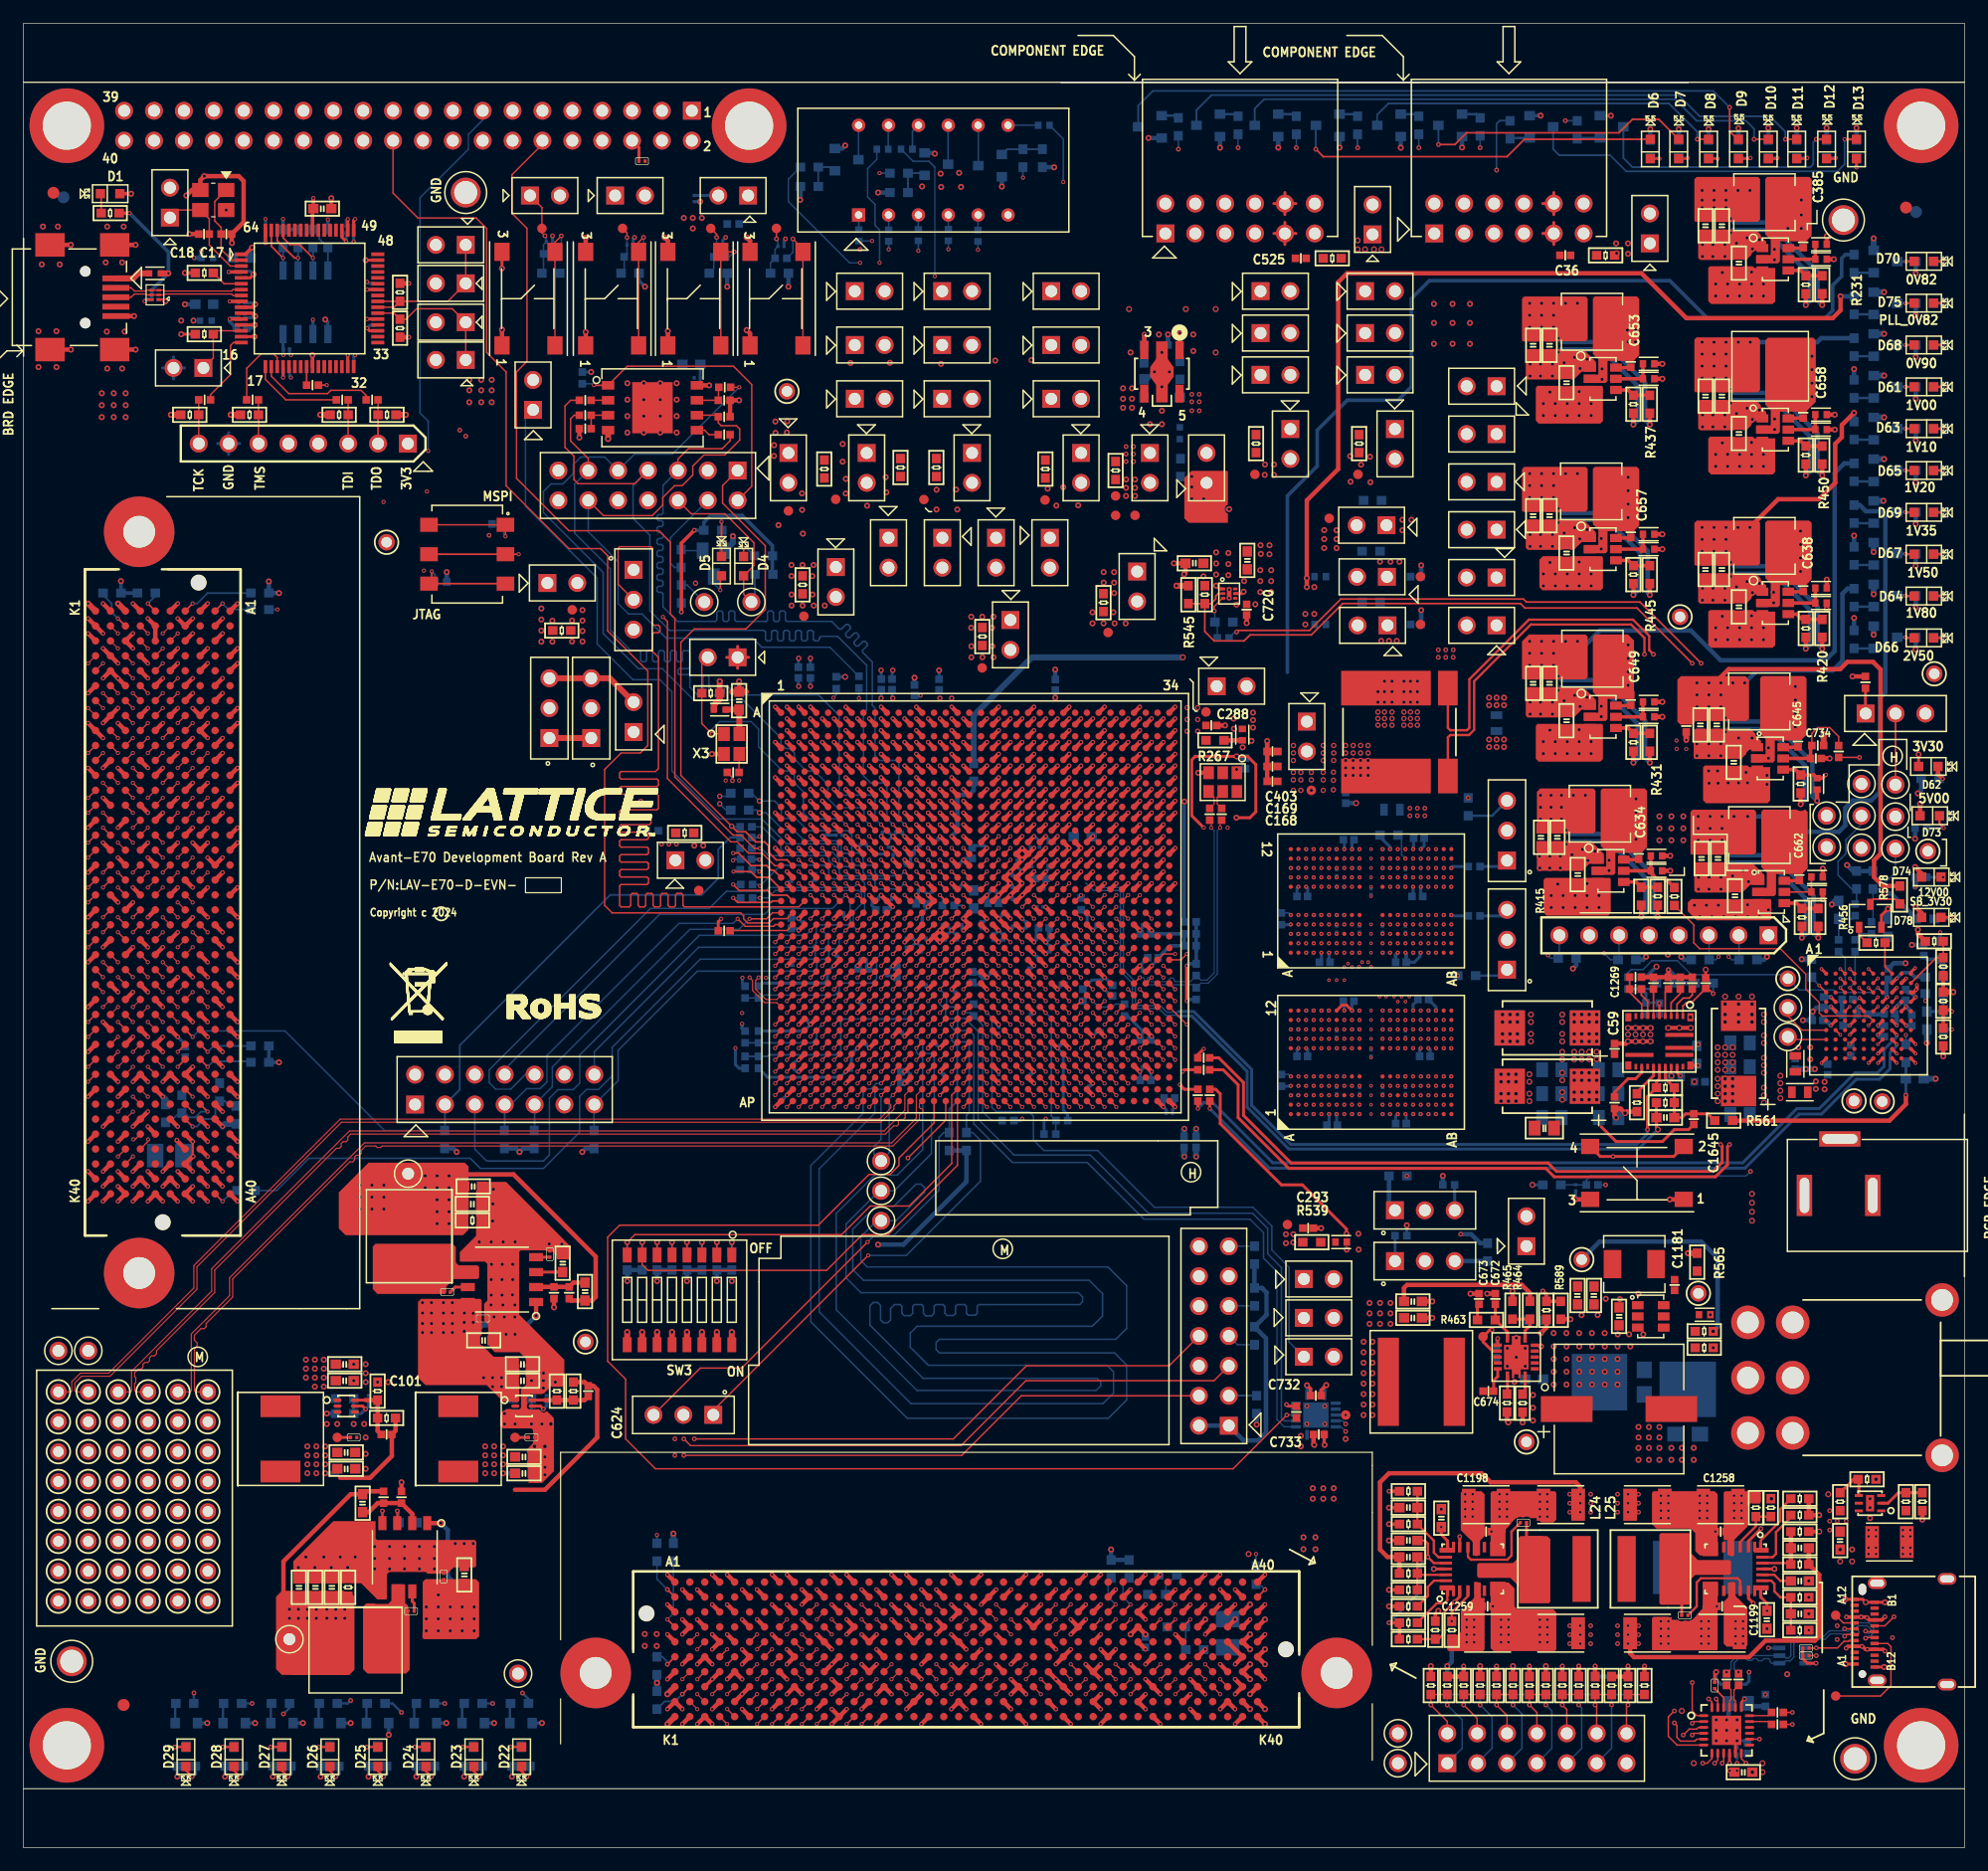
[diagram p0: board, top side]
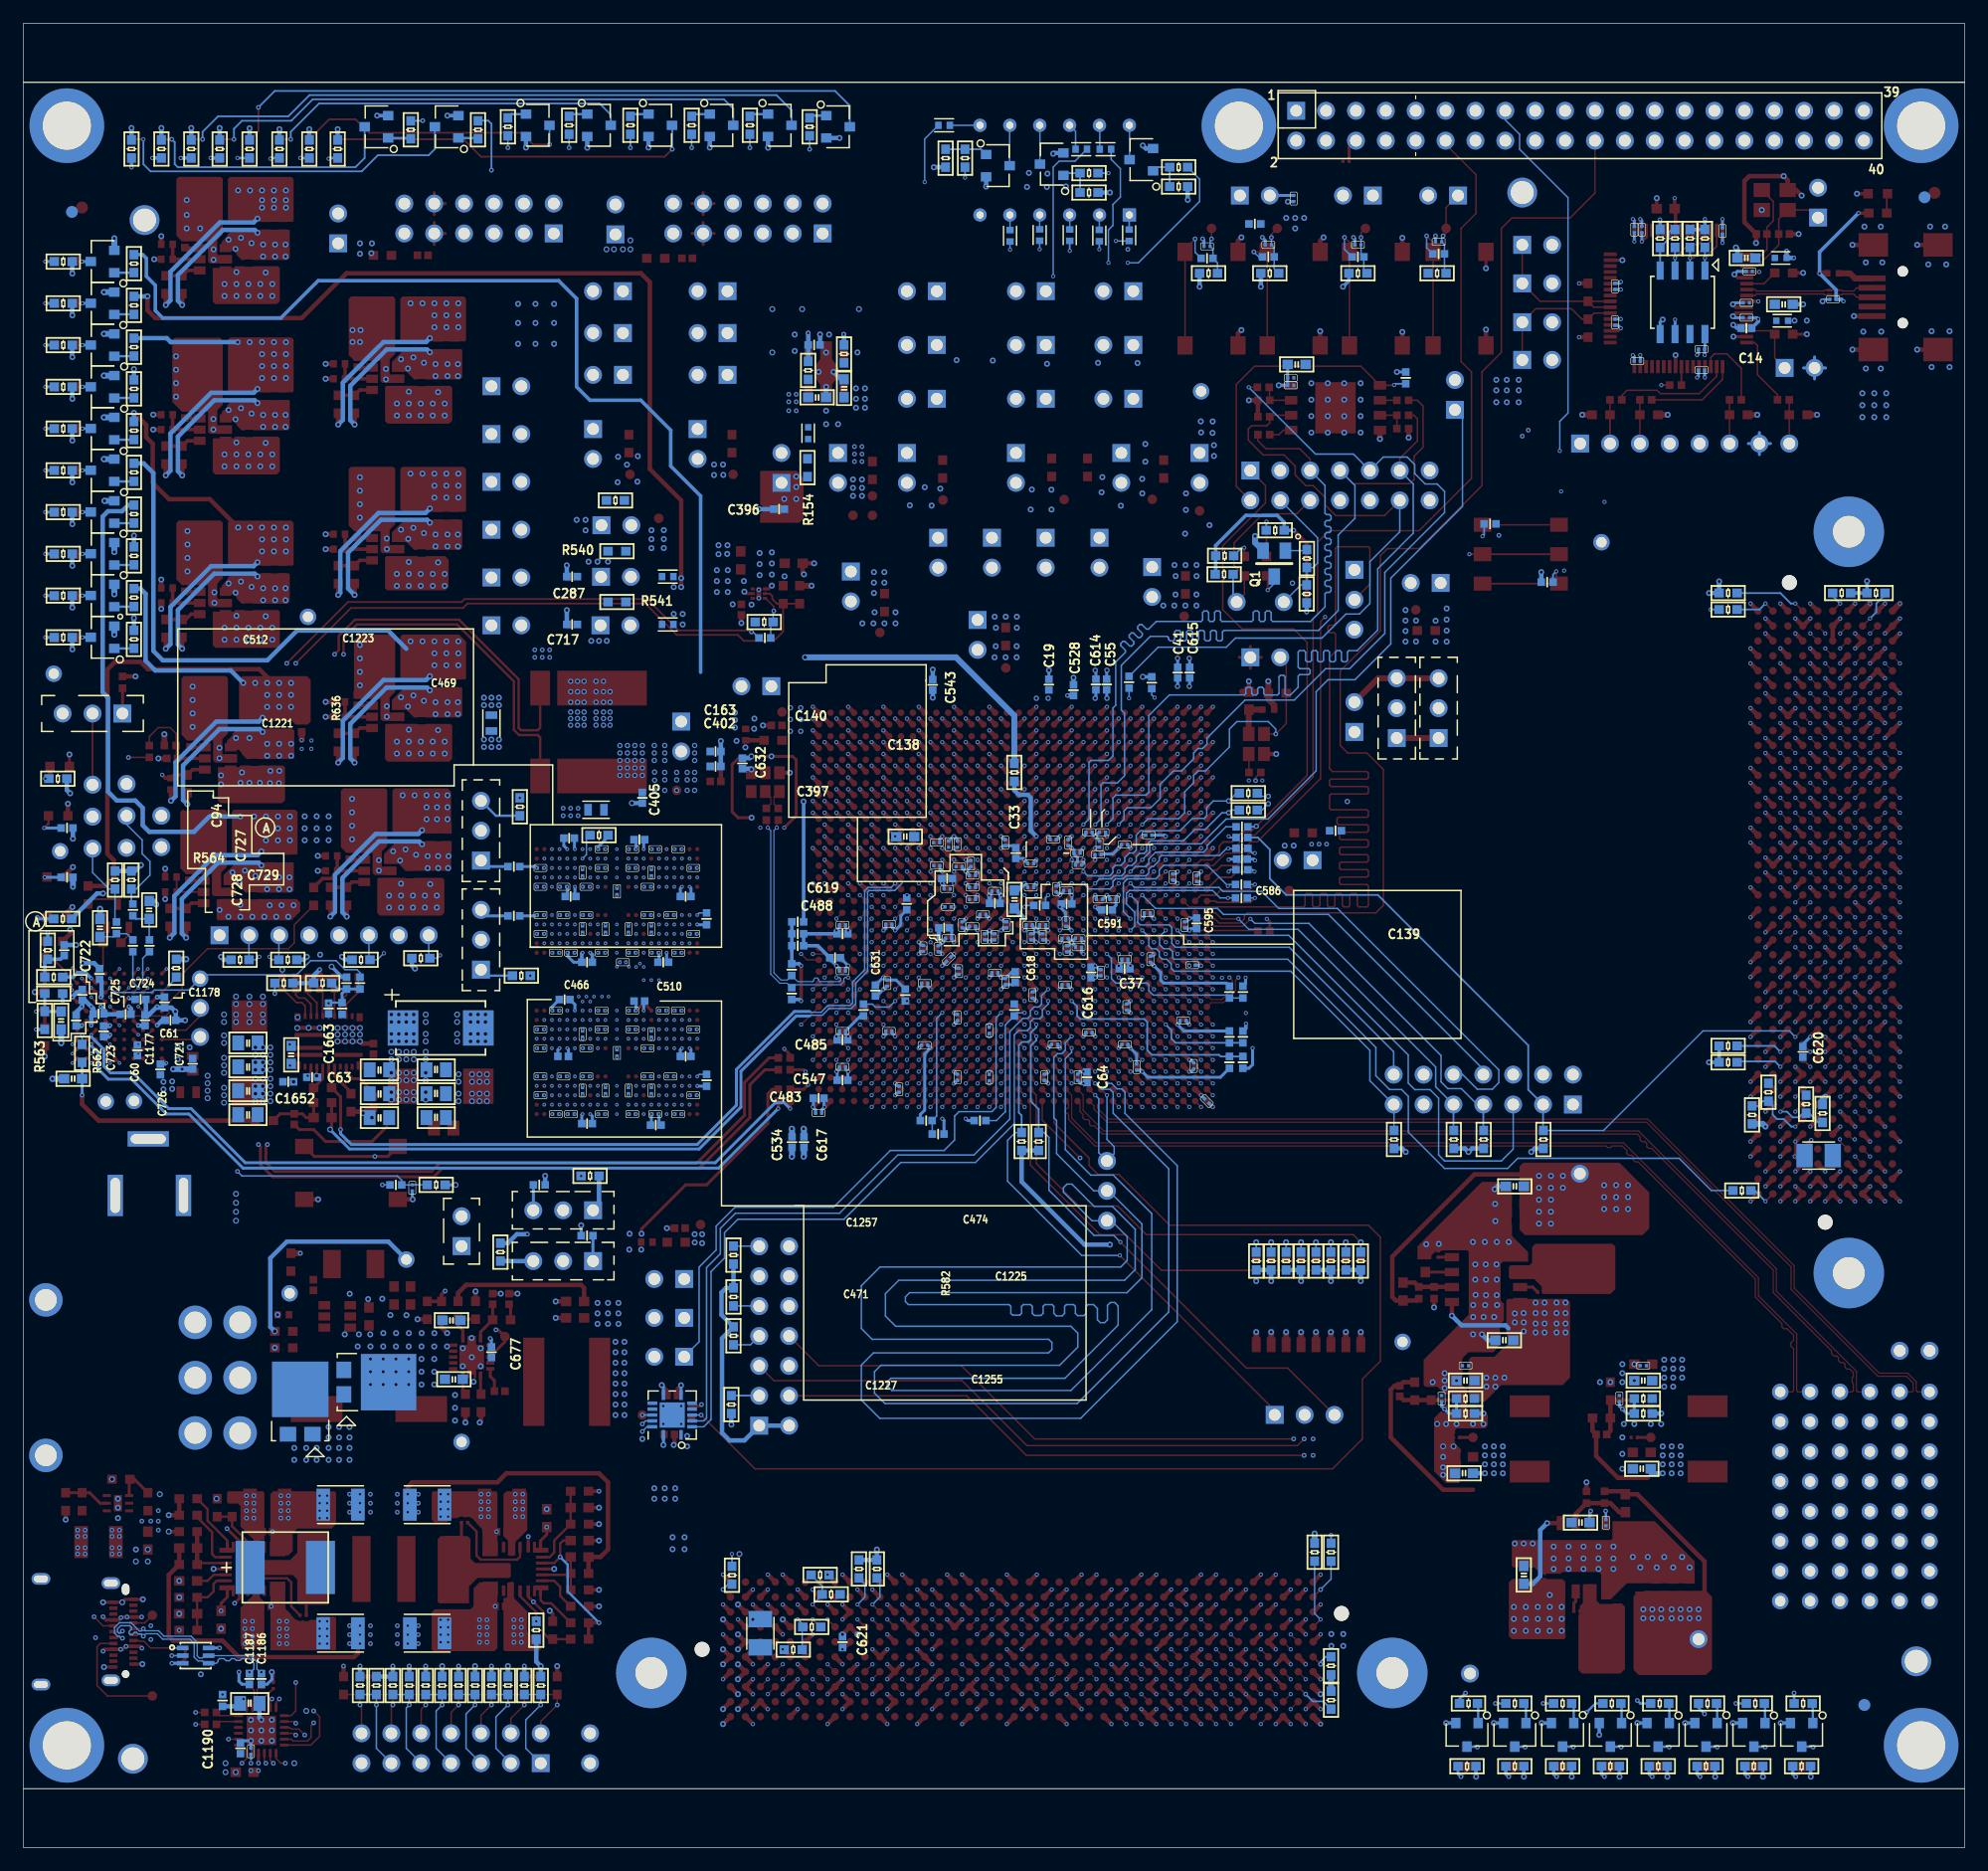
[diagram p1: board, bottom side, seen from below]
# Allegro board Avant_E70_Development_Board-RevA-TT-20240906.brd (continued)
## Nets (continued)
FMC2_TMS: J53.13 J54.D33(TMS) R316.1 U3.W14(WRIO13_5A)
FMC2_TRST_L: J53.6 J54.D34(TRST_L)
FMC2_VREFA: J54.H1(VREF_A_M2C) JP40.2 JP42.2
GPIO_AP14: U3.AP14(HPIO6_9B/DP1_DQ52) U46.4(A3)
ICS: C1214.1 C1215.1 U110.17(ICS_1) U110.18(ICS_2) U111.17(ICS_1) U111.18(ICS_2)
IMON1N_082V: R658.2(V2) U45.H10(IMON1N)
IMON1P_082V: R658.1(V1) U45.J10(IMON1P)
INITN: D4.K(CATHODE) INIT.1(TP) J3.6 R22.2 U3.T5(INITN)
K_DIG1: D60.12(K_DIG1) Q4.C
K_DIG2: D60.9(K_DIG2) Q2.C
K_DIG3: D60.8(K_DIG3) Q3.C
LED_0: R687.2 U3.L8(WRIO1_4B/MDQ5)
LED_1: R688.2 U3.P8(WRIO1_5B/MCLKN)
LED_2: R689.2 U3.M8(WRIO1_6A/MDQ6)
LED_3: R690.2 U3.M9(WRIO1_6B/MDQ7)
LED_4: R691.2 U3.P10(WRIO1_7A)
LED_5: R692.2 U3.N10(WRIO1_7B)
LED_6: R683.2 U3.AL10(HPIO6_25A/PCLKRT6_3/DP1_DM8)
LED_7: R684.2 U3.AL11(HPIO6_25B/PCLKRC6_3)
LED_8: R520.2 U3.AN15(HPIO6_5B/DP1_DQSN6)
LED_9: R522.2 U3.AH17(HPIO6_6A/DP1_DQ41)
LED_10: R525.2 U3.AG17(HPIO6_6B/DP1_DQ40)
LED_11: R527.2 U3.AM14(HPIO6_7A/DP1_DQ49)
LED_12: R530.2 U3.AL14(HPIO6_7B/DP1_DQ48)
LED_13: R531.2 U3.AK17(HPIO6_8A/DP1_DQ45)
LED_14: R534.2 U3.AJ17(HPIO6_8B/DP1_DQ44)
LED_15: R535.2 U3.AN14(HPIO6_9A/DP1_DQ53)
LPDDR4_A0_A: U3.AC26(HPIO10_2B/DP2_MA0) U5.H2(CA0_A) U5.R2(CA0_B) U119.H2(CA0_A) U119.R2(CA0_B)
LPDDR4_A1_A: U3.AB27(HPIO10_4A/DP2_MA1) U5.J2(CA1_A) U5.P2(CA1_B) U119.J2(CA1_A) U119.P2(CA1_B)
LPDDR4_A2_A: U3.AB28(HPIO10_4B/DP2_MA2) U5.H9(CA2_A) U5.R9(CA2_B) U119.H9(CA2_A) U119.R9(CA2_B)
LPDDR4_A3_A: U3.AC29(HPIO10_6A/DP2_MA3) U5.H10(CA3_A) U5.R10(CA3_B) U119.H10(CA3_A) U119.R10(CA3_B)
LPDDR4_A4_A: U3.AB29(HPIO10_6B/DP2_MA4) U5.H11(CA4_A) U5.R11(CA4_B) U119.H11(CA4_A) U119.R11(CA4_B)
LPDDR4_A5_A: U3.AD27(HPIO10_8A/DP2_MA5) U5.J11(CA5_A) U5.P11(CA5_B) U119.J11(CA5_A) U119.P11(CA5_B)
LPDDR4_CKE_A: U3.AB26(HPIO10_2A/DP2_CKE0) U5.J4(CKE0_A) U5.P4(CKE0_B) U119.J4(CKE0_A) U119.P4(CKE0_B)
LPDDR4_CLK_A_N: C1665.1 R582.1 R636.1 U3.AC25(HPIO10_0B/DP2_MCLKC0) U5.J9(CK_C_A) U5.P9(CK_C_B) U119.J9(CK_C_A) U119.P9(CK_C_B)
LPDDR4_CLK_A_P: C1665.2 R582.2 R636.2 U3.AB25(HPIO10_0A/DP2_MCLKT0) U5.J8(CK_T_A) U5.P8(CK_T_B) U119.J8(CK_T_A) U119.P8(CK_T_B)
LPDDR4_CS_A: U3.AA31(HPIO10_7A/DP2_CS_N0) U5.H4(CS0_A) U5.R4(CS0_B) U119.H4(CS0_A) U119.R4(CS0_B)
LPDDR4_DQ0_A: U3.AD22(HPIO10_20B/DP2_DQ00) U5.B2(DQ0_A)
LPDDR4_DQ0_B: U3.U29(HPIO11_3A/DP2_DQ16) U5.AA2(DQ0_B)
LPDDR4_DQ0_C: U3.V28(HPIO11_2A/DP2_DQ32) U119.B2(DQ0_A)
LPDDR4_DQ0_D: U3.AK32(HPIO9_7B/DP2_DQ48) U119.AA2(DQ0_B)
LPDDR4_DQ1_A: U3.AD21(HPIO10_20A/DP2_DQ01) U5.C2(DQ1_A)
LPDDR4_DQ1_B: U3.V29(HPIO11_3B/DP2_DQ17) U5.Y2(DQ1_B)
LPDDR4_DQ1_C: U3.U28(HPIO11_2B/DP2_DQ33) U119.C2(DQ1_A)
LPDDR4_DQ1_D: U3.AK31(HPIO9_7A/DP2_DQ49) U119.Y2(DQ1_B)
LPDDR4_DQ2_A: U3.AE25(HPIO10_14B/DP2_DQ02) U5.E2(DQ2_A)
LPDDR4_DQ2_B: U3.U30(HPIO11_9A/DP2_DQ18) U5.V2(DQ2_B)
LPDDR4_DQ2_C: U3.W26(HPIO11_8A/DP2_DQ34) U119.E2(DQ2_A)
LPDDR4_DQ2_D: U3.AJ32(HPIO9_1B/DP2_DQ50) U119.V2(DQ2_B)
LPDDR4_DQ3_A: U3.AE24(HPIO10_14A/DP2_DQ03) U5.F2(DQ3_A)
LPDDR4_DQ3_B: U3.U31(HPIO11_9B/DP2_DQ19) U5.U2(DQ3_B)
LPDDR4_DQ3_C: U3.V26(HPIO11_8B/DP2_DQ35) U119.F2(DQ3_A)
LPDDR4_DQ3_D: U3.AJ31(HPIO9_1A/DP2_DQ51) U119.U2(DQ3_B)
LPDDR4_DQ4_A: U3.AA21(HPIO10_22B/DP2_DQ04) U5.F4(DQ4_A)
LPDDR4_DQ4_B: U3.Y28(HPIO11_1A/DP2_DQ20) U5.U4(DQ4_B)
LPDDR4_DQ4_C: U3.AA27(HPIO11_0A/DP2_DQ36) U119.F4(DQ4_A)
LPDDR4_DQ4_D: U3.AK34(HPIO9_9B/DP2_DQ52) U119.U4(DQ4_B)
LPDDR4_DQ5_A: U3.Y21(HPIO10_22A/DP2_DQ05) U5.E4(DQ5_A)
LPDDR4_DQ5_B: U3.AA28(HPIO11_1B/DP2_DQ21) U5.V4(DQ5_B)
LPDDR4_DQ5_C: U3.Y27(HPIO11_0B/DP2_DQ37) U119.E4(DQ5_A)
LPDDR4_DQ5_D: U3.AK33(HPIO9_9A/DP2_DQ53) U119.V4(DQ5_B)
LPDDR4_DQ6_A: U3.AB24(HPIO10_16B/DP2_DQ06) U5.C4(DQ6_A)
LPDDR4_DQ6_B: U3.V30(HPIO11_7A/DP2_DQ22) U5.Y4(DQ6_B)
LPDDR4_DQ6_C: U3.AA26(HPIO11_6A/DP2_DQ38) U119.C4(DQ6_A)
LPDDR4_DQ6_D: U3.AJ33(HPIO9_3B/DP2_DQ54) U119.Y4(DQ6_B)
LPDDR4_DQ7_A: U3.AC24(HPIO10_16A/DP2_DQ07) U5.B4(DQ7_A)
LPDDR4_DQ7_B: U3.W30(HPIO11_7B/DP2_DQ23) U5.AA4(DQ7_B)
LPDDR4_DQ7_C: U3.Y26(HPIO11_6B/DP2_DQ39) U119.B4(DQ7_A)
LPDDR4_DQ7_D: U3.AJ34(HPIO9_3A/DP2_DQ55) U119.AA4(DQ7_B)
LPDDR4_DQ8_A: U3.AD34(HPIO10_21B/DP2_DQ08) U5.B11(DQ8_A)
LPDDR4_DQ8_B: U3.AA24(HPIO11_16A/DP2_DQ24) U5.AA11(DQ8_B)
LPDDR4_DQ8_C: U3.AF32(HPIO9_6B/DP2_DQ40) U119.B11(DQ8_A)
LPDDR4_DQ8_D: U3.AJ29(HPIO9_20B/DP2_DQ56) U119.AA11(DQ8_B)
LPDDR4_DQ9_A: U3.AD33(HPIO10_21A/DP2_DQ09) U5.C11(DQ9_A)
LPDDR4_DQ9_B: U3.Y24(HPIO11_16B/DP2_DQ25) U5.Y11(DQ9_B)
LPDDR4_DQ9_C: U3.AG32(HPIO9_6A/DP2_DQ41) U119.C11(DQ9_A)
LPDDR4_DQ9_D: U3.AJ28(HPIO9_20A/DP2_DQ57) U119.Y11(DQ9_B)
LPDDR4_DQ10_A: U3.AE32(HPIO10_15B/DP2_DQ10) U5.E11(DQ10_A)
LPDDR4_DQ10_B: U3.U23(HPIO11_22A/DP2_DQ26) U5.V11(DQ10_B)
LPDDR4_DQ10_C: U3.AF29(HPIO9_0B/DP2_DQ42) U119.E11(DQ10_A)
LPDDR4_DQ10_D: U3.AG28(HPIO9_14B/DP2_DQ58) U119.V11(DQ10_B)
LPDDR4_DQ11_A: U3.AE31(HPIO10_15A/DP2_DQ11) U5.F11(DQ11_A)
LPDDR4_DQ11_B: U3.U22(HPIO11_22B/DP2_DQ27) U5.U11(DQ11_B)
LPDDR4_DQ11_C: U3.AF28(HPIO9_0A/DP2_DQ43) U119.F11(DQ11_A)
LPDDR4_DQ11_D: U3.AG27(HPIO9_14A/DP2_DQ59) U119.U11(DQ11_B)
LPDDR4_DQ12_A: U3.AE33(HPIO10_23B/DP2_DQ12) U5.F9(DQ12_A)
LPDDR4_DQ12_B: U3.U25(HPIO11_14A/DP2_DQ28) U5.U9(DQ12_B)
LPDDR4_DQ12_C: U3.AG34(HPIO9_8B/DP2_DQ44) U119.F9(DQ12_A)
LPDDR4_DQ12_D: U3.AG26(HPIO9_22B/DP2_DQ60) U119.U9(DQ12_B)
LPDDR4_DQ13_A: U3.AE34(HPIO10_23A/DP2_DQ13) U5.E9(DQ13_A)
LPDDR4_DQ13_B: U3.T25(HPIO11_14B/DP2_DQ29) U5.V9(DQ13_B)
LPDDR4_DQ13_C: U3.AH34(HPIO9_8A/DP2_DQ45) U119.E9(DQ13_A)
LPDDR4_DQ13_D: U3.AH26(HPIO9_22A/DP2_DQ61) U119.V9(DQ13_B)
LPDDR4_DQ14_A: U3.AB34(HPIO10_17B/DP2_DQ14) U5.C9(DQ14_A)
LPDDR4_DQ14_B: U3.U24(HPIO11_20A/DP2_DQ30) U5.Y9(DQ14_B)
LPDDR4_DQ14_C: U3.AG30(HPIO9_2B/DP2_DQ46) U119.C9(DQ14_A)
LPDDR4_DQ14_D: U3.AG29(HPIO9_16B/DP2_DQ62) U119.Y9(DQ14_B)
LPDDR4_DQ15_A: U3.AB33(HPIO10_17A/DP2_DQ15) U5.B9(DQ15_A)
LPDDR4_DQ15_B: U3.T24(HPIO11_20B/DP2_DQ31) U5.AA9(DQ15_B)
LPDDR4_DQ15_C: U3.AF30(HPIO9_2A/DP2_DQ47) U119.B9(DQ15_A)
LPDDR4_DQ15_D: U3.AH29(HPIO9_16A/DP2_DQ63) U119.AA9(DQ15_B)
LPDDR4_LDM_A: U3.AC21(HPIO10_24A/PCLKRT10_2/DP2_DM0) U5.C3(DMI0_A)
LPDDR4_LDM_B: U3.V32(HPIO11_11A/PCLKT11_1/PCLKRT11_1) U5.Y3(DMI0_B)
LPDDR4_LDM_C: U3.V25(HPIO11_10A/PCLKT11_0/PCLKRT11_0) U119.C3(DMI0_A)
LPDDR4_LDM_D: U3.AM30(HPIO9_11A/PCLKT9_1/PCLKRT9_1/DP) U119.Y3(DMI0_B)
LPDDR4_LDQS_A_N: U3.AD23(HPIO10_18B/DP2_DQSN0) U5.E3(DQS0_C_A)
LPDDR4_LDQS_A_P: U3.AC23(HPIO10_18A/DP2_DQS0) U5.D3(DQS0_T_A)
LPDDR4_LDQS_B_N: U3.W29(HPIO11_5B/DP2_DQSN2) U5.V3(DQS0_C_B)
LPDDR4_LDQS_B_P: U3.Y29(HPIO11_5A/DP2_DQS2) U5.W3(DQS0_T_B)
LPDDR4_LDQS_C_N: U3.V27(HPIO11_4B/DP2_DQSN4) U119.E3(DQS0_C_A)
LPDDR4_LDQS_C_P: U3.U27(HPIO11_4A/DP2_DQS4) U119.D3(DQS0_T_A)
LPDDR4_LDQS_D_N: U3.AK30(HPIO9_5B/DP2_DQSN6) U119.V3(DQS0_C_B)
LPDDR4_LDQS_D_P: U3.AK29(HPIO9_5A/DP2_DQS6) U119.W3(DQS0_T_B)
LPDDR4_RESET: R596.1 U3.AF34(HPIO10_25B/PCLKRC10_3/DP2_RST_N) U5.T11(RESET_N) U119.T11(RESET_N)
LPDDR4_UDM_A: U3.AF33(HPIO10_25A/PCLKRT10_3/DP2_DM1) U5.C10(DMI1_A)
LPDDR4_UDM_B: U3.V22(HPIO11_24A/PCLKRT11_2/DP2_DM3) U5.Y10(DMI1_B)
LPDDR4_UDM_C: U3.AG33(HPIO9_10A/PCLKT9_0/PCLKRT9_0/DP) U119.C10(DMI1_A)
LPDDR4_UDM_D: U3.AJ27(HPIO9_24A/PCLKRT9_2/DP2_DM7) U119.Y10(DMI1_B)
LPDDR4_UDQS_A_N: U3.AC33(HPIO10_19B/DP2_DQSN1) U5.E10(DQS1_C_A)
LPDDR4_UDQS_A_P: U3.AC34(HPIO10_19A/DP2_DQS1) U5.D10(DQS1_T_A)
LPDDR4_UDQS_B_N: U3.W24(HPIO11_18B/DP2_DQSN3) U5.V10(DQS1_C_B)
LPDDR4_UDQS_B_P: U3.W23(HPIO11_18A/DP2_DQS3) U5.W10(DQS1_T_B)
LPDDR4_UDQS_C_N: U3.AG31(HPIO9_4B/DP2_DQSN5) U119.E10(DQS1_C_A)
LPDDR4_UDQS_C_P: U3.AF31(HPIO9_4A/DP2_DQS5) U119.D10(DQS1_T_A)
LPDDR4_UDQS_D_N: U3.AJ30(HPIO9_18B/DP2_DQSN7) U119.V10(DQS1_C_B)
LPDDR4_UDQS_D_P: U3.AH30(HPIO9_18A/DP2_DQS7) U119.W10(DQS1_T_B)
MPM3695_SCL: R707.2 U120.3(SCL)
MPM3695_SDA: R706.2 U120.4(SDA)
MPM3695_SW1: C1646.1 U120.27(SW#27) U120.28(SW#28)
MPM3695_TAKE: R694.1 R695.2 U120.9(TAKE)
ODT_CA_A: JP83.2 U5.G2(ODT_CA_A)
ODT_CA_B: JP84.2 U5.T2(ODT_CA_B)
ODT_CA_C: JP85.2 U119.G2(ODT_CA_A)
ODT_CA_D: JP86.2 U119.T2(ODT_CA_B)
PLL0V82_EN: PLL0V82_EN.1(TP) R715.2 U45.D6(GPIO3)
PLL0V82_MON: R584.2 U45.H8(VMON2)
PLL0V82_MON_GS: R583.2 U45.G8(VMON2GS)
PLL0V82_TRIM: R564.2 U45.C8(TRIM2)
PMOD2_1: J6.1 U3.P18(WRIO12_7B/PLLTFB12_IN)
PMOD2_2: J6.2 U3.N19(WRIO12_1A)
PMOD2_3: J6.3 U3.N20(WRIO12_5B)
PMOD2_4: J6.4 U3.P20(WRIO12_5A)
PMOD2_5: J6.7 U3.R17(WRIO12_6B)
PMOD2_6: J6.8 U3.M19(WRIO12_3A)
PMOD2_7: J6.9 U3.M20(WRIO12_3B/PCLKT12_0/PCLKRT12_0)
PMOD2_8: J6.10 U3.P19(WRIO12_7A/PLLT12_IN)
PMOD3_1: J7.1 U3.P14(WRIO12_4B)
PMOD3_2: J7.2 U3.N15(WRIO12_0A)
PMOD3_3: J7.3 U3.N16(WRIO12_2B)
PMOD3_4: J7.4 U3.R16(WRIO12_6A)
PMOD3_5: J7.7 U3.P13(WRIO12_4A)
PMOD3_6: J7.8 U3.N14(WRIO12_0B)
PMOD3_7: J7.9 U3.P15(WRIO12_2A)
PMOD3_8: J7.10 U3.N17(WRIO12_1B/PCLK12_1/PCLKRT12_1)
POWER_DOWN: C34.1 R42.2 R80.1 U45.H7(GPIO10)
PROGRAMN: C22.1 J3.1 JP17.1 PROGRAMN.1(TP) R10.2 R27.2 R29.1 R408.1 U3.P2(PROGRAMN)
PTM_DONE: P_DONE.1 U45.C6(PT17D || DONE)
PTM_INITN: P_INITN.1 U45.C5(PT17C || INITN)
PTM_JTAGENB: J8.2 P_JTAGENB.1 U45.B6(PT15C || JTAGENB)
PTM_PROGRAMN: P_PROGN.1 U45.A6(PT15D || PROGRAMN)
PTM_SCL_18: U3.AE15(HPIO6_24A/PCLKRT6_2/DP1_DM7) U46.2(A1)
PTM_SCL_33: PTM_SCL.1 R127.2 R550.1 U46.13(B1)
PTM_SDA_18: U3.AD15(HPIO6_24B/PCLKRC6_2) U46.3(A2)
PTM_SDA_33: PTM_SDA.1 R126.2 R549.1 U46.12(B2)
PTM_TCK: J39.8 R77.1 U45.A4(DIO23 || PT11C / TCK)
PTM_TDI: J39.3 R78.2 U45.B3(DIO25 || PT10D / TDI)
PTM_TDO: J39.2 R76.2 U45.A3(DIO22 || PT10C / TDO)
PTM_TMS: J39.6 R79.2 U45.B4(DIO24 || PT11D / TMS)
PUSHBUTTON1: C21.1 PB1.1(TP) R21.2 R23.1 U3.AC17(HPIO6_4A/DP1_DQS5)
PUSHBUTTON2: C26.1 PB2.1(TP) R47.2 R50.1 U3.AC16(HPIO6_4B/DP1_DQSN5)
PUSHBUTTON3: C27.1 PB3.1(TP) R48.2 R51.1 U3.AP15(HPIO6_5A/DP1_DQS6)
RASP_5V: C599.1 JP13.2 JP26.2 JP26.4
RASP_ID_SC: JP26.28 R103.1 U3.R12(WRIO14_7A)
RASP_ID_SD: JP26.27 R104.1 U3.T11(WRIO14_7B)
RASP_IO02: JP26.3 U3.V15(WRIO13_6B)
RASP_IO03: JP26.5 U3.T13(WRIO13_7A)
RASP_IO04: JP26.7 U3.P6(WRIO2_2A/SDQ2)
RASP_IO05: JP26.29 R108.2 U3.V8(WRIO14_6A)
RASP_IO06: JP26.31 R105.2 U3.W8(WRIO14_6B)
RASP_IO07: JP26.26 JP65.1
RASP_IO08: JP26.24 U3.P5(WRIO2_2B/SDQ3)
RASP_IO09: JP26.21 U3.R5(WRIO2_3B/SDS)
RASP_IO10: JP26.19 U3.R6(WRIO2_3A/SCSN)
RASP_IO11: JP26.23 R106.2 U3.U12(WRIO14_5A/PCLKRT14_0)
RASP_IO12: JP26.32 U3.U5(WRIO2_1B/SSDO)
RASP_IO13: JP26.33 U3.R9(WRIO14_8B)
RASP_IO14: JP26.8 U3.V14(WRIO13_5B)
RASP_IO15: JP26.10 U3.R13(WRIO13_7B)
RASP_IO16: JP26.36 U3.N6(WRIO2_0A/SDQ0)
RASP_IO17: JP26.11 U3.V16(WRIO13_6A)
RASP_IO18: JP26.12 R107.2 U3.T12(WRIO14_5B)
RASP_IO19: JP26.35 U3.R11(WRIO14_9A)
RASP_IO20: JP26.38 U3.T6(WRIO0_7B/PLLTFB0_IN)
RASP_IO21: JP26.40 U3.U6(WRIO0_7A/PLLT0_IN)
RASP_IO22: JP26.15 U3.W6(WRIO0_5B)
RASP_IO23: JP26.16 U3.P4(WRIO2_4B/SDQ5)
RASP_IO24: JP26.18 U3.N5(WRIO2_0B/SDQ1)
RASP_IO25: JP26.22 U3.V2(WRIO0_6A)
RASP_IO26: JP26.37 U3.T9(WRIO14_8A)
RASP_IO27: JP26.13 U3.P3(WRIO2_4A/SDQ4)
RXD_UART: JP2.2 U3.R3(WRIO2_6A/SDQ6)
SB_3V30: C1183.1 C1184.1 J11.1 J39.1 L23.2 R42.1 R76.1 R78.1 R79.1 R81.1 R126.1 R127.1 R566.1 R567.2 R585.2 SB_3V30.1(TP)
SCL: JP4.2 R103.2
SDA: JP5.2 R104.2
SEG_A: R332.2 U3.V10(WRIO14_0A)
SEG_B: R333.2 U3.T10(WRIO14_0B)
SEG_C: R334.2 U3.V12(WRIO14_1A)
SEG_D: R335.2 U3.V13(WRIO14_1B)
SEG_DP: R331.2 U3.W11(WRIO14_3B)
SEG_E: R336.2 U3.W10(WRIO14_2A)
SEG_F: R337.2 U3.V11(WRIO14_2B)
SEG_G: R338.2 U3.W12(WRIO14_3A)
SHORT_STUB_TRACE: ST.1 U3.AN10(HPIO6_21B/DP1_DQ64) U3.AN11(HPIO6_21A/DP1_DQ65)
SPI_MCLK: J3.12 R20.1 R40.2 U4.6(SCLK)
SYNC_IN: R615.2 R616.2 U110.3(SYNCIN) U111.16(SYNCO)
SYNC_OUT: U110.16(SYNCO) U111.3(SYNCIN)
TCK: J1.8 R5.1 R6.2 R106.1 U3.T1(TCK)
TDI: J1.3 R3.2 R7.2 R105.1 U3.U1(TDI)
TDO: J1.2 R4.2 R8.2 R108.1 U3.U2(TDO)
TMS: J1.6 R2.2 R9.2 R107.1 U3.R1(TMS)
TXD_UART: JP1.2 U3.T3(WRIO2_6B/SDQ7)
USB3_CC1: C1188.1 J25.A5(CC1) R601.2 U109.1
USB3_CC2: C1189.1 J25.B5(CC2) R602.2 U109.2
USB3_LDO_5V: C1190.1 C1191.1 C1261.1 C1268.1 R603.1 R604.1 R605.1 R606.1 R607.1 R608.1 R623.1 R640.2 R649.2 R650.2 R659.1 R660.1 R661.1 R662.1 R675.1 R676.1 U108.10(VIN) U118.6(VOUT)
USB3_PA1: J83.1 R603.2 R663.1 U108.1(PA1)
USB3_PA2: J83.3 R604.2 R664.1 U108.2(PA2)
USB3_PA3: J83.5 R659.2 R665.1 U108.3(PA3)
USB3_PA4: J83.7 R660.2 R666.1 U108.4(PA4)
USB3_PA5: J83.9 R661.2 R667.1 U108.5(PA5)
USB3_PA6: J83.11 R662.2 R668.1 U108.6(PA6)
USB3_PB0: J83.2 R607.2 R671.2 U108.7(PB0)
USB3_PB1: J83.4 R606.2 R672.2 U108.8(PB1)
USB3_PB2: J83.6 R623.2 R651.1 U108.12(PB2)
USB3_PB3: J83.8 R670.2 R675.2 U108.14(PB3)
USB3_PB6: J83.10 R605.2 R673.2 U108.23(PB6)
USB3_PB7: J83.12 R608.2 R674.2 U108.24(PB7)
USB3_PC2: J83.14 R669.2 R676.2 U108.9(PC2)
USB3_RST: C1192.2 U108.22(NRST)
USB_12V: C1204.1 C1205.1 C1206.1 C1207.1 C1208.1 C1209.1 C1210.1 C1211.1 C1666.1 C1667.1 J84.3 J84.6 L24.2 L25.2 R619.2 R622.2
USB_DM: C1186.1 J25.A7(D-A) J25.B7(D-B) R599.1 U109.5
USB_DP: C1187.1 J25.A6(D+A) J25.B6(D+B) R600.1 U109.4
USB_VBUS: C1193.1 C1194.1 C1195.1 C1196.1 C1198.1 C1199.1 C1258.1 C1259.1 C1260.1 C1668.1 J25.A4(VBUS1) J25.A9(VBUS2) J25.B4(VBUS4) J25.B9(VBUS3) R609.1 R610.1 R638.1 R648.1 U110.5(VIN_1) U110.14(VIN_2) U111.5(VIN_1) U111.14(VIN_2) U118.1(VIN)
VFMC1_3V30: C49.1 C50.1 C51.1 C52.1 F1_3V3.1(TP) FB4.2 J48.C39(3P3V#C39) J48.D36(3P3V#D36) J48.D38(3P3V#D38) J48.D40(3P3V#D40) L1.2 R95.2 R96.1 VFMC1_3V30.1
VFMC1_3V30AUX: C620.2 F1_3V3AUX.1(TP) FB4.1 J48.D32(3P3VAUX) R249.2 R250.2
VFMC1_ADJ: C100.1 C101.1 C103.1 C104.1 C1217.1 F1_ADJ.1(TP) J48.E39(VADJ#E39) J48.F40(VADJ#F40) J48.G39(VADJ#G39) J48.H40(VADJ#H40) JP70.1 JP72.1 JP74.1 L13.2 R399.2 VFMC1_ADJ.1(TP)
VFMC2_3V30: C556.1 C557.1 C559.1 C565.1 F2_3V3.1(TP) FB24.2 J54.C39(3P3V#C39) J54.D36(3P3V#D36) J54.D38(3P3V#D38) J54.D40(3P3V#D40) L10.2 R305.1 R307.2 VFMC2_3V30.1
VFMC2_3V30AUX: C621.2 F2_3V3AUX.1(TP) FB24.1 J54.D32(3P3VAUX) R323.2 R324.2
VFMC2_ADJ: C622.1 C624.1 C628.1 C629.1 C630.1 F2_ADJ.1(TP) J54.E39(VADJ#E39) J54.F40(VADJ#F40) J54.G39(VADJ#G39) J54.H40(VADJ#H40) JP76.1 JP78.1 L14.2 R402.2 VFMC2_ADJ.1(TP)
VLDO_MPM_3V3: C63.1 R52.2 R693.1 R694.2 R705.1 R706.1 R707.1 R708.2 U120.23(VCC)
N00911: C6.1 C7.1 FB1.1 U1.9(VPLL)
N00925: C9.1 C10.1 FB3.1 U1.4(VPHY)
N01606: JP3.1 R11.1 U1.14(RESET#)
N01656: R15.2 U1.6(REF)
N02092: R12.2 U1.63(EECS) U2.1(CS)
N02098: R13.2 U1.62(EECLK) U2.2(CLK)
N02124: R19.1 U1.61(EEDATA) U2.3(DI)
N02138: R14.2 R19.2 U2.4(DO)
N02805: C17.2 U1.2(OSCI) X1.1
N02831: C18.2 JP6.1 U1.3(OSCO) X1.3
N03813: R9.1 U1.19(ADBUS3)
N03929: R7.1 U1.17(ADBUS1)
N03953: R8.1 U1.18(ADBUS2)
N16504386: FB2.2 J2.1(VCC)
N16632009: JP2.1 JP5.1 R16.1 U1.39(BDBUS1) U1.40(BDBUS2)
N16632070: JP1.1 JP4.1 R17.1 U1.38(BDBUS0)
N16986163: R39.2 R45.1 U4.3(WP#/SIO2)
N16986174: R41.2 R44.2 U4.7(RESET#/SIO3)
N16986210: R43.2 U4.2(SO/SIO1)
N17591276: R10.1 U1.24(ADBUS7)
N17596855: R6.1 U1.16(ADBUS0)
N18595602: D1.A(ANODE) R1.1
N19901221: C36.1 J6.6 J6.12 J23.2 R82.2
N20181793: C52.2 R96.2 R100.1 U6.2(FB)
N20181835: C48.1 U6.7(BOOT)
N20181965: C54.1 U6.4(SS)
N20181967: C53.1 U6.3(VREG)
N20182036: C48.2 L1.1 U6.6(SW)
N20325017: J48.B1(RES1) R215.1
N20325029: J48.B40(RES0) R216.1
N20421551: JP88.2 U3.AA11(HPIO3_12A/VREF3/DP0_VREF3)
N20899580: R294.1 U3.U26(EXT_RES11/DP2_EXT_RES11)
N20899618: R290.1 U3.AE27(EXT_RES10/DP2_EXT_RES10)
N20900730: R291.2 U5.A5(ZQ0)
N20922301: C525.1 J7.6 J7.12 J57.2 R298.2
N20943247: JP40.1 U3.AF18(HPIO7_12A/VREF7/DP1_VREF7)
N20953373: C564.2 L10.1 U32.6(SW)
N20953565: C559.2 R305.2 R306.1 U32.2(FB)
N20953569: C564.1 U32.7(BOOT)
N20953725: C563.1 U32.4(SS)
N20953727: C562.1 U32.3(VREG)
N20954035: J54.B1(RES1) R308.1
N20954045: J54.B40(RES0) R309.1
N20954331: J54.K1(VREF_B_M2C) TP_FMC2_VREFB.1(TP)
N20986575: D4.A(ANODE) R24.1
N20986579: D5.K(CATHODE) Q1.C(COLLECTOR)
N20986602: D5.A(ANODE) R25.1
N20986712: Q1.B(BASE) R28.1
N20987029: R29.2 SW2.2(B1) SW2.4(B2)
N21000300: R46.2 U4.5(SI/SIO0)
N21001542: R20.2 U3.P9(WRIO1_5A/MCLK)
N21002825: JP65.2 U3.U3(WRIO2_5A/PCLKRT2_0/SCLKP)
N21005513: D60.3(DP) R331.1
N21005532: D60.11(A) R332.1
N21005551: D60.7(B) R333.1
N21005570: D60.4(C) R334.1
N21005589: D60.2(D) R335.1
N21005608: D60.1(E) R336.1
N21005627: D60.10(F) R337.1
N21005646: D60.5(G) R338.1
N21008142: Q2.B R339.2 R340.1
N21008495: Q3.B R341.2 R342.1
N21008871: Q4.B R343.2 R344.1
N21037031: R55.2 U3.T7(WRIO0_3B/PCLKT0_0/PCLKRT0_0)
N21071175: R345.2 U3.U15(WRIO13_3B/PCLKRT13_0)
N21072310: R23.2 SW1.2(B1) SW1.4(B2)
N21077063: D9.K(CATHODE) Q32.C
N21077065: D11.K(CATHODE) Q34.C
N21077067: D10.K(CATHODE) Q33.C
N21077110: D6.K(CATHODE) Q29.C
N21077112: D7.K(CATHODE) Q30.C
N21077121: D8.K(CATHODE) Q31.C
N21077214: D10.A(ANODE) R60.1
N21077216: D7.A(ANODE) R57.1
N21077218: D6.A(ANODE) R56.1
N21077222: D11.A(ANODE) R61.1
N21077224: D8.A(ANODE) R58.1
N21077226: D9.A(ANODE) R59.1
N21110155: R50.2 SW4.2(B1) SW4.4(B2)
N21111210: R51.2 SW5.2(B1) SW5.4(B2)
N21123855: C600.1 JP12.2 JP26.1 JP26.17
N21167890: R408.2 U3.R8(WRIO1_1B/MSDO)
N21221554: R652.1 R712.1 U3.AA10(EXT_RES3/DP0_EXT_RES3)
N21236832: C624.2 R402.1 R406.2 U115.6(FB)
N21269868: R538.2 Y1.5(OUT#)
N21271826: D61.A R169.1
N21271847: Q7.B R229.1
N21271871: D61.K Q7.C
N21271879: C385.1 U17.6(BST)
N21271891: C385.2 L8.1 U17.2(SW)
N21271907: R231.2 R232.1 U17.4(FB)
N21272003: R233.2 R234.1 U17.5(EN)
N21279835: D63.A R417.1
N21279856: Q8.B R416.1
N21279868: D63.K Q8.C
N21279888: C638.1 U35.6(BST)
N21279900: C638.2 L15.1 U35.2(SW)
N21279916: R420.2 R421.1 U35.4(FB)
N21279996: R418.2 R419.1 U35.5(EN)
N21283467: C734.1 R572.2 R716.1 U36.5(EN)
N21283516: R288.1 R424.1 R425.2 U36.4(FB)
N21283565: D64.A R427.1
N21283586: Q9.B R426.1
N21283590: D64.K Q9.C
N21283614: C645.1 U36.6(BST)
N21283618: C645.2 L5.1 U36.2(SW)
N21285415: R428.2 R429.1 U37.5(EN)
N21285466: R430.1 R431.2 U37.4(FB)
N21285515: D65.A R433.1
N21285536: Q10.B R432.1
N21285540: D65.K Q10.C
N21285564: C649.1 U37.6(BST)
N21285568: C649.2 L16.1 U37.2(SW)
N21287544: R434.2 R435.1 U38.5(EN)
N21287595: R436.1 R437.2 U38.4(FB)
N21287644: D66.A R439.1
N21287665: Q11.B R438.1
N21287669: D66.K Q11.C
N21287693: C653.1 U38.6(BST)
N21287697: C653.2 L17.1 U38.2(SW)
N21298381: D68.A R447.1
N21298402: Q13.B R446.1
N21298414: D68.K Q13.C
N21298430: C658.1 U40.6(BST)
N21298442: C658.2 L19.1 U40.2(SW)
N21298458: R450.2 R451.1 U40.4(FB)
N21298538: R448.2 R449.1 U40.5(EN)
N21300072: D62.A R411.1
N21300092: C634.1 U34.6(BST)
N21300096: C634.2 L4.1 U34.2(SW)
N21300112: R414.2 R415.1 U34.4(FB)
N21300200: R412.2 R413.1 R682.2 U34.5(EN)
N21310610: D69.A R453.1
N21310631: Q14.B R452.1
N21310643: D69.K Q14.C
N21310659: C662.1 U41.6(BST)
N21310671: C662.2 L20.1 U41.2(SW)
N21310687: R456.2 R457.1 U41.4(FB)
N21310767: R454.2 R455.1 U41.5(EN)
N21316067: R440.1 R441.2 U39.5(EN)
N21316093: R442.1 R445.2 U39.4(FB)
N21316143: D67.A R444.1
N21316167: Q12.B R443.1
N21316171: D67.K Q12.C
N21316188: C657.1 U39.6(BST)
N21316200: C657.2 L18.1 U39.2(SW)
N21319599: R655.1 R709.1 U3.AF17(EXT_RES7/DP1_EXT_RES7)
N21332411: C674.2 L21.1 U43.11(LX1) U43.12(LX2)
N21332860: C113.1 C713.1 C714.1 C1182.1 D77.K R519.1 R565.1 R588.1 U43.4(PVIN1) U43.5(PVIN2) U43.6(VIN) U107.3(VIN)
N21333157: C672.1 R463.1 U43.8(COMP)
N21333175: C673.1 R463.2
N21333379: C674.1 U43.13(BOOT)
N21333574: R464.2 R465.1 U43.7(FB)
N21334320: R466.2 U43.1(RT/SYNC)
N21334323: C677.2 U43.9(SS/TR)
N21335874: R467.2 U43.14(PGOOD)
N21377300: R490.2 R491.1 R492.1 R493.2 R548.2
N21392431: D74.A R519.2
N21425635: D22.A R521.1
N21425658: D22.K(C) Q16.C
N21425660: Q16.B R520.1
N21425855: D23.A R523.1
N21425865: D23.K(C) Q17.C
N21425867: Q17.B R522.1
N21436938: D24.A R524.1
N21436944: D24.K(C) Q18.C
N21437139: Q18.B R525.1
N21437250: D25.A R526.1
N21437256: D25.K(C) Q19.C
N21437449: Q19.B R527.1
N21437528: D26.A R528.1
N21437532: D26.K(C) Q20.C
N21437655: D27.A R529.1
N21437659: D27.K(C) Q21.C
N21437864: Q20.B R530.1
N21437895: Q21.B R531.1
N21438194: D28.A R532.1
N21438198: D28.K(C) Q22.C
N21438325: D29.A R533.1
N21438329: D29.K(C) Q23.C
N21438561: Q22.B R534.1
N21438597: Q23.B R535.1
N21460625: R656.1 R710.1 U3.AF23(EXT_RES8/DP1_EXT_RES8)
N21460772: JP42.1 U3.AF24(HPIO8_12A/VREF8/DP1_VREF8)
N21461634: PS_EN.1(TP) R588.2 R589.1 U43.10(EN)
N21466678: R537.2 Y1.4(OUT)
N21480652: R544.2 R545.1 R563.1 U44.2(ADJ/NC)
N21481605: R556.2 R715.1 U44.3(EN)
N21482339: D75.A R546.1
N21482349: D75.K Q24.C
N21482360: Q24.B R547.1
N21645200: D73.A R510.2
N21892437: R180.1 SW7.3(NC_1) SW7.6(NC_2)
N21892555: R179.2 SW7.1(NO_1) SW7.4(NO_2)
N21945289: C60.1 C61.1 C721.1 C722.1 C723.1 C724.1 C725.1 C1177.1 C1178.1 L3.1 U45.D2(VCCIO3#D2) U45.D5(VCCIO0#D5) U45.D7(VCC#D7) U45.E5(VCCIO0#E5) U45.F2(VCCIO3#F2) U45.F4(VCCIO2#F4) U45.G7(VCC#G7) U45.H4(VCCIO2#H4)
N21945322: J11.2 L3.2 L6.2
N21945422: C726.1 C727.1 C728.1 C729.1 L6.1 U45.E8(VCCA#E8) U45.E9(VCCA#E9) U45.F8(VCCA#F8)
N21948317: C30.2 R549.2 R551.1
N21948373: C29.2 R550.2 R552.1
N21948381: R551.2 U45.C3(SDA)
N21948411: R552.2 U45.C4(SCL)
N21948657: R80.2 SW8.2(B1) SW8.4(B2)
N21970187: R245.1 U46.15(EPAD)
N21993618: R81.2 U45.C1(RESETB)
N22007255: C94.1 R287.1 R288.2
N22018757: C1180.1 R563.2 R564.1
N22019660: C1181.1 U107.6(BST)
N22019707: C1181.2 L23.1 U107.2(SW)
N22019773: R565.2 R568.1 U107.5(EN) U107_EN.1(TP)
N22019783: R566.2 R569.1 U107.4(FB)
N22019789: D78.A R567.1
N22103220: Q26.D R578.2
N22103236: Q26.G R579.2
N22103439: R579.1 U45.A8(HVOUT1)
N22357147: J8.1 R585.1
N22419042: R398.1 TP_R7.1(TP) U3.R7(VSSR#R7)
N22461237: R654.1 R711.1 U3.AE13(EXT_RES5/DP0_EXT_RES5)
N22461561: JP38.1 U3.AF13(HPIO5_12A/VREF5/DP0_VREF5)
N22463394: JP89.2 U3.AG6(HPIO4_12A/VREF4/DP0_VREF4)
N22463398: R653.1 R713.1 U3.AG5(EXT_RES4/DP0_EXT_RES4)
N22505657: J25.A8(SBU1) TP26.1(TP)
N22505665: J25.B8(SBU2) TP25.1(TP)
N22506509: R599.2 U108.21(DM)
N22506512: R600.2 U108.20(DP)
N22506572: C1185.1 R648.2 U108.19(VBUS)
N22506942: R601.1 U108.18(CC1)
N22506945: R602.1 U108.17(CC2)
N22513651: R610.2 R613.2 U111.4(EN)
N22518145: R612.2 U110.23(FREQ)
N22518148: R611.2 U111.23(FREQ)
N22519451: C1266.1 R615.1 R618.1 U110.20(VCC)
N22519923: C1267.1 U111.20(VCC)
N22520337: R618.2 U110.1(PG_1) U110.2(PG_2)
N22520353: R617.2 U111.1(PG_1) U111.2(PG_2)
N22520434: C1203.1 U110.15(BST)
N22520437: C1203.2 L24.1 U110.9(SW_1) U110.10(SW_2)
N22520459: C1202.2 L25.1 U111.9(SW_1) U111.10(SW_2)
N22520465: C1202.1 U111.15(BST)
N22523186: C1667.2 R621.1 R622.1 U111.22(FB)
N22523201: C1666.2 R619.1 R620.1 U110.22(FB)
N22525321: J50.1(+5V) J84.1 J84.4
N22530625: C1219.2 R624.1 R625.1 U114.5(EN)
N22531796: C101.2 R399.1 R401.2 U114.6(FB)
N22531852: L13.1 U114.2(SW)
N22581142: C1220.2 R628.1 R629.1 U115.5(EN)
N22599585: L14.1 U115.2(SW)
N22604437: R185.2 U116.3(CE)
N22604439: R189.1 R192.2 U116.1(VFB)
N22625096: R633.2 U119.A5(ZQ0)
N22668834: R638.2 R639.2 U118.2(EN)
N22670042: R640.1 R641.1 U118.4(FB)
N22671497: C1265.1 R642.1 R649.1 U111.19(VBIAS)
N22672695: C1264.1 R643.1 R650.1 U110.19(VBIAS)
N22703478: JP83.3 R292.1
N22703481: JP83.1 R598.2
N22703488: JP84.3 R597.2
N22703491: JP84.1 R293.1
N22703555: JP85.3 R646.1
N22703558: JP85.1 R645.2
N22703565: JP86.3 R644.2
N22703568: JP86.1 R647.1
N22778691: J54.K40(VIO_B_M2C-2) TP_M2C_B_2_2.1(TP)
N22778693: J54.J39(VIO_B_M2C-1) TP_M2C_B_2_1.1(TP)
N22778746: J48.K40(VIO_B_M2C-2) TP_M2C_B_1_2.1(TP)
N22778748: J48.J39(VIO_B_M2C-1) TP_M2C_B_1_1.1(TP)
N23028314: AP14.1(TP) U46.11(B3)
N23029118: C69.1 FB6.2 X3.4(VDD)
N23029151: R110.1 X3.3(OUT)
N23030072: D12.K(CATHODE) Q27.C
N23030074: D13.K(CATHODE) Q28.C
N23030106: D12.A(ANODE) R62.1
N23030124: D13.A(ANODE) R63.1
N23030387: Q27.B R683.1
N23030530: Q28.B R684.1
N23050396: R685.1 U3.AF26(EXT_RES9/DP2_EXT_RES9)
N23063052: R686.1 U3.W2(VSSR57)
N23067021: Q29.B R687.1
N23067044: Q30.B R688.1
N23067876: Q31.B R689.1
N23067899: Q32.B R690.1
N23068194: Q33.B R691.1
N23068217: Q34.B R692.1
N23070235: C1269.1 R52.1 U120.2(VDRV)
N23070376: C1646.2 U120.25(BST)
N23070416: R695.1 U120.8(PASS)
N23070431: R696.1 U120.19(IREF)
N23070448: R54.2 U120.17(ADDR)
N23076171: C1179.1 R561.2 R562.1
N23077522: D70.A R475.1
N23077532: D70.K Q15.C
N23077534: Q15.B R474.1
N23166257: R609.2 R614.2 U110.4(EN)

Pads without a net: D60 6; J1 4 5; J2 4; J3 3; J25 A2 A3 A10 A11 B2 B3 B10 B11; J39 4 5; J48 A2 A3 A6 A7 A10 A11 A14 A15 A18 A19 A22 A23 A26 A27 A30 A31 A34 A35 A38 A39 B4 B5 B8 B9 B12 B13 B16 B17 B20 B21 B24 B25 B28 B29 B32 B33 B36 B37 C2 C3 C6 C7 D4 D5 E30 E31 E33 E34 E36 E37 F34 F35 F37 F38 J33 J34 J36 J37 K34 K35 K37 K38; J54 A2 A3 A6 A7 A10 A11 A14 A15 A18 A19 A22 A23 A26 A27 A30 A31 A34 A35 A38 A39 B4 B5 B8 B9 B12 B13 B16 B17 B20 B21 B24 B25 B28 B29 B32 B33 B36 B37 C2 C3 C6 C7 D4 D5 E12 E13 E15 E16 E18 E19 E21 E22 E24 E25 E27 E28 E30 E31 E33 E34 E36 E37 F13 F14 F16 F17 F19 F20 F22 F23 F25 F26 F28 F29 F31 F32 F34 F35 F37 F38 J15 J16 J18 J19 J21 J22 J24 J25 J27 J28 J30 J31 J33 J34 J36 J37 K16 K17 K19 K20 K22 K23 K25 K26 K28 K29 K31 K32 K34 K35 K37 K38; U1 21 22 23 26 27 28 29 30 32 33 34 36 41 43 44 45 46 48 52 53 54 55 57 58 59 60; U2 7; U3 A5 A6 A8 A9 A11 A12 A14 A15 A17 A18 A20 A21 A23 A24 A26 A27 A29 A30 A32 A33 AA29 AA30 AA32 AA33 AA34 AB21 AB30 AB31 AB32 AC27 AC30 AD26 AD29 AD30 AE26 AE28 AE29 AE30 AF27 AH33 AJ26 AL30 AL33 AL34 AM31 AM32 AM33 AM34 AN30 AN31 AN32 AN33 AN34 AP30 AP31 AP32 B1 B3 C1 C3 C5 C6 C8 C9 C11 C12 C14 C15 C17 C18 C20 C21 C23 C24 C26 C27 C29 C30 C32 C33 E1 E3 E5 E6 E8 E9 E11 E12 E14 E15 E17 E18 E20 E21 E23 E24 E26 E27 E29 E30 E32 E33 F1 F3 G5 G6 G8 G9 G11 G12 G14 G15 G17 G18 G20 G21 G23 G24 G26 G27 G29 G30 G32 G33 H1 H3 J1 J3 J6 J12 J18 J24 J30 L1 L3 L26 L28 L30 L32 L34 M1 M3 M6 M28 M30 M32 M34 P28 P30 P32 P34 R28 R30 R32 R34 T26 U32 U33 U34 V31 V33 V34 W22 W25 W33 W34 Y30 Y31 Y32 Y33 Y34; U5 A1 A2 A8 A11 A12 AA1 AA12 AB1 AB2 AB11 AB12 B1 B12 G11 H3 J5 K5 K8 N5 N8 P5 R3; U45 A2 A5 A7 A9 B1 B2 B5 B7 C2 C9 D1 D3 D4 D9 E1 E4 E10 F1 F3 F5 F10 G3 G5 G6 G9 G10 H2 H3 H5 H6 H9 J1 J2 J3 J4 J5 J6 J9 K2 K3 K4 K5 K9; U46 5 6 9 10; U108 13 15 16; U110 6 13; U111 6 13; U118 5; U119 A1 A2 A8 A11 A12 AA1 AA12 AB1 AB2 AB11 AB12 B1 B12 G11 H3 J5 K5 K8 N5 N8 P5 R3; U120 10 16 18 24; Y1 2

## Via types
v1: diameter 0.406, hole 0.203, TOP to BOTTOM, 377 vias
v2: diameter 0.356, hole 0.203, TOP to BOTTOM, 1778 vias
v3: diameter 0.305, hole 0.152, TOP to BOTTOM, 447 vias
v4: diameter 0.508, hole 0.254, TOP to BOTTOM, 1244 vias
v5: diameter 0.508, hole 0.305, TOP to BOTTOM, 191 vias
v6: diameter 0.457, hole 0.254, TOP to BOTTOM, 106 vias

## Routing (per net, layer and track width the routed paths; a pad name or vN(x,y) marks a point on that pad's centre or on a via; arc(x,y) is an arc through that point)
0V82_EN: length 23.9
  TOP w0.152: U45.C7 v3(157.65,73.06)
  BOTTOM w0.127: R704.2 136.4,74.34 136.65,74.6 137.67,74.6 138.43,75.36 140.59,75.36 141.78,74.16 149.66,74.16 UNK0V82_EN.1 150.96,72.86 153.87,72.86 154.07,72.66 157.2,72.66 157.59,73.06 v3(157.65,73.06)
0V82_MON: length 69.5
  TOP w0.254: U45.K8 v3(159.24,66.66) ; R575.2 101.61,67.1 103.71,65.01 103.71,62.21 107.76,58.16 129.6,58.16 130.31,57.45 143.64,57.45 144.4,58.21 144.4,59.61 v1(144.27,59.74)
  L03-SIG1 w0.254: v1(144.27,59.74) 144.91,60.37 149.96,60.37 155.8,66.21 158.8,66.21 v3(159.24,66.66)
0V82_MON_GS: length 70.9
  TOP w0.254: R576.2 101.98,66.09 103.25,64.82 103.25,62.02 107.57,57.7 129.41,57.7 130.12,56.99 143.83,56.99 144.86,58.02 144.86,59.56 v1(145.03,59.74) ; U45.J8 v3(159.24,67.46)
  L03-SIG1 w0.254: v3(159.24,67.46) 159.69,67.01 159.69,66.39 159,65.71 155.96,65.71 150.11,59.86 145.16,59.86 v1(145.03,59.74)
0V82_TRIM: length 4.9
  TOP w0.152: U45.D8 v3(159.24,72.26)
  L03-SIG1 w0.114: v3(159.24,72.26) 159.63,71.87 159.63,69.43 v2(160.02,69.04)
  BOTTOM w0.152: R562.2 v2(160.02,69.04)
1V8_LDO:
  vias: v1(99.31,123.49) v1(99.31,122.86) v1(99.31,122.09) v1(99.95,123.49) v1(99.95,122.86) v1(99.95,122.09) v1(120.27,101.77) v1(120.27,101.14) v1(120.9,101.77) v1(120.9,101.14) v1(121.54,101.77) v1(121.54,101.14)
1V80_EN: length 29.7
  TOP w0.127: R716.2 156.08,92.64 v1(156.08,92.63)
  TOP w0.152: U45.E6 v3(157.64,71.46)
  L05-SIG2 w0.091: v1(156.08,92.63) 158.88,92.63 161.63,89.88 161.63,84.92 UNK1V80_EN.1 161.54,84.32 161.54,81.55 159.52,79.52 159.52,75.08 158.85,74.42 158.85,72.01 158.67,71.83 158.01,71.83 v3(157.64,71.46)
1V80_MON: length 2.2
  TOP w0.305: v3(160.96,73.29) 160.96,72.96 v3(160.89,72.88) 160.66,72.66 U45.C10 ; U45.J7 v3(157.65,67.46)
  TOP w0.508: R577.2 v2(141.35,94.11)
  vias: v2(140.53,94.07) v2(140.54,93.36) v2(141.35,93.36)
1V80_TRIM: length 3.3
  TOP w0.305: U45.B8 v3(159.24,73.86)
  BOTTOM w0.305: R287.2 160.78,73.96 160.4,74.34 159.73,74.34 v3(159.24,73.86)
12V00_MON: length 7.9
  TOP w0.305: R289.1 R554.2 163.8,71.17 v2(163.93,71.04) ; U45.B9 v3(160.04,73.86)
  L12-SIG4 w0.305: v3(160.04,73.86) 161.11,73.86 v2(163.93,71.04)
GND: length 2019.5
  TOP w0.203: v4(12.06,131.39) 11.92,131.54 D3.1 ; v5(140.09,65.58) 140.06,65.6 U120.22
  TOP w0.254: v4(19.56,133.68) 19.27,133.39 U1.5 ; U45.A1 v3(152.85,74.66) ; v1(107.37,37.64) 107.5,37.5 R245.2 ; v1(138.05,61.01) 138.05,63.8 R697.2 138.81,65.07 139.06,65.32 U120.20 ; R583.1 98.69,64.43 v2(98.3,64.82) ; U43.15 126.15,42.42 v4(126.14,42.42) ; U43.15 v4(126.9,41.66) ; U43.15 127.64,42.42 v4(127.66,42.42) ; U43.15 126.14,40.92 v4(126.14,40.9) ; U43.15 127.66,40.92 v4(127.66,40.9) ; SW2.3 v4(40.68,134.2) ; v2(59.31,78.91) 59.06,78.67 R686.2 ; 129.15,137.16 J6.5 ; J6.5 130.09,138.09 ; J6.5 130.09,136.23 ; U1.47 v4(29.08,134.89) ; U45.G4 v3(155.25,69.06) ; U1.51 27.06,136.84 v2(27.43,136.47) ; v4(144.78,9.95) 145.53,9.2 U108.11 ; U45.F7 v3(157.65,69.86) ; JP15.1 60.71,102.07 ; JP15.1 60.71,100.21 ; JP15.1 61.64,101.14 ; JP15.1 59.77,101.14 ; v4(103.72,106.72) 103.56,106.55 U44.5 ; v4(158.5,79.76) 157.94,79.21 Q26.S ; v3(112.93,71.12) 112.46,71.59 112.1,71.59 U119.G12 ; U45.K7 v3(157.65,66.66) ; U45.A10 160.44,74.37 v3(160.81,74.74) ; v1(152.39,15.65) 151.65,15.65 151.25,16.06 C1189.2 C1188.2 ; 130.09,138.77 J6.11 ; J6.11 130.09,140.63 ; J6.11 129.15,139.7 ; J7.5 108.16,137.16 ; J7.5 107.23,136.23 ; J7.5 106.29,137.16 ; J7.5 107.23,138.09 ; C1192.1 143.76,14.78 v4(143.89,14.91) ; 106.29,139.7 J7.11 ; J7.11 108.16,139.7 ; J7.11 107.23,138.77 ; J7.11 107.23,140.63 ; U45.K10 v3(160.84,66.66) ; U110.21 v4(119.89,23.67) ; U45.F9 v3(160.04,69.86) ; C1269.2 v5(143,74.6) ; U45.K6 v3(156.85,66.66) ; U45.K1 v3(152.85,66.66) ; J25.A1 v4(154.9,15.58) ; v4(154.86,21.09) J25.A12 156.36,21.09 v5(156.61,20.84) J25.B1 v4(158.24,20.84) ; v2(29.21,129.11) 29.43,128.89 U1.35 ; v4(103.11,87.51) 104.26,87.51 104.76,88.01 104.76,92.03 104.06,92.72 v5(103.12,92.72) v4(101.42,92.72) 99.61,92.72 99.31,92.42 99.31,87.68 v2(100.33,86.66) ; J25.B12 v4(158.16,15.33) ; U1.15 v4(19.64,128.39) ; U45.E7 v3(158.44,71.46) ; JP26.6 52.32,144.46 C599.2 ; U45.D10 v3(160.84,72.26) ; U111.21 v4(148.84,23.67) ; v2(98.53,65.93) 98.68,66.09 R576.1 ; U45.E2 v3(153.65,71.46) ; U1.13 v4(19.66,129.39) ; D62.K v4(161.1,92.88)
  TOP w0.305: v4(109.1,39.28) 109.4,38.98 C732.2 ; R612.1 v4(116.08,20.49) ; D1.K v4(9.14,140.54) ; R15.1 v4(13.72,133.81) ; v4(19.43,135.97) 18.85,135.39 U1.1 ; U1.25 v4(24.56,126.82) ; v4(19.68,131.14) 19.43,130.89 U1.10 ; R616.1 120.01,19.86 v4(120.27,20.11) ; C5.2 v4(26.16,140.16) ; C1266.2 v4(116.08,26.08) ; v2(58.55,14.3) J54.H3 ; U1.11 19.42,130.39 v4(19.68,130.12) ; R621.2 v5(152.65,26.84) ; R643.2 v4(116.08,27.48) ; R681.1 R554.1 ; C1264.2 v4(116.08,28.88) ; R620.2 v4(116.08,21.89)
  TOP w0.381: v2(11.84,65.07) 12.47,65.71 v2(13.11,65.07) ; J54.G29 v2(90.3,15.57) ; J54.G29 v2(91.57,15.57) ; J54.G29 v2(91.57,14.3) ; J54.D28 v2(89.03,18.11) ; J54.D28 v2(90.3,19.38) ; J54.D28 v2(89.03,19.38) ; v2(5.49,95.55) J48.K9 v2(6.76,94.28) ; U3.G2 v2(64.9,90.93) ; U3.H14 v2(76.9,89.93) ; J48.A8 v2(18.19,96.82) ; J48.E23 v2(13.11,77.77) ; v2(95.38,13.03) J54.J32 v2(95.38,11.76) ; J54.K27 v2(89.03,10.49) ; v2(6.76,99.36) J48.J5 v2(8.03,99.36) J48.H6 ; U3.B5 v2(67.9,95.93) ; U3.H32 v2(95.9,89.93) ; U3.G25 v2(88.9,90.93) ; J48.B30 v2(16.92,67.61) ; U3.N4 v2(66.9,84.93) ; v2(101.73,11.76) J54.J38 v2(103,11.76) ; v2(66.17,20.65) 66.8,21.28 v2(66.17,21.92) ; U3.J14 v2(76.9,88.93) ; J54.A36 v2(100.46,23.19) ; 17.55,65.71 v2(18.19,65.07) ; U3.J28 v2(91.9,88.93) ; U3.T29 v2(92.9,81.93) ; U3.H7 v2(69.9,89.93) ; R430.2 v4(136.86,92.19) ; U3.M29 v2(92.9,85.93) ; U3.F33 v2(96.9,91.93) ; J48.F6 v2(11.84,99.36) ; J54.C28 v2(90.3,20.65) ; J48.G1 v2(9.3,105.71) ; U3.T17 v2(79.9,81.93) ; v2(72.9,80.93) U3.U10 v2(73.9,79.93) ; U3.J11 v2(73.9,88.93) ; U3.F18 v2(81.9,91.93) ; v2(15.65,94.28) J48.C9 v2(15.65,95.55) ; U3.L13 v2(75.9,86.93) ; U3.AB2 v2(64.9,74.93) ; U3.D8 v2(70.9,93.93) ; U3.AH19 v2(82.9,68.93) ; U3.H12 v2(74.9,89.93) ; v2(72.52,18.11) J54.E14 v2(71.25,18.11) ; U3.J20 v2(83.9,88.93) ; v2(6.76,103.17) J48.K2 v2(5.49,104.44) ; U3.F29 v2(92.9,91.93) ; U3.F5 v2(67.9,91.93) ; U3.D25 v2(88.9,93.93) ; J54.K9 v2(64.9,10.49) ; J54.J40 v4(105.54,11.76) ; U3.D22 v2(85.9,93.93) ; J54.E32 v2(95.38,16.84) ; U3.R33 v2(96.9,82.93) ; J48.D37 13.03,60.07 v2(13.03,60.12) ; D74.K 161.35,82.76 v4(160.8,83.32) ; U3.H22 v2(85.9,89.93) ; U3.K9 v2(71.9,87.93) ; U3.L31 v2(94.9,86.93) ; U3.AG22 v2(85.9,69.93) ; R670.1 v4(129.41,15.41) ; U3.B27 v2(90.9,95.93) ; U3.D9 v2(71.9,93.93) ; U3.D29 v2(92.9,93.93) ; U3.H23 v2(86.9,89.93) ; J48.B39 v2(16.92,56.18) ; v2(56.01,18.11) 56.64,18.74 v2(56.01,19.38) ; U3.K6 v2(68.9,87.93) ; U3.P31 v2(94.9,83.93) ; U3.K4 v2(66.9,87.93) ; U3.H25 v2(88.9,89.93) ; U3.J19 v2(82.9,88.93) ; J48.D13 v2(14.38,90.47) ; J48.H12 v2(8.03,91.74) ; J54.D3 v2(57.28,19.38) ; v2(76.9,80.93) U3.U14 v2(76.9,79.93) ; J54.B14 v2(71.25,21.92) ; U3.C4 v2(66.9,94.93) ; U3.K15 v2(77.9,87.93) ; J54.H24 v2(83.95,14.3) ; J54.H24 v2(85.22,13.03) ; J54.H24 v2(83.95,13.03) ; v2(95.38,19.38) J54.C32 v2(95.38,20.65) ; U3.AH11 v2(73.9,68.93) ; v2(78.87,19.38) 79.5,20.01 v2(78.87,20.65) ; J54.G26 v2(87.76,14.3) J54.H27 v2(89.03,13.03) ; J48.C16 v2(15.65,86.66) ; U3.W28 v2(91.9,77.93) ; U3.T32 v2(95.9,81.93) ; J54.F15 v2(72.52,16.84) ; U3.K11 v2(73.9,87.93) ; U3.B26 v2(89.9,95.93) ; v2(78.87,15.57) 79.5,14.93 v2(80.14,15.57) ; D73.K v4(161.23,88.69) ; v4(61.47,128.95) 61.76,128.66 SW5.1 ; U3.K7 v2(69.9,87.93) ; U3.L25 v2(88.9,86.93) ; J48.B7 v2(16.92,98.09) ; v2(81.41,18.11) J54.D22 v2(81.41,19.38) ; J54.C24 v2(85.22,20.65) ; 64.26,17.47 v2(63.63,18.11) ; R455.2 v4(152.96,83.18) ; J54.C1 v2(54.74,20.65) ; J54.F24 v2(83.95,15.57) ; U3.G34 v2(97.9,90.93) ; U3.D10 v2(72.9,93.93) ; U3.B25 v2(88.9,95.93) ; U3.D1 v2(63.9,93.93) ; J54.C17 v2(75.06,20.65) ; U3.AB11 v2(73.9,74.93) ; U3.V24 v2(86.9,79.93) ; U3.K30 v2(93.9,87.93) ; J48.F27 v2(11.84,71.42) ; U3.B6 v2(68.9,95.93) ; v2(10.57,62.53) J48.G35 v2(9.3,61.26) ; J2.5 v4(9.4,130.14) ; U3.V6 v2(68.9,78.93) ; C59.2 136.21,68.32 v5(136.4,68.5) ; J48.C12 v2(15.65,91.74) ; U3.G7 v2(69.9,90.93) ; U3.L33 v2(96.9,86.93) ; U3.AJ14 v2(76.9,67.93) ; J48.J26 v2(8.03,72.69) ; U3.N31 v2(94.9,84.93) ; J48.A28 v2(18.19,70.15) ; v2(73.79,13.03) J54.H15 v2(72.52,13.03) ; J48.C28 v2(15.65,70.15) ; J48.A20 v2(18.19,81.58) ; v2(15.65,84.12) J48.B18 v2(16.92,84.12) ; R449.2 v4(153.97,121.76) ; C288.2 v4(102.14,95.35) ; U3.J31 v2(94.9,88.93) ; J48.A40 v2(18.19,54.91) ; C293.2 v4(110.31,52.63) ; U3.F30 v2(93.9,91.93) ; U3.M25 88.4,85.43 v2(88.9,84.93) U3.N25 ; J54.A29 v2(91.57,23.19) ; U3.W19 v2(82.9,77.93) ; U3.AM7 v2(69.9,64.93) ; U3.D6 v2(68.9,93.93) ; U3.A7 v2(69.9,96.93) ; v2(89.03,16.84) J54.F27 v2(87.76,15.57) ; U3.B34 v2(97.9,95.93) ; U3.D14 v2(76.9,93.93) ; U3.B8 v2(70.9,95.93) ; U3.D15 v2(77.9,93.93) ; J48.C13 v2(15.65,90.47) ; U3.K13 v2(75.9,87.93) ; U3.J9 v2(71.9,88.93) ; U3.K31 v2(94.9,87.93) ; U3.M15 v2(77.9,85.93) ; J54.K24 v2(85.22,10.49) ; U3.N1 v2(63.9,84.93) ; U3.E22 v2(85.9,92.93) ; R232.2 v4(151.51,131.08) ; v2(58.55,15.57) J54.F3 v2(57.28,15.57) ; J48.A4 v2(18.19,101.9) ; J48.J40 v2(6.76,54.91) ; U3.K24 v2(87.9,87.93) ; 97.28,21.28 v2(97.92,21.92) ; 7.39,84.76 v2(6.76,85.39) ; R674.1 R669.1 v1(136.4,15.41) ; U3.M33 v2(96.9,85.93) ; U3.AL32 v2(95.9,65.93) ; U3.F13 v2(75.9,91.93) ; C676.2 v4(119.76,46.4) ; SW4.3 54.77,136.54 v4(54.48,136.83) ; C69.2 v4(60.83,99.11) ; J48.A36 v2(18.19,59.99) ; U3.H30 v2(93.9,89.93) ; J48.D28 v2(14.38,70.15) ; U3.H8 v2(70.9,89.93) ; J48.H30 v2(9.3,68.88) ; U3.M18 v2(81.9,85.93) ; J48.B15 v2(16.92,87.93) ; v4(13.84,140.38) 14.31,140.85 X1.2 15.03,141.69 v4(15.37,142.03) 18.29,142.03 18.71,141.61 18.71,138.12 C17.1 17.69,136.38 v4(17.72,136.35) ; U3.D16 v2(78.9,93.93) ; J48.J11 v2(6.76,91.74) ; U3.F24 v2(87.9,91.93) ; U3.F14 v2(76.9,91.93) ; 59.18,12.39 v2(58.55,11.76) ; R457.2 v4(151.18,77.31) ; J48.C38 v2(15.65,57.45) ; J48.D39 v2(13.11,57.45) ; J48.H24 v2(9.3,76.5) ; U3.F32 v2(95.9,91.93) ; 74.42,18.74 v2(73.79,19.38) ; U3.L19 v2(82.9,86.93) ; J54.D39 v2(104.27,19.38) ; J48.K18 v2(5.49,82.85) ; 69.34,11.12 v2(69.98,11.76) ; 69.34,11.12 v2(68.71,11.76) ; 69.34,11.12 v2(68.71,10.49) ; J48.K33 v2(5.49,63.8) ; U3.AP1 v2(63.9,62.93) ; v2(69.98,19.38) J54.D13 v2(69.98,18.11) ; U3.E16 v2(78.9,92.93) ; U3.B22 v2(85.9,95.93) ; J48.F9 v2(11.84,95.55) ; J48.B11 v2(16.92,93.01) ; U3.AD13 v2(75.9,72.93) ; U3.B10 v2(72.9,95.93) ; U3.AD25 v2(88.9,72.93) ; U3.AG3 v2(65.9,69.93) ; U3.N27 v2(90.9,84.93) ; U3.T2 v2(64.9,81.93) ; U3.D7 v2(69.9,93.93) ; v2(59.82,14.3) J54.G5 v2(61.09,14.3) ; J54.K33 v2(96.65,10.49) ; X3.2 v4(58.51,92.92) ; U3.J34 v2(97.9,88.93) ; U3.G3 v2(65.9,90.93) ; J48.D16 v2(14.38,86.66) ; J48.A13 v2(18.19,90.47) ; J48.E35 v2(13.11,61.26) ; U3.B19 v2(82.9,95.93) ; U3.F8 v2(70.9,91.93) ; J48.E14 v2(13.11,89.2) ; U3.C10 v2(72.9,94.93) ; U3.D20 v2(83.9,93.93) ; U3.P33 v2(96.9,83.93) ; U3.AM15 v2(77.9,64.93) ; U3.A2 v2(64.9,96.93) ; J48.G20 v2(9.3,81.58) ; J54.G1 v2(54.74,14.3) ; U3.B9 v2(71.9,95.93) ; U3.J29 v2(92.9,88.93) ; 56.64,21.28 v2(56.01,21.92) ; v2(8.03,96.82) J48.J8 v2(6.76,95.55) ; J48.H39 v2(8.03,57.45) ; 16.28,102.54 v2(16.92,103.17) ; 64.26,22.55 v2(63.63,23.19) ; 92.2,11.12 v2(91.57,10.49) ; J54.C25 v2(86.49,20.65) ; J48.B22 v2(16.92,77.77) ; U3.H15 v2(77.9,89.93) ; U3.P29 v2(92.9,83.93) ; J54.E35 v2(97.92,18.11) ; U3.B24 v2(87.9,95.93) ; 59.18,14.93 v2(58.55,14.3) ; U3.R27 v2(90.9,82.93) ; 56.64,16.2 v2(56.01,15.57) ; R436.2 v4(136.86,120.92) ; U3.F34 v2(97.9,91.93) ; J48.G11 v2(10.57,91.74) ; U3.K23 v2(86.9,87.93) ; U3.AD28 v2(91.9,72.93) ; J48.C5 v2(15.65,100.63) ; J48.D7 v2(14.38,98.09) ; J48.G23 v2(10.57,76.5) ; J48.D10 v2(14.38,94.28) ; J48.H18 v2(8.03,84.12) ; J54.F33 v2(95.38,15.57) ; J2.9 v4(9.52,127.29) ; U3.J15 v2(77.9,88.93) ; J54.B18 v2(76.33,21.92) ; U3.R23 v2(86.9,82.93) ; Y1.3 v4(99.86,91.33) ; J48.G5 v2(10.57,99.36) ; U3.F9 v2(71.9,91.93) ; v4(105.72,94.03) C403.1 C169.1 C168.1 ; v4(109.73,34.21) 109.66,34.28 C733.2 ; v2(10.57,104.44) J48.F2 11.2,102.54 ; U3.V20 v2(83.9,78.93) ; U3.H21 v2(84.9,89.93) ; U3.L21 v2(84.9,86.93) ; R617.1 R611.1 v4(152.65,28.24) ; J54.J14 v2(71.25,11.76) ; U3.J26 v2(89.9,88.93) ; U3.E13 v2(75.9,92.93) ; 6.12,102.54 v2(5.49,103.17) ; U3.L6 v2(68.9,86.93) ; J48.D22 v2(14.38,79.04) ; v2(71.25,15.57) J54.G14 v2(72.52,15.57) ; U3.J23 v2(86.9,88.93) ; v2(68.71,16.84) J54.E11 v2(67.44,18.11) ; 15.01,65.71 v2(15.65,65.07) ; J48.A21 v2(18.19,79.04) ; U3.A34 v2(97.9,96.93) ; J48.K39 v2(5.49,57.45) ; U3.T34 v2(97.9,81.93) ; v2(76.33,13.03) J54.J17 v2(75.06,11.76) ; J48.B14 v2(16.92,89.2) ; U3.M23 v2(86.9,85.93) ; R465.2 v4(126.58,47.26) ; U3.W21 v2(84.9,77.93) ; U3.H16 v2(78.9,89.93) ; U3.K29 v2(92.9,87.93) ; J48.F36 v2(10.57,61.26) ; U3.A28 v2(91.9,96.93) ; v2(96.65,13.03) J54.H33 v2(95.38,14.3) ; J48.G40 v2(9.3,54.91) ; U3.Y25 v2(88.9,76.93) ; v2(61.09,15.57) 61.72,16.2 v2(61.09,16.84) ; J48.C25 v2(15.65,73.96) ; 59.18,20.01 v2(58.55,20.65) ; U3.J27 v2(90.9,88.93) ; J2.6 v4(9.52,136.19) ; U3.L18 v2(81.9,86.93) ; U3.K12 v2(74.9,87.93) ; U3.AJ8 v2(70.9,67.93) ; v2(15.65,96.82) J48.C8 v2(14.38,96.82) ; U3.H29 v2(92.9,89.93) ; v2(86.9,84.93) U3.N23 v2(85.9,83.93) U3.P22 85.4,83.43 v2(84.9,82.93) U3.R21 v2(84.9,81.93) U3.T21 v2(83.9,80.93) U3.U20 ; U3.N2 v2(64.9,84.93) ; U3.J32 v2(95.9,88.93) ; 56.64,11.12 v2(56.01,10.49) ; U3.R29 v2(92.9,82.93) ; U3.B33 v2(96.9,95.93) ; SW4.1 v4(54.77,128.86) ; J54.A37 v2(101.73,23.19) ; J48.A29 v2(18.19,68.88) ; v2(54.74,11.76) J54.J1 v2(56.01,11.76) ; U3.F25 v2(88.9,91.93) ; J48.C24 v2(15.65,75.23) ; J54.B31 v2(94.11,21.92) ; U3.H9 v2(71.9,89.93) ; J48.H27 v2(9.3,72.69) ; R651.2 v4(126.62,15.41) ; U3.L27 v2(90.9,86.93) ; J54.K36 v2(99.19,11.76) ; U3.D34 v2(97.9,93.93) ; J54.B19 v2(77.6,21.92) ; U3.H2 v2(64.9,89.93) ; J54.C13 v2(69.98,20.65) ; 2.25,136.19 J2.7 v4(4.02,136.19) ; U3.R25 v2(88.9,82.93) ; J48.D25 v2(14.38,73.96) ; SW2.1 v4(40.68,128.99) ; C734.2 v4(153.54,92.55) ; U3.D11 v2(73.9,93.93) ; U3.F16 v2(78.9,91.93) ; J48.H9 v2(8.03,95.55) ; U3.F10 v2(72.9,91.93) ; v2(15.65,85.39) 15.01,84.76 v2(14.38,85.39) ; J48.K24 v2(5.49,75.23) ; J48.E8 v2(13.11,96.82) ; J48.B35 v2(16.92,61.26) ; J48.E40 v2(13.11,54.91) ; v2(91.57,16.84) 92.2,16.2 v2(92.84,16.84) ; J48.E26 v2(13.11,73.96) ; U3.J21 v2(84.9,88.93) ; U3.N26 v2(89.9,84.93) 89.4,85.43 U3.M26 ; U3.D5 v2(67.9,93.93) ; v2(99.19,14.3) J54.H36 v2(100.46,13.03) ; v5(135.38,62.02) 135.25,62.15 R54.1 135.76,62.79 v5(136.14,62.4) 136.27,62.53 R696.2 ; J54.A5 v2(59.82,23.19) ; U3.B28 v2(91.9,95.93) ; U3.P24 v2(87.9,83.93) ; J48.E5 v2(13.11,100.63) ; J54.A25 v2(86.49,23.19) ; J54.F36 v2(100.46,16.84) ; U3.A13 v2(75.9,96.93) ; U3.W32 v2(95.9,77.93) ; U3.D17 v2(79.9,93.93) ; J48.C40 v2(15.65,54.91) ; U3.F11 v2(73.9,91.93) ; U3.AC22 v2(85.9,73.93) ; J48.H36 v2(8.03,59.99) ; U3.D21 v2(84.9,93.93) ; U3.G4 v2(66.9,90.93) ; U3.P25 v2(88.9,83.93) ; J48.J20 v2(8.03,80.31) ; U3.H26 v2(89.9,89.93) ; J54.A33 v2(96.65,23.19) ; U3.M11 v2(73.9,85.93) ; U3.K33 v2(96.9,87.93) ; 92.2,13.66 v2(92.84,13.03) ; U3.D2 v2(64.9,93.93) ; U3.B20 v2(83.9,95.93) ; J54.A24 v2(85.22,23.19) ; 69.34,20.01 v2(68.71,20.65) ; U3.H17 v2(79.9,89.93) ; v2(80.14,11.76) 79.5,12.39 v2(78.87,11.76) ; J48.B31 v2(16.92,66.34) ; v2(11.84,67.61) J48.F30 v2(11.84,68.88) ; U3.B14 v2(76.9,95.93) ; U3.T27 v2(90.9,81.93) ; J54.D7 v2(62.36,19.38) ; U3.D27 v2(90.9,93.93) ; J48.B6 v2(16.92,99.36) ; U3.AM22 v2(85.9,64.93) ; U3.H24 v2(87.9,89.93) ; U3.F2 v2(64.9,91.93) ; U3.E34 v2(97.9,92.93) ; U3.J5 v2(67.9,88.93) ; J48.J35 v2(6.76,61.26) ; U3.G16 v2(78.9,90.93) ; U3.Y23 v2(86.9,76.93) ; U3.H11 v2(73.9,89.93) ; R306.2 v4(32.13,31.03) ; U3.K27 v2(90.9,87.93) ; U3.M21 v2(84.9,85.93) ; v2(81.41,20.65) J54.B22 v2(82.68,21.92) ; J48.A33 v2(18.19,63.8) ; U3.J22 v2(85.9,88.93) ; J48.F24 v2(11.84,76.5) ; J54.K39 v2(103,10.49) ; U3.AH28 v2(91.9,68.93) ; R589.2 v4(131.51,44.89) ; U3.J33 v2(96.9,88.93) ; U3.F26 v2(89.9,91.93) ; U3.C25 v2(88.9,94.93) ; 66.8,18.74 v2(66.17,19.38) ; U3.H5 v2(67.9,89.93) ; J48.F33 v2(11.84,63.8) ; U3.A1 v2(63.9,96.93) ; J48.A24 v2(18.19,75.23) ; J48.K27 v2(5.49,71.42) ; J48.E4 v2(13.11,101.9) ; v2(10.57,65.07) 9.93,65.71 v2(9.3,65.07) ; J48.H15 v2(8.03,86.66) ; U3.K3 v2(65.9,87.93) ; U3.D19 v2(82.9,93.93) ; U3.T31 v2(94.9,81.93) ; J48.H33 v2(8.03,63.8) ; U3.G13 v2(75.9,90.93) ; J54.C29 v2(91.57,20.65) ; J48.A16 v2(18.19,86.66) ; J54.B35 v2(99.19,21.92) ; J54.F18 v2(76.33,15.57) ; U3.B30 v2(93.9,95.93) ; J48.A37 v2(18.19,58.72) ; U3.AM12 v2(74.9,64.93) ; J54.B26 v2(87.76,21.92) ; U3.L14 v2(76.9,86.93) ; U3.W16 v2(78.9,77.93) ; U3.N34 v2(97.9,84.93) ; U3.AN27 v2(90.9,63.93) ; J54.E1 v2(54.74,18.11) ; U3.H27 v2(90.9,89.93) ; U3.B31 v2(94.9,95.93) ; U3.G31 v2(94.9,90.93) ; U3.K2 v2(64.9,87.93) ; J48.J29 v2(6.76,70.15) ; R639.1 v4(161.42,27.86) ; R419.2 v4(153.29,107.74) ; 61.72,11.12 v2(61.09,11.76) ; J48.K6 v2(5.49,98.09) ; U3.B21 v2(84.9,95.93) ; J48.A9 v2(18.19,95.55) ; J54.J26 v2(87.76,11.76) ; v2(58.55,10.49) J54.K3 v2(57.28,10.49) ; U3.AJ25 v2(88.9,67.93) ; v2(91.57,13.03) J54.J29 v2(91.57,11.76) ; U3.J8 v2(70.9,88.93) ; SW8.3 v4(131.92,55.07) ; J48.K12 v2(5.49,91.74) ; J54.B7 v2(62.36,21.92) ; J48.B23 v2(16.92,76.5) ; U3.E7 v2(69.9,92.93) ; U3.L5 v2(67.9,86.93) ; J48.C20 v2(15.65,81.58) ; U3.B17 v2(79.9,95.93) ; J48.K15 v2(5.49,86.66) ; U3.B12 v2(74.9,95.93) ; U3.H6 v2(68.9,89.93) ; U3.K34 v2(97.9,87.93) ; U3.A4 v2(66.9,96.93) ; U3.V18 v2(81.9,78.93) ; J48.B26 v2(16.92,72.69) ; J54.K18 v2(76.33,10.49) ; U3.K25 v2(88.9,87.93) ; U3.K22 v2(85.9,87.93) ; J48.C4 v2(15.65,101.9) ; U3.M5 v2(67.9,85.93) ; U3.AL3 v2(65.9,65.93) ; J48.F15 v2(11.84,87.93) ; U3.K8 v2(70.9,87.93) ; C675.2 v4(119.76,45) ; v2(68.71,13.03) 69.34,13.66 v2(68.71,14.3) ; J54.A28 v2(90.3,23.19) ; J48.E38 v2(11.84,57.45) ; U3.C19 v2(82.9,94.93) ; U3.M24 v2(87.9,85.93) ; 69.34,22.55 v2(68.71,23.19) ; U3.K21 v2(84.9,87.93) ; U3.J7 v2(69.9,88.93) ; 69.34,16.2 v2(68.71,15.57) J54.G11 ; C720.2 v4(103.98,104.05) ; U3.H4 v2(66.9,89.93) ; v2(103,14.3) J54.H39 v2(103,13.03) ; J48.K21 v2(5.49,79.04) ; U3.B16 v2(78.9,95.93) ; R100.2 v4(45.09,45.89) ; J54.D37 v2(100.46,18.11) ; R435.2 v4(139.32,126.08) ; U3.B29 v2(92.9,95.93) ; 61.72,21.28 v2(61.09,21.92) ; U3.G10 v2(72.9,90.93) ; 64.26,20.01 v2(63.63,20.65) ; v2(80.14,16.84) v2(78.87,18.11) ; U3.H31 v2(94.9,89.93) ; U3.B4 v2(66.9,95.93) ; J48.J23 v2(6.76,76.5) ; U3.F12 v2(74.9,91.93) ; U3.J25 v2(88.9,88.93) ; U3.R31 v2(94.9,82.93) ; v2(13.11,104.44) J48.D2 v2(14.38,104.44) ; U3.E2 v2(64.9,92.93) ; 74.42,22.55 v2(73.79,23.19) ; U3.L23 v2(86.9,86.93) ; U3.A10 v2(72.9,96.93) ; v2(103,15.57) J54.F39 J54.E38 ; U3.B18 v2(81.9,95.93) ; J54.B15 v2(72.52,21.92) ; U3.D33 v2(96.9,93.93) ; J54.B38 v2(101.73,21.92) ; U3.AE16 v2(78.9,71.93) ; J48.F12 v2(11.84,91.74) ; U3.AP34 v2(97.9,62.93) ; U3.T33 v2(96.9,81.93) ; U3.T28 v2(91.9,81.93) ; J48.G4 v2(10.57,100.63) ; J48.E29 v2(13.11,68.88) ; J54.E40 v2(105.54,18.11) ; R421.2 v4(151.51,101.87) ; U3.B13 v2(75.9,95.93) ; U3.D4 v2(66.9,93.93) ; J54.E23 v2(82.68,18.11) ; U3.K18 v2(81.9,87.93) ; U3.A22 v2(85.9,96.93) ; U3.AB8 v2(70.9,74.93) ; J48.A5 v2(18.19,100.63) ; U3.E10 v2(72.9,92.93) ; v4(160.85,79.92) 161.35,79.41 D78.K ; U3.N28 v2(91.9,84.93) ; v2(64.9,16.84) J54.F9 v2(64.9,15.57) ; U3.U18 v2(81.9,80.93) ; U3.M4 v2(66.9,85.93) ; U3.R26 v2(89.9,82.93) ; U3.F19 v2(82.9,91.93) ; J54.H21 v2(80.14,13.03) ; U3.D18 v2(81.9,93.93) ; U3.T23 v2(86.9,81.93) ; U3.L4 v2(66.9,86.93) ; 12.47,84.76 v2(13.11,85.39) ; C672.2 v4(124.43,47.06) ; U3.K20 v2(83.9,87.93) ; J48.E11 v2(13.11,93.01) ; U3.K14 v2(76.9,87.93) ; J48.C21 v2(15.65,79.04) ; U3.H20 v2(83.9,89.93) ; U3.J2 v2(64.9,88.93) ; U3.F28 v2(91.9,91.93) ; U3.K32 v2(95.9,87.93) ; J54.A32 v2(95.38,23.19) ; J54.C5 v2(59.82,20.65) ; 17.55,84.76 v2(18.19,85.39) ; U3.K16 v2(78.9,87.93) ; U3.M27 v2(90.9,85.93) ; J48.B2 v2(16.92,104.44) ; J54.B23 v2(83.95,21.92) ; U3.E25 v2(88.9,92.93) ; v2(77.6,19.38) J54.D19 v2(77.6,18.11) ; J54.J35 v2(99.19,13.03) ; U3.F15 v2(77.9,91.93) ; J48.J38 v2(6.76,57.45) ; J54.A1 v2(54.74,23.19) ; U3.C2 v2(64.9,94.93) ; U3.F17 v2(79.9,91.93) ; R415.2 v4(137.52,79.11) ; J48.K30 v2(5.49,67.61) ; J54.A13 v2(69.98,23.19) ; J48.B19 v2(16.92,82.85) ; U3.C31 v2(94.9,94.93) ; U3.L2 v2(64.9,86.93) ; J54.A9 v2(64.9,23.19) ; U3.D26 v2(89.9,93.93) ; U3.Y13 v2(75.9,76.93) ; U3.L15 v2(77.9,86.93) ; U3.K5 v2(67.9,87.93) ; 64.26,12.39 v2(63.63,11.76) ; U3.B15 v2(77.9,95.93) ; U3.AH32 v2(95.9,68.93) ; U3.K17 v2(79.9,87.93) ; U3.L20 v2(83.9,86.93) ; U3.AM19 v2(82.9,64.93) ; J48.F18 v2(10.57,84.12) ; v4(97.79,109.13) C719.2 98.77,108.31 v4(98.66,108.19) ; U3.L22 v2(85.9,86.93) ; J54.G40 v2(105.54,14.3) ; J48.C29 v2(15.65,68.88) ; J48.H21 v2(9.3,80.31) ; U3.D32 v2(95.9,93.93) ; v2(9.3,103.17) 8.66,102.54 v2(9.3,101.9) ; 13.74,102.54 v2(14.38,103.17) ; U3.M22 v2(85.9,85.93) ; U3.P27 v2(90.9,83.93) ; U3.D23 v2(86.9,93.93) ; J54.K21 v2(81.41,10.49) ; J54.C21 v2(80.14,20.65) ; J48.G14 v2(10.57,87.93) ; SW8.1 v4(139.95,55.07) ; v2(8.03,100.63) J48.J4 v2(6.76,101.9) ; R234.2 v4(153.29,136.93) ; U3.C28 v2(91.9,94.93) ; J54.G32 v2(94.11,15.57) ; v4(14.1,137.11) C18.1 ; R424.2 v4(151.07,88.66) ; v2(95.9,74.93) 95.9,74.93 U3.AC32 ; R671.1 v4(119.63,15.41) ; U3.A16 v2(78.9,96.93) ; J54.E26 v2(87.76,16.84) ; J54.B11 v2(67.44,21.92) ; U3.A19 v2(82.9,96.93) ; U3.C13 v2(75.9,94.93) ; U3.E4 v2(66.9,92.93) ; U3.J13 v2(75.9,88.93) ; v4(61.47,136.83) 61.76,136.54 SW5.3 ; J48.A12 v2(18.19,91.74) ; U3.B32 v2(95.9,95.93) ; U3.C16 v2(78.9,94.93) ; U3.D31 v2(94.9,93.93) ; J48.E1 v2(13.11,105.71) ; U3.K10 v2(72.9,87.93) ; J54.C38 v2(103,20.65) ; SW1.3 v4(47.79,136.79) ; U3.F20 v2(83.9,91.93) ; U3.F31 v2(94.9,91.93) ; U3.F21 v2(84.9,91.93) ; J54.G38 v2(101.73,15.57) ; R672.1 v4(123.82,15.41) ; J54.A17 v2(75.06,23.19) ; R440.2 v4(139.32,111.6) ; J48.G26 v2(10.57,72.69) ; J48.A25 v2(18.19,73.96) ; U3.A3 v2(65.9,96.93) ; J54.C36 v2(100.46,20.65) ; U3.F4 v2(66.9,91.93) ; R673.1 v1(132.21,15.41) ; U3.N33 v2(96.9,84.93) ; U3.AA6 v2(68.9,75.93) ; J54.C9 v2(64.9,20.65) ; 74.42,20.01 v2(73.79,20.65) ; J54.C33 v2(96.65,20.65) ; U3.H18 v2(81.9,89.93) ; U3.K19 v2(82.9,87.93) ; J54.J11 v2(67.44,11.76) ; 61.72,13.66 v2(61.09,13.03) J54.J5 ; J48.B34 v2(16.92,62.53) ; v2(58.55,16.84) 59.18,17.47 v2(58.55,18.11) ; U3.E31 v2(94.9,92.93) ; U3.F27 v2(90.9,91.93) ; U3.C7 v2(69.9,94.93) ; J48.A1 v2(18.19,105.71) ; U3.H19 v2(82.9,89.93) ; J48.D6 v2(14.38,99.36) ; U3.N3 v2(65.9,84.93) ; C673.2 v4(123.01,47.06) ; J54.G17 v2(76.33,14.3) ; U3.N32 v2(95.9,84.93) ; J54.B3 v2(57.28,21.92) ; 61.72,18.74 v2(61.09,19.38) ; J48.G8 v2(10.57,96.82) ; J48.G38 v2(9.3,57.45) ; J48.G29 v2(10.57,68.88) ; J54.A21 v2(81.41,23.19) ; J48.C33 v2(15.65,63.8) ; U3.B7 v2(69.9,95.93) ; U3.A31 v2(94.9,96.93) ; U3.D30 v2(93.9,93.93) ; U3.M17 v2(79.9,85.93) ; U3.E28 v2(91.9,92.93) ; R442.2 v4(136.86,106.44) ; U3.N30 v2(93.9,84.93) ; U3.T4 v2(66.9,81.93) ; J54.G35 v2(99.19,15.57) ; J54.G23 v2(82.68,15.57) ; v2(85.22,19.38) J54.D25 v2(86.49,19.38) ; J54.B27 v2(89.03,21.92) ; U3.F22 v2(85.9,91.93) ; J48.J1 v2(6.76,105.71) ; U3.F23 v2(86.9,91.93) ; 59.18,22.55 v2(58.55,23.19) ; R429.2 v4(139.32,97.35) ; U3.K1 v2(63.9,87.93) ; U3.G22 v2(85.9,90.93) ; U3.B2 v2(64.9,95.93) ; U3.D12 v2(74.9,93.93) ; J48.C1 v2(15.65,105.71) ; U3.L16 v2(78.9,86.93) ; R451.2 v4(151.51,116.6) ; U3.P17 v2(79.9,83.93) ; U3.C22 v2(85.9,94.93) ; 7.39,65.71 v2(8.03,65.07) ; U3.G1 v2(63.9,90.93) ; v4(4.02,127.29) J2.8 2.25,127.29 ; v2(76.33,18.11) J54.E17 v2(75.06,18.11) ; U3.W3 v2(65.9,77.93) ; U3.G19 v2(82.9,90.93) ; U3.L17 v2(79.9,86.93) ; J48.D19 v2(14.38,81.58) ; 92.2,21.28 v2(92.84,21.92) ; U3.L24 v2(87.9,86.93) ; J54.H18 v2(77.6,13.03) ; U3.E19 v2(82.9,92.93) ; U3.J16 v2(78.9,88.93) ; U3.M2 v2(64.9,85.93) ; U3.T30 v2(93.9,81.93) ; U3.K26 v2(89.9,87.93) ; J48.B38 v2(16.92,57.45) ; U3.J17 v2(79.9,88.93) ; 64.26,14.93 v2(64.9,14.3) ; U3.H13 v2(75.9,89.93) ; J54.A40 v2(105.54,23.19) ; U3.F6 v2(68.9,91.93) ; J54.F21 v2(81.41,16.84) ; J54.C40 v2(105.54,20.65) ; R413.2 v4(139.99,84.27) ; J48.F39 v2(10.57,57.45) ; J54.E5 v2(59.82,18.11) ; U3.F7 v2(69.9,91.93) ; U3.P23 v2(86.9,83.93) ; U3.H28 v2(91.9,89.93) ; U3.L29 v2(92.9,86.93) ; U3.N29 v2(92.9,84.93) ; J48.K36 v2(5.49,59.99) ; U3.D24 v2(87.9,93.93) ; U3.P26 v2(89.9,83.93) ; J48.E20 v2(13.11,81.58) ; U3.J10 v2(72.9,88.93) ; v2(64.9,13.03) J54.H9 v2(66.17,13.03) ; U3.B11 v2(73.9,95.93) ; 79.5,22.55 v2(78.87,23.19) ; U3.A25 v2(88.9,96.93) ; U3.AF8 v2(70.9,70.93) ; U3.K28 v2(91.9,87.93) ; U3.D28 v2(91.9,93.93) ; U3.M31 v2(94.9,85.93) ; J54.K15 v2(72.52,10.49) ; U3.H10 v2(72.9,89.93) ; U3.C34 v2(97.9,94.93) ; U3.AC18 v2(81.9,73.93) ; U3.N9 v2(71.9,84.93) ; J48.B10 v2(16.92,94.28) ; J54.E29 v2(91.57,18.11) ; J54.B39 v2(103,21.92) ; U3.D3 v2(65.9,93.93) ; J48.B27 v2(16.92,71.42) ; U3.N13 v2(75.9,84.93) ; R466.1 v4(127.44,36.11) ; U3.H33 v2(96.9,89.93) ; J48.J14 v2(6.76,89.2) ; J48.F21 v2(10.57,79.04) ; J48.C36 v2(15.65,59.99) ; 9.93,84.76 v2(10.57,85.39) ; SW1.1 v4(47.79,128.79) ; U3.AB23 v2(86.9,74.93) ; U3.J4 v2(66.9,88.93) ; U3.B23 v2(86.9,95.93) ; U3.H34 v2(97.9,89.93) ; U3.G28 v2(91.9,90.93) ; J54.J23 v2(83.95,11.76) ; U3.D13 v2(75.9,93.93)
  TOP w0.508: SW3.14 v4(57.67,43.8) ; 61.41,98.22 C69.2 60.25,98.22 ; SW3.11 v4(53.86,43.8) ; SW3.12 v4(55.13,43.8) ; R5.2 v4(12.53,121.75) ; SW3.15 v4(58.94,43.8) ; U4.4 v4(49.69,119.7) ; SW3.9 v4(51.32,43.8) ; R554.1 v4(164.05,72.69) ; SW3.16 v4(60.21,43.8) ; R545.2 v4(98.01,107.22) ; SW3.13 v4(56.4,43.8) ; SW3.10 v4(52.59,43.8)
  L02-GND w0.229: 132.16,77.52 133.1,77.52 ; 133.1,77.52 134.03,77.52 ; 133.1,77.52 133.1,78.45 ; 133.1,77.52 133.1,76.58 ; 45.47,113.54 J3.14 ; J3.14 44.53,114.47 ; J3.14 45.47,115.41 ; J3.14 46.4,114.47 ; 11.81,125.73 JP3.2 ; JP3.2 13.68,125.73 ; JP3.2 12.75,126.67 ; JP3.2 12.75,124.8 ; JP26.34 17.11,145.05 ; JP26.34 16.17,144.11 ; JP26.34 15.24,145.05 ; JP26.34 16.17,145.98 ; 45.72,147.59 JP26.9 ; JP26.9 46.65,146.65 ; JP26.9 47.59,147.59 ; JP26.9 46.65,148.52 ; JP26.30 22.19,145.05 ; JP26.30 21.25,144.11 ; JP26.30 20.32,145.05 ; JP26.30 21.25,145.98 ; J10.12 46.92,65.68 ; J10.12 45.98,64.74 ; J10.12 45.98,66.61 ; J10.12 45.05,65.68 ; JP26.25 26.33,148.52 ; JP26.25 26.33,146.65 ; JP26.25 27.27,147.59 ; JP26.25 25.4,147.59 ; J53.12 99.92,49.48 ; J53.12 98.99,48.54 ; J53.12 99.92,47.61 ; J53.12 100.85,48.54 ; J6.5 130.09,138.09 ; J6.5 131.02,137.16 ; J6.5 130.09,136.23 ; J6.5 129.15,137.16 ; 60.71,100.21 JP15.1 ; JP15.1 59.77,101.14 ; JP15.1 60.71,102.07 ; JP15.1 61.64,101.14 ; J7.5 107.23,138.09 ; J7.5 106.29,137.16 ; J7.5 108.16,137.16 ; J7.5 107.23,136.23 ; J7.11 107.23,140.63 ; J7.11 106.29,139.7 ; J7.11 107.23,138.77 ; J7.11 108.16,139.7 ; 40.64,145.05 JP26.14 ; JP26.14 42.51,145.05 ; JP26.14 41.57,145.98 ; JP26.14 41.57,144.11 ; JP64.2 57.03,36.76 ; JP64.2 56.09,37.69 ; JP64.2 56.09,35.83 ; JP64.2 55.16,36.76 ; J53.11 102.46,49.48 ; J53.11 103.39,48.54 ; J53.11 102.46,47.61 ; J53.11 101.53,48.54 ; JP26.39 9.49,147.59 ; JP26.39 8.55,146.65 ; JP26.39 7.62,147.59 ; JP26.39 8.55,148.52 ; 45.05,63.14 J10.11 ; J10.11 46.92,63.14 ; J10.11 45.98,62.2 ; J10.11 45.98,64.07 ; 129.15,139.7 J6.11 ; J6.11 131.02,139.7 ; J6.11 130.09,140.63 ; J6.11 130.09,138.77 ; J1.7 18.37,119.31 ; J1.7 17.43,118.37 ; J1.7 16.5,119.31 ; J1.7 17.43,120.24 ; 45.47,116.08 J3.13 ; J3.13 44.53,117.01 ; J3.13 46.4,117.01 ; J3.13 45.47,117.95 ; JP17.2 45.59,141.32 ; JP17.2 44.66,140.38 ; JP17.2 46.53,140.38 ; JP17.2 45.59,139.45 ; JP26.20 34.89,145.05 ; JP26.20 33.95,145.98 ; JP26.20 33.95,144.11 ; JP26.20 33.02,145.05 ; 51.73,144.11 JP26.6 ; JP26.6 52.67,145.05 ; JP26.6 51.73,145.98 ; JP26.6 50.8,145.05
  L02-GND w0.356: 162.55,22.82 J25.G4 ; J25.G4 163.52,22.15 ; J25.G4 163.52,23.5 ; J8.3 161.68,97.3 ; J8.3 162.61,96.36 ; J8.3 160.74,96.36 ; J8.3 161.68,95.43 ; J25.G2 157.57,23.14 ; J25.G2 157.57,21.79 ; J25.G2 158.54,22.47 ; J25.G1 158.54,14.2 ; J25.G1 157.57,14.88 ; J25.G1 157.57,13.53 ; J25.G1 156.6,14.2 ; J83.13 136.27,8.09 ; J83.13 136.27,6.23 ; J83.13 137.2,7.16 ; J83.13 135.34,7.16 ; J25.G3 163.52,14.52 ; J25.G3 162.55,13.85 ; J25.G3 163.52,13.17
  L02-GND w0.483: 157.2,53.49 J50.2 ; J50.2 157.2,57.34 ; J50.2 158.03,55.41 ; J50.2 156.37,55.41 ; 152.47,60.21 J50.3 ; J50.3 154.4,59.39 ; J50.3 156.33,60.21 ; J50.3 154.4,61.04
  L04-GND w0.229: 11.81,125.73 JP3.2 ; JP3.2 12.75,126.67 ; JP3.2 13.68,125.73 ; JP3.2 12.75,124.8 ; 101.53,48.54 J53.11 ; J53.11 103.39,48.54 ; J53.11 102.46,49.48 ; J53.11 102.46,47.61 ; JP26.9 46.65,148.52 ; JP26.9 45.72,147.59 ; JP26.9 47.59,147.59 ; JP26.9 46.65,146.65 ; 98.99,48.54 J53.12 ; J53.12 100.85,48.54 ; J53.12 99.92,47.61 ; J53.12 99.92,49.48 ; JP15.1 61.64,101.14 ; JP15.1 60.71,102.07 ; JP15.1 59.77,101.14 ; JP15.1 60.71,100.21 ; J3.14 46.4,114.47 ; J3.14 44.53,114.47 ; J3.14 45.47,115.41 ; J3.14 45.47,113.54 ; JP26.25 26.33,148.52 ; JP26.25 27.27,147.59 ; JP26.25 26.33,146.65 ; JP26.25 25.4,147.59 ; 106.29,139.7 J7.11 ; J7.11 107.23,138.77 ; J7.11 107.23,140.63 ; J7.11 108.16,139.7 ; 133.1,76.58 133.1,77.52 ; 133.1,77.52 134.03,77.52 ; 133.1,77.52 132.16,77.52 ; 133.1,77.52 133.1,78.45 ; 129.15,137.16 J6.5 ; J6.5 130.09,138.09 ; J6.5 131.02,137.16 ; J6.5 130.09,136.23 ; JP26.20 33.95,145.98 ; JP26.20 34.89,145.05 ; JP26.20 33.02,145.05 ; JP26.20 33.95,144.11 ; 15.24,145.05 JP26.34 ; JP26.34 16.17,145.98 ; JP26.34 16.17,144.11 ; JP26.34 17.11,145.05 ; JP26.6 51.73,145.98 ; JP26.6 51.73,144.11 ; JP26.6 50.8,145.05 ; JP26.6 52.67,145.05 ; J7.5 107.23,138.09 ; J7.5 108.16,137.16 ; J7.5 106.29,137.16 ; J7.5 107.23,136.23 ; 55.16,36.76 JP64.2 ; JP64.2 56.09,37.69 ; JP64.2 57.03,36.76 ; JP64.2 56.09,35.83 ; 44.66,140.38 JP17.2 ; JP17.2 45.59,141.32 ; JP17.2 45.59,139.45 ; JP17.2 46.53,140.38 ; J1.7 18.37,119.31 ; J1.7 17.43,120.24 ; J1.7 17.43,118.37 ; J1.7 16.5,119.31 ; 40.64,145.05 JP26.14 ; JP26.14 41.57,144.11 ; JP26.14 42.51,145.05 ; JP26.14 41.57,145.98 ; 130.09,138.77 J6.11 ; J6.11 130.09,140.63 ; J6.11 131.02,139.7 ; J6.11 129.15,139.7 ; JP26.30 21.25,145.98 ; JP26.30 21.25,144.11 ; JP26.30 20.32,145.05 ; JP26.30 22.19,145.05 ; J3.13 45.47,117.95 ; J3.13 44.53,117.01 ; J3.13 45.47,116.08 ; J3.13 46.4,117.01 ; J10.11 46.92,63.14 ; J10.11 45.98,62.2 ; J10.11 45.05,63.14 ; J10.11 45.98,64.07 ; 7.62,147.59 JP26.39 ; JP26.39 8.55,146.65 ; JP26.39 9.49,147.59 ; JP26.39 8.55,148.52 ; J10.12 46.92,65.68 ; J10.12 45.98,66.61 ; J10.12 45.98,64.74 ; J10.12 45.05,65.68
  L04-GND w0.356: 135.34,7.16 J83.13 ; J83.13 136.27,6.23 ; J83.13 137.2,7.16 ; J83.13 136.27,8.09 ; 162.55,22.82 J25.G4 ; J25.G4 163.52,23.5 ; J25.G4 163.52,22.15 ; 161.68,95.43 J8.3 ; J8.3 160.74,96.36 ; J8.3 161.68,97.3 ; J8.3 162.61,96.36 ; J25.G3 163.52,14.52 ; J25.G3 163.52,13.17 ; J25.G3 162.55,13.85 ; J25.G2 157.57,23.14 ; J25.G2 157.57,21.79 ; J25.G2 158.54,22.47 ; 156.6,14.2 J25.G1 ; J25.G1 158.54,14.2 ; J25.G1 157.57,13.53 ; J25.G1 157.57,14.88
  L04-GND w0.483: J50.2 158.03,55.41 ; J50.2 157.2,53.49 ; J50.2 157.2,57.34 ; J50.2 156.37,55.41 ; 152.47,60.21 J50.3 ; J50.3 156.33,60.21 ; J50.3 154.4,59.39 ; J50.3 154.4,61.04
  L05-SIG2 w0.218: J1.7 18.37,119.31 ; J1.7 17.43,120.24 ; J1.7 17.43,118.37 ; J1.7 16.5,119.31 ; 12.75,124.8 JP3.2 ; JP3.2 13.68,125.73 ; JP3.2 11.81,125.73 ; JP3.2 12.75,126.67
  L06-GND w0.229: 98.99,48.54 J53.12 ; J53.12 99.92,47.61 ; J53.12 99.92,49.48 ; J53.12 100.85,48.54 ; 129.15,137.16 J6.5 ; J6.5 131.02,137.16 ; J6.5 130.09,136.23 ; J6.5 130.09,138.09 ; 45.47,113.54 J3.14 ; J3.14 45.47,115.41 ; J3.14 44.53,114.47 ; J3.14 46.4,114.47 ; JP26.30 22.19,145.05 ; JP26.30 21.25,144.11 ; JP26.30 20.32,145.05 ; JP26.30 21.25,145.98 ; JP26.20 34.89,145.05 ; JP26.20 33.02,145.05 ; JP26.20 33.95,145.98 ; JP26.20 33.95,144.11 ; JP64.2 56.09,37.69 ; JP64.2 56.09,35.83 ; JP64.2 57.03,36.76 ; JP64.2 55.16,36.76 ; 40.64,145.05 JP26.14 ; JP26.14 41.57,145.98 ; JP26.14 41.57,144.11 ; JP26.14 42.51,145.05 ; 45.98,64.74 J10.12 ; J10.12 45.98,66.61 ; J10.12 46.92,65.68 ; J10.12 45.05,65.68 ; 102.46,47.61 J53.11 ; J53.11 102.46,49.48 ; J53.11 103.39,48.54 ; J53.11 101.53,48.54 ; 7.62,147.59 JP26.39 ; JP26.39 8.55,148.52 ; JP26.39 9.49,147.59 ; JP26.39 8.55,146.65 ; J3.13 46.4,117.01 ; J3.13 45.47,117.95 ; J3.13 44.53,117.01 ; J3.13 45.47,116.08 ; 60.71,100.21 JP15.1 ; JP15.1 61.64,101.14 ; JP15.1 59.77,101.14 ; JP15.1 60.71,102.07 ; 51.73,144.11 JP26.6 ; JP26.6 52.67,145.05 ; JP26.6 51.73,145.98 ; JP26.6 50.8,145.05 ; 107.23,138.77 J7.11 ; J7.11 106.29,139.7 ; J7.11 107.23,140.63 ; J7.11 108.16,139.7 ; JP17.2 46.53,140.38 ; JP17.2 45.59,139.45 ; JP17.2 45.59,141.32 ; JP17.2 44.66,140.38 ; 132.16,77.52 133.1,77.52 ; 133.1,77.52 133.1,76.58 ; 133.1,77.52 134.03,77.52 ; 133.1,77.52 133.1,78.45 ; J7.5 108.16,137.16 ; J7.5 107.23,136.23 ; J7.5 107.23,138.09 ; J7.5 106.29,137.16 ; 17.43,118.37 J1.7 ; J1.7 16.5,119.31 ; J1.7 18.37,119.31 ; J1.7 17.43,120.24 ; 130.09,138.77 J6.11 ; J6.11 131.02,139.7 ; J6.11 130.09,140.63 ; J6.11 129.15,139.7 ; 45.98,62.2 J10.11 ; J10.11 45.05,63.14 ; J10.11 46.92,63.14 ; J10.11 45.98,64.07 ; JP26.25 27.27,147.59 ; JP26.25 26.33,146.65 ; JP26.25 25.4,147.59 ; JP26.25 26.33,148.52 ; JP26.9 47.59,147.59 ; JP26.9 46.65,148.52 ; JP26.9 46.65,146.65 ; JP26.9 45.72,147.59 ; 15.24,145.05 JP26.34 ; JP26.34 16.17,144.11 ; JP26.34 17.11,145.05 ; JP26.34 16.17,145.98 ; JP3.2 12.75,126.67 ; JP3.2 12.75,124.8 ; JP3.2 11.81,125.73 ; JP3.2 13.68,125.73
  L06-GND w0.356: J25.G4 163.52,23.5 ; J25.G4 162.55,22.82 ; J25.G4 163.52,22.15 ; 136.27,6.23 J83.13 ; J83.13 135.34,7.16 ; J83.13 137.2,7.16 ; J83.13 136.27,8.09 ; 160.74,96.36 J8.3 ; J8.3 161.68,95.43 ; J8.3 162.61,96.36 ; J8.3 161.68,97.3 ; J25.G2 157.57,23.14 ; J25.G2 158.54,22.47 ; J25.G2 157.57,21.79 ; 162.55,13.85 J25.G3 ; J25.G3 163.52,14.52 ; J25.G3 163.52,13.17 ; J25.G1 157.57,14.88 ; J25.G1 158.54,14.2 ; J25.G1 156.6,14.2 ; J25.G1 157.57,13.53
  L06-GND w0.483: J50.2 157.2,57.34 ; J50.2 157.2,53.49 ; J50.2 158.03,55.41 ; J50.2 156.37,55.41 ; 154.4,59.39 J50.3 ; J50.3 154.4,61.04 ; J50.3 156.33,60.21 ; J50.3 152.47,60.21
  L07_POW1 w0.229: JP26.34 17.11,145.05 ; JP26.34 16.17,144.11 ; JP26.34 16.17,145.98 ; JP26.34 15.24,145.05 ; 8.55,146.65 JP26.39 ; JP26.39 7.62,147.59 ; JP26.39 8.55,148.52 ; JP26.39 9.49,147.59 ; JP3.2 12.75,126.67 ; JP3.2 13.68,125.73 ; JP3.2 12.75,124.8 ; JP3.2 11.81,125.73 ; JP26.25 26.33,148.52 ; JP26.25 27.27,147.59 ; JP26.25 25.4,147.59 ; JP26.25 26.33,146.65 ; JP26.30 21.25,145.98 ; JP26.30 21.25,144.11 ; JP26.30 22.19,145.05 ; JP26.30 20.32,145.05 ; JP15.1 60.71,102.07 ; JP15.1 60.71,100.21 ; JP15.1 59.77,101.14
  L08-POW2 w0.356: J83.13 136.27,8.09 ; J83.13 136.27,6.23 ; J83.13 137.2,7.16 ; J83.13 135.34,7.16 ; 162.55,13.85 J25.G3 ; J25.G3 163.52,13.17 ; J25.G3 163.52,14.52 ; J25.G1 158.54,14.2 ; J25.G1 156.6,14.2 ; J25.G1 157.57,14.88 ; J25.G1 157.57,13.53
  L09-GND w0.229: 12.75,124.8 JP3.2 ; JP3.2 11.81,125.73 ; JP3.2 13.68,125.73 ; JP3.2 12.75,126.67 ; J1.7 18.37,119.31 ; J1.7 17.43,120.24 ; J1.7 17.43,118.37 ; J1.7 16.5,119.31 ; 130.09,136.23 J6.5 ; J6.5 131.02,137.16 ; J6.5 129.15,137.16 ; J6.5 130.09,138.09 ; JP26.9 47.59,147.59 ; JP26.9 46.65,148.52 ; JP26.9 45.72,147.59 ; JP26.9 46.65,146.65 ; 106.29,137.16 J7.5 ; J7.5 107.23,136.23 ; J7.5 107.23,138.09 ; J7.5 108.16,137.16 ; 8.55,146.65 JP26.39 ; JP26.39 8.55,148.52 ; JP26.39 9.49,147.59 ; JP26.39 7.62,147.59 ; 98.99,48.54 J53.12 ; J53.12 100.85,48.54 ; J53.12 99.92,47.61 ; J53.12 99.92,49.48 ; 25.4,147.59 JP26.25 ; JP26.25 26.33,148.52 ; JP26.25 26.33,146.65 ; JP26.25 27.27,147.59 ; JP15.1 60.71,102.07 ; JP15.1 59.77,101.14 ; JP15.1 61.64,101.14 ; JP15.1 60.71,100.21 ; 45.59,139.45 JP17.2 ; JP17.2 46.53,140.38 ; JP17.2 45.59,141.32 ; JP17.2 44.66,140.38 ; 21.25,144.11 JP26.30 ; JP26.30 20.32,145.05 ; JP26.30 21.25,145.98 ; JP26.30 22.19,145.05 ; J10.11 46.92,63.14 ; J10.11 45.98,62.2 ; J10.11 45.98,64.07 ; J10.11 45.05,63.14 ; JP26.6 51.73,145.98 ; JP26.6 50.8,145.05 ; JP26.6 51.73,144.11 ; JP26.6 52.67,145.05 ; J3.13 46.4,117.01 ; J3.13 45.47,116.08 ; J3.13 45.47,117.95 ; J3.13 44.53,117.01 ; 133.1,77.52 134.03,77.52 ; 133.1,77.52 133.1,76.58 ; 133.1,77.52 133.1,78.45 ; 133.1,77.52 132.16,77.52 ; JP26.34 16.17,145.98 ; JP26.34 15.24,145.05 ; JP26.34 17.11,145.05 ; JP26.34 16.17,144.11 ; 33.02,145.05 JP26.20 ; JP26.20 34.89,145.05 ; JP26.20 33.95,144.11 ; JP26.20 33.95,145.98 ; J6.11 131.02,139.7 ; J6.11 130.09,140.63 ; J6.11 130.09,138.77 ; J6.11 129.15,139.7 ; 107.23,138.77 J7.11 ; J7.11 106.29,139.7 ; J7.11 107.23,140.63 ; J7.11 108.16,139.7 ; J10.12 45.98,66.61 ; J10.12 46.92,65.68 ; J10.12 45.05,65.68 ; J10.12 45.98,64.74 ; 44.53,114.47 J3.14 ; J3.14 45.47,115.41 ; J3.14 45.47,113.54 ; J3.14 46.4,114.47 ; JP26.14 41.57,145.98 ; JP26.14 41.57,144.11 ; JP26.14 42.51,145.05 ; JP26.14 40.64,145.05 ; 102.46,47.61 J53.11 ; J53.11 102.46,49.48 ; J53.11 101.53,48.54 ; J53.11 103.39,48.54 ; JP64.2 57.03,36.76 ; JP64.2 56.09,37.69 ; JP64.2 56.09,35.83 ; JP64.2 55.16,36.76
  L09-GND w0.356: J25.G2 158.54,22.47 ; J25.G2 157.57,23.14 ; J25.G2 157.57,21.79 ; J8.3 161.68,97.3 ; J8.3 160.74,96.36 ; J8.3 162.61,96.36 ; J8.3 161.68,95.43 ; J25.G4 163.52,23.5 ; J25.G4 162.55,22.82 ; J25.G4 163.52,22.15 ; 162.55,13.85 J25.G3 ; J25.G3 163.52,13.17 ; J25.G3 163.52,14.52 ; 156.6,14.2 J25.G1 ; J25.G1 158.54,14.2 ; J25.G1 157.57,13.53 ; J25.G1 157.57,14.88 ; J83.13 137.2,7.16 ; J83.13 135.34,7.16 ; J83.13 136.27,8.09 ; J83.13 136.27,6.23
  L09-GND w0.483: J50.2 158.03,55.41 ; J50.2 157.2,57.34 ; J50.2 157.2,53.49 ; J50.2 156.37,55.41 ; 152.47,60.21 J50.3 ; J50.3 156.33,60.21 ; J50.3 154.4,59.39 ; J50.3 154.4,61.04
  L10-SIG3 w0.218: 41.57,144.11 JP26.14 ; JP26.14 40.64,145.05 ; JP26.14 41.57,145.98 ; JP26.14 42.51,145.05 ; JP26.34 16.17,145.98 ; JP26.34 15.24,145.05 ; JP26.34 16.17,144.11 ; JP26.34 17.11,145.05 ; JP26.6 51.73,145.98 ; JP26.6 52.67,145.05 ; JP26.6 51.73,144.11 ; JP26.6 50.8,145.05 ; 26.33,146.65 JP26.25 ; JP26.25 25.4,147.59 ; JP26.25 27.27,147.59 ; JP26.25 26.33,148.52 ; JP26.20 33.95,145.98 ; JP26.20 34.89,145.05 ; JP26.20 33.02,145.05 ; JP26.20 33.95,144.11 ; 8.55,146.65 JP26.39 ; JP26.39 8.55,148.52 ; JP26.39 7.62,147.59 ; JP26.39 9.49,147.59 ; JP3.2 12.75,126.67 ; JP3.2 11.81,125.73 ; JP3.2 13.68,125.73 ; JP3.2 12.75,124.8 ; 44.66,140.38 JP17.2 ; JP17.2 46.53,140.38 ; JP17.2 45.59,141.32 ; JP17.2 45.59,139.45 ; 21.25,144.11 JP26.30 ; JP26.30 22.19,145.05 ; JP26.30 21.25,145.98 ; JP26.30 20.32,145.05 ; JP26.9 46.65,148.52 ; JP26.9 47.59,147.59 ; JP26.9 45.72,147.59 ; JP26.9 46.65,146.65
  L11-GND w0.229: 16.5,119.31 J1.7 ; J1.7 17.43,120.24 ; J1.7 17.43,118.37 ; J1.7 18.37,119.31 ; J7.11 107.23,140.63 ; J7.11 108.16,139.7 ; J7.11 107.23,138.77 ; J7.11 106.29,139.7 ; JP26.34 16.17,145.98 ; JP26.34 15.24,145.05 ; JP26.34 16.17,144.11 ; JP26.34 17.11,145.05 ; 130.09,138.77 J6.11 ; J6.11 130.09,140.63 ; J6.11 129.15,139.7 ; J6.11 131.02,139.7 ; JP26.25 27.27,147.59 ; JP26.25 26.33,146.65 ; JP26.25 26.33,148.52 ; JP26.25 25.4,147.59 ; 50.8,145.05 JP26.6 ; JP26.6 51.73,144.11 ; JP26.6 51.73,145.98 ; JP26.6 52.67,145.05 ; 133.1,77.52 134.03,77.52 ; 133.1,77.52 133.1,78.45 ; 133.1,77.52 132.16,77.52 ; 133.1,77.52 133.1,76.58 ; J6.5 130.09,138.09 ; J6.5 130.09,136.23 ; J6.5 129.15,137.16 ; J6.5 131.02,137.16 ; 98.99,48.54 J53.12 ; J53.12 100.85,48.54 ; J53.12 99.92,49.48 ; J53.12 99.92,47.61 ; JP26.14 42.51,145.05 ; JP26.14 41.57,144.11 ; JP26.14 40.64,145.05 ; JP26.14 41.57,145.98 ; 44.53,114.47 J3.14 ; J3.14 46.4,114.47 ; J3.14 45.47,113.54 ; J3.14 45.47,115.41 ; 21.25,144.11 JP26.30 ; JP26.30 22.19,145.05 ; JP26.30 20.32,145.05 ; JP26.30 21.25,145.98 ; JP26.39 8.55,148.52 ; JP26.39 9.49,147.59 ; JP26.39 8.55,146.65 ; JP26.39 7.62,147.59 ; JP15.1 61.64,101.14 ; JP15.1 60.71,102.07 ; JP15.1 60.71,100.21 ; JP15.1 59.77,101.14 ; JP17.2 46.53,140.38 ; JP17.2 45.59,141.32 ; JP17.2 44.66,140.38 ; JP17.2 45.59,139.45 ; J7.5 107.23,138.09 ; J7.5 106.29,137.16 ; J7.5 108.16,137.16 ; J7.5 107.23,136.23 ; J3.13 46.4,117.01 ; J3.13 44.53,117.01 ; J3.13 45.47,117.95 ; J3.13 45.47,116.08 ; 102.46,47.61 J53.11 ; J53.11 101.53,48.54 ; J53.11 102.46,49.48 ; J53.11 103.39,48.54 ; 45.05,63.14 J10.11 ; J10.11 45.98,62.2 ; J10.11 46.92,63.14 ; J10.11 45.98,64.07 ; JP3.2 12.75,126.67 ; JP3.2 13.68,125.73 ; JP3.2 12.75,124.8 ; JP3.2 11.81,125.73 ; JP26.20 33.95,145.98 ; JP26.20 33.02,145.05 ; JP26.20 34.89,145.05 ; JP26.20 33.95,144.11 ; 55.16,36.76 JP64.2 ; JP64.2 57.03,36.76 ; JP64.2 56.09,35.83 ; JP64.2 56.09,37.69 ; 45.72,147.59 JP26.9 ; JP26.9 46.65,148.52 ; JP26.9 46.65,146.65 ; JP26.9 47.59,147.59 ; 45.05,65.68 J10.12 ; J10.12 45.98,64.74 ; J10.12 45.98,66.61 ; J10.12 46.92,65.68
  L11-GND w0.356: J25.G1 158.54,14.2 ; J25.G1 156.6,14.2 ; J25.G1 157.57,14.88 ; J25.G1 157.57,13.53 ; J25.G2 157.57,23.14 ; J25.G2 158.54,22.47 ; J25.G2 157.57,21.79 ; 135.34,7.16 J83.13 ; J83.13 136.27,6.23 ; J83.13 136.27,8.09 ; J83.13 137.2,7.16 ; 162.55,22.82 J25.G4 ; J25.G4 163.52,23.5 ; J25.G4 163.52,22.15 ; J25.G3 163.52,14.52 ; J25.G3 163.52,13.17 ; J25.G3 162.55,13.85 ; J8.3 161.68,97.3 ; J8.3 160.74,96.36 ; J8.3 162.61,96.36 ; J8.3 161.68,95.43
  L11-GND w0.483: 154.4,59.39 J50.3 ; J50.3 152.47,60.21 ; J50.3 154.4,61.04 ; J50.3 156.33,60.21 ; 157.2,53.49 J50.2 ; J50.2 157.2,57.34 ; J50.2 156.37,55.41 ; J50.2 158.03,55.41
  L12-SIG4 w0.218: 8.55,146.65 JP26.39 ; JP26.39 9.49,147.59 ; JP26.39 7.62,147.59 ; JP26.39 8.55,148.52 ; 21.25,144.11 JP26.30 ; JP26.30 22.19,145.05 ; JP26.30 20.32,145.05 ; JP26.30 21.25,145.98 ; JP26.25 27.27,147.59 ; JP26.25 26.33,148.52 ; JP26.25 25.4,147.59 ; JP26.25 26.33,146.65 ; JP26.34 16.17,145.98 ; JP26.34 17.11,145.05 ; JP26.34 15.24,145.05 ; JP26.34 16.17,144.11 ; JP26.6 52.67,145.05 ; JP26.6 50.8,145.05 ; JP26.6 51.73,144.11 ; JP26.6 51.73,145.98 ; JP26.20 34.89,145.05 ; JP26.20 33.95,145.98 ; JP26.20 33.95,144.11 ; JP26.20 33.02,145.05 ; JP26.14 42.51,145.05 ; JP26.14 41.57,145.98 ; JP26.14 40.64,145.05 ; JP26.14 41.57,144.11 ; 46.65,146.65 JP26.9 ; JP26.9 46.65,148.52 ; JP26.9 45.72,147.59 ; JP26.9 47.59,147.59
  L12-SIG4 w0.345: J8.3 162.61,96.36 ; J8.3 161.68,95.43 ; J8.3 161.68,97.3 ; J8.3 160.74,96.36
  L12-SIG4 w0.472: 152.47,60.21 J50.3 ; J50.3 156.33,60.21 ; J50.3 154.4,59.39 ; J50.3 154.4,61.04 ; J50.2 157.2,57.34 ; J50.2 157.2,53.49 ; J50.2 158.03,55.41 ; J50.2 156.37,55.41
  L13-GND w0.229: 45.98,62.2 J10.11 ; J10.11 45.05,63.14 ; J10.11 45.98,64.07 ; J10.11 46.92,63.14 ; 33.02,145.05 JP26.20 ; JP26.20 33.95,144.11 ; JP26.20 34.89,145.05 ; JP26.20 33.95,145.98 ; 60.71,100.21 JP15.1 ; JP15.1 59.77,101.14 ; JP15.1 60.71,102.07 ; JP15.1 61.64,101.14 ; 129.15,139.7 J6.11 ; J6.11 130.09,138.77 ; J6.11 130.09,140.63 ; J6.11 131.02,139.7 ; 98.99,48.54 J53.12 ; J53.12 100.85,48.54 ; J53.12 99.92,47.61 ; J53.12 99.92,49.48 ; 46.65,146.65 JP26.9 ; JP26.9 47.59,147.59 ; JP26.9 45.72,147.59 ; JP26.9 46.65,148.52 ; 45.47,116.08 J3.13 ; J3.13 46.4,117.01 ; J3.13 44.53,117.01 ; J3.13 45.47,117.95 ; JP17.2 46.53,140.38 ; JP17.2 45.59,141.32 ; JP17.2 44.66,140.38 ; JP17.2 45.59,139.45 ; J1.7 18.37,119.31 ; J1.7 17.43,118.37 ; J1.7 17.43,120.24 ; J1.7 16.5,119.31 ; JP26.30 21.25,145.98 ; JP26.30 21.25,144.11 ; JP26.30 22.19,145.05 ; JP26.30 20.32,145.05 ; 40.64,145.05 JP26.14 ; JP26.14 41.57,144.11 ; JP26.14 42.51,145.05 ; JP26.14 41.57,145.98 ; 129.15,137.16 J6.5 ; J6.5 131.02,137.16 ; J6.5 130.09,138.09 ; J6.5 130.09,136.23 ; 45.05,65.68 J10.12 ; J10.12 45.98,64.74 ; J10.12 46.92,65.68 ; J10.12 45.98,66.61 ; JP26.34 17.11,145.05 ; JP26.34 16.17,145.98 ; JP26.34 16.17,144.11 ; JP26.34 15.24,145.05 ; 133.1,77.52 133.1,78.45 ; 133.1,77.52 134.03,77.52 ; 133.1,77.52 132.16,77.52 ; 133.1,77.52 133.1,76.58 ; JP3.2 12.75,126.67 ; JP3.2 13.68,125.73 ; JP3.2 11.81,125.73 ; JP3.2 12.75,124.8 ; 107.23,138.77 J7.11 ; J7.11 108.16,139.7 ; J7.11 106.29,139.7 ; J7.11 107.23,140.63 ; JP26.25 26.33,148.52 ; JP26.25 27.27,147.59 ; JP26.25 26.33,146.65 ; JP26.25 25.4,147.59 ; J3.14 45.47,115.41 ; J3.14 46.4,114.47 ; J3.14 45.47,113.54 ; J3.14 44.53,114.47 ; 107.23,136.23 J7.5 ; J7.5 108.16,137.16 ; J7.5 106.29,137.16 ; J7.5 107.23,138.09 ; J53.11 102.46,49.48 ; J53.11 103.39,48.54 ; J53.11 101.53,48.54 ; J53.11 102.46,47.61 ; 7.62,147.59 JP26.39 ; JP26.39 9.49,147.59 ; JP26.39 8.55,148.52 ; JP26.39 8.55,146.65 ; JP26.6 52.67,145.05 ; JP26.6 51.73,144.11 ; JP26.6 51.73,145.98 ; JP26.6 50.8,145.05 ; 56.09,35.83 JP64.2 ; JP64.2 57.03,36.76 ; JP64.2 55.16,36.76 ; JP64.2 56.09,37.69
  L13-GND w0.356: 157.57,21.79 J25.G2 ; J25.G2 158.54,22.47 ; J25.G2 157.57,23.14 ; 136.27,6.23 J83.13 ; J83.13 137.2,7.16 ; J83.13 136.27,8.09 ; J83.13 135.34,7.16 ; 161.68,95.43 J8.3 ; J8.3 161.68,97.3 ; J8.3 160.74,96.36 ; J8.3 162.61,96.36 ; 162.55,13.85 J25.G3 ; J25.G3 163.52,13.17 ; J25.G3 163.52,14.52 ; J25.G1 158.54,14.2 ; J25.G1 157.57,13.53 ; J25.G1 156.6,14.2 ; J25.G1 157.57,14.88 ; 162.55,22.82 J25.G4 ; J25.G4 163.52,23.5 ; J25.G4 163.52,22.15
  L13-GND w0.483: 157.2,53.49 J50.2 ; J50.2 157.2,57.34 ; J50.2 156.37,55.41 ; J50.2 158.03,55.41 ; 154.4,59.39 J50.3 ; J50.3 152.47,60.21 ; J50.3 156.33,60.21 ; J50.3 154.4,61.04
  BOTTOM w0.127: 98.17,71.04 98.14,71.04 98.08,70.98 97.2,70.98 96.63,71.55 94.74,71.55 94.52,71.77 94.52,73.55 93.5,74.57 93.5,81.3 93.22,81.58 91.25,81.58 v2(90.9,81.93)
  BOTTOM w0.203: v4(12.06,131.39) 11.9,131.56 C8.2
  BOTTOM w0.254: C173.2 76.4,79.43 v2(76.9,79.93) ; C579.2 77.08,68.11 v2(76.9,67.93) ; C14.2 19.38,129.11 v4(19.66,129.39) ; R645.1 v4(117.59,52.87) ; C598.2 74.16,86.19 v2(73.9,85.93) ; v2(79.9,81.93) 79.64,81.67 C530.2 ; C542.2 97.67,62.7 v2(97.9,62.93) 97.86,62.97 C483.2 ; v2(65.9,69.93) 66.16,70.19 C42.2 ; J1.7 17.43,120.24 ; J1.7 17.43,118.37 ; J1.7 18.37,119.31 ; J1.7 16.5,119.31 ; C22.2 v1(44.97,136.95) ; C26.2 59.44,136.58 v1(59.69,136.83) ; v2(81.9,85.93) 81.62,85.65 C32.2 ; C485.2 95.83,68.86 v2(95.9,68.93) 95.64,69.19 C546.2 ; v2(75.9,76.93) 75.57,76.6 C166.2 ; v2(75.9,76.93) 76.19,77.22 C147.2 ; v2(75.9,76.93) 76.19,76.64 C289.2 ; v2(75.9,76.93) 75.57,77.26 C401.2 ; v2(88.9,67.93) 88.66,68.17 C541.2 ; v2(73.9,85.93) 73.53,85.56 C20.2 ; v2(73.9,85.93) 73.55,86.28 C587.2 ; v2(22.73,126.82) 22.61,126.94 C16.2 ; v2(85.9,69.93) 85.6,70.23 C536.2 ; C526.2 79.64,83.67 v2(79.9,83.93) 80.02,84.05 C33.2 ; C398.2 86.62,77.21 v2(86.9,76.93) 87.19,76.64 C290.2 ; C66.2 75.13,64.93 v2(74.9,64.93) 74.83,65 C64.2 ; C580.2 78.16,65.19 v2(77.9,64.93) ; v2(28.19,126.82) 28.08,126.7 C1.2 ; C65.2 79.14,72.17 v2(78.9,71.93) ; C138.1 81.98,80.85 v2(81.9,80.93) 82.16,81.19 C148.2 ; v6(72.9,100.04) 72.92,100.02 C55.2 ; C466.2 118.24,75.23 118.72,75.71 C497.2 ; v6(65.9,101.06) 65.87,101.03 C615.2 ; C586.2 60.42,83.99 v2(60.31,83.88) ; C476.2 85.62,74.21 v2(85.9,73.93) ; C41.2 66.89,101.04 v6(66.9,101.06) ; U109.6 v1(148.34,16.95) ; v2(86.9,61.93) 86.75,61.78 R656.2 ; C291.2 75.57,83.58 75.4,83.75 75.4,84.11 75.7,84.41 C592.2 75.7,84.73 v2(75.9,84.93) 76.1,85.13 C529.2 ; v2(78.9,77.93) 78.62,77.65 C404.2 ; v2(78.9,77.93) 79.24,78.27 C152.2 ; v2(78.9,77.93) 78.62,78.21 C176.2 ; v2(78.9,77.93) 79.18,77.65 C292.2 ; v2(84.9,82.93) 84.48,83.35 C171.2 ; v2(84.9,82.93) 85.21,83.24 C150.2 ; v2(84.9,82.93) 84.59,82.62 C178.2 ; v2(63.9,62.93) 64.22,63.25 C43.2 ; C509.2 95.64,78.19 v2(95.9,77.93) 95.83,77.86 C619.2 ; C510.2 110.33,75.39 v3(110.33,76.04) ; v3(109.03,81.64) 109.16,81.5 C469.2 ; v2(73.9,79.93) 73.64,79.68 C591.2 ; C527.2 77.16,81.19 v2(76.9,80.93) 76.59,81.24 C143.2 ; C589.2 71.67,85.16 v2(71.9,84.93) 72.41,84.42 73.35,84.42 C400.2 ; C167.2 86.55,75.28 v2(86.9,74.93) ; C532.2 65.74,65.93 v2(65.9,65.93) ; C172.2 83.7,79.13 v2(83.9,78.93) ; v3(109.03,67.92) 109.16,67.79 C1225.2 ; v2(82.9,68.93) 82.91,68.94 C544.2 ; C7.2 19.56,131.27 v4(19.68,131.14) ; U46.7 v4(109.1,39.28) ; v4(19.56,133.68) 19.3,133.93 C10.2 ; v3(118.78,84.84) 119.07,85.13 C512.2 ; v2(88.9,72.93) 88.65,73.17 C473.2 ; C480.2 95.64,74.67 v2(95.9,74.93) 96.46,75.49 C488.2 ; C1227.2 117.54,62.26 v3(117.48,62.32) ; C538.2 82.91,64.94 v2(82.9,64.93) ; U109.3 v1(152.39,15.65) ; C1255.2 111.63,61.46 v3(111.63,62.32) ; v2(86.9,79.93) C507.2 ; v3(112.93,71.12) 112.93,71.76 C474.2 ; C1187.2 146.43,13.87 146.69,14.13 v1(146.69,14.91) ; C165.2 84.59,78.24 v2(84.9,77.93) 85.11,78.14 C175.2 ; v2(83.9,80.93) 84.07,80.76 C145.2 ; C1221.2 118.78,80.98 v3(118.78,81.64) ; 12.75,124.8 JP3.2 ; JP3.2 11.81,125.73 ; JP3.2 12.75,126.67 ; JP3.2 13.68,125.73 ; C468.2 88.64,76.67 v2(88.9,76.93) ; v2(68.9,78.93) 69.21,79.24 C596.2 ; R655.2 84.74,61.77 v2(84.9,61.93) ; v2(70.9,70.93) 71.13,71.16 C44.2 ; C15.2 19.56,130 v4(19.68,130.12) ; C2.2 29.33,132.93 v2(29.21,133.05) ; v2(60.52,67.93) 60.52,66.53 60.83,66.22 R654.2 ; v2(75.9,72.93) 76.19,73.22 C56.2 ; v2(66.9,81.93) 67.18,82.21 C584.2 ; R597.1 121.45,79.17 v3(121.38,79.24) ; v3(112.93,84.84) 112.93,85.47 C1223.2 ; U2.5 25.87,129.62 v4(25.65,129.84) ; v2(77.9,85.93) 77.73,85.76 C31.2 ; v2(84.9,81.93) 84.59,81.62 C151.2 ; v2(81.9,78.93) 81.64,78.67 C399.2 ; C19.2 v4(77.83,100.04) ; v6(73.9,100.04) 73.83,99.98 C614.2 ; v2(13.11,68.88) 13.74,68.25 C620.1 ; C618.2 80.97,74.41 C537.2 81.81,73.84 v2(81.9,73.93) 82.16,74.19 C535.2 ; C1190.2 146.37,9.06 v4(145.67,9.06) C1191.2 ; C726.2 152.94,66.57 v3(152.85,66.66) ; v2(91.9,68.93) 91.7,69.13 C548.2 ; C164.2 82.62,77.65 v2(82.9,77.93) 83.18,77.65 C177.2 ; v2(29.21,129.11) 29.46,129.35 C11.2 ; C478.2 91.64,73.19 v2(91.9,72.93) 92.46,72.37 C631.2 ; v3(121.38,83.24) 121.5,83.36 R598.1 ; C531.2 69.08,75.75 v2(68.9,75.93) ; C38.2 73.57,74.6 v2(73.9,74.93) ; C58.2 74.16,69.19 v2(73.9,68.93) ; C142.2 87.1,83.13 v2(86.9,82.93) ; C595.2 65.75,78.08 v2(65.9,77.93) 66.11,78.14 C597.2 ; C1186.2 144.29,13.87 143.89,14.27 v4(143.89,14.91) ; R652.2 61.11,73.42 v2(61.11,73.91) ; v2(67.9,85.93) 68,86.03 C590.2 ; C471.2 118.68,67.82 v3(118.78,67.92) ; C12.2 v2(28.07,136.47) ; C27.2 64.65,136.58 v1(64.77,136.7) ; v2(64.9,74.93) 64.95,74.98 C40.2 ; C174.2 85.96,85.93 v2(85.9,85.93) 85.6,85.63 C144.2 ; v3(116.18,84.84) 116.18,85.01 115.32,85.87 R596.2 ; C57.2 70.38,67.41 v2(70.9,67.93) 71.11,68.14 C533.2 ; C545.2 95.64,66.19 v2(95.9,65.93) 95.83,65.86 C547.2 ; 98.17,71.04 99.47,71.04 104.39,66.12 104.39,63.07 107.73,59.74 137.13,59.74 138.05,60.66 v1(138.05,61.01) ; v2(86.9,85.93) 87.11,85.72 C146.2 ; C13.2 v2(20.57,138.38) ; v2(90.9,63.93) 90.66,64.17 C540.2 ; C600.2 v4(57.52,139.87) ; C588.2 65.05,82.08 v2(64.9,81.93) ; C539.2 85.64,65.19 v2(85.9,64.93) ; C34.2 131.95,55.11 v4(131.92,55.07) ; C594.2 72.65,80.68 v2(72.9,80.93) 73.26,80.56 C593.2 ; v1(51.94,136.83) 51.82,136.71 C21.2 ; C3.2 22.61,125.04 v2(22.73,124.92) ; C1257.2 120.08,71.43 v3(120.08,71.12) ; C39.2 71.11,75.14 v2(70.9,74.93) ; C465.2 91.7,78.13 v2(91.9,77.93) ; C140.1 86.94,81.97 v2(86.9,81.93) 86.75,81.78 C149.2 ; C4.2 v2(27.43,136.47)
  BOTTOM w0.305: Q28.E v4(128.97,147.17) ; C616.2 74.01,74.82 v2(73.9,74.93) ; Q17.E v4(40.01,10.57) ; C466.2 117.54,75.97 v3(117.48,76.04) ; Q23.E v4(15.62,10.57) ; R653.2 61.09,69.64 v2(61.09,70) ; Q27.E v4(134.94,147.17) ; C619.2 R493.1 R548.1 97.48,76.63 C488.2 ; Q16.E v4(44.07,10.57) ; Q21.E v4(23.75,10.57) ; Q22.E v4(19.68,10.57) ; Q18.E v4(35.94,10.57) ; R398.2 v5(69.85,99.48) ; Q19.E v4(31.05,9.57) ; Q20.E v4(27.81,10.57)
  BOTTOM w0.381: v4(19.43,135.97) 19.3,135.84 C9.2 ; v2(86.9,76.93) 87.19,77.22 C397.2 ; R342.2 87.6,142.79 v4(87.62,142.78) ; v4(36.83,59.1) 36.53,59.4 R92.2 ; C722.2 159,75.14 v4(159.99,75.14) ; C207.2 95.5,124.76 v4(96.14,125.4) ; R663.2 v4(121.03,15.41) 121.41,15.79 R614.1 ; Q2.E 77.41,144 v4(77.47,143.94) ; v4(136.86,120.92) 137.22,121.28 137.22,124.21 134.13,127.3 130.69,127.3 v4(130.45,127.06) ; v3(158.44,71.46) 158.17,71.19 C729.2 158.17,70.79 158.16,70.8 C725.2 ; v4(145.11,137.22) 145.35,137.46 148.05,137.46 151.88,133.64 151.88,131.44 v4(151.51,131.08) ; Q33.E v4(106.66,144.46) ; Q30.E v4(122.28,144.46) ; C728.2 160.08,69.83 v3(160.04,69.86) ; v4(69.85,144.63) 69.6,144.38 Q4.E ; Q32.E v4(95.63,145.27) ; v4(39.94,55.94) 39.7,56.18 C50.2 ; R651.2 v4(126.62,15.41) ; R77.2 131.99,74.96 v4(131.72,74.68) ; R625.2 v4(25.78,36.88) ; C45.2 40.51,43.1 v4(41.02,43.61) ; v4(145.11,122.74) 145.35,122.98 148.79,122.98 151.88,119.89 151.88,116.97 v4(151.51,116.6) ; C6.2 v4(13.72,131.14) ; v4(151.18,77.31) 151.54,77.67 151.54,80.6 148.45,83.69 145.01,83.69 v4(144.77,83.45) ; v4(137.52,79.11) 137.89,79.47 137.89,82.4 134.8,85.49 131.36,85.49 v4(131.12,85.25) ; R192.1 v4(97.29,128.58) ; C717.2 v4(118.81,105.15) ; C405.1 v5(113.28,88.75) ; C396.2 v4(102.49,113.73) ; v4(136.86,92.19) 137.22,92.56 137.22,95.48 134.13,98.57 130.69,98.57 v4(130.45,98.33) ; Q29.E v4(111.87,144.46) ; v4(144.67,94.8) 144.91,95.04 148.35,95.04 151.44,91.95 151.44,89.02 v4(151.07,88.66) ; v4(136.86,106.44) 137.41,107 137.41,110.03 134.62,112.82 130.69,112.82 v4(130.45,112.58) ; C724.2 154.6,70.81 C1177.2 154.36,70.75 v3(153.65,71.46) 153.56,71.37 C1178.2 152.42,71.37 v4(152.1,71.04) 152.06,71.01 C61.2 v4(151.26,70.3) ; Q34.E v4(101.71,144.45) ; R670.1 v4(129.41,15.41) ; v4(144.78,10.84) 144.95,11.01 C1185.2 ; v2(79.9,81.93) 80.5,81.33 C612.2 ; R672.1 v4(123.82,15.41) ; R669.1 v1(136.4,15.41) ; R644.1 v4(120.66,57.07) ; v4(66.03,140.01) 66.04,140.03 R344.2 ; v3(160.84,72.26) 160.84,72.28 160.45,72.67 160.24,72.67 C727.2 ; C543.2 v4(87.71,100.1) ; C632.2 103.27,92.57 v5(103.12,92.72) ; C723.2 157.7,69.81 v3(157.65,69.86) ; R180.2 v4(35.98,108.38) ; Q3.E v4(83.17,141.14) ; v4(105.72,94.03) C403.1 C169.1 ; C208.2 v4(96.77,124.13) ; R340.2 v4(72.64,140.64) ; R673.1 v1(132.21,15.41) ; C287.2 v4(118.81,108.96) ; v4(151.51,101.87) 151.88,102.23 151.88,105.16 148.79,108.25 145.35,108.25 v4(145.11,108.01) ; R317.2 v4(104.83,35.94) ; R629.2 v4(40.89,36.88) ; C94.2 v4(160.53,76.7) ; Q31.E v4(117.08,144.45) ; C528.2 v4(75.74,99.41)
  BOTTOM w0.508: C534.2 99.67,58.72 v6(99.69,58.7) ; C1179.2 v4(162.55,65.32) ; v4(60.3,111.43) 60.3,110.88 Q1.E ; Q9.E v4(157.28,106.5) ; v2(11.84,63.8) 12.06,63.57 R251.1 ; C721.2 v4(151.52,66.14) v4(152.28,66.14) ; R252.1 17.15,61.49 v2(16.92,61.26) ; Q13.E v4(158.17,128.63) ; Q24.E v4(158.17,132.18) ; Q14.E v4(158.11,114.44) ; C29.1 v4(158.5,79.76) ; v4(153.72,80.13) 154.03,80.44 C30.1 ; Q8.E v4(158.17,121.53) ; Q7.E v4(158.17,125.08) ; Q15.E v4(157.28,136.74) ; C1180.2 v4(161.8,68.36) ; v6(98.69,58.7) 98.66,58.73 C617.2 ; Q12.E v4(157.28,110.09) ; Q10.E v4(158.17,117.98) ; Q11.E v4(157.28,103.06)
  vias: v1(55.37,34.72) v1(55.37,33.32) v1(102.49,106.88) v1(102.49,106.17) v1(124.78,26.84) v1(124.91,20.49) v1(125.48,30.02) v1(125.48,29.38) v1(125.48,28.75) v1(125.48,28.11) v1(125.6,19.35) v1(125.6,18.72) v1(125.6,18.08) v1(125.6,17.45) v1(126.11,30.02) v1(126.11,29.38) v1(126.11,28.75) v1(126.11,28.11) v1(126.24,19.35) v1(126.24,18.72) v1(126.24,18.08) v1(126.24,17.45) v1(128.91,30.02) v1(128.91,29.38) v1(128.91,28.75) v1(128.91,28.11) v1(128.91,19.35) v1(128.91,18.72) v1(128.91,18.08) v1(128.91,17.45) v1(129.54,30.02) v1(129.54,29.38) v1(129.54,28.75) v1(129.54,28.11) v1(129.54,19.35) v1(129.54,18.72) v1(129.54,18.08) v1(129.54,17.45) v1(139.19,29.89) v1(139.19,29.26) v1(139.19,28.62) v1(139.19,27.99) v1(139.19,19.22) v1(139.19,18.59) v1(139.19,17.95) v1(139.19,17.32) v1(139.83,29.89) v1(139.83,29.26) v1(139.83,28.62) v1(139.83,27.99) v1(139.83,19.22) v1(139.83,18.59) v1(139.83,17.95) v1(139.83,17.32) v1(142.49,29.89) v1(142.49,29.26) v1(142.49,28.62) v1(142.49,27.99) v1(142.62,19.22) v1(142.62,18.59) v1(142.62,17.95) v1(142.62,17.32) v1(143.13,29.89) v1(143.13,29.26) v1(143.13,28.62) v1(143.13,27.99) v1(143.26,19.22) v1(143.26,18.59) v1(143.26,17.95) v1(143.26,17.32) v1(143.82,26.84) v1(143.95,20.49) v1(154.18,18.84) v1(154.18,17.67) v1(156.84,26.97) v1(156.84,26.44) v1(156.84,25.47) v1(156.84,24.94) v1(157.48,26.97) v1(157.48,26.44) v1(157.48,25.47) v1(157.48,24.94) v1(158.88,17.83) v2(30.61,114.35) v2(34.04,108.5) v2(34.29,115.24) v2(59.69,90.67) v2(60.83,90.67) v2(61.09,70.91) v2(63.12,73.91) v2(102.36,86.66) v3(107.73,83.24) v3(107.73,77.64) v3(107.73,69.52) v3(107.73,63.92) v3(109.03,84.84) v3(109.03,79.24) v3(109.03,76.04) v3(109.03,71.12) v3(109.03,65.52) v3(109.03,62.32) v3(109.68,84.04) v3(109.68,82.44) v3(109.68,78.44) v3(109.68,76.84) v3(109.68,70.32) v3(109.68,68.72) v3(109.68,64.72) v3(109.68,63.12) v3(110.33,84.84) v3(110.33,81.64) v3(110.33,79.24) v3(110.33,71.12) v3(110.33,67.92) v3(110.33,65.52) v3(110.33,62.32) v3(111.63,84.84) v3(111.63,83.24) v3(111.63,81.64) v3(111.63,79.24) v3(111.63,77.64) v3(111.63,76.04) v3(111.63,73.71) v3(111.63,69.52) v3(111.63,67.92) v3(111.63,65.52) v3(111.63,63.92) v3(112.6,75.12) v3(112.93,83.24) v3(112.93,77.64) v3(112.93,76.04) v3(112.93,69.52) v3(112.93,63.92) v3(112.93,62.32) v3(113.58,84.04) v3(113.58,82.44) v3(113.58,78.44) v3(113.58,76.84) v3(113.54,74.85) v3(113.58,70.32) v3(113.58,68.72) v3(113.58,64.72) v3(113.58,63.12) v3(114.55,74.85) v3(115.28,72.31) v3(115.53,84.04) v3(115.53,82.44) v3(115.53,78.44) v3(115.53,76.84) v3(115.53,70.32) v3(115.53,68.72) v3(115.53,64.72) v3(115.53,63.12) v3(116.18,83.24) v3(116.18,77.64) v3(116.18,76.04) v3(116.18,71.12) v3(116.18,69.52) v3(116.18,63.92) v3(116.18,62.32) v3(116.83,71.88) v3(117.48,84.84) v3(117.48,83.24) v3(117.48,81.64) v3(117.48,79.24) v3(117.48,77.64) v3(117.48,71.88) v3(117.48,71.12) v3(117.48,69.52) v3(117.48,67.92) v3(117.48,65.52) v3(117.48,63.92) v3(118.78,79.24) v3(118.78,76.04) v3(118.78,71.12) v3(118.78,65.52) v3(118.78,62.32) v3(119.43,84.04) v3(119.43,82.44) v3(119.43,78.44) v3(119.43,76.84) v3(119.43,70.32) v3(119.43,68.72) v3(119.43,64.72) v3(119.43,63.12) v3(120.08,84.84) v3(120.08,81.64) v3(120.08,79.24) v3(120.08,76.04) v3(120.08,67.92) v3(120.08,65.52) v3(120.08,62.32) v3(121.38,81.64) v3(121.38,77.64) v3(121.38,69.52) v3(121.38,67.92) v3(121.38,65.52) v3(121.38,63.92) v3(155.25,67.46) v4(1.27,128.85) v4(1.27,125.81) v4(1.55,134.53) v4(1.65,137.74) v4(2.79,128.85) v4(2.79,125.81) v4(2.92,137.74) v4(3.08,134.53) v4(6.98,134.7) v4(7.11,137.74) v4(7.08,128.82) v4(7.11,125.68) v4(8.38,134.7) v4(8.38,125.68) v4(8.51,137.74) v4(8.6,128.82) v4(17.23,139.15) v4(23.37,23.8) v4(24,24.68) v4(24.77,23.8) v4(25.53,24.68) v4(25.78,35.99) v4(26.16,23.8) v4(26.67,35.99) v4(26.92,24.68) v4(27.56,23.8) v4(28.07,41.07) v4(28.07,39.67) v4(28.07,35.99) v4(28.19,24.68) v4(28.96,35.99) v4(29.08,41.07) v4(29.08,40.31) v4(29.08,39.54) v4(29.08,34.84) v4(29.08,33.45) v4(29.08,32.18) v4(29.84,25.57) v4(29.84,24.56) v4(29.84,23.67) v4(30.1,39.54) v4(30.99,39.54) v4(31.11,25.57) v4(31.11,24.56) v4(31.11,23.67) v4(32.39,25.57) v4(32.39,24.56) v4(32.39,23.67) v4(33.66,25.57) v4(33.66,24.56) v4(33.66,23.67) v4(34.92,25.57) v4(34.92,24.56) v4(34.92,23.67) v4(36.7,25.83) v4(37.46,25.83) v4(38.23,25.83) v4(38.74,51.46) v4(39.76,51.46) v4(39.78,49.55) v4(39.76,48.26) v4(39.76,46.94) v4(39.73,46.1) v4(39.9,54.69) v4(39.88,53.23) v4(39.99,45.08) v4(40.7,49.55) v4(40.67,48.26) v4(40.67,46.94) v4(40.77,51.46) v4(40.75,46.1) v4(40.88,45.08) v4(40.89,35.99) v4(41.59,49.55) v4(41.59,48.26) v4(41.56,46.96) v4(41.79,51.46) v4(41.77,46.1) v4(41.77,45.08) v4(41.78,43.61) v4(41.78,35.99) v4(43.18,39.67) v4(43.18,35.99) v4(44.07,35.99) v4(44.2,40.31) v4(44.2,39.67) v4(44.2,39.04) v4(44.32,33.19) v4(44.32,32.3) v4(44.32,31.67) v4(44.69,51.29) v4(45.21,39.54) v4(45.76,51.27) v4(51.33,124.43) v4(51.33,123.03) v4(51.33,121.64) v4(51.33,120.24) v4(52.73,124.43) v4(52.73,123.03) v4(52.73,121.64) v4(52.73,120.24) v4(54.13,124.43) v4(54.13,123.03) v4(54.13,121.64) v4(54.13,120.24) v4(55.52,124.43) v4(55.52,123.03) v4(55.52,121.64) v4(55.52,120.24) v4(94.11,127.05) v4(95.76,120.95) v4(96.52,128.57) v4(96.77,127.05) v4(96.77,122.09) v4(96.77,120.95) v4(97.41,125.4) v4(99.44,128.57) v4(99.44,127.17) v4(105.16,110.66) v4(105.18,109.93) v4(105.92,110.66) v4(105.92,109.9) v4(108.81,26.36) v4(108.81,25.35) v4(109.82,26.36) v4(109.82,25.35) v4(112.4,34.72) v4(120.52,28.75) v4(126.74,39.57) v4(126.9,43.3) v4(128.07,126.06) v4(128.07,125.04) v4(128.07,111.58) v4(128.07,110.56) v4(128.07,97.33) v4(128.07,96.32) v4(128.32,38.45) v4(128.32,37.36) v4(128.32,36.28) v4(128.87,84.25) v4(128.91,83.23) v4(128.96,126.06) v4(128.96,125.04) v4(128.96,111.58) v4(128.96,110.56) v4(128.96,97.33) v4(128.96,96.32) v4(129.76,84.25) v4(129.75,83.23) v4(129.98,126.06) v4(129.98,125.04) v4(129.98,111.58) v4(129.98,110.56) v4(129.98,97.33) v4(129.98,96.32) v4(130.64,84.25) v4(130.64,83.23) v4(130.96,126.17) v4(130.96,111.7) v4(130.96,97.45) v4(131.63,84.36) v4(131.86,126.63) v4(131.86,112.15) v4(131.86,97.9) v4(132.32,125.68) v4(132.3,111.21) v4(132.32,96.96) v4(132.53,84.82) v4(132.45,45.24) v4(132.91,126.47) v4(132.91,111.99) v4(132.91,97.74) v4(132.99,83.87) v4(133.58,84.66) v4(133.81,45.25) v4(134.5,46.63) v4(135.7,46.6) v4(137.27,47.05) v4(137.29,35.73) v4(137.29,34.84) v4(137.29,33.96) v4(137.29,32.94) v4(138.18,35.73) v4(138.18,34.84) v4(138.18,33.96) v4(138.18,32.94) v4(139.06,35.73) v4(139.06,34.84) v4(139.06,33.96) v4(139.06,32.94) v4(139.78,75.87) v4(140.08,33.96) v4(140.08,32.94) v4(140.97,33.96) v4(140.97,32.94) v4(141.99,33.96) v4(141.99,32.94) v4(142.26,93.79) v4(142.26,92.77) v4(142.39,82.45) v4(142.39,81.43) v4(142.73,136.22) v4(142.73,135.2) v4(142.73,121.74) v4(142.73,120.72) v4(142.73,107.01) v4(142.73,105.99) v4(143.27,93.79) v4(143.27,92.77) v4(143.28,82.45) v4(143.28,81.43) v4(143.4,45.27) v4(143.62,136.22) v4(143.62,135.2) v4(143.62,121.74) v4(143.62,120.72) v4(143.62,107.01) v4(143.62,105.99) v4(143.64,42.46) v4(143.89,10.84) v4(143.89,9.95) v4(143.89,9.06) v4(144.29,93.79) v4(144.29,92.77) v4(144.3,82.45) v4(144.3,81.43) v4(144.63,136.22) v4(144.63,135.2) v4(144.63,121.74) v4(144.63,120.72) v4(144.63,107.01) v4(144.63,105.99) v4(144.78,9.06) v4(145.28,82.56) v4(145.62,136.33) v4(145.62,121.86) v4(145.62,107.12) v4(145.67,10.84) v4(145.67,9.95) v4(145.8,94.28) v4(146.18,83.02) v4(146.52,136.79) v4(146.52,122.31) v4(146.52,107.58) v4(146.64,82.07) v4(146.98,135.84) v4(146.98,121.37) v4(146.98,106.63) v4(146.94,94.28) v4(147.23,82.86) v4(147.57,136.63) v4(147.57,122.15) v4(147.57,107.42) v4(148.21,18.59) v4(149.93,14.72) v4(151.76,22.65) v4(151.76,21.26) v4(151.76,19.86) v4(155.45,25.32) v4(156.97,29.64) v4(156.97,28.88) v4(156.97,27.99) v5(43.43,34.08) v5(44.32,34.08) v5(44.83,35.99) v5(93.98,130.73) v5(98.81,130.73) v5(101.35,130.73) v5(101.35,127.05) v5(104.14,24.94) v5(125.6,65.71) v5(125.6,65.07) v5(125.6,64.05) v5(125.6,63.42) v5(125.73,70.79) v5(125.73,70.15) v5(125.73,69.13) v5(125.73,68.5) v5(126.24,65.71) v5(126.24,65.07) v5(126.24,64.05) v5(126.24,63.42) v5(126.37,70.79) v5(126.37,70.15) v5(126.37,69.13) v5(126.37,68.5) v5(126.87,65.71) v5(126.87,65.07) v5(126.87,64.05) v5(126.87,63.42) v5(127,70.79) v5(127,70.15) v5(127,69.13) v5(127,68.5) v5(128.02,65.71) v5(128.02,65.07) v5(128.02,64.05) v5(128.02,63.42) v5(128.14,70.79) v5(128.14,70.15) v5(128.14,69.13) v5(128.14,68.5) v5(136.4,69.64) v5(136.4,69.08) v5(137.03,69.64) v5(137.03,69.08) v5(137.03,68.5) v5(137.67,69.64) v5(137.67,69.08) v5(137.67,68.5) v5(138.3,69.64) v5(138.3,69.08) v5(138.3,68.5) v5(139.83,69.64) v5(140.77,69.65) v5(140.97,11.6) v5(141.7,70.55) v5(141.73,69.64) v5(141.99,7.16) v5(142.04,65.07) v5(144.65,72.31) v5(144.65,71.67) v5(144.65,70.79) v5(144.65,70.15) v5(145.8,72.31) v5(145.8,71.67) v5(145.8,70.79) v5(145.8,70.15) v5(146.94,72.31) v5(146.94,71.67) v5(146.94,70.79) v5(146.94,70.15) v5(146.96,6.4) v5(147.83,7.16) v5(147.83,6.4) v5(147.95,70.79) v5(147.95,70.15) v5(147.95,69.01) v5(147.95,68.37) v5(147.95,67.1) v5(147.95,66.47) v5(147.95,65.83) v5(147.95,64.56) v5(147.95,63.93) v5(147.95,63.29) v5(148.59,29.64) v5(153.42,30.02) v5(154.43,25.32) v5(154.43,24.3) v5(155.45,24.3) v5(157.48,31.29) v6(52.47,88.89) v6(57.13,107.44)
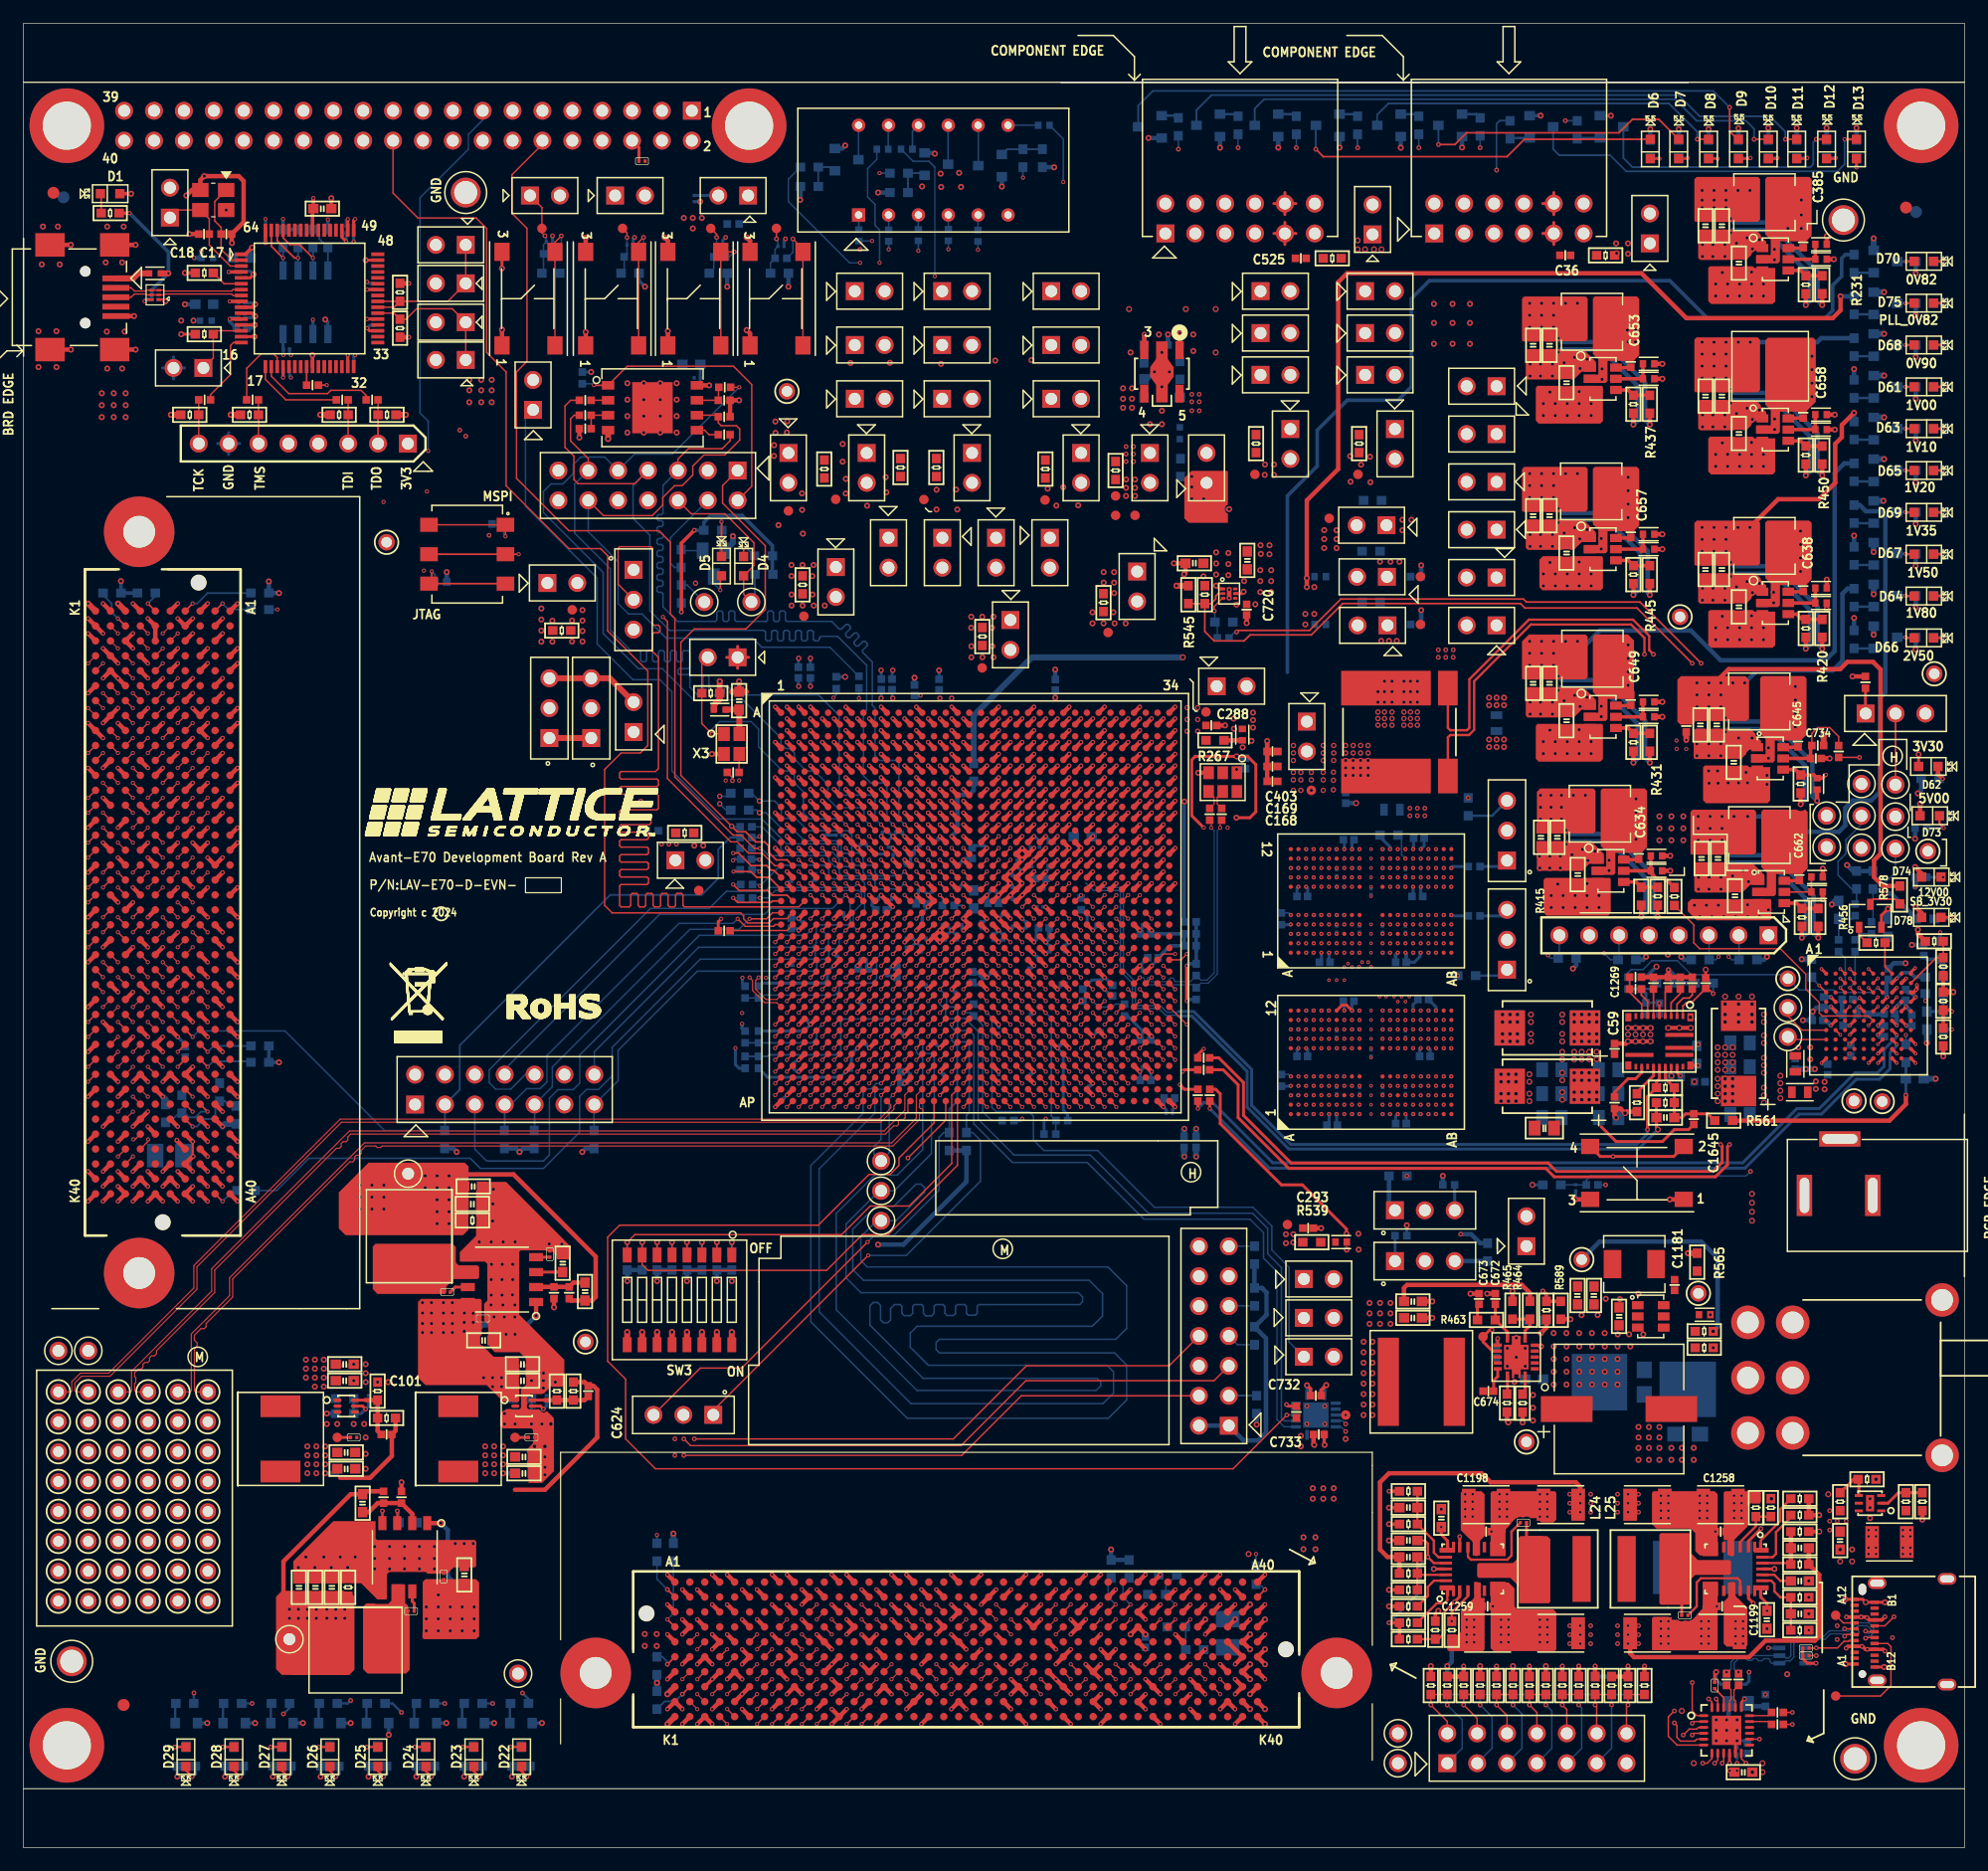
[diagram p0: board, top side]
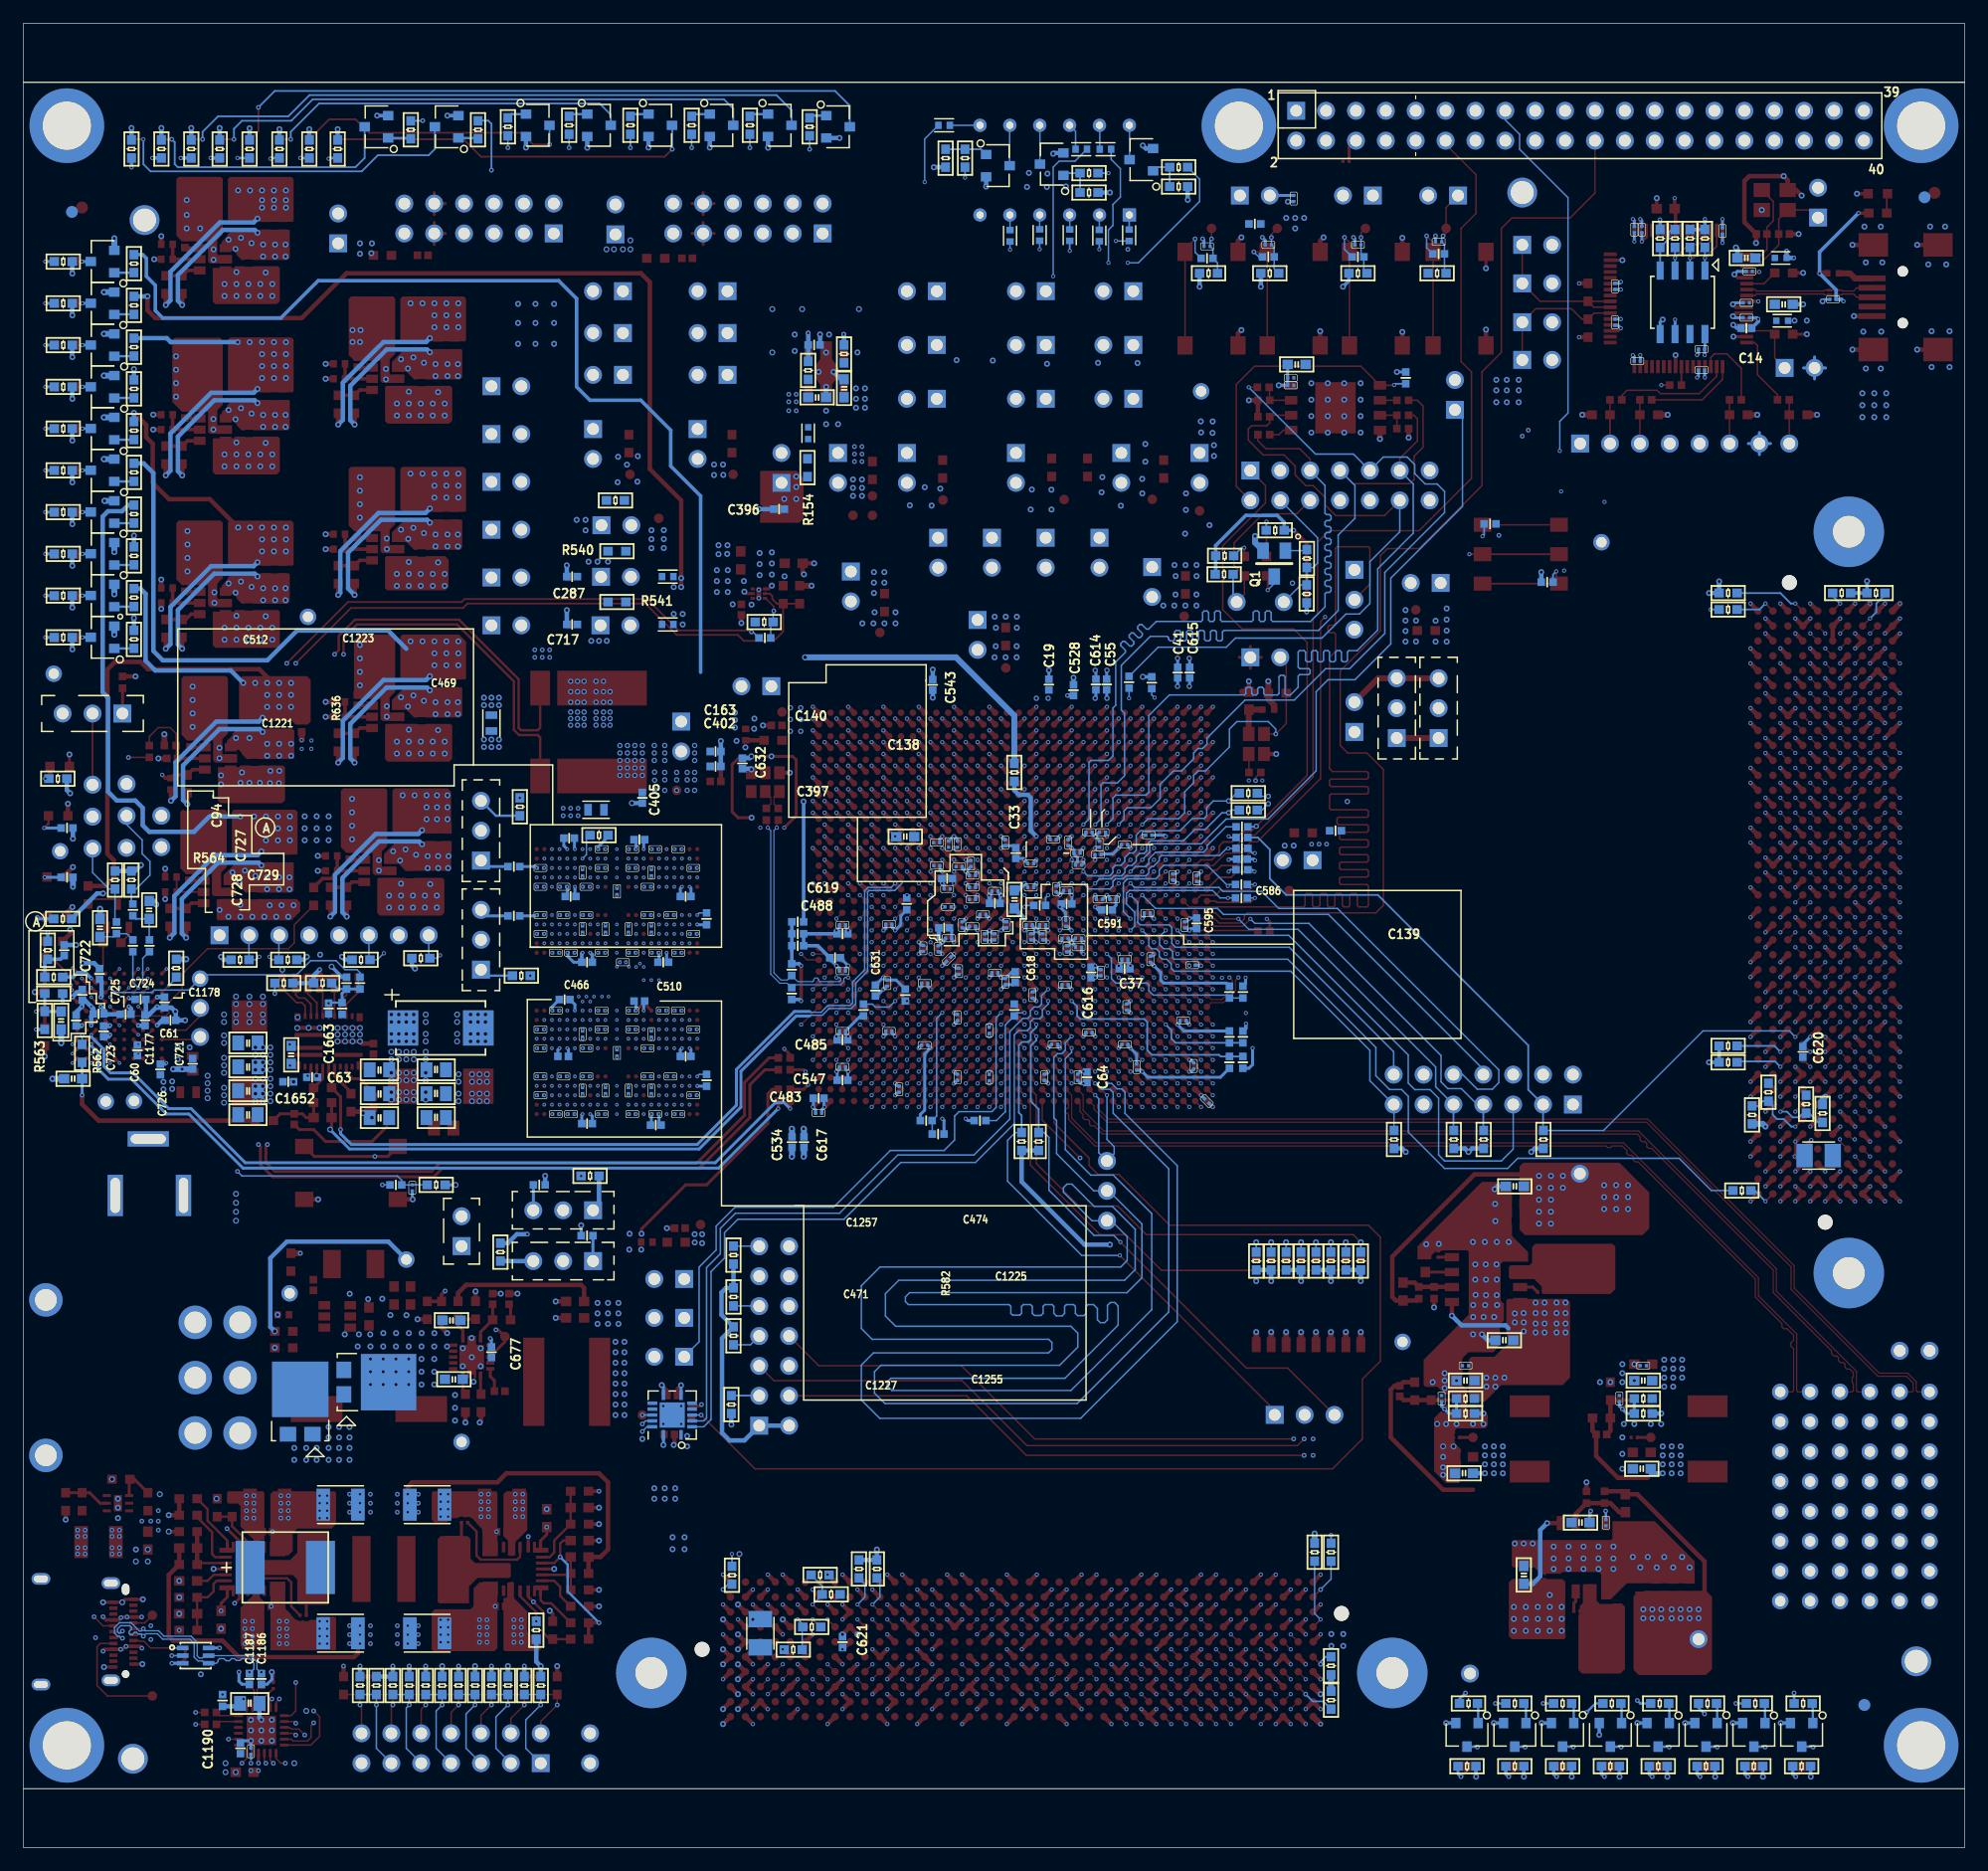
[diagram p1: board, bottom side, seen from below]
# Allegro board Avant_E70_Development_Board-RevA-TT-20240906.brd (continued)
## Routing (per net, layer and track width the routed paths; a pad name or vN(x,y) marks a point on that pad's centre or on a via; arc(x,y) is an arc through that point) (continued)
VBUS_5V00: length 12.1
  TOP w0.203: v2(10.29,131.39) 10.43,131.54 D3.6
  TOP w0.305: R1.2 v2(9.02,138.89)
  TOP w0.508: FB2.1 v2(12.32,133.77)
  BOTTOM w0.305: v2(10.29,131.39) 10.45,131.56 C8.1 10.91,132.37 v2(12.32,133.77) 12.32,135.59 v2(9.02,138.89)
VCC_0V82: length 91.6
  TOP w0.254: 134.11,61.26 135.38,59.99 139.32,59.99 140.33,61.01 141.55,61.01 C1645.1
  BOTTOM w0.305: R474.2 154.87,135.36 154.56,135.05 154.56,133.52 153.8,132.76 153.8,130.6 153.16,129.97 143.13,129.97 139.95,133.14 119.51,133.14 117.98,131.62 117.98,124.13 116.84,122.98 112.52,122.98 109.98,120.44 109.98,117.39 107.44,114.85 107.44,99.87
  vias: v4(109.6,30.53) v4(109.6,29.64) v4(110.49,30.53) v4(110.49,29.64) v4(111.38,30.53) v4(111.38,29.64) v5(130.81,70.79) v5(130.81,70.15) v5(130.81,69.13) v5(130.81,68.5) v5(130.81,67.61) v5(130.81,66.98) v5(130.81,65.83) v5(130.81,65.2) v5(130.81,64.18) v5(130.81,63.55) v5(131.83,70.79) v5(131.83,70.15) v5(131.83,69.13) v5(131.83,68.5) v5(131.83,67.61) v5(131.83,66.98) v5(131.83,65.83) v5(131.83,65.2) v5(131.83,64.18) v5(131.83,63.55) v5(132.46,70.79) v5(132.46,70.15) v5(132.46,69.13) v5(132.46,68.5) v5(132.46,67.61) v5(132.46,66.98) v5(132.46,65.83) v5(132.46,65.2) v5(132.46,64.18) v5(132.46,63.55) v5(133.1,70.79) v5(133.1,70.15) v5(133.1,69.13) v5(133.1,68.5) v5(133.1,67.61) v5(133.1,66.98) v5(133.1,65.83) v5(133.1,65.2) v5(133.1,64.18) v5(133.1,63.55) v5(133.73,70.79) v5(133.73,70.15) v5(133.73,69.13) v5(133.73,68.5) v5(133.73,67.61) v5(133.73,66.98) v5(133.73,65.83) v5(133.73,65.2) v5(133.73,64.18) v5(133.73,63.55) v6(115.14,98.22) v6(115.14,97.33) v6(115.14,96.49) v6(115.14,95.93) v6(115.14,95.37) v6(115.7,99.11) v6(115.7,98.22) v6(115.7,97.33) v6(115.7,96.49) v6(115.7,95.93) v6(115.7,95.37) v6(116.33,99.11) v6(116.33,98.22) v6(116.33,97.33) v6(116.33,96.49) v6(116.33,95.93) v6(116.33,95.37) v6(117.35,99.11) v6(117.35,98.22) v6(117.35,97.33) v6(117.35,96.49) v6(117.35,95.93) v6(117.35,95.37) v6(117.91,99.11) v6(117.91,98.22) v6(117.91,97.33) v6(117.91,96.49) v6(117.91,95.93) v6(117.91,95.37) v6(118.49,99.11) v6(118.49,98.22) v6(118.49,97.33) v6(118.49,96.49) v6(118.49,95.93) v6(118.49,95.37)
VCC_0V82_ALTN: length 2.4
  TOP w0.152: R693.2 139.57,72.69 U120.5
VCC_0V82_PG: length 2.3
  TOP w0.152: U120.7 138.56,72.94 R705.2
VCC_0V82_SENSE+: length 8.4
  TOP w0.254: U120.21 139.57,65.33 R697.1 R698.1 C62.1 140.97,62.02 141.29,62.35 C1645.2 143.19,62.35 R561.1
VCC_0V90: length 22.6
  TOP w0.381: R450.1 v4(152.91,116.6)
  BOTTOM w0.381: v4(146.79,127.92) 152.48,127.92 152.82,128.26 R446.2 ; v4(152.91,116.6) 152.51,117 152.51,120.16 149.05,123.62 145.44,123.62 v4(145.11,123.95)
  vias: v4(6.65,123.58) v4(6.65,122.56) v4(6.65,121.55) v4(7.67,123.58) v4(7.67,122.56) v4(7.67,121.55) v4(8.68,123.58) v4(8.68,122.56) v4(8.68,121.55) v4(142.69,127.92) v4(142.69,126.91) v4(142.69,125.89) v4(142.69,124.88) v4(143.71,127.92) v4(143.71,126.91) v4(143.71,125.89) v4(143.71,124.88) v4(144.73,127.92) v4(144.73,126.91) v4(144.73,125.89) v4(144.73,124.88) v4(145.77,127.92)
VCC_1V00: length 14.1
  TOP w0.381: R231.1 v4(152.91,131.08)
  BOTTOM w0.381: R229.2 v4(155.61,125.64) ; v4(145.11,138.42) 145.44,138.1 148.32,138.1 152.51,133.9 152.51,131.47 v4(152.91,131.08)
  vias: v4(142.69,140.82) v4(142.69,139.99) v4(142.69,139.35) v4(143.71,140.82) v4(143.71,139.99) v4(143.71,139.35) v4(144.73,140.82) v4(144.73,139.99) v4(144.73,139.35) v4(145.74,140.82) v4(146.76,140.82)
VCC_1V10: length 74.8
  TOP w0.381: R420.1 v4(152.91,101.87) ; v4(155.61,121.92) 154.57,120.88 154.57,119.85 154.02,119.29 154.02,115.96 152.63,114.58 149.16,114.58 v4(146.76,112.18)
  L03-SIG1 w0.381: v4(124.59,97.71) 120.9,97.71 118.75,99.87 106.81,99.87 104.14,97.2 101.98,97.2 100.84,96.06 100.84,94.15 99.82,93.14 99.07,93.14 98.69,92.76 v4(98.69,88.88)
  BOTTOM w0.305: R492.2 v4(98.69,88.88)
  BOTTOM w0.381: v4(145.11,109.21) 145.44,108.89 149.05,108.89 152.51,105.42 152.51,102.26 v4(152.91,101.87) ; R416.2 v4(155.61,121.92)
  vias: v4(124.59,97.07) v4(125.22,97.71) v4(125.22,97.07) v4(125.86,97.71) v4(125.86,97.07) v4(142.69,112.18) v4(142.69,111.16) v4(142.69,110.14) v4(143.71,112.18) v4(143.71,111.16) v4(143.71,110.14) v4(144.73,112.18) v4(144.73,111.16) v4(144.73,110.14) v4(145.74,112.18)
VCC_1V20: length 54.3
  TOP w0.381: R431.1 v4(138.25,92.19)
  BOTTOM w0.381: v4(130.45,99.54) 130.78,99.21 134.39,99.21 137.86,95.75 137.86,92.59 v4(138.25,92.19) ; 132.46,101.88 134,103.42 141.74,103.42 144.27,100.88 153.16,100.88 153.96,101.68 153.96,116.8 154.78,117.62 R432.2
  vias: v4(70.3,126.15) v4(73.66,126.17) v4(77.99,126.08) v4(82.6,126.36) v4(85.68,126.39) v4(103.76,107.62) v4(105.13,108.55) v4(105.13,107.62) v4(105.13,106.69) v4(106.06,108.55) v4(106.06,107.62) v4(106.06,106.69) v4(128.04,102.5) v4(128.04,101.48) v4(128.04,100.47) v4(129.05,102.5) v4(129.05,101.48) v4(129.05,100.47) v4(130.07,102.5) v4(130.07,101.48) v4(130.07,100.47) v4(131.09,102.5) v4(132.1,102.5)
VCC_1V35: length 54.3
  TOP w0.381: R456.1 v4(152.57,77.31)
  BOTTOM w0.381: v4(144.77,84.65) 145.1,84.33 148.71,84.33 152.18,80.86 152.18,77.7 v4(152.57,77.31) ; v4(146.57,87.62) 149.19,87.62 150.5,86.31 154.31,86.31 154.86,86.86 154.86,88.34 155.5,88.97 157.07,88.97 157.82,89.72 157.82,97.73 158.27,98.18 158.27,113.1 157.82,113.55 156.62,113.55 156.11,114.07 R452.2
  vias: v4(142.36,87.62) v4(142.36,86.6) v4(142.36,85.58) v4(143.38,87.62) v4(143.38,86.6) v4(143.38,85.58) v4(144.39,87.62) v4(144.39,86.6) v4(144.39,85.58) v4(145.41,87.62)
VCC_1V50: length 82.3
  TOP w0.381: R445.1 v4(138.25,106.44)
  L03-SIG1 w0.508: v5(98.55,101.14) 119,101.14 119.89,100.25 124.59,100.25 126.49,102.15 126.49,114.78 JP35.1
  BOTTOM w0.381: v4(138.25,106.44) 138.07,106.62 138.07,110.16 134.82,113.41 130.83,113.41 v4(130.45,113.79) ; R443.2 v4(155.61,111.48)
  BOTTOM w0.508: v5(98.55,101.14) 85.72,101.14 80.77,96.19 R714.2
  vias: v4(128.04,116.75) v4(128.04,115.73) v4(128.04,114.72) v4(129.05,116.75) v4(129.05,115.73) v4(129.05,114.72) v4(130.07,116.75) v4(130.07,115.73) v4(130.07,114.72) v4(131.09,116.75) v4(132.1,116.75)
VCC_1V80: length 64.6
  TOP w0.381: v4(144.29,98.96) 144.29,99.46 144.96,100.13 154.43,100.13 155.05,100.75 157.23,100.75 157.87,100.11 157.87,84.44 157.31,83.89 157.31,82.47 158.07,81.71 R578.1 ; R425.1 v4(152.47,88.95)
  BOTTOM w0.381: R426.2 155.06,106.97 154.62,106.53 154.62,100.84 153.8,100.02 147.38,100.02 v4(146.32,98.96) ; v4(144.67,96) 145,95.68 148.61,95.68 152.07,92.21 152.07,89.33 152.46,88.95 v4(152.47,88.95)
  vias: v4(139.06,87.63) v4(139.06,86.61) v4(139.06,85.59) v4(140.08,87.63) v4(140.08,86.61) v4(140.08,85.59) v4(141.1,87.63) v4(141.1,86.61) v4(141.1,85.59) v4(142.26,98.96) v4(142.26,97.95) v4(142.26,96.93) v4(143.27,98.96) v4(143.27,97.95) v4(143.27,96.93) v4(144.29,97.95) v4(144.29,96.93) v4(145.31,98.96)
VCC_1V80_FT: length 7.7
  TOP w0.254: U1.37 v2(29.21,129.89) ; U1.49 28.06,138.25 v2(28.19,138.38)
  TOP w0.305: U1.64 v2(20.56,136.36) ; U1.12 v2(17.53,129.89)
  BOTTOM w0.254: C15.1 17.63,130 v2(17.53,129.89) ; C11.1 29.22,129.88 v2(29.21,129.89) ; v2(20.56,136.36) 20.57,136.37 C13.1 ; v2(28.19,138.38) 28.07,138.25 C12.1
  BOTTOM w0.305: C14.1 17.53,129.67 v2(17.53,129.89)
VCC_2V50: length 58.3
  TOP w0.381: R437.1 v4(138.25,120.92)
  L10-SIG3 w0.381: v4(130.45,128.26) 131.24,127.48 134.19,127.48 134.62,127.05 139.83,127.05 141.48,125.4 141.48,118.41 144.53,115.36 152.4,115.36 154.31,113.46 154.31,107.87 155.61,106.56 v4(155.61,104.48)
  BOTTOM w0.381: R438.2 v4(155.61,104.48) ; v4(138.25,120.92) 137.86,121.31 137.86,124.47 134.39,127.94 130.78,127.94 v4(130.45,128.26)
  vias: v4(76.38,141.15) v4(77.96,142.24) v4(78.01,141.11) v4(79.53,142.31) v4(79.7,141.12) v4(93.47,124) v4(93.47,123.11) v4(93.47,122.35) v4(94.23,124) v4(94.23,123.11) v4(94.23,122.35) v4(128.04,131.23) v4(128.04,130.21) v4(128.04,129.19) v4(129.05,131.23) v4(129.05,130.21) v4(129.05,129.19) v4(130.07,131.23) v4(130.07,130.21) v4(130.07,129.19) v4(131.09,131.23) v4(132.1,131.23)
VCC_3V30: length 98.7
  TOP w0.254: U1.31 v2(27.56,126.82) ; C733.1 110.56,34.26 v4(110.61,34.21) ; U1.50 v2(27.56,138.37) ; U1.20 v2(22.06,124.92) ; U1.42 v2(29.21,132.39) ; R11.2 v4(13.4,128.6)
  TOP w0.305: v2(24.64,140.16) C5.1 24.56,139.19 U1.56 ; R414.1 v4(138.92,79.11)
  TOP w0.381: v4(161.04,78) 161.04,77.64 R680.2 ; R17.2 v2(32.77,128.35) ; R16.2 v2(32.77,132.92)
  TOP w0.508: R2.1 v4(17.61,121.75) ; R3.1 v4(25.23,121.75) ; R4.1 v4(32.5,121.75)
  BOTTOM w0.254: v2(29.21,132.39) 29.22,132.4 C2.1 ; U46.14 v4(110.61,34.21) ; C4.1 27.43,138.24 v2(27.56,138.37) ; U2.8 22.06,127.36 C16.1 v2(22.09,126.83) ; v2(27.56,126.82) 27.55,126.81 C1.1 ; C3.1 22.09,124.98 22.06,124.95 v2(22.06,124.92) ; U2.6 v2(24.6,129.84)
  BOTTOM w0.305: R702.1 137.91,73.95 v5(138.81,74.85) ; v4(25.26,6.02) 25.27,6.03 R528.2 ; v4(41.52,6.02) 41.53,6.03 R521.2 ; R529.2 21.21,6.03 v4(21.2,6.02) ; R526.2 29.34,6.03 v4(29.32,6.02) ; R532.2 17.14,6.03 v4(17.13,6.02) ; R14.1 v2(25.87,138.34) ; v4(33.39,6.02) 33.4,6.03 R524.2 ; v4(21.72,66.72) R91.2 R90.2 ; v4(37.45,6.02) 37.46,6.03 R523.2 ; R13.1 R12.1 v2(22.06,138.38) ; v4(8.28,107.62) R217.2 R84.2 ; R533.2 13.08,6.03 v4(13.07,6.02)
  BOTTOM w0.381: R417.2 160.86,119.57 v4(160.85,119.56) ; R475.2 160.86,133.76 v4(160.85,133.75) ; R546.2 160.86,130.22 v4(160.85,130.2) ; v4(47.5,59.1) 47.8,59.4 R87.2 ; R439.2 160.86,101.83 v4(160.85,101.82) ; R453.2 160.86,112.48 v4(160.85,112.46) ; C632.1 103.18,91.67 v4(103.12,91.61) ; R444.2 160.86,108.93 v4(160.85,108.92) ; R62.2 v4(153.28,146.12) ; R86.2 42.47,59.4 v4(42.16,59.1) 41.86,59.4 R85.2 ; v2(15.12,135.68) FB3.2 v2(14.5,135.08) ; v4(160.85,116.01) 160.86,116.02 R433.2 ; v4(92.46,25.32) R321.2 R322.2 ; v4(131.12,86.45) 131.45,86.13 135.06,86.13 138.52,82.66 138.52,79.5 v4(138.92,79.11) ; R427.2 160.86,105.38 v4(160.85,105.37) ; R316.2 R315.2 105.28,47.54 105.66,47.16 105.66,45.26 R314.2 105.62,43.27 105.62,35.24 104.98,34.59 103.71,34.59 J53.1 J53.2 ; v4(161.04,89.58) 161.32,89.87 R411.2 ; v4(160.85,123.11) 160.86,123.12 R169.2 ; v4(21.72,106.6) R83.2 v4(20.85,107.59) ; R447.2 160.86,126.67 v4(160.85,126.65) ; R63.2 v4(155.82,146.12)
  BOTTOM w0.508: R327.2 v4(55.24,26.67) ; R328.2 v4(53.85,13.99) R310.2
  vias: v4(13.4,129.75) v4(14.45,129.75) v4(44.02,105.29) v4(44.02,104.35) v4(44.02,103.41) v4(44.02,102.47) v4(44.96,104.25) v4(44.96,102.47) v4(52.81,18.14) v4(52.81,17.13) v4(53.83,18.14) v4(53.83,17.13) v4(63.8,119.17) v4(63.8,118.25) v4(63.91,121.18) v4(63.92,120.21) v4(64.92,121.19) v4(64.89,120.25) v4(65.28,108.98) v4(65.28,108.04) v4(66.22,108.98) v4(67.06,108.04) v4(67.16,108.98) v4(69.64,119.27) v4(69.64,117.77) v4(103.11,105.62) v4(104.72,105.64) v4(128.96,89.41) v4(128.96,88.4) v4(128.96,87.38) v4(129.85,89.41) v4(129.85,88.4) v4(129.85,87.38) v4(130.74,89.41) v4(130.74,88.4) v4(130.74,87.38) v4(131.75,89.41) v4(132.77,89.41)
VCC_3V30_EN: length 30.6
  TOP w0.127: v3(156.85,69.86) U45.F6 156.84,70.66 152.91,70.66 152.65,70.91 152.65,71.8 151.51,72.94 151.51,74.21 149.35,76.37 142.49,76.37 141.99,76.88 141.99,78.41 R682.1
  L05-SIG2 w0.091: v3(156.85,69.86) 156.85,67.51 157.23,67.12 157.23,64.16 VCC_3V30_EN.1
VCC_3V30_MON: length 5
  TOP w0.152: U45.B10 162.6,75.61 R681.2 R680.1
VCC_5V00: length 20.9
  TOP w0.381: v4(152.96,80.59) R454.1 ; v4(126.22,36.11) 126.11,36.22 R467.1 ; R428.1 v4(139.32,96.08) ; R418.1 v4(153.29,105.25) ; R448.1 v4(153.97,120.49) ; R434.1 v4(139.32,124.81) ; R233.1 v4(153.9,134.97) ; R464.1 128.06,47.12 127.37,47.81 117.61,47.81 117.35,47.54 C676.1 ; R441.1 v4(139.32,110.33) ; R412.1 v4(139.99,83)
  TOP w0.508: R572.1 v4(153.03,94.6)
  BOTTOM w0.381: R510.1 v4(160.8,85.72)
  vias: v4(113.92,42.97) v4(113.92,42.08) v4(113.92,41.19) v4(113.92,40.31) v4(113.92,39.42) v4(113.92,38.53) v4(113.92,37.64) v4(113.92,36.75) v4(114.43,46.27) v4(114.43,45.39) v4(114.43,44.5) v4(114.68,42.97) v4(114.68,42.08) v4(114.68,41.19) v4(114.68,40.31) v4(114.68,39.42) v4(114.68,38.53) v4(114.68,37.64) v4(114.68,36.75) v4(115.32,46.27) v4(115.32,45.39) v4(115.32,44.5) v4(116.21,46.27) v4(116.21,45.39) v4(116.21,44.5) v4(129.2,122.7) v4(129.2,121.69) v4(129.2,108.23) v4(129.2,107.21) v4(129.2,93.98) v4(129.2,92.96) v4(129.76,123.68) v4(129.76,109.2) v4(129.76,94.95) v4(129.87,80.89) v4(129.87,79.88) v4(130.21,122.7) v4(130.21,121.69) v4(130.21,108.23) v4(130.21,107.21) v4(130.21,93.98) v4(130.21,92.96) v4(130.43,81.87) v4(130.88,80.89) v4(130.88,79.88) v4(131.23,122.7) v4(131.23,121.69) v4(131.23,108.23) v4(131.23,107.21) v4(131.23,93.98) v4(131.23,92.96) v4(131.9,80.89) v4(131.9,79.88) v4(132.25,123.72) v4(132.25,122.7) v4(132.25,121.69) v4(132.25,109.24) v4(132.25,108.23) v4(132.25,107.21) v4(132.25,94.99) v4(132.25,93.98) v4(132.25,92.96) v4(132.91,81.91) v4(132.91,80.89) v4(132.91,79.88) v4(133.26,122.7) v4(133.26,121.69) v4(133.26,108.23) v4(133.26,107.21) v4(133.26,93.98) v4(133.26,92.96) v4(133.93,80.89) v4(133.93,79.88) v4(142.05,80.07) v4(142.5,79.09) v4(143.06,80.07) v4(143.26,91.49) v4(143.29,90.44) v4(143.52,79.09) v4(143.85,132.86) v4(143.85,131.85) v4(143.85,118.39) v4(143.85,117.37) v4(143.85,103.65) v4(143.85,102.64) v4(144.02,91.49) v4(144.05,90.44) v4(144.08,80.07) v4(144.41,133.84) v4(144.41,119.36) v4(144.41,104.63) v4(144.53,79.09) v4(144.87,132.86) v4(144.87,131.85) v4(144.87,118.39) v4(144.87,117.37) v4(144.87,103.65) v4(144.87,102.64) v4(144.91,90.47) v4(145.55,79.09) v4(145.8,90.47) v4(145.88,132.86) v4(145.88,131.85) v4(145.88,118.39) v4(145.88,117.37) v4(145.88,103.65) v4(145.88,102.64) v4(146.43,91.36) v4(146.56,90.47) v4(146.57,80.11) v4(146.57,79.09) v4(146.9,133.88) v4(146.9,132.86) v4(146.9,131.85) v4(146.9,119.4) v4(146.9,118.39) v4(146.9,117.37) v4(146.9,104.67) v4(146.9,103.65) v4(146.9,102.64) v4(147.58,79.09) v4(147.92,132.86) v4(147.92,131.85) v4(147.92,118.39) v4(147.92,117.37) v4(147.92,103.65) v4(147.92,102.64) v4(148.21,91.11) v4(148.21,90.34) v4(148.34,79.68) v5(144.02,67.99) v5(144.02,67.36) v5(144.02,66.72) v5(144.02,66.09) v5(144.02,65.32) v5(144.02,64.69) v5(144.02,64.05) v5(144.02,63.42) v5(144.65,67.99) v5(144.65,67.36) v5(144.65,66.72) v5(144.65,66.09) v5(144.65,65.32) v5(144.65,64.69) v5(144.65,64.05) v5(144.65,63.42) v5(145.29,67.99) v5(145.29,67.36) v5(145.29,66.72) v5(145.29,66.09) v5(145.29,65.32) v5(145.29,64.69) v5(145.29,64.05) v5(145.29,63.42)
VCC_12V00: length 25.7
  TOP w0.381: J48.C35 v2(15.65,61.26) ; J54.C37 v2(101.73,20.65) ; R289.2 v4(163.19,67.23) ; J48.C37 v2(15.65,58.72) ; U32.1 v4(35.48,27.56) ; J54.C35 v2(99.19,20.65) ; U6.1 v4(43.57,45.19)
  L08-POW2 w0.508: v4(163.19,67.23) 163.19,59.99
  BOTTOM w0.381: v4(43.57,45.19) 42.75,44.37 39.02,44.37 38.77,44.12 ; C558.1 36.7,22.4 36.07,23.03 36.07,26.97 v4(35.48,27.56)
  vias: v4(24,41.45) v4(24,40.69) v4(24,39.92) v4(24.77,41.45) v4(24.77,40.69) v4(24.77,39.92) v4(24.77,39.16) v4(25.53,41.45) v4(25.53,40.69) v4(25.53,39.92) v4(25.53,39.16) v4(33.92,46.3) v4(33.92,45.41) v4(33.92,44.52) v4(33.92,43.76) v4(34.24,20.44) v4(34.24,19.43) v4(34.24,18.41) v4(34.68,46.3) v4(34.68,45.41) v4(34.68,44.52) v4(34.68,43.76) v4(35.26,21.46) v4(35.26,20.44) v4(35.26,19.43) v4(35.26,18.41) v4(35.69,46.3) v4(35.69,45.41) v4(35.69,44.52) v4(35.69,43.76) v4(36.27,20.44) v4(36.27,19.43) v4(36.27,18.41) v4(36.46,46.3) v4(36.46,45.41) v4(36.46,44.52) v4(36.46,43.76) v4(37.29,20.44) v4(37.29,19.43) v4(37.29,18.41) v4(37.47,45.41) v4(37.46,44.62) v4(37.46,43.86) v4(38.23,45.39) v4(38.23,44.62) v4(38.31,20.44) v4(38.31,19.43) v4(38.31,18.41) v4(39.12,39.92) v4(39.88,39.92) v4(39.88,39.16) v4(40.64,39.92) v4(40.64,39.16)
VCC_AUX: length 10.1
  TOP w0.381: U3.Y12 v2(74.9,76.93) ; U3.Y22 v2(85.9,76.93) ; U3.P11 v2(73.9,83.93) ; U3.W18 v2(81.9,77.93)
  L03-SIG1 w0.254: v2(81.9,77.93) 82.31,77.52 85.31,77.52 v2(85.9,76.93)
  BOTTOM w0.254: v2(85.9,76.93) 86.1,77.13 C398.1 86.1,77.96 C397.1 ; v2(74.9,76.93) 75.05,77.08 C401.1 ; v2(81.9,77.93) 81.69,78.14 C399.1 ; C400.1 73.92,83.95 v2(73.9,83.93)
  vias: v4(99.31,116.51) v4(99.31,115.62) v4(99.31,114.6) v4(100.33,114.6)
VCC_CORE: length 105.9
  TOP w0.254: R575.1 99.83,67.36 v2(100.33,67.86) ; R698.2 C62.2 138.81,61.13 v5(138.94,61.01)
  TOP w0.381: U3.N22 v2(84.9,83.93) ; U3.N22 v2(84.9,84.93) U3.N21 v2(84.9,83.93) ; U3.N22 v2(85.9,84.93) ; v2(84.9,83.93) U3.P21 v2(83.9,82.93) U3.R20 v2(83.9,81.93) U3.T20 83.4,81.43 v2(82.9,80.93) U3.U19 ; U3.N24 v2(87.9,84.93) ; U3.W15 v2(77.9,77.93) ; v2(77.9,77.93) U3.Y14 ; v2(77.9,77.93) U3.Y15 v2(77.9,76.93) U3.Y14 ; U3.V21 v2(84.9,78.93) ; U3.Y14 v2(76.9,76.93) ; U3.R24 v2(87.9,82.93) ; v2(79.9,77.93) U3.W17 80.4,78.43 v2(79.9,78.93) U3.V17 ; U3.U21 v2(84.9,80.93) 85.4,81.43 U3.T22 v2(85.9,81.93) U3.R22 v2(85.9,82.93) ; U3.V19 v2(82.9,78.93) 83.4,78.43 U3.W20 v2(83.9,77.93) ; U3.Y19 v2(82.9,76.93) ; U3.U13 v2(75.9,80.93) ; U3.W13 v2(75.9,77.93) ; U3.AA12 v2(74.9,75.93) ; U3.AA22 v2(85.9,75.93)
  BOTTOM w0.127: 90.3,81.96 90.93,81.33 93.11,81.33 93.24,81.2 93.24,74.47 94.26,73.45 94.26,71.67 94.64,71.29 96.52,71.29 97.09,70.72 98.08,70.72 98.14,70.66 98.17,70.66
  BOTTOM w0.254: v2(74.9,75.93) 75.05,76.08 C166.1 ; C151.1 84.07,81.76 v2(83.9,81.93) ; v2(75.9,77.93) 76.24,78.27 C173.1 ; C178.1 84.07,82.76 v2(83.9,82.93) ; C147.1 76.72,77.11 v2(76.9,76.93) ; v2(84.9,78.93) 85.16,78.67 C175.1 ; C148.1 82.69,81.14 v2(82.9,80.93) ; v2(79.9,77.93) 79.76,78.06 C152.1 ; C139.2 75.88,80.91 v2(75.9,80.93) 76.06,81.1 C143.1 ; C167.1 86.16,75.67 v2(85.9,75.93) ; C165.1 84.07,78.1 v2(83.9,77.93) ; v2(82.9,78.93) 83.18,79.21 C172.1 ; C176.1 78.1,78.13 v2(77.9,77.93) ; C177.1 83.1,77.13 v2(82.9,76.93) 82.7,77.13 C164.1 ; v2(77.9,76.93) 78.1,77.13 C404.1 ; v5(138.94,61.01) 137.29,59.36 107.57,59.36 104.01,62.91 104.01,65.96 99.31,70.66 98.17,70.66 ; v2(84.9,83.93) 84.84,83.88 C171.1
  BOTTOM w0.381: C138.2 82.88,80.91 v2(82.9,80.93) ; C612.1 v2(79.9,78.93)
  vias: v6(107.95,93.65) v6(107.95,93.01) v6(107.95,92.38) v6(107.95,91.36) v6(107.95,90.72) v6(107.95,89.84) v6(108.59,91.36) v6(108.59,90.72) v6(108.59,89.84) v6(109.47,91.36) v6(109.47,90.72) v6(109.47,89.84) v6(110.49,93.65) v6(110.49,93.01) v6(110.49,92.38) v6(110.49,91.36) v6(110.49,90.72) v6(110.49,89.84) v6(111.38,93.65) v6(111.38,93.01) v6(111.38,92.38) v6(111.36,91.38) v6(111.35,90.69) v6(111.35,89.88) v6(112.4,93.65) v6(112.4,93.01) v6(112.4,92.38) v6(112.4,91.74) v6(112.4,91.11) v6(113.03,93.65) v6(113.03,93.01) v6(113.03,92.38) v6(113.03,91.74) v6(113.03,91.11) v6(113.66,93.65) v6(113.66,93.01) v6(113.66,92.38) v6(113.66,91.74) v6(113.66,91.11) v6(114.3,93.65) v6(114.3,93.01) v6(114.3,92.38) v6(114.3,91.74) v6(114.3,91.11)
VCC_DDR: length 24.9
  L10-SIG3 w0.381: v3(116.83,62.32) 116.83,57.83 v1(117.59,57.06) 117.86,56.8 117.86,53.64 119.38,52.12 v1(122.17,52.12)
  BOTTOM w0.254: v3(108.38,81.64) 108.26,81.52 C469.1 ; R633.1 107.7,64.7 v3(107.73,64.72) ; v3(119.43,67.92) 119.58,67.77 C471.1 ; v3(116.83,62.32) 116.64,62.14 C1227.1 ; v3(112.28,84.84) 112.28,85.56 C1223.1 ; C1225.1 108.26,67.8 v3(108.38,67.92) ; C474.1 112.28,71.85 v3(112.28,71.12) ; R291.1 107.7,78.41 v3(107.73,78.44) ; v3(118.13,81.64) 118.13,80.91 C1221.1
  BOTTOM w0.305: v3(116.83,76.04) 116.64,75.85 C466.1
  BOTTOM w0.381: v1(122.17,52.12) 123.06,52.12 123.82,51.35 R646.2
  vias: v1(93.73,119.05) v1(93.73,118.41) v1(93.73,117.78) v1(94.36,119.05) v1(94.36,118.41) v1(94.36,117.78) v1(121.92,74.09) v1(122.82,89.19) v3(107.73,82.44) v3(107.73,68.72) v3(108.38,83.24) v3(108.38,79.24) v3(108.38,77.64) v3(108.38,69.52) v3(108.38,65.52) v3(108.38,63.92) v3(109.68,84.84) v3(109.68,81.64) v3(109.68,79.24) v3(109.68,76.04) v3(109.68,71.12) v3(109.68,67.92) v3(109.68,65.52) v3(109.68,62.32) v3(110.98,83.24) v3(110.98,81.64) v3(110.98,79.24) v3(110.98,77.64) v3(110.98,69.52) v3(110.98,67.92) v3(110.98,65.52) v3(110.98,63.92) v3(112.28,81.64) v3(112.28,79.24) v3(112.28,76.04) v3(112.28,67.92) v3(112.28,65.52) v3(112.28,62.32) v3(113.58,84.84) v3(113.58,83.24) v3(113.58,77.64) v3(113.58,76.04) v3(113.58,71.12) v3(113.58,69.52) v3(113.58,63.92) v3(113.58,62.32) v3(115.53,84.84) v3(115.53,83.24) v3(115.53,77.64) v3(115.53,76.04) v3(115.53,71.12) v3(115.53,69.52) v3(115.53,63.92) v3(115.53,62.32) v3(116.83,84.84) v3(116.83,81.64) v3(116.83,79.24) v3(116.83,71.12) v3(116.83,67.92) v3(116.83,65.52) v3(118.13,83.24) v3(118.13,79.24) v3(118.13,77.64) v3(118.13,69.52) v3(118.13,67.92) v3(118.13,65.52) v3(118.13,63.92) v3(119.43,84.84) v3(119.43,81.64) v3(119.43,79.24) v3(119.43,76.04) v3(119.43,71.12) v3(119.43,65.52) v3(119.43,62.32) v3(120.73,83.24) v3(120.73,81.64) v3(120.73,79.24) v3(120.73,77.64) v3(120.73,69.52) v3(120.73,67.92) v3(120.73,65.52) v3(120.73,63.92) v3(121.38,82.44) v3(121.38,78.44) v3(121.38,68.72) v3(121.38,64.72) v4(124.59,94.15) v4(124.59,93.52) v4(125.22,94.15) v4(125.22,93.52) v4(125.86,94.15) v4(125.86,93.52)
VCC_DDR_VDD1: length 3.9
  BOTTOM w0.254: C512.1 118.17,84.88 v3(118.13,84.84) ; v3(110.98,76.04) 110.98,75.32 C510.1 ; v3(118.13,71.12) 118.13,71.64 C1257.1 ; C1255.1 110.98,61.57 v3(110.98,62.32)
  vias: v1(117.86,88.31) v1(117.86,87.68) v1(118.49,88.31) v1(118.49,87.68) v1(119.13,88.31) v1(119.13,87.68) v3(110.98,84.84) v3(110.98,71.12) v3(111.63,82.44) v3(111.63,78.44) v3(111.63,68.72) v3(111.63,64.72) v3(117.48,82.44) v3(117.48,78.44) v3(117.48,68.72) v3(117.48,64.72) v3(118.13,76.04) v3(118.13,62.32)
VCCA_PLL4: length 1.2
  TOP w0.381: U3.AA13 v2(75.9,75.93)
  BOTTOM w0.254: v2(75.9,75.93) 76.08,76.11 C289.1
  vias: v4(115.32,109.27) v4(116.21,109.27) v4(116.97,109.27)
VCCA_PLL7: length 1.3
  TOP w0.381: U3.Y16 v2(78.9,76.93)
  BOTTOM w0.254: C292.1 79.1,77.13 v2(78.9,76.93)
  vias: v4(115.42,102.54) v4(116.08,102.54) v4(116.74,102.54)
VCCA_PLL10: length 1.1
  TOP w0.381: U3.AA23 v2(86.9,75.93)
  BOTTOM w0.254: v2(86.9,75.93) 87.08,76.11 C290.1
  vias: v4(107.31,52.12) v4(107.31,51.35) v4(107.95,52.12) v4(107.94,51.42)
VCCA_PLLW: length 1.2
  TOP w0.381: U3.P12 v2(74.9,83.93)
  BOTTOM w0.254: v2(74.9,83.93) 74.9,83.64 C291.1
  vias: v6(98.93,96.85) v6(98.93,95.85) v6(98.93,94.85) v6(99.82,96.85) v6(99.82,95.85) v6(99.82,94.85)
VCCA_PLLW_IN: length 1.6
  TOP w0.381: R267.2 103.61,94.08 FB22.1
  vias: v4(103.63,93.49) v4(104.39,94.04)
VCCBAT_1V50: length 6.6
  TOP w0.381: U3.M16 v2(78.9,85.93)
  BOTTOM w0.381: R714.1 80.77,89.84 80.39,89.45 79.63,89.45 79.38,89.2 79.38,86.41 v2(78.9,85.93)
VCCIO0: length 4.3
  TOP w0.381: U3.V3 v2(65.9,78.93) ; U3.V7 v2(69.9,78.93) ; U3.M12 v2(74.9,85.93)
  BOTTOM w0.254: v2(74.9,85.93) 74.68,86.14 C598.1 ; C595.1 65.85,78.98 v2(65.9,78.93) 66.16,78.67 C597.1 ; C596.1 69.73,79.1 v2(69.9,78.93)
  vias: v4(46.63,104.26) v4(46.63,102.48) v4(47.52,105.15) v4(47.52,104.26) v4(47.52,103.37) v4(47.52,102.48)
VCCIO1: length 4
  TOP w0.381: U3.N8 v2(70.9,84.93) 70.4,85.43 U3.M7 v2(69.9,85.93) ; U3.N11 v2(73.9,84.93)
  BOTTOM w0.254: v2(69.9,85.93) 69.8,86.03 C590.1 ; v2(73.9,84.93) 73.83,85 C20.1 ; C589.1 71.14,85.17 v2(70.9,84.93)
  vias: v4(90.87,104.97) v4(90.87,104.03) v4(91.81,104.03) v4(92.65,104.97) v4(92.75,104.03) v4(93.69,104.03) v6(77.9,97.66) v6(78.9,97.66)
VCCIO1_IN: length 35.5
  TOP w0.381: R39.1 v4(47.25,119.81) ; U4.8 v4(58.29,124.25) ; R40.1 R41.1 v4(60.83,122.98)
  TOP w0.508: v4(59.18,99.11) R109.2 59.18,97.58 58.68,97.08 FB6.1
  L03-SIG1 w0.381: v4(59.18,99.11) 57.78,99.11 55.18,101.71 55.18,109.84 J3.10
  BOTTOM w0.254: v4(58.29,124.25) C23.2 C24.1 57.54,126.02 C25.1 ; R38.1 v4(48.25,125.39)
  BOTTOM w0.381: R59.2 v4(145.79,146.1) ; R60.2 v4(148.33,146.12) ; R56.2 v4(138.29,146.02) ; R61.2 v4(150.74,146.12) ; R58.2 v4(143.25,146.02) ; R57.2 v4(140.71,146.02)
  vias: v4(56.13,138.48) v4(56.9,138.48) v4(56.9,137.59) v4(57.66,138.48) v4(91.82,108.38) v4(91.82,107.49) v4(92.71,108.38) v4(92.71,107.49) v4(92.71,106.6)
VCCIO2: length 4.2
  TOP w0.381: U3.M10 v2(72.9,85.93) ; U3.R4 v2(66.9,82.93) ; U3.R2 v2(64.9,82.93)
  BOTTOM w0.254: v2(72.9,85.93) 73.02,86.05 C587.1 ; v2(66.9,82.93) 67.1,82.73 C584.1 ; v2(64.9,82.93) 65.22,82.61 C588.1 ; v2(62.55,83.93) 62.5,83.99 C586.1
  vias: v4(57.02,85.14) v4(57.78,85.14)
VCCIO2_IN: length 37.1
  TOP w0.305: v1(55.92,104.99) 55.92,110.83 v1(57.03,111.94)
  L10-SIG3 w0.305: v1(57.03,111.94) 56.77,112.19 40.26,112.19 v1(39.58,111.5)
  BOTTOM w0.305: v1(57.03,111.94) R25.2 57.83,112.62 58.42,113.2 61.09,113.2 63.65,110.64 R24.2 63.65,108.24 R22.1
  BOTTOM w0.381: R26.1 v1(55.92,104.99)
  vias: v1(54.23,85.26) v1(54.86,85.26) v1(55.5,85.26)
VCCIO3: length 12.3
  TOP w0.381: U3.AB6 v2(68.9,74.93) ; U3.AC11 v2(73.9,73.93) ; U3.AB9 v2(71.9,74.93) ; U3.AB3 v2(65.9,74.93)
  BOTTOM w0.254: v2(71.9,74.93) 71.64,75.19 C39.1 ; C38.1 73.75,74.08 v2(73.9,73.93) ; R712.2 62.75,73.45 68.07,73.45 68.33,73.71 68.33,74.36 v2(68.9,74.93) 69.19,75.22 C531.1
  BOTTOM w0.305: C616.1 73.91,73.92 v2(73.9,73.93)
  vias: v4(69.9,116.3) v4(69.9,115.07) v4(71.71,114.02) v4(73.29,116.45) v4(73.36,115.16)
VCCIO4: length 10.7
  TOP w0.381: U3.AE8 v2(70.9,71.93) ; U3.AN2 v2(64.9,63.93) ; U3.AG4 v2(66.9,69.93) ; U3.AK3 v2(65.9,66.93)
  BOTTOM w0.254: C532.1 65.77,66.93 v2(65.9,66.93) ; C44.1 71.15,71.68 v2(70.9,71.93) ; C43.1 64.59,63.63 v2(64.9,63.93) ; v6(65.9,98.68) 65.87,98.71 C615.1 ; v6(66.9,98.68) 66.89,98.69 C41.1 ; R713.2 66.35,69.38 v2(66.9,69.93) 66.68,70.15 C42.1
  vias: v4(77.62,115.38) v4(77.61,113.7) v4(79.28,115.4) v4(79.38,113.7)
VCCIO5: length 14.1
  TOP w0.381: U3.AH12 v2(74.9,68.93) ; U3.AL7 v2(69.9,65.93) ; U3.AJ9 v2(71.9,67.93) ; U3.AD14 v2(76.9,72.93)
  BOTTOM w0.254: C55.1 72.92,97.68 v6(72.9,97.66) ; C533.1 71.64,68.19 v2(71.9,67.93) ; v2(76.9,72.93) 76.72,73.11 C56.1 ; v2(74.9,68.93) 74.68,69.14 C58.1 ; R711.2 63.25,65.45 69.42,65.45 v2(69.9,65.93) 70.02,66.06 C57.1 ; C614.1 73.83,97.73 v6(73.9,97.66)
  vias: v4(87.06,115.47) v4(87.8,114.03) v4(88.39,115.6) v4(89.66,114.06)
VCCIO6: length 5
  TOP w0.381: U3.AJ15 v2(77.9,67.93) ; U3.AL12 v2(74.9,65.93) ; U3.AL15 v2(77.9,65.93) ; U3.AD16 v2(78.9,72.93)
  BOTTOM w0.254: v2(78.9,72.93) 79.13,72.7 C65.1 ; C66.1 75.17,65.93 v2(74.9,65.93) 74.87,65.9 C64.1 ; v2(77.9,67.93) 77.61,68.22 C579.1 ; v2(77.9,65.93) 78.11,65.71 C580.1
  vias: v4(110.57,111.95) v4(110.57,111.19) v4(110.57,110.43) v4(111.62,111.94) v4(111.62,111.18) v4(111.62,110.42)
VCCIO6_IN: length 42
  TOP w0.305: C732.1 110.31,38.85 v4(110.74,39.29)
  L05-SIG2 w0.381: v4(72.64,51.23) 72.28,50.86 65.93,50.86 63.2,48.13 v4(60.21,48.13)
  BOTTOM w0.254: v4(110.74,39.29) 110.61,39.15 U46.8
  BOTTOM w0.305: v4(52.83,132.63) 52.32,133.14 R21.1
  BOTTOM w0.381: R36.1 R37.1 v4(51.32,48.13) ; R48.1 v4(65.02,132.63) ; R32.1 R33.1 v4(56.4,48.13) ; R34.1 R35.1 v4(53.86,48.13) ; R47.1 v4(59.82,132.63) ; v4(58.94,48.13) R31.1 R30.1 ; R542.2 R543.2 80.15,56.58 74.8,51.23 v4(72.64,51.23)
  vias: v4(108.59,34.97) v4(108.59,34.08) v4(117.22,112.82) v4(117.22,111.93) v4(117.98,112.82) v4(119.9,131.17) v4(119.9,129.56) v4(119.9,127.78) v4(121.48,131.17) v4(121.48,129.56) v4(121.48,127.78) v4(122.96,131.17) v4(122.96,129.56) v4(122.96,127.78)
VCCIO7: length 5.3
  TOP w0.381: U3.AL19 v2(82.9,65.93) ; U3.AL22 v2(85.9,65.93) ; U3.AD18 v2(81.9,72.93) ; U3.AG19 v2(82.9,69.93)
  BOTTOM w0.254: C539.1 85.68,65.71 v2(85.9,65.93) ; C618.1 80.89,73.32 C537.1 81.53,73.29 v2(81.9,72.93)
  BOTTOM w0.381: C543.1 v4(87.71,97.71)
  vias: v4(105.51,116.64) v4(105.54,117.52) v4(106.3,117.52) v4(106.3,116.63)
VCCIO8: length 12.4
  TOP w0.381: U3.AM27 v2(90.9,64.93) ; U3.AF22 v2(85.9,70.93) ; U3.AC19 v2(82.9,73.93) ; U3.AJ24 v2(87.9,67.93)
  BOTTOM w0.254: R710.2 88.77,62.28 88.39,62.66 88.39,67.44 v2(87.9,67.93) 88.14,68.17 C541.1 ; v2(85.9,70.93) 85.76,70.79 C536.1 ; C535.1 82.69,74.14 v2(82.9,73.93) ; C540.1 90.67,64.7 v2(90.9,64.93)
  BOTTOM w0.508: v6(98.69,61.08) 98.66,61.05 C617.1 ; v6(99.69,61.08) 99.67,61.07 C534.1
  vias: v4(112.78,118.24) v4(112.82,116.06) v4(113.7,117.51) v4(114.46,118.18) v4(114.5,116.02)
VCCIO10: length 24.6
  TOP w0.305: U3.W27 v2(90.9,77.93)
  TOP w0.381: U3.AC28 v2(91.9,73.93) ; U3.AC31 94.9,74.93 v2(94.9,74.93) ; U3.V23 v2(85.9,79.93) ; U3.AD24 v2(87.9,72.93) ; U3.AP33 v2(96.9,62.93) ; U3.AH31 v2(94.9,68.93) ; U3.AH27 v2(90.9,68.93) ; U3.AB22 v2(85.9,74.93) ; U3.AA25 v2(88.9,75.93) ; U3.W31 v2(94.9,77.93) ; U3.AL31 v2(94.9,65.93)
  BOTTOM w0.254: C507.1 v2(85.9,79.93) ; C476.1 85.7,74.73 v2(85.9,74.93) ; C631.1 91.92,73.93 v2(91.9,73.93) 91.68,73.72 C478.1 90.82,73.72 R685.2 ; C547.1 94.93,65.9 v2(94.9,65.93) 95.11,66.15 C545.1 ; v2(94.9,77.93) 95.11,78.15 C509.1 ; C473.1 88.13,73.16 v2(87.9,72.93) ; C465.1 91.18,78.21 v2(90.9,77.93) 90.42,78.4 90.42,79.17 89.92,79.68 R294.2 ; C488.1 95.56,75.59 v2(94.9,74.93) 95.11,74.71 C480.1 ; C468.1 88.68,76.15 v2(88.9,75.93) ; C542.1 97.15,62.68 v2(96.9,62.93) 96.96,62.99 C483.1 ; C485.1 94.93,68.9 v2(94.9,68.93) 95.11,69.15 C546.1 93.84,70.67 R290.2 ; v2(90.9,68.93) 91.18,69.21 C548.1
  vias: v4(93.73,116.25) v4(93.73,115.54) v4(93.73,114.85) v4(94.49,116.25) v4(94.49,115.54) v4(94.49,114.85)
VCCIO12: length 4.4
  TOP w0.381: U3.P16 v2(78.9,83.93) ; U3.M14 v2(76.9,85.93) ; U3.N18 v2(81.9,84.93)
  BOTTOM w0.254: v2(76.9,85.93) 77.18,85.64 C31.1 ; C33.1 80.82,85.13 C32.1 81.7,85.13 v2(81.9,84.93) ; v2(78.9,83.93) 79.11,83.72 C526.1
  vias: v4(80.57,102.08) v4(80.57,101.15) v4(81.51,101.15) v4(82.35,102.08) v4(82.45,101.15)
VCCIO12_IN:
  vias: v4(80.56,104.59) v4(80.56,103.65) v4(81.5,104.59) v4(82.34,103.65) v4(82.44,104.59) v4(135.38,136.32) v4(135.43,135.48) v4(136.4,136.32) v4(136.4,135.43) v5(113.41,136.57) v5(113.41,135.81) v5(114.05,135.81) v5(114.81,135.81) v5(115.44,135.81)
VCCIO13: length 3.9
  TOP w0.381: U3.T16 v2(78.9,81.93) ; U3.T14 v2(76.9,81.93) ; U3.M13 v2(75.9,85.93)
  BOTTOM w0.254: v2(76.9,81.93) 77.11,81.72 C527.1 ; C529.1 76.18,85.65 v2(75.9,85.93) ; v2(78.9,81.93) 79.11,81.72 C530.1
  BOTTOM w0.381: C528.1 v2(76.26,97.89)
  vias: v4(64.18,112.37) v4(66.18,115.07) v4(66.19,113.67) v4(66.26,111.65)
VCCIO14: length 4.6
  TOP w0.381: U3.U11 v2(73.9,80.93) ; U3.N12 v2(74.9,84.93) ; U3.U9 v2(71.9,80.93)
  BOTTOM w0.254: v2(74.9,84.93) 75.18,84.65 C592.1 ; C593.1 73.8,80.83 v2(73.9,80.93) ; v2(71.9,80.93) 72.13,80.7 C594.1 72.13,80.07 72.45,79.74 C591.1
  vias: v4(65.29,106.48) v4(65.29,105.54) v4(66.23,105.54) v4(67.07,106.48) v4(67.17,105.54) v4(68.11,105.54)
VCCPLL_0V82: length 93.4
  TOP w0.254: v4(112.46,52.15) 112.46,52.56 108.71,56.31 106.93,56.31 101.73,61.51 101.73,64.05 101.35,64.43 R584.1 ; U44.1 101.66,106.95 v4(101.38,107.23)
  TOP w0.381: v4(109.09,107.11) v4(109.09,107.87) 109.09,114.47 111.76,117.14 111.76,133.02 112.52,133.78 137.54,133.78 141.35,129.97 153.8,129.97 154.46,130.63 v4(154.46,131.82)
  BOTTOM w0.381: R547.2 154.47,131.81 v4(154.46,131.82)
  vias: v4(100.3,108.02) v4(101.38,110.05) v4(101.38,109.11) v4(101.38,108.17) v4(102.43,110) v4(102.43,109.06) v4(102.43,108.12) v4(102.87,95.93) v4(102.89,95.07) v4(104.52,96.44) v4(104.52,95.8) v4(104.52,95.17) v4(108.97,104.82) v4(108.97,103.93) v4(109.73,107.11) v4(109.73,104.82) v4(112.49,50.81) v4(113.48,52.15) v4(113.5,50.81)
6_INCH_LONG_TRACE: length 150.3
  TOP w0.152: U3.AH13 v2(75.9,68.93) ; U3.AJ13 v2(75.9,67.93)
  BOTTOM w0.127: v2(75.9,68.93) 76.44,68.39 76.44,67.75 76.73,67.46 77.1,67.46 77.41,67.14 77.41,62.01 77.18,61.78 77.18,58.97 74.02,55.8 UNK6T.1 72.74,55.8 69.92,52.99 69.92,48.42 71.19,47.15 89.67,47.15 90.03,46.79 90.03,46.39 89.78,46.14 81.22,46.14 81.07,45.98 81.07,45.39 80.92,45.24 80.31,45.24 80.16,45.39 80.16,45.98 80,46.14 79.39,46.14 79.24,45.98 79.24,45.39 79.06,45.21 78.51,45.21 78.33,45.39 78.33,45.98 78.17,46.14 77.56,46.14 77.41,45.98 77.41,45.39 77.19,45.17 76.72,45.17 76.5,45.39 76.5,45.98 76.35,46.14 75.74,46.14 75.58,45.98 75.58,45.39 75.39,45.2 74.86,45.2 74.67,45.39 74.67,45.98 74.52,46.14 74.04,46.14 73.71,45.8 73.71,44.84 73.47,44.6 73.1,44.6 72.85,44.84 72.85,46.07 72.61,46.31 72.24,46.31 71.95,46.03 71.95,44.39 76.47,39.87 91.26,39.87 91.57,39.56 91.57,39.23 91.17,38.83 75.96,38.83 69.09,45.7 69.09,53.87 72.36,57.14 74.27,57.14 76.44,59.31 76.44,67.03 75.9,67.57 v2(75.9,67.93)
10_INCH_LONG_TRACE: length 253.4
  TOP w0.152: U3.AM11 v2(73.9,64.93) ; U3.AM10 v2(72.9,64.93)
  BOTTOM w0.127: v2(72.9,64.93) 72.5,64.93 72.03,64.46 71.63,64.46 71.37,64.2 71.37,62.38 66.92,57.94 66.92,44.67 75.13,36.47 92.21,36.47 93.78,38.04 93.78,40.99 92.74,42.03 77.87,42.03 77.58,42.32 77.58,42.91 77.85,43.18 92.85,43.18 93.78,44.11 93.78,47.74 92.19,49.33 71.73,49.33 71.18,49.87 71.18,51.91 72.53,53.26 UNK10T.1 74.17,53.26 76.6,55.69 76.6,56.07 76.3,56.37 75.87,56.37 73.98,54.48 72.43,54.48 70.5,52.54 70.5,49.1 71.4,48.2 90.59,48.2 91.73,47.06 91.73,45.16 90.86,44.29 75.96,44.29 75.38,43.71 75.38,42.52 76.92,40.98 92.11,40.98 92.66,40.43 92.66,38.62 91.77,37.73 75.43,37.73 67.65,45.51 67.65,57.68 72.37,62.4 72.37,64.16 72.64,64.43 73.39,64.43 73.89,64.93 v2(73.9,64.93)
12_MHZ: length 64.5
  L10-SIG3 w0.091: JP65.3 49.14,106.22 41.66,106.22 31.62,116.25 23.37,116.25 21.21,118.41 21.21,122.6 15.49,128.32 15.49,132.63 10.79,137.33 10.79,139.4 JP6.2
125_DIS: length 26.8
  TOP w0.127: JP15.2 57.66,100.63 R109.1 57.66,95.51 v1(58.55,94.62) X3.1 ; U3.L7 v2(69.9,86.93)
  BOTTOM w0.127: v2(69.9,86.93) 69.41,87.42 66.8,87.42 66.29,87.93 66.29,89.71 65.53,90.47 65.53,91.11 65.15,91.49 64.52,91.49 62.48,93.52 62.48,95.04 61.85,95.68 59.18,95.68 58.55,95.04 v1(58.55,94.62)
125_MHZ: length 15.1
  TOP w0.127: v1(60.26,90.66) 60.26,90.92 R110.2 ; U3.N7 v2(69.9,84.93)
  L10-SIG3 w0.091: v2(69.9,84.93) 69.47,84.5 68.45,84.5 68.33,84.63 68.33,85.14 68.07,85.39 66.8,85.39 65.53,86.66 65.53,88.06 65.15,88.44 64.26,88.44 62.48,90.22 60.71,90.22 v1(60.26,90.66)
ASC_CLK: length 4.4
  TOP w0.127: U45.G1 151.19,69.46 149.99,70.66 ASC_CLK.1
ASC_RDAT: length 16.3
  TOP w0.152: U45.E3 v3(155.24,71.46)
  L05-SIG2 w0.091: RDAT.1 156.16,84.87 156.16,81.25 157.25,80.16 157.25,74.55 156.91,74.21 156.91,73.56 157.21,73.25 157.21,72.9 156.95,72.64 155.8,72.64 155.24,72.08 v3(155.24,71.46)
ASC_WDAT: length 3.4
  TOP w0.127: WDAT.1 150.21,68.66 U45.H1
ASC_WRCLK: length 22.7
  TOP w0.152: U45.G2 v3(154.44,69.06)
  L05-SIG2 w0.091: v3(154.45,69.06) 154.45,69.86 155.59,71 156.17,71 156.72,71.55 156.72,71.89 157.5,72.67 157.84,72.67 158.11,72.94 158.11,73.25 157.88,73.48 157.51,73.48 157.28,73.71 157.28,74.02 157.64,74.38 157.64,82.61 157.35,82.9 157.35,85.82 WRCLK.1
B6_SCL: length 47.1
  TOP w0.127: v2(71.75,51.45) 61.04,40.74 57.53,40.74 JP64.3
  TOP w0.152: U3.AH16 v2(78.9,68.93)
  BOTTOM w0.127: R542.1 78.23,60.75 77.83,60.35 77.83,55.85 73.99,52.02 72.32,52.02 v2(71.75,51.45)
  BOTTOM w0.152: R542.1 78.7,62.75 79.37,63.41 79.37,68.12 78.9,68.59 v2(78.9,68.93)
B6_SDA: length 47
  TOP w0.127: v2(71.81,50.31) 58.63,37.14 JP64.1
  TOP w0.152: U3.AG16 v2(78.9,69.93)
  BOTTOM w0.127: v2(71.81,50.31) 75.04,50.31 81.35,56.62 81.35,60.09 80.69,60.75 R543.1
  BOTTOM w0.152: v2(78.9,69.93) 78.9,69.7 79.38,69.22 79.38,68.64 79.57,68.45 80.11,68.45 80.39,68.17 80.39,62.45 80.15,62.21 R543.1
CFGMODE: length 49.4
  TOP w0.127: v2(54.36,104.57) 54.74,104.19 54.74,90.84 60.12,85.46 60.67,85.46 61.63,84.49 62.81,84.49 63.87,83.43 U3.P1
  TOP w0.152: SW7.5 SW7.2 v2(42.09,109.9)
  L10-SIG3 w0.109: v2(54.36,104.57) 54.36,105.76 52.83,107.29 49.87,107.29 47.25,109.9 v2(42.09,109.9)
CSSPIN: length 72.3
  TOP w0.152: U3.P7 v2(69.9,83.93)
  L03-SIG1 w0.091: J3.8 51.84,115.72 44.73,115.72 43.31,117.14 JP51.1
  BOTTOM w0.127: v2(69.9,83.93) 69.9,83.94 69.27,84.58 69.27,85.09 69.06,85.29 64.87,85.29 62.76,87.4 59.21,87.4 55.12,91.49 55.12,98.22 54.1,99.23 51.82,99.23 48.77,102.28 48.77,107.87 42.67,113.97 42.67,121.53 JP51.1
DIP_SW1: length 42.2
  TOP w0.127: SW3.1 v4(60.21,51.43)
  TOP w0.152: U3.AA16 v2(78.9,75.93)
  L05-SIG2 w0.091: v2(78.9,75.93) 79.25,75.58 79.25,68.73 79.11,68.59 77.69,68.59 77.24,68.14 77.24,67.64 76.96,67.36 76.71,67.36 76.53,67.18 76.53,65.78 76.2,65.45 75.69,65.45 75.44,65.2 75.44,63.42 76.07,62.78 76.07,58.34 75.06,57.32 67.53,57.32 61.64,51.43 v4(60.21,51.43)
  BOTTOM w0.152: R30.2 v4(60.21,51.43)
DIP_SW2: length 43.7
  TOP w0.127: SW3.2 v4(58.94,51.43)
  TOP w0.152: U3.AA17 v2(79.9,75.93)
  L05-SIG2 w0.091: v2(79.9,75.93) 79.5,75.53 79.5,68.63 79.25,68.37 77.8,68.37 77.47,68.04 77.47,67.48 77.32,67.33 77.32,65.68 77.09,65.45 76.71,65.45 76.45,65.2 76.45,58.09 75.31,56.94 67.69,56.94 61.59,50.85 59.52,50.85 v4(58.94,51.43)
  BOTTOM w0.152: R31.2 v4(58.94,51.43)
DIP_SW3: length 36.6
  TOP w0.127: SW3.3 v4(57.67,51.43)
  TOP w0.152: U3.AL16 v2(78.9,65.93)
  L10-SIG3 w0.091: v4(57.67,51.43) 59.27,49.83 72.01,49.83 78.23,56.05 78.23,65.26 v2(78.9,65.93)
  BOTTOM w0.152: R32.2 v4(57.67,51.43)
DIP_SW4: length 37.4
  TOP w0.127: SW3.4 v4(56.4,51.43)
  TOP w0.152: U3.AM16 v2(78.9,64.93)
  L10-SIG3 w0.091: v4(56.4,51.43) 58.34,49.49 72.18,49.49 78.56,55.88 78.56,64.59 v2(78.9,64.93)
  BOTTOM w0.152: R33.2 v4(56.4,51.43)
DIP_SW5: length 49.5
  TOP w0.127: SW3.5 v4(55.13,51.43)
  TOP w0.152: U3.AB16 v2(78.9,74.93)
  L10-SIG3 w0.091: v4(55.13,51.43) 57.37,49.2 72.39,49.2 78.87,55.67 78.87,64.18 79.25,64.56 79.25,74.58 v2(78.9,74.93)
  BOTTOM w0.152: R34.2 v4(55.13,51.43)
DIP_SW6: length 51.5
  TOP w0.127: SW3.6 v4(53.86,51.43)
  TOP w0.152: U3.AB17 v2(79.9,74.93)
  L10-SIG3 w0.091: v2(79.9,74.93) 79.5,74.53 79.5,64.44 79.25,64.18 79.25,55.55 72.52,48.81 56.48,48.81 v4(53.86,51.43)
  BOTTOM w0.152: R35.2 v4(53.86,51.43)
DIP_SW7: length 38.9
  TOP w0.127: U3.AP16 79.4,57.99 73.48,52.07 71.3,52.07 68.27,49.04 53.08,49.04 52.59,49.54 SW3.7 v4(52.59,51.43)
  BOTTOM w0.152: R36.2 v4(52.59,51.43)
DIP_SW8: length 38.8
  TOP w0.127: SW3.8 v4(51.32,51.43) 51.96,52.08 69.55,52.08 71.98,54.51 75.29,54.51 78.91,58.13 78.91,63.94 U3.AN16
  BOTTOM w0.152: R37.2 v4(51.32,51.43)
DM: length 10.9
  TOP w0.117: U1.7 17.81,132.39 17.69,132.27 11.98,132.27 11.91,132.34 D3.3 D3.4 10.45,132.34 10.37,132.27 9.43,132.27 9.15,132.54 J2.2
DONE: length 41.6
  TOP w0.152: U3.U4 v2(66.9,80.93)
  L05-SIG2 w0.091: v2(66.9,80.93) 66.4,81.43 66.4,83.28 66.2,83.49 65.41,83.49 64.26,84.63 64.26,85.39 63.37,86.28 63.37,89.71 62.99,90.09 62.99,100.71 DONE.1
  BOTTOM w0.127: J3.4 54.99,111.3 54.99,109.14 55.36,108.77 R28.2 55.9,107.31 R26.2 56.41,107.29 DONE.1
DP: length 10.9
  TOP w0.117: J2.3 9.15,131.74 9.43,132.01 10.37,132.01 10.45,131.94 D3.5 D3.2 11.91,131.94 11.98,132.01 17.69,132.01 17.81,131.89 U1.8
DQ0_MOSI: length 70
  TOP w0.127: R46.1 60.06,119.55 59.39,118.87 56.52,118.87 55.63,117.98 J3.5
  TOP w0.152: U3.L12 v2(74.9,86.93)
  BOTTOM w0.127: J3.5 54.36,115.75 54.36,113.39 54.24,113.27 53.98,113.27 53.85,113.14 53.85,112.89 53.98,112.76 54.24,112.76 54.36,112.63 54.36,112.38 54.24,112.25 53.98,112.25 53.85,112.12 53.85,111.87 53.98,111.74 54.24,111.74 54.36,111.62 54.36,111.36 54.24,111.23 53.98,111.23 53.85,111.11 53.85,110.85 53.98,110.73 54.24,110.73 54.36,110.6 54.36,110.35 54.24,110.22 53.98,110.22 53.85,110.09 53.85,109.84 53.98,109.71 54.24,109.71 54.36,109.58 54.36,109.33 54.24,109.2 53.98,109.2 53.85,109.08 53.85,108.82 53.98,108.69 54.24,108.69 54.36,108.57 54.36,108.31 54.24,108.19 53.98,108.19 53.85,108.06 53.85,107.81 53.98,107.68 54.24,107.68 54.36,107.55 54.36,107.3 54.24,107.17 53.98,107.17 53.85,107.04 53.85,106.79 53.98,106.66 54.24,106.66 54.36,106.54 54.36,105.42 55.6,104.19 58.81,104.19 58.94,104.31 58.94,104.95 59.07,105.08 59.32,105.08 59.45,104.95 59.45,104.31 59.58,104.19 59.83,104.19 59.96,104.31 59.96,104.95 60.08,105.08 60.34,105.08 60.46,104.95 60.46,104.31 60.59,104.19 63.11,104.19 63.24,104.31 63.24,104.95 63.37,105.08 63.62,105.08 63.75,104.95 63.75,104.31 63.88,104.19 64.13,104.19 64.26,104.31 64.26,104.95 64.38,105.08 64.64,105.08 64.77,104.95 64.77,104.31 64.89,104.19 68.71,104.19 69.36,103.54 69.54,103.54 69.93,103.93 70.11,103.93 70.29,103.75 70.29,103.57 69.9,103.18 69.9,103 70.07,102.82 70.25,102.82 70.65,103.21 70.83,103.21 71.01,103.03 71.01,102.85 70.61,102.46 70.61,102.28 70.79,102.1 70.97,102.1 71.37,102.49 71.54,102.49 71.72,102.31 71.72,102.13 71.33,101.74 71.33,101.56 72.15,100.74 72.15,97.07 72.39,96.83 72.39,92.76 72.77,92.38 74.27,92.38 74.42,92.22 74.42,87.41 v2(74.9,86.93)
DQ1_MISO: length 71.1
  TOP w0.127: R43.1 46.51,122.98 46.02,122.5 46.02,119 46.79,118.23 46.79,116.25 47.14,115.9 51.97,115.9 J3.7
  TOP w0.152: U3.L11 v2(73.9,86.93)
  BOTTOM w0.127: J3.7 51.82,115.74 51.82,112.95 53.24,111.52 53.24,105.1 54.92,103.42 62.95,103.42 63.08,103.3 63.08,102.66 63.21,102.54 63.46,102.54 63.59,102.66 63.59,103.3 63.71,103.42 63.97,103.42 64.09,103.3 64.09,102.66 64.22,102.54 64.48,102.54 64.6,102.66 64.6,103.3 64.73,103.42 64.98,103.42 65.11,103.3 65.11,102.66 65.24,102.54 65.49,102.54 65.62,102.66 65.62,103.3 65.75,103.42 66,103.42 66.13,103.3 66.13,102.66 66.25,102.54 66.51,102.54 66.63,102.66 66.63,103.3 66.76,103.42 67.02,103.42 67.14,103.3 67.14,102.66 67.27,102.54 67.52,102.54 67.65,102.66 67.65,102.79 67.78,102.92 69.22,102.92 71.68,100.46 71.68,96.67 71.4,96.39 71.4,91.08 72.01,90.47 73.25,90.47 73.41,90.32 73.41,87.42 v2(73.9,86.93)
DQ2: length 71.6
  TOP w0.127: R45.2 46.81,121.71 46.51,121.41 46.51,119.53 48.01,118.03 J3.11
  TOP w0.152: U3.L10 v2(72.9,86.93)
  BOTTOM w0.127: v2(72.9,86.93) 72.39,87.44 72.39,89.18 72.14,89.43 69.57,89.43 69.34,89.66 69.34,96.19 67.59,97.94 61.22,97.94 61.1,98.07 61.1,98.47 60.97,98.6 60.71,98.6 60.59,98.47 60.59,98.07 60.46,97.94 60.21,97.94 60.08,98.07 60.08,98.47 59.95,98.6 59.7,98.6 59.57,98.47 59.57,98.07 59.44,97.94 58.4,97.94 58.27,98.07 58.27,99.49 58.15,99.61 57.89,99.61 57.77,99.49 57.77,98.07 57.64,97.94 57.3,97.94 56.64,98.6 56.64,99.54 56.52,99.67 55.75,99.67 55.63,99.8 55.63,100.05 55.75,100.18 56.52,100.18 56.64,100.3 56.64,101.58 56.52,101.71 56.14,101.71 56.01,101.58 56.01,100.88 55.89,100.76 55.63,100.76 55.51,100.88 55.51,101.58 55.38,101.71 55.12,101.71 55,101.58 55,100.88 54.87,100.76 54.62,100.76 54.49,100.88 54.49,101.58 54.36,101.71 54.11,101.71 53.98,101.58 53.98,100.88 53.85,100.76 53.6,100.76 53.47,100.88 53.47,101.58 53.35,101.71 53.09,101.71 52.97,101.58 52.97,100.88 52.84,100.76 52.58,100.76 52.46,100.88 52.46,101.58 52.33,101.71 51.63,101.71 49.88,103.45 49.88,108.66 46.86,111.68 46.86,115.87 J3.11
DQ3: length 68.4
  TOP w0.127: R44.1 v2(60.85,124.09)
  TOP w0.152: U3.L9 v2(71.9,86.93)
  BOTTOM w0.127: v2(71.9,86.93) 71.45,87.38 71.45,88.08 71.17,88.36 69.16,88.36 68.38,89.15 68.38,90.34 67.23,91.49 66.55,91.49 65.53,92.5 65.53,93.01 65.15,93.39 64.77,93.39 64.39,93.77 64.39,94.28 61.16,97.51 56.97,97.51 54.31,100.17 52.27,100.17 49.28,103.17 49.28,108.36 44.2,113.44 44.2,115.24 44.83,115.87 45.85,115.87 46.74,116.76 46.74,117.52 47.37,118.16 49.4,118.16 J3.9 51.94,118.41 55.17,118.41 v2(60.85,124.09)
EN_CORE_0V82: length 6.2
  TOP w0.203: U120.6 v1(139.06,71.74)
  BOTTOM w0.203: R703.2 139.01,71.79 v1(139.06,71.74) ; R708.1 138.31,72.95 R702.2
  BOTTOM w0.254: R704.1 R702.2 137.92,72.57 R703.2
EPS1_AN13_P: length 78.8
  TOP w0.099: U3.AN13 75.9,63.93 75.9,61.97 73.8,59.87 28.97,59.87 17.52,48.42 17.52,46.89 14.26,43.64 14.26,38.82 14.16,38.72 TP_AN13.1
EPS1_AP13_N: length 78.8
  TOP w0.099: TP_AP13.1 14.63,38.72 14.53,38.82 14.53,42.39 14.76,42.62 14.76,42.88 14.53,43.12 14.53,43.53 15.09,44.09 15.37,44.09 15.52,44.24 15.52,44.52 17.78,46.78 17.78,48.31 27.74,58.26 27.99,58.26 28.14,58.42 28.14,58.67 28.3,58.82 28.55,58.82 28.7,58.98 28.7,59.23 29.08,59.61 29.95,59.61 30.08,59.48 30.35,59.48 30.47,59.61 73.91,59.61 76.16,61.86 76.16,62.29 76.26,62.39 76.35,62.39 76.45,62.49 76.45,62.69 76.35,62.79 76.26,62.79 76.16,62.89 76.16,63.19 U3.AP13
EPS2_AJ16: length 105.3
  TOP w0.124: U3.AJ16 v2(78.9,67.93)
  L12-SIG4 w0.081: v2(78.9,67.93) 78.28,67.31 78.28,66.81 78.02,66.55 74.72,66.55 74.34,66.17 74.34,62.12 70.69,58.47 70.69,51.56 60.07,40.94 33.78,40.94 30.61,37.77 30.61,32.3 28.07,29.76 17.53,29.76 17.14,30.15 17.14,31.54 16.17,32.51 4.74,32.51 4.13,31.9 4.13,31.18 4.05,31.1 TP_AJ16.1
EPS2_AK16: length 105
  TOP w0.124: U3.AK16 v2(78.9,66.93)
  L12-SIG4 w0.081: TP_AK16.1 4.42,31.1 4.34,31.18 4.34,31.82 4.83,32.3 16.09,32.3 16.94,31.46 16.94,30.06 17.44,29.56 28.15,29.56 30.82,32.22 30.82,37.68 33.87,40.73 60.16,40.73 70.9,51.47 70.9,58.38 74.55,62.03 74.55,66.09 74.8,66.34 78.1,66.34 78.49,66.72 78.49,67.15 78.57,67.23 78.82,67.23 78.9,67.15 v2(78.9,66.93)
EPS3_AL13_P: length 86.3
  TOP w0.124: U3.AL13 v2(75.9,65.93)
  L10-SIG3 w0.081: TP_AL13.1 8.04,35.09 8.13,35.01 8.76,35.01 9.19,35.44 9.19,40.01 27.73,58.55 70.53,58.55 75.31,63.33 75.31,65.34 v2(75.9,65.93)
EPS3_AM13_N: length 86.6
  TOP w0.124: U3.AM13 v2(75.9,64.93)
  L10-SIG3 w0.081: v2(75.9,64.93) 75.9,65.32 75.82,65.4 75.67,65.4 75.52,65.26 75.52,63.25 70.61,58.34 27.81,58.34 9.4,39.92 9.4,35.35 8.85,34.8 8.13,34.8 8.04,34.72 TP_AM13.1
EPS4_AG15_P: length 89.3
  TOP w0.124: U3.AG15 v2(77.9,69.93)
  L12-SIG4 w0.081: TP_AG15.1 15.66,35.09 15.75,35.01 16.42,35.01 16.81,35.4 16.81,39.5 20,42.69 30.73,42.69 31.47,41.96 59.28,41.96 69.49,52.16 69.49,58.61 73.29,62.42 73.29,67.12 73.71,67.53 77.14,67.53 77.29,67.69 77.29,69.31 77.52,69.53 77.9,69.53 77.98,69.62 77.98,69.85 v2(77.9,69.93)
EPS4_AH15_N: length 89.2
  TOP w0.124: U3.AH15 v2(77.9,68.93)
  L12-SIG4 w0.081: v2(77.9,68.93) 77.9,69.24 77.82,69.33 77.61,69.33 77.5,69.22 77.5,67.6 77.23,67.33 73.8,67.33 73.5,67.03 73.5,62.33 69.7,58.53 69.7,52.08 59.37,41.75 31.38,41.75 30.65,42.49 20.09,42.49 17.02,39.42 17.02,35.31 16.51,34.8 15.75,34.8 15.66,34.72 TP_AH15.1
EPS5_AK12_N: length 90
  TOP w0.124: U3.AK12 v2(74.9,66.93)
  L10-SIG3 w0.081: TP_AK12.1 5.5,35.09 5.59,35.01 6.1,35.01 6.65,35.57 6.65,40.01 26.86,60.22 70.84,60.22 73.63,63.01 73.63,63.18 73.77,63.32 73.95,63.32 74.34,63.72 74.34,66.26 74.62,66.54 75.21,66.54 75.49,66.81 75.49,67 75.41,67.08 75.05,67.08 v2(74.9,66.93)
EPS5_AK13_P: length 89.6
  TOP w0.124: U3.AK13 v2(75.9,66.93)
  L10-SIG3 w0.081: TP_AK13.1 5.5,34.72 5.59,34.8 6.18,34.8 6.86,35.48 6.86,39.92 26.95,60.01 70.93,60.01 74.55,63.63 74.55,66.17 74.71,66.33 75.3,66.33 75.9,66.93 v2(75.9,66.93)
EPS6_AF15_P: length 92.9
  TOP w0.124: U3.AF15 v2(77.9,70.93)
  L12-SIG4 w0.081: TP_AF15.1 13.12,35.09 13.21,35.01 13.84,35.01 14.22,35.39 14.22,39.42 18.75,43.94 31.71,43.94 32.55,43.1 44.32,43.1 46.48,45.26 60.18,45.26 68.32,53.4 68.32,58.76 72.29,62.73 72.29,69.21 72.6,69.52 76.21,69.52 76.37,69.68 76.37,70.24 76.71,70.58 78.25,70.58 78.38,70.71 78.38,70.87 78.3,70.96 77.92,70.96 v2(77.9,70.93)
EPS6_AF16_N: length 92.9
  TOP w0.124: U3.AF16 v2(78.9,70.93)
  L12-SIG4 w0.081: v2(78.9,70.93) 78.34,70.37 76.8,70.37 76.58,70.15 76.58,69.59 76.3,69.31 72.69,69.31 72.5,69.12 72.5,62.64 68.53,58.67 68.53,53.31 60.27,45.05 46.57,45.05 44.41,42.89 32.47,42.89 31.62,43.73 18.84,43.73 14.43,39.33 14.43,35.31 13.93,34.8 13.21,34.8 13.12,34.72 TP_AF16.1
EPS7_AN12_N: length 80.8
  TOP w0.099: TP_AN12.1 9.08,38.72 9.18,38.82 9.18,40.46 15.99,47.27 15.99,49.18 27.7,60.89 73.16,60.89 74.92,62.65 74.92,63.95 U3.AN12
EPS7_AP12_P: length 80.9
  TOP w0.099: TP_AP12.1 9.55,38.72 9.45,38.82 9.45,39.42 9.55,39.52 9.55,39.92 9.45,40.02 9.45,40.35 9.75,40.65 10,40.65 10.15,40.81 10.15,41.06 10.31,41.21 10.56,41.21 10.71,41.37 10.71,41.62 10.87,41.78 11.12,41.78 11.3,41.96 11.3,42.21 16.26,47.16 16.26,49.07 26.6,59.42 26.86,59.42 27.01,59.57 27.01,59.82 27.16,59.98 27.42,59.98 27.57,60.13 27.57,60.38 27.81,60.63 73.27,60.63 73.97,61.32 74.25,61.32 74.38,61.45 74.38,61.73 74.5,61.86 74.79,61.86 74.94,62.01 74.94,62.29 75.18,62.54 75.18,63.22 U3.AP12
EPS8_AG14_N: length 98.7
  TOP w0.124: U3.AG14 v2(76.9,69.93)
  L10-SIG3 w0.081: TP_AG14.1 9.13,31.1 9.21,31.18 9.21,31.78 9.95,32.51 11.22,32.51 11.73,33.03 11.73,39.76 15.15,43.18 43.13,43.18 46.53,46.57 46.53,51.15 52.58,57.2 74.29,57.2 76.3,59.2 76.3,69.33 76.5,69.53 76.82,69.53 76.9,69.62 v2(76.9,69.93)
EPS8_AH14_P: length 99
  TOP w0.124: U3.AH14 v2(76.9,68.93)
  L10-SIG3 w0.081: v2(76.9,68.93) 76.9,69.24 76.82,69.33 76.59,69.33 76.5,69.24 76.5,59.11 74.38,56.99 52.66,56.99 46.74,51.06 46.74,46.49 43.22,42.97 17.39,42.97 17.26,42.85 17.06,42.85 16.94,42.97 16.74,42.97 16.61,42.85 16.41,42.85 16.29,42.97 16.09,42.97 15.96,42.85 15.76,42.85 15.64,42.97 15.24,42.97 14.58,42.31 14.58,42.19 14.41,42.02 14.29,42.02 13.33,41.06 13.33,40.93 13.16,40.76 13.03,40.76 12.87,40.6 12.87,40.47 12.7,40.3 12.57,40.3 11.94,39.67 11.94,32.94 11.3,32.3 10.03,32.3 9.9,32.17 9.9,32.02 9.74,31.86 9.59,31.86 9.42,31.69 9.42,31.18 9.5,31.1 TP_AH14.1
EPS9_AP10_P: length 83
  TOP w0.099: TP_AP10.1 4,38.72 4.1,38.82 4.1,39.58 4.83,40.31 7.24,40.31 14.48,47.54 14.48,49.45 26.92,61.9 72.77,61.9 73.73,62.85 73.73,63.1 U3.AP10
EPS9_AP11_N: length 83.1
  TOP w0.099: TP_AP11.1 4.47,38.72 4.37,38.82 4.37,39.47 4.94,40.04 7.35,40.04 14.74,47.44 14.74,49.34 27.03,61.63 72.88,61.63 73.99,62.74 73.99,63.02 U3.AP11
EPS10_AK14_P: length 94.9
  TOP w0.124: U3.AK14 v2(76.9,66.93)
  L10-SIG3 w0.081: TP_AK14.1 14.43,31.1 14.35,31.02 14.35,30.41 14.78,29.97 15.1,29.97 15.23,30.1 15.43,30.1 15.55,29.97 16.3,29.97 16.58,30.25 16.58,30.42 16.73,30.56 16.89,30.56 17.06,30.74 17.06,31.37 16.92,31.52 16.92,31.7 17.06,31.85 17.06,32.17 16.94,32.29 16.94,32.5 17.06,32.62 17.06,32.82 16.94,32.94 16.94,33.15 17.06,33.27 17.06,33.47 16.94,33.59 16.94,33.8 17.06,33.92 17.06,39.63 19.64,42.21 43.77,42.21 47.67,46.11 47.67,50.38 51.9,54.61 73.7,54.61 77.29,58.21 77.29,66.85 77.21,66.93 v2(76.9,66.93)
EPS10_AK15_N: length 94.7
  TOP w0.124: U3.AK15 v2(77.9,66.93)
  L10-SIG3 w0.081: v2(77.9,66.93) 77.58,66.93 77.5,66.85 77.5,58.12 73.79,54.4 51.98,54.4 47.88,50.3 47.88,46.02 43.86,42 19.73,42 17.27,39.54 17.27,30.65 16.38,29.76 14.69,29.76 14.14,30.32 14.14,31.02 14.06,31.1 TP_AK15.1
F_DDR_100MHZ_N: length 21.5
  TOP w0.099: v2(101.73,86.66) 101.73,87.17 101.85,87.3 R538.1
  TOP w0.124: v2(94.9,73.93) 94.9,73.93 U3.AD31
  BOTTOM w0.099: v2(94.9,73.93) 95.17,73.93 95.27,73.83 95.27,73.58 95.53,73.32 99.44,73.32 R491.2 100.08,73.45 100.71,73.45 101.48,74.21 101.48,86.41 v2(101.73,86.66)
F_DDR_100MHZ_P: length 21.1
  TOP w0.099: v2(100.97,86.66) 100.97,87.18 R537.1
  TOP w0.124: U3.AD32 95.9,73.93 v2(95.9,73.93)
  BOTTOM w0.099: v2(95.9,73.93) 95.63,73.93 95.53,73.83 95.53,73.69 95.64,73.58 97.32,73.58 97.41,73.68 97.41,73.79 97.51,73.88 97.71,73.88 97.81,73.79 97.81,73.68 97.91,73.58 99.18,73.58 R490.1 100.08,73.71 100.6,73.71 101.21,74.32 101.21,86.41 v2(100.97,86.66)
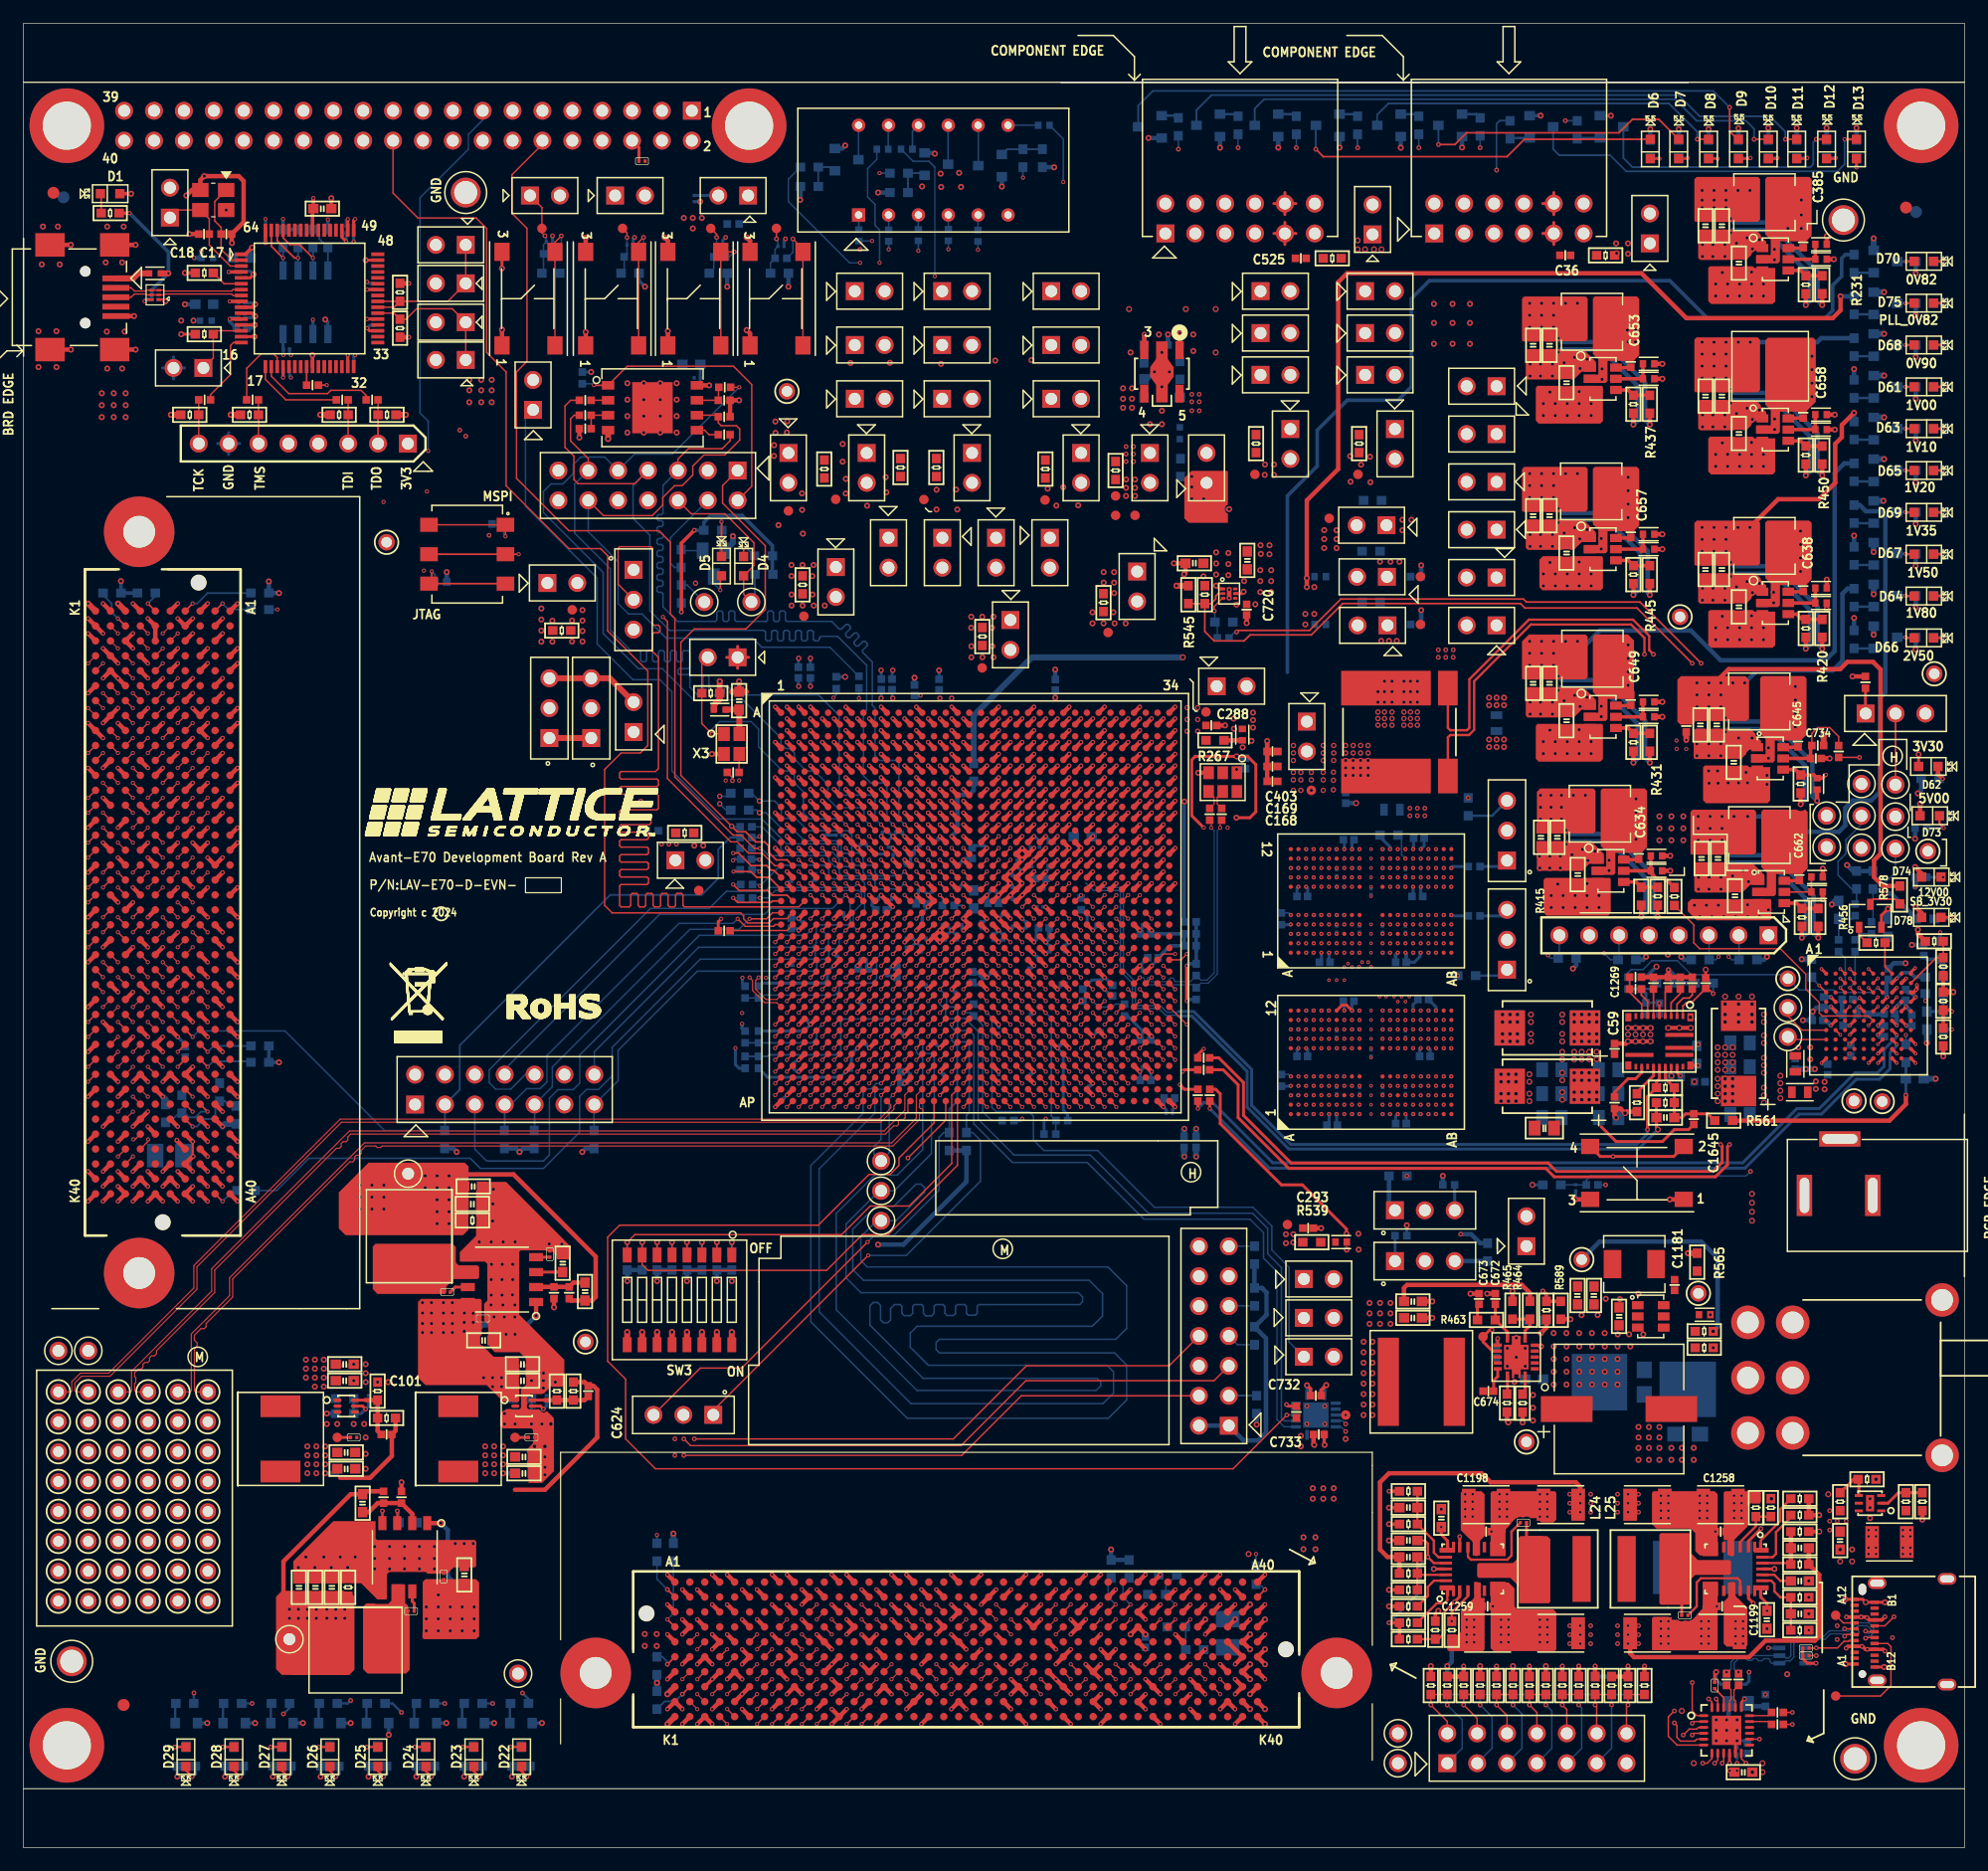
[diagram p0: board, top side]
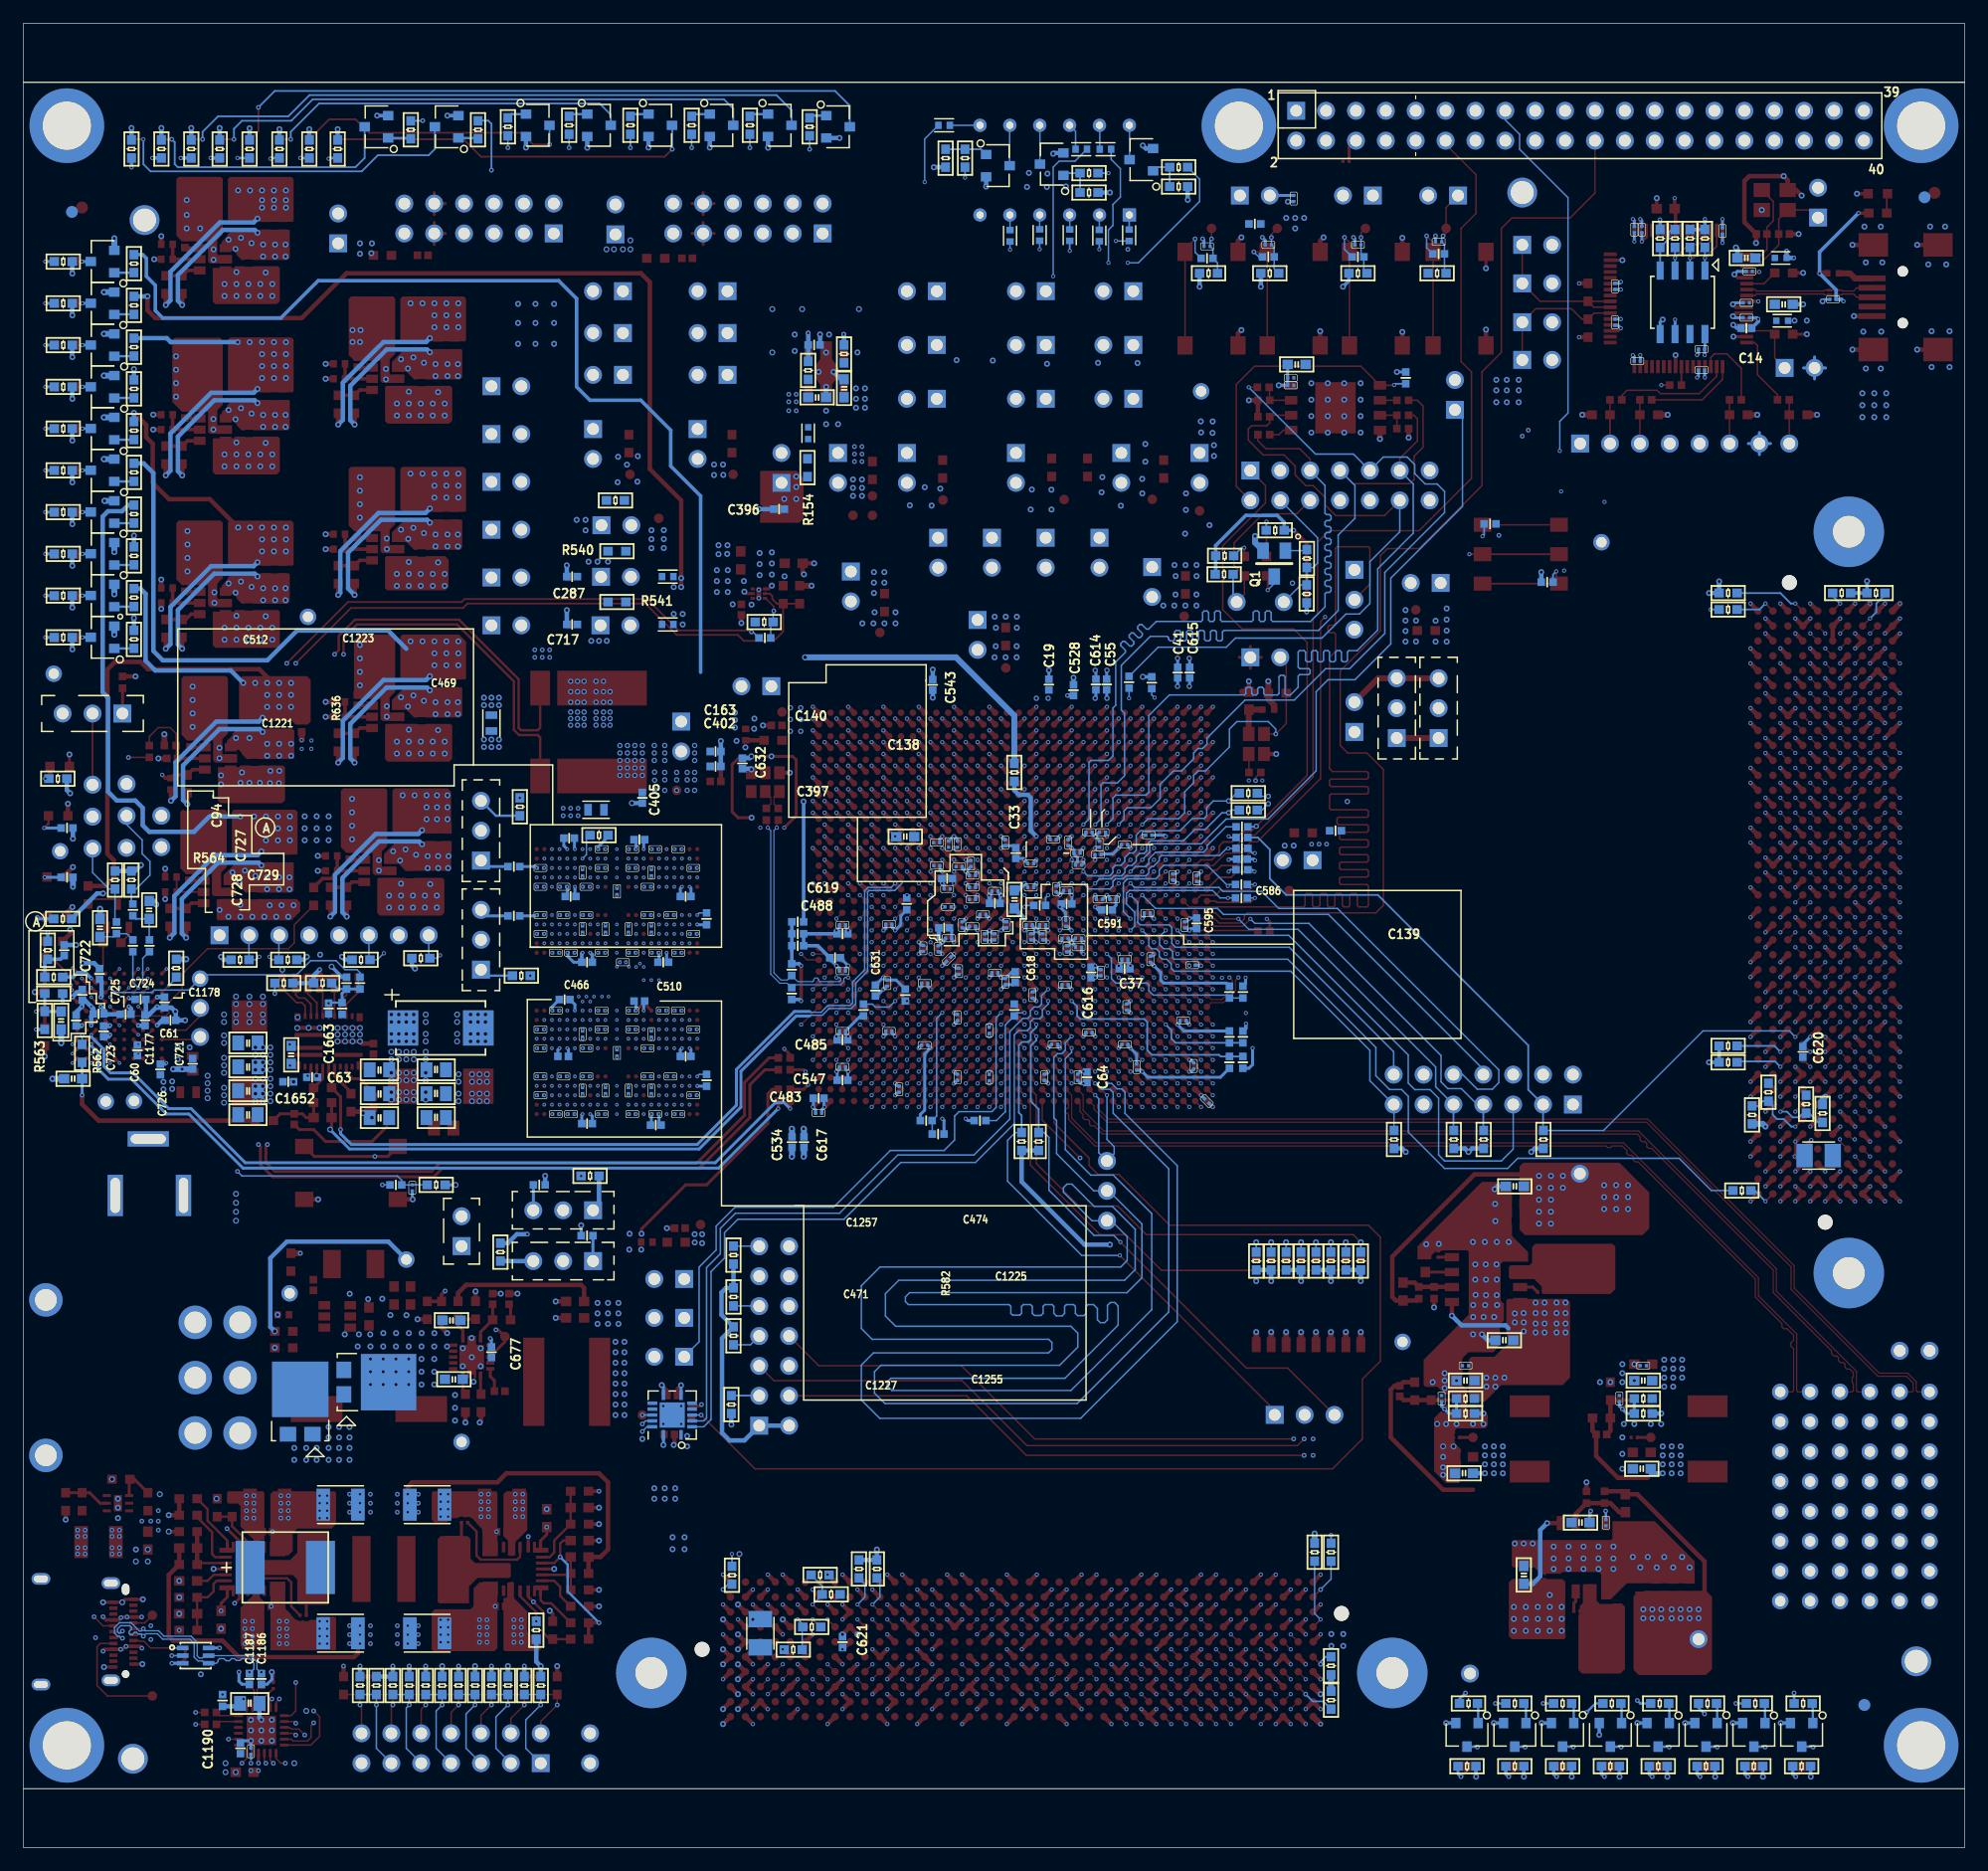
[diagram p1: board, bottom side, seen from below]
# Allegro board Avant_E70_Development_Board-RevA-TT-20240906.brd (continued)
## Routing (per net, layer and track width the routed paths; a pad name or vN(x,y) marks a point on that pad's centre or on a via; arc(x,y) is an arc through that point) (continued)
F_K_DIG1: length 74.8
  TOP w0.152: U3.W9 v2(71.9,77.93)
  L05-SIG2 w0.091: v2(71.12,134.67) 71.75,134.03 73.15,134.03 75.63,131.56 75.63,100.81 75.22,100.41 75.22,97.1 75.52,96.81 75.52,82.55 75.31,82.34 73.53,82.34 73.41,82.22 73.41,81.71 73.15,81.45 72.75,81.45 72.52,81.22 72.52,78.55 v2(71.9,77.93)
  BOTTOM w0.127: R343.1 65.02,141.78 65.02,139.87 70.23,134.67 v2(71.12,134.67)
F_K_DIG2: length 71.2
  TOP w0.152: U3.V9 v2(71.9,78.93)
  L05-SIG2 w0.109: v2(72.77,142.29) 72.39,142.29 67.69,137.59 67.69,121.73 69.15,120.27 69.15,113.37 72.23,110.29 72.23,102.61 73.44,101.4 73.44,98.88 74.28,98.04 74.28,84.74 73.91,84.37 73.79,84.37 73.41,83.99 73.41,83.87 72.9,83.36 72.62,83.36 72.37,83.1 72.37,81.53 72.28,81.44 72.28,79.31 v2(71.9,78.93)
  BOTTOM w0.152: R339.1 v2(72.77,142.29)
F_K_DIG3: length 79.7
  TOP w0.152: U3.R10 v2(72.9,82.93)
  L05-SIG2 w0.109: v2(84.96,141.91) 84.84,141.78 72.52,141.78 68.02,137.28 68.02,122.5 69.81,120.7 71.26,120.7 74.74,117.22 74.74,101.5 74.52,101.28 74.52,83.71 74.17,83.36 73.33,83.36 v2(72.9,82.93)
  BOTTOM w0.152: R341.1 v2(84.96,141.91)
FLASH_CS: length 31.5
  TOP w0.127: U4.1 51.32,125.88 60.35,125.88 61.9,124.32 61.9,115.67 60.71,114.47
  TOP w0.152: U4.1 48.51,124.25 v2(48.49,124.28)
  L03-SIG1 w0.091: v2(48.49,124.28) 48.46,124.25 43.77,124.25 JP51.2
  BOTTOM w0.152: v2(48.49,124.28) 48.38,124.39 R38.2
FMC1_CLK0_M2C_N: length 95.4
  TOP w0.124: U3.Y6 v2(68.9,76.93) ; J48.H5 v2(9.3,99.36)
  L05-SIG2 w0.081: v2(68.9,76.93) 69.14,76.93 69.24,77.03 69.24,77.24 69.11,77.36 58.68,77.36 56.45,79.59 51.73,79.59 51.18,80.15 51.18,80.44 51.41,80.67 51.41,80.78 51.18,81.01 51.06,81.01 50.83,80.78 50.54,80.78 50.19,81.13 50.19,81.42 50.42,81.65 50.42,81.77 50.19,82 50.08,82 49.85,81.77 49.56,81.77 49.21,82.12 49.21,82.41 49.44,82.64 49.44,82.75 49.21,82.98 49.09,82.98 48.86,82.75 48.57,82.75 48.22,83.1 48.22,83.39 48.45,83.62 48.45,83.74 48.22,83.97 48.11,83.97 47.88,83.74 47.59,83.74 47.24,84.09 47.24,84.38 47.47,84.61 47.47,84.72 47.24,84.95 47.12,84.95 46.89,84.72 46.6,84.72 46.25,85.07 46.25,85.36 46.48,85.59 46.48,85.71 46.25,85.94 46.14,85.94 45.91,85.71 45.62,85.71 45.27,86.06 45.27,86.35 45.5,86.58 45.5,86.69 45.27,86.92 45.15,86.92 44.92,86.69 44.63,86.69 44.28,87.04 44.28,87.33 44.51,87.56 44.51,87.68 44.28,87.91 44.17,87.91 43.94,87.68 43.65,87.68 43.3,88.03 43.3,88.32 43.53,88.55 43.53,88.66 43.3,88.89 43.18,88.89 42.95,88.66 42.66,88.66 42.31,89.01 42.31,89.3 42.54,89.53 42.54,89.65 42.31,89.88 42.2,89.88 41.97,89.65 41.68,89.65 41.33,90 41.33,90.29 41.56,90.52 41.56,90.63 41.33,90.86 41.21,90.86 40.98,90.63 40.69,90.63 32.59,98.74 32.45,98.74 32.29,98.9 32.29,99.04 32.13,99.2 31.99,99.2 31.83,99.36 31.83,99.5 31.43,99.89 31.08,99.89 30.96,99.77 30.76,99.77 30.63,99.89 30.43,99.89 30.31,99.77 30.11,99.77 29.98,99.89 28.79,99.89 28.71,99.81 28.71,98.85 28.51,98.64 28.01,98.64 27.81,98.85 27.81,99.81 27.73,99.89 27.4,99.89 27.32,99.81 27.32,98.87 27.12,98.67 26.62,98.67 26.42,98.87 26.42,99.81 26.34,99.89 26.01,99.89 25.93,99.81 25.93,98.93 25.73,98.73 25.23,98.73 25.02,98.93 25.02,99.81 24.94,99.89 24.62,99.89 24.54,99.81 24.54,98.93 24.33,98.73 23.84,98.73 23.63,98.93 23.63,99.81 23.55,99.89 23.23,99.89 23.15,99.81 23.15,99.1 22.94,98.9 22.44,98.9 22.24,99.1 22.24,99.81 22.16,99.89 21.83,99.89 21.75,99.81 21.75,99.1 21.55,98.9 21.05,98.9 20.85,99.1 20.85,99.81 20.77,99.89 20.44,99.89 20.36,99.81 20.36,99.1 20.16,98.9 19.66,98.9 19.46,99.1 19.46,99.81 19.38,99.89 9.38,99.89 9.3,99.81 v2(9.3,99.36)
FMC1_CLK0_M2C_P: length 95.4
  TOP w0.124: J48.H4 v2(9.3,100.63) ; U3.Y7 v2(69.9,76.93)
  L05-SIG2 w0.081: v2(69.9,76.93) 69.55,76.93 69.44,77.04 69.44,77.32 69.19,77.57 58.77,77.57 56.54,79.8 51.82,79.8 51.38,80.23 51.38,80.35 51.61,80.58 51.61,80.87 51.26,81.22 50.97,81.22 50.74,80.99 50.63,80.99 50.4,81.22 50.4,81.33 50.63,81.57 50.63,81.85 50.28,82.21 49.99,82.21 49.76,81.97 49.64,81.97 49.41,82.2 49.41,82.32 49.64,82.55 49.64,82.84 49.29,83.19 49,83.19 48.77,82.96 48.66,82.96 48.43,83.19 48.43,83.3 48.66,83.54 48.66,83.82 48.31,84.18 48.02,84.18 47.79,83.94 47.67,83.94 47.44,84.17 47.44,84.29 47.67,84.52 47.67,84.81 47.32,85.16 47.03,85.16 46.8,84.93 46.69,84.93 46.46,85.16 46.46,85.27 46.69,85.51 46.69,85.79 46.34,86.15 46.05,86.15 45.82,85.91 45.7,85.91 45.47,86.14 45.47,86.26 45.7,86.49 45.7,86.78 45.35,87.13 45.06,87.13 44.83,86.9 44.72,86.9 44.49,87.13 44.49,87.24 44.72,87.48 44.72,87.76 44.37,88.12 44.08,88.12 43.85,87.88 43.73,87.88 43.5,88.11 43.5,88.23 43.73,88.46 43.73,88.75 43.38,89.1 43.09,89.1 42.86,88.87 42.75,88.87 42.52,89.1 42.52,89.21 42.75,89.45 42.75,89.73 42.4,90.09 42.11,90.09 41.88,89.85 41.76,89.85 41.53,90.08 41.53,90.2 41.76,90.43 41.76,90.72 41.41,91.07 41.12,91.07 40.89,90.84 40.78,90.84 31.52,100.1 28.71,100.1 28.5,99.9 28.5,98.93 28.42,98.85 28.1,98.85 28.02,98.93 28.02,99.9 27.81,100.1 27.32,100.1 27.11,99.9 27.11,98.96 27.03,98.88 26.71,98.88 26.63,98.96 26.63,99.9 26.42,100.1 25.92,100.1 25.72,99.9 25.72,99.02 25.64,98.93 25.31,98.93 25.23,99.02 25.23,99.9 25.03,100.1 24.53,100.1 24.33,99.9 24.33,99.02 24.25,98.93 23.92,98.93 23.84,99.02 23.84,99.9 23.64,100.1 23.14,100.1 22.94,99.9 22.94,99.19 22.86,99.11 22.53,99.11 22.45,99.19 22.45,99.9 22.25,100.1 21.75,100.1 21.55,99.9 21.55,99.19 21.46,99.11 21.14,99.11 21.06,99.19 21.06,99.9 20.85,100.1 20.36,100.1 20.15,99.9 20.15,99.19 20.07,99.11 19.75,99.11 19.67,99.19 19.67,99.9 19.46,100.1 9.38,100.1 9.3,100.18 v2(9.3,100.63)
FMC1_CLK1_M2C_N: length 89.5
  TOP w0.124: 9.93,102.54 v2(10.57,101.9)
  TOP w0.152: U3.AE6 v2(68.9,71.93)
  L12-SIG4 w0.081: v2(68.9,71.93) 68.9,71.56 68.98,71.48 69.15,71.48 69.32,71.64 69.32,74.19 69.24,74.27 69.24,74.57 69.32,74.65 69.32,75.09 69.05,75.35 68.68,75.35 68.55,75.23 68.3,75.23 68.18,75.35 63.34,75.35 62.65,76.04 50.33,76.04 48.22,78.15 43.27,78.15 32.46,88.96 32.46,89.25 33.11,89.9 33.11,90.01 32.88,90.24 32.76,90.24 32.11,89.59 31.83,89.59 31.47,89.94 31.47,90.23 32.12,90.88 32.12,91 31.89,91.23 31.78,91.23 31.13,90.58 30.84,90.58 30.49,90.93 30.49,91.22 31.14,91.87 31.14,91.98 30.91,92.21 30.79,92.21 30.14,91.56 29.86,91.56 26.28,95.14 26.28,95.42 26.84,95.98 26.84,96.1 26.61,96.33 26.5,96.33 25.94,95.77 25.65,95.77 25.3,96.12 25.3,96.41 25.98,97.1 25.98,97.21 25.75,97.44 25.64,97.44 24.95,96.75 24.66,96.75 24.31,97.11 24.31,97.39 25,98.08 25,98.2 24.77,98.43 24.65,98.43 23.97,97.74 23.68,97.74 20.28,101.14 11.43,101.14 11.05,101.52 11.05,102.3 10.92,102.43 10.65,102.43 10.57,102.35 v2(10.57,101.9)
FMC1_CLK1_M2C_P: length 89.8
  TOP w0.124: J48.G2 v2(10.57,103.17)
  TOP w0.152: U3.AF6 v2(68.9,70.93)
  L12-SIG4 w0.081: v2(68.9,70.93) 69.52,71.56 69.52,75.18 69.14,75.56 63.42,75.56 62.74,76.25 50.42,76.25 48.31,78.36 43.35,78.36 32.67,89.05 32.67,89.16 33.32,89.81 33.32,90.1 32.96,90.45 32.68,90.45 32.03,89.8 31.91,89.8 31.68,90.03 31.68,90.15 32.33,90.8 32.33,91.08 31.98,91.44 31.69,91.44 31.04,90.79 30.93,90.79 30.7,91.02 30.7,91.13 31.35,91.78 31.35,92.07 30.99,92.42 30.71,92.42 30.06,91.77 29.94,91.77 26.49,95.22 26.49,95.34 27.05,95.9 27.05,96.19 26.7,96.54 26.41,96.54 25.85,95.98 25.74,95.98 25.51,96.21 25.51,96.32 26.19,97.01 26.19,97.3 25.84,97.65 25.55,97.65 24.87,96.96 24.75,96.96 24.52,97.19 24.52,97.31 25.21,98 25.21,98.28 24.86,98.64 24.57,98.64 23.88,97.95 23.77,97.95 20.37,101.35 11.52,101.35 11.26,101.61 11.26,102.39 11.01,102.64 10.65,102.64 10.57,102.72 v2(10.57,103.17)
FMC1_CLK2_M2C_N: length 87.3
  TOP w0.099: J48.K5 v2(6.76,100.63)
  TOP w0.124: U3.AJ6 v2(68.9,67.93)
  L12-SIG4 w0.081: v2(68.9,67.93) 68.58,67.93 68.5,68.01 68.5,68.3 68.63,68.42 68.63,68.63 68.5,68.75 68.5,69.16 68.63,69.29 68.63,69.52 68.5,69.64 68.5,70.23 68.63,70.35 68.63,70.56 68.5,70.69 68.5,74.23 68.19,74.55 63.42,74.55 62.48,75.48 49.7,75.48 48.3,76.88 47.59,76.88 47.34,77.14 46.81,77.14 46.55,76.88 46.2,76.88 45.95,77.14 45.42,77.14 45.16,76.88 44.81,76.88 44.55,77.14 44.03,77.14 43.77,76.88 42.93,76.88 21.08,98.73 19.87,98.73 19.79,98.81 19.79,99.56 19.58,99.77 19.09,99.77 18.88,99.56 18.88,98.81 18.8,98.73 18.48,98.73 18.4,98.81 18.4,99.56 18.19,99.77 17.69,99.77 17.49,99.56 17.49,98.81 17.41,98.73 6.52,98.73 6.23,99.02 6.23,100.55 6.31,100.63 v2(6.76,100.63)
FMC1_CLK2_M2C_P: length 87
  TOP w0.099: J48.K4 v2(5.49,100.63)
  TOP w0.124: U3.AJ5 v2(67.9,67.93)
  L12-SIG4 w0.081: v2(5.49,100.63) 5.94,100.63 6.02,100.55 6.02,98.93 6.43,98.52 17.5,98.52 17.7,98.72 17.7,99.48 17.78,99.56 18.11,99.56 18.19,99.48 18.19,98.72 18.39,98.52 18.89,98.52 19.09,98.72 19.09,99.48 19.17,99.56 19.5,99.56 19.58,99.48 19.58,98.72 19.78,98.52 21,98.52 42.84,76.67 43.86,76.67 44.11,76.93 44.47,76.93 44.72,76.67 45.25,76.67 45.5,76.93 45.86,76.93 46.11,76.67 46.64,76.67 46.9,76.93 47.25,76.93 47.5,76.67 48.21,76.67 49.61,75.28 62.4,75.28 63.33,74.34 68.1,74.34 68.29,74.15 68.29,68.01 68.21,67.93 v2(67.9,67.93)
FMC1_CLK3_M2C_N: length 84.6
  TOP w0.099: v2(62.48,73.93) 62.24,73.69 62.24,72.93 63.11,72.06 64.03,72.06 U3.AE1 ; 7.39,102.54 v2(8.03,101.9)
  L12-SIG4 w0.081: v2(8.03,101.9) 8.03,102.35 7.95,102.43 7.4,102.43 7.3,102.33 7.04,102.33 6.95,102.43 6.24,102.43 6.01,102.21 6.01,102.05 5.86,101.9 5.7,101.9 5.55,101.75 5.55,101.59 5.4,101.44 5.24,101.44 4.95,101.15 4.95,99.73 5.08,99.61 5.08,99.41 4.95,99.28 4.95,99.08 5.08,98.96 5.08,98.76 4.95,98.63 4.95,98.09 5.46,97.58 5.8,97.58 5.93,97.71 6.13,97.71 6.25,97.58 6.45,97.58 6.58,97.71 6.78,97.71 6.9,97.58 7.1,97.58 7.23,97.71 7.43,97.71 7.55,97.58 20.45,97.58 25.39,92.64 25.39,92.35 24.69,91.65 24.69,91.53 24.92,91.3 25.04,91.3 25.74,92 26.03,92 26.38,91.65 26.38,91.36 25.73,90.72 25.73,90.6 25.96,90.37 26.07,90.37 26.72,91.02 27.01,91.02 42.16,75.87 47.75,75.87 48.9,74.72 62,74.72 62.21,74.52 62.21,74.21 v2(62.48,73.93)
FMC1_CLK3_M2C_P: length 84.9
  TOP w0.099: v2(61.72,73.93) 61.98,73.68 61.98,72.83 63,71.8 64.03,71.8 U3.AF1 ; J48.J2 v2(8.03,103.17)
  L12-SIG4 w0.081: v2(8.03,103.17) 8.03,102.72 7.95,102.64 6.15,102.64 4.74,101.24 4.74,98 5.37,97.37 20.36,97.37 25.18,92.55 25.18,92.44 24.48,91.74 24.48,91.45 24.84,91.1 25.12,91.1 25.82,91.8 25.94,91.8 26.17,91.57 26.17,91.45 25.52,90.8 25.52,90.51 25.87,90.16 26.16,90.16 26.81,90.81 26.92,90.81 42.08,75.66 47.67,75.66 48.81,74.51 60.22,74.51 60.37,74.37 60.54,74.37 60.69,74.51 60.87,74.51 61.02,74.37 61.19,74.37 61.34,74.51 61.92,74.51 62,74.43 62,74.21 v2(61.72,73.93)
FMC1_GA0: length 5.2
  TOP w0.152: J48.C34 v2(15.65,62.53)
  BOTTOM w0.152: R251.2 12.42,61.62 13.21,62.4 R249.1 13.72,62.4 14.07,62.05 14.61,62.05 15.09,62.53 v2(15.65,62.53)
FMC1_GA1: length 6.1
  TOP w0.152: J48.D35 v2(14.38,61.26)
  BOTTOM w0.152: v2(14.38,61.26) 14.73,61.26 15.37,61.9 15.93,61.9 16.31,62.28 16.31,63.06 R250.1 17.12,63.42 17.53,63.01 R252.2
FMC1_HA00_CLK_N: length 93
  TOP w0.124: J48.F5 v2(11.84,100.63) ; U3.AJ11 v2(73.9,67.93)
  L05-SIG2 w0.081: v2(73.9,67.93) 74.21,67.93 74.29,68.01 74.29,73.17 74.14,73.33 74.14,73.5 74.29,73.66 74.29,74.05 74,74.34 72.64,74.34 72.31,74.68 72.31,75.02 72,75.33 71.62,75.33 71.29,75.65 71.29,76.03 71.03,76.29 70.65,76.29 70.28,76.67 70.28,78.07 70.01,78.33 58.96,78.33 56.68,80.61 53.05,80.61 41.25,92.41 41.14,92.41 40.88,92.15 40.59,92.15 40.24,92.5 40.24,92.79 40.5,93.05 40.5,93.16 40.27,93.39 40.15,93.39 39.89,93.13 39.6,93.13 39.25,93.48 39.25,93.77 39.51,94.03 39.51,94.15 39.28,94.38 39.17,94.38 38.91,94.12 38.62,94.12 38.27,94.47 38.27,94.76 38.53,95.02 38.53,95.13 38.3,95.36 38.18,95.36 37.92,95.1 37.63,95.1 37.28,95.45 37.28,95.74 37.54,96 37.54,96.12 37.31,96.35 37.2,96.35 36.94,96.09 36.65,96.09 36.3,96.44 36.3,96.73 36.56,96.99 36.56,97.1 36.33,97.33 36.21,97.33 35.95,97.07 35.66,97.07 35.31,97.42 35.31,97.71 35.57,97.97 35.57,98.09 35.34,98.32 35.23,98.32 34.97,98.06 34.68,98.06 34.33,98.41 34.33,98.7 34.59,98.96 34.59,99.07 34.36,99.3 34.24,99.3 33.98,99.04 33.69,99.04 33.34,99.39 33.34,99.68 33.6,99.94 33.6,100.06 32.5,101.16 27.95,101.16 27.67,100.88 27.17,100.88 26.89,101.16 26.56,101.16 26.28,100.88 25.78,100.88 25.5,101.16 25.17,101.16 24.89,100.88 24.39,100.88 24.11,101.16 23.78,101.16 23.5,100.88 22.99,100.88 22.72,101.16 22.38,101.16 22.11,100.88 21.6,100.88 21.32,101.16 20.99,101.16 20.71,100.88 20.21,100.88 19.93,101.16 14.02,101.16 13.92,101.06 13.69,101.06 13.59,101.16 13.37,101.16 13.27,101.06 13.04,101.06 12.94,101.16 12.7,101.16 12.6,101.06 12.37,101.06 12.27,101.16 11.92,101.16 11.84,101.08 v2(11.84,100.63)
FMC1_HA00_CLK_P: length 93
  TOP w0.124: U3.AJ12 v2(74.9,67.93) ; J48.F4 v2(11.84,101.9)
  L05-SIG2 w0.081: v2(74.9,67.93) 74.58,67.93 74.5,68.01 74.5,74.13 74.09,74.55 72.73,74.55 72.52,74.76 72.52,75.1 72.09,75.54 71.7,75.54 71.5,75.74 71.5,76.12 71.12,76.5 70.74,76.5 70.49,76.75 70.49,78.15 70.1,78.54 59.05,78.54 56.77,80.82 53.14,80.82 41.34,92.62 41.05,92.62 40.79,92.36 40.68,92.36 40.45,92.59 40.45,92.7 40.71,92.96 40.71,93.25 40.35,93.6 40.07,93.6 39.81,93.34 39.69,93.34 39.46,93.57 39.46,93.69 39.72,93.95 39.72,94.23 39.37,94.59 39.08,94.59 38.82,94.33 38.71,94.33 38.48,94.56 38.48,94.67 38.74,94.93 38.74,95.22 38.38,95.57 38.1,95.57 37.84,95.31 37.72,95.31 37.49,95.54 37.49,95.66 37.75,95.92 37.75,96.2 37.4,96.56 37.11,96.56 36.85,96.3 36.74,96.3 36.51,96.53 36.51,96.64 36.77,96.9 36.77,97.19 36.41,97.54 36.13,97.54 35.87,97.28 35.75,97.28 35.52,97.51 35.52,97.63 35.78,97.89 35.78,98.17 35.43,98.53 35.14,98.53 34.88,98.27 34.77,98.27 34.54,98.5 34.54,98.61 34.8,98.87 34.8,99.16 34.44,99.51 34.16,99.51 33.9,99.25 33.78,99.25 33.55,99.48 33.55,99.6 33.81,99.86 33.81,100.14 32.59,101.37 27.86,101.37 27.59,101.09 27.26,101.09 26.98,101.37 26.47,101.37 26.2,101.09 25.86,101.09 25.59,101.37 25.08,101.37 24.8,101.09 24.47,101.09 24.19,101.37 23.69,101.37 23.41,101.09 23.08,101.09 22.8,101.37 22.3,101.37 22.02,101.09 21.69,101.09 21.41,101.37 20.91,101.37 20.63,101.09 20.3,101.09 20.02,101.37 11.92,101.37 11.84,101.45 v2(11.84,101.9)
FMC1_HA01_CLK_N: length 95.4
  TOP w0.099: 12.47,102.54 v2(13.11,103.17)
  TOP w0.124: U3.AE12 v2(74.9,71.93)
  L12-SIG4 w0.081: v2(74.9,71.93) 74.9,71.62 74.82,71.53 70.63,71.53 70.5,71.66 70.5,76.21 70.13,76.58 63.59,76.58 63.16,77.01 51.09,77.01 48.73,79.38 45.68,79.38 40.93,84.13 40.64,84.13 40,83.49 39.89,83.49 39.66,83.72 39.66,83.84 40.29,84.47 40.29,84.76 39.94,85.11 39.65,85.11 39.02,84.48 38.9,84.48 38.67,84.71 38.67,84.82 39.31,85.46 39.31,85.75 38.96,86.1 38.67,86.1 38.03,85.46 37.92,85.46 37.69,85.69 37.69,85.81 38.32,86.44 38.32,86.73 37.97,87.08 37.68,87.08 37.05,86.45 36.93,86.45 36.7,86.68 36.7,86.79 37.34,87.43 37.34,87.72 36.99,88.07 36.7,88.07 36.06,87.43 35.95,87.43 35.72,87.66 35.72,87.78 36.35,88.41 36.35,88.7 36,89.05 35.71,89.05 35.08,88.42 34.96,88.42 34.73,88.65 34.73,88.76 35.37,89.4 35.37,89.69 30.68,94.37 30.39,94.37 30.07,94.05 29.95,94.05 29.72,94.28 29.72,94.39 30.05,94.72 30.05,95.01 29.7,95.36 29.41,95.36 29.04,94.99 28.92,94.99 28.69,95.22 28.69,95.33 29.06,95.7 29.06,95.99 22.39,102.66 12.66,102.66 12.58,102.74 12.58,103.09 12.66,103.17 v2(13.11,103.17)
FMC1_HA01_CLK_P: length 95.8
  TOP w0.099: J48.E2 v2(11.84,103.17)
  TOP w0.124: U3.AF12 v2(74.9,70.93)
  L12-SIG4 w0.081: v2(74.9,70.93) 74.9,71.24 74.82,71.33 70.54,71.33 70.29,71.57 70.29,76.12 70.04,76.37 63.5,76.37 63.07,76.8 51.01,76.8 48.64,79.17 45.59,79.17 40.84,83.92 40.73,83.92 40.09,83.28 39.8,83.28 39.45,83.64 39.45,83.92 40.09,84.56 40.09,84.67 39.86,84.91 39.74,84.91 39.1,84.27 38.82,84.27 38.46,84.62 38.46,84.91 39.1,85.54 39.1,85.66 38.87,85.89 38.76,85.89 38.12,85.25 37.83,85.25 37.48,85.61 37.48,85.89 38.12,86.53 38.12,86.64 37.89,86.88 37.77,86.88 37.13,86.24 36.85,86.24 36.49,86.59 36.49,86.88 37.13,87.51 37.13,87.63 36.9,87.86 36.79,87.86 36.15,87.22 35.86,87.22 35.51,87.58 35.51,87.86 36.15,88.5 36.15,88.61 35.92,88.85 35.8,88.85 35.16,88.21 34.88,88.21 34.52,88.56 34.52,88.85 35.16,89.48 35.16,89.6 30.6,94.17 30.48,94.17 30.15,93.84 29.87,93.84 29.51,94.19 29.51,94.48 29.84,94.81 29.84,94.92 29.61,95.15 29.5,95.15 29.13,94.78 28.84,94.78 28.49,95.13 28.49,95.42 28.86,95.79 28.86,95.91 22.31,102.45 12.57,102.45 12.37,102.66 12.37,103.09 12.29,103.17 v2(11.84,103.17)
FMC1_HA02_N: length 97.7
  TOP w0.099: J48.K8 v2(5.49,96.82)
  TOP w0.152: U3.AF14 v2(76.9,70.93)
  L03-SIG1 w0.081: v2(5.49,96.82) 5.94,96.82 6.02,96.74 6.02,95.21 6.39,94.83 21.38,94.83 27.19,89.02 28.09,89.02 28.29,89.22 28.29,89.7 28.37,89.78 28.7,89.78 28.78,89.7 28.78,89.22 28.98,89.02 29.48,89.02 29.68,89.22 29.68,89.7 29.76,89.78 30.09,89.78 30.17,89.7 30.17,89.22 30.37,89.02 30.87,89.02 31.07,89.22 31.07,89.7 31.15,89.78 31.48,89.78 31.56,89.7 31.56,89.22 31.76,89.02 32.26,89.02 32.47,89.22 32.47,89.7 32.55,89.78 32.87,89.78 32.95,89.7 32.95,89.22 33.16,89.02 33.65,89.02 33.86,89.22 33.86,89.7 33.94,89.78 34.26,89.78 34.35,89.7 34.35,89.22 34.55,89.02 35.05,89.02 35.25,89.22 35.25,89.7 35.33,89.78 35.66,89.78 35.74,89.7 35.74,89.22 35.94,89.02 36.44,89.02 36.64,89.22 36.64,89.7 36.72,89.78 37.05,89.78 37.13,89.7 37.13,89.22 37.33,89.02 37.83,89.02 38.03,89.22 38.03,89.7 38.11,89.78 38.44,89.78 38.52,89.7 38.52,89.22 38.72,89.02 39.22,89.02 39.43,89.22 39.43,89.7 39.51,89.78 39.83,89.78 39.91,89.7 39.91,89.22 40.12,89.02 40.61,89.02 40.82,89.22 40.82,89.62 40.9,89.7 41.22,89.7 41.3,89.62 41.3,89.22 41.51,89.02 43.96,89.02 58.65,74.33 75.11,74.33 75.29,74.14 75.29,73.5 75.5,73.3 76.06,73.3 76.3,73.06 76.3,71.53 v2(76.9,70.93)
FMC1_HA02_P: length 97.8
  TOP w0.099: J48.K7 v2(6.76,96.82)
  TOP w0.152: U3.AE14 v2(76.9,71.93)
  L03-SIG1 w0.081: v2(76.9,71.93) 76.9,71.5 76.82,71.42 76.7,71.42 76.5,71.62 76.5,73.15 76.15,73.5 75.58,73.5 75.5,73.59 75.5,74.23 75.19,74.53 58.74,74.53 44.04,89.23 41.59,89.23 41.51,89.31 41.51,89.71 41.31,89.91 40.81,89.91 40.61,89.71 40.61,89.31 40.53,89.23 40.2,89.23 40.12,89.31 40.12,89.79 39.92,89.99 39.42,89.99 39.22,89.79 39.22,89.31 39.14,89.23 38.81,89.23 38.73,89.31 38.73,89.79 38.53,89.99 38.03,89.99 37.82,89.79 37.82,89.31 37.74,89.23 37.42,89.23 37.34,89.31 37.34,89.79 37.13,89.99 36.64,89.99 36.43,89.79 36.43,89.31 36.35,89.23 36.03,89.23 35.95,89.31 35.95,89.79 35.74,89.99 35.24,89.99 35.04,89.79 35.04,89.31 34.96,89.23 34.63,89.23 34.55,89.31 34.55,89.79 34.35,89.99 33.85,89.99 33.65,89.79 33.65,89.31 33.57,89.23 33.24,89.23 33.16,89.31 33.16,89.79 32.96,89.99 32.46,89.99 32.26,89.79 32.26,89.31 32.18,89.23 31.85,89.23 31.77,89.31 31.77,89.79 31.57,89.99 31.07,89.99 30.87,89.79 30.87,89.31 30.78,89.23 30.46,89.23 30.38,89.31 30.38,89.79 30.17,89.99 29.68,89.99 29.47,89.79 29.47,89.31 29.39,89.23 29.07,89.23 28.99,89.31 28.99,89.79 28.78,89.99 28.28,89.99 28.08,89.79 28.08,89.31 28,89.23 27.28,89.23 21.46,95.04 7.42,95.04 7.29,95.17 7.09,95.17 6.97,95.04 6.48,95.04 6.23,95.29 6.23,95.96 6.32,96.06 6.32,96.29 6.23,96.39 6.23,96.74 6.31,96.82 v2(6.76,96.82)
FMC1_HA03_N: length 101.4
  TOP w0.124: U3.AC14 v2(76.9,73.93) ; J48.J7 v2(6.76,98.09)
  L03-SIG1 w0.081: v2(6.76,98.09) 7.16,98.09 7.29,97.97 7.29,96.48 7.66,96.1 21.66,96.1 26.99,90.77 28.15,90.77 28.35,90.97 28.35,91.73 28.44,91.81 28.76,91.81 28.84,91.73 28.84,90.97 29.05,90.77 29.54,90.77 29.75,90.97 29.75,91.73 29.83,91.81 30.15,91.81 30.23,91.73 30.23,90.97 30.44,90.77 30.94,90.77 31.14,90.97 31.14,91.73 31.22,91.81 31.54,91.81 31.63,91.73 31.63,90.97 31.83,90.77 32.33,90.77 32.53,90.97 32.53,91.73 32.61,91.81 32.94,91.81 33.02,91.73 33.02,90.97 33.22,90.77 33.72,90.77 33.92,90.97 33.92,91.73 34,91.81 34.33,91.81 34.41,91.73 34.41,90.97 34.61,90.77 35.11,90.77 35.31,90.97 35.31,91.73 35.4,91.81 35.72,91.81 35.8,91.73 35.8,90.97 36.01,90.77 36.5,90.77 36.71,90.97 36.71,91.73 36.79,91.81 37.11,91.81 37.19,91.73 37.19,90.97 37.4,90.77 37.89,90.77 38.1,90.97 38.1,91.73 38.18,91.81 38.5,91.81 38.59,91.73 38.59,90.97 38.79,90.77 39.29,90.77 39.49,90.97 39.49,91.73 39.57,91.81 39.9,91.81 39.98,91.73 39.98,90.97 40.18,90.77 40.68,90.77 40.88,90.97 40.88,91.73 40.96,91.81 41.29,91.81 41.37,91.73 41.37,90.97 41.57,90.77 43.35,90.77 58.79,75.33 76.06,75.33 76.25,75.14 76.25,74.64 76.54,74.34 77.21,74.34 77.29,74.26 77.29,74.01 77.21,73.93 v2(76.9,73.93)
FMC1_HA03_P: length 101.4
  TOP w0.124: U3.AC15 v2(77.9,73.93) ; J48.J6 v2(8.03,98.09)
  L03-SIG1 w0.081: v2(77.9,73.93) 77.58,73.93 77.5,74.01 77.5,74.35 77.3,74.55 76.62,74.55 76.45,74.72 76.45,75.23 76.15,75.53 58.88,75.53 43.43,90.98 41.66,90.98 41.58,91.06 41.58,91.82 41.37,92.02 40.88,92.02 40.67,91.82 40.67,91.06 40.59,90.98 40.27,90.98 40.19,91.06 40.19,91.82 39.98,92.02 39.48,92.02 39.28,91.82 39.28,91.06 39.2,90.98 38.88,90.98 38.79,91.06 38.79,91.82 38.59,92.02 38.09,92.02 37.89,91.82 37.89,91.06 37.81,90.98 37.48,90.98 37.4,91.06 37.4,91.82 37.2,92.02 36.7,92.02 36.5,91.82 36.5,91.06 36.42,90.98 36.09,90.98 36.01,91.06 36.01,91.82 35.81,92.02 35.31,92.02 35.11,91.82 35.11,91.06 35.02,90.98 34.7,90.98 34.62,91.06 34.62,91.82 34.41,92.02 33.92,92.02 33.71,91.82 33.71,91.06 33.63,90.98 33.31,90.98 33.23,91.06 33.23,91.82 33.02,92.02 32.53,92.02 32.32,91.82 32.32,91.06 32.24,90.98 31.92,90.98 31.83,91.06 31.83,91.82 31.63,92.02 31.13,92.02 30.93,91.82 30.93,91.06 30.85,90.98 30.52,90.98 30.44,91.06 30.44,91.82 30.24,92.02 29.74,92.02 29.54,91.82 29.54,91.06 29.46,90.98 29.13,90.98 29.05,91.06 29.05,91.82 28.85,92.02 28.35,92.02 28.15,91.82 28.15,91.06 28.06,90.98 27.08,90.98 21.74,96.31 7.75,96.31 7.5,96.56 7.5,98.01 7.58,98.09 v2(8.03,98.09)
FMC1_HA04_N: length 100.4
  TOP w0.124: J48.F8 v2(11.84,96.82) ; U3.AA14 v2(76.9,75.93)
  L03-SIG1 w0.081: v2(76.9,75.93) 77.26,75.93 77.34,76.01 77.34,76.19 77.21,76.33 58.94,76.33 42.35,92.91 39.77,92.91 39.57,93.11 39.57,94.3 39.49,94.38 39.16,94.38 39.08,94.3 39.08,93.11 38.88,92.91 38.38,92.91 38.18,93.11 38.18,94.3 38.1,94.38 37.77,94.38 37.69,94.3 37.69,93.11 37.49,92.91 36.99,92.91 36.79,93.11 36.79,94.3 36.71,94.38 36.38,94.38 36.3,94.3 36.3,93.11 36.1,92.91 35.6,92.91 35.39,93.11 35.39,94.3 35.31,94.38 34.99,94.38 34.91,94.3 34.91,93.11 34.7,92.91 34.21,92.91 34,93.11 34,94.3 33.92,94.38 33.6,94.38 33.52,94.3 33.52,93.11 33.31,92.91 32.81,92.91 32.61,93.11 32.61,94.3 32.53,94.38 32.2,94.38 32.12,94.3 32.12,93.11 31.92,92.91 31.42,92.91 31.22,93.11 31.22,94.3 31.14,94.38 30.81,94.38 30.73,94.3 30.73,93.11 30.53,92.91 30.03,92.91 29.83,93.11 29.83,94.3 29.75,94.38 29.42,94.38 29.34,94.3 29.34,93.11 29.14,92.91 28.64,92.91 28.44,93.11 28.44,94.3 28.35,94.38 28.03,94.38 27.95,94.3 27.95,93.11 27.74,92.91 26.54,92.91 22.1,97.35 11.92,97.35 11.84,97.27 v2(11.84,96.82)
FMC1_HA04_P: length 100.5
  TOP w0.124: J48.F7 v2(11.84,98.09) ; U3.AA15 v2(77.9,75.93)
  L03-SIG1 w0.081: v2(77.9,75.93) 77.29,76.53 59.02,76.53 42.44,93.12 39.86,93.12 39.78,93.2 39.78,94.38 39.58,94.59 39.08,94.59 38.87,94.38 38.87,93.2 38.79,93.12 38.47,93.12 38.39,93.2 38.39,94.38 38.18,94.59 37.69,94.59 37.48,94.38 37.48,93.2 37.4,93.12 37.08,93.12 37,93.2 37,94.38 36.79,94.59 36.29,94.59 36.09,94.38 36.09,93.2 36.01,93.12 35.68,93.12 35.6,93.2 35.6,94.38 35.4,94.59 34.9,94.59 34.7,94.38 34.7,93.2 34.62,93.12 34.29,93.12 34.21,93.2 34.21,94.38 34.01,94.59 33.51,94.59 33.31,94.38 33.31,93.2 33.23,93.12 32.9,93.12 32.82,93.2 32.82,94.38 32.62,94.59 32.12,94.59 31.92,94.38 31.92,93.2 31.83,93.12 31.51,93.12 31.43,93.2 31.43,94.38 31.22,94.59 30.73,94.59 30.52,94.38 30.52,93.2 30.44,93.12 30.12,93.12 30.04,93.2 30.04,94.38 29.83,94.59 29.33,94.59 29.13,94.38 29.13,93.2 29.05,93.12 28.72,93.12 28.64,93.2 28.64,94.38 28.44,94.59 27.94,94.59 27.74,94.38 27.74,93.2 27.66,93.12 26.63,93.12 22.19,97.56 11.92,97.56 11.84,97.64 v2(11.84,98.09)
FMC1_HA05_N: length 102.2
  TOP w0.124: U3.AB15 v2(77.9,74.93) ; J48.E7 v2(13.11,98.09)
  L03-SIG1 w0.081: v2(13.11,98.09) 12.36,98.83 12.36,99.68 12.77,100.08 22.06,100.08 26.43,95.71 27.53,95.71 27.61,95.79 27.61,96.77 27.81,96.97 28.31,96.97 28.51,96.77 28.51,95.79 28.6,95.71 28.92,95.71 29,95.79 29,96.77 29.2,96.97 29.7,96.97 29.91,96.77 29.91,95.79 29.99,95.71 30.31,95.71 30.39,95.79 30.39,96.77 30.6,96.97 31.09,96.97 31.3,96.77 31.3,95.79 31.38,95.71 31.7,95.71 31.79,95.79 31.79,96.77 31.99,96.97 32.49,96.97 32.69,96.77 32.69,95.79 32.77,95.71 33.1,95.71 33.18,95.79 33.18,96.77 33.38,96.97 33.88,96.97 34.08,96.77 34.08,95.79 34.16,95.71 34.49,95.71 34.57,95.79 34.57,96.77 34.77,96.97 35.27,96.97 35.47,96.77 35.47,95.79 35.55,95.71 35.88,95.71 35.96,95.79 35.96,96.77 36.16,96.97 36.66,96.97 36.87,96.77 36.87,95.79 36.95,95.71 37.27,95.71 37.35,95.79 37.35,96.77 37.56,96.97 38.05,96.97 38.26,96.77 38.26,95.79 38.34,95.71 38.66,95.71 38.74,95.79 38.74,96.77 38.95,96.97 39.45,96.97 39.65,96.77 39.65,95.79 39.73,95.71 41.09,95.71 59.27,77.53 78.21,77.53 78.49,77.26 78.49,75.61 78.16,75.28 77.7,75.28 77.62,75.2 77.62,75.01 77.7,74.93 v2(77.9,74.93)
FMC1_HA05_P: length 101.9
  TOP w0.124: U3.AB14 v2(76.9,74.93) ; J48.E6 v2(13.11,99.36)
  L03-SIG1 w0.081: v2(13.11,99.36) 13.11,98.86 13,98.75 12.74,98.75 12.57,98.92 12.57,99.59 12.85,99.87 13.49,99.87 13.61,99.74 13.84,99.74 13.97,99.87 21.97,99.87 26.34,95.5 27.61,95.5 27.82,95.7 27.82,96.68 27.9,96.77 28.22,96.77 28.31,96.68 28.31,95.7 28.51,95.5 29.01,95.5 29.21,95.7 29.21,96.68 29.29,96.77 29.62,96.77 29.7,96.68 29.7,95.7 29.9,95.5 30.4,95.5 30.6,95.7 30.6,96.68 30.68,96.77 31.01,96.77 31.09,96.68 31.09,95.7 31.29,95.5 31.79,95.5 31.99,95.7 31.99,96.68 32.07,96.77 32.4,96.77 32.48,96.68 32.48,95.7 32.68,95.5 33.18,95.5 33.39,95.7 33.39,96.68 33.47,96.77 33.79,96.77 33.87,96.68 33.87,95.7 34.08,95.5 34.57,95.5 34.78,95.7 34.78,96.68 34.86,96.77 35.18,96.77 35.27,96.68 35.27,95.7 35.47,95.5 35.97,95.5 36.17,95.7 36.17,96.68 36.25,96.77 36.58,96.77 36.66,96.68 36.66,95.7 36.86,95.5 37.36,95.5 37.56,95.7 37.56,96.68 37.64,96.77 37.97,96.77 38.05,96.68 38.05,95.7 38.25,95.5 38.75,95.5 38.95,95.7 38.95,96.68 39.03,96.77 39.36,96.77 39.44,96.68 39.44,95.7 39.64,95.5 41.01,95.5 59.18,77.33 78.13,77.33 78.28,77.18 78.28,75.7 78.07,75.49 77.62,75.49 77.41,75.29 77.41,75.01 77.33,74.93 v2(76.9,74.93)
FMC1_HA06_N: length 90.6
  TOP w0.124: J48.K11 v2(6.76,93.01) ; U3.AJ7 v2(69.9,67.93)
  L03-SIG1 w0.081: v2(6.76,93.01) 6.31,93.01 6.23,92.93 6.23,92.5 6.35,92.38 6.71,92.38 6.86,92.53 7.03,92.53 7.18,92.38 7.36,92.38 7.51,92.53 7.68,92.53 7.83,92.38 8.38,92.38 8.76,91.99 8.76,91.53 8.86,91.43 8.86,91.21 8.76,91.11 8.76,90.09 8.89,89.96 9.73,89.96 9.98,89.71 9.98,87.55 10.11,87.42 12.17,87.42 12.43,87.16 12.43,86.25 12.52,86.15 18.41,86.15 18.8,85.77 18.8,84.54 24.85,78.49 27.74,78.49 27.97,78.71 28.53,78.71 28.75,78.49 29.14,78.49 29.36,78.71 29.92,78.71 30.14,78.49 30.53,78.49 30.75,78.71 31.31,78.71 31.53,78.49 32.4,78.49 32.61,78.28 32.61,77.68 32.69,77.6 33.01,77.6 33.1,77.68 33.1,78.63 33.3,78.84 33.8,78.84 34,78.63 34,77.68 34.08,77.6 34.41,77.6 34.49,77.68 34.49,78.63 34.69,78.84 35.19,78.84 35.39,78.63 35.39,77.68 35.47,77.6 35.8,77.6 35.88,77.68 35.88,78.63 36.08,78.84 36.58,78.84 36.78,78.63 36.78,77.68 36.87,77.6 37.19,77.6 37.27,77.68 37.27,78.61 37.47,78.81 37.97,78.81 38.18,78.61 38.18,77.68 38.26,77.6 47.29,77.6 57.35,67.53 57.71,67.53 57.84,67.66 58.01,67.66 58.14,67.53 58.39,67.53 58.5,67.64 58.7,67.64 58.8,67.53 69.82,67.53 69.9,67.62 v2(69.9,67.93)
FMC1_HA06_P: length 90.2
  TOP w0.124: J48.K10 v2(5.49,93.01) ; U3.AK7 v2(69.9,66.93)
  L03-SIG1 w0.081: v2(5.49,93.01) 5.94,93.01 6.02,92.93 6.02,92.42 6.27,92.17 8.3,92.17 8.55,91.91 8.55,90 8.8,89.75 9.64,89.75 9.77,89.62 9.77,87.46 10.02,87.21 12.08,87.21 12.22,87.08 12.22,86.16 12.44,85.94 18.33,85.94 18.59,85.69 18.59,84.46 24.77,78.28 27.83,78.28 28.05,78.5 28.44,78.5 28.66,78.28 29.22,78.28 29.45,78.5 29.83,78.5 30.06,78.28 30.61,78.28 30.84,78.5 31.22,78.5 31.45,78.28 32.32,78.28 32.4,78.2 32.4,77.59 32.6,77.39 33.1,77.39 33.3,77.59 33.3,78.55 33.39,78.63 33.71,78.63 33.79,78.55 33.79,77.59 33.99,77.39 34.49,77.39 34.7,77.59 34.7,78.55 34.78,78.63 35.1,78.63 35.18,78.55 35.18,77.59 35.39,77.39 35.88,77.39 36.09,77.59 36.09,78.55 36.17,78.63 36.49,78.63 36.58,78.55 36.58,77.59 36.78,77.39 37.28,77.39 37.48,77.59 37.48,78.52 37.56,78.6 37.89,78.6 37.97,78.52 37.97,77.59 38.17,77.39 47.2,77.39 57.27,67.33 69.5,67.33 v2(69.9,66.93)
FMC1_HA07_N: length 92.7
  TOP w0.124: J48.J10 v2(8.03,93.01) ; U3.AJ10 v2(72.9,67.93)
  L03-SIG1 w0.081: v2(72.9,67.93) 72.9,68.19 72.82,68.27 72.51,68.27 72.31,68.47 72.31,71.08 72.06,71.33 58.09,71.33 46.14,83.28 45.07,83.28 44.99,83.2 44.99,82.62 44.78,82.42 44.28,82.42 44.08,82.62 44.08,83.2 44,83.28 35.63,83.28 35.43,83.48 35.43,84.11 35.34,84.19 35.02,84.19 34.94,84.11 34.94,83.48 34.73,83.28 34.24,83.28 34.03,83.48 34.03,84.09 33.95,84.17 33.63,84.17 33.55,84.09 33.55,83.48 33.34,83.28 32.84,83.28 32.64,83.48 32.64,84.09 32.56,84.17 32.24,84.17 32.15,84.09 32.15,83.48 31.95,83.28 31.45,83.28 31.25,83.48 31.25,84.09 31.17,84.17 30.84,84.17 30.76,84.09 30.76,83.48 30.56,83.28 30.06,83.28 29.86,83.48 29.86,84.11 29.78,84.19 29.45,84.19 29.37,84.11 29.37,83.19 29.13,82.95 28.69,82.95 27.81,83.83 27.81,84.21 27.57,84.45 27.18,84.45 26.82,84.82 26.82,85.2 26.58,85.44 26.2,85.44 25.84,85.8 25.84,86.18 25.6,86.42 25.21,86.42 24.85,86.79 24.85,87.17 24.61,87.41 24.23,87.41 23.87,87.77 23.87,88.15 23.63,88.39 23.24,88.39 22.88,88.76 22.88,89.14 22.64,89.38 22.26,89.38 21.9,89.74 21.9,90.12 21.66,90.36 21.27,90.36 20.61,91.02 19.71,91.02 19.5,91.23 19.5,91.53 19.42,91.61 19.1,91.61 19.02,91.53 19.02,91.23 18.81,91.02 17.52,91.02 17.31,91.23 17.31,91.48 17.23,91.56 16.91,91.56 16.82,91.48 16.82,91.23 16.62,91.02 15.46,91.02 15.28,91.2 14.9,91.2 14.73,91.02 10.33,91.02 9.82,91.53 9.82,93.31 9.59,93.54 8.11,93.54 8.03,93.46 v2(8.03,93.01)
FMC1_HA07_P: length 92.8
  TOP w0.124: J48.J9 v2(8.03,94.28) ; U3.AH10 v2(72.9,68.93)
  L03-SIG1 w0.081: v2(72.9,68.93) 72.9,68.56 72.82,68.48 72.6,68.48 72.52,68.56 72.52,71.17 72.15,71.53 58.18,71.53 46.23,83.49 44.98,83.49 44.78,83.28 44.78,82.71 44.7,82.63 44.37,82.63 44.29,82.71 44.29,83.28 44.09,83.49 35.71,83.49 35.63,83.57 35.63,84.2 35.43,84.4 34.93,84.4 34.73,84.2 34.73,83.57 34.65,83.49 34.32,83.49 34.24,83.57 34.24,84.17 34.04,84.37 33.54,84.37 33.34,84.17 33.34,83.57 33.26,83.49 32.93,83.49 32.85,83.57 32.85,84.17 32.65,84.37 32.15,84.37 31.95,84.17 31.95,83.57 31.86,83.49 31.54,83.49 31.46,83.57 31.46,84.17 31.25,84.37 30.76,84.37 30.55,84.17 30.55,83.57 30.47,83.49 30.15,83.49 30.07,83.57 30.07,84.2 29.86,84.4 29.36,84.4 29.16,84.2 29.16,83.28 29.04,83.16 28.78,83.16 28.02,83.92 28.02,84.3 27.65,84.66 27.27,84.66 27.03,84.9 27.03,85.28 26.67,85.65 26.29,85.65 26.05,85.89 26.05,86.27 25.68,86.63 25.3,86.63 25.06,86.87 25.06,87.25 24.7,87.62 24.32,87.62 24.08,87.86 24.08,88.24 23.71,88.6 23.33,88.6 23.09,88.84 23.09,89.22 22.73,89.59 22.35,89.59 22.11,89.83 22.11,90.21 21.74,90.57 21.36,90.57 20.7,91.23 19.79,91.23 19.71,91.31 19.71,91.61 19.51,91.82 19.01,91.82 18.81,91.61 18.81,91.31 18.73,91.23 17.6,91.23 17.52,91.31 17.52,91.56 17.32,91.77 16.82,91.77 16.62,91.56 16.62,91.31 16.54,91.23 15.54,91.23 15.37,91.41 14.82,91.41 14.64,91.23 10.41,91.23 10.03,91.61 10.03,93.39 9.67,93.75 8.11,93.75 8.03,93.83 v2(8.03,94.28)
FMC1_HA08_N: length 94.9
  TOP w0.124: J48.F11 v2(11.84,93.01) ; U3.AG11 v2(73.9,69.93)
  L03-SIG1 w0.081: v2(73.9,69.93) 73.58,69.93 73.5,70.01 73.5,72.21 73.18,72.53 58.32,72.53 45.9,84.96 44.43,84.96 44.22,84.76 44.22,84.54 44.14,84.46 43.82,84.46 43.74,84.54 43.74,85.02 43.53,85.22 43.03,85.22 42.83,85.02 42.83,84.54 42.75,84.46 42.42,84.46 42.34,84.54 42.34,85.02 42.14,85.22 41.64,85.22 41.44,85.02 41.44,84.54 41.36,84.46 41.03,84.46 40.95,84.54 40.95,85.02 40.75,85.22 40.25,85.22 40.05,85.02 40.05,84.54 39.97,84.46 39.64,84.46 39.56,84.54 39.56,85.95 39.36,86.15 38.86,86.15 38.66,85.95 38.66,84.54 38.57,84.46 38.25,84.46 38.17,84.54 38.17,85.95 37.92,86.2 37.51,86.2 37.26,85.95 37.26,84.54 37.18,84.46 36.86,84.46 36.78,84.54 36.78,85.02 36.57,85.22 35.51,85.22 35.42,85.3 35.42,86 35.22,86.2 34.72,86.2 34.52,86 34.52,85.3 34.44,85.22 34.11,85.22 34.03,85.3 34.03,86 33.83,86.2 33.33,86.2 33.13,86 33.13,85.3 33.05,85.22 32.67,85.22 32.59,85.3 32.59,86.05 32.39,86.25 31.89,86.25 31.69,86.05 31.69,85.3 31.61,85.22 31.28,85.22 31.2,85.3 31.2,86.08 31,86.28 30.5,86.28 30.3,86.08 30.3,85.3 30.22,85.22 29.89,85.22 29.81,85.3 29.81,86.08 29.61,86.28 29.11,86.28 28.91,86.08 28.91,85.3 28.82,85.22 28.34,85.22 21.06,92.5 11.43,92.5 11.31,92.63 11.31,92.93 11.39,93.01 v2(11.84,93.01)
FMC1_HA08_P: length 95.1
  TOP w0.124: U3.AG10 v2(72.9,69.93) ; J48.F10 v2(10.57,93.01)
  L03-SIG1 w0.081: v2(72.9,69.93) 73.21,69.93 73.29,70.01 73.29,71.29 73.18,71.41 73.18,71.6 73.29,71.72 73.29,72.13 73.1,72.33 72.69,72.33 72.54,72.18 72.35,72.18 72.21,72.33 58.24,72.33 45.81,84.75 44.51,84.75 44.43,84.67 44.43,84.45 44.23,84.25 43.73,84.25 43.53,84.45 43.53,84.93 43.45,85.01 43.12,85.01 43.04,84.93 43.04,84.45 42.84,84.25 42.34,84.25 42.14,84.45 42.14,84.93 42.05,85.01 41.73,85.01 41.65,84.93 41.65,84.45 41.44,84.25 40.95,84.25 40.74,84.45 40.74,84.93 40.66,85.01 40.34,85.01 40.26,84.93 40.26,84.45 40.05,84.25 39.55,84.25 39.35,84.45 39.35,85.86 39.27,85.94 38.94,85.94 38.86,85.86 38.86,84.45 38.66,84.25 38.16,84.25 37.96,84.45 37.96,85.87 37.83,86 37.6,86 37.47,85.87 37.47,84.45 37.27,84.25 36.77,84.25 36.57,84.45 36.57,84.93 36.49,85.01 35.42,85.01 35.22,85.21 35.22,85.91 35.13,86 34.81,86 34.73,85.91 34.73,85.21 34.52,85.01 34.03,85.01 33.82,85.21 33.82,85.91 33.74,86 33.42,86 33.34,85.91 33.34,85.21 33.13,85.01 32.59,85.01 32.39,85.21 32.39,85.97 32.3,86.05 31.98,86.05 31.9,85.97 31.9,85.21 31.69,85.01 31.2,85.01 30.99,85.21 30.99,85.99 30.91,86.07 30.59,86.07 30.51,85.99 30.51,85.21 30.3,85.01 29.8,85.01 29.6,85.21 29.6,85.99 29.52,86.07 29.19,86.07 29.11,85.99 29.11,85.21 28.91,85.01 28.25,85.01 20.97,92.29 11.34,92.29 11.1,92.54 11.1,92.93 11.02,93.01 v2(10.57,93.01)
FMC1_HA09_N: length 95.7
  TOP w0.124: J48.E10 v2(13.11,94.28) ; U3.AG13 v2(75.9,69.93)
  L03-SIG1 w0.081: v2(75.9,69.93) 75.58,69.93 75.5,70.01 75.5,71.14 75.14,71.5 74.64,71.5 74.5,71.63 74.5,73.24 74.21,73.53 58.59,73.53 44.9,87.22 42.34,87.22 42.26,87.31 42.26,88.11 42.06,88.31 41.56,88.31 41.36,88.11 41.36,87.31 41.28,87.22 40.95,87.22 40.87,87.31 40.87,88.11 40.67,88.31 40.17,88.31 39.97,88.11 39.97,87.31 39.89,87.22 39.56,87.22 39.48,87.31 39.48,88.11 39.28,88.31 38.78,88.31 38.57,88.11 38.57,87.31 38.49,87.22 38.17,87.22 38.09,87.31 38.09,88.11 37.88,88.31 37.39,88.31 37.18,88.11 37.18,87.31 37.1,87.22 36.78,87.22 36.69,87.31 36.69,88.11 36.49,88.31 35.99,88.31 35.79,88.11 35.79,87.31 35.71,87.22 35.38,87.22 35.3,87.31 35.3,88.11 35.1,88.31 34.6,88.31 34.4,88.11 34.4,87.31 34.32,87.22 33.99,87.22 33.91,87.31 33.91,88.11 33.71,88.31 33.21,88.31 33.01,88.11 33.01,87.31 32.93,87.22 32.6,87.22 32.52,87.31 32.52,88.11 32.32,88.31 31.82,88.31 31.61,88.11 31.61,87.31 31.53,87.22 31.21,87.22 31.13,87.31 31.13,88.11 30.92,88.31 30.43,88.31 30.22,88.11 30.22,87.31 30.14,87.22 29.82,87.22 29.74,87.31 29.74,88.11 29.53,88.31 29.03,88.31 28.83,88.11 28.83,87.31 28.75,87.22 27.63,87.22 21.08,93.77 12.7,93.77 12.58,93.9 12.58,94.2 12.66,94.28 v2(13.11,94.28)
FMC1_HA09_P: length 95.9
  TOP w0.124: J48.E9 v2(11.84,94.28) ; U3.AG12 v2(74.9,69.93)
  L03-SIG1 w0.081: v2(11.84,94.28) 12.29,94.28 12.37,94.2 12.37,93.81 12.62,93.56 21,93.56 27.54,87.02 28.84,87.02 29.04,87.22 29.04,88.02 29.12,88.1 29.45,88.1 29.53,88.02 29.53,87.22 29.73,87.02 30.23,87.02 30.43,87.22 30.43,88.02 30.51,88.1 30.84,88.1 30.92,88.02 30.92,87.22 31.12,87.02 31.62,87.02 31.82,87.22 31.82,88.02 31.9,88.1 32.23,88.1 32.31,88.02 32.31,87.22 32.51,87.02 33.01,87.02 33.22,87.22 33.22,88.02 33.3,88.1 33.62,88.1 33.7,88.02 33.7,87.22 33.91,87.02 34.4,87.02 34.61,87.22 34.61,88.02 34.69,88.1 35.01,88.1 35.09,88.02 35.09,87.22 35.3,87.02 35.8,87.02 36,87.22 36,88.02 36.08,88.1 36.41,88.1 36.49,88.02 36.49,87.22 36.69,87.02 37.19,87.02 37.39,87.22 37.39,88.02 37.47,88.1 37.8,88.1 37.88,88.02 37.88,87.22 38.08,87.02 38.58,87.02 38.78,87.22 38.78,88.02 38.86,88.1 39.19,88.1 39.27,88.02 39.27,87.22 39.47,87.02 39.97,87.02 40.17,87.22 40.17,88.02 40.26,88.1 40.58,88.1 40.66,88.02 40.66,87.22 40.87,87.02 41.36,87.02 41.57,87.22 41.57,88.02 41.65,88.1 41.97,88.1 42.05,88.02 42.05,87.22 42.26,87.02 44.82,87.02 58.51,73.33 74.13,73.33 74.29,73.16 74.29,72.67 74.22,72.59 74.22,72.31 74.29,72.23 74.29,71.55 74.55,71.29 75.06,71.29 75.29,71.06 75.29,70.69 75.18,70.58 75.18,70.38 75.29,70.27 75.29,70.01 75.21,69.93 v2(74.9,69.93)
FMC1_HA10_N: length 89.3
  TOP w0.124: U3.AL9 v2(71.9,65.93) ; J48.K14 v2(5.49,87.93)
  L03-SIG1 w0.081: v2(71.9,65.93) 71.29,65.32 70.52,65.32 70.44,65.24 70.44,62.65 70.19,62.4 56.47,62.4 47.71,71.17 25.4,71.17 23.7,72.86 17.44,72.86 17.01,73.29 16.9,73.29 16.71,73.11 16.43,73.11 16.07,73.46 16.07,73.75 16.26,73.93 16.26,74.05 15.92,74.39 14.87,74.39 13.63,75.63 13.63,76.81 13.49,76.95 12.56,76.95 12.31,77.2 12.31,77.99 11.98,78.32 11.32,78.32 11.07,78.57 11.07,79.38 10.98,79.47 10.02,79.47 9.77,79.72 9.77,84.64 9.67,84.75 7.84,84.75 7.37,85.22 7.37,88.18 7.09,88.46 5.57,88.46 5.49,88.38 v2(5.49,87.93)
FMC1_HA10_P: length 89
  TOP w0.124: J48.K13 v2(5.49,89.2) ; U3.AL8 v2(70.9,65.93)
  L03-SIG1 w0.081: v2(5.49,89.2) 6.02,88.67 7.18,88.67 7.57,88.27 7.57,85.31 7.92,84.96 9.75,84.96 9.98,84.73 9.98,79.8 10.11,79.68 11.06,79.68 11.28,79.46 11.28,78.66 11.4,78.53 12.06,78.53 12.52,78.08 12.52,77.29 12.65,77.16 13.58,77.16 13.84,76.9 13.84,75.71 14.96,74.6 16,74.6 16.47,74.13 16.47,73.84 16.28,73.66 16.28,73.54 16.51,73.31 16.63,73.31 16.81,73.5 17.1,73.5 17.53,73.07 23.79,73.07 25.49,71.38 47.8,71.38 56.56,62.61 70.1,62.61 70.23,62.74 70.23,65.32 70.44,65.53 71.21,65.53 71.37,65.7 71.37,65.85 71.29,65.93 v2(70.9,65.93)
FMC1_HA11_N: length 88.3
  TOP w0.099: J48.J13 v2(6.76,90.47)
  TOP w0.124: U3.AL6 v2(68.9,65.93)
  L03-SIG1 w0.081: v2(68.9,65.93) 68.58,65.93 68.5,65.85 68.5,65.58 68.25,65.32 56.98,65.32 46.65,75.66 45.65,75.66 45.57,75.58 45.57,74.8 45.36,74.6 44.87,74.6 44.66,74.8 44.66,75.58 44.58,75.66 44.26,75.66 44.18,75.58 44.18,74.8 43.97,74.6 43.48,74.6 43.27,74.8 43.27,75.58 43.19,75.66 42.87,75.66 42.78,75.58 42.78,74.82 42.58,74.62 42.08,74.62 41.88,74.82 41.88,75.58 41.8,75.66 41.47,75.66 41.39,75.58 41.39,75 41.19,74.79 40.69,74.79 40.49,75 40.49,75.58 40.41,75.66 39.83,75.66 39.74,75.58 39.74,75 39.54,74.8 39.04,74.8 38.84,75 38.84,75.58 38.76,75.66 38.43,75.66 38.35,75.58 38.35,75 38.15,74.8 37.65,74.8 37.45,75 37.45,75.58 37.37,75.66 22.27,75.66 19.87,78.05 19.76,78.05 19.53,77.83 19.25,77.83 18.89,78.18 18.89,78.47 19.12,78.69 19.12,78.81 16.3,81.62 16.3,82.89 15.79,83.4 11.6,83.4 11.09,83.91 11.09,85.56 10.71,85.94 8.97,85.94 8.43,86.49 8.43,88.27 7.29,89.41 7.29,90.39 7.21,90.47 v2(6.76,90.47)
FMC1_HA11_P: length 88.2
  TOP w0.099: J48.J12 v2(8.03,90.47)
  TOP w0.124: U3.AL5 v2(67.9,65.93)
  L03-SIG1 w0.081: v2(67.9,65.93) 68.21,65.93 68.29,65.85 68.29,65.67 68.16,65.53 67.66,65.53 67.49,65.71 67.28,65.71 67.11,65.53 66.67,65.53 66.5,65.71 66.29,65.71 66.12,65.53 65.68,65.53 65.53,65.68 65.28,65.68 65.13,65.53 64.71,65.53 64.59,65.66 64.29,65.66 64.17,65.53 63.72,65.53 63.6,65.66 63.29,65.66 63.17,65.53 57.07,65.53 46.74,75.87 45.56,75.87 45.36,75.66 45.36,74.89 45.28,74.8 44.95,74.8 44.87,74.89 44.87,75.66 44.67,75.87 44.17,75.87 43.97,75.66 43.97,74.89 43.89,74.8 43.56,74.8 43.48,74.89 43.48,75.66 43.28,75.87 42.78,75.87 42.58,75.66 42.58,74.91 42.49,74.82 42.17,74.82 42.09,74.91 42.09,75.66 41.89,75.87 41.39,75.87 41.18,75.66 41.18,75.08 41.1,75 40.78,75 40.7,75.08 40.7,75.66 40.49,75.87 39.74,75.87 39.54,75.66 39.54,75.09 39.46,75.01 39.13,75.01 39.05,75.09 39.05,75.66 38.85,75.87 38.35,75.87 38.14,75.66 38.14,75.09 38.06,75.01 37.74,75.01 37.66,75.09 37.66,75.66 37.45,75.87 22.35,75.87 19.96,78.26 19.67,78.26 19.45,78.04 19.33,78.04 19.1,78.27 19.1,78.38 19.33,78.6 19.33,78.89 16.51,81.71 16.51,82.98 15.88,83.61 11.68,83.61 11.3,83.99 11.3,85.64 10.79,86.15 9.06,86.15 8.64,86.57 8.64,88.35 7.5,89.49 7.5,90.39 7.58,90.47 v2(8.03,90.47)
FMC1_HA12_N: length 91.1
  TOP w0.099: J48.F14 v2(11.84,89.2)
  TOP w0.124: U3.AH8 v2(70.9,68.93)
  L03-SIG1 w0.081: v2(70.9,68.93) 70.59,68.93 70.5,69.02 70.5,69.31 70.27,69.54 57.76,69.54 46.74,80.56 46.2,80.56 46,80.36 46,79.58 45.92,79.5 45.59,79.5 45.51,79.58 45.51,80.36 45.31,80.56 44.81,80.56 44.61,80.36 44.61,79.58 44.53,79.5 44.2,79.5 44.12,79.58 44.12,80.36 43.92,80.56 43.42,80.56 43.22,80.36 43.22,79.58 43.14,79.5 42.81,79.5 42.73,79.58 42.73,80.36 42.53,80.56 27.43,80.56 26.61,81.38 26.61,81.5 27.05,81.93 27.05,82.22 26.7,82.57 26.41,82.57 25.78,81.95 25.67,81.95 25.44,82.18 25.44,82.29 26.06,82.92 26.06,83.2 25.71,83.56 25.42,83.56 24.7,82.83 24.58,82.83 24.35,83.06 24.35,83.18 25.08,83.9 25.08,84.19 24.73,84.54 24.44,84.54 23.79,83.89 23.67,83.89 23.44,84.12 23.44,84.24 24.09,84.89 24.09,85.17 23.74,85.53 23.45,85.53 22.83,84.9 22.71,84.9 22.48,85.13 22.48,85.25 23.11,85.87 23.11,86.16 22.76,86.51 22.47,86.51 21.73,85.77 21.61,85.77 21.38,86 21.38,86.12 22.12,86.86 22.12,87.14 21.77,87.5 21.48,87.5 20.76,86.77 20.64,86.77 20.41,87 20.41,87.12 21.14,87.84 21.14,88.13 20.79,88.48 20.5,88.48 20.06,88.05 19.95,88.05 19.18,88.82 18.41,88.82 18.24,88.65 17.99,88.65 17.82,88.82 17.34,88.82 17.17,88.65 16.93,88.65 16.75,88.82 16.28,88.82 16.1,88.65 15.86,88.65 15.69,88.82 15.21,88.82 15.04,88.65 14.79,88.65 14.62,88.82 14.14,88.82 13.97,88.65 13.73,88.65 13.55,88.82 13.08,88.82 12.9,88.65 12.66,88.65 12.49,88.82 11.43,88.82 11.31,88.95 11.31,89.12 11.39,89.2 v2(11.84,89.2)
FMC1_HA12_P: length 91.3
  TOP w0.099: J48.F13 v2(10.57,89.2)
  TOP w0.124: U3.AH7 v2(69.9,68.93)
  L03-SIG1 w0.081: v2(10.57,89.2) 11.02,89.2 11.1,89.12 11.1,88.86 11.35,88.61 12.4,88.61 12.57,88.44 12.99,88.44 13.16,88.61 13.47,88.61 13.64,88.44 14.06,88.44 14.23,88.61 14.53,88.61 14.71,88.44 15.12,88.44 15.3,88.61 15.6,88.61 15.77,88.44 16.19,88.44 16.36,88.61 16.67,88.61 16.84,88.44 17.26,88.44 17.43,88.61 17.74,88.61 17.91,88.44 18.32,88.44 18.5,88.61 19.09,88.61 19.86,87.84 20.15,87.84 20.58,88.27 20.7,88.27 20.93,88.04 20.93,87.93 20.2,87.2 20.2,86.91 20.56,86.56 20.84,86.56 21.57,87.29 21.68,87.29 21.91,87.06 21.91,86.94 21.18,86.2 21.18,85.92 21.53,85.56 21.82,85.56 22.55,86.3 22.67,86.3 22.9,86.07 22.9,85.96 22.28,85.33 22.28,85.05 22.63,84.69 22.91,84.69 23.54,85.32 23.65,85.32 23.88,85.09 23.88,84.97 23.23,84.32 23.23,84.04 23.59,83.68 23.87,83.68 24.52,84.33 24.64,84.33 24.87,84.1 24.87,83.99 24.14,83.26 24.14,82.97 24.5,82.62 24.78,82.62 25.51,83.35 25.62,83.35 25.85,83.12 25.85,83 25.23,82.38 25.23,82.09 25.58,81.74 25.87,81.74 26.49,82.36 26.61,82.36 26.84,82.13 26.84,82.02 26.41,81.58 26.41,81.3 27.35,80.36 42.44,80.36 42.52,80.28 42.52,79.5 42.72,79.29 43.22,79.29 43.42,79.5 43.42,80.28 43.51,80.36 43.83,80.36 43.91,80.28 43.91,79.5 44.12,79.29 44.61,79.29 44.82,79.5 44.82,80.28 44.9,80.36 45.22,80.36 45.3,80.28 45.3,79.5 45.51,79.29 46.01,79.29 46.21,79.5 46.21,80.28 46.29,80.36 46.65,80.36 57.67,69.33 68.2,69.33 68.3,69.24 68.5,69.24 68.6,69.33 69.19,69.33 69.31,69.21 69.51,69.21 69.63,69.33 70.19,69.33 70.29,69.23 70.29,69.01 70.21,68.93 v2(69.9,68.93)
FMC1_HA13_N: length 92.6
  TOP w0.124: J48.E13 v2(13.11,90.47) ; U3.AG9 v2(71.9,69.93)
  L03-SIG1 w0.081: v2(13.11,90.47) 12.66,90.47 12.58,90.39 12.58,90.04 12.66,89.96 20.7,89.96 29.08,81.58 29.76,81.58 29.84,81.66 29.84,82.47 30.04,82.67 30.54,82.67 30.74,82.47 30.74,81.46 30.82,81.38 31.15,81.38 31.23,81.46 31.23,82.47 31.43,82.67 31.93,82.67 32.13,82.47 32.13,81.43 32.21,81.35 32.54,81.35 32.62,81.43 32.62,82.47 32.82,82.67 33.32,82.67 33.52,82.47 33.52,81.43 33.61,81.35 33.93,81.35 34.01,81.43 34.01,82.5 34.22,82.7 34.71,82.7 34.92,82.5 34.92,81.46 35,81.38 35.32,81.38 35.4,81.46 35.4,82.47 35.61,82.67 36.11,82.67 36.31,82.47 36.31,81.48 36.39,81.4 36.71,81.4 36.8,81.48 36.8,82.47 37,82.67 37.5,82.67 37.7,82.47 37.7,81.48 37.78,81.4 38.11,81.4 38.19,81.48 38.19,82.44 38.39,82.65 38.89,82.65 39.09,82.44 39.09,81.48 39.17,81.4 39.5,81.4 39.58,81.48 39.58,82.44 39.78,82.65 40.28,82.65 40.48,82.44 40.48,81.51 40.57,81.43 40.89,81.43 40.97,81.51 40.97,82.44 41.18,82.65 41.67,82.65 41.88,82.44 41.88,81.66 41.96,81.58 42.28,81.58 42.36,81.66 42.36,82.45 42.57,82.65 43.06,82.65 43.27,82.45 43.27,81.66 43.35,81.58 44.07,81.58 44.32,81.83 45.25,81.83 45.51,81.58 46.99,81.58 58.04,70.53 71.24,70.53 71.5,70.28 71.5,69.72 71.61,69.62 71.79,69.62 71.9,69.72 v2(71.9,69.93)
FMC1_HA13_P: length 92.9
  TOP w0.124: J48.E12 v2(11.84,90.47) ; U3.AH9 v2(71.9,68.93)
  L03-SIG1 w0.081: v2(11.84,90.47) 12.29,90.47 12.37,90.39 12.37,89.96 12.57,89.75 20.61,89.75 29,81.37 29.84,81.37 30.04,81.58 30.04,82.38 30.13,82.46 30.45,82.46 30.53,82.38 30.53,81.37 30.74,81.17 31.23,81.17 31.44,81.37 31.44,82.38 31.52,82.46 31.84,82.46 31.92,82.38 31.92,81.35 32.13,81.14 32.63,81.14 32.83,81.35 32.83,82.38 32.91,82.46 33.24,82.46 33.32,82.38 33.32,81.35 33.52,81.14 34.02,81.14 34.22,81.35 34.22,82.41 34.3,82.49 34.63,82.49 34.71,82.41 34.71,81.37 34.91,81.17 35.41,81.17 35.61,81.37 35.61,82.38 35.69,82.46 36.02,82.46 36.1,82.38 36.1,81.4 36.3,81.19 36.8,81.19 37,81.4 37,82.38 37.09,82.46 37.41,82.46 37.49,82.38 37.49,81.4 37.7,81.19 38.19,81.19 38.4,81.4 38.4,82.36 38.48,82.44 38.8,82.44 38.88,82.36 38.88,81.4 39.09,81.19 39.59,81.19 39.79,81.4 39.79,82.36 39.87,82.44 40.19,82.44 40.28,82.36 40.28,81.42 40.48,81.22 40.98,81.22 41.18,81.42 41.18,82.36 41.26,82.44 41.59,82.44 41.67,82.36 41.67,81.58 41.87,81.37 42.37,81.37 42.57,81.58 42.57,82.36 42.65,82.44 42.98,82.44 43.06,82.36 43.06,81.58 43.26,81.37 44.16,81.37 44.41,81.63 45.17,81.63 45.42,81.37 46.9,81.37 57.95,70.33 71.16,70.33 71.29,70.19 71.29,69.54 v2(71.9,68.93)
FMC1_HA14_N: length 85.7
  TOP w0.124: U3.AP8 v2(70.9,62.93) ; J48.J16 v2(6.76,86.66)
  L03-SIG1 w0.081: v2(6.76,86.66) 6.76,87.11 6.68,87.19 6.44,87.19 6.33,87.09 6.33,86.2 6.41,86.12 6.5,86.12 6.58,86.04 6.58,85.88 6.5,85.8 6.41,85.8 6.33,85.72 6.33,85.28 8,83.61 8.1,83.61 8.76,82.95 8.76,78.83 9.1,78.49 9.65,78.49 10.11,78.02 10.11,77.56 10.46,77.22 11.09,77.22 11.38,76.93 11.38,76.21 11.6,75.99 12.23,75.99 12.65,75.57 12.65,74.94 12.91,74.68 13.55,74.68 13.92,74.3 13.92,73.63 14.14,73.41 14.82,73.41 15.11,73.11 15.11,72.44 15.41,72.14 23.29,72.14 25.02,70.4 47.5,70.4 56.05,61.85 66.65,61.85 66.77,61.97 66.97,61.97 67.09,61.85 67.3,61.85 67.42,61.97 67.62,61.97 67.74,61.85 67.95,61.85 68.07,61.97 68.27,61.97 68.39,61.85 68.6,61.85 68.72,61.97 68.92,61.97 69.04,61.85 69.25,61.85 69.37,61.97 69.57,61.97 69.69,61.85 69.9,61.85 70.02,61.97 70.22,61.97 70.34,61.85 70.65,61.85 70.82,62.02 70.82,62.13 70.73,62.22 70.73,62.34 70.84,62.46 70.96,62.46 71.05,62.36 71.16,62.36 71.29,62.49 71.29,62.85 71.21,62.93 v2(70.9,62.93)
FMC1_HA14_P: length 85.3
  TOP w0.124: J48.J15 v2(6.76,87.93) ; U3.AP9 v2(71.9,62.93)
  L03-SIG1 w0.081: v2(6.76,87.93) 6.76,87.63 6.53,87.4 6.35,87.4 6.12,87.17 6.12,85.2 7.91,83.4 8.02,83.4 8.55,82.87 8.55,78.74 9.02,78.28 9.56,78.28 9.91,77.93 9.91,77.48 10.37,77.01 11.01,77.01 11.18,76.84 11.18,76.12 11.51,75.78 12.15,75.78 12.45,75.48 12.45,74.85 12.83,74.47 13.46,74.47 13.72,74.21 13.72,73.54 14.06,73.2 14.73,73.2 14.9,73.03 14.9,72.35 15.33,71.93 23.2,71.93 24.93,70.2 47.41,70.2 55.97,61.64 70.74,61.64 71.5,62.41 71.5,62.79 71.65,62.93 v2(71.9,62.93)
FMC1_HA15_N: length 89.1
  TOP w0.124: U3.AK6 v2(68.9,66.93) ; 11.2,84.76 v2(11.84,84.12)
  L03-SIG1 w0.081: v2(11.84,84.12) 11.84,84.57 11.92,84.65 16.95,84.65 17.73,83.87 17.73,83.76 17.36,83.39 17.36,83.1 17.71,82.75 18,82.75 18.37,83.12 18.49,83.12 18.72,82.89 18.72,82.78 18.41,82.47 18.41,82.18 18.76,81.83 19.05,81.83 19.36,82.14 19.47,82.14 19.7,81.9 19.7,81.79 18.73,80.82 18.73,80.54 19.09,80.18 19.37,80.18 20.34,81.15 20.46,81.15 20.69,80.92 20.69,80.81 19.76,79.88 19.76,79.59 20.11,79.24 20.4,79.24 21.33,80.17 21.44,80.17 21.67,79.93 21.67,79.82 20.76,78.9 20.76,78.62 21.11,78.26 21.39,78.26 22.31,79.18 22.43,79.18 22.66,78.95 22.66,78.83 21.8,77.98 21.8,77.69 22.16,77.34 22.44,77.34 23.3,78.2 23.41,78.2 23.64,77.96 23.64,77.85 22.81,77.02 22.81,76.73 23.17,76.38 23.45,76.38 24.28,77.21 24.4,77.21 25.06,76.55 26.09,76.55 26.29,76.75 26.29,77.35 26.37,77.44 26.7,77.44 26.78,77.35 26.78,76.75 26.98,76.55 27.48,76.55 27.68,76.75 27.68,77.35 27.76,77.44 28.09,77.44 28.17,77.35 28.17,76.75 28.37,76.55 28.87,76.55 29.08,76.75 29.08,77.35 29.16,77.44 29.48,77.44 29.56,77.35 29.56,76.75 29.77,76.55 30.26,76.55 30.47,76.75 30.47,77.35 30.55,77.44 30.87,77.44 30.95,77.35 30.95,76.75 31.16,76.55 46.9,76.55 57.14,66.31 68.28,66.31 v2(68.9,66.93)
FMC1_HA15_P: length 89.2
  TOP w0.124: U3.AK5 v2(67.9,66.93) ; J48.F16 v2(11.84,85.39)
  L03-SIG1 w0.081: v2(11.84,85.39) 11.84,84.94 11.92,84.86 17.04,84.86 17.94,83.96 17.94,83.67 17.57,83.3 17.57,83.19 17.8,82.96 17.91,82.96 18.28,83.33 18.57,83.33 18.92,82.98 18.92,82.69 18.62,82.38 18.62,82.27 18.85,82.04 18.96,82.04 19.27,82.34 19.56,82.34 19.91,81.99 19.91,81.7 18.94,80.74 18.94,80.62 19.17,80.39 19.29,80.39 20.25,81.36 20.54,81.36 20.89,81.01 20.89,80.72 19.97,79.79 19.97,79.67 20.2,79.44 20.31,79.44 21.24,80.37 21.53,80.37 21.88,80.02 21.88,79.73 20.96,78.82 20.96,78.7 21.19,78.47 21.31,78.47 22.22,79.39 22.51,79.39 22.86,79.04 22.86,78.75 22.01,77.9 22.01,77.78 22.24,77.55 22.36,77.55 23.21,78.4 23.5,78.4 23.85,78.05 23.85,77.76 23.02,76.94 23.02,76.82 23.25,76.59 23.37,76.59 24.19,77.42 24.48,77.42 25.15,76.75 26,76.75 26.08,76.84 26.08,77.44 26.29,77.64 26.78,77.64 26.99,77.44 26.99,76.84 27.07,76.75 27.39,76.75 27.47,76.84 27.47,77.44 27.68,77.64 28.18,77.64 28.38,77.44 28.38,76.84 28.46,76.75 28.79,76.75 28.87,76.84 28.87,77.44 29.07,77.64 29.57,77.64 29.77,77.44 29.77,76.84 29.85,76.75 30.18,76.75 30.26,76.84 30.26,77.44 30.46,77.64 30.96,77.64 31.16,77.44 31.16,76.84 31.24,76.75 46.99,76.75 57.23,66.52 65.13,66.52 65.25,66.65 65.51,66.65 65.63,66.52 66.12,66.52 66.24,66.65 66.55,66.65 66.67,66.52 67.13,66.52 67.23,66.62 67.59,66.62 67.69,66.52 68.19,66.52 68.29,66.62 68.29,66.85 68.21,66.93 v2(67.9,66.93)
FMC1_HA16_N: length 91.8
  TOP w0.124: J48.E16 v2(13.11,86.66) ; U3.AK11 v2(73.9,66.93)
  L03-SIG1 w0.081: v2(13.11,86.66) 13.11,87.11 13.19,87.19 18.73,87.19 20.12,85.8 20.12,85.69 19.46,85.02 19.46,84.74 19.81,84.38 20.1,84.38 20.76,85.05 20.88,85.05 21.11,84.82 21.11,84.7 20.41,84 20.41,83.71 20.76,83.36 21.05,83.36 21.75,84.06 21.86,84.06 22.09,83.83 22.09,83.72 21.43,83.05 21.43,82.77 21.78,82.41 22.07,82.41 22.73,83.08 22.85,83.08 23.08,82.85 23.08,82.73 22.44,82.09 22.44,81.81 22.79,81.45 23.08,81.45 23.72,82.09 23.83,82.09 24.06,81.86 24.06,81.75 23.38,81.06 23.38,80.77 23.73,80.42 24.02,80.42 24.7,81.11 24.82,81.11 25.05,80.88 25.05,80.76 24.42,80.14 24.42,79.85 24.78,79.5 25.06,79.5 25.69,80.12 25.8,80.12 26.5,79.42 38.73,79.42 38.81,79.34 38.81,78.4 39.01,78.2 39.51,78.2 39.71,78.4 39.71,79.49 39.79,79.57 40.12,79.57 40.2,79.49 40.2,78.4 40.4,78.2 40.9,78.2 41.1,78.4 41.1,79.49 41.19,79.57 41.51,79.57 41.59,79.49 41.59,78.61 41.79,78.41 41.94,78.41 42.17,78.18 42.73,78.18 42.96,78.41 43.34,78.41 43.57,78.18 44.12,78.18 44.35,78.41 44.73,78.41 44.96,78.18 45.51,78.18 45.74,78.41 46.12,78.41 46.35,78.18 46.9,78.18 47.13,78.41 47.46,78.41 57.54,68.33 58.07,68.33 58.31,68.57 58.68,68.57 58.92,68.33 59.46,68.33 59.71,68.57 60.07,68.57 60.32,68.33 61.22,68.33 61.41,68.14 61.87,68.14 62.17,68.44 62.62,68.44 62.92,68.14 63.38,68.14 63.56,68.33 71.13,68.33 71.3,68.15 71.3,67.66 71.6,67.36 72.02,67.36 72.31,67.06 72.31,66.65 72.62,66.34 73.3,66.34 v2(73.9,66.93)
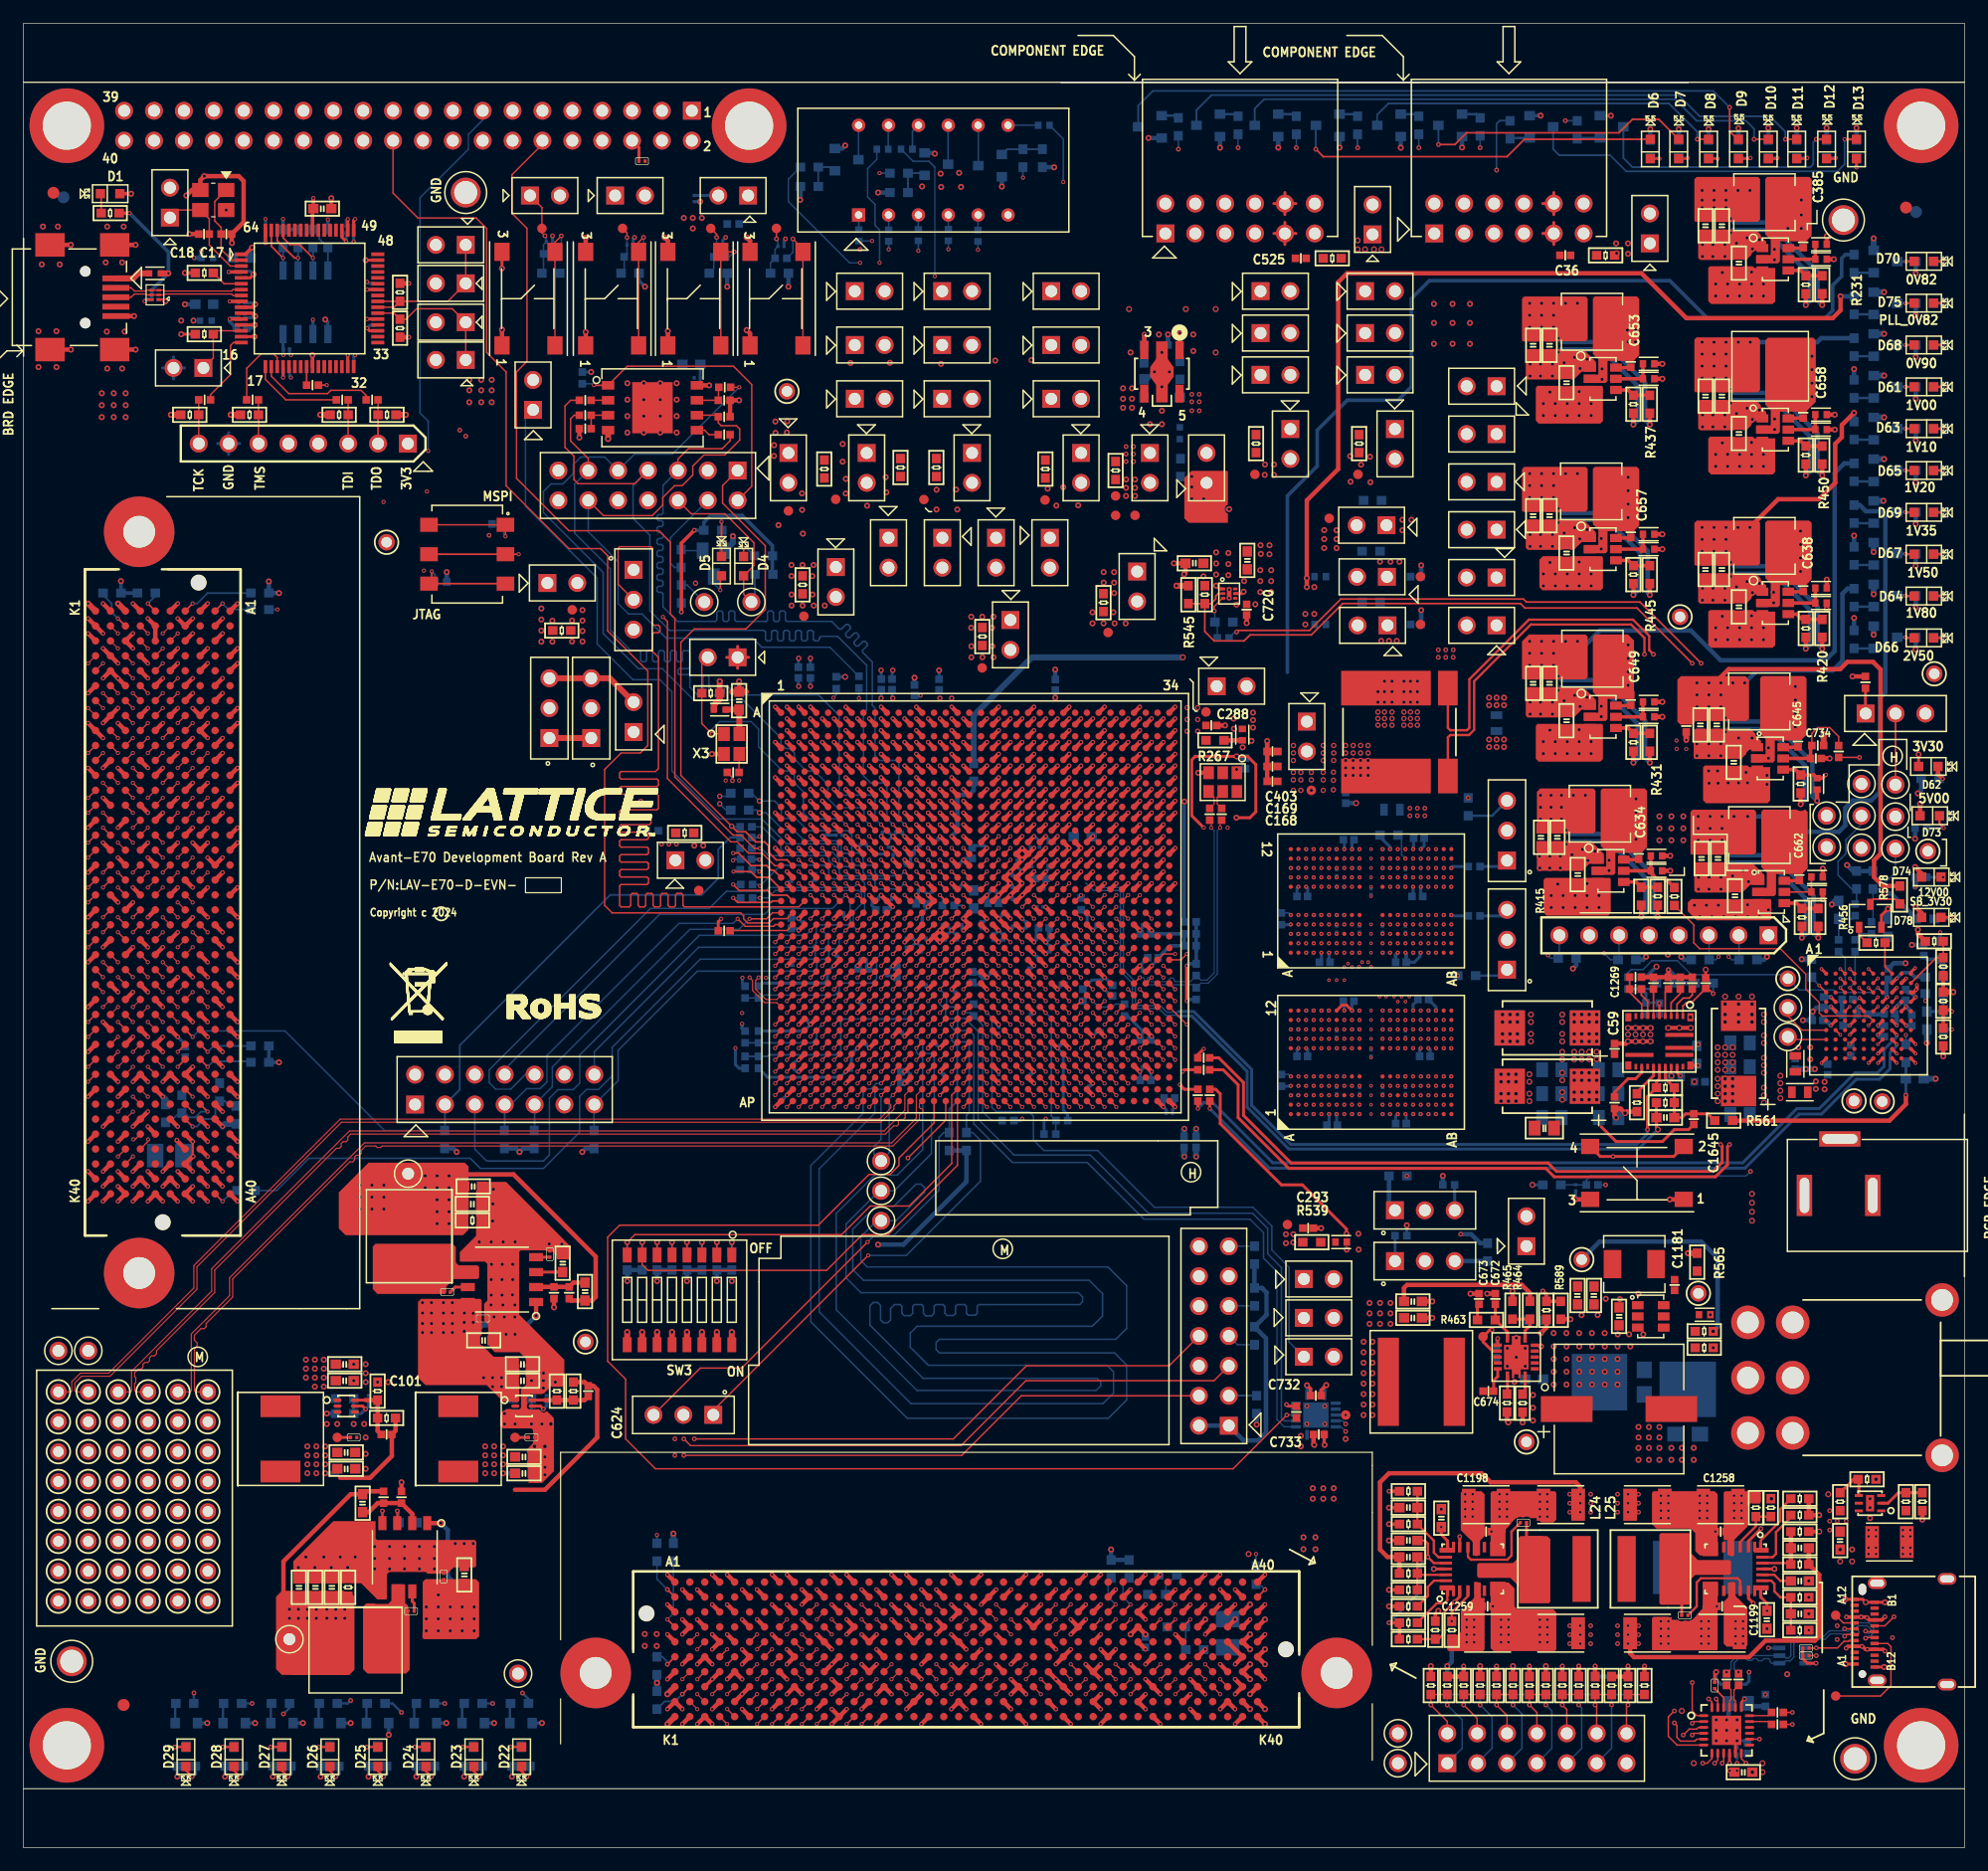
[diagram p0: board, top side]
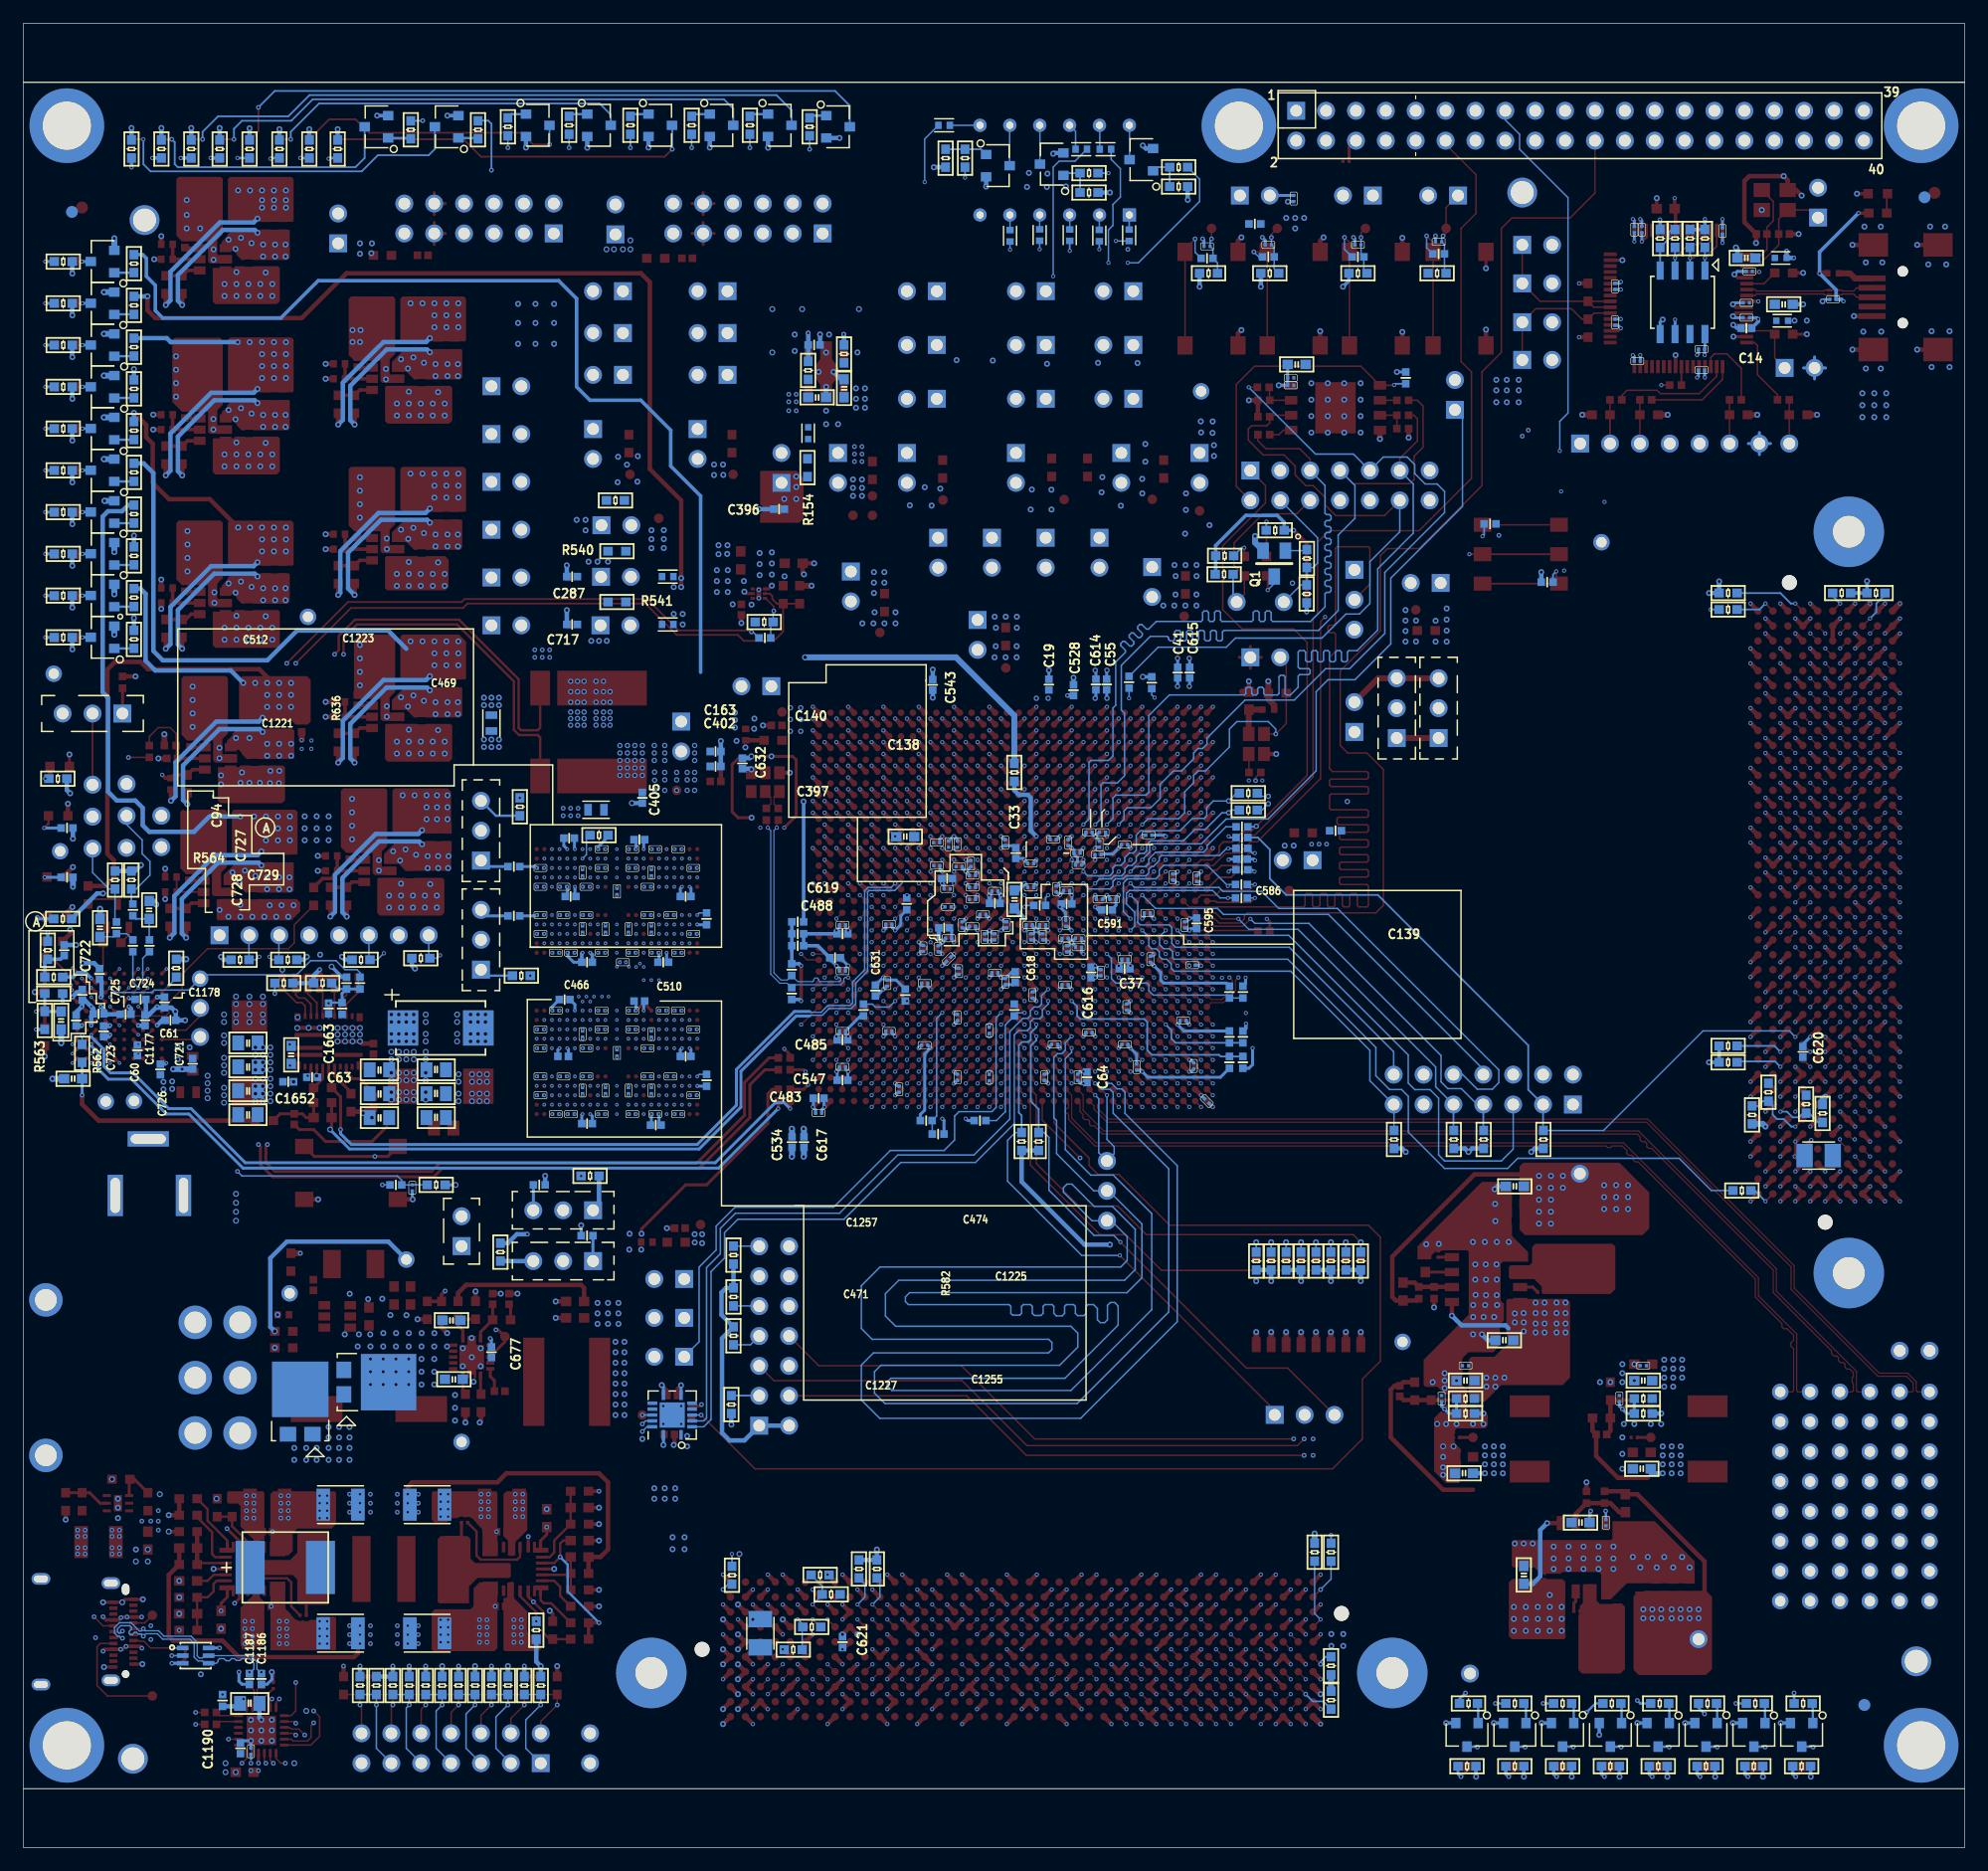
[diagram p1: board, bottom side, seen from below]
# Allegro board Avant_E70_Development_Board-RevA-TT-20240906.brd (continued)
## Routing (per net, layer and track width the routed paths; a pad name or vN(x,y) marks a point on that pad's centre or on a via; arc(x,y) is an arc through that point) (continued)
FMC1_HA16_P: length 92.1
  TOP w0.124: U3.AK10 v2(72.9,66.93) ; J48.E15 v2(13.11,87.93)
  L03-SIG1 w0.081: v2(13.11,87.93) 13.11,87.48 13.19,87.4 18.82,87.4 20.33,85.89 20.33,85.6 19.67,84.94 19.67,84.82 19.9,84.59 20.01,84.59 20.68,85.25 20.96,85.25 21.32,84.9 21.32,84.61 20.62,83.91 20.62,83.8 20.85,83.57 20.96,83.57 21.66,84.27 21.95,84.27 22.3,83.92 22.3,83.63 21.64,82.97 21.64,82.85 21.87,82.62 21.98,82.62 22.65,83.28 22.93,83.28 23.29,82.93 23.29,82.64 22.65,82.01 22.65,81.89 22.88,81.66 23,81.66 23.63,82.3 23.92,82.3 24.27,81.95 24.27,81.66 23.58,80.97 23.58,80.86 23.81,80.63 23.93,80.63 24.62,81.31 24.9,81.31 25.26,80.96 25.26,80.67 24.63,80.05 24.63,79.94 24.86,79.7 24.98,79.7 25.6,80.33 25.89,80.33 26.59,79.63 38.81,79.63 39.02,79.43 39.02,78.49 39.1,78.41 39.42,78.41 39.5,78.49 39.5,79.58 39.71,79.78 40.2,79.78 40.41,79.58 40.41,78.49 40.49,78.41 40.81,78.41 40.9,78.49 40.9,79.57 41.1,79.78 41.6,79.78 41.8,79.57 41.8,78.7 41.88,78.61 42.03,78.61 42.26,78.39 42.64,78.39 42.87,78.61 43.42,78.61 43.65,78.39 44.03,78.39 44.26,78.61 44.81,78.61 45.04,78.39 45.42,78.39 45.65,78.61 46.21,78.61 46.44,78.39 46.82,78.39 47.04,78.61 47.54,78.61 57.62,68.53 57.98,68.53 58.23,68.78 58.77,68.78 59.01,68.53 59.37,68.53 59.62,68.78 60.16,68.78 60.4,68.53 61.31,68.53 61.49,68.35 61.78,68.35 62.08,68.65 62.7,68.65 63,68.35 63.29,68.35 63.47,68.53 71.21,68.53 71.51,68.24 71.51,67.75 71.69,67.57 72.11,67.57 72.52,67.15 72.52,66.73 72.71,66.54 73.22,66.54 73.48,66.81 73.48,67 73.4,67.08 73.05,67.08 v2(72.9,66.93)
FMC1_HA17_CLK_N: length 83.9
  TOP w0.124: 6.12,84.76 v2(5.49,84.12) ; U3.AP7 v2(69.9,62.93)
  L10-SIG3 w0.081: v2(5.49,84.12) 5.44,84.17 5.44,84.56 5.52,84.64 5.68,84.64 6.01,84.31 6.01,70.06 8.04,68.04 13.4,68.04 14.54,66.89 17.24,66.89 19.78,64.35 49.57,64.35 50.6,63.33 69.5,63.33 v2(69.9,62.93)
FMC1_HA17_CLK_P: length 83.8
  TOP w0.124: J48.K16 v2(5.49,85.39) ; U3.AN7 v2(69.9,63.93)
  L10-SIG3 w0.081: v2(5.49,85.39) 5.49,84.94 5.58,84.85 5.77,84.85 6.22,84.4 6.22,70.15 8.13,68.25 13.49,68.25 14.63,67.1 17.32,67.1 19.86,64.56 49.66,64.56 50.69,63.53 69.5,63.53 v2(69.9,63.93)
FMC1_HA18_N: length 87.9
  TOP w0.124: J48.J19 v2(6.76,81.58) ; U3.AM9 v2(71.9,64.93)
  L03-SIG1 w0.081: v2(71.9,64.93) 71.58,64.93 71.5,64.85 71.5,64.65 71.62,64.54 72.13,64.54 72.52,64.15 72.52,61.67 71.62,60.77 55.57,60.77 47.08,69.26 46.18,69.26 46.1,69.18 46.1,68.8 45.9,68.6 45.4,68.6 45.2,68.8 45.2,69.18 45.11,69.26 24.38,69.26 22.86,70.79 14.95,70.79 13.81,71.92 7.76,71.92 7.28,72.4 7.28,81.88 7.05,82.11 6.84,82.11 6.76,82.03 v2(6.76,81.58)
FMC1_HA18_P: length 87.6
  TOP w0.124: U3.AM8 v2(70.9,64.93) ; J48.J18 v2(6.76,82.85)
  L03-SIG1 w0.081: v2(70.9,64.93) 71.21,64.93 71.29,64.85 71.29,64.57 71.53,64.33 72.04,64.33 72.31,64.06 72.31,61.75 71.54,60.98 55.65,60.98 47.16,69.47 46.1,69.47 45.89,69.27 45.89,68.89 45.81,68.81 45.49,68.81 45.4,68.89 45.4,69.27 45.2,69.47 24.47,69.47 22.95,70.99 15.03,70.99 13.89,72.13 7.85,72.13 7.49,72.49 7.49,81.96 7.13,82.32 6.84,82.32 6.76,82.4 v2(6.76,82.85)
FMC1_HA19_N: length 90.6
  TOP w0.099: J48.F20 v2(11.84,81.58)
  TOP w0.124: U3.AK8 v2(70.9,66.93)
  L03-SIG1 w0.081: v2(70.9,66.93) 71,67.03 71.37,67.03 71.45,66.95 71.45,66.75 71.17,66.47 70.66,66.47 70.51,66.62 70.26,66.62 70.1,66.47 69.55,66.47 69.34,66.26 69.34,64.64 69.22,64.51 69.22,64.31 69.34,64.18 69.34,63.8 69.09,63.55 68.61,63.55 68.48,63.67 68.25,63.67 68.12,63.55 56.77,63.55 48.01,72.31 45.97,72.31 45.89,72.39 45.89,72.61 45.69,72.82 45.19,72.82 44.99,72.61 44.99,72.39 44.9,72.31 44.58,72.31 44.5,72.39 44.5,72.72 44.3,72.92 43.8,72.92 43.59,72.72 43.59,72.39 43.51,72.31 43.11,72.31 43.03,72.39 43.03,72.82 42.83,73.02 42.33,73.02 42.13,72.82 42.13,72.39 42.05,72.31 41.72,72.31 41.64,72.39 41.64,72.84 41.44,73.05 40.94,73.05 40.73,72.84 40.73,72.39 40.65,72.31 40.33,72.31 40.25,72.39 40.25,72.84 40.04,73.05 39.55,73.05 39.34,72.84 39.34,72.39 39.26,72.31 38.94,72.31 38.86,72.39 38.86,72.84 38.65,73.05 38.15,73.05 37.95,72.84 37.95,72.39 37.87,72.31 37.54,72.31 37.46,72.39 37.46,72.87 37.26,73.07 36.76,73.07 36.56,72.87 36.56,72.39 36.48,72.31 36.15,72.31 36.07,72.39 36.07,72.87 35.87,73.07 35.37,73.07 35.17,72.87 35.17,72.39 35.09,72.31 34.76,72.31 34.68,72.39 34.68,72.87 34.48,73.07 33.98,73.07 33.78,72.87 33.78,72.39 33.69,72.31 33.37,72.31 33.29,72.39 33.29,72.89 33.08,73.1 32.59,73.1 32.38,72.89 32.38,72.39 32.3,72.31 31.98,72.31 31.9,72.39 31.9,72.89 31.69,73.1 31.19,73.1 30.99,72.89 30.99,72.39 30.91,72.31 30.58,72.31 30.5,72.39 30.5,72.89 30.3,73.1 29.8,73.1 29.6,72.89 29.6,72.39 29.52,72.31 29.19,72.31 29.11,72.39 29.11,72.87 28.91,73.07 28.41,73.07 28.21,72.87 28.21,72.39 28.13,72.31 27.8,72.31 27.72,72.39 27.72,72.89 27.52,73.1 27.02,73.1 26.82,72.89 26.82,72.39 26.73,72.31 25.91,72.31 24.13,74.09 19.04,74.09 18.28,74.85 17.44,74.85 15.19,77.1 15.19,77.94 14.52,78.61 14.02,78.61 13.8,78.83 13.8,79.25 13.25,79.8 12.42,79.8 11.31,80.92 11.31,81.5 11.39,81.58 v2(11.84,81.58)
FMC1_HA19_P: length 90.4
  TOP w0.099: J48.F19 v2(10.57,81.58)
  TOP w0.124: U3.AK9 v2(71.9,66.93)
  L03-SIG1 w0.081: v2(10.57,81.58) 11.02,81.58 11.1,81.5 11.1,80.83 12.33,79.59 13.16,79.59 13.59,79.17 13.59,78.75 13.93,78.41 14.44,78.41 14.99,77.86 14.99,77.01 17.35,74.64 18.2,74.64 18.96,73.88 24.04,73.88 25.82,72.1 26.82,72.1 27.02,72.3 27.02,72.81 27.11,72.89 27.43,72.89 27.51,72.81 27.51,72.3 27.71,72.1 28.21,72.1 28.42,72.3 28.42,72.78 28.5,72.86 28.82,72.86 28.9,72.78 28.9,72.3 29.11,72.1 29.6,72.1 29.81,72.3 29.81,72.81 29.89,72.89 30.21,72.89 30.3,72.81 30.3,72.3 30.5,72.1 31,72.1 31.2,72.3 31.2,72.81 31.28,72.89 31.61,72.89 31.69,72.81 31.69,72.3 31.89,72.1 32.39,72.1 32.59,72.3 32.59,72.81 32.67,72.89 33,72.89 33.08,72.81 33.08,72.3 33.28,72.1 33.78,72.1 33.98,72.3 33.98,72.78 34.06,72.86 34.39,72.86 34.47,72.78 34.47,72.3 34.67,72.1 35.17,72.1 35.38,72.3 35.38,72.78 35.46,72.86 35.78,72.86 35.86,72.78 35.86,72.3 36.07,72.1 36.56,72.1 36.77,72.3 36.77,72.78 36.85,72.86 37.17,72.86 37.25,72.78 37.25,72.3 37.46,72.1 37.96,72.1 38.16,72.3 38.16,72.76 38.24,72.84 38.57,72.84 38.65,72.76 38.65,72.3 38.85,72.1 39.35,72.1 39.55,72.3 39.55,72.76 39.63,72.84 39.96,72.84 40.04,72.76 40.04,72.3 40.24,72.1 40.74,72.1 40.94,72.3 40.94,72.76 41.02,72.84 41.35,72.84 41.43,72.76 41.43,72.3 41.63,72.1 42.13,72.1 42.33,72.3 42.33,72.73 42.42,72.81 42.74,72.81 42.82,72.73 42.82,72.3 43.03,72.1 43.6,72.1 43.8,72.3 43.8,72.63 43.88,72.71 44.21,72.71 44.29,72.63 44.29,72.3 44.49,72.1 44.99,72.1 45.19,72.3 45.19,72.53 45.28,72.61 45.6,72.61 45.68,72.53 45.68,72.3 45.89,72.1 47.92,72.1 56.68,63.34 69.17,63.34 69.55,63.71 69.55,66.18 69.63,66.26 71.25,66.26 71.9,66.9 v2(71.9,66.93)
FMC1_HA20_N: length 87.3
  TOP w0.099: J48.E19 v2(13.11,82.85)
  TOP w0.124: U3.AM5 v2(67.9,64.93)
  L03-SIG1 w0.081: v2(67.9,64.93) 68.21,64.93 68.29,64.85 68.29,64.6 68.21,64.52 67.66,64.52 67.49,64.69 67.26,64.69 67.09,64.52 66.67,64.52 66.5,64.69 66.27,64.69 66.1,64.52 65.74,64.52 65.56,64.69 65.28,64.69 65.11,64.52 64.76,64.52 64.59,64.69 64.36,64.69 64.19,64.52 63.7,64.52 63.55,64.66 63.29,64.66 63.14,64.52 56.94,64.52 47.54,73.92 37.05,73.92 36.97,74 36.97,74.55 36.77,74.75 36.27,74.75 36.06,74.55 36.06,74 35.98,73.92 35.66,73.92 35.58,74 35.58,74.77 35.37,74.98 34.88,74.98 34.67,74.77 34.67,74 34.59,73.92 34.27,73.92 34.19,74 34.19,74.77 33.98,74.98 33.48,74.98 33.28,74.77 33.28,74 33.2,73.92 32.87,73.92 32.79,74 32.79,74.77 32.59,74.98 32.09,74.98 31.89,74.77 31.89,74 31.81,73.92 31.48,73.92 31.4,74 31.4,74.77 31.2,74.98 30.7,74.98 30.5,74.77 30.5,74 30.42,73.92 30.09,73.92 30.01,74 30.01,74.77 29.81,74.98 29.31,74.98 29.11,74.77 29.11,74 29.02,73.92 28.7,73.92 28.62,74 28.62,74.77 28.41,74.98 27.92,74.98 27.71,74.77 27.71,74 27.63,73.92 27.31,73.92 27.23,74 27.23,74.77 27.02,74.98 26.52,74.98 26.32,74.77 26.32,74 26.24,73.92 25.91,73.92 25.83,74 25.83,74.77 25.63,74.98 20.95,74.98 20.65,75.28 20.25,75.28 19.79,74.82 19.68,74.82 19.45,75.05 19.45,75.17 19.96,75.68 19.96,75.97 19.61,76.32 19.32,76.32 18.81,75.81 18.69,75.81 18.46,76.04 18.46,76.15 18.98,76.67 18.98,76.96 18.62,77.31 18.34,77.31 17.82,76.79 17.71,76.79 17.48,77.02 17.48,77.14 17.99,77.65 17.99,77.94 14.86,81.07 14.33,81.07 14.23,81.17 14,81.17 13.9,81.07 13.68,81.07 13.58,81.17 13.35,81.17 13.25,81.07 12.83,81.07 12.58,81.32 12.58,82.04 12.7,82.16 12.7,82.36 12.58,82.49 12.58,82.77 12.66,82.85 v2(13.11,82.85)
FMC1_HA20_P: length 87
  TOP w0.099: J48.E18 v2(11.84,82.85)
  TOP w0.124: U3.AM6 v2(68.9,64.93)
  L03-SIG1 w0.081: v2(68.9,64.93) 68.69,64.93 68.5,64.74 68.5,64.51 68.3,64.31 56.86,64.31 47.46,73.71 36.96,73.71 36.76,73.91 36.76,74.46 36.68,74.55 36.35,74.55 36.27,74.46 36.27,73.91 36.07,73.71 35.57,73.71 35.37,73.91 35.37,74.69 35.29,74.77 34.96,74.77 34.88,74.69 34.88,73.91 34.68,73.71 34.18,73.71 33.98,73.91 33.98,74.69 33.9,74.77 33.57,74.77 33.49,74.69 33.49,73.91 33.29,73.71 32.79,73.71 32.58,73.91 32.58,74.69 32.5,74.77 32.18,74.77 32.1,74.69 32.1,73.91 31.89,73.71 31.4,73.71 31.19,73.91 31.19,74.69 31.11,74.77 30.79,74.77 30.71,74.69 30.71,73.91 30.5,73.71 30,73.71 29.8,73.91 29.8,74.69 29.72,74.77 29.39,74.77 29.31,74.69 29.31,73.91 29.11,73.71 28.61,73.71 28.41,73.91 28.41,74.69 28.33,74.77 28,74.77 27.92,74.69 27.92,73.91 27.72,73.71 27.22,73.71 27.02,73.91 27.02,74.69 26.94,74.77 26.61,74.77 26.53,74.69 26.53,73.91 26.33,73.71 25.83,73.71 25.63,73.91 25.63,74.69 25.54,74.77 20.87,74.77 20.56,75.07 20.34,75.07 19.88,74.61 19.59,74.61 19.24,74.97 19.24,75.25 19.75,75.77 19.75,75.88 19.52,76.11 19.41,76.11 18.89,75.6 18.61,75.6 18.25,75.95 18.25,76.24 18.77,76.75 18.77,76.87 18.54,77.1 18.42,77.1 17.91,76.58 17.62,76.58 17.27,76.94 17.27,77.22 17.78,77.74 17.78,77.85 14.77,80.86 12.74,80.86 12.37,81.24 12.37,82.77 12.29,82.85 v2(11.84,82.85)
FMC1_HA21_N: length 83.8
  TOP w0.124: U3.AN5 v2(67.9,63.93) ; J48.K20 v2(5.49,80.31)
  L12-SIG4 w0.081: v2(67.9,63.93) 68.29,63.93 68.37,64.01 68.37,64.16 68.21,64.33 67.58,64.33 67.44,64.18 67.27,64.18 67.13,64.33 66.84,64.33 66.55,64.04 66.55,63.67 66.67,63.55 66.67,63.29 66.55,63.17 66.55,62.66 64.82,60.93 23.2,60.93 17.35,66.77 7.79,66.77 7.28,67.27 7.28,79.4 6.44,80.24 6.33,80.24 6.25,80.17 6.14,80.17 6.02,80.28 6.02,80.4 6.1,80.47 6.1,80.59 5.84,80.84 5.57,80.84 5.49,80.76 v2(5.49,80.31)
FMC1_HA21_P: length 83.3
  TOP w0.124: U3.AN6 v2(68.9,63.93) ; J48.K19 v2(5.49,81.58)
  L12-SIG4 w0.081: v2(5.49,81.58) 5.49,81.13 5.57,81.05 5.93,81.05 7.49,79.49 7.49,67.36 7.87,66.98 17.44,66.98 23.28,61.13 64.73,61.13 66.34,62.74 66.34,64.13 66.75,64.54 68.29,64.54 v2(68.9,63.93)
FMC1_HA22_N: length 82.2
  TOP w0.124: U3.AP6 v2(68.9,62.93) ; J48.J22 v2(6.76,77.77)
  L12-SIG4 w0.081: v2(68.9,62.93) 68.58,62.93 68.5,63.01 68.5,63.32 68.28,63.55 67.64,63.55 67.31,63.22 67.31,62.28 65.28,60.24 20.83,60.24 17.78,63.29 13.97,63.29 12.7,64.56 7.62,64.56 6.22,65.96 6.22,78.12 6.38,78.27 6.68,78.27 6.76,78.19 v2(6.76,77.77)
FMC1_HA22_P: length 82.6
  TOP w0.124: J48.J21 v2(6.76,79.04) ; U3.AP5 v2(67.9,62.93)
  L12-SIG4 w0.081: v2(67.9,62.93) 68.21,62.93 68.29,63.01 68.29,63.23 68.19,63.34 67.73,63.34 67.52,63.13 67.52,62.19 65.36,60.04 20.74,60.04 17.69,63.08 13.88,63.08 12.61,64.35 7.53,64.35 6.01,65.87 6.01,78.2 6.29,78.48 6.68,78.48 6.76,78.56 v2(6.76,79.04)
FMC1_HA23_N: length 84.6
  TOP w0.124: J48.K23 v2(5.49,76.5) ; U3.AN8 v2(70.9,63.93)
  L10-SIG3 w0.081: v2(70.9,63.93) 71.21,63.93 71.29,63.85 71.29,63.64 71.21,63.55 71.1,63.55 71.02,63.47 71.02,63.31 71.1,63.23 71.21,63.23 71.29,63.15 71.29,62.7 71.06,62.46 70.87,62.46 70.73,62.32 70.73,62.13 70.5,61.9 69.98,61.9 69.88,62 69.65,62 69.55,61.9 69.33,61.9 69.22,62 69,62 68.9,61.9 68.57,61.9 68.46,62 68.24,62 68.14,61.9 19.05,61.9 16.38,64.56 7.09,64.56 6.73,64.92 6.73,67.61 6.01,68.33 5.28,68.33 5.1,68.51 5.1,75.66 5.18,75.74 5.33,75.74 5.41,75.83 5.41,75.99 5.33,76.07 5.18,76.07 5.1,76.15 5.1,76.9 5.26,77.07 5.41,77.07 5.49,76.98 v2(5.49,76.5)
FMC1_HA23_P: length 84.2
  TOP w0.124: J48.K22 v2(5.49,77.77) ; U3.AN9 v2(71.9,63.93)
  L10-SIG3 w0.081: v2(5.49,77.77) 5.49,77.61 4.89,77.01 4.89,68.42 5.19,68.12 5.93,68.12 6.52,67.52 6.52,64.83 7,64.35 16.3,64.35 18.96,61.69 70.58,61.69 71.5,62.61 71.5,63.83 71.6,63.93 v2(71.9,63.93)
FMC1_HB00_N_CC: length 89.1
  TOP w0.124: J48.K26 v2(6.76,72.69)
  TOP w0.152: U3.AC1 v2(63.9,73.93)
  L05-SIG2 w0.081: v2(63.9,73.93) 63.9,74.24 63.82,74.33 60.8,74.33 60.69,74.21 60.48,74.21 60.37,74.33 60.15,74.33 60.07,74.24 59.8,74.24 59.72,74.33 59.5,74.33 59.42,74.24 59.15,74.24 59.07,74.33 57.86,74.33 55.56,76.63 49.96,76.63 40.59,86 31.55,86 31.34,86.2 31.34,86.75 31.26,86.83 30.94,86.83 30.86,86.75 30.86,86.2 30.65,86 30.16,86 29.95,86.2 29.95,86.75 29.87,86.83 29.55,86.83 29.46,86.75 29.46,86.2 29.26,86 28.76,86 28.56,86.2 28.56,86.75 28.48,86.83 28.15,86.83 28.07,86.75 28.07,86.2 27.87,86 27.37,86 27.17,86.2 27.17,86.75 27.09,86.83 26.76,86.83 26.68,86.75 26.68,86.2 26.48,86 25.98,86 25.78,86.2 25.78,86.75 25.7,86.83 25.37,86.83 25.29,86.75 25.29,86.2 25.09,86 24.59,86 24.38,86.2 24.38,86.75 24.3,86.83 23.98,86.83 23.9,86.75 23.9,86.2 23.69,86 23.2,86 22.99,86.2 22.99,86.75 22.91,86.83 22.59,86.83 22.51,86.75 22.51,86.2 22.3,86 21.8,86 21.6,86.2 21.6,86.75 21.52,86.83 21.19,86.83 21.11,86.75 21.11,86.2 20.91,86 20.41,86 20.21,86.2 20.21,86.75 20.13,86.83 19.8,86.83 19.72,86.75 19.72,86.2 19.52,86 7.7,86 7.45,85.75 7.45,73.47 7.2,73.22 6.84,73.22 6.76,73.14 v2(6.76,72.69)
FMC1_HB00_P_CC: length 88.9
  TOP w0.124: J48.K25 v2(6.76,73.96)
  TOP w0.152: U3.AB1 v2(63.9,74.93)
  L05-SIG2 w0.081: v2(63.9,74.93) 63.9,74.62 63.82,74.53 57.95,74.53 55.65,76.84 50.05,76.84 40.68,86.21 31.63,86.21 31.55,86.29 31.55,86.84 31.35,87.04 30.85,87.04 30.65,86.84 30.65,86.29 30.57,86.21 30.24,86.21 30.16,86.29 30.16,86.84 29.96,87.04 29.46,87.04 29.26,86.84 29.26,86.29 29.18,86.21 28.85,86.21 28.77,86.29 28.77,86.84 28.57,87.04 28.07,87.04 27.86,86.84 27.86,86.29 27.78,86.21 27.46,86.21 27.38,86.29 27.38,86.84 27.17,87.04 26.68,87.04 26.47,86.84 26.47,86.29 26.39,86.21 26.07,86.21 25.98,86.29 25.98,86.84 25.78,87.04 25.28,87.04 25.08,86.84 25.08,86.29 25,86.21 24.67,86.21 24.59,86.29 24.59,86.84 24.39,87.04 23.89,87.04 23.69,86.84 23.69,86.29 23.61,86.21 23.28,86.21 23.2,86.29 23.2,86.84 23,87.04 22.5,87.04 22.3,86.84 22.3,86.29 22.22,86.21 21.89,86.21 21.81,86.29 21.81,86.84 21.61,87.04 21.11,87.04 20.9,86.84 20.9,86.29 20.82,86.21 20.5,86.21 20.42,86.29 20.42,86.84 20.21,87.04 19.72,87.04 19.51,86.84 19.51,86.29 19.43,86.21 7.61,86.21 7.24,85.84 7.24,73.55 7.11,73.43 6.84,73.43 6.76,73.51 v2(6.76,73.96)
FMC1_HB01_N: length 96.1
  TOP w0.124: U3.AD10 v2(72.9,72.93) ; J48.J25 v2(6.76,75.23)
  L10-SIG3 w0.081: v2(6.76,75.23) 7.21,75.23 7.29,75.15 7.29,72.25 7.53,72 8.53,72 8.74,72.21 8.74,74.33 8.93,74.51 9.71,74.51 9.82,74.4 9.82,70.98 10.1,70.7 16.01,70.7 17.32,69.39 18.3,69.39 20.41,67.28 22.28,67.28 22.36,67.19 22.36,66.24 22.57,66.04 23.07,66.04 23.27,66.24 23.27,67.19 23.35,67.28 23.67,67.28 23.76,67.19 23.76,66.24 23.96,66.04 24.46,66.04 24.66,66.24 24.66,67.19 24.74,67.28 25.07,67.28 25.15,67.19 25.15,66.24 25.35,66.04 25.85,66.04 26.05,66.24 26.05,67.19 26.13,67.28 26.46,67.28 26.54,67.19 26.54,66.24 26.74,66.04 27.24,66.04 27.44,66.24 27.44,66.89 27.53,66.97 27.85,66.97 27.93,66.89 27.93,66.24 28.14,66.04 30.85,66.04 32.47,67.66 49.57,67.66 51.86,65.37 72.26,65.37 72.5,65.62 72.5,72.85 72.58,72.93 v2(72.9,72.93)
FMC1_HB01_P: length 96.3
  TOP w0.124: J48.J24 v2(8.03,75.23) ; U3.AD9 v2(71.9,72.93)
  L10-SIG3 w0.081: v2(71.9,72.93) 72.21,72.93 72.3,72.85 72.3,68.66 72.16,68.53 72.16,68.3 72.3,68.16 72.3,67.69 72.14,67.53 72.14,67.33 72.3,67.17 72.3,66.68 72.14,66.52 72.14,66.32 72.3,66.16 72.3,65.7 72.17,65.58 71.7,65.58 71.55,65.73 71.35,65.73 71.2,65.58 70.69,65.58 70.56,65.71 70.28,65.71 70.15,65.58 69.65,65.58 69.55,65.68 69.24,65.68 69.14,65.58 51.94,65.58 49.66,67.86 32.39,67.86 30.76,66.24 28.22,66.24 28.14,66.33 28.14,66.98 27.94,67.18 27.44,67.18 27.24,66.98 27.24,66.33 27.15,66.24 26.83,66.24 26.75,66.33 26.75,67.28 26.55,67.48 26.05,67.48 25.84,67.28 25.84,66.33 25.76,66.24 25.44,66.24 25.36,66.33 25.36,67.28 25.15,67.48 24.66,67.48 24.45,67.28 24.45,66.33 24.37,66.24 24.05,66.24 23.96,66.33 23.96,67.28 23.76,67.48 23.26,67.48 23.06,67.28 23.06,66.33 22.98,66.24 22.65,66.24 22.57,66.33 22.57,67.28 22.37,67.48 20.5,67.48 18.38,69.6 17.41,69.6 16.09,70.91 10.19,70.91 10.03,71.07 10.03,74.48 9.79,74.72 8.84,74.72 8.53,74.42 8.53,72.3 8.44,72.21 7.62,72.21 7.5,72.33 7.5,73.13 7.59,73.23 7.59,73.45 7.5,73.55 7.5,73.78 7.59,73.88 7.59,74.1 7.5,74.2 7.5,74.43 7.59,74.53 7.59,74.75 7.5,74.85 7.5,75.15 7.58,75.23 v2(8.03,75.23)
FMC1_HB02_N: length 91.5
  TOP w0.099: J48.F23 v2(11.84,77.77)
  TOP w0.124: U3.AD5 v2(67.9,72.93)
  L10-SIG3 w0.081: v2(11.84,77.77) 11.39,77.77 11.31,77.69 11.31,77.39 11.43,77.26 12.14,77.26 12.25,77.36 12.47,77.36 12.57,77.26 12.79,77.26 12.9,77.36 13.12,77.36 13.22,77.26 13.44,77.26 13.55,77.36 13.77,77.36 13.87,77.26 14.48,77.26 14.73,77.52 15.26,77.52 15.52,77.26 15.81,77.26 16.07,77.52 16.6,77.52 16.85,77.26 17.21,77.26 17.46,77.52 17.99,77.52 18.24,77.26 18.64,77.26 18.78,77.13 18.89,77.13 19.46,77.7 19.75,77.7 20.1,77.35 20.1,77.06 19.53,76.49 19.53,76.38 19.88,76.03 19.99,76.03 21.14,77.17 21.42,77.17 21.78,76.82 21.78,76.53 20.63,75.39 20.63,75.27 20.86,75.04 20.98,75.04 22.19,76.25 22.47,76.25 22.83,75.9 22.83,75.61 21.69,74.48 21.69,74.37 21.92,74.14 22.04,74.14 23.17,75.27 23.46,75.27 23.81,74.92 23.81,74.63 22.87,73.69 22.87,73.52 23.44,72.94 24.74,72.94 24.96,72.72 25.35,72.72 25.57,72.94 26.13,72.94 26.35,72.72 26.74,72.72 26.96,72.94 27.52,72.94 27.74,72.72 28.13,72.72 28.35,72.94 28.91,72.94 29.14,72.72 29.52,72.72 29.75,72.94 30.31,72.94 30.53,72.72 30.91,72.72 31.14,72.94 31.7,72.94 31.92,72.72 32.31,72.72 32.53,72.94 33.09,72.94 33.31,72.72 33.7,72.72 33.92,72.94 34.48,72.94 34.7,72.72 35.09,72.72 35.31,72.94 40.8,72.94 41,72.74 41,72.01 41.09,71.93 41.41,71.93 41.49,72.01 41.49,72.74 41.7,72.94 42.19,72.94 42.4,72.74 42.4,72.01 42.48,71.93 42.8,71.93 42.88,72.01 42.88,72.74 43.09,72.94 43.59,72.94 43.79,72.74 43.79,72.01 43.87,71.93 44.2,71.93 44.28,72.01 44.28,72.74 44.48,72.94 44.98,72.94 45.18,72.74 45.18,72.01 45.26,71.93 45.59,71.93 45.67,72.01 45.67,72.74 45.87,72.94 46.37,72.94 46.57,72.74 46.57,72.01 46.65,71.93 46.98,71.93 47.06,72.01 47.06,72.74 47.26,72.94 47.76,72.94 47.96,72.74 47.96,72.01 48.05,71.93 48.37,71.93 48.45,72.01 48.45,72.74 48.66,72.94 49.32,72.94 52.69,69.57 64.13,69.57 64.28,69.72 64.54,69.72 64.69,69.57 65.13,69.57 65.27,69.72 65.56,69.72 65.71,69.57 66.12,69.57 66.26,69.72 66.5,69.72 66.65,69.57 67.14,69.57 67.26,69.69 67.56,69.69 67.69,69.57 68.16,69.57 68.29,69.7 68.29,70.18 68.15,70.32 68.15,70.56 68.29,70.7 68.29,71.22 68.17,71.34 68.17,71.57 68.29,71.69 68.29,72.85 68.21,72.93 v2(67.9,72.93)
FMC1_HB02_P: length 91.2
  TOP w0.099: J48.F22 v2(10.57,77.77)
  TOP w0.124: U3.AD6 v2(68.9,72.93)
  L10-SIG3 w0.081: v2(10.57,77.77) 11.02,77.77 11.1,77.69 11.1,77.3 11.35,77.05 14.57,77.05 14.82,77.31 15.18,77.31 15.43,77.05 15.9,77.05 16.15,77.31 16.51,77.31 16.76,77.05 17.29,77.05 17.55,77.31 17.9,77.31 18.16,77.05 18.56,77.05 18.69,76.92 18.98,76.92 19.55,77.5 19.66,77.5 19.9,77.27 19.9,77.15 19.32,76.58 19.32,76.29 19.79,75.82 20.08,75.82 21.22,76.97 21.34,76.97 21.57,76.74 21.57,76.62 20.42,75.48 20.42,75.19 20.78,74.84 21.06,74.84 22.27,76.04 22.39,76.04 22.62,75.81 22.62,75.7 21.49,74.57 21.49,74.28 21.84,73.93 22.12,73.93 23.26,75.06 23.37,75.06 23.6,74.83 23.6,74.71 22.66,73.78 22.66,73.43 23.36,72.74 24.65,72.74 24.87,72.51 25.43,72.51 25.66,72.74 26.04,72.74 26.27,72.51 26.83,72.51 27.05,72.74 27.44,72.74 27.66,72.51 28.22,72.51 28.44,72.74 28.83,72.74 29.05,72.51 29.61,72.51 29.83,72.74 30.22,72.74 30.44,72.51 31,72.51 31.22,72.74 31.61,72.74 31.83,72.51 32.39,72.51 32.62,72.74 33,72.74 33.23,72.51 33.79,72.51 34.01,72.74 34.39,72.74 34.62,72.51 35.18,72.51 35.4,72.74 40.72,72.74 40.8,72.66 40.8,71.92 41,71.72 41.5,71.72 41.7,71.92 41.7,72.66 41.78,72.74 42.11,72.74 42.19,72.66 42.19,71.92 42.39,71.72 42.89,71.72 43.09,71.92 43.09,72.66 43.17,72.74 43.5,72.74 43.58,72.66 43.58,71.92 43.78,71.72 44.28,71.72 44.48,71.92 44.48,72.66 44.57,72.74 44.89,72.74 44.97,72.66 44.97,71.92 45.18,71.72 45.67,71.72 45.88,71.92 45.88,72.66 45.96,72.74 46.28,72.74 46.36,72.66 46.36,71.92 46.57,71.72 47.07,71.72 47.27,71.92 47.27,72.66 47.35,72.74 47.68,72.74 47.76,72.66 47.76,71.92 47.96,71.72 48.46,71.72 48.66,71.92 48.66,72.66 48.74,72.74 49.23,72.74 52.6,69.36 68.25,69.36 68.5,69.62 68.5,72.85 68.58,72.93 v2(68.9,72.93)
FMC1_HB03_N: length 90.6
  TOP w0.099: J48.E22 v2(11.84,79.04)
  TOP w0.152: U3.AC5 v2(67.9,73.93)
  L10-SIG3 w0.081: v2(11.84,79.04) 12.29,79.04 12.37,78.96 12.37,78.57 12.62,78.32 14.54,78.32 14.82,78.6 15.15,78.6 15.42,78.32 16.03,78.32 16.23,78.53 16.23,78.83 16.31,78.91 16.64,78.91 16.72,78.83 16.72,78.53 16.92,78.32 18.78,78.32 18.99,78.53 18.99,78.8 19.07,78.88 19.39,78.88 19.48,78.8 19.48,78.53 19.68,78.32 20.18,78.32 20.38,78.53 20.38,78.8 20.46,78.88 20.79,78.88 20.87,78.8 20.87,78.53 21.07,78.32 21.5,78.32 21.75,78.08 21.75,77.79 22.16,77.38 22.44,77.38 22.73,77.1 22.73,76.81 23.14,76.4 23.43,76.4 23.72,76.11 23.72,75.82 24.13,75.41 24.41,75.41 24.86,74.97 24.86,74.86 24.16,74.16 24.16,73.88 24.52,73.52 24.8,73.52 25.5,74.22 25.61,74.22 26.2,73.63 27.28,73.63 27.48,73.83 27.48,74.43 27.56,74.51 27.89,74.51 27.97,74.43 27.97,73.7 28.17,73.5 28.67,73.5 28.87,73.7 28.87,74.43 28.95,74.51 29.28,74.51 29.36,74.43 29.36,73.7 29.56,73.5 30.06,73.5 30.27,73.7 30.27,74.43 30.35,74.51 30.67,74.51 30.75,74.43 30.75,73.7 30.96,73.5 31.45,73.5 31.66,73.7 31.66,74.43 31.74,74.51 32.06,74.51 32.14,74.43 32.14,73.7 32.35,73.5 32.85,73.5 33.05,73.7 33.05,74.43 33.13,74.51 33.46,74.51 33.54,74.43 33.54,73.73 33.74,73.52 34.24,73.52 34.44,73.73 34.44,74.43 34.52,74.51 34.85,74.51 34.93,74.43 34.93,73.83 35.13,73.63 35.63,73.63 35.83,73.83 35.83,74.43 35.91,74.51 36.24,74.51 36.32,74.43 36.32,73.83 36.52,73.63 37.02,73.63 37.22,73.83 37.22,74.43 37.31,74.51 37.63,74.51 37.71,74.43 37.71,73.83 37.92,73.63 38.41,73.63 38.62,73.83 38.62,74.43 38.7,74.51 39.02,74.51 39.1,74.43 39.1,73.83 39.31,73.63 39.81,73.63 40.01,73.83 40.01,74.43 40.09,74.51 40.42,74.51 40.5,74.43 40.5,73.83 40.7,73.63 41.2,73.63 41.4,73.83 41.4,74.43 41.48,74.51 41.81,74.51 41.89,74.43 41.89,73.83 42.09,73.63 42.59,73.63 42.79,73.83 42.79,74.43 42.87,74.51 43.2,74.51 43.28,74.43 43.28,73.83 43.48,73.63 43.98,73.63 44.18,73.83 44.18,74.43 44.27,74.51 44.59,74.51 44.67,74.43 44.67,73.83 44.88,73.63 45.62,73.63 45.88,73.88 46.23,73.88 46.49,73.63 47.01,73.63 47.27,73.88 47.62,73.88 47.88,73.63 49.48,73.63 52.79,70.32 67.14,70.32 67.5,70.68 67.5,73.85 67.58,73.93 v2(67.9,73.93)
FMC1_HB03_P: length 90.3
  TOP w0.099: J48.E21 v2(13.11,79.04)
  TOP w0.152: U3.AC4 v2(66.9,73.93)
  L10-SIG3 w0.081: v2(66.9,73.93) 67.21,73.93 67.3,73.85 67.3,72.68 67.16,72.54 67.16,72.31 67.3,72.17 67.3,71.76 67.13,71.6 67.13,71.41 67.3,71.24 67.3,70.77 67.06,70.53 66.67,70.53 66.52,70.68 66.32,70.68 66.17,70.53 52.87,70.53 49.57,73.83 47.96,73.83 47.71,74.09 47.18,74.09 46.93,73.83 46.57,73.83 46.32,74.09 45.79,74.09 45.54,73.83 44.96,73.83 44.88,73.92 44.88,74.52 44.68,74.72 44.18,74.72 43.98,74.52 43.98,73.92 43.9,73.83 43.57,73.83 43.49,73.92 43.49,74.52 43.29,74.72 42.79,74.72 42.58,74.52 42.58,73.92 42.5,73.83 42.18,73.83 42.1,73.92 42.1,74.52 41.89,74.72 41.4,74.72 41.19,74.52 41.19,73.92 41.11,73.83 40.79,73.83 40.7,73.92 40.7,74.52 40.5,74.72 40,74.72 39.8,74.52 39.8,73.92 39.72,73.83 39.39,73.83 39.31,73.92 39.31,74.52 39.11,74.72 38.61,74.72 38.41,74.52 38.41,73.92 38.33,73.83 38,73.83 37.92,73.92 37.92,74.52 37.72,74.72 37.22,74.72 37.02,74.52 37.02,73.92 36.94,73.83 36.61,73.83 36.53,73.92 36.53,74.52 36.33,74.72 35.83,74.72 35.62,74.52 35.62,73.92 35.54,73.83 35.22,73.83 35.14,73.92 35.14,74.52 34.93,74.72 34.44,74.72 34.23,74.52 34.23,73.81 34.15,73.73 33.83,73.73 33.75,73.81 33.75,74.52 33.54,74.72 33.04,74.72 32.84,74.52 32.84,73.79 32.76,73.71 32.43,73.71 32.35,73.79 32.35,74.52 32.15,74.72 31.65,74.72 31.45,74.52 31.45,73.79 31.37,73.71 31.04,73.71 30.96,73.79 30.96,74.52 30.76,74.72 30.26,74.72 30.06,74.52 30.06,73.79 29.98,73.71 29.65,73.71 29.57,73.79 29.57,74.52 29.37,74.72 28.87,74.72 28.67,74.52 28.67,73.79 28.58,73.71 28.26,73.71 28.18,73.79 28.18,74.52 27.97,74.72 27.48,74.72 27.27,74.52 27.27,73.92 27.19,73.83 26.29,73.83 25.7,74.42 25.41,74.42 24.72,73.73 24.6,73.73 24.37,73.96 24.37,74.08 25.07,74.77 25.07,75.06 24.5,75.62 24.21,75.62 23.93,75.91 23.93,76.2 23.52,76.61 23.23,76.61 22.94,76.89 22.94,77.18 22.53,77.59 22.24,77.59 21.96,77.88 21.96,78.17 21.59,78.53 21.16,78.53 21.08,78.61 21.08,78.89 20.87,79.09 20.37,79.09 20.17,78.89 20.17,78.61 20.09,78.53 19.77,78.53 19.68,78.61 19.68,78.89 19.48,79.09 18.98,79.09 18.78,78.89 18.78,78.61 18.7,78.53 17.01,78.53 16.93,78.61 16.93,78.91 16.72,79.12 16.23,79.12 16.02,78.91 16.02,78.61 15.94,78.53 15.51,78.53 15.23,78.81 14.73,78.81 14.45,78.53 12.7,78.53 12.58,78.66 12.58,78.96 12.66,79.04 v2(13.11,79.04)
FMC1_HB04_N: length 99.1
  TOP w0.124: J48.F26 v2(11.84,72.69) ; U3.AC10 v2(72.9,73.93)
  L10-SIG3 w0.081: v2(11.84,72.69) 11.84,73.14 11.92,73.22 12.36,73.22 12.44,73.14 12.44,72.08 12.64,71.88 13.61,71.88 13.82,72.08 13.82,73.14 13.9,73.22 14.8,73.22 14.88,73.14 14.88,72.11 15.09,71.9 16.18,71.9 16.38,72.11 16.38,73.14 16.46,73.22 17.11,73.22 17.34,72.99 17.34,71.69 20.91,68.12 23.37,68.12 23.57,68.32 23.57,68.93 23.65,69.01 23.97,69.01 24.06,68.93 24.06,68.32 24.26,68.12 24.76,68.12 24.96,68.32 24.96,68.93 25.04,69.01 25.37,69.01 25.45,68.93 25.45,68.32 25.65,68.12 26.15,68.12 26.35,68.32 26.35,68.93 26.43,69.01 26.76,69.01 26.84,68.93 26.84,68.19 27.04,67.99 27.54,67.99 27.74,68.19 27.74,68.93 27.83,69.01 28.15,69.01 28.23,68.93 28.23,67.83 28.44,67.63 28.93,67.63 29.14,67.83 29.14,68.93 29.22,69.01 29.54,69.01 29.62,68.93 29.62,67.07 29.83,66.87 30.32,66.87 30.53,67.07 30.53,68.93 30.61,69.01 31.21,69.01 31.29,68.93 31.29,68.65 31.49,68.45 31.99,68.45 32.19,68.65 32.19,68.93 32.27,69.01 32.6,69.01 32.68,68.93 32.68,68.65 32.88,68.45 33.38,68.45 33.58,68.65 33.58,68.93 33.66,69.01 33.99,69.01 34.07,68.93 34.07,68.65 34.27,68.45 34.77,68.45 34.97,68.65 34.97,68.93 35.06,69.01 35.38,69.01 35.46,68.93 35.46,68.65 35.67,68.45 36.16,68.45 36.37,68.65 36.37,68.93 36.45,69.01 36.77,69.01 36.85,68.93 36.85,68.65 37.06,68.45 37.56,68.45 37.76,68.65 37.76,68.93 37.84,69.01 38.17,69.01 38.25,68.93 38.25,68.65 38.45,68.45 38.95,68.45 39.15,68.65 39.15,68.93 39.23,69.01 39.56,69.01 39.64,68.93 39.64,68.65 39.84,68.45 40.34,68.45 40.54,68.65 40.54,68.93 40.62,69.01 40.95,69.01 41.03,68.93 41.03,68.65 41.23,68.45 41.73,68.45 41.93,68.65 41.93,68.93 42.02,69.01 42.34,69.01 42.42,68.93 42.42,68.65 42.63,68.45 43.12,68.45 43.33,68.65 43.33,68.87 43.41,68.95 43.73,68.95 43.81,68.87 43.81,68.65 44.02,68.45 44.52,68.45 44.72,68.65 44.72,68.87 44.8,68.95 45.12,68.95 45.21,68.87 45.21,68.65 45.41,68.45 50.09,68.45 52.2,66.34 71.12,66.34 71.5,66.72 71.5,74.24 71.58,74.33 72.5,74.33 v2(72.9,73.93)
FMC1_HB04_P: length 99.3
  TOP w0.124: U3.AB10 v2(72.9,74.93) ; J48.F25 v2(11.84,73.96)
  L10-SIG3 w0.081: v2(72.9,74.93) 72.9,74.62 72.82,74.53 71.5,74.53 71.29,74.33 71.29,66.81 71.03,66.55 52.28,66.55 50.18,68.66 45.5,68.66 45.41,68.74 45.41,68.96 45.21,69.16 44.71,69.16 44.51,68.96 44.51,68.74 44.43,68.66 44.1,68.66 44.02,68.74 44.02,68.96 43.82,69.16 43.32,69.16 43.12,68.96 43.12,68.74 43.04,68.66 42.71,68.66 42.63,68.74 42.63,69.01 42.43,69.22 41.93,69.22 41.73,69.01 41.73,68.74 41.64,68.66 41.32,68.66 41.24,68.74 41.24,69.01 41.04,69.22 40.54,69.22 40.33,69.01 40.33,68.74 40.25,68.66 39.93,68.66 39.85,68.74 39.85,69.01 39.64,69.22 39.15,69.22 38.94,69.01 38.94,68.74 38.86,68.66 38.54,68.66 38.45,68.74 38.45,69.01 38.25,69.22 37.75,69.22 37.55,69.01 37.55,68.74 37.47,68.66 37.14,68.66 37.06,68.74 37.06,69.01 36.86,69.22 36.36,69.22 36.16,69.01 36.16,68.74 36.08,68.66 35.75,68.66 35.67,68.74 35.67,69.01 35.47,69.22 34.97,69.22 34.77,69.01 34.77,68.74 34.69,68.66 34.36,68.66 34.28,68.74 34.28,69.01 34.08,69.22 33.58,69.22 33.37,69.01 33.37,68.74 33.29,68.66 32.97,68.66 32.89,68.74 32.89,69.01 32.68,69.22 32.19,69.22 31.98,69.01 31.98,68.74 31.9,68.66 31.58,68.66 31.49,68.74 31.49,69.01 31.29,69.22 30.52,69.22 30.32,69.01 30.32,67.16 30.24,67.08 29.91,67.08 29.83,67.16 29.83,69.01 29.63,69.22 29.13,69.22 28.93,69.01 28.93,67.92 28.85,67.84 28.52,67.84 28.44,67.92 28.44,69.01 28.24,69.22 27.74,69.22 27.54,69.01 27.54,68.28 27.45,68.2 27.13,68.2 27.05,68.28 27.05,69.01 26.85,69.22 26.35,69.22 26.14,69.01 26.14,68.41 26.06,68.33 25.74,68.33 25.66,68.41 25.66,69.01 25.45,69.22 24.96,69.22 24.75,69.01 24.75,68.41 24.67,68.33 24.35,68.33 24.26,68.41 24.26,69.01 24.06,69.22 23.56,69.22 23.36,69.01 23.36,68.41 23.28,68.33 21,68.33 17.55,71.78 17.55,73.07 17.19,73.43 16.38,73.43 16.17,73.23 16.17,72.19 16.09,72.11 15.17,72.11 15.09,72.19 15.09,73.23 14.89,73.43 13.81,73.43 13.61,73.23 13.61,72.17 13.53,72.09 12.73,72.09 12.65,72.17 12.65,73.23 12.45,73.43 11.92,73.43 11.84,73.51 v2(11.84,73.96)
FMC1_HB05_N: length 94
  TOP w0.099: J48.E25 v2(11.84,75.23)
  TOP w0.124: U3.AD8 v2(70.9,72.93)
  L10-SIG3 w0.081: v2(70.9,72.93) 70.58,72.93 70.5,72.85 70.5,67.61 70.22,67.33 52.38,67.33 49.81,69.9 34.97,69.9 34.76,70.1 34.76,70.5 34.68,70.58 34.36,70.58 34.28,70.5 34.28,70.1 34.07,69.9 33.58,69.9 33.37,70.1 33.37,70.5 33.29,70.58 32.97,70.58 32.89,70.5 32.89,70.1 32.68,69.9 32.18,69.9 31.98,70.1 31.98,70.75 31.9,70.83 31.57,70.83 31.49,70.75 31.49,70.1 31.29,69.9 30.79,69.9 30.59,70.1 30.59,70.75 30.51,70.83 30.18,70.83 30.1,70.75 30.1,70.1 29.9,69.9 29.4,69.9 29.2,70.1 29.2,70.75 29.12,70.83 28.79,70.83 28.71,70.75 28.71,70.1 28.51,69.9 28.01,69.9 27.81,70.1 27.81,70.75 27.72,70.83 27.4,70.83 27.32,70.75 27.32,70.1 27.11,69.9 26.62,69.9 26.41,70.1 26.41,70.75 26.33,70.83 26.01,70.83 25.93,70.75 25.93,70.1 25.72,69.9 25.22,69.9 25.02,70.1 25.02,70.67 24.94,70.76 24.62,70.76 24.53,70.67 24.53,70.1 24.33,69.9 23.07,69.9 22.17,69 21.8,69 21.35,69.45 21.35,69.74 22.43,70.81 22.43,70.93 22.2,71.16 22.08,71.16 21.01,70.08 20.72,70.08 20.37,70.43 20.37,70.72 21.44,71.8 21.44,71.91 20.96,72.39 20.85,72.39 19.64,71.18 19.35,71.18 19,71.53 19,71.82 20.21,73.03 20.21,73.14 19.98,73.37 19.86,73.37 18.81,72.32 18.52,72.32 18.17,72.67 18.17,72.96 19.22,74.01 19.22,74.13 18.84,74.51 12.62,74.51 12.37,74.76 12.37,75.15 12.29,75.23 v2(11.84,75.23)
FMC1_HB05_P: length 94
  TOP w0.099: J48.E24 v2(13.11,75.23)
  TOP w0.124: U3.AD7 v2(69.9,72.93)
  L10-SIG3 w0.081: v2(69.9,72.93) 70.21,72.93 70.3,72.85 70.3,71.69 70.18,71.57 70.18,71.4 70.3,71.28 70.3,70.7 70.15,70.56 70.15,70.35 70.3,70.21 70.3,69.71 70.15,69.57 70.15,69.33 70.3,69.19 70.3,68.72 70.15,68.58 70.15,68.36 70.3,68.22 70.3,67.69 70.14,67.53 69.7,67.53 69.57,67.66 69.27,67.66 69.14,67.53 68.68,67.53 68.53,67.69 68.28,67.69 68.12,67.53 67.67,67.53 67.54,67.66 67.21,67.66 67.08,67.53 52.47,67.53 49.9,70.11 35.05,70.11 34.97,70.19 34.97,70.58 34.77,70.79 34.27,70.79 34.07,70.58 34.07,70.19 33.99,70.11 33.66,70.11 33.58,70.19 33.58,70.58 33.38,70.79 32.88,70.79 32.68,70.58 32.68,70.19 32.6,70.11 32.27,70.11 32.19,70.19 32.19,70.84 31.99,71.04 31.49,71.04 31.29,70.84 31.29,70.19 31.2,70.11 30.88,70.11 30.8,70.19 30.8,70.84 30.59,71.04 30.1,71.04 29.89,70.84 29.89,70.19 29.81,70.11 29.49,70.11 29.41,70.19 29.41,70.84 29.2,71.04 28.7,71.04 28.5,70.84 28.5,70.19 28.42,70.11 28.09,70.11 28.01,70.19 28.01,70.84 27.81,71.04 27.31,71.04 27.11,70.84 27.11,70.19 27.03,70.11 26.7,70.11 26.62,70.19 26.62,70.84 26.42,71.04 25.92,71.04 25.72,70.84 25.72,70.19 25.64,70.11 25.31,70.11 25.23,70.19 25.23,70.76 25.03,70.96 24.53,70.96 24.33,70.76 24.33,70.19 24.24,70.11 22.98,70.11 22.09,69.21 21.89,69.21 21.56,69.54 21.56,69.65 22.63,70.72 22.63,71.01 22.28,71.36 21.99,71.36 20.92,70.29 20.81,70.29 20.58,70.52 20.58,70.64 21.65,71.71 21.65,72 21.05,72.6 20.76,72.6 19.55,71.39 19.44,71.39 19.21,71.62 19.21,71.73 20.42,72.94 20.42,73.23 20.06,73.58 19.78,73.58 18.72,72.53 18.6,72.53 18.37,72.76 18.37,72.87 19.43,73.93 19.43,74.22 18.92,74.72 12.7,74.72 12.58,74.85 12.58,75.15 12.66,75.23 v2(13.11,75.23)
FMC1_HB06_N_CC: length 85.1
  TOP w0.124: J48.K29 v2(5.49,68.88)
  TOP w0.152: U3.AM2 v2(64.9,64.93)
  L05-SIG2 w0.081: v2(5.49,68.88) 5.49,69.33 5.57,69.41 7,69.41 7.28,69.12 7.28,63.5 7.7,63.08 21.64,63.08 23.96,65.41 23.96,66.85 24.04,66.93 25.04,66.93 25.25,67.13 25.25,67.63 25.04,67.83 24.29,67.83 24.21,67.91 24.21,68.42 24.29,68.5 25.77,68.5 25.85,68.42 25.85,66.19 26.06,65.99 26.56,65.99 26.76,66.19 26.76,68.42 26.84,68.5 27.17,68.5 27.25,68.42 27.25,66.19 27.45,65.99 27.95,65.99 28.15,66.19 28.15,68.42 28.23,68.5 49.74,68.5 51.49,66.76 51.49,66.64 51.26,66.42 51.26,66.13 51.62,65.78 51.9,65.78 52.13,66 52.24,66 52.92,65.33 64.82,65.33 64.9,65.24 v2(64.9,64.93)
FMC1_HB06_P_CC: length 85.1
  TOP w0.124: J48.K28 v2(5.49,70.15)
  TOP w0.152: U3.AL2 v2(64.9,65.93)
  L05-SIG2 w0.081: v2(64.9,65.93) 64.9,65.62 64.82,65.53 53,65.53 52.33,66.21 52.04,66.21 51.82,65.99 51.7,65.99 51.47,66.22 51.47,66.33 51.7,66.56 51.7,66.84 49.83,68.71 28.15,68.71 27.94,68.51 27.94,66.27 27.86,66.19 27.54,66.19 27.45,66.27 27.45,68.51 27.25,68.71 26.75,68.71 26.55,68.51 26.55,66.27 26.47,66.19 26.14,66.19 26.06,66.27 26.06,68.51 25.86,68.71 24.2,68.71 24,68.51 24,67.83 24.2,67.62 24.96,67.62 25.04,67.54 25.04,67.22 24.96,67.14 23.95,67.14 23.75,66.93 23.75,65.49 21.55,63.29 7.79,63.29 7.49,63.59 7.49,69.21 7.08,69.62 5.57,69.62 5.49,69.7 v2(5.49,70.15)
FMC1_HB07_N: length 96.8
  TOP w0.099: J48.J28 v2(8.03,71.42)
  TOP w0.124: U3.AD11 v2(73.9,72.93)
  L10-SIG3 w0.081: v2(73.9,72.93) 74.31,72.93 74.4,72.84 74.4,72.72 74.24,72.56 73.57,72.56 73.3,72.29 73.3,71.57 73.5,71.37 78.22,71.37 78.3,71.29 78.3,70.61 78.22,70.53 73.5,70.53 73.3,70.33 73.3,69.56 73.5,69.36 75.2,69.36 75.28,69.28 75.28,68.63 75.2,68.55 73.5,68.55 73.3,68.35 73.3,66.67 73.15,66.52 73.15,66.32 73.3,66.17 73.3,65.73 73.15,65.58 73.15,65.35 73.3,65.2 73.3,64.75 73.07,64.52 72.66,64.52 72.52,64.66 72.28,64.66 72.14,64.52 51.73,64.52 49.19,67.06 32.8,67.06 31.09,65.35 20.49,65.35 16.2,69.64 13.51,69.64 13.36,69.5 13.12,69.5 12.97,69.64 12.44,69.64 12.3,69.5 12.05,69.5 11.91,69.64 11.38,69.64 11.23,69.5 10.99,69.5 10.84,69.64 9.4,69.64 9.3,69.74 9.08,69.74 8.97,69.64 8.75,69.64 8.65,69.74 8.42,69.74 8.32,69.64 8,69.64 7.5,70.15 7.5,70.44 7.59,70.53 7.59,70.76 7.5,70.86 7.5,71.34 7.58,71.42 v2(8.03,71.42)
FMC1_HB07_P: length 96.5
  TOP w0.099: J48.J27 v2(6.76,71.42)
  TOP w0.124: U3.AD12 v2(74.9,72.93)
  L10-SIG3 w0.081: v2(74.9,72.93) 74.32,72.36 73.66,72.36 73.51,72.2 73.51,71.66 73.59,71.58 78.31,71.58 78.51,71.38 78.51,70.53 78.31,70.32 73.59,70.32 73.51,70.24 73.51,69.65 73.59,69.57 75.29,69.57 75.49,69.36 75.49,68.55 75.29,68.34 73.59,68.34 73.51,68.26 73.51,64.66 73.15,64.31 51.65,64.31 49.11,66.85 32.88,66.85 31.18,65.14 20.41,65.14 16.11,69.43 13.6,69.43 13.45,69.29 13.03,69.29 12.89,69.43 12.53,69.43 12.38,69.29 11.97,69.29 11.82,69.43 11.46,69.43 11.32,69.29 10.9,69.29 10.75,69.43 7.91,69.43 7.29,70.06 7.29,71.34 7.21,71.42 v2(6.76,71.42)
FMC1_HB08_N: length 92.4
  TOP w0.099: J48.F29 v2(10.57,70.15)
  TOP w0.152: U3.AF7 v2(69.9,70.93)
  L05-SIG2 w0.081: v2(10.57,70.15) 11.02,70.15 11.1,70.07 11.1,69.68 11.37,69.41 18.35,69.41 18.88,69.94 18.88,76.73 19.13,76.98 19.95,76.98 20.15,77.19 20.15,77.76 20.23,77.84 20.56,77.84 20.64,77.76 20.64,77.19 20.84,76.98 21.34,76.98 21.54,77.19 21.54,77.76 21.62,77.84 21.95,77.84 22.03,77.76 22.03,77.19 22.23,76.98 22.73,76.98 22.93,77.19 22.93,77.76 23.01,77.84 23.34,77.84 23.42,77.76 23.42,77.19 23.62,76.98 24.12,76.98 24.32,77.19 24.32,77.76 24.41,77.84 24.73,77.84 24.81,77.76 24.81,77.19 25.02,76.98 25.51,76.98 25.72,77.19 25.72,77.76 25.8,77.84 26.12,77.84 26.2,77.76 26.2,77.19 26.41,76.98 26.91,76.98 27.11,77.19 27.11,77.76 27.19,77.84 27.52,77.84 27.6,77.76 27.6,77.19 27.8,76.98 28.3,76.98 28.5,77.19 28.5,77.76 28.58,77.84 28.91,77.84 28.99,77.76 28.99,77.19 29.19,76.98 29.69,76.98 29.89,77.19 29.89,77.76 29.97,77.84 30.3,77.84 30.38,77.76 30.38,77.19 30.58,76.98 31.08,76.98 31.28,77.19 31.28,77.76 31.37,77.84 31.69,77.84 31.77,77.76 31.77,77.19 31.98,76.98 32.47,76.98 32.68,77.19 32.68,77.76 32.76,77.84 33.08,77.84 33.16,77.76 33.16,77.19 33.37,76.98 33.87,76.98 34.07,77.19 34.07,77.76 34.15,77.84 34.47,77.84 34.56,77.76 34.56,77.19 34.76,76.98 35.26,76.98 35.46,77.19 35.46,77.76 35.54,77.84 35.87,77.84 35.95,77.76 35.95,77.19 36.15,76.98 36.65,76.98 36.85,77.19 36.85,77.76 36.93,77.84 37.26,77.84 37.34,77.76 37.34,77.19 37.54,76.98 38.04,76.98 38.24,77.19 38.24,77.76 38.33,77.84 38.65,77.84 38.73,77.76 38.73,77.19 38.93,76.98 39.43,76.98 39.64,77.19 39.64,77.76 39.72,77.84 40.04,77.84 40.12,77.76 40.12,77.19 40.33,76.98 43.61,76.98 47.6,72.99 52.95,72.99 55.61,70.33 69.26,70.33 69.87,70.93 v2(69.9,70.93)
FMC1_HB08_P: length 92.7
  TOP w0.099: J48.F28 v2(11.84,70.15)
  TOP w0.152: U3.AE7 v2(69.9,71.93)
  L05-SIG2 w0.081: v2(11.84,70.15) 11.39,70.15 11.31,70.07 11.31,69.77 11.45,69.62 18.27,69.62 18.67,70.02 18.67,76.82 19.04,77.19 19.86,77.19 19.94,77.27 19.94,77.85 20.14,78.05 20.64,78.05 20.85,77.85 20.85,77.27 20.93,77.19 21.25,77.19 21.33,77.27 21.33,77.85 21.54,78.05 22.03,78.05 22.24,77.85 22.24,77.27 22.32,77.19 22.64,77.19 22.72,77.27 22.72,77.85 22.93,78.05 23.43,78.05 23.63,77.85 23.63,77.27 23.71,77.19 24.04,77.19 24.12,77.27 24.12,77.85 24.32,78.05 24.82,78.05 25.02,77.85 25.02,77.27 25.1,77.19 25.43,77.19 25.51,77.27 25.51,77.85 25.71,78.05 26.21,78.05 26.41,77.85 26.41,77.27 26.49,77.19 26.82,77.19 26.9,77.27 26.9,77.85 27.1,78.05 27.6,78.05 27.8,77.85 27.8,77.27 27.89,77.19 28.21,77.19 28.29,77.27 28.29,77.85 28.5,78.05 28.99,78.05 29.2,77.85 29.2,77.27 29.28,77.19 29.6,77.19 29.68,77.27 29.68,77.85 29.89,78.05 30.39,78.05 30.59,77.85 30.59,77.27 30.67,77.19 30.99,77.19 31.08,77.27 31.08,77.85 31.28,78.05 31.78,78.05 31.98,77.85 31.98,77.27 32.06,77.19 32.39,77.19 32.47,77.27 32.47,77.85 32.67,78.05 33.17,78.05 33.37,77.85 33.37,77.27 33.45,77.19 33.78,77.19 33.86,77.27 33.86,77.85 34.06,78.05 34.56,78.05 34.76,77.85 34.76,77.27 34.85,77.19 35.17,77.19 35.25,77.27 35.25,77.85 35.46,78.05 35.95,78.05 36.16,77.85 36.16,77.27 36.24,77.19 36.56,77.19 36.64,77.27 36.64,77.85 36.85,78.05 37.34,78.05 37.55,77.85 37.55,77.27 37.63,77.19 37.95,77.19 38.04,77.27 38.04,77.85 38.24,78.05 38.74,78.05 38.94,77.85 38.94,77.27 39.02,77.19 39.35,77.19 39.43,77.27 39.43,77.85 39.63,78.05 40.13,78.05 40.33,77.85 40.33,77.27 40.41,77.19 43.7,77.19 47.69,73.2 53.04,73.2 55.7,70.53 69.18,70.53 69.55,70.9 69.55,71.58 v2(69.9,71.93)
FMC1_HB09_N: length 90.8
  TOP w0.124: J48.E28 v2(13.11,70.15)
  TOP w0.152: U3.AF5 v2(67.9,70.93)
  L05-SIG2 w0.081: v2(67.9,70.93) 67.5,71.33 56.23,71.33 53.72,73.83 48.16,73.83 42.34,79.65 41.41,79.65 41.33,79.57 41.33,79.24 41.12,79.04 40.62,79.04 40.42,79.24 40.42,79.57 40.34,79.65 40.02,79.65 39.93,79.57 39.93,79.21 39.73,79.01 39.23,79.01 39.03,79.21 39.03,79.57 38.95,79.65 38.62,79.65 38.54,79.57 38.54,79.12 38.34,78.91 37.84,78.91 37.64,79.12 37.64,79.57 37.56,79.65 37.23,79.65 37.15,79.57 37.15,79.12 36.95,78.91 36.45,78.91 36.25,79.12 36.25,79.57 36.16,79.65 35.84,79.65 35.76,79.57 35.76,79.12 35.55,78.91 35.06,78.91 34.85,79.12 34.85,79.57 34.77,79.65 34.45,79.65 34.37,79.57 34.37,79.12 34.16,78.91 33.67,78.91 33.46,79.12 33.46,79.57 33.38,79.65 33.06,79.65 32.97,79.57 32.97,79.12 32.77,78.91 32.27,78.91 32.07,79.12 32.07,79.57 31.99,79.65 31.66,79.65 31.58,79.57 31.58,79.12 31.38,78.91 30.88,78.91 30.68,79.12 30.68,79.57 30.6,79.65 30.27,79.65 30.19,79.57 30.19,79.12 29.99,78.91 29.49,78.91 29.29,79.12 29.29,79.57 29.2,79.65 28.88,79.65 28.8,79.57 28.8,79.12 28.6,78.91 28.1,78.91 27.89,79.12 27.89,79.57 27.81,79.65 27.49,79.65 27.41,79.57 27.41,79.12 27.2,78.91 26.71,78.91 26.5,79.12 26.5,79.57 26.42,79.65 26.1,79.65 26.01,79.57 26.01,79.12 25.81,78.91 25.31,78.91 25.11,79.12 25.11,79.57 25.03,79.65 24.7,79.65 24.62,79.57 24.62,79.12 24.42,78.91 23.92,78.91 23.72,79.12 23.72,79.57 23.64,79.65 23.31,79.65 23.23,79.57 23.23,79.12 23.03,78.91 22.53,78.91 22.33,79.12 22.33,79.57 22.25,79.65 21.92,79.65 21.84,79.57 21.84,79.12 21.64,78.91 21.14,78.91 20.93,79.12 20.93,79.57 20.85,79.65 20.53,79.65 20.45,79.57 20.45,79.12 20.24,78.91 19.75,78.91 19.54,79.12 19.54,79.57 19.46,79.65 16.66,79.65 16.46,79.45 16.46,77.22 16.55,77.14 17.58,77.14 17.78,76.93 17.78,75.74 17.58,75.54 16.97,75.54 16.89,75.46 16.89,75.14 16.97,75.05 17.58,75.05 17.78,74.85 17.78,71.04 17.42,70.68 13.19,70.68 13.11,70.6 v2(13.11,70.15)
FMC1_HB09_P: length 91
  TOP w0.124: J48.E27 v2(13.11,71.42)
  TOP w0.152: U3.AE5 v2(67.9,71.93)
  L05-SIG2 w0.081: v2(13.11,71.42) 13.11,70.97 13.19,70.89 17.34,70.89 17.57,71.13 17.57,74.76 17.49,74.85 16.89,74.85 16.68,75.05 16.68,75.55 16.89,75.75 17.49,75.75 17.57,75.83 17.57,76.85 17.49,76.93 16.46,76.93 16.26,77.13 16.26,79.54 16.58,79.86 19.55,79.86 19.75,79.66 19.75,79.2 19.83,79.12 20.16,79.12 20.24,79.2 20.24,79.66 20.44,79.86 20.94,79.86 21.14,79.66 21.14,79.2 21.22,79.12 21.55,79.12 21.63,79.2 21.63,79.66 21.83,79.86 22.33,79.86 22.53,79.66 22.53,79.2 22.62,79.12 22.94,79.12 23.02,79.2 23.02,79.66 23.23,79.86 23.72,79.86 23.93,79.66 23.93,79.2 24.01,79.12 24.33,79.12 24.41,79.2 24.41,79.66 24.62,79.86 25.12,79.86 25.32,79.66 25.32,79.2 25.4,79.12 25.73,79.12 25.81,79.2 25.81,79.66 26.01,79.86 26.51,79.86 26.71,79.66 26.71,79.2 26.79,79.12 27.12,79.12 27.2,79.2 27.2,79.66 27.4,79.86 27.9,79.86 28.1,79.66 28.1,79.2 28.18,79.12 28.51,79.12 28.59,79.2 28.59,79.66 28.79,79.86 29.29,79.86 29.49,79.66 29.49,79.2 29.58,79.12 29.9,79.12 29.98,79.2 29.98,79.66 30.19,79.86 30.68,79.86 30.89,79.66 30.89,79.2 30.97,79.12 31.29,79.12 31.37,79.2 31.37,79.66 31.58,79.86 32.08,79.86 32.28,79.66 32.28,79.2 32.36,79.12 32.68,79.12 32.77,79.2 32.77,79.66 32.97,79.86 33.47,79.86 33.67,79.66 33.67,79.2 33.75,79.12 34.08,79.12 34.16,79.2 34.16,79.66 34.36,79.86 34.86,79.86 35.06,79.66 35.06,79.2 35.14,79.12 35.47,79.12 35.55,79.2 35.55,79.66 35.75,79.86 36.25,79.86 36.45,79.66 36.45,79.2 36.54,79.12 36.86,79.12 36.94,79.2 36.94,79.66 37.14,79.86 37.64,79.86 37.85,79.66 37.85,79.2 37.93,79.12 38.25,79.12 38.33,79.2 38.33,79.66 38.54,79.86 39.03,79.86 39.24,79.66 39.24,79.3 39.32,79.22 39.64,79.22 39.73,79.3 39.73,79.66 39.93,79.86 40.43,79.86 40.63,79.66 40.63,79.33 40.71,79.24 41.04,79.24 41.12,79.33 41.12,79.66 41.32,79.86 42.43,79.86 48.24,74.04 53.81,74.04 56.32,71.53 67.82,71.53 67.9,71.62 v2(67.9,71.93)
FMC1_HB10_N: length 83.7
  TOP w0.124: U3.AN3 v2(65.9,63.93) ; 6.12,65.71 v2(5.49,65.07)
  L05-SIG2 w0.081: v2(65.9,63.93) 65.9,64.24 65.82,64.33 65.61,64.33 65.5,64.22 65.5,62.63 64.69,61.81 62.88,61.81 62.67,62.02 62.67,62.5 62.59,62.58 62.27,62.58 62.19,62.5 62.19,62.02 61.98,61.81 61.48,61.81 61.28,62.02 61.28,62.5 61.2,62.58 60.87,62.58 60.79,62.5 60.79,62.02 60.59,61.81 60.09,61.81 59.89,62.02 59.89,62.5 59.81,62.58 59.48,62.58 59.4,62.5 59.4,62.02 59.2,61.81 58.7,61.81 58.5,62.02 58.5,62.5 58.42,62.58 58.09,62.58 58.01,62.5 58.01,62.02 57.81,61.81 57.31,61.81 57.11,62.02 57.11,62.5 57.02,62.58 56.7,62.58 56.62,62.5 56.62,62.02 56.41,61.81 55.92,61.81 55.71,62.02 55.71,62.5 55.63,62.58 55.31,62.58 55.23,62.5 55.23,62.02 55.02,61.81 54.52,61.81 54.32,62.02 54.32,62.5 54.24,62.58 53.92,62.58 53.83,62.5 53.83,62.02 53.63,61.81 53.13,61.81 52.93,62.02 52.93,62.5 52.85,62.58 52.52,62.58 52.44,62.5 52.44,62.02 52.24,61.81 51.74,61.81 51.54,62.02 51.54,62.5 51.46,62.58 51.13,62.58 51.05,62.5 51.05,62.02 50.85,61.81 31.79,61.81 31.54,62.06 31.54,64.02 31.46,64.1 25.71,64.1 22.29,60.67 6.44,60.67 6.07,61.05 6.07,64.45 5.94,64.57 5.94,64.77 6.07,64.9 6.07,65.41 5.87,65.6 5.57,65.6 5.49,65.52 v2(5.49,65.07)
FMC1_HB10_P: length 83.6
  TOP w0.124: U3.AM3 v2(65.9,64.93) ; J48.K31 v2(5.49,66.34)
  L05-SIG2 w0.081: v2(5.49,66.34) 5.49,65.89 5.57,65.81 5.96,65.81 6.27,65.49 6.27,61.13 6.53,60.88 22.2,60.88 25.63,64.31 31.55,64.31 31.75,64.11 31.75,62.15 31.88,62.02 50.76,62.02 50.84,62.1 50.84,62.58 51.05,62.78 51.54,62.78 51.75,62.58 51.75,62.1 51.83,62.02 52.15,62.02 52.23,62.1 52.23,62.58 52.44,62.78 52.93,62.78 53.14,62.58 53.14,62.1 53.22,62.02 53.54,62.02 53.63,62.1 53.63,62.58 53.83,62.78 54.33,62.78 54.53,62.58 54.53,62.1 54.61,62.02 54.94,62.02 55.02,62.1 55.02,62.58 55.22,62.78 55.72,62.78 55.92,62.58 55.92,62.1 56,62.02 56.33,62.02 56.41,62.1 56.41,62.58 56.61,62.78 57.11,62.78 57.31,62.58 57.31,62.1 57.4,62.02 57.72,62.02 57.8,62.1 57.8,62.58 58,62.78 58.5,62.78 58.71,62.58 58.71,62.1 58.79,62.02 59.11,62.02 59.19,62.1 59.19,62.58 59.4,62.78 59.89,62.78 60.1,62.58 60.1,62.1 60.18,62.02 60.5,62.02 60.59,62.1 60.59,62.58 60.79,62.78 61.29,62.78 61.49,62.58 61.49,62.1 61.57,62.02 61.9,62.02 61.98,62.1 61.98,62.58 62.18,62.78 62.68,62.78 62.88,62.58 62.88,62.1 62.96,62.02 64.6,62.02 65.29,62.72 65.29,64.3 65.53,64.53 65.82,64.53 65.9,64.62 v2(65.9,64.93)
FMC1_HB11_N: length 85.8
  TOP w0.124: J48.J31 v2(8.03,67.61) ; U3.AK4 v2(66.9,66.93)
  L12-SIG4 w0.081: v2(8.03,67.61) 8.03,68.06 8.11,68.14 13.72,68.14 13.97,67.89 14.5,67.89 14.75,68.14 17.21,68.14 23.66,61.69 44.11,61.69 44.31,61.89 44.71,61.89 44.92,61.69 45.5,61.69 45.7,61.89 46.11,61.89 46.31,61.69 46.89,61.69 47.09,61.89 47.5,61.89 47.7,61.69 49.96,61.69 50.16,61.89 50.16,63 50.24,63.08 50.57,63.08 50.65,63 50.65,61.89 50.85,61.69 51.35,61.69 51.55,61.89 51.55,63 51.63,63.08 51.96,63.08 52.04,63 52.04,61.89 52.24,61.69 52.74,61.69 52.94,61.89 52.94,63 53.02,63.08 53.35,63.08 53.43,63 53.43,61.89 53.63,61.69 54.13,61.69 54.33,61.89 54.33,62.88 54.42,62.96 54.74,62.96 54.82,62.88 54.82,61.89 55.03,61.69 55.52,61.69 55.73,61.89 55.73,62.88 55.81,62.96 56.13,62.96 56.21,62.88 56.21,61.89 56.42,61.69 56.92,61.69 57.12,61.89 57.12,62.88 57.2,62.96 57.52,62.96 57.61,62.88 57.61,61.89 57.81,61.69 58.31,61.69 58.51,61.89 58.51,62.88 58.59,62.96 58.92,62.96 59,62.88 59,61.89 59.2,61.69 63.12,61.69 63.33,61.89 63.33,63.97 63.71,64.35 64.16,64.35 64.31,64.21 64.48,64.21 64.63,64.35 65.11,64.35 65.49,64.73 65.49,65.11 65.7,65.32 66.04,65.32 66.47,65.76 66.47,66.25 66.62,66.4 66.62,66.57 66.47,66.73 66.47,67.24 66.55,67.33 66.82,67.33 66.9,67.24 v2(66.9,66.93)
FMC1_HB11_P: length 85.6
  TOP w0.124: J48.J30 v2(8.03,68.88) ; U3.AJ4 v2(66.9,67.93)
  L12-SIG4 w0.081: v2(66.9,67.93) 66.9,67.62 66.82,67.53 66.47,67.53 66.26,67.33 66.26,65.84 65.95,65.53 65.61,65.53 65.28,65.2 65.28,64.82 65.02,64.56 63.63,64.56 63.12,64.05 63.12,61.98 63.04,61.9 59.29,61.9 59.21,61.98 59.21,62.96 59,63.17 58.51,63.17 58.3,62.96 58.3,61.98 58.22,61.9 57.9,61.9 57.81,61.98 57.81,62.96 57.61,63.17 57.11,63.17 56.91,62.96 56.91,61.98 56.83,61.9 56.5,61.9 56.42,61.98 56.42,62.96 56.22,63.17 55.72,63.17 55.52,62.96 55.52,61.98 55.44,61.9 55.11,61.9 55.03,61.98 55.03,62.96 54.83,63.17 54.33,63.17 54.13,62.96 54.13,61.98 54.05,61.9 53.72,61.9 53.64,61.98 53.64,63.09 53.44,63.29 52.94,63.29 52.73,63.09 52.73,61.98 52.65,61.9 52.33,61.9 52.25,61.98 52.25,63.09 52.04,63.29 51.55,63.29 51.34,63.09 51.34,61.98 51.26,61.9 50.94,61.9 50.85,61.98 50.85,63.09 50.65,63.29 50.15,63.29 49.95,63.09 49.95,61.98 49.87,61.9 47.79,61.9 47.58,62.1 47.01,62.1 46.8,61.9 46.4,61.9 46.19,62.1 45.61,62.1 45.41,61.9 45,61.9 44.8,62.1 44.22,62.1 44.02,61.9 23.75,61.9 17.29,68.35 14.66,68.35 14.41,68.1 14.05,68.1 13.8,68.35 8.11,68.35 8.03,68.43 v2(8.03,68.88)
FMC1_HB12_N: length 89.5
  TOP w0.124: U3.AH3 v2(65.9,68.93) ; 11.2,65.71 v2(10.57,66.34)
  L05-SIG2 w0.081: v2(65.9,68.93) 66.21,68.93 66.29,68.85 66.29,68.64 66.19,68.53 65.59,68.53 65.47,68.65 65.26,68.65 65.14,68.53 64.63,68.53 64.53,68.63 64.3,68.63 64.21,68.53 63.61,68.53 63.51,68.63 63.28,68.63 63.19,68.53 54.52,68.53 51.63,71.42 46.58,71.42 44.65,73.36 43.13,73.36 43.05,73.44 43.05,74.01 42.84,74.21 42.34,74.21 42.14,74.01 42.14,73.44 42.06,73.36 41.73,73.36 41.65,73.44 41.65,74.11 41.45,74.32 40.95,74.32 40.75,74.11 40.75,73.44 40.67,73.36 40.34,73.36 40.26,73.44 40.26,74.11 40.06,74.32 39.56,74.32 39.36,74.11 39.36,73.44 39.28,73.36 38.95,73.36 38.87,73.44 38.87,74.11 38.67,74.32 38.17,74.32 37.97,74.11 37.97,73.44 37.88,73.36 37.56,73.36 37.48,73.44 37.48,74.11 37.27,74.32 36.78,74.32 36.57,74.11 36.57,73.44 36.49,73.36 36.17,73.36 36.09,73.44 36.09,74.11 35.88,74.32 35.38,74.32 35.18,74.11 35.18,73.44 35.1,73.36 34.78,73.36 34.69,73.44 34.69,74.11 34.49,74.32 33.99,74.32 33.79,74.11 33.79,73.44 33.71,73.36 33.38,73.36 33.3,73.44 33.3,74.11 33.1,74.32 32.6,74.32 32.4,74.11 32.4,73.44 32.32,73.36 31.99,73.36 31.91,73.44 31.91,74.11 31.71,74.32 31.21,74.32 31.01,74.11 31.01,73.44 30.92,73.36 30.6,73.36 30.52,73.44 30.52,74.11 30.31,74.32 29.82,74.32 29.61,74.11 29.61,73.44 29.53,73.36 29.21,73.36 29.13,73.44 29.13,74.11 28.92,74.32 28.43,74.32 28.22,74.11 28.22,73.44 28.14,73.36 27.82,73.36 27.73,73.44 27.73,74.11 27.53,74.32 27.03,74.32 26.83,74.11 26.83,73.44 26.75,73.36 26.42,73.36 26.34,73.44 26.34,74.11 26.14,74.32 25.64,74.32 25.44,74.11 25.44,73.44 25.36,73.36 25.03,73.36 24.95,73.44 24.95,74.11 24.75,74.32 24.25,74.32 24.05,74.11 24.05,73.44 23.96,73.36 23.64,73.36 23.56,73.44 23.56,74.11 23.36,74.32 22.86,74.32 22.65,74.11 22.65,73.44 22.57,73.36 21.05,73.36 20.32,72.63 20.32,68.41 18.96,67.06 11.3,67.06 11.1,66.85 11.1,66.42 11.02,66.34 v2(10.57,66.34)
FMC1_HB12_P: length 89.2
  TOP w0.124: J48.F31 v2(11.84,66.34) ; U3.AH4 v2(66.9,68.93)
  L05-SIG2 w0.081: v2(66.9,68.93) 66.58,68.93 66.5,68.85 66.5,68.56 66.27,68.33 54.43,68.33 51.54,71.21 46.5,71.21 44.56,73.15 43.04,73.15 42.84,73.35 42.84,73.93 42.76,74.01 42.43,74.01 42.35,73.93 42.35,73.35 42.15,73.15 41.65,73.15 41.45,73.35 41.45,74.03 41.36,74.11 41.04,74.11 40.96,74.03 40.96,73.35 40.75,73.15 40.26,73.15 40.05,73.35 40.05,74.03 39.97,74.11 39.65,74.11 39.57,74.03 39.57,73.35 39.36,73.15 38.86,73.15 38.66,73.35 38.66,74.03 38.58,74.11 38.25,74.11 38.17,74.03 38.17,73.35 37.97,73.15 37.47,73.15 37.27,73.35 37.27,74.03 37.19,74.11 36.86,74.11 36.78,74.03 36.78,73.35 36.58,73.15 36.08,73.15 35.88,73.35 35.88,74.03 35.8,74.11 35.47,74.11 35.39,74.03 35.39,73.35 35.19,73.15 34.69,73.15 34.49,73.35 34.49,74.03 34.4,74.11 34.08,74.11 34,74.03 34,73.35 33.79,73.15 33.3,73.15 33.09,73.35 33.09,74.03 33.01,74.11 32.69,74.11 32.61,74.03 32.61,73.35 32.4,73.15 31.9,73.15 31.7,73.35 31.7,74.03 31.62,74.11 31.3,74.11 31.21,74.03 31.21,73.35 31.01,73.15 30.51,73.15 30.31,73.35 30.31,74.03 30.23,74.11 29.9,74.11 29.82,74.03 29.82,73.35 29.62,73.15 29.12,73.15 28.92,73.35 28.92,74.03 28.84,74.11 28.51,74.11 28.43,74.03 28.43,73.35 28.23,73.15 27.73,73.15 27.53,73.35 27.53,74.03 27.44,74.11 27.12,74.11 27.04,74.03 27.04,73.35 26.84,73.15 26.34,73.15 26.13,73.35 26.13,74.03 26.05,74.11 25.73,74.11 25.65,74.03 25.65,73.35 25.44,73.15 24.95,73.15 24.74,73.35 24.74,74.03 24.66,74.11 24.34,74.11 24.25,74.03 24.25,73.35 24.05,73.15 23.55,73.15 23.35,73.35 23.35,74.03 23.27,74.11 22.94,74.11 22.86,74.03 22.86,73.35 22.66,73.15 21.13,73.15 20.53,72.54 20.53,68.33 19.05,66.85 11.39,66.85 11.31,66.77 11.31,66.42 11.39,66.34 v2(11.84,66.34)
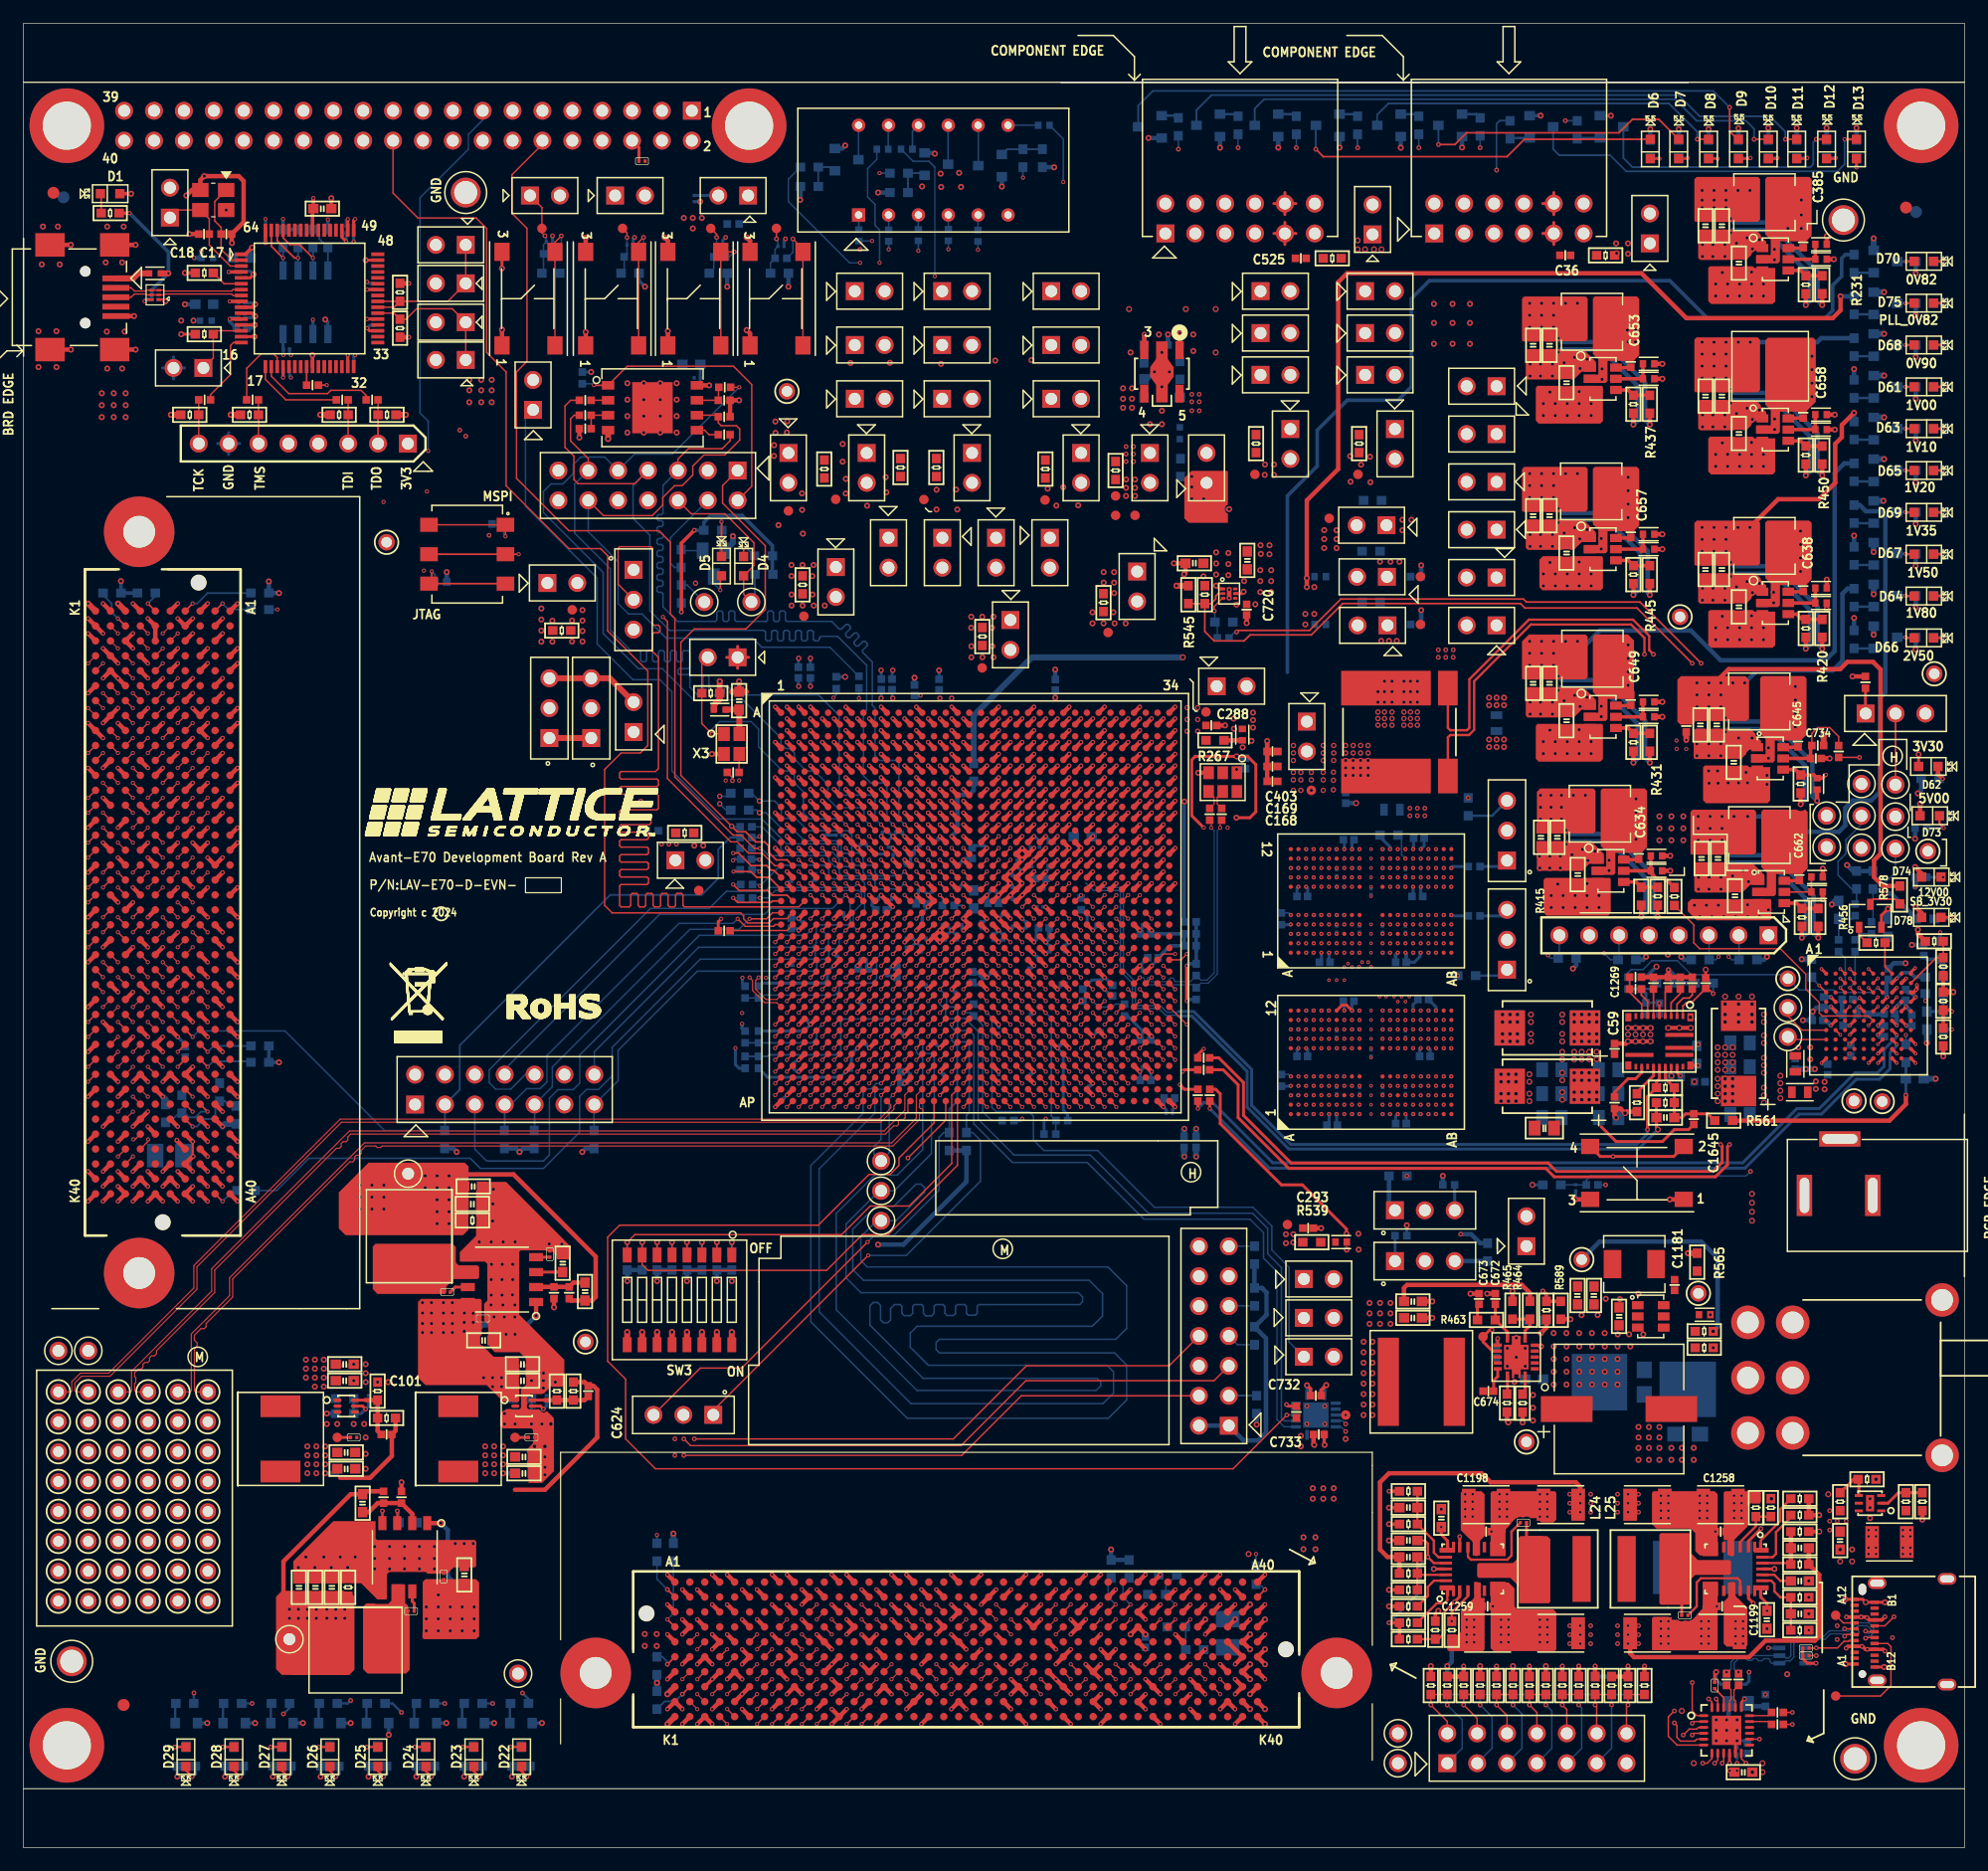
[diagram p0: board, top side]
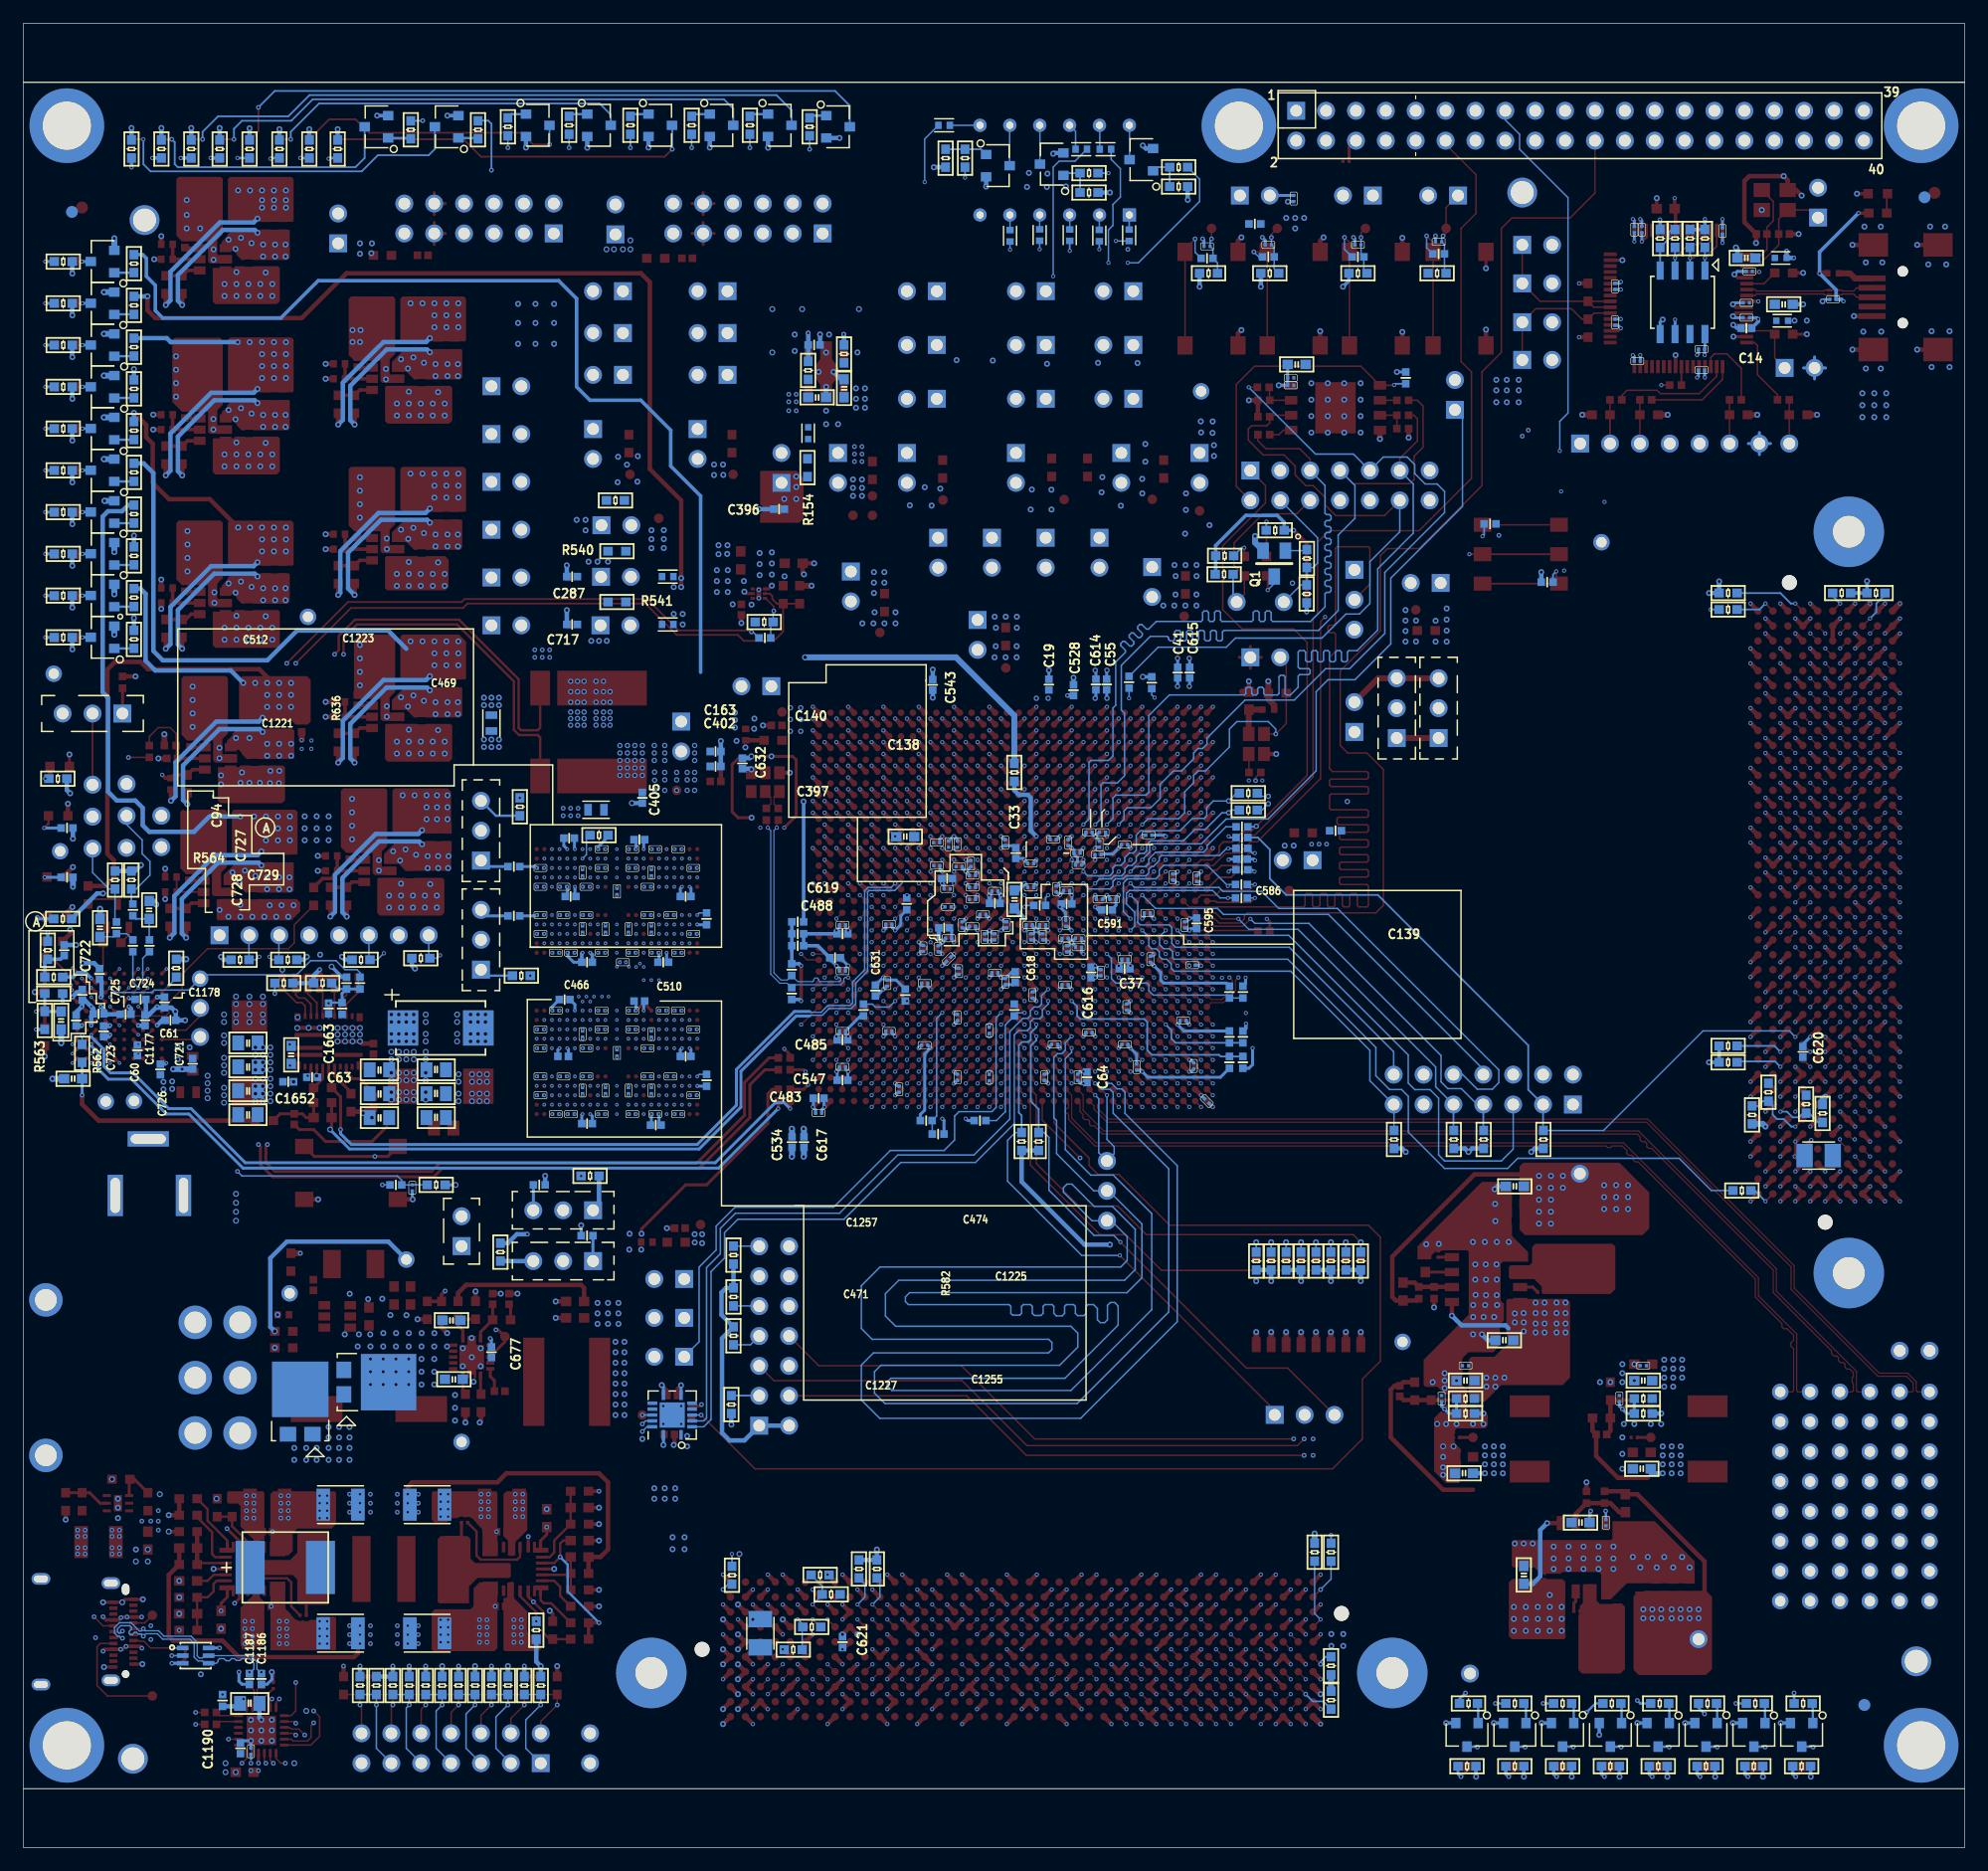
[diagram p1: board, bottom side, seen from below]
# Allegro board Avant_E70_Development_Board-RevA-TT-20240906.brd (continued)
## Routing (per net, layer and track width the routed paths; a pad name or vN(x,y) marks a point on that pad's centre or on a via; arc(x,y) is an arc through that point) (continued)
FMC1_LA00_CLK_N: length 97.5
  TOP w0.124: J48.G7 v2(9.3,98.09) ; U3.AA7 v2(69.9,75.93)
  L05-SIG2 w0.081: v2(69.9,75.93) 69.9,75.62 69.82,75.53 68.7,75.53 68.45,75.78 68.45,76.25 68.17,76.53 58.6,76.53 56.51,78.61 51.48,78.61 32,98.09 30.04,98.09 29.84,97.89 29.84,96.42 29.76,96.34 29.43,96.34 29.35,96.42 29.35,97.89 29.15,98.09 28.65,98.09 28.45,97.89 28.45,96.42 28.37,96.34 28.04,96.34 27.96,96.42 27.96,97.89 27.76,98.09 27.26,98.09 27.06,97.89 27.06,96.45 26.97,96.36 26.65,96.36 26.57,96.45 26.57,97.89 26.36,98.09 25.87,98.09 25.66,97.89 25.66,96.5 25.58,96.41 25.26,96.41 25.18,96.5 25.18,97.89 24.97,98.09 24.48,98.09 24.27,97.89 24.27,96.5 24.19,96.41 23.87,96.41 23.78,96.5 23.78,97.89 23.58,98.09 23.08,98.09 22.88,97.89 22.88,96.52 22.8,96.44 22.47,96.44 22.39,96.52 22.39,97.89 22.19,98.09 21.69,98.09 21.49,97.89 21.49,96.52 21.41,96.44 21.08,96.44 21,96.52 21,97.89 20.8,98.09 20.3,98.09 20.1,97.89 20.1,96.52 20.01,96.44 19.69,96.44 19.61,96.52 19.61,97.89 19.41,98.09 18.84,98.09 18.07,98.85 10.03,98.85 9.83,98.65 9.83,98.17 9.75,98.09 v2(9.3,98.09)
FMC1_LA00_CLK_P: length 97.3
  TOP w0.124: J48.G6 v2(10.57,98.09) ; U3.AB7 v2(69.9,74.93)
  L05-SIG2 w0.081: v2(10.57,98.09) 10.12,98.09 10.04,98.17 10.04,98.56 10.12,98.64 17.99,98.64 18.75,97.88 19.32,97.88 19.4,97.8 19.4,96.43 19.6,96.23 20.1,96.23 20.3,96.43 20.3,97.8 20.39,97.88 20.71,97.88 20.79,97.8 20.79,96.43 21,96.23 21.49,96.23 21.7,96.43 21.7,97.8 21.78,97.88 22.1,97.88 22.18,97.8 22.18,96.43 22.39,96.23 22.89,96.23 23.09,96.43 23.09,97.8 23.17,97.88 23.49,97.88 23.58,97.8 23.58,96.41 23.78,96.21 24.28,96.21 24.48,96.41 24.48,97.8 24.56,97.88 24.89,97.88 24.97,97.8 24.97,96.41 25.17,96.21 25.67,96.21 25.87,96.41 25.87,97.8 25.95,97.88 26.28,97.88 26.36,97.8 26.36,96.36 26.56,96.16 27.06,96.16 27.26,96.36 27.26,97.8 27.35,97.88 27.67,97.88 27.75,97.8 27.75,96.33 27.95,96.13 28.45,96.13 28.66,96.33 28.66,97.8 28.74,97.88 29.06,97.88 29.14,97.8 29.14,96.33 29.35,96.13 29.84,96.13 30.05,96.33 30.05,97.8 30.13,97.88 30.9,97.88 31.02,97.76 31.29,97.76 31.41,97.88 31.92,97.88 32.29,97.51 32.29,97.3 32.41,97.17 32.63,97.17 32.75,97.05 32.75,96.86 32.9,96.71 33.09,96.71 51.39,78.41 56.42,78.41 58.51,76.32 68.09,76.32 68.24,76.16 68.24,75.69 68.61,75.33 69.5,75.33 v2(69.9,74.93)
FMC1_LA01_CLK_N: length 97.3
  TOP w0.124: U3.AC9 v2(71.9,73.93) ; J48.D9 v2(14.38,95.55)
  L05-SIG2 w0.081: v2(14.38,95.55) 13.93,95.55 13.85,95.47 13.85,95.17 13.97,95.04 19.06,95.04 19.26,94.84 19.26,93.66 19.34,93.57 19.67,93.57 19.75,93.66 19.75,94.84 19.95,95.04 20.45,95.04 20.65,94.84 20.65,93.66 20.73,93.57 21.06,93.57 21.14,93.66 21.14,94.84 21.34,95.04 21.84,95.04 22.04,94.84 22.04,93.66 22.13,93.57 22.45,93.57 22.53,93.66 22.53,94.84 22.74,95.04 23.23,95.04 23.44,94.84 23.44,93.66 23.52,93.57 23.84,93.57 23.92,93.66 23.92,94.84 24.13,95.04 24.63,95.04 24.83,94.84 24.83,93.55 24.91,93.47 25.23,93.47 25.32,93.55 25.32,94.84 25.52,95.04 26.02,95.04 26.22,94.84 26.22,93.55 26.3,93.47 26.63,93.47 26.71,93.55 26.71,94.84 26.91,95.04 27.41,95.04 27.61,94.84 27.61,93.55 27.69,93.47 28.02,93.47 28.1,93.55 28.1,94.84 28.3,95.04 28.8,95.04 29,94.84 29,93.52 29.09,93.44 29.41,93.44 29.49,93.52 29.49,94.84 29.7,95.04 30.19,95.04 30.4,94.84 30.4,93.52 30.48,93.44 30.8,93.44 30.88,93.52 30.88,94.84 31.09,95.04 31.58,95.04 31.79,94.84 31.79,93.52 31.87,93.44 32.19,93.44 32.28,93.52 32.28,94.84 32.48,95.04 33.25,95.04 50.52,77.77 55.98,77.77 58.22,75.53 67.17,75.53 67.52,75.19 67.52,74.64 67.63,74.53 71.23,74.53 71.5,74.27 71.5,74.01 71.58,73.93 v2(71.9,73.93)
FMC1_LA01_CLK_P: length 97.4
  TOP w0.124: J48.D8 v2(13.11,95.55) ; U3.AC8 v2(70.9,73.93)
  L05-SIG2 w0.081: v2(70.9,73.93) 71.21,73.93 71.3,74.01 71.3,74.18 71.15,74.33 70.6,74.33 70.48,74.21 70.26,74.21 70.15,74.33 69.68,74.33 69.57,74.21 69.35,74.21 69.24,74.33 67.54,74.33 67.31,74.56 67.31,75.1 67.09,75.33 58.13,75.33 55.9,77.56 50.43,77.56 33.16,94.83 32.57,94.83 32.48,94.75 32.48,93.44 32.28,93.23 31.78,93.23 31.58,93.44 31.58,94.75 31.5,94.83 31.17,94.83 31.09,94.75 31.09,93.44 30.89,93.23 30.39,93.23 30.19,93.44 30.19,94.75 30.11,94.83 29.78,94.83 29.7,94.75 29.7,93.44 29.5,93.23 29,93.23 28.8,93.44 28.8,94.75 28.71,94.83 28.39,94.83 28.31,94.75 28.31,93.46 28.11,93.26 27.61,93.26 27.4,93.46 27.4,94.75 27.32,94.83 27,94.83 26.92,94.75 26.92,93.46 26.71,93.26 26.22,93.26 26.01,93.46 26.01,94.75 25.93,94.83 25.61,94.83 25.52,94.75 25.52,93.46 25.32,93.26 24.82,93.26 24.62,93.46 24.62,94.75 24.54,94.83 24.21,94.83 24.13,94.75 24.13,93.57 23.93,93.37 23.43,93.37 23.23,93.57 23.23,94.75 23.15,94.83 22.82,94.83 22.74,94.75 22.74,93.57 22.54,93.37 22.04,93.37 21.84,93.57 21.84,94.75 21.76,94.83 21.43,94.83 21.35,94.75 21.35,93.57 21.15,93.37 20.65,93.37 20.44,93.57 20.44,94.75 20.36,94.83 20.04,94.83 19.96,94.75 19.96,93.57 19.75,93.37 19.26,93.37 19.05,93.57 19.05,94.75 18.97,94.83 13.89,94.83 13.64,95.08 13.64,95.47 13.56,95.55 v2(13.11,95.55)
FMC1_LA02_N: length 98.7
  TOP w0.124: J48.H8 v2(9.3,95.55) ; U3.AB12 v2(74.9,74.93)
  L10-SIG3 w0.081: v2(74.9,74.93) 75.13,74.93 75.22,75.02 75.22,75.28 75.14,75.36 74.68,75.36 74.29,75.74 74.29,82.17 74.17,82.29 74.17,82.55 74.29,82.67 74.29,83.11 74.08,83.32 73.7,83.32 73.56,83.18 73.38,83.18 73.24,83.32 72.63,83.32 72.49,83.18 72.3,83.18 72.16,83.33 64.64,83.33 64.31,83.65 64.31,85.22 56.72,92.8 43.26,92.8 39.98,96.08 32.53,96.08 32.33,96.29 32.33,96.96 32.25,97.04 31.93,97.04 31.84,96.96 31.84,96.29 31.64,96.08 31.14,96.08 30.94,96.29 30.94,96.96 30.86,97.04 30.53,97.04 30.45,96.96 30.45,96.29 30.25,96.08 29.75,96.08 29.55,96.29 29.55,96.96 29.47,97.04 29.14,97.04 29.06,96.96 29.06,96.29 28.86,96.08 28.36,96.08 28.16,96.29 28.16,96.96 28.07,97.04 27.75,97.04 27.67,96.96 27.67,96.29 27.46,96.08 26.97,96.08 26.76,96.29 26.76,96.96 26.68,97.04 26.36,97.04 26.28,96.96 26.28,96.29 26.07,96.08 25.58,96.08 25.37,96.29 25.37,96.96 25.29,97.04 24.97,97.04 24.88,96.96 24.88,96.29 24.68,96.08 24.18,96.08 23.98,96.29 23.98,96.96 23.9,97.04 23.57,97.04 23.49,96.96 23.49,96.29 23.29,96.08 22.79,96.08 22.59,96.29 22.59,96.96 22.51,97.04 22.18,97.04 22.1,96.96 22.1,96.29 21.9,96.08 21.4,96.08 21.2,96.29 21.2,96.96 21.11,97.04 20.79,97.04 20.71,96.96 20.71,96.29 20.51,96.08 20.01,96.08 19.8,96.29 19.8,96.96 19.72,97.04 19.4,97.04 19.32,96.96 19.32,96.29 19.11,96.08 9.38,96.08 9.3,96 v2(9.3,95.55)
FMC1_LA02_P: length 98.9
  TOP w0.124: U3.AB13 v2(75.9,74.93) ; J48.H7 v2(9.3,96.82)
  L10-SIG3 w0.081: v2(9.3,96.82) 9.3,96.37 9.38,96.29 19.03,96.29 19.11,96.37 19.11,97.05 19.31,97.25 19.81,97.25 20.01,97.05 20.01,96.37 20.09,96.29 20.42,96.29 20.5,96.37 20.5,97.05 20.7,97.25 21.2,97.25 21.4,97.05 21.4,96.37 21.49,96.29 21.81,96.29 21.89,96.37 21.89,97.05 22.1,97.25 22.59,97.25 22.8,97.05 22.8,96.37 22.88,96.29 23.2,96.29 23.28,96.37 23.28,97.05 23.49,97.25 23.98,97.25 24.19,97.05 24.19,96.37 24.27,96.29 24.59,96.29 24.68,96.37 24.68,97.05 24.88,97.25 25.38,97.25 25.58,97.05 25.58,96.37 25.66,96.29 25.99,96.29 26.07,96.37 26.07,97.05 26.27,97.25 26.77,97.25 26.97,97.05 26.97,96.37 27.05,96.29 27.38,96.29 27.46,96.37 27.46,97.05 27.66,97.25 28.16,97.25 28.36,97.05 28.36,96.37 28.45,96.29 28.77,96.29 28.85,96.37 28.85,97.05 29.05,97.25 29.55,97.25 29.76,97.05 29.76,96.37 29.84,96.29 30.16,96.29 30.24,96.37 30.24,97.05 30.45,97.25 30.94,97.25 31.15,97.05 31.15,96.37 31.23,96.29 31.55,96.29 31.64,96.37 31.64,97.05 31.84,97.25 32.34,97.25 32.54,97.05 32.54,96.37 32.62,96.29 40.07,96.29 43.35,93.01 56.81,93.01 64.52,85.3 64.52,83.74 64.72,83.53 74.16,83.53 74.5,83.2 74.5,75.83 74.76,75.57 75.22,75.57 75.43,75.36 75.43,75.03 75.53,74.93 75.85,74.93 75.85,74.93 v2(75.9,74.93)
FMC1_LA03_N: length 96.6
  TOP w0.124: U3.Y10 v2(72.9,76.93) ; J48.G10 v2(10.57,94.28)
  L10-SIG3 w0.081: v2(10.57,94.28) 10.57,94.73 10.65,94.81 19.18,94.81 19.41,95.04 19.79,95.04 20.02,94.81 20.57,94.81 20.8,95.04 21.18,95.04 21.41,94.81 21.97,94.81 22.19,95.04 22.57,95.04 22.8,94.81 23.36,94.81 23.58,95.04 23.97,95.04 24.19,94.81 24.75,94.81 24.98,95.04 25.36,95.04 25.58,94.81 26.14,94.81 26.37,95.04 26.75,95.04 26.98,94.81 27.53,94.81 27.76,95.04 28.14,95.04 28.37,94.81 28.92,94.81 29.15,95.04 29.53,95.04 29.76,94.81 30.32,94.81 30.54,95.04 30.93,95.04 31.15,94.81 39.73,94.81 42.63,91.91 50.43,91.91 50.51,91.83 50.51,90.75 50.71,90.54 51.21,90.54 51.41,90.75 51.41,91.83 51.49,91.91 51.82,91.91 51.9,91.83 51.9,90.87 52.1,90.67 52.6,90.67 52.81,90.87 52.81,91.83 52.89,91.91 53.93,91.91 54.64,91.2 54.64,91.09 53.83,90.28 53.83,89.99 54.18,89.64 54.47,89.64 55.91,91.08 56.02,91.08 56.25,90.84 56.25,90.73 54.78,89.25 54.78,88.97 55.13,88.62 55.42,88.62 56.94,90.14 57.06,90.14 57.29,89.91 57.29,89.8 56.12,88.63 56.12,88.34 56.47,87.99 56.76,87.99 57.25,88.48 57.36,88.48 58.05,87.79 58.34,87.79 58.6,88.05 58.71,88.05 58.95,87.82 58.95,87.71 58.68,87.45 58.68,87.16 60.58,85.26 61.04,85.26 61.25,85.47 61.25,86.3 61.33,86.38 61.65,86.38 61.73,86.3 61.73,85.47 61.94,85.26 62.87,85.26 63.12,85.01 63.12,83.49 64.28,82.33 70.21,82.33 70.34,82.19 70.49,82.19 70.62,82.33 71.16,82.33 71.3,82.19 71.53,82.19 71.65,82.31 72.17,82.31 72.31,82.17 72.54,82.17 72.69,82.31 73.06,82.31 73.3,82.07 73.3,81.65 73.15,81.5 73.15,81.29 73.3,81.15 73.3,80.76 73.15,80.62 73.15,80.4 73.3,80.26 73.3,77.01 73.21,76.93 v2(72.9,76.93)
FMC1_LA03_P: length 96.2
  TOP w0.124: U3.Y11 v2(73.9,76.93) ; J48.G9 v2(10.57,95.55)
  L10-SIG3 w0.081: v2(73.9,76.93) 73.5,77.33 73.5,82.16 73.13,82.53 64.37,82.53 63.33,83.57 63.33,85.1 62.95,85.47 62.02,85.47 61.94,85.55 61.94,86.38 61.74,86.58 61.24,86.58 61.04,86.38 61.04,85.55 60.96,85.47 60.67,85.47 58.89,87.25 58.89,87.36 59.15,87.62 59.15,87.91 58.8,88.26 58.51,88.26 58.25,88 58.14,88 57.45,88.69 57.16,88.69 56.67,88.19 56.56,88.19 56.33,88.42 56.33,88.54 57.5,89.71 57.5,90 57.14,90.35 56.86,90.35 55.33,88.82 55.22,88.82 54.99,89.05 54.99,89.17 56.46,90.64 56.46,90.93 56.11,91.28 55.82,91.28 54.38,89.85 54.27,89.85 54.04,90.08 54.04,90.19 54.85,91 54.85,91.29 54.02,92.12 52.8,92.12 52.6,91.92 52.6,90.96 52.52,90.88 52.19,90.88 52.11,90.96 52.11,91.92 51.91,92.12 51.41,92.12 51.21,91.92 51.21,90.83 51.12,90.75 50.8,90.75 50.72,90.83 50.72,91.92 50.51,92.12 42.71,92.12 39.81,95.02 31.24,95.02 31.01,95.25 30.46,95.25 30.23,95.02 29.85,95.02 29.62,95.25 29.06,95.25 28.84,95.02 28.45,95.02 28.23,95.25 27.67,95.25 27.45,95.02 27.06,95.02 26.84,95.25 26.28,95.25 26.05,95.02 25.67,95.02 25.44,95.25 24.89,95.25 24.66,95.02 24.28,95.02 24.05,95.25 23.5,95.25 23.27,95.02 22.89,95.02 22.66,95.25 22.1,95.25 21.88,95.02 21.5,95.02 21.27,95.25 20.71,95.25 20.49,95.02 20.1,95.02 19.88,95.25 19.32,95.25 19.09,95.02 10.65,95.02 10.57,95.1 v2(10.57,95.55)
FMC1_LA04_N: length 97.9
  TOP w0.124: J48.H11 v2(9.3,93.01) ; U3.AC12 v2(74.9,73.93)
  L10-SIG3 w0.081: v2(74.9,73.93) 75.18,73.93 75.25,74 75.25,74.18 75.17,74.26 73.57,74.26 73.32,74.51 73.32,76.08 73.12,76.29 72.6,76.29 72.26,76.63 72.26,79.29 72.16,79.4 72.16,79.68 72.26,79.78 72.26,80.16 72.16,80.26 72.16,80.51 72.26,80.62 72.26,81.2 72.09,81.37 71.65,81.37 71.53,81.25 71.3,81.25 71.18,81.37 70.68,81.37 70.59,81.28 70.3,81.28 70.21,81.37 64.22,81.37 63.37,82.22 61.88,82.22 61.68,82.42 61.68,84.31 61.6,84.4 61.27,84.4 61.19,84.31 61.19,82.42 60.99,82.22 59.44,82.22 59.1,82.55 59.1,83.3 59.3,83.5 59.6,83.5 59.68,83.58 59.68,83.91 59.6,83.99 59.3,83.99 59.1,84.19 59.1,85.18 58.25,86.03 56.81,86.03 56.61,86.23 56.61,87.08 56.53,87.16 56.2,87.16 56.12,87.08 56.12,86.23 55.92,86.03 55.42,86.03 55.22,86.23 55.22,87.08 55.14,87.16 54.81,87.16 54.73,87.08 54.73,86.23 54.53,86.03 53.59,86.03 52.85,86.77 52.85,87.05 53.88,88.08 53.88,88.19 53.65,88.42 53.53,88.42 52.51,87.4 52.22,87.4 51.25,88.37 51.25,88.66 51.99,89.4 51.99,89.52 51.76,89.75 51.65,89.75 50.9,89 50.62,89 48.47,91.15 41.82,91.15 39,93.97 27.17,93.97 26.92,93.72 26.38,93.72 26.13,93.97 25.77,93.97 25.52,93.72 24.99,93.72 24.74,93.97 24.38,93.97 24.13,93.72 23.6,93.72 23.35,93.97 22.99,93.97 22.74,93.72 22.21,93.72 21.96,93.97 21.6,93.97 21.35,93.72 20.82,93.72 20.57,93.97 20.21,93.97 19.96,93.72 19.42,93.72 19.17,93.97 18.04,93.97 17.61,93.54 9.38,93.54 9.3,93.46 v2(9.3,93.01)
FMC1_LA04_P: length 98
  TOP w0.124: U3.AC13 v2(75.9,73.93) ; J48.H10 v2(9.3,94.28)
  L10-SIG3 w0.081: v2(75.9,73.93) 75.58,73.93 75.46,74.05 75.46,74.27 75.26,74.47 73.66,74.47 73.53,74.6 73.53,76.17 73.2,76.5 72.68,76.5 72.47,76.71 72.47,81.29 72.18,81.58 64.3,81.58 63.46,82.42 61.97,82.42 61.89,82.51 61.89,84.4 61.68,84.6 61.19,84.6 60.98,84.4 60.98,82.51 60.9,82.42 59.52,82.42 59.31,82.64 59.31,83.21 59.39,83.29 59.69,83.29 59.89,83.5 59.89,84 59.69,84.2 59.39,84.2 59.31,84.28 59.31,85.26 58.34,86.23 56.9,86.23 56.82,86.32 56.82,87.17 56.62,87.37 56.12,87.37 55.91,87.17 55.91,86.32 55.83,86.23 55.51,86.23 55.43,86.32 55.43,87.17 55.22,87.37 54.73,87.37 54.52,87.17 54.52,86.32 54.44,86.23 53.68,86.23 53.06,86.85 53.06,86.97 54.09,87.99 54.09,88.28 53.73,88.63 53.45,88.63 52.42,87.61 52.31,87.61 51.46,88.46 51.46,88.57 52.2,89.32 52.2,89.6 51.85,89.96 51.56,89.96 50.82,89.21 50.7,89.21 48.55,91.36 41.91,91.36 39.09,94.18 27.08,94.18 26.83,93.93 26.47,93.93 26.22,94.18 25.69,94.18 25.44,93.93 25.08,93.93 24.83,94.18 24.3,94.18 24.05,93.93 23.69,93.93 23.44,94.18 22.9,94.18 22.65,93.93 22.29,93.93 22.04,94.18 21.51,94.18 21.26,93.93 20.9,93.93 20.65,94.18 20.12,94.18 19.87,93.93 19.51,93.93 19.26,94.18 17.96,94.18 17.53,93.75 9.38,93.75 9.3,93.83 v2(9.3,94.28)
FMC1_LA05_N: length 97.6
  TOP w0.099: J48.D12 v2(14.38,91.74)
  TOP w0.124: U3.AA9 v2(71.9,75.93)
  L10-SIG3 w0.081: v2(14.38,91.74) 13.93,91.74 13.85,91.66 13.85,91.31 13.93,91.23 16.54,91.23 16.63,91.31 16.63,91.66 16.83,91.87 17.33,91.87 17.53,91.66 17.53,91.31 17.61,91.23 18.58,91.23 19.01,90.81 19.3,90.81 19.38,90.89 19.38,92.07 19.58,92.27 20.08,92.27 20.28,92.07 20.28,90.89 20.36,90.81 20.69,90.81 20.77,90.89 20.77,92.05 20.97,92.25 21.47,92.25 21.67,92.05 21.67,90.89 21.76,90.81 22.08,90.81 22.16,90.89 22.16,91.99 22.36,92.2 22.86,92.2 23.07,91.99 23.07,90.89 23.15,90.81 23.47,90.81 23.55,90.89 23.55,91.99 23.76,92.2 24.25,92.2 24.46,91.99 24.46,90.89 24.54,90.81 24.86,90.81 24.95,90.89 24.95,92.02 25.15,92.22 25.65,92.22 25.85,92.02 25.85,90.89 25.93,90.81 26.26,90.81 26.34,90.89 26.34,91.99 26.54,92.2 27.04,92.2 27.24,91.99 27.24,90.89 27.32,90.81 27.65,90.81 27.73,90.89 27.73,91.54 27.93,91.74 28.43,91.74 28.63,91.54 28.63,90.89 28.71,90.81 29.04,90.81 29.12,90.89 29.12,91.54 29.32,91.74 29.82,91.74 30.03,91.54 30.03,90.89 30.11,90.81 30.43,90.81 30.51,90.89 30.51,91.54 30.72,91.74 31.21,91.74 31.42,91.54 31.42,90.89 31.5,90.81 31.82,90.81 31.9,90.89 31.9,91.54 32.11,91.74 32.61,91.74 32.81,91.54 32.81,90.89 32.89,90.81 39.42,90.81 40.51,89.71 45.72,89.71 55.16,80.27 55.53,80.27 55.61,80.35 55.61,81.5 55.81,81.71 56.31,81.71 56.52,81.5 56.52,80.35 56.6,80.27 56.92,80.27 57,80.35 57,81.5 57.21,81.71 57.7,81.71 57.91,81.5 57.91,80.35 57.99,80.27 63.21,80.27 63.79,79.68 70.25,79.68 70.52,79.41 70.52,78.58 70.31,78.38 69.57,78.38 69.49,78.29 69.49,76.65 69.56,76.58 70.94,76.58 71.59,75.93 v2(71.9,75.93)
FMC1_LA05_P: length 97.2
  TOP w0.099: J48.D11 v2(13.11,91.74)
  TOP w0.124: U3.AA8 v2(70.9,75.93)
  L10-SIG3 w0.081: v2(13.11,91.74) 13.56,91.74 13.64,91.66 13.64,91.23 13.84,91.02 16.63,91.02 16.83,91.23 16.83,91.58 16.92,91.66 17.24,91.66 17.32,91.58 17.32,91.23 17.53,91.02 18.5,91.02 18.92,90.6 19.38,90.6 19.59,90.8 19.59,91.98 19.67,92.07 19.99,92.07 20.07,91.98 20.07,90.8 20.28,90.6 20.77,90.6 20.98,90.8 20.98,91.96 21.06,92.04 21.38,92.04 21.47,91.96 21.47,90.8 21.67,90.6 22.17,90.6 22.37,90.8 22.37,91.91 22.45,91.99 22.78,91.99 22.86,91.91 22.86,90.8 23.06,90.6 23.56,90.6 23.76,90.8 23.76,91.91 23.84,91.99 24.17,91.99 24.25,91.91 24.25,90.8 24.45,90.6 24.95,90.6 25.15,90.8 25.15,91.93 25.23,92.02 25.56,92.02 25.64,91.93 25.64,90.8 25.84,90.6 26.34,90.6 26.55,90.8 26.55,91.91 26.63,91.99 26.95,91.99 27.03,91.91 27.03,90.8 27.24,90.6 27.73,90.6 27.94,90.8 27.94,91.45 28.02,91.53 28.34,91.53 28.43,91.45 28.43,90.8 28.63,90.6 29.13,90.6 29.33,90.8 29.33,91.45 29.41,91.53 29.74,91.53 29.82,91.45 29.82,90.8 30.02,90.6 30.52,90.6 30.72,90.8 30.72,91.45 30.8,91.53 31.13,91.53 31.21,91.45 31.21,90.8 31.41,90.6 31.91,90.6 32.11,90.8 32.11,91.45 32.19,91.53 32.52,91.53 32.6,91.45 32.6,90.8 32.8,90.6 39.33,90.6 40.43,89.5 45.63,89.5 55.08,80.06 55.62,80.06 55.82,80.26 55.82,81.42 55.9,81.5 56.23,81.5 56.31,81.42 56.31,80.26 56.51,80.06 57.01,80.06 57.21,80.26 57.21,81.42 57.29,81.5 57.62,81.5 57.7,81.42 57.7,80.26 57.9,80.06 63.12,80.06 63.71,79.47 70.16,79.47 70.31,79.32 70.31,78.67 70.23,78.58 69.49,78.58 69.28,78.38 69.28,76.56 69.47,76.37 70.85,76.37 70.99,76.23 70.99,76.02 v2(70.9,75.93)
FMC1_LA06_N: length 96.1
  TOP w0.099: J48.C11 v2(15.65,93.01)
  TOP w0.124: U3.Y9 v2(71.9,76.93)
  L10-SIG3 w0.081: v2(15.65,93.01) 15.2,93.01 15.12,92.93 15.12,92.72 15.25,92.58 16.1,92.58 16.22,92.71 16.42,92.71 16.54,92.58 17.01,92.58 17.14,92.71 17.34,92.71 17.46,92.58 17.76,92.58 18.16,92.99 27.68,92.99 27.88,92.78 27.88,92.54 27.96,92.46 28.29,92.46 28.37,92.54 28.37,92.78 28.57,92.99 29.07,92.99 29.27,92.78 29.27,92.54 29.35,92.46 29.68,92.46 29.76,92.54 29.76,92.78 29.96,92.99 30.46,92.99 30.66,92.78 30.66,92.54 30.75,92.46 31.07,92.46 31.15,92.54 31.15,92.91 31.36,93.11 31.85,93.11 32.06,92.91 32.06,92.54 32.14,92.46 32.46,92.46 32.54,92.54 32.54,93.16 32.75,93.37 33.43,93.37 33.73,93.06 33.73,91.78 33.82,91.7 34.14,91.7 34.22,91.78 34.22,93.16 34.42,93.37 34.92,93.37 35.13,93.16 35.13,91.78 35.21,91.7 35.53,91.7 35.61,91.78 35.61,93.16 35.82,93.37 36.31,93.37 36.52,93.16 36.52,91.78 36.6,91.7 36.92,91.7 37.01,91.78 37.01,93.19 37.21,93.39 37.71,93.39 37.91,93.19 37.91,91.78 37.99,91.7 38.32,91.7 38.4,91.78 38.4,92.73 38.6,92.93 39.1,92.93 39.3,92.73 39.3,91.78 39.38,91.7 39.92,91.7 41.02,90.6 46.23,90.6 47.27,89.55 47.39,89.55 48.07,90.24 48.36,90.24 48.71,89.89 48.71,89.6 48.03,88.91 48.03,88.8 48.26,88.57 48.37,88.57 49.06,89.26 49.35,89.26 49.7,88.9 49.7,88.62 49.01,87.93 49.01,87.81 49.24,87.58 49.36,87.58 50.04,88.27 50.33,88.27 50.68,87.92 50.68,87.63 50,86.94 50,86.83 50.23,86.6 50.34,86.6 51.03,87.29 51.32,87.29 51.67,86.93 51.67,86.65 50.98,85.96 50.98,85.84 51.21,85.61 51.33,85.61 51.82,86.11 52.11,86.11 52.46,85.76 52.46,85.47 51.97,84.97 51.97,84.86 52.31,84.51 52.43,84.51 53.06,85.15 53.35,85.15 53.7,84.8 53.7,84.51 53.07,83.87 53.07,83.76 54.25,82.57 57.99,82.57 59.28,81.28 63.46,81.28 64.22,80.52 71.09,80.52 71.5,80.11 71.5,77.01 71.58,76.93 v2(71.9,76.93)
FMC1_LA06_P: length 95.9
  TOP w0.099: J48.C10 v2(14.38,93.01)
  TOP w0.124: U3.Y8 v2(70.9,76.93)
  L10-SIG3 w0.081: v2(70.9,76.93) 71.21,76.93 71.29,77.01 71.29,80.02 71,80.31 64.13,80.31 63.37,81.07 59.19,81.07 57.9,82.36 54.17,82.36 52.86,83.67 52.86,83.96 53.5,84.6 53.5,84.71 53.26,84.94 53.15,84.94 52.51,84.31 52.23,84.31 51.76,84.77 51.76,85.06 52.26,85.56 52.26,85.67 52.03,85.9 51.91,85.9 51.41,85.41 51.13,85.41 50.77,85.76 50.77,86.05 51.46,86.73 51.46,86.85 51.23,87.08 51.12,87.08 50.43,86.39 50.14,86.39 49.79,86.74 49.79,87.03 50.48,87.72 50.48,87.83 50.25,88.06 50.13,88.06 49.44,87.38 49.16,87.38 48.8,87.73 48.8,88.02 49.49,88.7 49.49,88.82 49.26,89.05 49.15,89.05 48.46,88.36 48.17,88.36 47.82,88.71 47.82,89 48.51,89.69 48.51,89.8 48.27,90.03 48.16,90.03 47.47,89.35 47.19,89.35 46.14,90.39 40.93,90.39 39.84,91.49 39.3,91.49 39.09,91.69 39.09,92.65 39.01,92.73 38.69,92.73 38.61,92.65 38.61,91.69 38.4,91.49 37.9,91.49 37.7,91.69 37.7,93.1 37.62,93.18 37.3,93.18 37.21,93.1 37.21,91.69 37.01,91.49 36.51,91.49 36.31,91.69 36.31,93.08 36.23,93.16 35.9,93.16 35.82,93.08 35.82,91.69 35.62,91.49 35.12,91.49 34.92,91.69 34.92,93.08 34.84,93.16 34.51,93.16 34.43,93.08 34.43,91.69 34.23,91.49 33.73,91.49 33.53,91.69 33.53,92.97 33.34,93.16 32.83,93.16 32.75,93.08 32.75,92.45 32.55,92.25 32.05,92.25 31.85,92.45 31.85,92.82 31.77,92.9 31.44,92.9 31.36,92.82 31.36,92.45 31.16,92.25 30.66,92.25 30.46,92.45 30.46,92.7 30.37,92.78 30.05,92.78 29.97,92.7 29.97,92.45 29.77,92.25 29.27,92.25 29.06,92.45 29.06,92.7 28.98,92.78 28.66,92.78 28.58,92.7 28.58,92.45 28.37,92.25 27.88,92.25 27.67,92.45 27.67,92.7 27.59,92.78 18.25,92.78 17.85,92.38 15.16,92.38 14.91,92.63 14.91,92.93 14.83,93.01 v2(14.38,93.01)
FMC1_LA07_N: length 86.4
  TOP w0.124: J48.H14 v2(9.3,87.93) ; U3.AA1 v2(63.9,75.93)
  L10-SIG3 w0.081: v2(9.3,87.93) 9.3,88.38 9.38,88.46 9.75,88.46 9.85,88.36 10.03,88.36 10.13,88.46 10.9,88.46 11.18,88.18 11.18,87.78 11.07,87.68 11.07,87.47 11.18,87.37 11.18,86.28 11.51,85.94 18.29,85.94 18.46,85.77 18.94,85.77 19.11,85.94 19.36,85.94 19.53,85.77 20.01,85.77 20.18,85.94 20.79,85.94 20.96,85.77 21.54,85.77 21.71,85.94 22.18,85.94 22.35,85.77 22.93,85.77 23.11,85.94 23.57,85.94 23.75,85.77 24.33,85.77 24.5,85.94 27.39,85.94 27.53,85.8 27.53,85.38 27.45,85.29 26.91,85.29 26.66,85.05 26.66,84.42 26.87,84.22 28.31,84.22 28.52,84.42 28.52,85.74 28.6,85.82 28.92,85.82 29,85.74 29,84.37 29.21,84.17 29.68,84.17 29.91,84.4 29.91,85.74 29.99,85.82 30.31,85.82 30.4,85.74 30.4,84.37 30.6,84.17 31.07,84.17 31.3,84.39 31.3,85.74 31.38,85.82 31.71,85.82 31.79,85.74 31.79,84.45 31.99,84.25 32.49,84.25 32.69,84.45 32.69,85.74 32.77,85.82 33.1,85.82 33.18,85.74 33.18,84.45 33.38,84.25 33.88,84.25 34.08,84.45 34.08,85.74 34.16,85.82 34.49,85.82 34.57,85.74 34.57,84.45 34.77,84.25 35.27,84.25 35.48,84.45 35.48,85.74 35.56,85.82 35.88,85.82 35.96,85.74 35.96,84.45 36.17,84.25 36.66,84.25 36.87,84.45 36.87,85.74 36.95,85.82 37.27,85.82 37.36,85.74 37.36,84.45 37.56,84.25 45.72,84.25 53.64,76.33 63.82,76.33 63.9,76.24 v2(63.9,75.93)
FMC1_LA07_P: length 86.2
  TOP w0.124: J48.H13 v2(9.3,89.2) ; U3.Y1 v2(63.9,76.93)
  L10-SIG3 w0.081: v2(9.3,89.2) 9.3,88.75 9.38,88.67 10.99,88.67 11.38,88.27 11.38,86.37 11.6,86.15 18.38,86.15 18.55,85.98 18.85,85.98 19.03,86.15 19.44,86.15 19.61,85.98 19.92,85.98 20.09,86.15 20.88,86.15 21.05,85.98 21.45,85.98 21.63,86.15 22.27,86.15 22.44,85.98 22.85,85.98 23.02,86.15 23.66,86.15 23.83,85.98 24.24,85.98 24.41,86.15 27.47,86.15 27.74,85.89 27.74,85.29 27.53,85.09 27,85.09 26.87,84.96 26.87,84.51 26.95,84.43 28.23,84.43 28.31,84.51 28.31,85.82 28.51,86.03 29.01,86.03 29.21,85.82 29.21,84.46 29.29,84.37 29.59,84.37 29.7,84.48 29.7,85.82 29.9,86.03 30.4,86.03 30.6,85.82 30.6,84.46 30.68,84.37 30.99,84.37 31.09,84.48 31.09,85.82 31.29,86.03 31.79,86.03 32,85.82 32,84.54 32.08,84.46 32.4,84.46 32.48,84.54 32.48,85.82 32.69,86.03 33.18,86.03 33.39,85.82 33.39,84.54 33.47,84.46 33.79,84.46 33.88,84.54 33.88,85.82 34.08,86.03 34.58,86.03 34.78,85.82 34.78,84.54 34.86,84.46 35.19,84.46 35.27,84.54 35.27,85.82 35.47,86.03 35.97,86.03 36.17,85.82 36.17,84.54 36.25,84.46 36.58,84.46 36.66,84.54 36.66,85.82 36.86,86.03 37.36,86.03 37.56,85.82 37.56,84.54 37.64,84.46 45.81,84.46 53.73,76.53 63.82,76.53 63.9,76.62 v2(63.9,76.93)
FMC1_LA08_N: length 91.7
  TOP w0.124: J48.G13 v2(9.3,90.47)
  TOP w0.152: U3.AB5 v2(67.9,74.93)
  L10-SIG3 w0.081: v2(9.3,90.47) 9.3,90.92 9.22,91 8.77,91 8.67,90.9 8.45,90.9 8.35,91 7.28,91 7.19,90.9 6.93,90.9 6.84,91 6.5,91 6.22,90.72 6.22,90.39 6.38,90.24 6.38,90.06 6.22,89.91 6.22,89.74 6.38,89.59 6.38,89.41 6.22,89.26 6.22,87.5 5.92,87.19 5.03,87.19 4.88,87.04 4.88,86.18 4.96,86.1 7.2,86.1 7.28,86.18 7.28,87.99 7.49,88.19 8.02,88.19 8.1,88.27 8.1,88.6 8.02,88.68 7.49,88.68 7.28,88.88 7.28,89.63 7.62,89.96 9.95,89.96 10.03,90.04 10.03,91.13 10.23,91.33 11.23,91.33 11.43,91.13 11.43,90.04 11.51,89.96 38.99,89.96 40.01,88.95 45.38,88.95 54.78,79.55 62.27,79.55 62.82,79 64.98,79 65.44,78.53 68.24,78.53 68.53,78.24 68.53,75.69 68.17,75.33 67.6,75.33 67.4,75.14 67.4,75.01 67.48,74.93 v2(67.9,74.93)
FMC1_LA08_P: length 91.3
  TOP w0.124: J48.G12 v2(9.3,91.74)
  TOP w0.152: U3.AB4 v2(66.9,74.93)
  L10-SIG3 w0.081: v2(9.3,91.74) 9.3,91.29 9.22,91.21 6.41,91.21 6.01,90.81 6.01,87.59 5.83,87.4 4.95,87.4 4.67,87.12 4.67,86.1 4.87,85.89 7.29,85.89 7.49,86.1 7.49,87.9 7.57,87.98 8.1,87.98 8.31,88.19 8.31,88.69 8.1,88.89 7.57,88.89 7.49,88.97 7.49,89.54 7.71,89.75 10.03,89.75 10.24,89.96 10.24,91.05 10.32,91.13 11.14,91.13 11.22,91.05 11.22,89.96 11.42,89.75 38.9,89.75 39.92,88.74 45.29,88.74 54.69,79.34 62.18,79.34 62.74,78.79 64.9,78.79 65.36,78.33 68.15,78.33 68.33,78.15 68.33,75.78 68.09,75.54 67.51,75.54 v2(66.9,74.93)
FMC1_LA09_N: length 88
  TOP w0.124: J48.D15 v2(14.38,87.93) ; U3.Y2 v2(64.9,76.93)
  L10-SIG3 w0.081: v2(14.38,87.93) 14.38,88.51 14.3,88.59 12.78,88.59 12.57,88.39 12.57,88.08 12.65,88.01 12.65,87.75 12.57,87.68 12.57,87.4 12.67,87.3 12.98,87.3 13.11,87.42 13.33,87.42 13.46,87.3 13.64,87.3 13.74,87.4 13.94,87.4 14.05,87.3 17.5,87.3 17.58,87.38 17.58,87.73 17.78,87.93 18.28,87.93 18.48,87.73 18.48,87.28 18.56,87.19 18.93,87.19 19.01,87.28 19.01,87.73 19.21,87.93 19.71,87.93 19.91,87.73 19.91,87.02 19.99,86.94 20.32,86.94 20.4,87.02 20.4,87.73 20.6,87.93 21.1,87.93 21.31,87.73 21.31,87.02 21.39,86.94 21.71,86.94 21.79,87.02 21.79,87.73 22,87.93 22.49,87.93 22.7,87.73 22.7,87 22.78,86.91 23.1,86.91 23.18,87 23.18,87.73 23.39,87.93 23.89,87.93 24.09,87.73 24.09,87.05 24.17,86.97 24.5,86.97 24.58,87.05 24.58,87.73 24.78,87.93 25.28,87.93 25.48,87.73 25.48,87.12 25.56,87.04 38.36,87.04 38.56,86.84 38.56,85.3 38.64,85.22 38.96,85.22 39.05,85.3 39.05,86.84 39.25,87.04 39.75,87.04 39.95,86.84 39.95,85.3 40.03,85.22 40.36,85.22 40.44,85.3 40.44,86.84 40.64,87.04 41.14,87.04 41.34,86.84 41.34,85.3 41.42,85.22 41.75,85.22 41.83,85.3 41.83,86.84 42.03,87.04 42.53,87.04 42.73,86.84 42.73,85.3 42.82,85.22 43.22,85.22 43.3,85.3 43.3,86.84 43.51,87.04 44,87.04 44.21,86.84 44.21,85.3 44.29,85.22 44.61,85.22 44.69,85.3 44.69,86.2 44.9,86.41 45.4,86.41 45.6,86.2 45.6,85.3 45.68,85.22 46.15,85.22 53.89,77.47 64.18,77.47 64.47,77.18 64.47,76.65 64.7,76.42 64.82,76.42 64.9,76.5 v2(64.9,76.93)
FMC1_LA09_P: length 87.7
  TOP w0.124: J48.D14 v2(14.38,89.2) ; U3.AA2 v2(64.9,75.93)
  L10-SIG3 w0.081: v2(64.9,75.93) 64.26,76.57 64.26,77.1 64.09,77.26 53.81,77.26 46.06,85.01 45.59,85.01 45.39,85.21 45.39,86.12 45.31,86.2 44.98,86.2 44.9,86.12 44.9,85.21 44.7,85.01 44.2,85.01 44,85.21 44,86.75 43.92,86.83 43.59,86.83 43.51,86.75 43.51,85.21 43.31,85.01 42.73,85.01 42.53,85.21 42.53,86.75 42.44,86.83 42.12,86.83 42.04,86.75 42.04,85.21 41.84,85.01 41.34,85.01 41.13,85.21 41.13,86.75 41.05,86.83 40.73,86.83 40.65,86.75 40.65,85.21 40.44,85.01 39.95,85.01 39.74,85.21 39.74,86.75 39.66,86.83 39.34,86.83 39.25,86.75 39.25,85.21 39.05,85.01 38.55,85.01 38.35,85.21 38.35,86.75 38.27,86.83 25.48,86.83 25.27,87.04 25.27,87.64 25.19,87.72 24.87,87.72 24.79,87.64 24.79,86.96 24.58,86.76 24.08,86.76 23.88,86.96 23.88,87.64 23.8,87.72 23.47,87.72 23.39,87.64 23.39,86.91 23.19,86.71 22.69,86.71 22.49,86.91 22.49,87.64 22.41,87.72 22.08,87.72 22,87.64 22,86.94 21.8,86.73 21.3,86.73 21.1,86.94 21.1,87.64 21.02,87.72 20.69,87.72 20.61,87.64 20.61,86.94 20.41,86.73 19.91,86.73 19.71,86.94 19.71,87.64 19.62,87.72 19.3,87.72 19.22,87.64 19.22,87.19 19.01,86.99 18.48,86.99 18.27,87.19 18.27,87.64 18.19,87.72 17.87,87.72 17.79,87.64 17.79,87.29 17.58,87.09 12.59,87.09 12.36,87.31 12.36,88.47 12.69,88.8 13.98,88.8 v2(14.38,89.2)
FMC1_LA10_N: length 92.7
  TOP w0.124: J48.C15 v2(15.65,87.93)
  TOP w0.152: U3.AA5 v2(67.9,75.93)
  L10-SIG3 w0.081: v2(67.9,75.93) 67.9,76.28 67.75,76.43 67.48,76.43 67.29,76.62 67.29,77.15 67.12,77.33 65.28,77.33 64.58,78.02 60.43,78.02 60.22,78.22 60.22,78.5 60.14,78.58 59.82,78.58 59.73,78.5 59.73,78.22 59.53,78.02 59.03,78.02 58.83,78.22 58.83,78.5 58.75,78.58 58.42,78.58 58.34,78.5 58.34,78.22 58.14,78.02 57.64,78.02 57.44,78.22 57.44,78.5 57.36,78.58 57.03,78.58 56.95,78.5 56.95,78.22 56.75,78.02 56.25,78.02 56.05,78.22 56.05,78.5 55.97,78.58 55.64,78.58 55.56,78.5 55.56,78.22 55.36,78.02 54.7,78.02 54.3,78.42 54.18,78.42 54.1,78.34 53.81,78.34 53.46,78.69 53.46,78.98 53.54,79.06 53.54,79.18 53.31,79.41 53.2,79.41 53.12,79.32 52.83,79.32 52.48,79.68 52.48,79.96 52.56,80.05 52.56,80.16 52.33,80.39 52.21,80.39 52.13,80.31 51.84,80.31 51.49,80.66 51.49,80.95 51.57,81.03 51.57,81.15 51.34,81.38 51.23,81.38 51.15,81.29 50.86,81.29 50.51,81.65 50.51,81.93 50.59,82.02 50.59,82.13 50.36,82.36 50.24,82.36 50.16,82.28 49.87,82.28 49.52,82.63 49.52,82.92 49.6,83 49.6,83.12 49.37,83.35 49.26,83.35 49.18,83.27 48.89,83.27 48.54,83.62 48.54,83.9 48.62,83.99 48.62,84.1 48.39,84.33 48.27,84.33 48.19,84.25 47.9,84.25 47.55,84.6 47.55,84.89 47.63,84.97 47.63,85.09 47.4,85.32 47.29,85.32 47.21,85.24 46.92,85.24 46.57,85.59 46.57,85.87 46.65,85.96 46.65,86.07 45.04,87.68 38.8,87.68 38.59,87.88 38.59,88.78 38.51,88.87 38.19,88.87 38.1,88.78 38.1,87.88 37.9,87.68 37.4,87.68 37.2,87.88 37.2,88.91 37.12,88.99 36.79,88.99 36.71,88.91 36.71,87.88 36.51,87.68 36.01,87.68 35.81,87.88 35.81,88.91 35.73,88.99 35.4,88.99 35.32,88.91 35.32,87.88 35.12,87.68 34.62,87.68 34.42,87.88 34.42,88.91 34.33,88.99 34.01,88.99 33.93,88.91 33.93,87.88 33.73,87.68 33.23,87.68 33.02,87.88 33.02,88.91 32.94,88.99 32.62,88.99 32.54,88.91 32.54,87.88 32.33,87.68 31.84,87.68 31.63,87.88 31.63,88.91 31.55,88.99 31.23,88.99 31.14,88.91 31.14,87.88 30.94,87.68 30.44,87.68 30.24,87.88 30.24,88.91 30.16,88.99 29.83,88.99 29.75,88.91 29.75,87.88 29.55,87.68 29.05,87.68 28.85,87.88 28.85,88.91 28.77,88.99 28.44,88.99 28.36,88.91 28.36,87.88 28.16,87.68 27.66,87.68 27.46,87.88 27.46,88.91 27.38,88.99 27.05,88.99 26.97,88.91 26.97,87.88 26.77,87.68 26.27,87.68 26.06,87.88 26.06,88.38 25.98,88.46 25.17,88.46 24.97,88.67 24.97,88.96 24.89,89.04 24.56,89.04 24.48,88.96 24.48,88.67 24.28,88.46 23.78,88.46 23.58,88.67 23.58,88.96 23.5,89.04 23.17,89.04 23.09,88.96 23.09,88.67 22.89,88.46 22.39,88.46 22.19,88.67 22.19,88.96 22.1,89.04 21.78,89.04 21.7,88.96 21.7,88.67 21.49,88.46 21,88.46 20.79,88.67 20.79,88.96 20.71,89.04 20.39,89.04 20.31,88.96 20.31,88.67 20.1,88.46 19.6,88.46 19.4,88.67 19.4,88.96 19.32,89.04 18.99,89.04 18.91,88.96 18.91,88.67 18.71,88.46 18.21,88.46 18.01,88.67 18.01,88.96 17.93,89.04 17.6,89.04 17.52,88.96 17.52,88.67 17.32,88.46 15.73,88.46 15.65,88.38 v2(15.65,87.93)
FMC1_LA10_P: length 92.5
  TOP w0.124: J48.C14 v2(15.65,89.2)
  TOP w0.152: U3.Y5 v2(67.9,76.93)
  L10-SIG3 w0.081: v2(67.9,76.93) 67.9,76.68 67.85,76.64 67.57,76.64 67.5,76.71 67.5,77.24 67.21,77.53 65.36,77.53 64.67,78.23 60.51,78.23 60.43,78.31 60.43,78.58 60.23,78.79 59.73,78.79 59.53,78.58 59.53,78.31 59.45,78.23 59.12,78.23 59.04,78.31 59.04,78.58 58.84,78.79 58.34,78.79 58.13,78.58 58.13,78.31 58.05,78.23 57.73,78.23 57.65,78.31 57.65,78.58 57.44,78.79 56.95,78.79 56.74,78.58 56.74,78.31 56.66,78.23 56.34,78.23 56.25,78.31 56.25,78.58 56.05,78.79 55.55,78.79 55.35,78.58 55.35,78.31 55.27,78.23 54.79,78.23 54.38,78.63 54.1,78.63 54.01,78.55 53.9,78.55 53.67,78.78 53.67,78.89 53.75,78.98 53.75,79.26 53.4,79.62 53.11,79.62 53.03,79.53 52.91,79.53 52.68,79.76 52.68,79.88 52.77,79.96 52.77,80.25 52.41,80.6 52.13,80.6 52.04,80.52 51.93,80.52 51.7,80.75 51.7,80.86 51.78,80.95 51.78,81.23 51.43,81.59 51.14,81.59 51.06,81.5 50.94,81.5 50.71,81.73 50.71,81.85 50.8,81.93 50.8,82.22 50.44,82.57 50.16,82.57 50.07,82.49 49.96,82.49 49.73,82.72 49.73,82.83 49.81,82.92 49.81,83.2 49.46,83.56 49.17,83.56 49.09,83.47 48.97,83.47 48.74,83.7 48.74,83.82 48.83,83.9 48.83,84.19 48.47,84.54 48.19,84.54 48.1,84.46 47.99,84.46 47.76,84.69 47.76,84.8 47.84,84.89 47.84,85.17 47.49,85.53 47.2,85.53 47.12,85.44 47,85.44 46.77,85.67 46.77,85.79 46.86,85.87 46.86,86.16 45.13,87.89 38.88,87.89 38.8,87.97 38.8,88.87 38.6,89.07 38.1,89.07 37.9,88.87 37.9,87.97 37.81,87.89 37.49,87.89 37.41,87.97 37.41,89 37.21,89.2 36.71,89.2 36.5,89 36.5,87.97 36.42,87.89 36.1,87.89 36.02,87.97 36.02,89 35.81,89.2 35.32,89.2 35.11,89 35.11,87.97 35.03,87.89 34.71,87.89 34.62,87.97 34.62,89 34.42,89.2 33.92,89.2 33.72,89 33.72,87.97 33.64,87.89 33.31,87.89 33.23,87.97 33.23,89 33.03,89.2 32.53,89.2 32.33,89 32.33,87.97 32.25,87.89 31.92,87.89 31.84,87.97 31.84,89 31.64,89.2 31.14,89.2 30.94,89 30.94,87.97 30.86,87.89 30.53,87.89 30.45,87.97 30.45,89 30.25,89.2 29.75,89.2 29.54,89 29.54,87.97 29.46,87.89 29.14,87.89 29.06,87.97 29.06,89 28.85,89.2 28.36,89.2 28.15,89 28.15,87.97 28.07,87.89 27.75,87.89 27.66,87.97 27.66,89 27.46,89.2 26.96,89.2 26.76,89 26.76,87.97 26.68,87.89 26.35,87.89 26.27,87.97 26.27,88.47 26.07,88.67 25.26,88.67 25.18,88.75 25.18,89.05 24.97,89.25 24.48,89.25 24.27,89.05 24.27,88.75 24.19,88.67 23.87,88.67 23.79,88.75 23.79,89.05 23.58,89.25 23.08,89.25 22.88,89.05 22.88,88.75 22.8,88.67 22.47,88.67 22.39,88.75 22.39,89.05 22.19,89.25 21.69,89.25 21.49,89.05 21.49,88.75 21.41,88.67 21.08,88.67 21,88.75 21,89.05 20.8,89.25 20.3,89.25 20.1,89.05 20.1,88.75 20.02,88.67 19.69,88.67 19.61,88.75 19.61,89.05 19.41,89.25 18.91,89.25 18.71,89.05 18.71,88.75 18.62,88.67 18.3,88.67 18.22,88.75 18.22,89.05 18.01,89.25 17.52,89.25 17.31,89.05 17.31,88.75 17.23,88.67 15.73,88.67 15.65,88.75 v2(15.65,89.2)
FMC1_LA11_N: length 89.6
  TOP w0.099: 8.66,84.76 v2(8.03,85.39)
  TOP w0.152: U3.AD4 v2(66.9,72.93)
  L10-SIG3 w0.081: v2(66.9,72.93) 66.58,72.93 66.5,72.85 66.5,71.67 66.13,71.29 52.96,71.29 48.77,75.48 47.78,75.48 47.7,75.4 47.7,75.05 47.5,74.85 47,74.85 46.8,75.05 46.8,75.4 46.72,75.48 46.39,75.48 46.31,75.4 46.31,75.05 46.11,74.85 45.61,74.85 45.41,75.05 45.41,75.4 45.33,75.48 38.71,75.48 38.5,75.69 38.5,76.34 38.42,76.42 38.1,76.42 38.02,76.34 38.02,75.69 37.81,75.48 37.31,75.48 37.11,75.69 37.11,76.34 37.03,76.42 36.7,76.42 36.62,76.34 36.62,75.69 36.42,75.48 35.92,75.48 35.72,75.69 35.72,76.34 35.64,76.42 35.31,76.42 35.23,76.34 35.23,75.69 35.03,75.48 34.53,75.48 34.33,75.69 34.33,76.29 34.25,76.37 33.92,76.37 33.84,76.29 33.84,75.69 33.64,75.48 33.14,75.48 32.94,75.69 32.94,76.21 32.85,76.29 32.53,76.29 32.45,76.21 32.45,75.69 32.24,75.48 31.75,75.48 31.54,75.69 31.54,76.21 31.46,76.29 31.14,76.29 31.06,76.21 31.06,75.56 30.85,75.35 30.35,75.35 30.15,75.56 30.15,76.21 30.07,76.29 29.75,76.29 29.66,76.21 29.66,75.53 29.46,75.33 28.96,75.33 28.76,75.53 28.76,76.21 28.68,76.29 28.35,76.29 28.27,76.21 28.27,75.48 28.07,75.28 27.57,75.28 27.37,75.48 27.37,76.21 27.29,76.29 26.96,76.29 26.88,76.21 26.88,75.25 26.68,75.05 25.9,75.05 21.35,79.59 20.58,79.59 20.38,79.8 20.38,80.02 20.3,80.1 19.98,80.1 19.89,80.02 19.89,79.8 19.69,79.59 19.19,79.59 18.99,79.8 18.99,80.02 18.91,80.1 18.58,80.1 18.5,80.02 18.5,79.8 18.3,79.59 17.8,79.59 17.6,79.8 17.6,80.02 17.52,80.1 17.19,80.1 17.11,80.02 17.11,79.8 16.91,79.59 16.41,79.59 16.21,79.8 16.21,80.02 16.12,80.1 15.8,80.1 15.72,80.02 15.72,79.8 15.51,79.59 8.8,79.59 8.56,79.84 8.56,85.31 8.48,85.39 v2(8.03,85.39)
FMC1_LA11_P: length 89.2
  TOP w0.099: J48.H16 v2(9.3,85.39)
  TOP w0.152: U3.AD3 v2(65.9,72.93)
  L10-SIG3 w0.081: v2(65.9,72.93) 66.21,72.93 66.3,72.85 66.3,72.68 66.17,72.56 66.17,72.32 66.3,72.2 66.3,71.76 66.04,71.5 65.68,71.5 65.53,71.65 65.28,71.65 65.13,71.5 64.74,71.5 64.59,71.65 64.34,71.65 64.19,71.5 53.05,71.5 48.85,75.69 47.7,75.69 47.49,75.49 47.49,75.14 47.41,75.06 47.09,75.06 47.01,75.14 47.01,75.49 46.8,75.69 46.31,75.69 46.1,75.49 46.1,75.14 46.02,75.06 45.7,75.06 45.61,75.14 45.61,75.49 45.41,75.69 38.79,75.69 38.71,75.77 38.71,76.42 38.51,76.63 38.01,76.63 37.81,76.42 37.81,75.77 37.73,75.69 37.4,75.69 37.32,75.77 37.32,76.42 37.12,76.63 36.62,76.63 36.42,76.42 36.42,75.77 36.33,75.69 36.01,75.69 35.93,75.77 35.93,76.42 35.72,76.63 35.23,76.63 35.02,76.42 35.02,75.77 34.94,75.69 34.62,75.69 34.54,75.77 34.54,76.37 34.33,76.58 33.83,76.58 33.63,76.37 33.63,75.77 33.55,75.69 33.22,75.69 33.14,75.77 33.14,76.3 32.94,76.5 32.44,76.5 32.24,76.3 32.24,75.77 32.16,75.69 31.83,75.69 31.75,75.77 31.75,76.3 31.55,76.5 31.05,76.5 30.85,76.3 30.85,75.64 30.77,75.56 30.44,75.56 30.36,75.64 30.36,76.3 30.16,76.5 29.66,76.5 29.46,76.3 29.46,75.62 29.37,75.54 29.05,75.54 28.97,75.62 28.97,76.3 28.76,76.5 28.27,76.5 28.06,76.3 28.06,75.57 27.98,75.48 27.66,75.48 27.58,75.57 27.58,76.3 27.37,76.5 26.87,76.5 26.67,76.3 26.67,75.34 26.59,75.26 25.98,75.26 21.44,79.8 20.67,79.8 20.59,79.88 20.59,80.11 20.39,80.31 19.89,80.31 19.69,80.11 19.69,79.88 19.6,79.8 19.28,79.8 19.2,79.88 19.2,80.11 18.99,80.31 18.5,80.31 18.29,80.11 18.29,79.88 18.21,79.8 17.89,79.8 17.81,79.88 17.81,80.11 17.6,80.31 17.1,80.31 16.9,80.11 16.9,79.88 16.82,79.8 16.5,79.8 16.41,79.88 16.41,80.11 16.21,80.31 15.71,80.31 15.51,80.11 15.51,79.88 15.43,79.8 8.89,79.8 8.77,79.93 8.77,85.31 8.85,85.39 v2(9.3,85.39)
FMC1_LA12_N: length 89.3
  TOP w0.099: J48.G16 v2(10.57,86.66)
  TOP w0.124: U3.Y3 v2(65.9,76.93)
  L10-SIG3 w0.081: v2(10.57,86.66) 10.12,86.66 10.04,86.58 10.04,86.25 10.16,86.13 10.16,85.93 10.04,85.81 10.04,85.01 10.16,84.88 11.13,84.88 11.33,84.68 11.33,83.72 11.41,83.64 12.31,83.64 12.4,83.72 12.4,84.68 12.6,84.88 13.18,84.88 13.28,84.98 13.51,84.98 13.61,84.88 13.83,84.88 13.93,84.98 14.16,84.98 14.26,84.88 14.48,84.88 14.58,84.98 14.81,84.98 14.91,84.88 16.7,84.88 16.78,84.96 16.78,85.19 16.99,85.39 17.48,85.39 17.69,85.19 17.69,84.65 17.8,84.53 18.6,84.53 18.95,84.88 19.73,84.88 19.96,84.66 20.34,84.66 20.57,84.88 21.13,84.88 21.35,84.66 21.74,84.66 21.96,84.88 22.77,84.88 23.11,84.54 23.11,83.65 23.2,83.57 23.65,83.57 23.73,83.65 23.73,85.06 23.93,85.26 24.43,85.26 24.63,85.06 24.63,83.65 24.72,83.57 25.04,83.57 25.12,83.65 25.12,85.04 25.33,85.24 25.82,85.24 26.03,85.04 26.03,83.65 26.11,83.57 35.4,83.57 35.6,83.36 35.6,82.51 35.68,82.42 36.01,82.42 36.09,82.51 36.09,83.36 36.29,83.57 36.79,83.57 36.99,83.36 36.99,82.51 37.08,82.42 37.4,82.42 37.48,82.51 37.48,83.36 37.68,83.57 38.18,83.57 38.39,83.36 38.39,82.51 38.47,82.42 38.79,82.42 38.87,82.51 38.87,83.36 39.08,83.57 39.57,83.57 39.78,83.36 39.78,82.51 39.86,82.42 40.18,82.42 40.27,82.51 40.27,83.36 40.47,83.57 40.97,83.57 41.17,83.36 41.17,82.51 41.25,82.42 41.58,82.42 41.66,82.51 41.66,83.36 41.86,83.57 42.36,83.57 42.56,83.36 42.56,82.51 42.64,82.42 42.97,82.42 43.05,82.51 43.05,83.36 43.25,83.57 43.75,83.57 43.95,83.36 43.95,82.51 44.03,82.42 44.36,82.42 44.44,82.51 44.44,83.36 44.64,83.57 45.55,83.57 53.63,75.48 62.28,75.48 62.38,75.59 62.6,75.59 62.71,75.48 62.93,75.48 63.03,75.59 63.26,75.59 63.36,75.48 63.58,75.48 63.68,75.59 63.91,75.59 64.01,75.48 64.23,75.48 64.33,75.59 64.56,75.59 64.66,75.48 65.12,75.48 65.32,75.69 65.32,76.33 65.53,76.53 65.82,76.53 65.9,76.62 v2(65.9,76.93)
FMC1_LA12_P: length 89
  TOP w0.099: J48.G15 v2(9.3,86.66)
  TOP w0.124: U3.AA3 v2(65.9,75.93)
  L10-SIG3 w0.081: v2(9.3,86.66) 9.75,86.66 9.83,86.58 9.83,84.92 10.08,84.67 11.04,84.67 11.12,84.59 11.12,83.63 11.32,83.43 12.4,83.43 12.6,83.63 12.6,84.59 12.68,84.67 16.79,84.67 16.99,84.88 16.99,85.1 17.07,85.18 17.4,85.18 17.48,85.1 17.48,84.56 17.71,84.32 18.68,84.32 19.03,84.67 19.65,84.67 19.87,84.45 20.43,84.45 20.65,84.67 21.04,84.67 21.26,84.45 21.82,84.45 22.05,84.67 22.69,84.67 22.91,84.46 22.91,83.57 23.11,83.36 23.74,83.36 23.94,83.56 23.94,84.97 24.02,85.06 24.35,85.06 24.43,84.97 24.43,83.56 24.63,83.36 25.13,83.36 25.33,83.56 25.33,84.95 25.41,85.03 25.74,85.03 25.82,84.95 25.82,83.56 26.02,83.36 35.31,83.36 35.39,83.28 35.39,82.42 35.6,82.22 36.09,82.22 36.3,82.42 36.3,83.28 36.38,83.36 36.7,83.36 36.79,83.28 36.79,82.42 36.99,82.22 37.49,82.22 37.69,82.42 37.69,83.28 37.77,83.36 38.1,83.36 38.18,83.28 38.18,82.42 38.38,82.22 38.88,82.22 39.08,82.42 39.08,83.28 39.16,83.36 39.49,83.36 39.57,83.28 39.57,82.42 39.77,82.22 40.27,82.22 40.47,82.42 40.47,83.28 40.55,83.36 40.88,83.36 40.96,83.28 40.96,82.42 41.16,82.22 41.66,82.22 41.87,82.42 41.87,83.28 41.95,83.36 42.27,83.36 42.35,83.28 42.35,82.42 42.56,82.22 43.05,82.22 43.26,82.42 43.26,83.28 43.34,83.36 43.66,83.36 43.75,83.28 43.75,82.42 43.95,82.22 44.45,82.22 44.65,82.42 44.65,83.28 44.73,83.36 45.47,83.36 53.55,75.28 65.2,75.28 65.53,75.61 65.53,76.24 65.61,76.33 65.82,76.33 65.9,76.24 v2(65.9,75.93)
FMC1_LA13_N: length 91
  TOP w0.099: J48.D18 v2(14.38,84.12)
  TOP w0.152: U3.Y4 v2(66.9,76.93)
  L10-SIG3 w0.081: v2(66.9,76.93) 66.9,76.62 66.82,76.53 66.54,76.53 66.34,76.33 66.34,74.68 66.21,74.55 65.68,74.55 65.53,74.7 65.3,74.7 65.16,74.55 64.62,74.55 64.47,74.7 64.24,74.7 64.09,74.55 63.77,74.55 63.65,74.67 63.4,74.67 63.28,74.55 53.3,74.55 46.27,81.58 45.64,81.58 45.44,81.38 45.44,80.47 45.36,80.39 45.03,80.39 44.95,80.47 44.95,81.38 44.75,81.58 44.25,81.58 44.05,81.38 44.05,80.34 43.97,80.26 43.64,80.26 43.56,80.34 43.56,81.38 43.36,81.58 42.86,81.58 42.66,81.38 42.66,80.29 42.58,80.21 42.25,80.21 42.17,80.29 42.17,81.38 41.97,81.58 41.47,81.58 41.26,81.38 41.26,80.29 41.18,80.21 40.86,80.21 40.78,80.29 40.78,81.38 40.57,81.58 40.08,81.58 39.87,81.38 39.87,80.29 39.79,80.21 39.47,80.21 39.38,80.29 39.38,81.38 39.18,81.58 34.74,81.58 34.66,81.66 34.66,82.6 34.46,82.8 33.96,82.8 33.76,82.6 33.76,81.66 33.68,81.58 33.35,81.58 33.27,81.66 33.27,82.6 33.07,82.8 32.57,82.8 32.37,82.6 32.37,81.66 32.28,81.58 31.96,81.58 31.88,81.66 31.88,82.6 31.67,82.8 31.18,82.8 30.97,82.6 30.97,81.66 30.89,81.58 30.57,81.58 30.49,81.66 30.49,82.62 30.28,82.83 29.78,82.83 29.58,82.62 29.58,81.66 29.5,81.58 29.18,81.58 29.09,81.66 29.09,82.6 28.89,82.8 28.39,82.8 28.19,82.6 28.19,81.66 28.11,81.58 27.78,81.58 27.7,81.66 27.7,82.57 27.5,82.77 27,82.77 26.8,82.57 26.8,81.66 26.72,81.58 26.39,81.58 26.31,81.66 26.31,82.6 26.11,82.8 25.61,82.8 25.41,82.6 25.41,81.49 24.84,80.92 24.38,80.92 23.65,81.66 23.65,81.77 24.02,82.14 24.02,82.43 23.66,82.78 23.38,82.78 23.01,82.41 22.89,82.41 21.69,83.61 20.95,83.61 20.68,83.34 20.34,83.34 20.07,83.61 19.56,83.61 19.28,83.34 18.95,83.34 18.67,83.61 18.17,83.61 17.89,83.34 17.56,83.34 17.28,83.61 16.34,83.61 16.24,83.71 16.02,83.71 15.91,83.61 15.69,83.61 15.59,83.71 15.37,83.71 15.26,83.61 15.04,83.61 14.94,83.71 14.72,83.71 14.61,83.61 13.97,83.61 13.85,83.74 13.85,84.04 13.93,84.12 v2(14.38,84.12)
FMC1_LA13_P: length 90.7
  TOP w0.099: 13.74,84.76 v2(13.11,84.12)
  TOP w0.152: U3.AA4 v2(66.9,75.93)
  L10-SIG3 w0.081: v2(13.11,84.12) 13.56,84.12 13.64,84.04 13.64,83.65 13.89,83.4 17.2,83.4 17.47,83.13 17.98,83.13 18.25,83.4 18.59,83.4 18.86,83.13 19.37,83.13 19.64,83.4 19.98,83.4 20.25,83.13 20.76,83.13 21.04,83.4 21.61,83.4 22.81,82.2 23.09,82.2 23.46,82.58 23.58,82.58 23.81,82.34 23.81,82.23 23.44,81.86 23.44,81.57 24.3,80.71 24.93,80.71 25.61,81.4 25.61,82.51 25.7,82.59 26.02,82.59 26.1,82.51 26.1,81.58 26.31,81.37 26.8,81.37 27.01,81.58 27.01,82.49 27.09,82.57 27.41,82.57 27.49,82.49 27.49,81.58 27.7,81.37 28.19,81.37 28.4,81.58 28.4,82.51 28.48,82.59 28.8,82.59 28.89,82.51 28.89,81.58 29.09,81.37 29.59,81.37 29.79,81.58 29.79,82.54 29.87,82.62 30.2,82.62 30.28,82.54 30.28,81.58 30.48,81.37 30.98,81.37 31.18,81.58 31.18,82.51 31.26,82.59 31.59,82.59 31.67,82.51 31.67,81.58 31.87,81.37 32.37,81.37 32.57,81.58 32.57,82.51 32.66,82.59 32.98,82.59 33.06,82.51 33.06,81.58 33.26,81.37 33.76,81.37 33.97,81.58 33.97,82.51 34.05,82.59 34.37,82.59 34.45,82.51 34.45,81.58 34.66,81.37 39.1,81.37 39.18,81.29 39.18,80.2 39.38,80 39.88,80 40.08,80.2 40.08,81.29 40.16,81.37 40.49,81.37 40.57,81.29 40.57,80.2 40.77,80 41.27,80 41.47,80.2 41.47,81.29 41.55,81.37 41.88,81.37 41.96,81.29 41.96,80.2 42.16,80 42.66,80 42.86,80.2 42.86,81.29 42.95,81.37 43.27,81.37 43.35,81.29 43.35,80.26 43.56,80.05 44.05,80.05 44.26,80.26 44.26,81.29 44.34,81.37 44.66,81.37 44.74,81.29 44.74,80.39 44.95,80.18 45.45,80.18 45.65,80.39 45.65,81.29 45.73,81.37 46.18,81.37 53.21,74.34 66.29,74.34 66.55,74.6 66.55,76.24 66.63,76.33 66.82,76.33 66.9,76.24 v2(66.9,75.93)
FMC1_LA14_N: length 88.8
  TOP w0.099: J48.C19 v2(15.65,82.85)
  TOP w0.152: U3.AC2 v2(64.9,73.93)
  L10-SIG3 w0.081: v2(15.65,82.85) 15.2,82.85 15.12,82.77 15.12,82.47 15.24,82.34 15.81,82.34 15.91,82.44 16.13,82.44 16.23,82.34 16.46,82.34 16.56,82.44 16.78,82.44 16.88,82.34 17.11,82.34 17.21,82.44 17.43,82.44 17.53,82.34 18.95,82.34 19.17,82.12 19.56,82.12 19.78,82.34 20.34,82.34 20.56,82.12 20.95,82.12 21.17,82.34 21.84,82.34 24.77,79.42 25.47,79.42 25.63,79.58 25.63,80.51 25.84,80.72 26.34,80.72 26.54,80.51 26.54,79.5 26.62,79.42 26.95,79.42 27.03,79.5 27.03,80.54 27.23,80.74 27.73,80.74 27.93,80.54 27.93,79.58 28.01,79.5 28.34,79.5 28.42,79.58 28.42,80.54 28.62,80.74 29.12,80.74 29.32,80.54 29.32,79.58 29.4,79.5 29.73,79.5 29.81,79.58 29.81,80.51 30.01,80.72 30.51,80.72 30.71,80.51 30.71,79.58 30.8,79.5 31.12,79.5 31.2,79.58 31.2,80.51 31.41,80.72 31.9,80.72 32.11,80.51 32.11,79.58 32.19,79.5 32.51,79.5 32.59,79.58 32.59,80.49 32.8,80.69 33.3,80.69 33.5,80.49 33.5,79.58 33.58,79.5 33.9,79.5 33.99,79.58 33.99,80.46 34.19,80.67 34.69,80.67 34.89,80.46 34.89,79.58 34.97,79.5 35.3,79.5 35.38,79.58 35.38,80.46 35.58,80.67 36.08,80.67 36.28,80.46 36.28,79.58 36.36,79.5 36.69,79.5 36.77,79.58 36.77,80.46 36.97,80.67 37.47,80.67 37.67,80.46 37.67,79.58 37.76,79.5 38.53,79.5 38.73,79.3 38.73,78.44 38.82,78.36 39.14,78.36 39.22,78.44 39.22,79.3 39.43,79.5 39.92,79.5 40.13,79.3 40.13,78.44 40.21,78.36 40.53,78.36 40.61,78.44 40.61,79.3 40.82,79.5 41.32,79.5 41.52,79.3 41.52,78.44 41.6,78.36 41.92,78.36 42.01,78.44 42.01,79.3 42.21,79.5 42.71,79.5 42.91,79.3 42.91,78.44 42.99,78.36 43.32,78.36 43.4,78.44 43.4,79.3 43.6,79.5 44.1,79.5 44.3,79.3 44.3,78.44 44.38,78.36 44.71,78.36 44.79,78.44 44.79,79.3 44.99,79.5 45.49,79.5 45.69,79.3 45.69,78.44 45.78,78.36 46.1,78.36 46.18,78.44 46.18,79.3 46.38,79.5 47.26,79.5 53.25,73.5 61.19,73.5 61.29,73.61 61.54,73.61 61.65,73.5 62.62,73.5 62.72,73.61 62.97,73.61 63.07,73.5 63.27,73.5 63.39,73.63 63.59,73.63 63.72,73.5 64.16,73.5 64.31,73.66 64.52,73.66 64.67,73.5 65.21,73.5 65.42,73.71 65.42,73.85 65.34,73.93 v2(64.9,73.93)
FMC1_LA14_P: length 88.5
  TOP w0.099: J48.C18 v2(14.38,82.85)
  TOP w0.152: U3.AC3 v2(65.9,73.93)
  L10-SIG3 w0.081: v2(65.9,73.93) 65.9,73.89 65.3,73.3 53.17,73.3 47.17,79.29 46.47,79.29 46.39,79.21 46.39,78.36 46.19,78.15 45.69,78.15 45.49,78.36 45.49,79.21 45.4,79.29 45.08,79.29 45,79.21 45,78.36 44.79,78.15 44.3,78.15 44.09,78.36 44.09,79.21 44.01,79.29 43.69,79.29 43.61,79.21 43.61,78.36 43.4,78.15 42.91,78.15 42.7,78.36 42.7,79.21 42.62,79.29 42.3,79.29 42.21,79.21 42.21,78.36 42.01,78.15 41.51,78.15 41.31,78.36 41.31,79.21 41.23,79.29 40.9,79.29 40.82,79.21 40.82,78.36 40.62,78.15 40.12,78.15 39.92,78.36 39.92,79.21 39.84,79.29 39.51,79.29 39.43,79.21 39.43,78.36 39.23,78.15 38.73,78.15 38.53,78.36 38.53,79.21 38.44,79.29 37.67,79.29 37.47,79.5 37.47,80.38 37.38,80.46 37.06,80.46 36.98,80.38 36.98,79.5 36.78,79.29 36.28,79.29 36.07,79.5 36.07,80.38 35.99,80.46 35.67,80.46 35.59,80.38 35.59,79.5 35.38,79.29 34.89,79.29 34.68,79.5 34.68,80.38 34.6,80.46 34.28,80.46 34.19,80.38 34.19,79.5 33.99,79.29 33.49,79.29 33.29,79.5 33.29,80.4 33.21,80.48 32.88,80.48 32.8,80.4 32.8,79.5 32.6,79.29 32.1,79.29 31.9,79.5 31.9,80.43 31.82,80.51 31.49,80.51 31.41,80.43 31.41,79.5 31.21,79.29 30.71,79.29 30.51,79.5 30.51,80.43 30.43,80.51 30.1,80.51 30.02,80.43 30.02,79.5 29.82,79.29 29.32,79.29 29.11,79.5 29.11,80.45 29.03,80.53 28.71,80.53 28.63,80.45 28.63,79.5 28.42,79.29 27.93,79.29 27.72,79.5 27.72,80.45 27.64,80.53 27.32,80.53 27.23,80.45 27.23,79.42 27.03,79.21 26.53,79.21 26.33,79.42 26.33,80.43 26.25,80.51 25.92,80.51 25.84,80.43 25.84,79.5 25.56,79.21 24.68,79.21 21.76,82.13 21.26,82.13 21.03,81.91 20.48,81.91 20.25,82.13 19.87,82.13 19.64,81.91 19.08,81.91 18.86,82.13 15.16,82.13 14.91,82.38 14.91,82.77 14.83,82.85 v2(14.38,82.85)
FMC1_LA15_N: length 94.5
  TOP w0.124: J48.H20 v2(8.03,81.58) ; U3.AC6 v2(68.9,73.93)
  L10-SIG3 w0.081: v2(8.03,81.58) 8.03,82.03 7.95,82.11 7.71,82.11 7.57,81.98 7.57,80.59 7.35,80.37 7.35,79.98 7.57,79.76 7.57,79.2 7.35,78.97 7.35,78.59 7.57,78.36 7.57,77.81 7.35,77.58 7.35,77.2 7.57,76.97 7.57,76.07 7.66,75.99 8.42,75.99 8.5,76.07 8.5,78.35 8.72,78.56 9.78,78.56 9.98,78.36 9.98,76.07 10.06,75.99 10.67,75.99 10.87,76.2 11.4,76.2 11.61,75.99 12.06,75.99 12.24,76.17 12.78,76.17 12.95,75.99 14.33,75.99 14.54,75.79 14.54,75.55 14.62,75.46 14.94,75.46 15.03,75.55 15.03,76.25 15.23,76.45 16.25,76.45 16.45,76.25 16.45,75.6 16.53,75.52 16.85,75.52 16.94,75.6 16.94,75.79 17.14,75.99 18.85,75.99 22.91,71.93 32.88,71.93 33.08,71.73 33.49,71.73 33.69,71.93 34.27,71.93 34.47,71.73 34.88,71.73 35.08,71.93 35.87,71.93 36.08,71.73 36.08,71.08 36.16,70.99 36.48,70.99 36.57,71.08 36.57,71.98 36.77,72.18 37.27,72.18 37.47,71.98 37.47,71.08 37.55,70.99 37.88,70.99 37.96,71.08 37.96,71.98 38.16,72.18 38.66,72.18 38.86,71.98 38.86,71.08 38.94,70.99 39.27,70.99 39.35,71.08 39.35,71.98 39.55,72.18 40.05,72.18 40.25,71.98 40.25,71.08 40.33,70.99 50.12,70.99 52.59,68.53 65.13,68.53 65.25,68.65 65.56,68.65 65.68,68.53 66.15,68.53 66.27,68.65 66.57,68.65 66.7,68.53 67.11,68.53 67.28,68.7 67.54,68.7 67.71,68.53 68.13,68.53 68.3,68.7 68.55,68.7 68.73,68.53 69.08,68.53 69.29,68.75 69.29,69.21 69.16,69.34 69.16,69.57 69.29,69.7 69.29,70.2 69.19,70.3 69.19,70.58 69.29,70.69 69.29,71.21 69.16,71.34 69.16,71.55 69.29,71.68 69.29,73.85 69.21,73.93 v2(68.9,73.93)
FMC1_LA15_P: length 94.8
  TOP w0.124: U3.AC7 v2(69.9,73.93) ; J48.H19 v2(8.03,82.85)
  L10-SIG3 w0.081: v2(69.9,73.93) 69.58,73.93 69.5,73.85 69.5,68.66 69.16,68.32 52.5,68.32 50.04,70.79 40.25,70.79 40.05,70.99 40.05,71.89 39.96,71.97 39.64,71.97 39.56,71.89 39.56,70.99 39.35,70.79 38.86,70.79 38.65,70.99 38.65,71.89 38.57,71.97 38.25,71.97 38.17,71.89 38.17,70.99 37.96,70.79 37.46,70.79 37.26,70.99 37.26,71.89 37.18,71.97 36.85,71.97 36.77,71.89 36.77,70.99 36.57,70.79 36.07,70.79 35.87,70.99 35.87,71.64 35.79,71.72 35.17,71.72 34.97,71.52 34.38,71.52 34.18,71.72 33.78,71.72 33.58,71.52 32.99,71.52 32.79,71.72 22.82,71.72 18.76,75.78 17.23,75.78 17.14,75.7 17.14,75.51 16.94,75.31 16.44,75.31 16.24,75.51 16.24,76.16 16.16,76.24 15.32,76.24 15.23,76.16 15.23,75.46 15.03,75.26 14.53,75.26 14.33,75.46 14.33,75.7 14.25,75.78 12.87,75.78 12.69,75.96 12.33,75.96 12.15,75.78 11.52,75.78 11.32,75.99 10.96,75.99 10.75,75.78 9.98,75.78 9.77,75.99 9.77,78.27 9.69,78.36 8.81,78.36 8.71,78.26 8.71,75.99 8.51,75.78 7.57,75.78 7.37,75.99 7.37,76.89 7.14,77.11 7.14,77.67 7.37,77.9 7.37,78.28 7.14,78.51 7.14,79.06 7.37,79.29 7.37,79.67 7.14,79.9 7.14,80.45 7.37,80.68 7.37,82.07 7.62,82.32 7.95,82.32 8.03,82.4 v2(8.03,82.85)
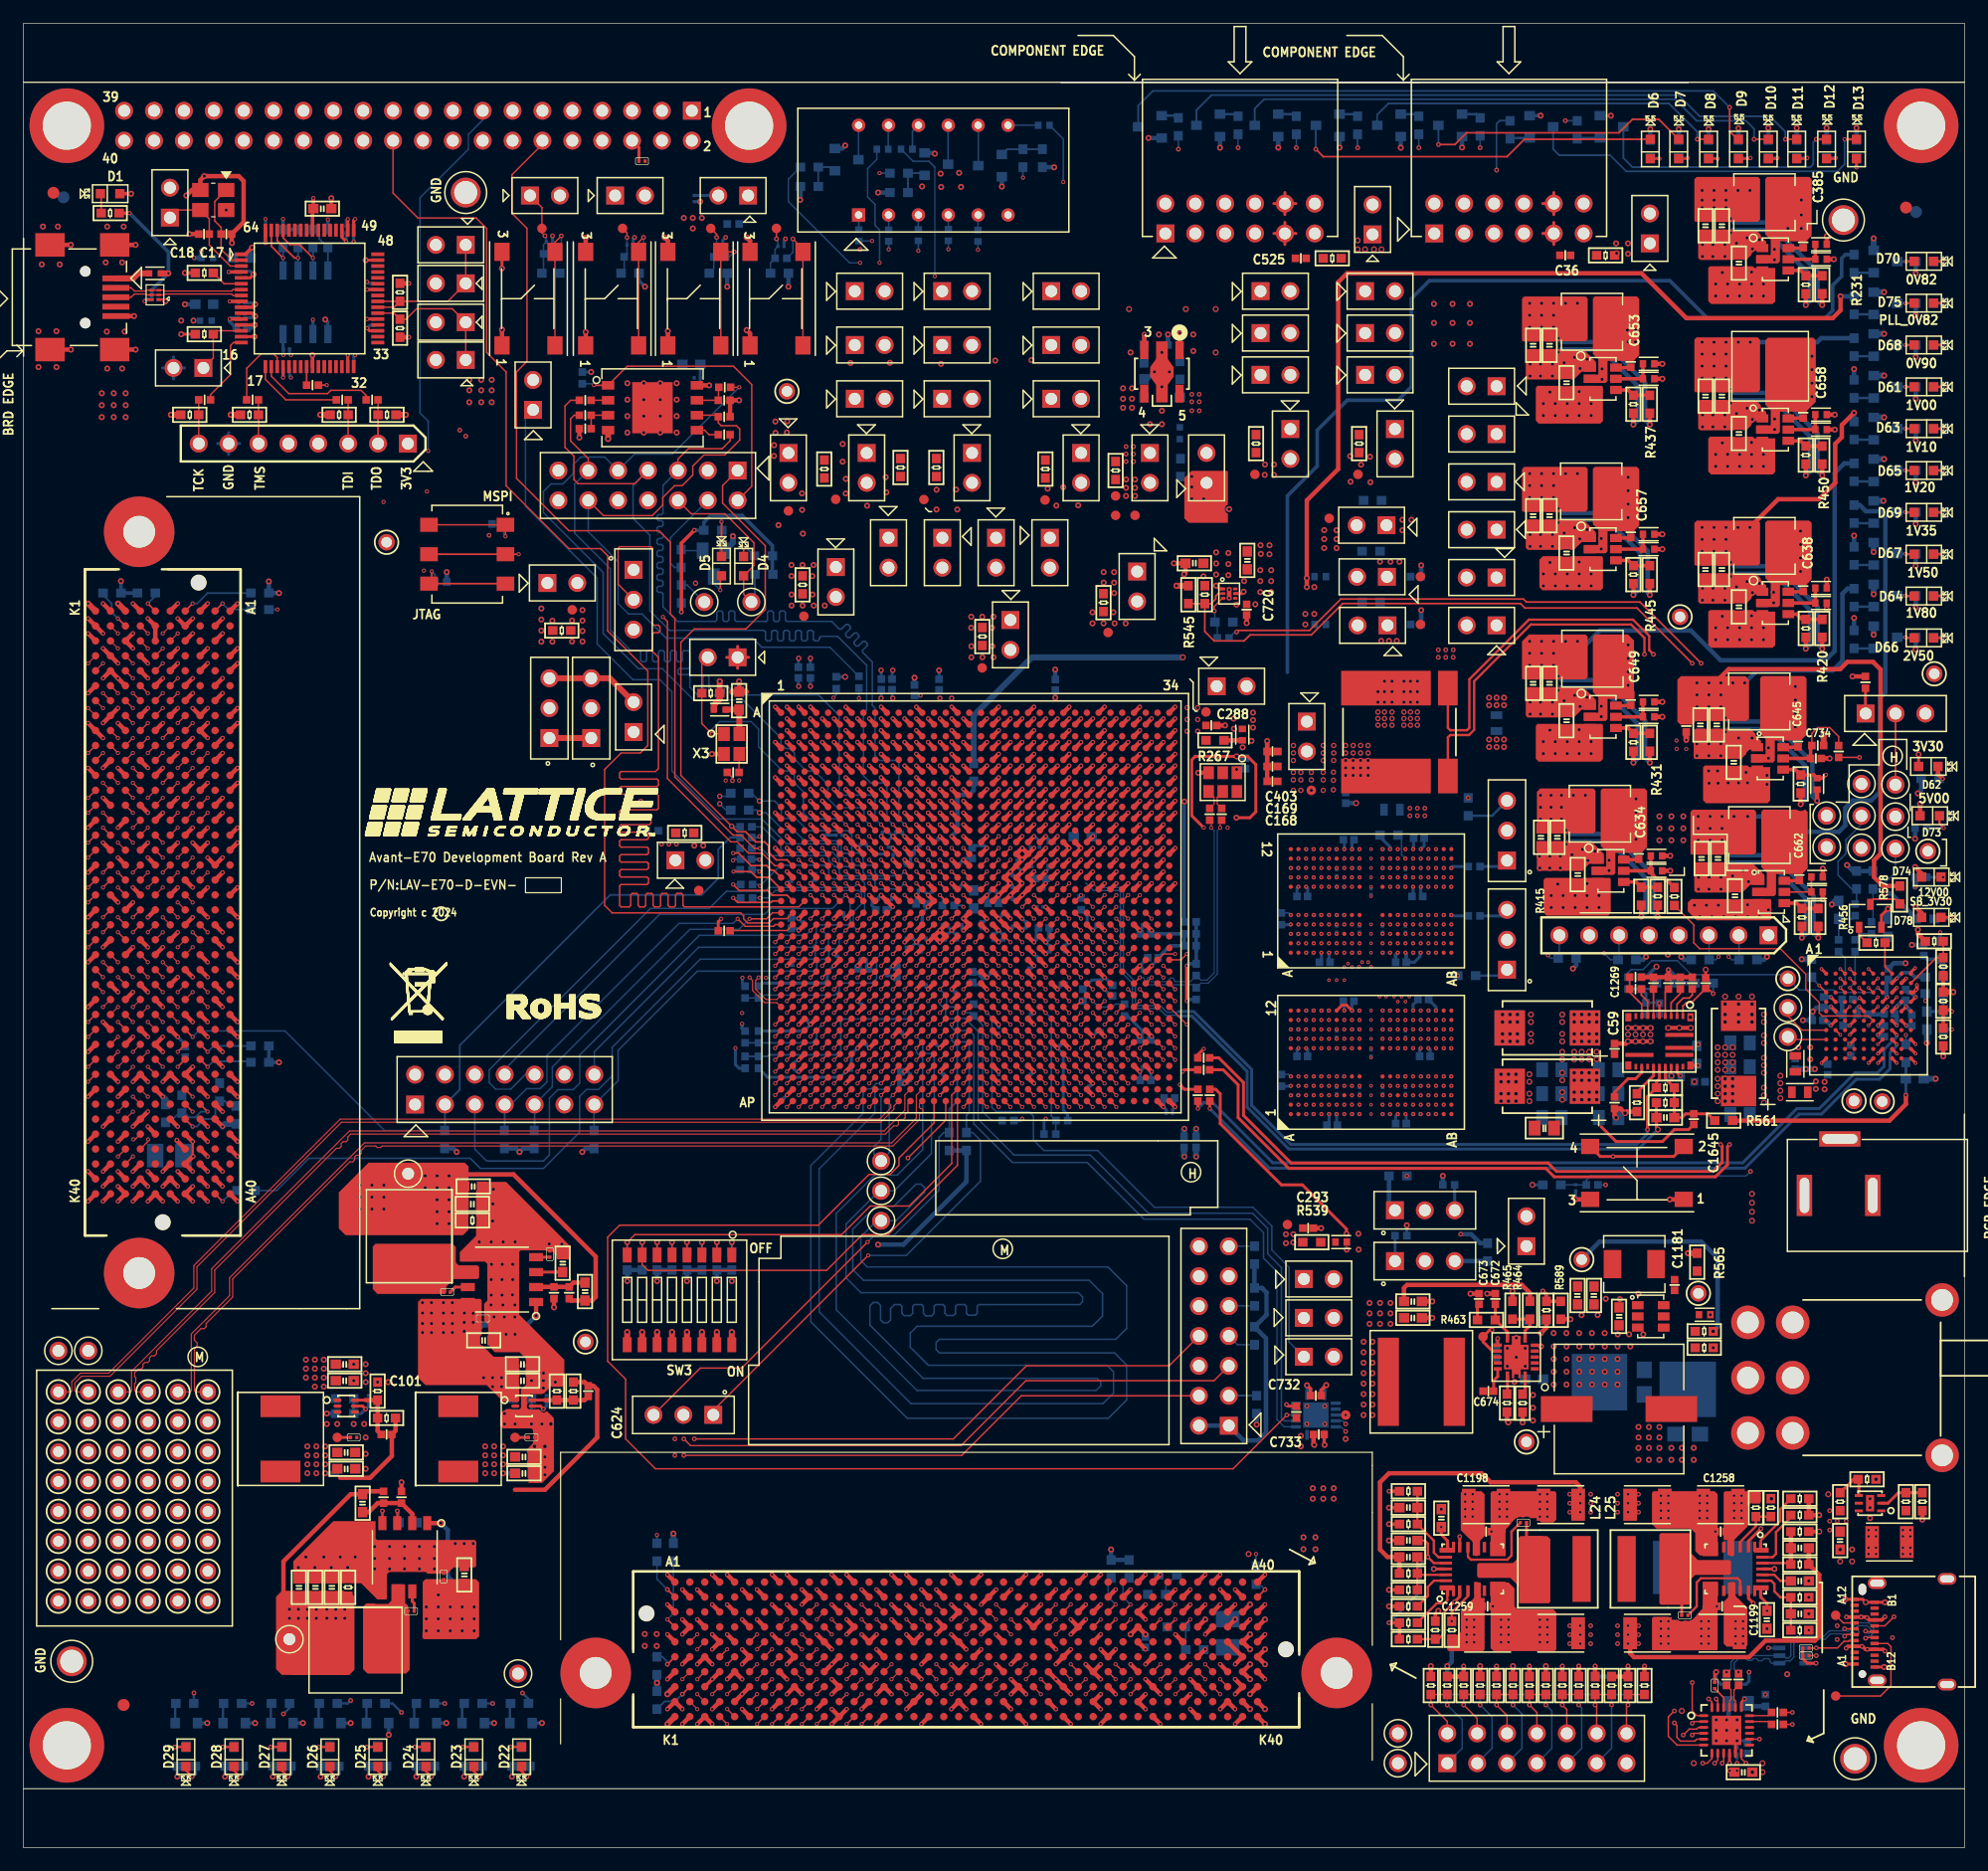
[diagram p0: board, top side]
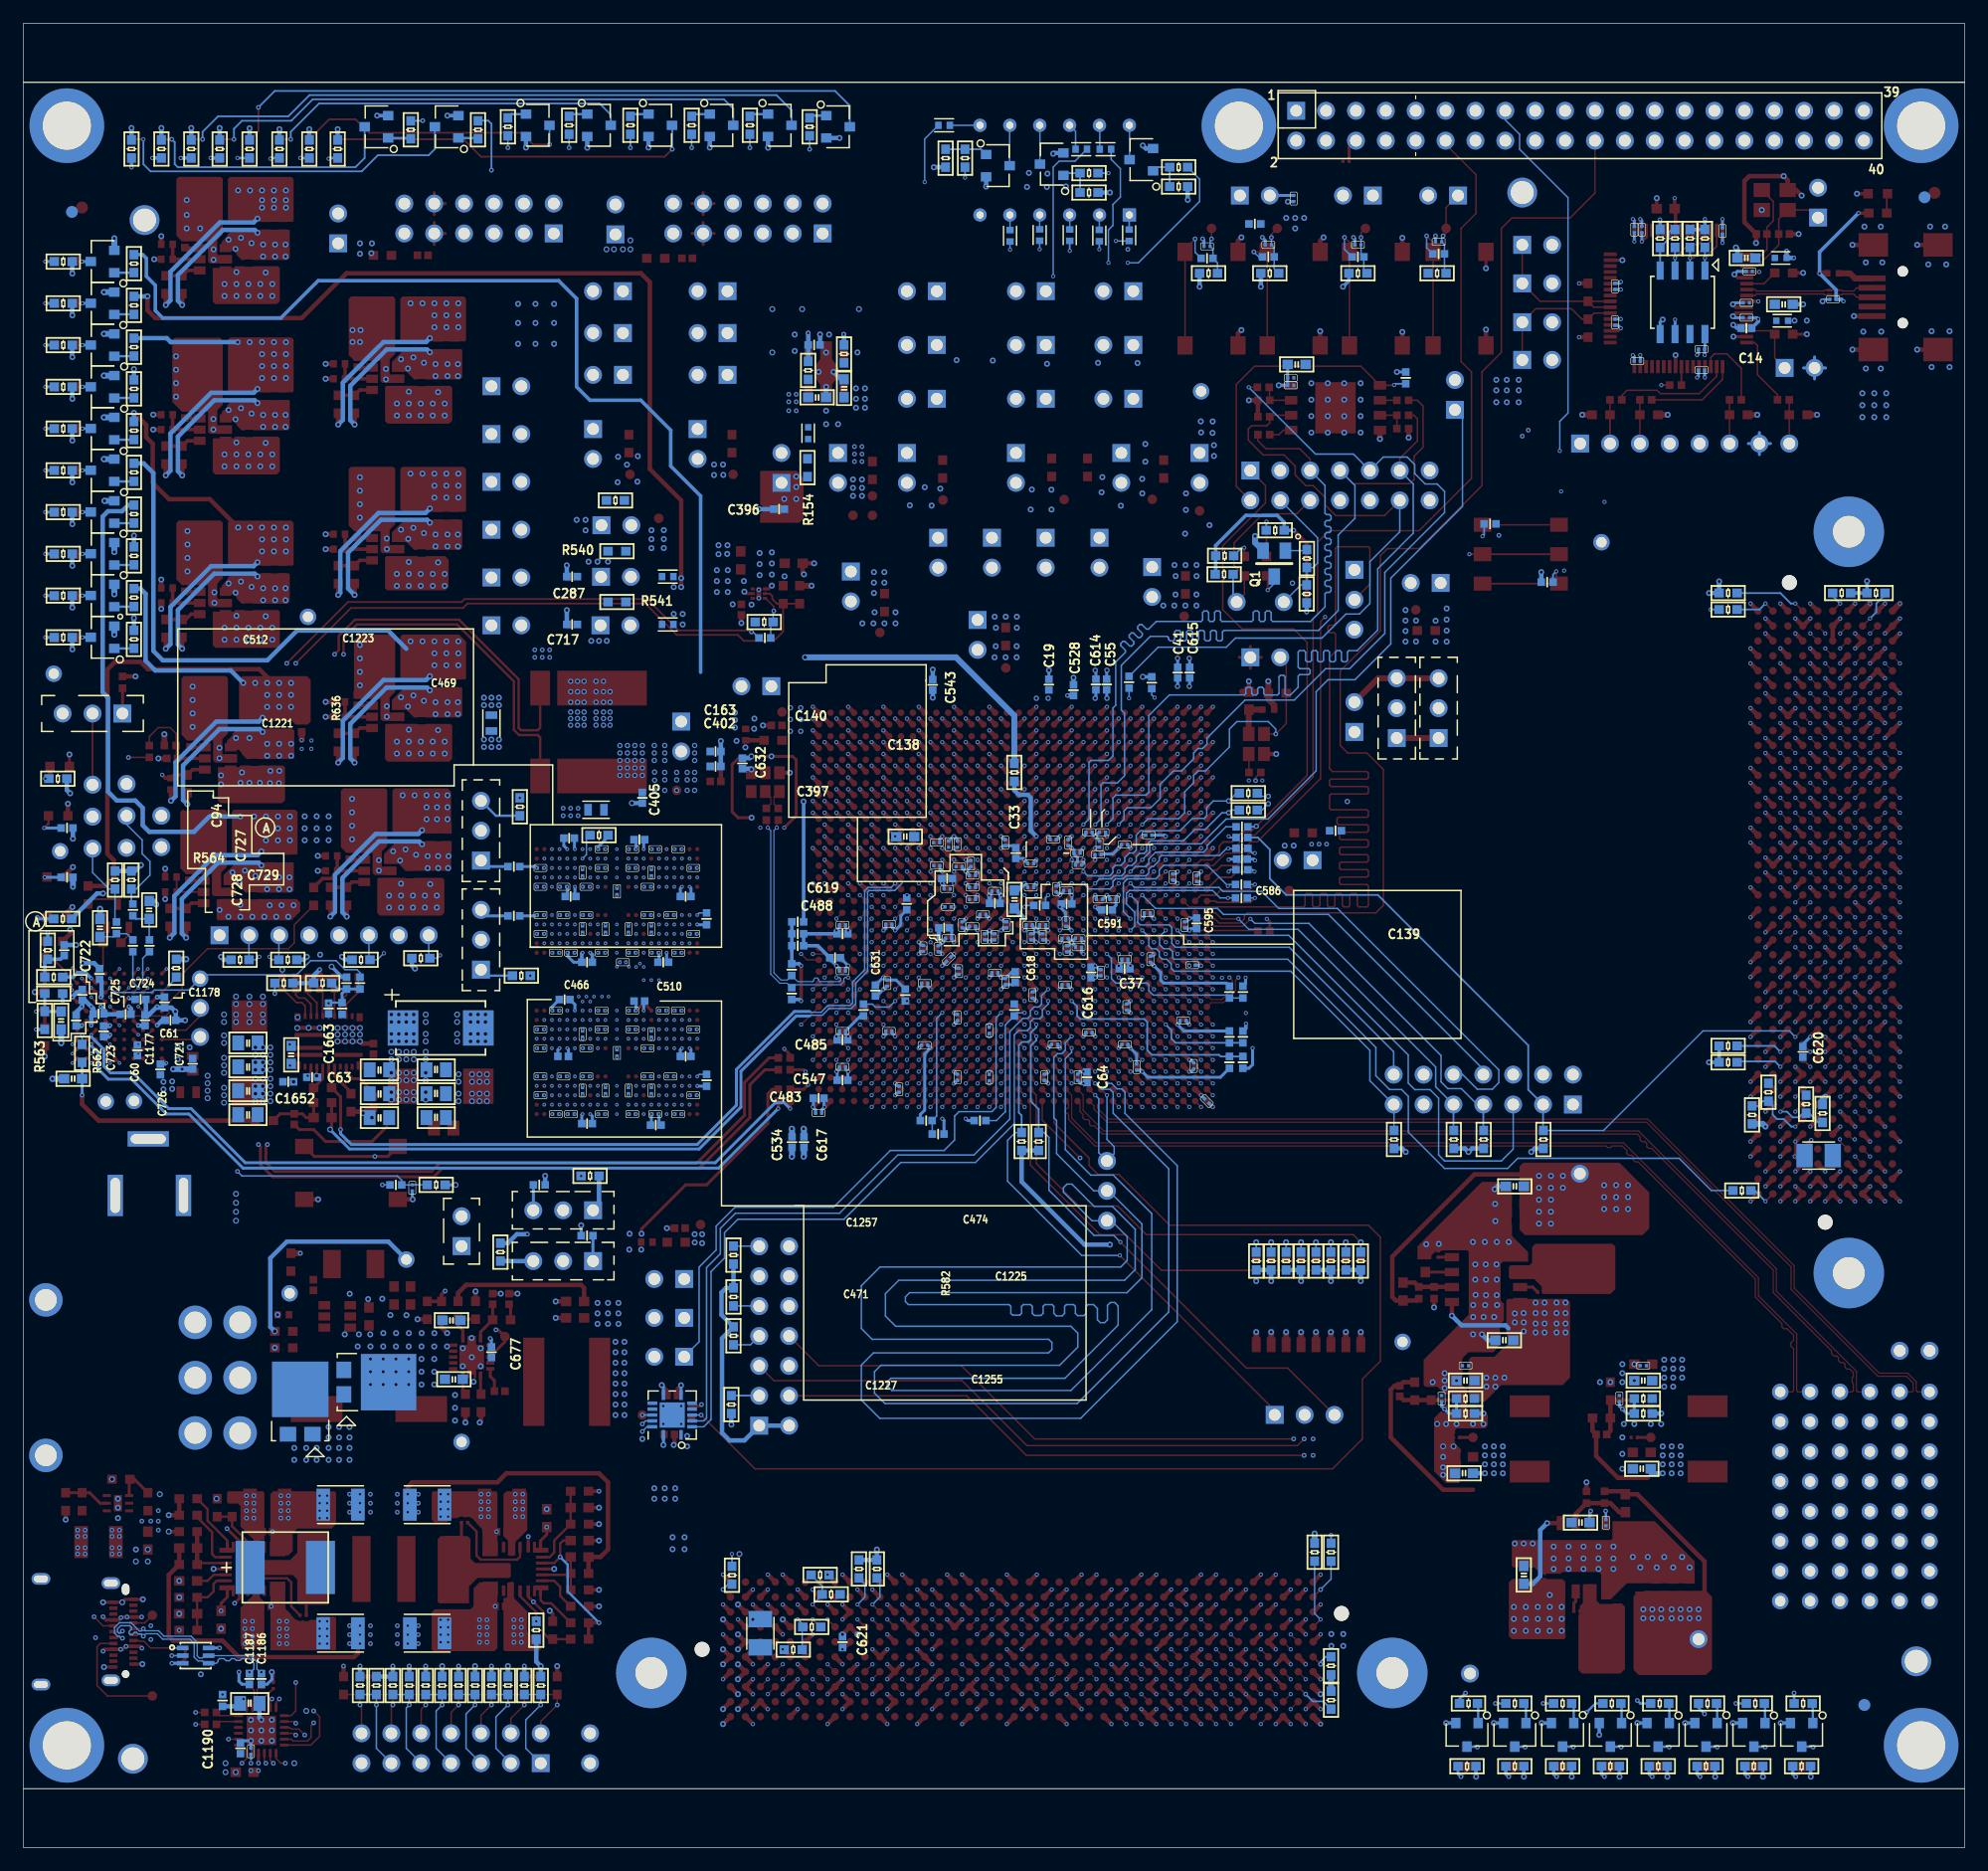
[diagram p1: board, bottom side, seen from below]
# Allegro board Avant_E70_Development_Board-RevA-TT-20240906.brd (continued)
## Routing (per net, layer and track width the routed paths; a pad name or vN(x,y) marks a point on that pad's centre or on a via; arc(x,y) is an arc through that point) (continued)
FMC1_LA16_N: length 87
  TOP w0.099: J48.G19 v2(10.57,82.85)
  TOP w0.152: U3.AD1 v2(63.9,72.93)
  L10-SIG3 w0.081: v2(10.57,82.85) 10.12,82.85 10.04,82.77 10.04,82.47 10.13,82.37 10.13,82.14 10.04,82.05 10.04,81.32 10.29,81.07 10.73,81.07 10.83,81.17 11.05,81.17 11.15,81.07 21.76,81.07 25.31,77.52 26.84,77.52 26.93,77.6 26.93,78.33 27.13,78.53 27.63,78.53 27.83,78.33 27.83,77.6 27.91,77.52 28.24,77.52 28.32,77.6 28.32,78.33 28.52,78.53 29.02,78.53 29.22,78.33 29.22,77.6 29.3,77.52 29.63,77.52 29.71,77.6 29.71,78.41 29.91,78.61 30.41,78.61 30.61,78.41 30.61,77.6 30.69,77.52 31.02,77.52 31.1,77.6 31.1,78.43 31.3,78.63 31.8,78.63 32.01,78.43 32.01,77.6 32.09,77.52 32.41,77.52 32.49,77.6 32.49,78.46 32.7,78.66 33.19,78.66 33.4,78.46 33.4,77.6 33.48,77.52 33.8,77.52 33.88,77.6 33.88,78.46 34.09,78.66 34.59,78.66 34.79,78.46 34.79,77.6 34.87,77.52 35.2,77.52 35.28,77.6 35.28,78.46 35.48,78.66 35.98,78.66 36.18,78.46 36.18,77.6 36.26,77.52 36.59,77.52 36.67,77.6 36.67,78.46 36.87,78.66 37.37,78.66 37.57,78.46 37.57,77.6 37.65,77.52 39.62,77.52 39.82,77.31 39.82,76.66 39.9,76.58 40.23,76.58 40.31,76.66 40.31,77.31 40.51,77.52 41.01,77.52 41.21,77.31 41.21,76.66 41.3,76.58 41.62,76.58 41.7,76.66 41.7,77.31 41.9,77.52 42.4,77.52 42.61,77.31 42.61,76.66 42.69,76.58 43.01,76.58 43.09,76.66 43.09,77.31 43.3,77.52 43.79,77.52 44,77.31 44,76.66 44.08,76.58 44.4,76.58 44.49,76.66 44.49,77.31 44.69,77.52 45.19,77.52 45.39,77.31 45.39,76.66 45.47,76.58 45.8,76.58 45.88,76.66 45.88,77.31 46.08,77.52 46.58,77.52 46.78,77.31 46.78,76.66 46.86,76.58 47.19,76.58 47.27,76.66 47.27,77.31 47.47,77.52 48.13,77.52 53.13,72.52 61.32,72.52 61.39,72.59 61.6,72.59 61.67,72.52 61.92,72.52 62.04,72.64 62.25,72.64 62.37,72.52 62.57,72.52 62.69,72.64 62.9,72.64 63.02,72.52 63.22,72.52 63.34,72.64 63.55,72.64 63.67,72.52 64.19,72.52 64.36,72.69 64.36,72.85 64.28,72.93 v2(63.9,72.93)
FMC1_LA16_P: length 86.9
  TOP w0.099: J48.G18 v2(9.3,82.85)
  TOP w0.152: U3.AD2 v2(64.9,72.93)
  L10-SIG3 w0.081: v2(9.3,82.85) 9.75,82.85 9.83,82.77 9.83,81.24 10.2,80.86 21.67,80.86 25.23,77.31 26.93,77.31 27.13,77.51 27.13,78.24 27.21,78.32 27.54,78.32 27.62,78.24 27.62,77.51 27.82,77.31 28.32,77.31 28.53,77.51 28.53,78.24 28.61,78.32 28.93,78.32 29.01,78.24 29.01,77.51 29.22,77.31 29.71,77.31 29.92,77.51 29.92,78.32 30,78.4 30.32,78.4 30.41,78.32 30.41,77.51 30.61,77.31 31.11,77.31 31.31,77.51 31.31,78.35 31.39,78.43 31.72,78.43 31.8,78.35 31.8,77.51 32,77.31 32.5,77.31 32.7,77.51 32.7,78.37 32.78,78.45 33.11,78.45 33.19,78.37 33.19,77.51 33.39,77.31 33.89,77.31 34.09,77.51 34.09,78.37 34.17,78.45 34.5,78.45 34.58,78.37 34.58,77.51 34.78,77.31 35.28,77.31 35.49,77.51 35.49,78.37 35.57,78.45 35.89,78.45 35.97,78.37 35.97,77.51 36.18,77.31 36.67,77.31 36.88,77.51 36.88,78.37 36.96,78.45 37.28,78.45 37.36,78.37 37.36,77.51 37.57,77.31 39.53,77.31 39.61,77.23 39.61,76.58 39.82,76.37 40.31,76.37 40.52,76.58 40.52,77.23 40.6,77.31 40.92,77.31 41.01,77.23 41.01,76.58 41.21,76.37 41.71,76.37 41.91,76.58 41.91,77.23 41.99,77.31 42.32,77.31 42.4,77.23 42.4,76.58 42.6,76.37 43.1,76.37 43.3,76.58 43.3,77.23 43.38,77.31 43.71,77.31 43.79,77.23 43.79,76.58 43.99,76.37 44.49,76.37 44.69,76.58 44.69,77.23 44.77,77.31 45.1,77.31 45.18,77.23 45.18,76.58 45.38,76.37 45.88,76.37 46.09,76.58 46.09,77.23 46.17,77.31 46.49,77.31 46.57,77.23 46.57,76.58 46.78,76.37 47.27,76.37 47.48,76.58 47.48,77.23 47.56,77.31 48.05,77.31 53.05,72.31 64.28,72.31 v2(64.9,72.93)
FMC1_LA17_CLK_N: length 80.3
  TOP w0.099: J48.D21 v2(13.11,80.31)
  TOP w0.124: U3.AP3 v2(65.9,62.93)
  L12-SIG4 w0.081: v2(13.11,80.31) 13.61,80.31 13.69,80.39 13.69,80.78 13.94,81.03 33.36,81.03 34.19,80.2 34.31,80.2 34.72,80.61 35.01,80.61 35.36,80.26 35.36,79.97 34.95,79.56 34.95,79.44 35.18,79.21 35.29,79.21 35.71,79.62 35.99,79.62 36.35,79.27 36.35,78.98 35.93,78.57 35.93,78.46 36.16,78.23 36.28,78.23 36.89,78.84 37.18,78.84 37.53,78.49 37.53,78.2 36.92,77.59 36.92,77.47 37.15,77.24 37.26,77.24 37.89,77.87 38.18,77.87 38.53,77.52 38.53,77.23 37.9,76.6 37.9,76.49 38.13,76.26 38.25,76.26 38.81,76.82 39.1,76.82 39.45,76.47 39.45,76.18 38.89,75.62 38.89,75.5 39.71,74.68 47.16,74.68 48.31,73.53 67.23,73.53 67.49,73.28 67.49,65.59 67.19,65.29 66.81,65.29 66.5,64.98 66.5,64.73 66.13,64.35 65.86,64.35 65.5,64 65.5,63.01 65.58,62.93 v2(65.9,62.93)
FMC1_LA17_CLK_P: length 80.2
  TOP w0.099: J48.D20 v2(14.38,80.31)
  TOP w0.124: U3.AP2 v2(64.9,62.93)
  L12-SIG4 w0.081: v2(14.38,80.31) 13.98,80.31 13.9,80.39 13.9,80.69 14.02,80.82 33.27,80.82 34.11,79.99 34.39,79.99 34.81,80.4 34.92,80.4 35.15,80.17 35.15,80.06 34.74,79.64 34.74,79.35 35.09,79 35.38,79 35.79,79.42 35.91,79.42 36.14,79.19 36.14,79.07 35.72,78.66 35.72,78.37 36.08,78.02 36.36,78.02 36.98,78.63 37.09,78.63 37.33,78.4 37.33,78.29 36.71,77.67 36.71,77.38 37.06,77.03 37.35,77.03 37.98,77.66 38.09,77.66 38.32,77.43 38.32,77.32 37.69,76.69 37.69,76.4 38.05,76.05 38.33,76.05 38.9,76.61 39.01,76.61 39.24,76.38 39.24,76.27 38.68,75.7 38.68,75.41 39.62,74.47 47.08,74.47 48.22,73.33 64.13,73.33 64.29,73.17 64.52,73.17 64.67,73.33 65.13,73.33 65.28,73.17 65.48,73.17 65.63,73.33 66.17,73.33 66.32,73.17 66.52,73.17 66.67,73.33 67.15,73.33 67.28,73.19 67.28,72.69 67.16,72.56 67.16,72.36 67.28,72.23 67.28,70.65 67.16,70.53 67.16,70.3 67.28,70.18 67.28,66.64 67.16,66.52 67.16,66.31 67.28,66.19 67.28,65.68 67.11,65.5 66.73,65.5 66.29,65.07 66.29,64.82 66.04,64.56 65.77,64.56 65.29,64.09 65.29,63.01 65.21,62.93 v2(64.9,62.93)
FMC1_LA18_CLK_N: length 84.6
  TOP w0.124: U3.AJ1 v2(63.9,67.93) ; J48.C23 v2(14.38,77.77)
  L12-SIG4 w0.081: v2(63.9,67.93) 63.9,68.24 63.82,68.33 53.22,68.33 52.36,69.18 32.97,69.18 32.77,69.38 32.77,70.34 32.69,70.43 32.36,70.43 32.28,70.34 32.28,69.38 32.08,69.18 31.58,69.18 31.38,69.38 31.38,70.47 31.3,70.55 30.97,70.55 30.89,70.47 30.89,69.38 30.69,69.18 30.19,69.18 29.98,69.38 29.98,70.5 29.9,70.58 29.58,70.58 29.5,70.5 29.5,69.38 29.29,69.18 28.8,69.18 28.59,69.38 28.59,70.5 28.51,70.58 28.19,70.58 28.11,70.5 28.11,69.38 27.9,69.18 27.4,69.18 27.2,69.38 27.2,70.5 27.12,70.58 26.79,70.58 26.71,70.5 26.71,69.38 26.51,69.18 26.01,69.18 25.81,69.38 25.81,70.5 25.73,70.58 25.4,70.58 25.32,70.5 25.32,69.38 25.12,69.18 24.62,69.18 24.42,69.38 24.42,70.5 24.34,70.58 24.01,70.58 23.93,70.5 23.93,69.38 23.73,69.18 23.03,69.18 19.01,73.2 10.12,73.2 9.82,73.49 9.82,76.93 10.16,77.26 14.76,77.26 14.88,77.38 14.88,77.69 14.8,77.77 v2(14.38,77.77)
FMC1_LA18_CLK_P: length 84.3
  TOP w0.124: J48.C22 v2(15.65,77.77)
  TOP w0.152: U3.AH1 v2(63.9,68.93)
  L12-SIG4 w0.081: v2(15.65,77.77) 15.17,77.77 15.09,77.69 15.09,77.29 14.85,77.05 10.25,77.05 10.03,76.84 10.03,73.58 10.21,73.41 19.1,73.41 23.11,69.39 23.64,69.39 23.72,69.47 23.72,70.58 23.92,70.79 24.42,70.79 24.63,70.58 24.63,69.47 24.71,69.39 25.03,69.39 25.11,69.47 25.11,70.58 25.32,70.79 25.81,70.79 26.02,70.58 26.02,69.47 26.1,69.39 26.42,69.39 26.51,69.47 26.51,70.58 26.71,70.79 27.21,70.79 27.41,70.58 27.41,69.47 27.49,69.39 27.82,69.39 27.9,69.47 27.9,70.58 28.1,70.79 28.6,70.79 28.8,70.58 28.8,69.47 28.88,69.39 29.21,69.39 29.29,69.47 29.29,70.58 29.49,70.79 29.99,70.79 30.19,70.58 30.19,69.47 30.27,69.39 30.6,69.39 30.68,69.47 30.68,70.56 30.88,70.76 31.38,70.76 31.59,70.56 31.59,69.47 31.67,69.39 31.99,69.39 32.07,69.47 32.07,70.43 32.28,70.63 32.77,70.63 32.98,70.43 32.98,69.47 33.06,69.39 52.45,69.39 53.31,68.53 63.82,68.53 63.9,68.62 v2(63.9,68.93)
FMC1_LA19_N: length 87.5
  TOP w0.124: J48.H23 v2(8.03,77.77)
  TOP w0.152: U3.AF4 v2(66.9,70.93)
  L12-SIG4 w0.081: v2(66.9,70.93) 66.9,71.24 66.82,71.33 66.54,71.33 66.34,71.53 66.34,72.22 66.21,72.36 63.41,72.36 63.16,72.61 47.09,72.61 46.88,72.81 46.88,73.16 46.8,73.24 46.48,73.24 46.39,73.16 46.39,72.81 46.19,72.61 45.69,72.61 45.49,72.81 45.49,73.57 45.41,73.65 45.08,73.65 45,73.57 45,72.81 44.8,72.61 44.3,72.61 44.1,72.81 44.1,73.57 44.02,73.65 43.69,73.65 43.61,73.57 43.61,72.81 43.41,72.61 42.91,72.61 42.71,72.81 42.71,73.57 42.63,73.65 42.3,73.65 42.22,73.57 42.22,72.81 42.02,72.61 41.52,72.61 41.31,72.81 41.31,73.6 41.23,73.68 40.91,73.68 40.83,73.6 40.83,72.81 40.62,72.61 40.13,72.61 39.92,72.81 39.92,73.6 39.84,73.68 39.52,73.68 39.43,73.6 39.43,72.81 39.23,72.61 38.18,72.61 37.23,73.56 37.23,73.85 38.05,74.67 38.05,74.79 37.82,75.02 37.7,75.02 36.88,74.2 36.6,74.2 36.24,74.55 36.24,74.84 37.01,75.6 37.01,75.72 36.78,75.95 36.67,75.95 35.9,75.18 35.61,75.18 35.26,75.53 35.26,75.82 36.07,76.63 36.07,76.74 35.83,76.97 35.72,76.97 34.91,76.17 34.63,76.17 34.27,76.52 34.27,76.81 34.94,77.47 34.94,77.59 34.71,77.82 34.6,77.82 33.93,77.15 33.64,77.15 33.29,77.5 33.29,77.79 33.96,78.46 33.96,78.57 33.72,78.8 33.61,78.8 32.94,78.14 32.66,78.14 31.37,79.42 8.89,79.42 8.72,79.25 8.72,78.51 8.51,78.3 8.11,78.3 8.03,78.22 v2(8.03,77.77)
FMC1_LA19_P: length 87.5
  TOP w0.124: J48.H22 v2(8.03,79.04)
  TOP w0.152: U3.AE4 v2(66.9,71.93)
  L12-SIG4 w0.081: v2(66.9,71.93) 66.9,71.62 66.82,71.53 66.63,71.53 66.55,71.62 66.55,72.31 66.29,72.56 63.5,72.56 63.25,72.82 47.17,72.82 47.09,72.9 47.09,73.25 46.89,73.45 46.39,73.45 46.19,73.25 46.19,72.9 46.1,72.82 45.78,72.82 45.7,72.9 45.7,73.66 45.5,73.86 45,73.86 44.79,73.66 44.79,72.9 44.71,72.82 44.39,72.82 44.31,72.9 44.31,73.66 44.1,73.86 43.61,73.86 43.4,73.66 43.4,72.9 43.32,72.82 43,72.82 42.91,72.9 42.91,73.66 42.71,73.86 42.21,73.86 42.01,73.66 42.01,72.9 41.93,72.82 41.6,72.82 41.52,72.9 41.52,73.68 41.32,73.88 40.82,73.88 40.62,73.68 40.62,72.9 40.54,72.82 40.21,72.82 40.13,72.9 40.13,73.68 39.93,73.88 39.43,73.88 39.23,73.68 39.23,72.9 39.15,72.82 38.27,72.82 37.44,73.65 37.44,73.76 38.26,74.58 38.26,74.87 37.9,75.22 37.62,75.22 36.8,74.4 36.68,74.4 36.45,74.63 36.45,74.75 37.22,75.52 37.22,75.81 36.87,76.16 36.58,76.16 35.81,75.39 35.7,75.39 35.47,75.62 35.47,75.73 36.27,76.54 36.27,76.83 35.92,77.18 35.63,77.18 34.83,76.37 34.71,76.37 34.48,76.6 34.48,76.72 35.15,77.39 35.15,77.67 34.8,78.03 34.51,78.03 33.84,77.36 33.73,77.36 33.5,77.59 33.5,77.7 34.16,78.37 34.16,78.66 33.81,79.01 33.52,79.01 32.86,78.34 32.74,78.34 31.46,79.63 8.8,79.63 8.51,79.34 8.51,78.59 8.43,78.51 8.11,78.51 8.03,78.59 v2(8.03,79.04)
FMC1_LA20_N: length 85.8
  TOP w0.124: J48.G22 v2(9.3,77.77)
  TOP w0.152: U3.AF2 v2(64.9,70.93)
  L12-SIG4 w0.081: v2(9.3,77.77) 9.3,78.03 9.57,78.3 18.3,78.3 18.38,78.22 18.38,77 18.58,76.8 19.08,76.8 19.29,77 19.29,78.22 19.37,78.3 19.69,78.3 19.77,78.22 19.77,77.09 19.98,76.88 20.47,76.88 20.68,77.09 20.68,78.22 20.76,78.3 21.08,78.3 21.16,78.22 21.16,77.09 21.37,76.88 21.87,76.88 22.07,77.09 22.07,78.22 22.15,78.3 22.48,78.3 22.56,78.22 22.56,77.09 22.76,76.88 23.26,76.88 23.46,77.09 23.46,78.22 23.54,78.3 23.87,78.3 23.95,78.22 23.95,77.09 24.15,76.88 24.65,76.88 24.85,77.09 24.85,78.22 24.93,78.3 25.26,78.3 25.34,78.22 25.34,77.09 25.54,76.88 26.04,76.88 26.24,77.09 26.24,78.22 26.33,78.3 26.65,78.3 26.73,78.22 26.73,77.09 26.94,76.88 27.43,76.88 27.64,77.09 27.64,78.22 27.72,78.3 28.04,78.3 28.12,78.22 28.12,77.09 28.33,76.88 28.83,76.88 29.03,77.09 29.03,78.22 29.11,78.3 29.44,78.3 29.52,78.22 29.52,77.09 29.72,76.88 30.22,76.88 30.42,77.09 30.42,78.22 30.5,78.3 31.05,78.3 31.63,77.73 31.63,77.61 31.36,77.35 31.36,77.06 31.72,76.71 32,76.71 32.26,76.97 32.38,76.97 34.42,74.93 34.42,74.81 34.04,74.43 34.04,74.14 34.39,73.79 34.68,73.79 35.06,74.18 35.18,74.18 37.55,71.8 62.57,71.8 63.05,71.33 64.82,71.33 64.9,71.24 v2(64.9,70.93)
FMC1_LA20_P: length 85.9
  TOP w0.124: J48.G21 v2(9.3,79.04)
  TOP w0.152: U3.AE2 v2(64.9,71.93)
  L12-SIG4 w0.081: v2(9.3,79.04) 9.3,78.59 9.38,78.51 18.39,78.51 18.59,78.31 18.59,77.09 18.67,77.01 19,77.01 19.08,77.09 19.08,78.31 19.28,78.51 19.78,78.51 19.98,78.31 19.98,77.17 20.06,77.09 20.39,77.09 20.47,77.17 20.47,78.31 20.67,78.51 21.17,78.51 21.37,78.31 21.37,77.17 21.45,77.09 21.78,77.09 21.86,77.17 21.86,78.31 22.06,78.51 22.56,78.51 22.77,78.31 22.77,77.17 22.85,77.09 23.17,77.09 23.25,77.17 23.25,78.31 23.46,78.51 23.95,78.51 24.16,78.31 24.16,77.17 24.24,77.09 24.56,77.09 24.64,77.17 24.64,78.31 24.85,78.51 25.35,78.51 25.55,78.31 25.55,77.17 25.63,77.09 25.96,77.09 26.04,77.17 26.04,78.31 26.24,78.51 26.74,78.51 26.94,78.31 26.94,77.17 27.02,77.09 27.35,77.09 27.43,77.17 27.43,78.31 27.63,78.51 28.13,78.51 28.33,78.31 28.33,77.17 28.41,77.09 28.74,77.09 28.82,77.17 28.82,78.31 29.02,78.51 29.52,78.51 29.72,78.31 29.72,77.17 29.81,77.09 30.13,77.09 30.21,77.17 30.21,78.31 30.42,78.51 31.14,78.51 31.83,77.81 31.83,77.53 31.57,77.27 31.57,77.15 31.8,76.92 31.92,76.92 32.18,77.18 32.47,77.18 34.63,75.02 34.63,74.73 34.25,74.35 34.25,74.23 34.48,74 34.59,74 34.98,74.38 35.26,74.38 37.64,72.01 62.66,72.01 63.13,71.53 64.82,71.53 64.9,71.62 v2(64.9,71.93)
FMC1_LA21_N: length 85
  TOP w0.124: J48.H26 v2(8.03,73.96) ; U3.AK2 v2(64.9,66.93)
  L12-SIG4 w0.081: v2(8.03,73.96) 8.48,73.96 8.56,73.88 8.56,72.22 8.8,71.97 18.71,71.97 22.27,68.42 51.77,68.42 51.99,68.2 51.99,65.91 52.2,65.71 52.69,65.71 52.9,65.91 52.9,67.24 53.05,67.4 53.25,67.4 53.38,67.27 53.38,65.91 53.59,65.71 54.09,65.71 54.29,65.91 54.29,67.37 54.37,67.45 54.69,67.45 54.78,67.37 54.78,65.91 54.98,65.71 55.48,65.71 55.68,65.91 55.68,67.42 55.76,67.5 56.09,67.5 56.17,67.42 56.17,65.91 56.37,65.71 56.87,65.71 57.07,65.91 57.07,67.45 57.15,67.53 57.48,67.53 57.56,67.45 57.56,65.91 57.76,65.71 58.26,65.71 58.46,65.91 58.46,67.47 58.55,67.56 58.87,67.56 58.95,67.47 58.95,65.91 59.16,65.71 59.65,65.71 59.86,65.91 59.86,67.24 59.94,67.33 60.26,67.33 60.34,67.24 60.34,65.91 60.55,65.71 61.04,65.71 61.25,65.91 61.25,67.24 61.33,67.33 64.82,67.33 64.9,67.24 v2(64.9,66.93)
FMC1_LA21_P: length 84.7
  TOP w0.124: U3.AJ2 v2(64.9,67.93) ; J48.H25 v2(9.3,73.96)
  L12-SIG4 w0.081: v2(9.3,73.96) 8.85,73.96 8.77,73.88 8.77,72.31 8.89,72.18 18.8,72.18 22.35,68.63 51.86,68.63 52.2,68.28 52.2,66 52.28,65.91 52.61,65.91 52.69,66 52.69,67.33 52.97,67.61 53.34,67.61 53.59,67.36 53.59,66 53.67,65.91 54,65.91 54.08,66 54.08,67.46 54.28,67.66 54.78,67.66 54.98,67.46 54.98,66 55.07,65.91 55.39,65.91 55.47,66 55.47,67.51 55.68,67.71 56.17,67.71 56.38,67.51 56.38,66 56.46,65.91 56.78,65.91 56.86,66 56.86,67.53 57.07,67.74 57.57,67.74 57.77,67.53 57.77,66 57.85,65.91 58.17,65.91 58.26,66 58.26,67.56 58.46,67.76 58.96,67.76 59.16,67.56 59.16,66 59.24,65.91 59.57,65.91 59.65,66 59.65,67.33 59.85,67.53 60.35,67.53 60.55,67.33 60.55,66 60.63,65.91 60.96,65.91 61.04,66 61.04,67.33 61.24,67.53 64.82,67.53 64.9,67.62 v2(64.9,67.93)
FMC1_LA22_N: length 83.6
  TOP w0.124: J48.G25 v2(10.57,73.96)
  TOP w0.152: U3.AG2 v2(64.9,69.93)
  L12-SIG4 w0.081: v2(64.9,69.93) 64.28,69.31 60.11,69.31 59.35,70.07 58.49,70.07 58.41,69.99 58.41,69.34 58.21,69.13 57.71,69.13 57.51,69.34 57.51,69.99 57.43,70.07 57.1,70.07 57.02,69.99 57.02,69.34 56.82,69.13 56.32,69.13 56.12,69.34 56.12,69.99 56.03,70.07 55.71,70.07 55.63,69.99 55.63,69.34 55.43,69.13 54.93,69.13 54.72,69.34 54.72,69.99 54.64,70.07 54.32,70.07 54.24,69.99 54.24,69.34 54.03,69.13 53.54,69.13 53.33,69.34 53.33,69.99 53.25,70.07 34.58,70.07 33.11,71.55 26.51,71.55 26.3,71.75 26.3,73.67 26.22,73.75 25.9,73.75 25.82,73.67 25.82,71.75 25.61,71.55 25.12,71.55 24.91,71.75 24.91,73.67 24.83,73.75 24.51,73.75 24.42,73.67 24.42,71.75 24.22,71.55 23.72,71.55 23.52,71.75 23.52,74.41 23.44,74.49 23.11,74.49 23.03,74.41 23.03,71.75 22.83,71.55 22.33,71.55 22.13,71.75 22.13,74.41 22.05,74.49 21.72,74.49 21.64,74.41 21.64,72.84 21.44,72.63 20.94,72.63 20.74,72.84 20.74,74.41 20.66,74.49 10.65,74.49 10.57,74.41 v2(10.57,73.96)
FMC1_LA22_P: length 83.5
  TOP w0.124: J48.G24 v2(10.57,75.23)
  TOP w0.152: U3.AG1 v2(63.9,69.93)
  L12-SIG4 w0.081: v2(10.57,75.23) 10.57,74.78 10.65,74.7 20.74,74.7 20.95,74.5 20.95,72.92 21.03,72.84 21.35,72.84 21.43,72.92 21.43,74.5 21.64,74.7 22.13,74.7 22.34,74.5 22.34,71.84 22.42,71.76 22.74,71.76 22.82,71.84 22.82,74.5 23.03,74.7 23.53,74.7 23.73,74.5 23.73,71.84 23.81,71.76 24.14,71.76 24.22,71.84 24.22,73.76 24.42,73.96 24.92,73.96 25.12,73.76 25.12,71.84 25.2,71.76 25.53,71.76 25.61,71.84 25.61,73.76 25.81,73.96 26.31,73.96 26.51,73.76 26.51,71.84 26.59,71.76 33.19,71.76 34.67,70.28 53.34,70.28 53.54,70.07 53.54,69.42 53.62,69.34 53.95,69.34 54.03,69.42 54.03,70.07 54.23,70.28 54.73,70.28 54.93,70.07 54.93,69.42 55.01,69.34 55.34,69.34 55.42,69.42 55.42,70.07 55.62,70.28 56.12,70.28 56.32,70.07 56.32,69.42 56.41,69.34 56.73,69.34 56.81,69.42 56.81,70.07 57.02,70.28 57.51,70.28 57.72,70.07 57.72,69.42 57.8,69.34 58.12,69.34 58.2,69.42 58.2,70.07 58.41,70.28 59.44,70.28 60.2,69.52 64.16,69.52 64.31,69.66 64.31,69.85 64.23,69.93 v2(63.9,69.93)
FMC1_LA23_N: length 86.8
  TOP w0.099: J48.D24 v2(14.38,76.5)
  TOP w0.152: U3.AE3 v2(65.9,71.93)
  L12-SIG4 w0.081: v2(65.9,71.93) 65.9,71.59 65.82,71.51 65.53,71.51 65.32,71.31 65.32,70.75 65.11,70.53 60.58,70.53 59.94,71.17 36.58,71.17 35.1,72.65 33.21,72.65 33.13,72.73 33.13,75.03 32.92,75.23 32.42,75.23 32.22,75.03 32.22,72.73 32.14,72.65 31.81,72.65 31.73,72.73 31.73,75.76 31.53,75.97 31.03,75.97 30.83,75.76 30.83,72.73 30.75,72.65 30.42,72.65 30.34,72.73 30.34,75.76 30.14,75.97 29.64,75.97 29.44,75.76 29.44,72.73 29.36,72.65 29.03,72.65 28.95,72.73 28.95,75.76 28.75,75.97 28.25,75.97 28.05,75.76 28.05,72.73 27.96,72.65 27.64,72.65 27.56,72.73 27.56,75.76 27.35,75.97 26.44,75.97 26.24,75.76 26.24,75.06 26.16,74.98 25.83,74.98 25.75,75.06 25.75,75.76 25.55,75.97 25.05,75.97 24.85,75.76 24.85,75.06 24.77,74.98 24.44,74.98 24.36,75.06 24.36,75.76 24.16,75.97 13.95,75.97 13.87,76.05 13.87,76.4 13.97,76.5 v2(14.38,76.5)
FMC1_LA23_P: length 86.8
  TOP w0.099: J48.D23 v2(13.11,76.5)
  TOP w0.152: U3.AF3 v2(65.9,70.93)
  L12-SIG4 w0.081: v2(13.11,76.5) 13.85,75.76 24.07,75.76 24.15,75.68 24.15,74.98 24.35,74.77 24.85,74.77 25.06,74.98 25.06,75.68 25.14,75.76 25.46,75.76 25.54,75.68 25.54,74.98 25.75,74.77 26.24,74.77 26.45,74.98 26.45,75.68 26.53,75.76 27.27,75.76 27.35,75.68 27.35,72.64 27.55,72.44 28.05,72.44 28.25,72.64 28.25,75.68 28.33,75.76 28.66,75.76 28.74,75.68 28.74,72.64 28.94,72.44 29.44,72.44 29.65,72.64 29.65,75.68 29.73,75.76 30.05,75.76 30.13,75.68 30.13,72.64 30.34,72.44 30.83,72.44 31.04,72.64 31.04,75.68 31.12,75.76 31.44,75.76 31.53,75.68 31.53,72.64 31.73,72.44 32.23,72.44 32.43,72.64 32.43,74.94 32.51,75.02 32.84,75.02 32.92,74.94 32.92,72.64 33.12,72.44 35.01,72.44 36.49,70.96 59.86,70.96 60.49,70.32 65.2,70.32 65.53,70.66 65.53,71.22 65.61,71.3 65.82,71.3 65.9,71.22 v2(65.9,70.93)
FMC1_LA24_N: length 86.4
  TOP w0.124: J48.H29 v2(8.03,70.15)
  TOP w0.152: U3.AJ3 v2(65.9,67.93)
  L12-SIG4 w0.081: v2(65.9,67.93) 65.9,68.37 65.84,68.42 65.56,68.42 65.48,68.34 65.48,66.75 64.98,66.26 64.6,66.26 64.47,66.13 64.47,65.62 64.18,65.32 63.27,65.32 62.59,64.64 62.59,62.96 62.38,62.75 60.08,62.75 59.82,63.01 59.82,63.65 59.49,63.97 49.95,63.97 49.66,64.27 49.66,66.55 49.44,66.77 31.96,66.77 31.88,66.69 31.88,62.91 31.54,62.58 30.81,62.58 30.61,62.78 30.61,63.77 30.53,63.85 30.2,63.85 30.12,63.77 30.12,62.78 29.92,62.58 29.42,62.58 29.22,62.78 29.22,63.77 29.14,63.85 28.81,63.85 28.73,63.77 28.73,62.78 28.53,62.58 28.03,62.58 27.83,62.78 27.83,63.77 27.74,63.85 27.42,63.85 27.34,63.77 27.34,62.78 27.14,62.58 26.64,62.58 26.43,62.78 26.43,63.77 26.35,63.85 26.03,63.85 25.95,63.77 25.95,62.78 25.74,62.58 25.25,62.58 25.04,62.78 25.04,63.77 24.96,63.85 24.64,63.85 24.55,63.77 24.55,63.12 24.35,62.91 23.62,62.91 18.84,67.69 18.84,69.18 18.61,69.41 8.77,69.41 v2(8.03,70.15)
FMC1_LA24_P: length 86
  TOP w0.124: J48.H28 v2(9.3,70.15)
  TOP w0.152: U3.AH2 v2(64.9,68.93)
  L12-SIG4 w0.081: v2(9.3,70.15) 8.74,70.15 8.64,70.05 8.64,69.84 8.85,69.62 18.69,69.62 19.05,69.26 19.05,67.78 23.71,63.12 24.27,63.12 24.35,63.2 24.35,63.85 24.55,64.05 25.05,64.05 25.25,63.85 25.25,62.87 25.33,62.78 25.66,62.78 25.74,62.87 25.74,63.85 25.94,64.05 26.44,64.05 26.64,63.85 26.64,62.87 26.72,62.78 27.05,62.78 27.13,62.87 27.13,63.85 27.33,64.05 27.83,64.05 28.03,63.85 28.03,62.87 28.12,62.78 28.44,62.78 28.52,62.87 28.52,63.85 28.73,64.05 29.22,64.05 29.43,63.85 29.43,62.87 29.51,62.78 29.83,62.78 29.91,62.87 29.91,63.85 30.12,64.05 30.62,64.05 30.82,63.85 30.82,62.87 30.9,62.78 31.46,62.78 31.67,63 31.67,66.77 31.87,66.98 49.53,66.98 49.87,66.64 49.87,64.35 50.04,64.18 59.58,64.18 60.03,63.73 60.03,63.1 60.16,62.96 62.3,62.96 62.38,63.04 62.38,64.73 63.19,65.53 64.09,65.53 64.26,65.71 64.26,66.21 64.52,66.47 64.9,66.47 65.27,66.84 65.27,68.56 v2(64.9,68.93)
FMC1_LA25_N: length 82.8
  TOP w0.099: J48.G28 v2(10.57,71.42)
  TOP w0.124: U3.AK1 v2(63.9,66.93)
  L12-SIG4 w0.081: v2(63.9,66.93) 63.9,66.62 63.82,66.53 62.89,66.53 61.38,65.03 50.76,65.03 50.63,65.16 50.63,67.15 50.04,67.74 30.65,67.74 30.45,67.53 30.45,66.14 30.36,66.06 30.04,66.06 29.96,66.14 29.96,67.53 29.75,67.74 29.26,67.74 29.05,67.53 29.05,65.74 28.97,65.66 28.65,65.66 28.57,65.74 28.57,67.53 28.36,67.74 27.86,67.74 27.66,67.53 27.66,65.74 27.58,65.66 27.25,65.66 27.17,65.74 27.17,67.53 26.97,67.74 26.47,67.74 26.27,67.53 26.27,65.74 26.19,65.66 25.86,65.66 25.78,65.74 25.78,67.53 25.58,67.74 25.08,67.74 24.88,67.53 24.88,65.74 24.8,65.66 24.47,65.66 24.39,65.74 24.39,67.49 24.19,67.69 23.69,67.69 23.49,67.49 23.49,65.74 23.4,65.66 23.08,65.66 23,65.74 23,66.84 18.92,70.91 10.1,70.91 9.91,71.11 9.91,71.34 9.99,71.42 v2(10.57,71.42)
FMC1_LA25_P: length 82.7
  TOP w0.099: J48.G27 v2(9.3,71.42)
  TOP w0.124: U3.AL1 v2(63.9,65.93)
  L12-SIG4 w0.081: v2(9.3,71.42) 10.01,70.7 18.84,70.7 22.79,66.75 22.79,65.66 22.99,65.45 23.49,65.45 23.69,65.66 23.69,67.4 23.78,67.48 24.1,67.48 24.18,67.4 24.18,65.66 24.38,65.45 24.88,65.45 25.09,65.66 25.09,67.45 25.17,67.53 25.49,67.53 25.57,67.45 25.57,65.66 25.78,65.45 26.27,65.45 26.48,65.66 26.48,67.45 26.56,67.53 26.88,67.53 26.97,67.45 26.97,65.66 27.17,65.45 27.67,65.45 27.87,65.66 27.87,67.45 27.95,67.53 28.28,67.53 28.36,67.45 28.36,65.66 28.56,65.45 29.06,65.45 29.26,65.66 29.26,67.45 29.34,67.53 29.67,67.53 29.75,67.45 29.75,66.06 29.95,65.85 30.45,65.85 30.65,66.06 30.65,67.45 30.73,67.53 49.95,67.53 50.42,67.06 50.42,65.07 50.67,64.82 61.47,64.82 62.98,66.33 63.82,66.33 63.9,66.24 v2(63.9,65.93)
FMC1_LA26_N: length 96.8
  TOP w0.099: J48.D27 v2(14.38,72.69)
  TOP w0.124: U3.AF11 v2(73.9,70.93)
  L05-SIG2 w0.081: v2(14.38,72.69) 13.93,72.69 13.85,72.77 13.85,83.21 14.07,83.44 19.14,83.44 19.34,83.64 19.34,84.21 19.43,84.29 19.75,84.29 19.83,84.21 19.83,83.64 20.04,83.44 20.53,83.44 20.74,83.64 20.74,84.21 20.82,84.29 21.14,84.29 21.22,84.21 21.22,83.64 21.43,83.44 21.92,83.44 22.13,83.64 22.13,84.21 22.21,84.29 22.53,84.29 22.62,84.21 22.62,83.64 22.82,83.44 23.32,83.44 23.52,83.64 23.52,84.21 23.6,84.29 23.93,84.29 24.01,84.21 24.01,83.64 24.21,83.44 24.71,83.44 24.91,83.64 24.91,84.21 24.99,84.29 25.32,84.29 25.4,84.21 25.4,83.64 25.6,83.44 26.1,83.44 26.3,83.64 26.3,84.21 26.39,84.29 26.71,84.29 26.79,84.21 26.79,83.64 26.99,83.44 27.49,83.44 27.7,83.64 27.7,84.21 27.78,84.29 28.1,84.29 28.18,84.21 28.18,83.64 28.39,83.44 28.88,83.44 29.09,83.64 29.09,84.21 29.17,84.29 29.49,84.29 29.58,84.21 29.58,83.64 29.78,83.44 30.28,83.44 30.48,83.64 30.48,84.21 30.56,84.29 30.89,84.29 30.97,84.21 30.97,83.64 31.17,83.44 31.67,83.44 31.87,83.64 31.87,84.21 31.95,84.29 32.28,84.29 32.36,84.21 32.36,83.64 32.56,83.44 33.06,83.44 33.26,83.64 33.26,84.21 33.34,84.29 33.67,84.29 33.75,84.21 33.75,83.64 33.95,83.44 34.45,83.44 34.66,83.64 34.66,84.21 34.74,84.29 35.06,84.29 35.14,84.21 35.14,83.64 35.35,83.44 35.84,83.44 36.05,83.64 36.05,84.21 36.13,84.29 36.45,84.29 36.53,84.21 36.53,83.64 36.74,83.44 41.73,83.44 49.56,75.61 55.09,75.61 57.38,73.33 73.03,73.33 73.3,73.05 73.3,71.53 v2(73.9,70.93)
FMC1_LA26_P: length 96.7
  TOP w0.099: J48.D26 v2(13.11,72.69)
  TOP w0.124: U3.AE11 v2(73.9,71.93)
  L05-SIG2 w0.081: v2(13.11,72.69) 13.56,72.69 13.64,72.77 13.64,83.3 13.99,83.64 19.05,83.64 19.14,83.72 19.14,84.3 19.34,84.5 19.84,84.5 20.04,84.3 20.04,83.72 20.12,83.64 20.45,83.64 20.53,83.72 20.53,84.3 20.73,84.5 21.23,84.5 21.43,84.3 21.43,83.72 21.51,83.64 21.84,83.64 21.92,83.72 21.92,84.3 22.12,84.5 22.62,84.5 22.82,84.3 22.82,83.72 22.91,83.64 23.23,83.64 23.31,83.72 23.31,84.3 23.51,84.5 24.01,84.5 24.22,84.3 24.22,83.72 24.3,83.64 24.62,83.64 24.7,83.72 24.7,84.3 24.91,84.5 25.4,84.5 25.61,84.3 25.61,83.72 25.69,83.64 26.01,83.64 26.1,83.72 26.1,84.3 26.3,84.5 26.8,84.5 27,84.3 27,83.72 27.08,83.64 27.41,83.64 27.49,83.72 27.49,84.3 27.69,84.5 28.19,84.5 28.39,84.3 28.39,83.72 28.47,83.64 28.8,83.64 28.88,83.72 28.88,84.3 29.08,84.5 29.58,84.5 29.78,84.3 29.78,83.72 29.86,83.64 30.19,83.64 30.27,83.72 30.27,84.3 30.47,84.5 30.97,84.5 31.18,84.3 31.18,83.72 31.26,83.64 31.58,83.64 31.66,83.72 31.66,84.3 31.87,84.5 32.36,84.5 32.57,84.3 32.57,83.72 32.65,83.64 32.97,83.64 33.06,83.72 33.06,84.3 33.26,84.5 33.76,84.5 33.96,84.3 33.96,83.72 34.04,83.64 34.37,83.64 34.45,83.72 34.45,84.3 34.65,84.5 35.15,84.5 35.35,84.3 35.35,83.72 35.43,83.64 35.76,83.64 35.84,83.72 35.84,84.3 36.04,84.5 36.54,84.5 36.74,84.3 36.74,83.72 36.82,83.64 41.82,83.64 49.64,75.82 55.18,75.82 57.47,73.53 73.11,73.53 73.51,73.14 73.51,71.93 73.59,71.85 73.82,71.85 v2(73.9,71.93)
FMC1_LA27_N: length 95.6
  TOP w0.124: U3.AE10 v2(72.9,71.93) ; J48.C27 v2(15.65,71.42)
  L05-SIG2 w0.081: v2(15.65,71.42) 15.65,71.9 15.57,71.98 15.13,71.98 14.9,72.2 14.9,81.87 15.38,82.35 19.51,82.35 19.71,82.14 19.71,81.49 19.79,81.41 20.12,81.41 20.2,81.49 20.2,82.14 20.4,82.35 20.9,82.35 21.1,82.14 21.1,81.49 21.18,81.41 21.51,81.41 21.59,81.49 21.59,82.14 21.79,82.35 22.29,82.35 22.49,82.14 22.49,81.49 22.58,81.41 22.9,81.41 22.98,81.49 22.98,82.14 23.18,82.35 23.68,82.35 23.89,82.14 23.89,81.49 23.97,81.41 24.29,81.41 24.37,81.49 24.37,82.14 24.58,82.35 25.07,82.35 25.28,82.14 25.28,81.49 25.36,81.41 25.68,81.41 25.77,81.49 25.77,82.14 25.97,82.35 26.47,82.35 26.67,82.14 26.67,81.49 26.75,81.41 27.08,81.41 27.16,81.49 27.16,82.14 27.36,82.35 27.86,82.35 28.06,82.14 28.06,81.49 28.14,81.41 28.47,81.41 28.55,81.49 28.55,82.14 28.75,82.35 29.25,82.35 29.45,82.14 29.45,81.49 29.53,81.41 29.86,81.41 29.94,81.49 29.94,82.14 30.14,82.35 30.64,82.35 30.85,82.14 30.85,81.49 30.93,81.41 31.25,81.41 31.33,81.49 31.33,82.14 31.54,82.35 32.03,82.35 32.24,82.14 32.24,81.49 32.32,81.41 32.64,81.41 32.72,81.49 32.72,82.14 32.93,82.35 33.43,82.35 33.63,82.14 33.63,81.49 33.71,81.41 34.04,81.41 34.12,81.49 34.12,82.14 34.32,82.35 34.82,82.35 35.02,82.14 35.02,81.49 35.1,81.41 35.43,81.41 35.51,81.49 35.51,82.14 35.71,82.35 36.21,82.35 36.41,82.14 36.41,81.49 36.49,81.41 36.82,81.41 36.9,81.49 36.9,82.14 37.1,82.35 37.6,82.35 37.8,82.14 37.8,81.49 37.89,81.41 42.43,81.41 48.86,74.98 54.52,74.98 56.97,72.53 72.3,72.53 v2(72.9,71.93)
FMC1_LA27_P: length 95.7
  TOP w0.124: U3.AF10 v2(72.9,70.93) ; J48.C26 v2(15.65,72.69)
  L05-SIG2 w0.081: v2(72.9,70.93) 72.54,71.29 72.54,71.99 72.21,72.33 56.88,72.33 54.44,74.77 48.77,74.77 42.34,81.2 37.8,81.2 37.6,81.4 37.6,82.06 37.52,82.14 37.19,82.14 37.11,82.06 37.11,81.4 36.91,81.2 36.41,81.2 36.2,81.4 36.2,82.06 36.12,82.14 35.8,82.14 35.72,82.06 35.72,81.4 35.51,81.2 35.02,81.2 34.81,81.4 34.81,82.06 34.73,82.14 34.41,82.14 34.33,82.06 34.33,81.4 34.12,81.2 33.62,81.2 33.42,81.4 33.42,82.06 33.34,82.14 33.01,82.14 32.93,82.06 32.93,81.4 32.73,81.2 32.23,81.2 32.03,81.4 32.03,82.06 31.95,82.14 31.62,82.14 31.54,82.06 31.54,81.4 31.34,81.2 30.84,81.2 30.64,81.4 30.64,82.06 30.56,82.14 30.23,82.14 30.15,82.06 30.15,81.4 29.95,81.2 29.45,81.2 29.25,81.4 29.25,82.06 29.16,82.14 28.84,82.14 28.76,82.06 28.76,81.4 28.55,81.2 28.06,81.2 27.85,81.4 27.85,82.06 27.77,82.14 27.45,82.14 27.37,82.06 27.37,81.4 27.16,81.2 26.66,81.2 26.46,81.4 26.46,82.06 26.38,82.14 26.05,82.14 25.97,82.06 25.97,81.4 25.77,81.2 25.27,81.2 25.07,81.4 25.07,82.06 24.99,82.14 24.66,82.14 24.58,82.06 24.58,81.4 24.38,81.2 23.88,81.2 23.68,81.4 23.68,82.06 23.6,82.14 23.27,82.14 23.19,82.06 23.19,81.4 22.99,81.2 22.49,81.2 22.29,81.4 22.29,82.06 22.2,82.14 21.88,82.14 21.8,82.06 21.8,81.4 21.59,81.2 21.1,81.2 20.89,81.4 20.89,82.06 20.81,82.14 20.49,82.14 20.41,82.06 20.41,81.4 20.2,81.2 19.7,81.2 19.5,81.4 19.5,82.06 19.42,82.14 15.47,82.14 15.11,81.78 15.11,73.4 15.21,73.3 15.21,73.05 15.11,72.94 15.11,72.29 15.21,72.19 15.57,72.19 15.65,72.27 v2(15.65,72.69)
FMC1_LA28_N: length 90.2
  TOP w0.099: 8.66,65.71 v2(9.3,66.34)
  TOP w0.124: U3.AH5 v2(67.9,68.93)
  L05-SIG2 w0.081: v2(9.3,66.34) 8.85,66.34 8.77,66.26 8.77,66.04 8.98,65.83 9.57,65.83 9.7,65.96 9.9,65.96 10.02,65.83 18.36,65.83 18.47,65.93 18.69,65.93 18.79,65.83 19.43,65.83 21.21,67.61 21.21,71.12 21.59,71.5 22.54,71.5 22.62,71.58 22.62,72.08 22.82,72.28 23.32,72.28 23.52,72.08 23.52,71.58 23.6,71.5 23.93,71.5 24.01,71.58 24.01,72.08 24.21,72.28 24.71,72.28 24.91,72.08 24.91,71.58 25,71.5 25.32,71.5 25.4,71.58 25.4,72.08 25.61,72.28 26.1,72.28 26.31,72.08 26.31,71.58 26.39,71.5 26.71,71.5 26.79,71.58 26.79,72.08 27,72.28 27.5,72.28 27.7,72.08 27.7,71.58 27.78,71.5 28.11,71.5 28.19,71.58 28.19,72.08 28.39,72.28 28.89,72.28 29.09,72.08 29.09,71.58 29.17,71.5 29.5,71.5 29.58,71.58 29.58,72.08 29.78,72.28 30.28,72.28 30.48,72.08 30.48,71.58 30.56,71.5 30.89,71.5 30.97,71.58 30.97,72.08 31.17,72.28 31.67,72.28 31.87,72.08 31.87,71.58 31.96,71.5 32.28,71.5 32.36,71.58 32.36,72.08 32.57,72.28 33.06,72.28 33.27,72.08 33.27,71.58 33.35,71.5 33.67,71.5 33.75,71.58 33.75,72.08 33.96,72.28 34.46,72.28 34.66,72.08 34.66,71.58 34.74,71.5 35.06,71.5 35.15,71.58 35.15,72.08 35.35,72.28 35.85,72.28 36.05,72.08 36.05,71.58 36.13,71.5 36.46,71.5 36.54,71.58 36.54,72.08 36.74,72.28 37.24,72.28 37.44,72.08 37.44,71.58 37.52,71.5 37.85,71.5 37.93,71.58 37.93,72.08 38.13,72.28 38.63,72.28 38.83,72.08 38.83,71.58 38.92,71.5 39.24,71.5 39.32,71.58 39.32,72.08 39.52,72.28 40.02,72.28 40.23,72.08 40.23,71.58 40.31,71.5 40.63,71.5 40.71,71.58 40.71,72.08 40.92,72.28 41.41,72.28 41.62,72.08 41.62,71.58 41.7,71.5 42.02,71.5 42.11,71.58 42.11,72.08 42.31,72.28 42.81,72.28 43.01,72.08 43.01,71.58 43.09,71.5 43.42,71.5 43.5,71.58 43.5,72.08 43.7,72.28 44.2,72.28 44.4,72.08 44.4,71.58 45.45,70.53 51.2,70.53 54.17,67.56 66.12,67.56 66.24,67.69 66.52,67.69 66.65,67.56 67.11,67.56 67.26,67.71 67.49,67.71 67.64,67.56 68.12,67.56 68.3,67.73 68.3,68.28 68.5,68.48 68.5,68.84 68.4,68.93 v2(67.9,68.93)
FMC1_LA28_P: length 90
  TOP w0.099: J48.H31 v2(8.03,66.34)
  TOP w0.124: U3.AH6 v2(68.9,68.93)
  L05-SIG2 w0.081: v2(8.03,66.34) 8.48,66.34 8.56,66.26 8.56,65.95 8.89,65.62 19.52,65.62 21.42,67.52 21.42,71.03 21.68,71.29 22.62,71.29 22.83,71.49 22.83,72 22.91,72.08 23.23,72.08 23.31,72 23.31,71.49 23.52,71.29 24.02,71.29 24.22,71.49 24.22,72 24.3,72.08 24.63,72.08 24.71,72 24.71,71.49 24.91,71.29 25.41,71.29 25.61,71.49 25.61,72 25.69,72.08 26.02,72.08 26.1,72 26.1,71.49 26.3,71.29 26.8,71.29 27,71.49 27,72 27.08,72.08 27.41,72.08 27.49,72 27.49,71.49 27.69,71.29 28.19,71.29 28.39,71.49 28.39,72 28.48,72.08 28.8,72.08 28.88,72 28.88,71.49 29.09,71.29 29.58,71.29 29.79,71.49 29.79,72 29.87,72.08 30.19,72.08 30.27,72 30.27,71.49 30.48,71.29 30.98,71.29 31.18,71.49 31.18,72 31.26,72.08 31.58,72.08 31.67,72 31.67,71.49 31.87,71.29 32.37,71.29 32.57,71.49 32.57,72 32.65,72.08 32.98,72.08 33.06,72 33.06,71.49 33.26,71.29 33.76,71.29 33.96,71.49 33.96,72 34.04,72.08 34.37,72.08 34.45,72 34.45,71.49 34.65,71.29 35.15,71.29 35.35,71.49 35.35,72 35.44,72.08 35.76,72.08 35.84,72 35.84,71.49 36.05,71.29 36.54,71.29 36.75,71.49 36.75,72 36.83,72.08 37.15,72.08 37.23,72 37.23,71.49 37.44,71.29 37.93,71.29 38.14,71.49 38.14,72 38.22,72.08 38.54,72.08 38.63,72 38.63,71.49 38.83,71.29 39.33,71.29 39.53,71.49 39.53,72 39.61,72.08 39.94,72.08 40.02,72 40.02,71.49 40.22,71.29 40.72,71.29 40.92,71.49 40.92,72 41,72.08 41.33,72.08 41.41,72 41.41,71.49 41.61,71.29 42.11,71.29 42.31,71.49 42.31,72 42.4,72.08 42.72,72.08 42.8,72 42.8,71.49 43,71.29 43.5,71.29 43.71,71.49 43.71,72 43.79,72.08 44.11,72.08 44.19,72 44.19,71.49 45.36,70.32 51.11,70.32 54.08,67.35 68.21,67.35 68.5,67.65 68.5,68.19 68.71,68.4 68.71,68.74 v2(68.9,68.93)
FMC1_LA29_N: length 91.9
  TOP w0.099: J48.G31 v2(10.57,67.61)
  TOP w0.124: U3.AG8 v2(70.9,69.93)
  L05-SIG2 w0.081: v2(70.9,69.93) 70.29,69.33 55.03,69.33 52.25,72.1 47.08,72.1 44.14,75.05 41.22,75.05 41.02,75.25 41.02,75.65 40.94,75.73 40.61,75.73 40.53,75.65 40.53,75.25 40.33,75.05 39.83,75.05 39.63,75.25 39.63,75.68 39.55,75.76 39.22,75.76 39.14,75.68 39.14,75.25 38.94,75.05 38.44,75.05 38.24,75.25 38.24,75.81 38.16,75.89 37.83,75.89 37.75,75.81 37.75,75.25 37.55,75.05 37.05,75.05 36.85,75.25 36.85,75.81 36.76,75.89 36.44,75.89 36.36,75.81 36.36,75.25 36.15,75.05 35.66,75.05 35.45,75.25 35.45,75.81 35.37,75.89 35.05,75.89 34.97,75.81 34.97,75.25 34.76,75.05 34.26,75.05 34.06,75.25 34.06,75.81 33.98,75.89 33.66,75.89 33.57,75.81 33.57,75.25 33.37,75.05 32.87,75.05 32.67,75.25 32.67,75.81 32.59,75.89 32.26,75.89 32.18,75.81 32.18,75.25 31.98,75.05 31.48,75.05 31.28,75.25 31.28,75.81 31.2,75.89 30.87,75.89 30.79,75.81 30.79,75.25 30.59,75.05 30.09,75.05 29.89,75.25 29.89,75.81 29.8,75.89 29.48,75.89 29.4,75.81 29.4,75.25 29.19,75.05 28.7,75.05 28.49,75.25 28.49,75.81 28.41,75.89 28.09,75.89 28.01,75.81 28.01,75.25 27.8,75.05 27.3,75.05 27.1,75.25 27.1,75.81 27.02,75.89 26.7,75.89 26.61,75.81 26.61,75.25 26.41,75.05 25.91,75.05 25.71,75.25 25.71,75.81 25.63,75.89 25.3,75.89 25.22,75.81 25.22,75.25 25.02,75.05 24.52,75.05 24.32,75.25 24.32,75.81 24.24,75.89 23.91,75.89 23.83,75.81 23.83,75.25 23.63,75.05 23.13,75.05 22.93,75.25 22.93,75.81 22.84,75.89 22.52,75.89 22.44,75.81 22.44,75.25 22.24,75.05 21.74,75.05 21.53,75.25 21.53,75.81 21.45,75.89 21.13,75.89 21.05,75.81 21.05,75.25 20.84,75.05 19.82,75.05 19.64,74.87 19.64,69.05 18.71,68.12 10.12,68.12 10.04,68.04 10.04,67.69 10.12,67.61 v2(10.57,67.61)
FMC1_LA29_P: length 92.2
  TOP w0.099: J48.G30 v2(9.3,67.61)
  TOP w0.124: U3.AG7 v2(69.9,69.93)
  L05-SIG2 w0.081: v2(9.3,67.61) 9.75,67.61 9.83,67.69 9.83,68.12 10.03,68.33 18.62,68.33 19.43,69.13 19.43,74.95 19.74,75.26 20.76,75.26 20.84,75.34 20.84,75.89 21.04,76.09 21.54,76.09 21.74,75.89 21.74,75.34 21.82,75.26 22.15,75.26 22.23,75.34 22.23,75.89 22.43,76.09 22.93,76.09 23.13,75.89 23.13,75.34 23.22,75.26 23.54,75.26 23.62,75.34 23.62,75.89 23.83,76.09 24.32,76.09 24.53,75.89 24.53,75.34 24.61,75.26 24.93,75.26 25.01,75.34 25.01,75.89 25.22,76.09 25.71,76.09 25.92,75.89 25.92,75.34 26,75.26 26.32,75.26 26.41,75.34 26.41,75.89 26.61,76.09 27.11,76.09 27.31,75.89 27.31,75.34 27.39,75.26 27.72,75.26 27.8,75.34 27.8,75.89 28,76.09 28.5,76.09 28.7,75.89 28.7,75.34 28.78,75.26 29.11,75.26 29.19,75.34 29.19,75.89 29.39,76.09 29.89,76.09 30.09,75.89 30.09,75.34 30.18,75.26 30.5,75.26 30.58,75.34 30.58,75.89 30.78,76.09 31.28,76.09 31.49,75.89 31.49,75.34 31.57,75.26 31.89,75.26 31.97,75.34 31.97,75.89 32.18,76.09 32.67,76.09 32.88,75.89 32.88,75.34 32.96,75.26 33.28,75.26 33.37,75.34 33.37,75.89 33.57,76.09 34.07,76.09 34.27,75.89 34.27,75.34 34.35,75.26 34.68,75.26 34.76,75.34 34.76,75.89 34.96,76.09 35.46,76.09 35.66,75.89 35.66,75.34 35.74,75.26 36.07,75.26 36.15,75.34 36.15,75.89 36.35,76.09 36.85,76.09 37.05,75.89 37.05,75.34 37.13,75.26 37.46,75.26 37.54,75.34 37.54,75.89 37.74,76.09 38.24,76.09 38.45,75.89 38.45,75.34 38.53,75.26 38.85,75.26 38.93,75.34 38.93,75.76 39.14,75.97 39.63,75.97 39.84,75.76 39.84,75.34 39.92,75.26 40.24,75.26 40.33,75.34 40.33,75.74 40.53,75.94 41.03,75.94 41.23,75.74 41.23,75.34 41.31,75.26 44.22,75.26 47.17,72.31 52.34,72.31 55.12,69.53 69.14,69.53 69.25,69.64 69.47,69.64 69.58,69.53 70.21,69.53 70.29,69.62 70.29,69.85 70.21,69.93 v2(69.9,69.93)
FMC1_LA30_N: length 83
  TOP w0.099: J48.H35 v2(9.3,62.53)
  TOP w0.124: U3.AM1 v2(63.9,64.93)
  L05-SIG2 w0.081: v2(63.9,64.93) 63.9,64.62 63.82,64.53 62.6,64.53 62.4,64.33 62.4,63.73 62.31,63.65 61.99,63.65 61.91,63.73 61.91,64.33 61.71,64.53 61.21,64.53 61,64.33 61,63.73 60.92,63.65 60.6,63.65 60.52,63.73 60.52,64.33 60.31,64.53 59.82,64.53 59.61,64.33 59.61,63.73 59.53,63.65 59.21,63.65 59.12,63.73 59.12,64.33 58.92,64.53 58.42,64.53 58.22,64.33 58.22,63.73 58.14,63.65 57.81,63.65 57.73,63.73 57.73,64.33 57.53,64.53 57.03,64.53 56.83,64.33 56.83,63.73 56.75,63.65 56.42,63.65 56.34,63.73 56.34,64.33 56.14,64.53 55.64,64.53 55.44,64.33 55.44,63.73 55.36,63.65 55.03,63.65 54.95,63.73 54.95,64.33 54.75,64.53 54.25,64.53 54.04,64.33 54.04,63.73 53.96,63.65 53.64,63.65 53.56,63.73 53.56,64.33 53.35,64.53 50.78,64.53 50.09,65.22 50.09,66.9 49.25,67.74 31.77,67.74 31.57,67.53 31.57,65.44 31.49,65.36 31.16,65.36 31.08,65.44 31.08,67.53 30.88,67.74 30.38,67.74 30.18,67.53 30.18,65.44 30.1,65.36 29.77,65.36 29.69,65.44 29.69,67.53 29.49,67.74 28.99,67.74 28.79,67.53 28.79,65.44 28.71,65.36 25.02,65.36 21.67,62 8.86,62 8.63,62.23 8.63,62.44 8.71,62.53 v2(9.3,62.53)
FMC1_LA30_P: length 82.9
  TOP w0.099: J48.H34 v2(8.03,62.53)
  TOP w0.124: U3.AN1 v2(63.9,63.93)
  L05-SIG2 w0.081: v2(63.9,63.93) 63.9,64.24 63.82,64.33 62.69,64.33 62.6,64.24 62.6,63.65 62.4,63.45 61.9,63.45 61.7,63.65 61.7,64.24 61.62,64.33 61.29,64.33 61.21,64.24 61.21,63.65 61.01,63.45 60.51,63.45 60.31,63.65 60.31,64.24 60.23,64.33 59.9,64.33 59.82,64.24 59.82,63.65 59.62,63.45 59.12,63.45 58.92,63.65 58.92,64.24 58.84,64.33 58.51,64.33 58.43,64.24 58.43,63.65 58.23,63.45 57.73,63.45 57.52,63.65 57.52,64.24 57.44,64.33 57.12,64.33 57.04,64.24 57.04,63.65 56.83,63.45 56.34,63.45 56.13,63.65 56.13,64.24 56.05,64.33 55.73,64.33 55.64,64.24 55.64,63.65 55.44,63.45 54.94,63.45 54.74,63.65 54.74,64.24 54.66,64.33 54.33,64.33 54.25,64.24 54.25,63.65 54.05,63.45 53.55,63.45 53.35,63.65 53.35,64.24 53.27,64.33 50.69,64.33 49.88,65.14 49.88,66.81 49.16,67.53 31.86,67.53 31.78,67.45 31.78,65.35 31.58,65.15 31.08,65.15 30.87,65.35 30.87,67.45 30.79,67.53 30.47,67.53 30.39,67.45 30.39,65.35 30.18,65.15 29.69,65.15 29.48,65.35 29.48,67.45 29.4,67.53 29.08,67.53 28.99,67.45 28.99,65.35 28.79,65.15 25.11,65.15 21.75,61.79 8.77,61.79 v2(8.03,62.53)
FMC1_LA31_N: length 94.5
  TOP w0.099: J48.G34 v2(9.3,63.8)
  TOP w0.124: U3.AE9 v2(71.9,71.93)
  L05-SIG2 w0.081: v2(71.9,71.93) 71.29,71.32 71.29,66.81 71.02,66.53 53.59,66.53 50.49,69.64 42.99,69.64 42.91,69.72 42.91,70.21 42.71,70.41 42.21,70.41 42.01,70.21 42.01,69.72 41.93,69.64 41.6,69.64 41.52,69.72 41.52,70.2 41.32,70.4 40.82,70.4 40.62,70.2 40.62,69.72 40.53,69.64 40.21,69.64 40.13,69.72 40.13,70.33 39.92,70.53 39.43,70.53 39.22,70.33 39.22,69.72 39.14,69.64 38.82,69.64 38.74,69.72 38.74,70.33 38.53,70.53 38.03,70.53 37.83,70.33 37.83,69.72 37.75,69.64 37.43,69.64 37.34,69.72 37.34,70.33 37.14,70.53 36.64,70.53 36.44,70.33 36.44,69.72 36.36,69.64 36.03,69.64 35.95,69.72 35.95,70.33 35.75,70.53 35.25,70.53 35.05,70.33 35.05,69.72 34.97,69.64 34.64,69.64 34.56,69.72 34.56,70.33 34.36,70.53 33.86,70.53 33.66,70.33 33.66,69.72 33.57,69.64 33.25,69.64 33.17,69.72 33.17,70.33 32.97,70.53 32.47,70.53 32.26,70.33 32.26,69.72 32.18,69.64 31.86,69.64 31.78,69.72 31.78,70.33 31.57,70.53 31.08,70.53 30.87,70.33 30.87,69.72 30.79,69.64 30.47,69.64 30.38,69.72 30.38,70.33 30.18,70.53 29.68,70.53 29.48,70.33 29.48,69.72 29.4,69.64 29.07,69.64 28.99,69.72 28.99,70.33 28.79,70.53 28.29,70.53 28.09,70.33 28.09,69.72 28.01,69.64 27.68,69.64 27.6,69.72 27.6,70.33 27.4,70.53 26.9,70.53 26.7,70.33 26.7,69.72 26.62,69.64 26.29,69.64 26.21,69.72 26.21,70.33 26.01,70.53 25.51,70.53 25.3,70.33 25.3,69.72 25.22,69.64 24.9,69.64 24.82,69.72 24.82,70.33 24.61,70.53 24.12,70.53 23.91,70.33 23.91,69.72 23.83,69.64 23.07,69.64 22.73,69.3 22.73,66.25 21,64.52 10.08,64.52 9.83,64.27 9.83,63.88 9.75,63.8 v2(9.3,63.8)
FMC1_LA31_P: length 94.8
  TOP w0.099: J48.G33 v2(10.57,63.8)
  TOP w0.124: U3.AF9 v2(71.9,70.93)
  L05-SIG2 w0.081: v2(10.57,63.8) 10.12,63.8 10.04,63.88 10.04,64.18 10.16,64.31 11.01,64.31 11.14,64.18 11.34,64.18 11.46,64.31 11.66,64.31 11.79,64.18 11.99,64.18 12.11,64.31 12.31,64.31 12.44,64.18 12.64,64.18 12.76,64.31 21.08,64.31 22.94,66.17 22.94,69.22 23.16,69.43 23.92,69.43 24.12,69.64 24.12,70.24 24.2,70.32 24.53,70.32 24.61,70.24 24.61,69.64 24.81,69.43 25.31,69.43 25.51,69.64 25.51,70.24 25.59,70.32 25.92,70.32 26,70.24 26,69.64 26.2,69.43 26.7,69.43 26.9,69.64 26.9,70.24 26.99,70.32 27.31,70.32 27.39,70.24 27.39,69.64 27.6,69.43 28.09,69.43 28.3,69.64 28.3,70.24 28.38,70.32 28.7,70.32 28.78,70.24 28.78,69.64 28.99,69.43 29.49,69.43 29.69,69.64 29.69,70.24 29.77,70.32 30.09,70.32 30.18,70.24 30.18,69.64 30.38,69.43 30.88,69.43 31.08,69.64 31.08,70.24 31.16,70.32 31.49,70.32 31.57,70.24 31.57,69.64 31.77,69.43 32.27,69.43 32.47,69.64 32.47,70.24 32.55,70.32 32.88,70.32 32.96,70.24 32.96,69.64 33.16,69.43 33.66,69.43 33.86,69.64 33.86,70.24 33.95,70.32 34.27,70.32 34.35,70.24 34.35,69.64 34.56,69.43 35.05,69.43 35.26,69.64 35.26,70.24 35.34,70.32 35.66,70.32 35.74,70.24 35.74,69.64 35.95,69.43 36.44,69.43 36.65,69.64 36.65,70.24 36.73,70.32 37.05,70.32 37.14,70.24 37.14,69.64 37.34,69.43 37.84,69.43 38.04,69.64 38.04,70.24 38.12,70.32 38.45,70.32 38.53,70.24 38.53,69.64 38.73,69.43 39.23,69.43 39.43,69.64 39.43,70.24 39.51,70.32 39.84,70.32 39.92,70.24 39.92,69.64 40.12,69.43 40.62,69.43 40.82,69.64 40.82,70.12 40.91,70.2 41.23,70.2 41.31,70.12 41.31,69.64 41.51,69.43 42.01,69.43 42.22,69.64 42.22,70.12 42.3,70.2 42.62,70.2 42.7,70.12 42.7,69.64 42.91,69.43 50.4,69.43 53.51,66.33 71.1,66.33 71.5,66.72 71.5,71.24 71.7,71.43 71.82,71.43 71.9,71.35 v2(71.9,70.93)
FMC1_LA32_N: length 82.8
  TOP w0.124: J48.H38 v2(9.3,58.72) ; U3.AP4 v2(66.9,62.93)
  L05-SIG2 w0.081: v2(66.9,62.93) 66.9,63.28 66.98,63.36 67.14,63.36 67.3,63.2 67.3,62.27 67.1,62.07 66.97,62.07 66.81,61.9 66.81,61.78 66.64,61.61 66.51,61.61 66.35,61.44 66.35,61.32 65.11,60.07 64.6,60.07 64.5,60.17 64.27,60.17 64.18,60.07 58.25,60.07 58.04,59.87 58.04,59.26 57.96,59.18 57.64,59.18 57.56,59.26 57.56,59.87 57.35,60.07 56.86,60.07 56.65,59.87 56.65,59.26 56.57,59.18 56.25,59.18 56.16,59.26 56.16,59.87 55.96,60.07 55.46,60.07 55.26,59.87 55.26,59.26 55.18,59.18 54.85,59.18 54.77,59.26 54.77,59.87 54.57,60.07 54.07,60.07 53.87,59.87 53.87,59.26 53.79,59.18 53.46,59.18 53.38,59.26 53.38,59.87 53.18,60.07 52.68,60.07 52.48,59.87 52.48,59.26 52.4,59.18 52.07,59.18 51.99,59.26 51.99,59.87 51.79,60.07 51.29,60.07 51.08,59.87 51.08,59.26 51,59.18 50.68,59.18 50.6,59.26 50.6,59.87 50.39,60.07 49.9,60.07 49.69,59.87 49.69,59.26 49.61,59.18 49.29,59.18 49.21,59.26 49.21,59.87 49,60.07 30.68,60.07 30.47,59.87 30.47,58.76 30.39,58.68 30.07,58.68 29.99,58.76 29.99,59.87 29.78,60.07 29.28,60.07 29.08,59.87 29.08,58.76 29,58.68 28.67,58.68 28.59,58.76 28.59,59.87 28.39,60.07 27.89,60.07 27.69,59.87 27.69,58.76 27.61,58.68 27.28,58.68 27.2,58.76 27.2,59.87 27,60.07 25.86,60.07 24,58.21 8.83,58.21 8.51,58.53 8.51,58.74 8.59,58.82 9.2,58.82 v2(9.3,58.72)
FMC1_LA32_P: length 82.6
  TOP w0.124: J48.H37 v2(8.03,58.72) ; U3.AN4 v2(66.9,63.93)
  L05-SIG2 w0.081: v2(8.03,58.72) 8.74,58 24.09,58 25.95,59.86 26.91,59.86 26.99,59.78 26.99,58.67 27.2,58.47 27.69,58.47 27.9,58.67 27.9,59.78 27.98,59.86 28.3,59.86 28.39,59.78 28.39,58.67 28.59,58.47 29.09,58.47 29.29,58.67 29.29,59.78 29.37,59.86 29.7,59.86 29.78,59.78 29.78,58.67 29.98,58.47 30.48,58.47 30.68,58.67 30.68,59.78 30.76,59.86 48.92,59.86 49,59.78 49,59.18 49.2,58.97 49.7,58.97 49.9,59.18 49.9,59.78 49.98,59.86 50.31,59.86 50.39,59.78 50.39,59.18 50.59,58.97 51.09,58.97 51.29,59.18 51.29,59.78 51.37,59.86 51.7,59.86 51.78,59.78 51.78,59.18 51.98,58.97 52.48,58.97 52.69,59.18 52.69,59.78 52.77,59.86 53.09,59.86 53.17,59.78 53.17,59.18 53.38,58.97 53.87,58.97 54.08,59.18 54.08,59.78 54.16,59.86 54.48,59.86 54.56,59.78 54.56,59.18 54.77,58.97 55.27,58.97 55.47,59.18 55.47,59.78 55.55,59.86 55.88,59.86 55.96,59.78 55.96,59.18 56.16,58.97 56.66,58.97 56.86,59.18 56.86,59.78 56.94,59.86 57.27,59.86 57.35,59.78 57.35,59.18 57.55,58.97 58.05,58.97 58.25,59.18 58.25,59.78 58.33,59.86 65.19,59.86 67.51,62.19 67.51,63.32 v2(66.9,63.93)
FMC1_LA33_N: length 85.3
  TOP w0.124: J48.G37 10.59,60.02 v2(10.59,60.18) ; U3.AL4 v2(66.9,65.93)
  L05-SIG2 w0.081: v2(66.9,65.93) 66.9,65.59 66.82,65.51 66.49,65.51 66.29,65.31 66.29,62.53 64.72,60.96 31.03,60.96 30.94,61.04 30.94,63.22 30.74,63.42 30.24,63.42 30.04,63.22 30.04,61.04 29.96,60.96 29.63,60.96 29.55,61.04 29.55,63.22 29.35,63.42 28.85,63.42 28.65,63.22 28.65,61.04 28.57,60.96 28.24,60.96 28.16,61.04 28.16,63.22 27.96,63.42 27.46,63.42 27.26,63.22 27.26,61.04 27.17,60.96 26.85,60.96 26.77,61.04 26.77,63.22 26.57,63.42 26.07,63.42 25.86,63.22 25.86,61.04 25.78,60.96 25.1,60.96 23.62,59.48 23.03,59.48 22.95,59.56 22.95,59.86 22.75,60.07 22.25,60.07 22.05,59.86 22.05,59.56 21.97,59.48 21.64,59.48 21.56,59.56 21.56,59.86 21.36,60.07 20.86,60.07 20.65,59.86 20.65,59.56 20.57,59.48 20.25,59.48 20.17,59.56 20.17,59.86 19.96,60.07 19.47,60.07 19.26,59.86 19.26,59.56 19.18,59.48 12.39,59.48 12.29,59.58 12.06,59.58 11.96,59.48 11.74,59.48 11.64,59.58 11.41,59.58 11.31,59.48 11.09,59.48 10.99,59.58 10.76,59.58 10.66,59.48 10.32,59.48 10.06,59.74 10.06,60.1 10.14,60.18 v2(10.59,60.18)
FMC1_LA33_P: length 85
  TOP w0.124: v2(9.32,60.18) 9.48,60.18 J48.G36 ; U3.AM4 v2(66.9,64.93)
  L05-SIG2 w0.081: v2(66.9,64.93) 66.9,65.22 66.82,65.3 66.58,65.3 66.5,65.22 66.5,62.44 64.81,60.75 30.94,60.75 30.74,60.96 30.74,63.13 30.65,63.21 30.33,63.21 30.25,63.13 30.25,60.96 30.04,60.75 29.55,60.75 29.34,60.96 29.34,63.13 29.26,63.21 28.94,63.21 28.86,63.13 28.86,60.96 28.65,60.75 28.16,60.75 27.95,60.96 27.95,63.13 27.87,63.21 27.55,63.21 27.46,63.13 27.46,60.96 27.26,60.75 26.76,60.75 26.56,60.96 26.56,63.13 26.48,63.21 26.15,63.21 26.07,63.13 26.07,60.96 25.87,60.75 25.19,60.75 23.71,59.27 22.95,59.27 22.74,59.48 22.74,59.78 22.66,59.86 22.34,59.86 22.25,59.78 22.25,59.48 22.05,59.27 21.55,59.27 21.35,59.48 21.35,59.78 21.27,59.86 20.94,59.86 20.86,59.78 20.86,59.48 20.66,59.27 20.16,59.27 19.96,59.48 19.96,59.78 19.88,59.86 19.55,59.86 19.47,59.78 19.47,59.48 19.27,59.27 10.23,59.27 9.86,59.65 9.86,60.1 9.77,60.18 v2(9.32,60.18)
FMC1_PG_C2M: length 155
  TOP w0.152: U3.V4 v2(66.9,78.93) ; J48.D1 v2(14.38,105.71)
  L03-SIG1 w0.091: v2(14.38,105.71) 13.97,106.12 5.21,106.12 3.85,104.76 3.85,69.48 4.85,68.47 21.62,68.47 23.14,66.95 34.55,66.95 J10.4
  L05-SIG2 w0.091: v2(14.38,105.71) 16.17,103.92 17.96,103.92 18.34,104.3 38.75,104.3 42.14,100.91 42.14,94.05 54.23,81.96 57.96,81.96 60.63,79.29 66.53,79.29 v2(66.9,78.93)
  BOTTOM w0.152: R83.1 15.65,106.6 14.76,105.71 v2(14.38,105.71)
FMC1_PG_M2C: length 129.3
  TOP w0.152: J48.F1 v2(10.57,105.71) ; U3.W4 v2(66.9,77.93)
  L03-SIG1 w0.091: J10.5 38.36,63.3 39.55,64.48 39.55,66.19 38.28,67.46 23.39,67.46 21.59,69.26 4.95,69.26 4.25,69.97 4.25,104.01 5.35,105.1 9.96,105.1 v2(10.57,105.71)
  BOTTOM w0.127: J10.5 38.36,59.35 39.37,58.34 44.2,58.34 44.7,58.85 44.7,63.67 45.43,64.4 46.73,64.4 47.29,64.96 47.29,67.35 57.45,77.52 66.49,77.52 v2(66.9,77.93)
  BOTTOM w0.152: v2(10.57,105.71) 11.2,106.35 R84.1
FMC1_PRSNT_M2C_L: length 114.5
  TOP w0.152: U3.U7 v2(69.9,80.93) ; J48.H2 v2(8.03,104.44)
  L03-SIG1 w0.091: v2(8.03,104.44) 7.39,103.8 7.39,103 6.94,102.55 5.21,102.55 4.74,102.08 4.74,70.24 5.21,69.77 22.1,69.77 23.79,68.08 38.5,68.08 J10.8
  BOTTOM w0.127: v2(69.9,80.93) 68.77,79.8 63.5,79.8 62.99,79.29 54.08,79.29 40.9,66.12 J10.8
  BOTTOM w0.152: v2(8.03,104.44) 7.49,104.98 7.49,105.71 6.76,106.45 R217.1
FMC1_RES0: length 63.7
  TOP w0.152: U3.W5 v2(67.9,77.93)
  BOTTOM w0.127: R216.2 21.51,55.83 24.25,58.57 37.97,58.57 38.83,57.7 44.2,57.7 47.28,60.79 47.28,63.84 47.85,64.41 48.87,64.41 50.04,65.58 50.04,67.99 57.53,75.48 67.18,75.48 67.31,75.61 67.31,76.12 67.56,76.37 68.07,76.37 68.42,76.72 68.42,77.41 v2(67.9,77.93)
FMC1_RES1: length 62.8
  TOP w0.152: U3.V5 v2(67.9,78.93)
  L05-SIG2 w0.091: v2(21.59,105.2) 38.61,105.2 42.52,101.29 42.52,94.18 54.36,82.34 58.04,82.34 60.83,79.55 67.28,79.55 v2(67.9,78.93)
  BOTTOM w0.152: R215.2 v2(21.59,105.2)
FMC1_SCL: length 81.5
  TOP w0.152: U3.T8 v2(70.9,81.93) ; J48.C30 v2(15.65,67.61)
  L03-SIG1 w0.091: v2(15.65,67.61) 16.03,67.23 18.41,67.23 23.88,61.77 38.61,61.77 39.5,62.66 39.5,63.67 40.13,64.31 42.08,64.31 J10.10
  BOTTOM w0.127: J10.10 42.66,65.68 41.42,64.44 40.14,64.44 39.58,65 39.58,66.08 53.31,79.8 58.29,79.8 59.74,81.25 63.04,81.25 63.37,81.58 70.55,81.58 v2(70.9,81.93)
  BOTTOM w0.152: R90.1 16.16,68.12 v2(15.65,67.61)
FMC1_SDA: length 74.9
  TOP w0.152: U3.U8 v2(70.9,80.93) ; J48.C31 v2(15.65,66.34)
  L03-SIG1 w0.091: J10.14 47.28,64.44 42.8,64.44 42.16,63.8 42.16,62.66 40.39,60.88 23.11,60.88 18.16,65.83 16.16,65.83 v2(15.65,66.34)
  BOTTOM w0.127: J10.14 48.52,67.62 57.4,76.5 67.06,76.5 67.39,76.83 67.39,78.2 67.59,78.4 70.07,78.4 70.28,78.61 70.28,80.31 v2(70.9,80.93)
  BOTTOM w0.152: v2(15.65,66.34) 16.1,66.8 19.25,66.8 R91.1
FMC1_TCK: length 66.4
  TOP w0.152: J48.D29 v2(14.38,68.88)
  BOTTOM w0.127: v2(14.38,68.88) 14.89,69.39 22.23,69.39 30.69,60.93 R92.1
  BOTTOM w0.152: R92.1 35.82,60.96 J10.3 37.08,64.4 37.08,68.16 49.87,80.95 57.66,80.95 59.05,82.34 59.05,84.81 60.07,85.83 R55.1
FMC1_TDI: length 65.9
  TOP w0.127: v2(60.71,78.91) 61.34,78.28 63.75,78.28 63.9,78.43 U3.W1
  TOP w0.152: J48.D30 v2(13.11,67.61)
  L03-SIG1 w0.091: v2(13.11,67.61) 14,66.72 18.19,66.72 23.52,61.39 39.15,61.39 J10.7
  BOTTOM w0.127: v2(60.71,78.91) 60.33,78.53 55.73,78.53 44.5,67.3 44.5,65.06 43.92,64.49 42.77,64.49 41.42,63.14 J10.7
  BOTTOM w0.152: J10.7 40.9,60.96 R85.1
FMC1_TDO: length 65.8
  TOP w0.127: U3.V1 63.67,79.43 63.15,78.91 v2(61.72,78.91)
  TOP w0.152: J48.D31 v2(13.11,66.34)
  L03-SIG1 w0.091: v2(13.11,66.34) 14,65.45 14.73,65.45 15.75,64.44 18.56,64.44 22.62,60.37 40.68,60.37 J10.9
  BOTTOM w0.127: J10.9 44.95,64.65 44.95,66.32 56.66,78.02 60.83,78.02 v2(61.72,78.91)
  BOTTOM w0.152: R86.1 43.44,60.96 J10.9
FMC1_TMS: length 70.7
  TOP w0.152: U3.W7 v2(69.9,77.93) ; J48.D33 v2(14.38,63.8)
  L03-SIG1 w0.091: v2(14.38,63.8) 15.01,63.17 19.01,63.17 22.19,59.99 45.38,59.99 J10.13
  BOTTOM w0.127: v2(69.9,77.93) 69.34,77.37 69.34,76.63 69.09,76.37 68.71,76.37 68.45,76.12 68.45,75.74 68.2,75.48 67.82,75.48 67.44,75.1 67.44,74.72 67.18,74.47 57.28,74.47 50.55,67.74 50.55,65.16 J10.13 48.5,63.11 R87.1
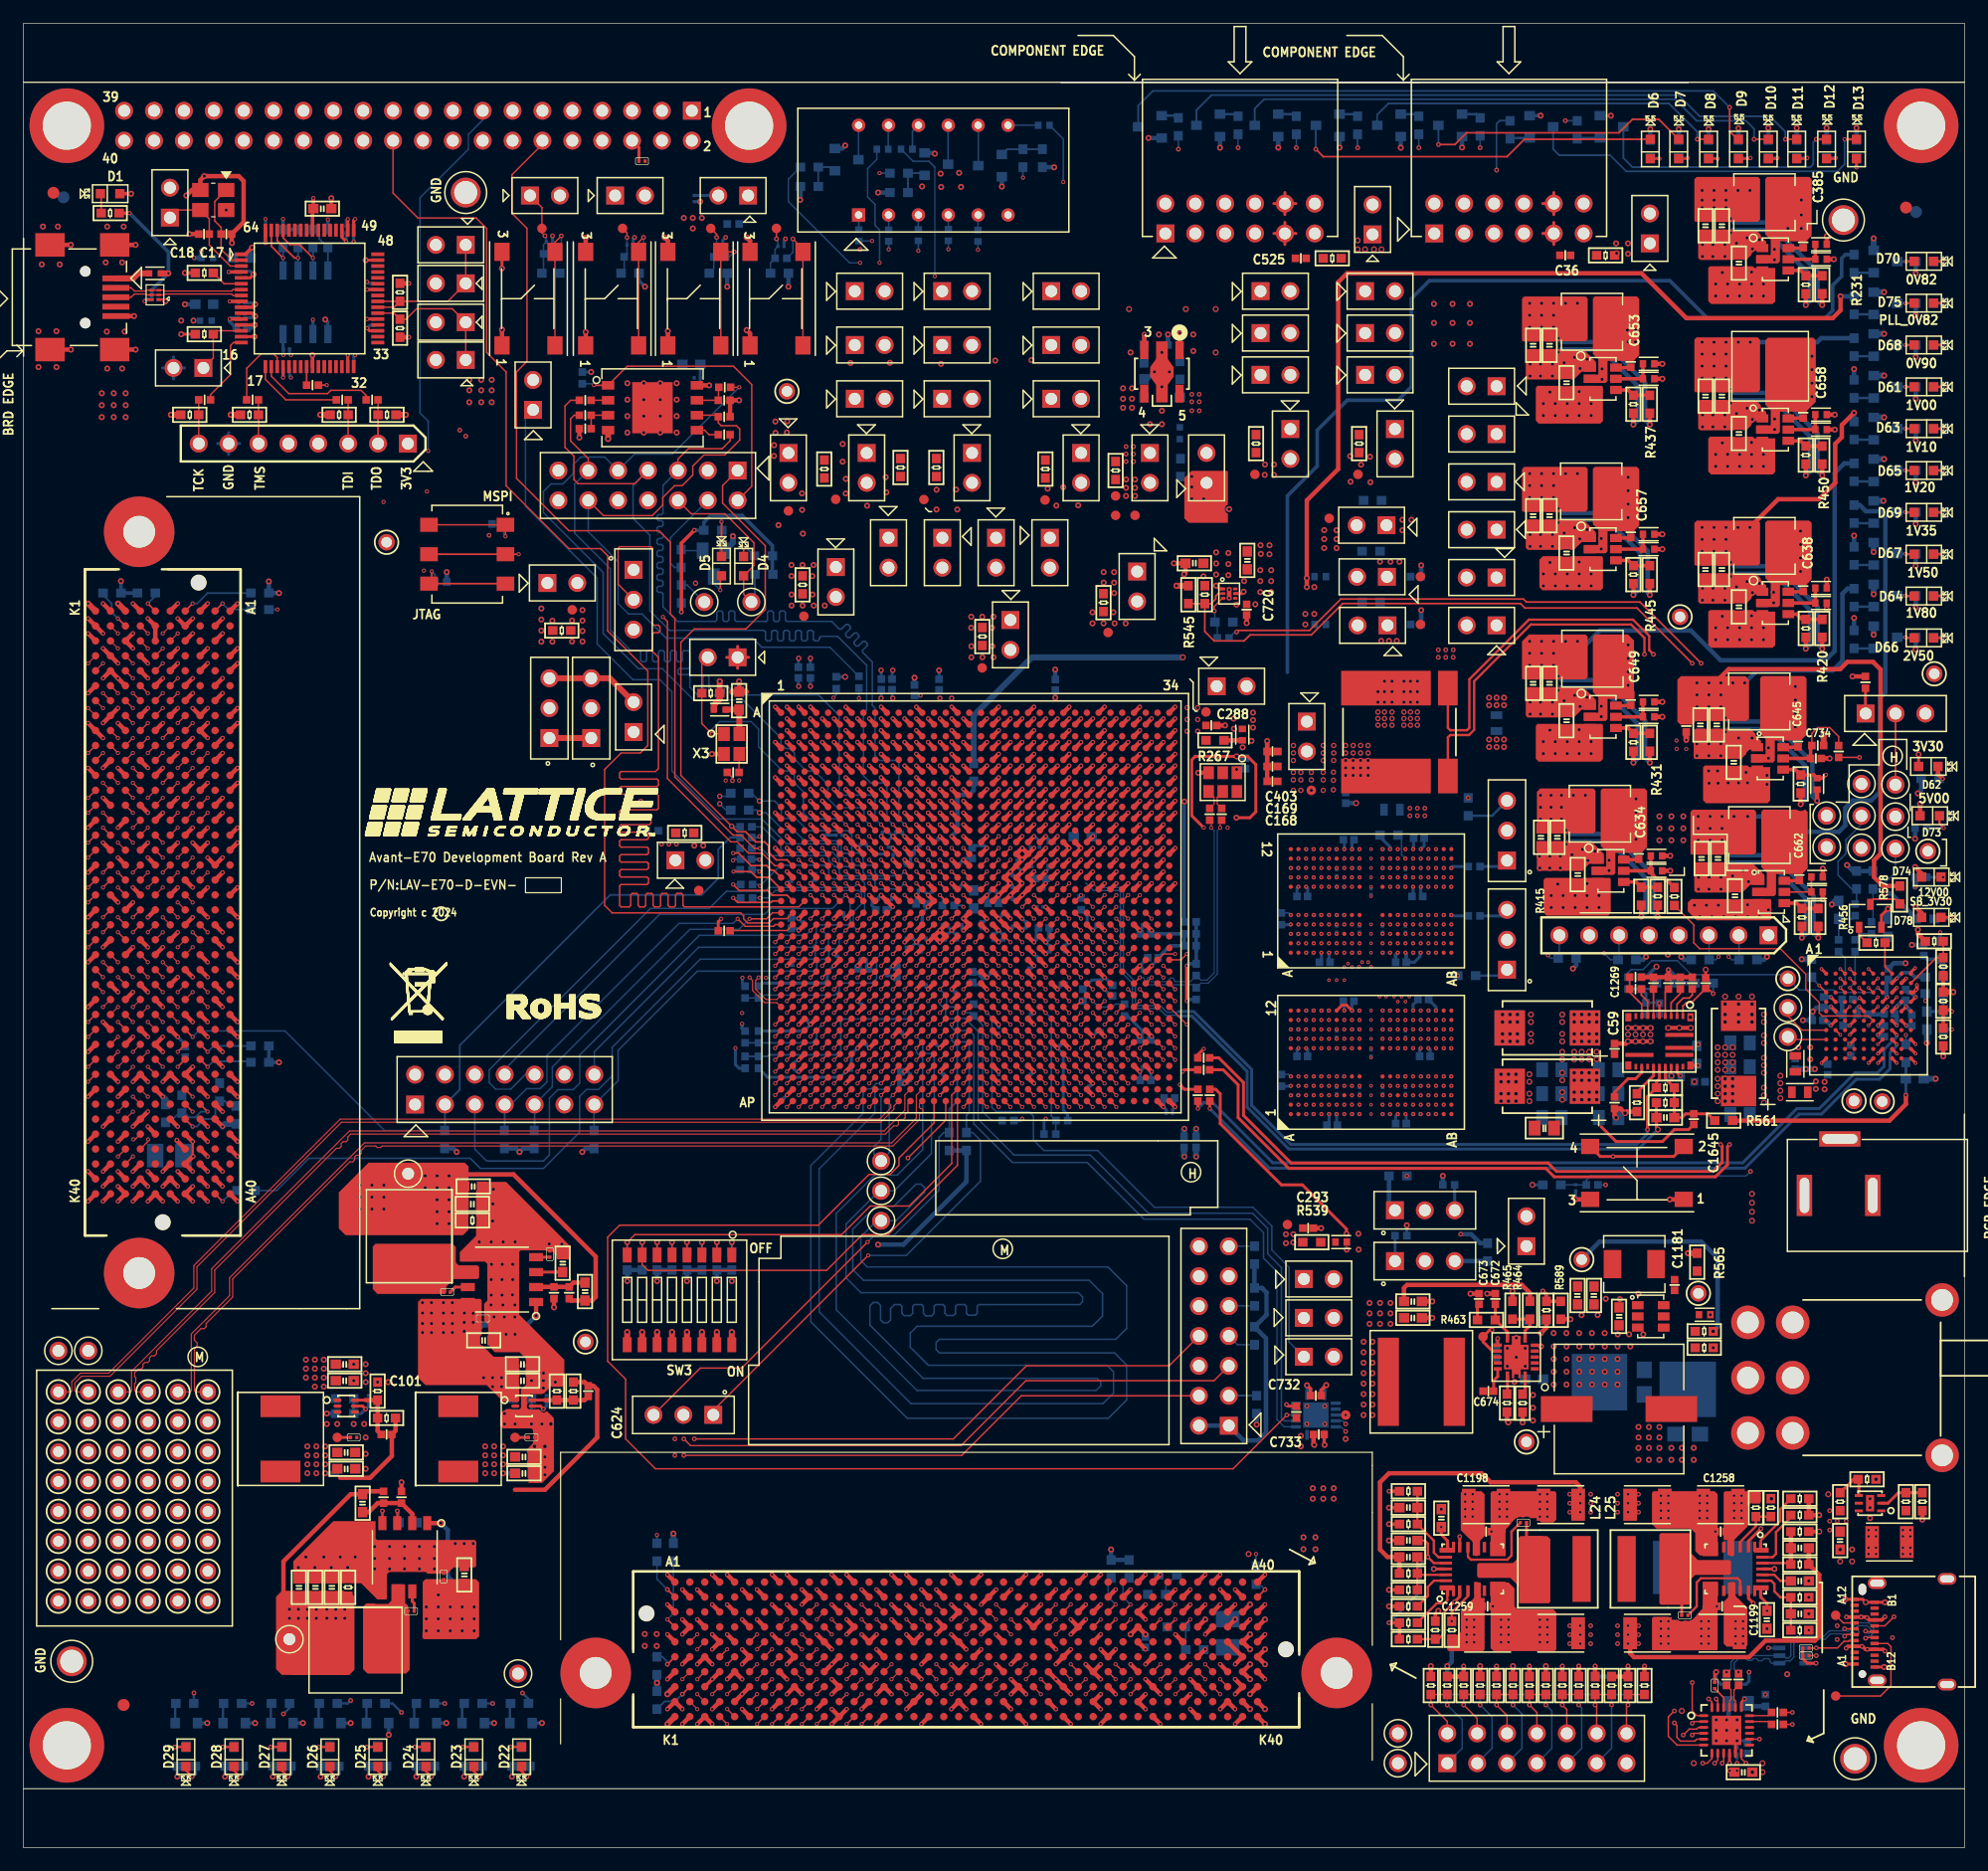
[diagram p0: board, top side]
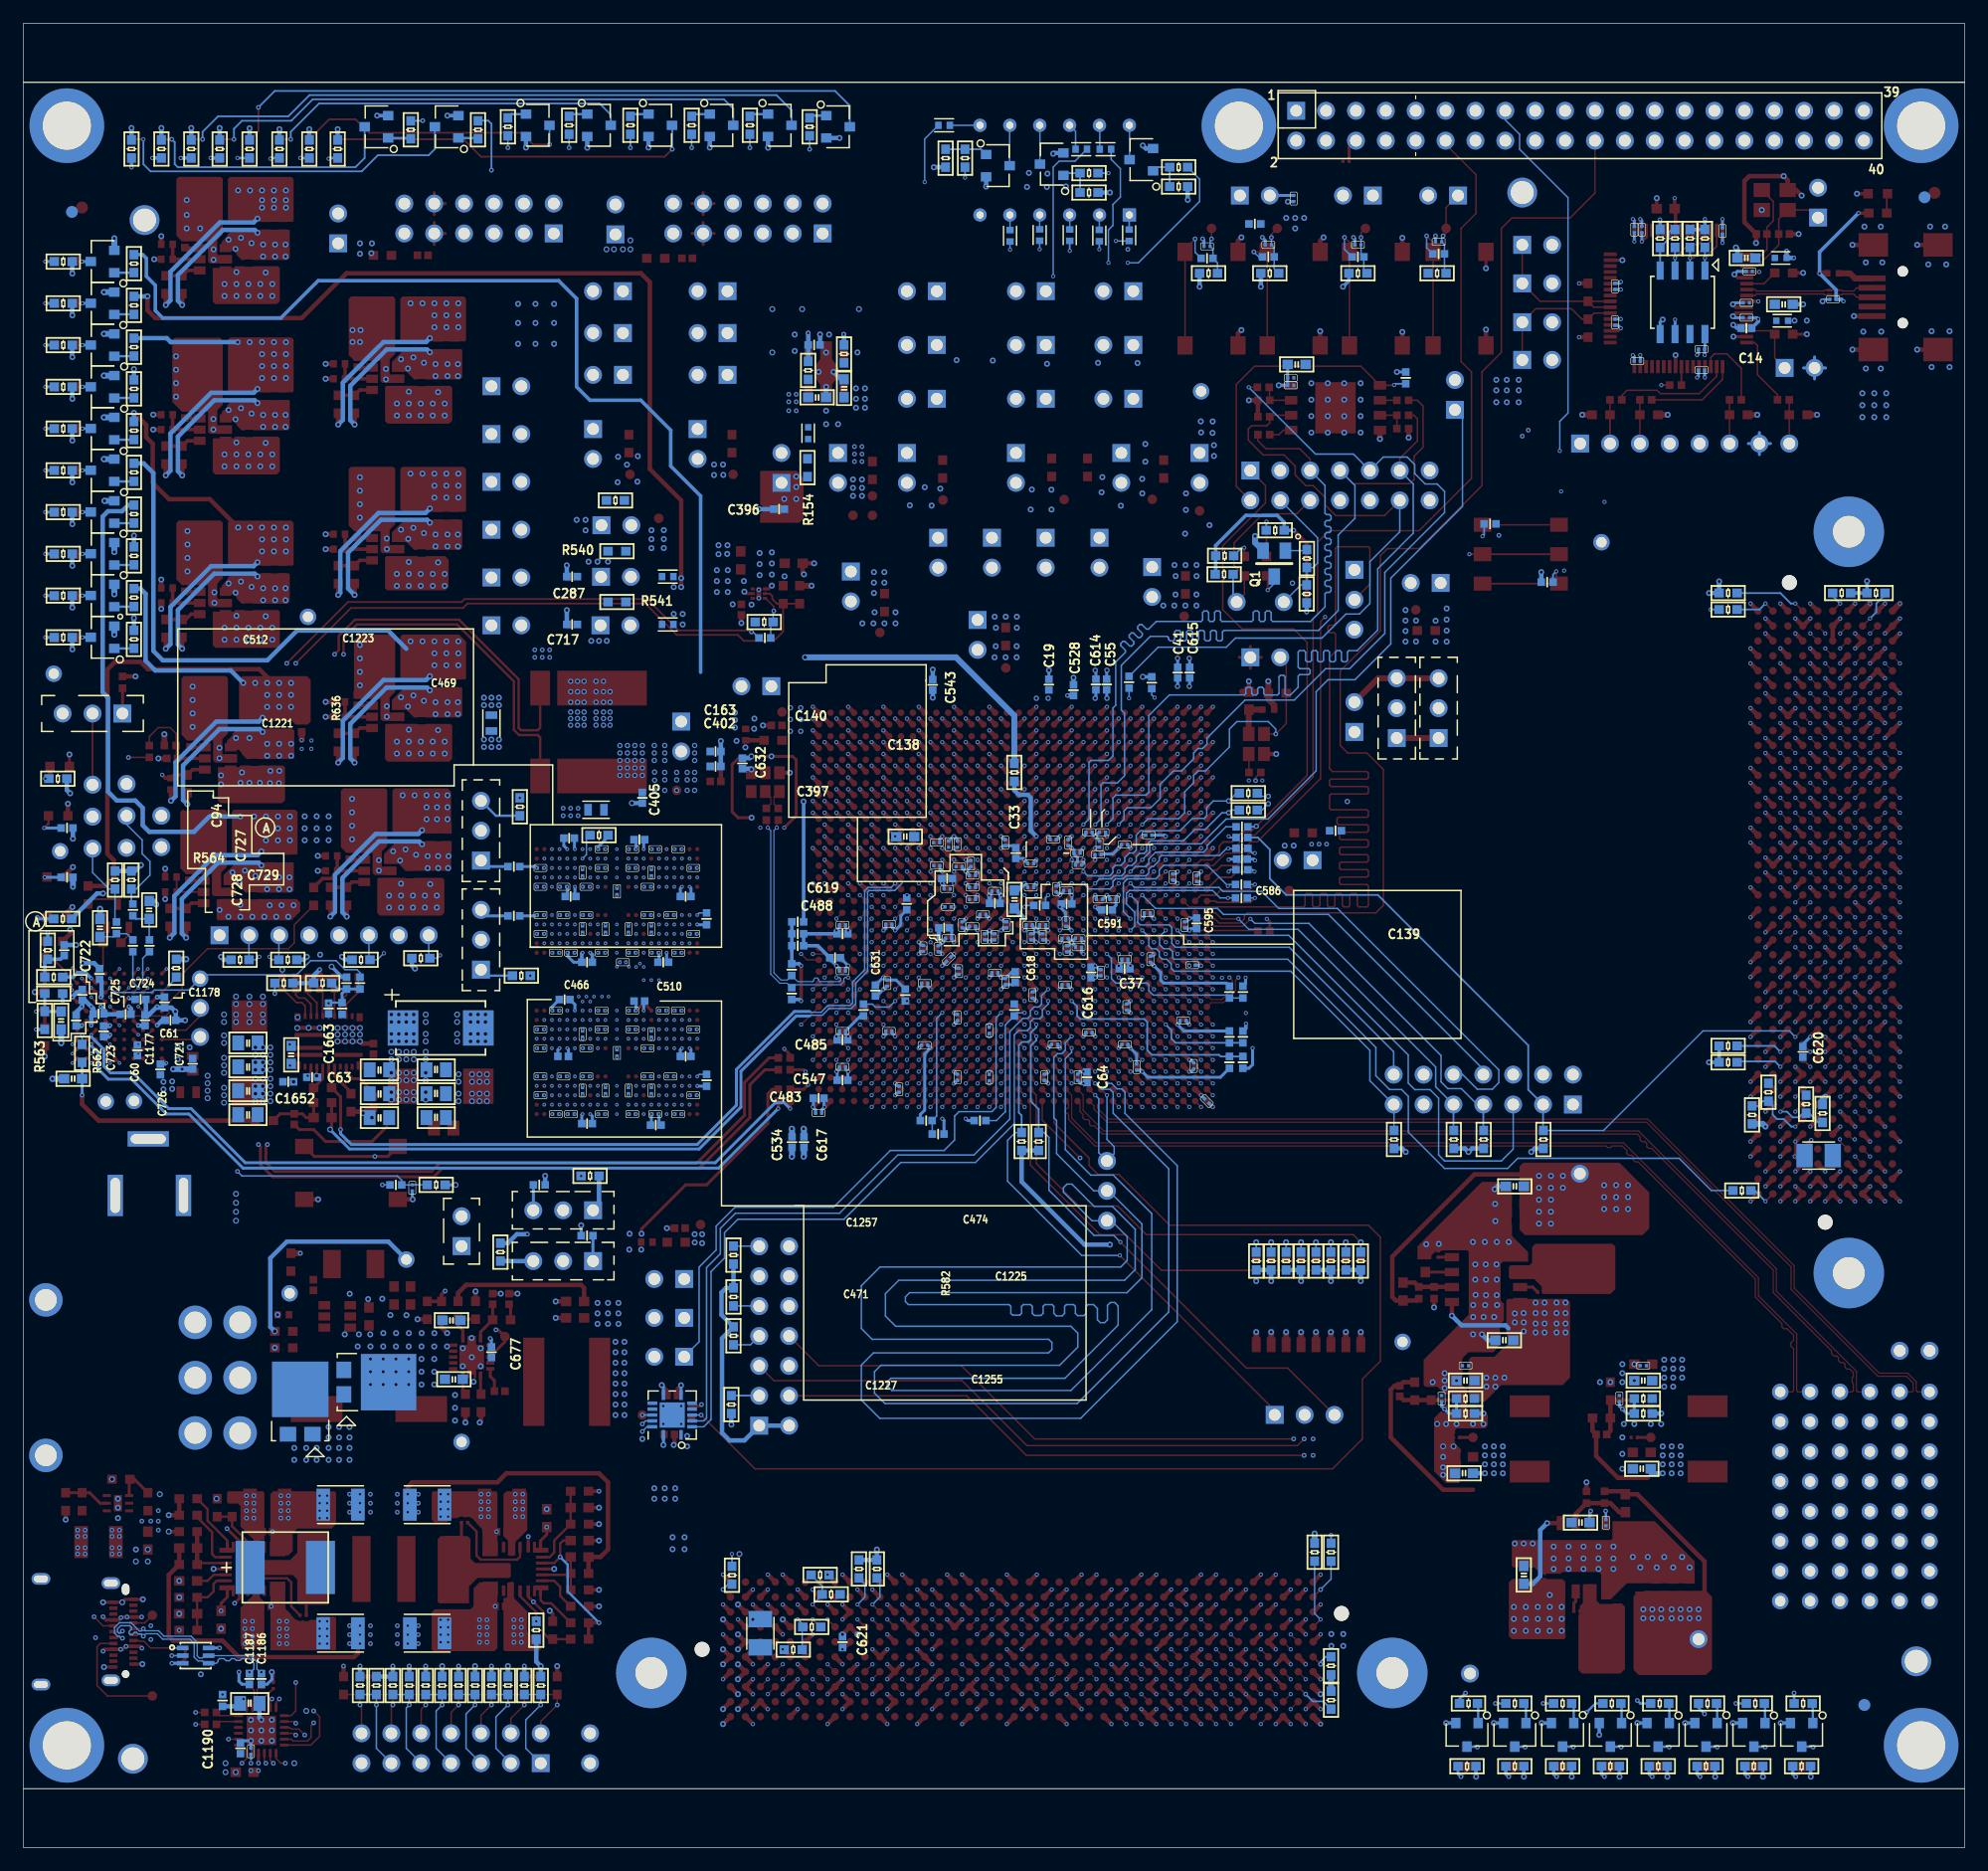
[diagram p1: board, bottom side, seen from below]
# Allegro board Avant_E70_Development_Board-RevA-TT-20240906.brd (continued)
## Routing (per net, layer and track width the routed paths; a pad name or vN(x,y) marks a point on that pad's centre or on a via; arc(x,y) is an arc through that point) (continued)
FMC1_TRST_L: length 38.3
  TOP w0.152: J48.D34 v2(14.38,62.53)
  L03-SIG1 w0.091: J10.6 37.08,64.4 37.08,62.4 36.8,62.12 24.41,62.12 18.54,67.99 12.45,67.99 12.32,67.86 12.32,64.59 v2(14.38,62.53)
FMC1_VREFA: length 48.2
  TOP w0.508: JP89.3 JP88.3 49.83,99.36 JP38.2 ; J48.H1 v2(8.03,105.71)
  L10-SIG3 w0.508: v2(8.03,105.71) J48.H1 19.43,105.08 20.57,103.93 33.27,103.93 37.85,99.36 JP89.3
FMC1_VREFB: length 48.4
  TOP w0.508: JP88.1 JP89.1 ; J48.K1 v2(5.49,105.71)
  L12-SIG4 w0.508: JP89.1 34.67,104.31 19.94,104.31 19.18,105.08 J48.K1 v2(5.49,105.71)
FMC2_CLK0_M2C_N: length 91.4
  TOP w0.124: U3.AH20 v2(83.9,68.93) ; J54.H5 v2(59.82,13.03)
  L10-SIG3 w0.081: v2(83.9,68.93) 83.9,69.24 83.82,69.33 81.73,69.33 81.53,69.13 81.53,53.98 73.59,46.04 65.25,46.04 65.17,45.96 65.17,45.13 64.97,44.93 64.47,44.93 64.27,45.13 64.27,45.96 64.19,46.04 63.86,46.04 63.78,45.96 63.78,45.13 63.58,44.93 63.08,44.93 62.87,45.13 62.87,45.96 62.79,46.04 62.19,46.04 62.01,45.86 62.01,34.45 61.59,34.03 61.59,33.92 62.13,33.38 62.13,33.09 61.78,32.74 61.49,32.74 60.95,33.28 60.83,33.28 60.6,33.05 60.6,32.94 61.14,32.39 61.14,32.11 60.79,31.76 60.5,31.76 59.96,32.3 59.85,32.3 59.29,31.73 59.29,16.15 59.08,15.95 55.61,15.95 55.52,15.87 55.52,15.11 55.61,15.03 59.08,15.03 59.29,14.83 59.29,13.11 59.37,13.03 v2(59.82,13.03)
FMC2_CLK0_M2C_P: length 91.5
  TOP w0.124: U3.AG20 v2(83.9,69.93) ; 59.18,13.66 v2(58.55,13.03)
  L10-SIG3 w0.081: v2(58.55,13.03) 59,13.03 59.08,13.11 59.08,14.74 59,14.82 55.52,14.82 55.32,15.03 55.32,15.95 55.52,16.16 59,16.16 59.08,16.24 59.08,31.82 59.76,32.5 60.05,32.5 60.59,31.96 60.7,31.96 60.93,32.19 60.93,32.31 60.39,32.85 60.39,33.14 60.75,33.49 61.03,33.49 61.57,32.95 61.69,32.95 61.92,33.18 61.92,33.29 61.38,33.83 61.38,34.12 61.8,34.54 61.8,45.94 62.1,46.25 62.88,46.25 63.08,46.05 63.08,45.22 63.16,45.14 63.49,45.14 63.57,45.22 63.57,46.05 63.77,46.25 64.27,46.25 64.47,46.05 64.47,45.22 64.56,45.14 64.88,45.14 64.96,45.22 64.96,46.05 65.17,46.25 73.51,46.25 81.33,54.07 81.33,69.22 81.64,69.53 83.5,69.53 v2(83.9,69.93)
FMC2_CLK1_M2C_N: length 91.1
  TOP w0.124: U3.AE23 v2(86.9,71.93) ; J54.G3 v2(57.28,14.3)
  L12-SIG4 w0.081: v2(57.28,14.3) 57.15,14.3 56.49,13.64 55.75,13.64 55.29,14.1 55.29,23.13 55.49,23.33 55.72,23.33 55.8,23.41 55.8,23.74 55.72,23.82 55.49,23.82 55.29,24.02 55.29,24.9 81.15,50.76 81.15,52.13 81.07,52.21 79.76,52.21 79.55,52.41 79.55,52.91 79.76,53.11 81.07,53.11 81.15,53.2 81.15,53.52 81.07,53.6 79.76,53.6 79.55,53.81 79.55,54.3 79.76,54.51 81.07,54.51 81.15,54.59 81.15,54.91 81.07,54.99 79.76,54.99 79.55,55.2 79.55,55.69 79.76,55.9 81.07,55.9 81.15,55.98 81.15,56.3 81.07,56.39 79.76,56.39 79.55,56.59 79.55,57.09 79.76,57.29 81.07,57.29 81.15,57.37 81.15,72.06 81.62,72.52 85.18,72.52 85.44,72.26 86.26,72.26 86.58,71.93 v2(86.9,71.93)
FMC2_CLK1_M2C_P: length 91.5
  TOP w0.099: 56.64,14.93 v2(56.01,14.3)
  TOP w0.124: U3.AE22 v2(85.9,71.93)
  L12-SIG4 w0.081: v2(85.9,71.93) 85.78,72.05 85.35,72.05 85.09,72.31 83.56,72.31 83.43,72.18 83.23,72.18 83.1,72.31 82.61,72.31 82.48,72.18 82.28,72.18 82.16,72.31 81.7,72.31 81.36,71.97 81.36,71.73 81.46,71.63 81.46,71.4 81.36,71.3 81.36,71.08 81.46,70.98 81.46,70.75 81.36,70.65 81.36,70.43 81.46,70.33 81.46,70.1 81.36,70 81.36,57.28 81.16,57.08 79.84,57.08 79.76,57 79.76,56.68 79.84,56.59 81.16,56.59 81.36,56.39 81.36,55.89 81.16,55.69 79.84,55.69 79.76,55.61 79.76,55.28 79.84,55.2 81.16,55.2 81.36,55 81.36,54.5 81.16,54.3 79.84,54.3 79.76,54.22 79.76,53.89 79.84,53.81 81.16,53.81 81.36,53.61 81.36,53.11 81.16,52.91 79.84,52.91 79.76,52.82 79.76,52.5 79.84,52.42 81.16,52.42 81.36,52.22 81.36,50.67 55.5,24.81 55.5,24.11 55.58,24.03 55.8,24.03 56.01,23.83 56.01,23.33 55.8,23.13 55.58,23.13 55.5,23.04 55.5,17.17 55.58,17.08 55.8,17.08 55.88,17 55.88,16.84 55.8,16.76 55.58,16.76 55.5,16.68 55.5,16.52 55.58,16.43 55.9,16.43 55.98,16.35 55.98,16.19 55.9,16.11 55.58,16.11 55.5,16.03 55.5,15.22 55.58,15.14 55.8,15.14 55.88,15.06 55.88,14.9 55.8,14.82 55.58,14.82 55.5,14.73 55.5,14.18 55.84,13.84 56.41,13.84 56.54,13.98 56.54,14.22 56.46,14.3 v2(56.01,14.3)
FMC2_CLK2_M2C_N: length 84.6
  TOP w0.124: J54.K5 v2(59.82,11.76) ; U3.AN21 v2(84.9,63.93)
  L10-SIG3 w0.081: v2(84.9,63.93) 84.9,63.62 84.82,63.53 84.53,63.53 84.33,63.33 84.33,50.76 83.85,50.28 83.73,50.28 83.03,50.99 82.74,50.99 82.39,50.63 82.39,50.35 83.09,49.64 83.09,49.52 76.09,42.52 65.93,42.52 65.63,42.23 65.63,32.07 64.84,31.27 64.84,30.98 65.11,30.71 65.11,30.6 64.88,30.37 64.76,30.37 64.49,30.64 64.21,30.64 63.85,30.29 63.85,30 64.11,29.74 64.11,29.63 63.88,29.4 63.76,29.4 63.51,29.65 63.22,29.65 62.78,29.22 62.78,17.61 63.16,17.24 66.46,17.24 66.72,16.98 66.72,11.69 66.26,11.23 60.64,11.23 60.49,11.07 59.97,11.07 59.82,11.22 v2(59.82,11.76)
FMC2_CLK2_M2C_P: length 84.2
  TOP w0.124: U3.AP21 v2(84.9,62.93) ; 59.18,11.12 v2(59.82,10.49)
  L10-SIG3 w0.081: v2(59.82,10.49) 60.19,10.86 60.57,10.86 60.73,11.02 66.34,11.02 66.93,11.6 66.93,17.06 66.55,17.45 63.25,17.45 62.99,17.7 62.99,29.13 63.31,29.44 63.42,29.44 63.68,29.19 63.97,29.19 64.32,29.54 64.32,29.83 64.06,30.08 64.06,30.2 64.29,30.43 64.41,30.43 64.68,30.16 64.96,30.16 65.31,30.51 65.31,30.8 65.05,31.07 65.05,31.18 65.84,31.98 65.84,42.14 66.01,42.31 76.17,42.31 83.3,49.44 83.3,49.73 82.59,50.43 82.59,50.55 82.83,50.78 82.94,50.78 83.65,50.07 83.93,50.07 84.54,50.67 84.54,63.24 84.62,63.33 84.82,63.33 84.9,63.24 v2(84.9,62.93)
FMC2_CLK3_M2C_N: length 81.6
  TOP w0.099: J54.J3 v2(57.28,13.03)
  TOP w0.124: U3.AN29 v2(92.9,63.93)
  L03-SIG1 w0.081: v2(57.28,13.03) 57.81,12.5 80.37,12.5 81.94,14.06 81.94,14.46 82.57,15.09 82.74,15.09 83.23,15.58 83.23,15.94 85.82,18.53 85.82,21.14 92.3,27.62 92.3,63.33 v2(92.9,63.93)
FMC2_CLK3_M2C_P: length 82.1
  TOP w0.099: 56.64,12.39 v2(57.28,11.76)
  TOP w0.124: U3.AP29 v2(92.9,62.93)
  L03-SIG1 w0.081: v2(57.28,11.76) 57.28,12.21 57.36,12.29 80.46,12.29 82.14,13.98 82.14,14.37 82.65,14.88 82.83,14.88 83.44,15.49 83.44,15.86 86.03,18.45 86.03,21.05 92.51,27.53 92.51,63.24 92.59,63.32 92.82,63.32 92.9,63.24 v2(92.9,62.93)
FMC2_GA0: length 4.1
  TOP w0.152: 97.28,20.01 v2(97.92,20.65)
  BOTTOM w0.127: R325.2 97.1,22.22 R323.1 97.1,21.46 v2(97.92,20.65)
FMC2_GA1: length 3.7
  TOP w0.152: J54.D35 v2(99.19,19.38)
  BOTTOM w0.127: R326.2 98.81,18.69 R324.1
  BOTTOM w0.152: R324.1 98.76,18.95 v2(99.19,19.38)
FMC2_HA00_CLK_N: length 85.6
  TOP w0.124: J54.F5 v2(59.82,15.57) ; U3.AL24 v2(87.9,65.93)
  L12-SIG4 w0.081: v2(59.82,15.57) 59.82,16.02 59.74,16.1 58.33,16.1 57.81,16.62 57.81,20.39 57.73,20.47 56.92,20.47 56.72,20.67 56.72,21.17 56.92,21.37 57.73,21.37 57.81,21.46 57.81,22.65 57.73,22.73 57.02,22.73 56.82,22.94 56.82,23.43 57.02,23.64 57.73,23.64 57.81,23.72 57.81,24.04 57.73,24.12 57.02,24.12 56.82,24.33 56.82,24.83 57.02,25.03 57.73,25.03 57.81,25.11 57.81,25.76 83.21,51.16 83.21,51.93 83.04,52.09 82.54,52.09 82.34,52.3 82.34,52.79 82.54,53 83.15,53 83.23,53.08 83.23,53.4 83.15,53.49 82.54,53.49 82.34,53.69 82.34,54.19 82.54,54.39 83.15,54.39 83.23,54.47 83.23,54.8 83.15,54.88 82.54,54.88 82.34,55.08 82.34,55.58 82.54,55.78 83.15,55.78 83.23,55.86 83.23,56.19 83.15,56.27 82.42,56.27 82.21,56.47 82.21,56.97 82.42,57.17 83.15,57.17 83.23,57.25 83.23,57.58 83.15,57.66 82.42,57.66 82.21,57.86 82.21,58.36 82.42,58.57 83.15,58.57 83.23,58.65 83.23,58.97 83.15,59.05 82.37,59.05 82.17,59.26 82.17,59.75 82.37,59.96 83.58,59.96 83.66,60.04 83.66,60.36 83.58,60.44 82.37,60.44 82.17,60.65 82.17,61.15 82.37,61.35 83.15,61.35 83.23,61.43 83.23,65.16 83.61,65.53 87.5,65.53 v2(87.9,65.93)
FMC2_HA00_CLK_P: length 85.4
  TOP w0.124: 59.18,16.2 v2(59.82,16.84) ; U3.AM24 v2(87.9,64.93)
  L12-SIG4 w0.081: v2(87.9,64.93) 87.9,65.24 87.82,65.33 84.63,65.33 84.51,65.2 84.28,65.2 84.15,65.33 83.69,65.33 83.44,65.07 83.44,64.69 83.54,64.59 83.54,64.33 83.44,64.23 83.44,61.34 83.24,61.14 82.46,61.14 82.38,61.06 82.38,60.73 82.46,60.65 83.67,60.65 83.87,60.45 83.87,59.95 83.67,59.75 82.46,59.75 82.38,59.67 82.38,59.34 82.46,59.26 83.24,59.26 83.44,59.06 83.44,58.56 83.24,58.36 82.5,58.36 82.42,58.28 82.42,57.95 82.5,57.87 83.24,57.87 83.44,57.67 83.44,57.17 83.24,56.97 82.5,56.97 82.42,56.88 82.42,56.56 82.5,56.48 83.24,56.48 83.44,56.27 83.44,55.78 83.24,55.57 82.63,55.57 82.55,55.49 82.55,55.17 82.63,55.09 83.24,55.09 83.44,54.88 83.44,54.38 83.24,54.18 82.63,54.18 82.55,54.1 82.55,53.77 82.63,53.69 83.24,53.69 83.44,53.49 83.44,52.99 83.24,52.79 82.63,52.79 82.55,52.71 82.55,52.38 82.63,52.3 83.13,52.3 83.41,52.02 83.41,51.08 58.02,25.68 58.02,25.02 57.81,24.82 57.11,24.82 57.03,24.74 57.03,24.41 57.11,24.33 57.81,24.33 58.02,24.13 58.02,23.63 57.81,23.43 57.11,23.43 57.03,23.35 57.03,23.02 57.11,22.94 57.81,22.94 58.02,22.74 58.02,21.37 57.81,21.17 57.01,21.17 56.93,21.09 56.93,20.76 57.01,20.68 57.81,20.68 58.02,20.48 58.02,17.42 58.12,17.32 58.12,17.12 58.02,17.02 58.02,16.71 58.42,16.31 58.73,16.31 58.83,16.4 59.05,16.4 59.15,16.31 59.74,16.31 59.82,16.39 v2(59.82,16.84)
FMC2_HA01_CLK_N: length 86.2
  TOP w0.099: J54.E3 v2(57.28,16.84)
  TOP w0.152: U3.AN17 v2(79.9,63.93)
  L10-SIG3 w0.081: v2(57.28,16.84) 57.28,17.29 57.36,17.37 57.74,17.37 57.99,17.62 57.99,22.92 57.79,23.12 56.42,23.12 56.34,23.2 56.34,23.52 56.42,23.61 57.79,23.61 57.99,23.81 57.99,24.31 57.79,24.51 56.42,24.51 56.34,24.59 56.34,24.92 56.42,25 57.79,25 57.99,25.2 57.99,25.7 57.79,25.9 56.42,25.9 56.34,25.98 56.34,26.31 56.42,26.39 57.79,26.39 57.99,26.59 57.99,27.09 57.79,27.29 56.42,27.29 56.34,27.38 56.34,27.7 56.42,27.78 57.79,27.78 57.99,27.99 57.99,28.48 57.79,28.69 56.42,28.69 56.34,28.77 56.34,29.09 56.42,29.17 57.79,29.17 57.99,29.38 57.99,29.87 57.79,30.08 56.42,30.08 56.34,30.16 56.34,30.48 56.42,30.57 57.79,30.57 57.99,30.77 57.99,31.88 61.09,34.98 61.09,40.6 60.89,40.8 60.34,40.8 60.25,40.89 60.25,41.21 60.34,41.29 60.89,41.29 61.09,41.5 61.09,41.99 60.89,42.2 60.34,42.2 60.25,42.28 60.25,42.6 60.34,42.68 60.89,42.68 61.09,42.89 61.09,46.69 61.51,47.11 73.22,47.11 80.52,54.4 80.52,63.31 v2(79.9,63.93)
FMC2_HA01_CLK_P: length 85.6
  TOP w0.099: 56.64,17.47 v2(57.28,18.11)
  TOP w0.152: U3.AP17 v2(79.9,62.93)
  L10-SIG3 w0.081: v2(57.28,18.11) 57.28,17.66 57.36,17.58 57.66,17.58 57.78,17.7 57.78,22.83 57.7,22.91 56.34,22.91 56.13,23.11 56.13,23.61 56.34,23.81 57.7,23.81 57.78,23.9 57.78,24.22 57.7,24.3 56.34,24.3 56.13,24.51 56.13,25 56.34,25.21 57.7,25.21 57.78,25.29 57.78,25.61 57.7,25.69 56.34,25.69 56.13,25.9 56.13,26.4 56.34,26.6 57.7,26.6 57.78,26.68 57.78,27 57.7,27.09 56.34,27.09 56.13,27.29 56.13,27.79 56.34,27.99 57.7,27.99 57.78,28.07 57.78,28.4 57.7,28.48 56.34,28.48 56.13,28.68 56.13,29.18 56.34,29.38 57.7,29.38 57.78,29.46 57.78,29.79 57.7,29.87 56.34,29.87 56.13,30.07 56.13,30.57 56.34,30.77 57.7,30.77 57.78,30.86 57.78,31.96 60.88,35.06 60.88,40.51 60.8,40.6 60.25,40.6 60.05,40.8 60.05,41.3 60.25,41.5 60.8,41.5 60.88,41.58 60.88,41.91 60.8,41.99 60.25,41.99 60.05,42.19 60.05,42.69 60.25,42.89 60.8,42.89 60.88,42.97 60.88,46.77 61.43,47.32 73.14,47.32 80.31,54.49 80.31,63.22 80.22,63.32 79.98,63.32 79.9,63.24 v2(79.9,62.93)
FMC2_HA02_N: length 81.8
  TOP w0.124: U3.AN26 v2(89.9,63.93) ; 64.26,11.12 v2(63.63,10.49)
  L12-SIG4 w0.081: v2(63.63,10.49) 63.18,10.49 63.1,10.41 63.1,10.16 63.18,10.08 64.02,10.08 64.17,10.23 64.35,10.23 64.5,10.08 65.23,10.08 65.45,10.3 65.45,10.64 65.33,10.77 65.33,10.97 65.45,11.09 65.45,11.45 65.35,11.55 65.35,11.78 65.45,11.87 65.45,12.1 65.35,12.2 65.35,12.43 65.45,12.52 65.45,12.75 65.35,12.85 65.35,13.08 65.45,13.17 65.45,13.4 65.35,13.5 65.35,13.73 65.45,13.82 65.45,14.25 65.35,14.34 65.35,14.57 65.45,14.67 65.45,14.9 65.35,14.99 65.35,15.22 65.45,15.32 65.45,15.55 65.35,15.64 65.35,15.87 65.45,15.97 65.45,26.13 66.14,26.82 66.14,26.93 65.51,27.56 65.51,27.85 65.86,28.2 66.15,28.2 66.78,27.57 66.89,27.57 67.12,27.8 67.12,27.91 66.37,28.67 66.37,28.95 66.72,29.31 67.01,29.31 67.76,28.55 67.88,28.55 68.11,28.79 68.11,28.9 67.37,29.64 67.37,29.93 67.72,30.28 68.01,30.28 68.75,29.54 68.86,29.54 69.09,29.77 69.09,29.88 68.35,30.62 68.35,30.91 68.71,31.26 68.99,31.26 69.73,30.52 69.85,30.52 70.08,30.76 70.08,30.87 69.58,31.37 69.58,31.65 69.93,32.01 70.22,32.01 70.72,31.51 70.83,31.51 71.06,31.74 71.06,31.85 70.6,32.31 70.6,32.6 70.96,32.95 71.24,32.95 71.7,32.49 71.82,32.49 89.33,50 89.33,63.33 89.53,63.53 89.82,63.53 89.9,63.62 v2(89.9,63.93)
FMC2_HA02_P: length 81.4
  TOP w0.124: J54.K7 v2(62.36,10.49) ; U3.AP26 v2(89.9,62.93)
  L12-SIG4 w0.081: v2(89.9,62.93) 89.9,63.24 89.82,63.33 89.62,63.33 89.53,63.24 89.53,49.92 71.9,32.29 71.62,32.29 71.16,32.75 71.04,32.75 70.81,32.52 70.81,32.4 71.27,31.94 71.27,31.65 70.92,31.3 70.63,31.3 70.13,31.8 70.02,31.8 69.79,31.57 69.79,31.45 70.29,30.96 70.29,30.67 69.93,30.32 69.65,30.32 68.91,31.05 68.79,31.05 68.56,30.82 68.56,30.71 69.3,29.97 69.3,29.68 68.95,29.33 68.66,29.33 67.92,30.07 67.81,30.07 67.58,29.84 67.58,29.72 68.32,28.99 68.32,28.7 67.96,28.35 67.68,28.35 66.92,29.1 66.81,29.1 66.58,28.87 66.58,28.75 67.33,28 67.33,27.71 66.98,27.36 66.69,27.36 66.06,27.99 65.94,27.99 65.71,27.76 65.71,27.65 66.35,27.02 66.35,26.73 65.66,26.04 65.66,10.22 65.31,9.87 63.09,9.87 62.89,10.07 62.89,10.41 62.81,10.49 v2(62.36,10.49)
FMC2_HA03_N: length 82.7
  TOP w0.124: J54.J7 v2(62.36,11.76) ; U3.AP24 v2(87.9,62.93)
  L12-SIG4 w0.081: v2(87.9,62.93) 87.9,63.24 87.82,63.33 87.67,63.33 87.58,63.24 87.58,52.58 86.39,51.39 86.39,51.27 87.02,50.65 87.02,50.36 86.67,50.01 86.38,50.01 85.75,50.64 85.64,50.64 85.41,50.4 85.41,50.29 86.1,49.6 86.1,49.31 85.75,48.96 85.46,48.96 84.77,49.65 84.66,49.65 84.42,49.42 84.42,49.3 85.16,48.57 85.16,48.28 84.81,47.93 84.52,47.93 83.78,48.67 83.67,48.67 83.44,48.43 83.44,48.32 84.17,47.59 84.17,47.31 83.81,46.95 83.53,46.95 82.8,47.68 82.69,47.68 82.45,47.45 82.45,47.33 83.19,46.6 83.19,46.31 82.84,45.96 82.55,45.96 81.81,46.7 81.7,46.7 81.47,46.46 81.47,46.35 82.22,45.6 82.22,45.31 81.87,44.96 81.58,44.96 80.83,45.71 80.72,45.71 80.48,45.48 80.48,45.36 81.21,44.64 81.21,44.35 80.86,44 80.57,44 79.84,44.73 79.73,44.73 79.5,44.49 79.5,44.38 80.28,43.6 80.28,43.32 79.92,42.96 79.64,42.96 78.86,43.74 78.75,43.74 63.07,28.07 63.07,12.54 62.82,12.29 62.44,12.29 62.36,12.21 v2(62.36,11.76)
FMC2_HA03_P: length 82.7
  TOP w0.124: 61.72,12.39 v2(62.36,13.03) ; U3.AN24 v2(87.9,63.93)
  L12-SIG4 w0.081: v2(87.9,63.93) 87.9,63.62 87.82,63.53 87.58,63.53 87.38,63.33 87.38,52.67 86.19,51.48 86.19,51.19 86.81,50.56 86.81,50.45 86.58,50.22 86.47,50.22 85.84,50.84 85.55,50.84 85.2,50.49 85.2,50.2 85.89,49.52 85.89,49.4 85.66,49.17 85.54,49.17 84.86,49.86 84.57,49.86 84.22,49.51 84.22,49.22 84.95,48.48 84.95,48.36 84.72,48.13 84.61,48.13 83.87,48.87 83.58,48.87 83.23,48.52 83.23,48.23 83.96,47.51 83.96,47.39 83.73,47.16 83.61,47.16 82.89,47.89 82.6,47.89 82.25,47.54 82.25,47.25 82.98,46.51 82.98,46.39 82.75,46.16 82.64,46.16 81.9,46.9 81.61,46.9 81.26,46.55 81.26,46.26 82.01,45.51 82.01,45.4 81.78,45.17 81.67,45.17 80.92,45.92 80.63,45.92 80.28,45.57 80.28,45.28 81,44.55 81,44.44 80.77,44.21 80.66,44.21 79.93,44.93 79.64,44.93 79.29,44.58 79.29,44.29 80.07,43.52 80.07,43.4 79.84,43.17 79.72,43.17 78.95,43.95 78.66,43.95 62.87,28.15 62.87,12.62 62.74,12.5 62.44,12.5 62.36,12.58 v2(62.36,13.03)
FMC2_HA04_N: length 82.3
  TOP w0.124: U3.AP25 v2(88.9,62.93) ; 64.26,16.2 v2(63.63,15.57)
  L12-SIG4 w0.081: v2(63.63,15.57) 63.63,16.02 63.71,16.1 64.1,16.1 64.34,16.34 64.34,24.58 64.42,24.66 64.67,24.66 64.87,24.86 64.87,25.36 64.67,25.56 63.99,25.56 63.91,25.64 63.91,25.92 64.04,26.05 64.67,26.05 64.87,26.25 64.87,26.75 64.67,26.95 64.01,26.95 63.93,27.03 63.93,27.62 70.87,34.56 70.99,34.56 71.67,33.87 71.96,33.87 72.31,34.22 72.31,34.51 71.63,35.2 71.63,35.31 71.86,35.54 71.97,35.54 72.66,34.85 72.95,34.85 73.3,35.21 73.3,35.49 72.61,36.18 72.61,36.3 72.84,36.53 72.96,36.53 73.65,35.84 73.93,35.84 74.28,36.19 74.28,36.48 73.6,37.17 73.6,37.28 73.83,37.51 73.94,37.51 74.63,36.82 74.92,36.82 75.27,37.18 75.27,37.46 74.58,38.15 74.58,38.27 74.81,38.5 74.93,38.5 75.62,37.81 75.9,37.81 76.25,38.16 76.25,38.45 75.57,39.14 75.57,39.25 75.8,39.48 75.91,39.48 76.6,38.79 76.89,38.79 77.24,39.15 77.24,39.43 76.55,40.12 76.55,40.24 76.78,40.47 76.9,40.47 77.59,39.78 77.87,39.78 78.22,40.13 78.22,40.42 77.54,41.11 77.54,41.22 77.77,41.45 77.88,41.45 78.57,40.76 78.86,40.76 79.21,41.12 79.21,41.4 78.57,42.05 78.57,42.2 78.75,42.39 78.92,42.39 79.56,41.75 79.84,41.75 88.52,50.43 88.52,63.22 88.59,63.29 88.82,63.29 88.9,63.21 v2(88.9,62.93)
FMC2_HA04_P: length 82.2
  TOP w0.124: J54.F7 v2(63.63,16.84) ; U3.AN25 v2(88.9,63.93)
  L12-SIG4 w0.081: v2(88.9,63.93) 88.31,63.34 88.31,50.51 79.76,41.96 79.64,41.96 79,42.59 78.67,42.59 78.36,42.29 78.36,41.96 79,41.32 79,41.2 78.77,40.97 78.66,40.97 77.97,41.66 77.68,41.66 77.33,41.31 77.33,41.02 78.02,40.33 78.02,40.22 77.79,39.99 77.67,39.99 76.98,40.68 76.7,40.68 76.34,40.32 76.34,40.03 77.03,39.35 77.03,39.23 76.8,39 76.69,39 76,39.69 75.71,39.69 75.36,39.34 75.36,39.05 76.05,38.36 76.05,38.25 75.82,38.02 75.7,38.02 75.01,38.71 74.73,38.71 74.37,38.35 74.37,38.06 75.06,37.38 75.06,37.26 74.83,37.03 74.72,37.03 74.03,37.72 73.74,37.72 73.39,37.37 73.39,37.08 74.08,36.39 74.08,36.28 73.85,36.05 73.73,36.05 73.04,36.74 72.76,36.74 72.4,36.38 72.4,36.09 73.09,35.41 73.09,35.29 72.86,35.06 72.75,35.06 72.06,35.75 71.77,35.75 71.42,35.4 71.42,35.11 72.11,34.42 72.11,34.31 71.88,34.08 71.76,34.08 71.07,34.76 70.79,34.76 63.72,27.7 63.72,26.95 63.93,26.74 64.58,26.74 64.66,26.66 64.66,26.34 64.58,26.26 63.95,26.26 63.7,26 63.7,25.56 63.9,25.35 64.58,25.35 64.66,25.27 64.66,24.95 64.58,24.87 64.34,24.87 64.13,24.66 64.13,16.43 64.01,16.31 63.71,16.31 63.63,16.39 v2(63.63,16.84)
FMC2_HA05_N: length 84.3
  TOP w0.124: U3.AM25 v2(88.9,64.93) ; J54.E7 v2(62.36,16.84)
  L12-SIG4 w0.081: v2(62.36,16.84) 62.36,17.29 62.28,17.37 61.89,17.37 61.62,17.64 61.62,23.89 61.54,23.97 60.55,23.97 60.35,24.17 60.35,24.64 60.55,24.85 61.54,24.85 61.62,24.93 61.62,25.25 61.54,25.34 60.6,25.34 60.4,25.54 60.4,26.04 60.6,26.24 61.54,26.24 61.62,26.32 61.62,28.18 86.23,52.79 86.23,54.41 86.15,54.49 84.55,54.49 84.35,54.7 84.35,55.19 84.55,55.4 86.15,55.4 86.23,55.48 86.23,55.8 86.15,55.88 84.53,55.88 84.32,56.09 84.32,56.59 84.53,56.79 86.15,56.79 86.23,56.87 86.23,57.2 86.15,57.28 84.53,57.28 84.32,57.48 84.32,57.98 84.53,58.18 86.15,58.18 86.23,58.26 86.23,58.59 86.15,58.67 84.53,58.67 84.32,58.87 84.32,59.37 84.53,59.57 86.15,59.57 86.23,59.65 86.23,59.98 86.15,60.06 84.96,60.06 84.75,60.26 84.75,60.76 84.96,60.96 86.15,60.96 86.23,61.05 86.23,64.1 86.7,64.56 89.17,64.56 89.26,64.64 89.26,64.82 89.15,64.93 v2(88.9,64.93)
FMC2_HA05_P: length 83.8
  TOP w0.124: 61.72,17.47 v2(62.36,18.11) ; U3.AM26 v2(89.9,64.93)
  L12-SIG4 w0.081: v2(62.36,18.11) 62.36,17.66 62.28,17.58 61.98,17.58 61.83,17.73 61.83,23.97 61.62,24.18 60.63,24.18 60.55,24.26 60.55,24.56 60.63,24.64 61.62,24.64 61.83,24.84 61.83,25.34 61.62,25.54 60.69,25.54 60.6,25.63 60.6,25.95 60.69,26.03 61.62,26.03 61.83,26.23 61.83,28.09 86.44,52.71 86.44,54.5 86.24,54.7 84.64,54.7 84.56,54.78 84.56,55.11 84.64,55.19 86.24,55.19 86.44,55.39 86.44,55.89 86.24,56.09 84.61,56.09 84.53,56.17 84.53,56.5 84.61,56.58 86.24,56.58 86.44,56.78 86.44,57.28 86.24,57.48 84.61,57.48 84.53,57.57 84.53,57.89 84.61,57.97 86.24,57.97 86.44,58.18 86.44,58.67 86.24,58.88 84.61,58.88 84.53,58.96 84.53,59.28 84.61,59.36 86.24,59.36 86.44,59.57 86.44,60.07 86.24,60.27 85.04,60.27 84.96,60.35 84.96,60.68 85.04,60.76 86.24,60.76 86.44,60.96 86.44,64.01 86.79,64.35 89.32,64.35 v2(89.9,64.93)
FMC2_HA06_N: length 85.3
  TOP w0.124: J54.K11 v2(67.44,10.49) ; U3.AK26 v2(89.9,66.93)
  L12-SIG4 w0.081: v2(67.44,10.49) 66.99,10.49 66.91,10.57 66.91,25.38 67.68,26.15 67.79,26.15 68.36,25.59 68.64,25.59 69,25.94 69,26.23 68.43,26.79 68.43,26.91 68.66,27.14 68.78,27.14 69.34,26.57 69.63,26.57 69.98,26.92 69.98,27.21 69.41,27.78 69.41,27.89 69.65,28.12 69.76,28.12 70.33,27.56 70.61,27.56 70.97,27.91 70.97,28.2 70.4,28.76 70.4,28.88 84.7,43.18 84.82,43.18 85.4,42.6 85.69,42.6 86.04,42.96 86.04,43.24 85.46,43.82 85.46,43.94 85.69,44.17 85.8,44.17 86.54,43.44 86.82,43.44 87.17,43.79 87.17,44.08 86.44,44.81 86.44,44.92 86.67,45.15 86.79,45.15 87.52,44.42 87.81,44.42 88.16,44.77 88.16,45.06 87.43,45.79 87.43,45.91 87.66,46.14 87.77,46.14 88.51,45.41 88.79,45.41 89.14,45.76 89.14,46.05 88.41,46.78 88.41,46.89 88.64,47.12 88.76,47.12 89.49,46.39 89.78,46.39 90.13,46.74 90.13,47.03 89.42,47.74 89.42,47.9 90.51,48.98 90.51,66.27 90.21,66.57 89.98,66.57 89.9,66.65 v2(89.9,66.93)
FMC2_HA06_P: length 85
  TOP w0.124: U3.AL26 v2(89.9,65.93) ; 66.8,11.12 v2(66.17,10.49)
  L12-SIG4 w0.081: v2(66.17,10.49) 66.62,10.49 66.7,10.57 66.7,25.47 67.59,26.36 67.88,26.36 68.44,25.8 68.56,25.8 68.79,26.03 68.79,26.14 68.22,26.71 68.22,26.99 68.57,27.35 68.86,27.35 69.43,26.78 69.54,26.78 69.77,27.01 69.77,27.13 69.21,27.69 69.21,27.98 69.56,28.33 69.85,28.33 70.41,27.77 70.53,27.77 70.76,28 70.76,28.11 70.19,28.68 70.19,28.96 84.62,43.39 84.91,43.39 85.48,42.81 85.6,42.81 85.83,43.04 85.83,43.16 85.25,43.74 85.25,44.02 85.6,44.38 85.89,44.38 86.62,43.64 86.74,43.64 86.97,43.87 86.97,43.99 86.24,44.72 86.24,45.01 86.59,45.36 86.88,45.36 87.61,44.63 87.72,44.63 87.95,44.86 87.95,44.97 87.22,45.71 87.22,45.99 87.57,46.35 87.86,46.35 88.59,45.61 88.71,45.61 88.94,45.84 88.94,45.96 88.21,46.69 88.21,46.98 88.56,47.33 88.85,47.33 89.58,46.6 89.69,46.6 89.92,46.83 89.92,46.94 89.22,47.65 89.22,47.99 90.3,49.07 90.3,66.19 90.12,66.36 89.98,66.36 89.9,66.28 v2(89.9,65.93)
FMC2_HA07_N: length 87.8
  TOP w0.124: 66.8,12.39 v2(66.17,11.76) ; U3.AM20 v2(83.9,64.93)
  L10-SIG3 w0.081: v2(66.17,11.76) 65.72,11.76 65.64,11.84 65.64,15.74 65.12,16.26 62.28,16.26 61.72,16.81 61.72,29.47 64.85,32.6 64.85,42.99 65.14,43.27 73.88,43.27 74.08,43.48 74.08,44.06 74.16,44.14 74.49,44.14 74.57,44.06 74.57,43.48 74.77,43.27 75.52,43.27 76.39,44.14 76.39,44.43 75.7,45.11 75.7,45.23 75.93,45.46 76.05,45.46 76.74,44.77 77.02,44.77 77.38,45.12 77.38,45.41 76.69,46.1 76.69,46.21 76.92,46.44 77.03,46.44 77.72,45.76 78.01,45.76 78.36,46.11 78.36,46.4 77.67,47.08 77.67,47.2 77.9,47.43 78.02,47.43 78.71,46.74 78.99,46.74 79.35,47.09 79.35,47.38 78.66,48.07 78.66,48.18 78.89,48.41 79,48.41 79.69,47.73 79.98,47.73 80.33,48.08 80.33,48.37 79.64,49.05 79.64,49.17 79.87,49.4 79.99,49.4 80.59,48.8 80.88,48.8 81.23,49.15 81.23,49.44 80.63,50.04 80.63,50.15 83.49,53.02 83.49,61.69 83.59,61.79 83.59,61.97 83.49,62.07 83.49,62.33 83.59,62.43 83.59,62.68 83.49,62.78 83.49,63.29 83.62,63.42 83.62,63.65 83.49,63.78 83.49,64.26 83.62,64.39 83.62,64.56 83.49,64.69 83.49,65.23 83.64,65.38 83.82,65.38 83.9,65.29 v2(83.9,64.93)
FMC2_HA07_P: length 87.5
  TOP w0.124: J54.J9 v2(64.9,11.76) ; U3.AL20 v2(83.9,65.93)
  L10-SIG3 w0.081: v2(83.9,65.93) 83.28,65.31 83.28,53.1 80.42,50.24 80.42,49.95 81.02,49.35 81.02,49.23 80.79,49 80.68,49 80.07,49.61 79.79,49.61 79.43,49.26 79.43,48.97 80.12,48.28 80.12,48.17 79.89,47.94 79.78,47.94 79.09,48.62 78.8,48.62 78.45,48.27 78.45,47.98 79.14,47.3 79.14,47.18 78.91,46.95 78.79,46.95 78.1,47.64 77.82,47.64 77.46,47.29 77.46,47 78.15,46.31 78.15,46.2 77.92,45.97 77.81,45.97 77.12,46.65 76.83,46.65 76.48,46.3 76.48,46.01 77.17,45.33 77.17,45.21 76.94,44.98 76.82,44.98 76.13,45.67 75.85,45.67 75.49,45.32 75.49,45.03 76.18,44.34 76.18,44.23 75.44,43.48 74.86,43.48 74.78,43.56 74.78,44.14 74.57,44.34 74.07,44.34 73.87,44.14 73.87,43.56 73.79,43.48 65.05,43.48 64.64,43.07 64.64,32.69 61.51,29.56 61.51,16.72 62.19,16.05 65.03,16.05 65.43,15.66 65.43,11.84 65.35,11.76 v2(64.9,11.76)
FMC2_HA08_N: length 93.7
  TOP w0.124: J54.F11 v2(67.44,15.57) ; U3.AG18 v2(81.9,69.93)
  L03-SIG1 w0.081: v2(67.44,15.57) 67.44,16.02 67.52,16.1 69.14,16.1 69.47,16.43 69.47,26.46 70.3,27.3 70.3,27.58 69.63,28.25 69.63,28.37 69.86,28.6 69.98,28.6 70.65,27.93 70.93,27.93 71.29,28.28 71.29,28.57 70.62,29.24 70.62,29.35 70.85,29.58 70.96,29.58 71.63,28.91 71.92,28.91 72.27,29.27 72.27,29.55 71.6,30.22 71.6,30.34 71.84,30.57 71.95,30.57 72.62,29.9 72.9,29.9 73.26,30.25 73.26,30.54 72.59,31.21 72.59,31.32 72.82,31.55 72.93,31.55 73.6,30.88 73.89,30.88 74.24,31.24 74.24,31.52 73.57,32.19 73.57,32.31 73.81,32.54 73.92,32.54 74.74,31.72 75.19,31.72 76.23,32.75 76.23,33.59 76.03,33.79 74.89,33.79 74.81,33.88 74.81,34.2 74.89,34.28 76.03,34.28 76.23,34.49 76.23,36.6 76.03,36.8 75.02,36.8 74.94,36.88 74.94,37.21 75.02,37.29 76.03,37.29 76.25,37.51 76.25,38.48 75.47,39.27 75.47,39.38 75.7,39.61 75.81,39.61 76.59,38.83 76.88,38.83 77.23,39.18 77.23,39.47 76.45,40.25 76.45,40.37 76.68,40.6 76.8,40.6 77.58,39.81 77.87,39.81 78.22,40.17 78.22,40.45 77.44,41.24 77.44,41.35 77.67,41.58 77.78,41.58 78.56,40.8 78.85,40.8 79.2,41.15 79.2,41.44 78.42,42.22 78.42,42.34 78.65,42.57 78.77,42.57 79.55,41.78 79.84,41.78 80.19,42.14 80.19,42.42 79.41,43.21 79.41,43.32 79.64,43.55 79.75,43.55 80.53,42.77 80.82,42.77 81.49,43.44 81.49,46.22 81.29,46.42 80.93,46.42 80.85,46.5 80.85,46.83 80.93,46.91 81.29,46.91 81.49,47.11 81.49,47.61 81.29,47.81 80.93,47.81 80.85,47.89 80.85,48.22 80.93,48.3 81.29,48.3 81.49,48.5 81.49,67.14 81.62,67.28 82.26,67.28 82.5,67.52 82.5,69.32 v2(81.9,69.93)
FMC2_HA08_P: length 93.9
  TOP w0.124: 66.8,16.2 v2(67.44,16.84) ; U3.AH18 v2(81.9,68.93)
  L03-SIG1 w0.081: v2(81.9,68.93) 81.9,69.3 81.98,69.38 82.15,69.38 82.3,69.24 82.3,68.63 82.17,68.5 82.17,68.25 82.3,68.12 82.3,67.61 82.17,67.48 81.53,67.48 81.28,67.23 81.28,48.59 81.2,48.51 80.85,48.51 80.65,48.3 80.65,47.81 80.85,47.6 81.2,47.6 81.28,47.52 81.28,47.2 81.2,47.12 80.85,47.12 80.65,46.91 80.65,46.41 80.85,46.21 81.2,46.21 81.28,46.13 81.28,43.52 80.74,42.98 80.62,42.98 79.84,43.76 79.55,43.76 79.2,43.41 79.2,43.12 79.98,42.34 79.98,42.22 79.75,41.99 79.64,41.99 78.85,42.77 78.57,42.77 78.21,42.42 78.21,42.13 79,41.35 79,41.24 78.77,41.01 78.65,41.01 77.87,41.79 77.58,41.79 77.23,41.44 77.23,41.15 78.01,40.37 78.01,40.25 77.78,40.02 77.67,40.02 76.88,40.8 76.6,40.8 76.24,40.45 76.24,40.16 77.03,39.38 77.03,39.27 76.8,39.04 76.68,39.04 75.9,39.82 75.61,39.82 75.26,39.47 75.26,39.18 76.04,38.4 76.04,37.6 75.94,37.5 74.93,37.5 74.73,37.3 74.73,36.8 74.93,36.6 75.94,36.6 76.02,36.51 76.02,34.57 75.94,34.49 74.8,34.49 74.6,34.29 74.6,33.79 74.8,33.59 75.94,33.59 76.02,33.51 76.02,32.84 75.11,31.92 74.83,31.92 74.01,32.74 73.72,32.74 73.37,32.39 73.37,32.11 74.03,31.44 74.03,31.32 73.8,31.09 73.69,31.09 73.02,31.76 72.73,31.76 72.38,31.41 72.38,31.12 73.05,30.45 73.05,30.34 72.82,30.11 72.7,30.11 72.04,30.77 71.75,30.77 71.4,30.42 71.4,30.14 72.06,29.47 72.06,29.35 71.83,29.12 71.72,29.12 71.05,29.79 70.76,29.79 70.41,29.44 70.41,29.15 71.08,28.48 71.08,28.37 70.85,28.14 70.73,28.14 70.07,28.8 69.78,28.8 69.43,28.45 69.43,28.17 70.09,27.5 70.09,27.38 69.26,26.55 69.26,17.5 69.18,17.42 69.04,17.42 68.94,17.31 68.94,17.2 69.04,17.09 69.18,17.09 69.26,17.01 69.26,16.52 69.05,16.31 68.63,16.31 68.48,16.46 68.28,16.46 68.13,16.31 67.52,16.31 67.44,16.39 v2(67.44,16.84)
FMC2_HA09_N: length 97.6
  TOP w0.124: 66.8,17.47 v2(66.17,18.11)
  TOP w0.152: U3.AE17 v2(79.9,71.93)
  L03-SIG1 w0.081: v2(79.9,71.93) 79.9,72.3 79.82,72.38 79.65,72.38 79.51,72.24 79.51,71.59 79.58,71.52 79.58,71.22 79.51,71.15 79.51,69.61 79.21,69.31 78.57,69.31 78.49,69.23 78.49,50.85 78.07,50.43 77.78,50.43 77.08,51.14 76.96,51.14 76.73,50.91 76.73,50.79 77.44,50.09 77.44,49.8 77.08,49.45 76.8,49.45 76.09,50.15 75.98,50.15 75.75,49.92 75.75,49.81 76.45,49.1 76.45,48.81 76.1,48.46 75.81,48.46 75.11,49.17 74.99,49.17 74.76,48.94 74.76,48.82 75.47,48.12 75.47,47.83 75.11,47.48 74.83,47.48 74.12,48.18 74.01,48.18 73.78,47.95 73.78,47.84 74.48,47.13 74.48,46.84 74.13,46.49 73.84,46.49 73.14,47.2 73.02,47.2 72.79,46.97 72.79,46.85 73.5,46.15 73.5,45.86 73.14,45.51 72.86,45.51 72.15,46.21 72.04,46.21 71.81,45.98 71.81,45.87 72.51,45.16 72.51,44.87 72.16,44.52 71.87,44.52 71.17,45.23 71.05,45.23 70.82,45 70.82,44.88 71.53,44.18 71.53,43.89 71.17,43.54 70.89,43.54 70.35,44.08 70.23,44.08 70,43.85 70,43.73 70.54,43.19 70.54,42.9 69.8,42.17 69.8,41.87 69.6,41.67 68.59,41.67 68.51,41.59 68.51,41.26 68.59,41.18 69.6,41.18 69.8,40.98 69.8,40.48 69.6,40.27 68.59,40.27 68.51,40.19 68.51,39.87 68.59,39.79 69.6,39.79 69.8,39.58 69.8,39.09 69.6,38.88 68.59,38.88 68.51,38.8 68.51,38.48 68.59,38.4 69.6,38.4 69.8,38.19 69.8,36.46 69.23,35.89 68.94,35.89 68.51,36.32 68.39,36.32 68.16,36.09 68.16,35.98 68.6,35.54 68.6,35.25 68.25,34.9 67.96,34.9 67.52,35.34 67.41,35.34 67.18,35.1 67.18,34.99 67.61,34.56 67.61,34.27 67.26,33.92 66.97,33.92 66.54,34.35 66.42,34.35 66.19,34.12 66.19,34.01 66.63,33.57 66.63,33.28 66.28,32.93 65.99,32.93 65.55,33.37 65.44,33.37 65.21,33.13 65.21,33.02 65.64,32.59 65.64,32.3 65.29,31.95 65,31.95 64.57,32.38 64.45,32.38 64.22,32.15 64.22,32.03 64.66,31.6 64.66,31.31 64.26,30.92 64.26,17.83 64.51,17.58 66.09,17.58 66.17,17.66 v2(66.17,18.11)
FMC2_HA09_P: length 98
  TOP w0.124: J54.E9 v2(66.17,16.84)
  TOP w0.152: U3.AD17 v2(79.9,72.93)
  L03-SIG1 w0.081: v2(66.17,16.84) 66.17,17.29 66.09,17.37 64.43,17.37 64.05,17.74 64.05,31 64.45,31.4 64.45,31.51 64.02,31.95 64.02,32.24 64.37,32.59 64.66,32.59 65.09,32.15 65.2,32.15 65.43,32.39 65.43,32.5 65,32.93 65,33.22 65.35,33.57 65.64,33.57 66.07,33.14 66.19,33.14 66.42,33.37 66.42,33.48 65.99,33.92 65.99,34.21 66.34,34.56 66.63,34.56 67.06,34.12 67.17,34.12 67.4,34.36 67.4,34.47 66.97,34.9 66.97,35.19 67.32,35.54 67.61,35.54 68.04,35.11 68.16,35.11 68.39,35.34 68.39,35.45 67.96,35.89 67.96,36.18 68.31,36.53 68.6,36.53 69.03,36.09 69.14,36.09 69.6,36.55 69.6,38.11 69.51,38.19 68.5,38.19 68.3,38.39 68.3,38.89 68.5,39.09 69.51,39.09 69.6,39.17 69.6,39.5 69.51,39.58 68.5,39.58 68.3,39.78 68.3,40.28 68.5,40.48 69.51,40.48 69.6,40.56 69.6,40.89 69.51,40.97 68.5,40.97 68.3,41.17 68.3,41.67 68.5,41.87 69.51,41.87 69.6,41.96 69.6,42.25 70.33,42.99 70.33,43.1 69.79,43.64 69.79,43.93 70.15,44.28 70.43,44.28 70.97,43.74 71.09,43.74 71.32,43.97 71.32,44.09 70.61,44.79 70.61,45.08 70.97,45.43 71.25,45.43 71.96,44.73 72.07,44.73 72.3,44.96 72.3,45.07 71.6,45.78 71.6,46.07 71.95,46.42 72.24,46.42 72.94,45.71 73.06,45.71 73.29,45.94 73.29,46.06 72.58,46.76 72.58,47.05 72.94,47.4 73.22,47.4 73.93,46.7 74.04,46.7 74.27,46.93 74.27,47.04 73.57,47.75 73.57,48.04 73.92,48.39 74.21,48.39 74.91,47.68 75.03,47.68 75.26,47.91 75.26,48.03 74.55,48.73 74.55,49.02 74.91,49.37 75.19,49.37 75.9,48.67 76.01,48.67 76.24,48.9 76.24,49.01 75.54,49.72 75.54,50.01 75.89,50.36 76.18,50.36 76.88,49.65 77,49.65 77.23,49.88 77.23,50 76.52,50.7 76.52,50.99 76.88,51.34 77.16,51.34 77.87,50.64 77.98,50.64 78.28,50.93 78.28,69.31 78.48,69.52 79.12,69.52 79.3,69.69 79.3,72.33 79.9,72.93 v2(79.9,72.93)
FMC2_HA10_N: length 83.4
  TOP w0.124: J54.K14 v2(71.25,10.49) ; U3.AP23 v2(86.9,62.93)
  L10-SIG3 w0.081: v2(86.9,62.93) 86.9,63.31 86.82,63.39 86.66,63.39 86.49,63.22 86.49,62.66 86.59,62.56 86.59,62.3 86.49,62.2 86.49,47.38 86.15,47.04 85.4,47.04 84.62,47.81 84.51,47.81 84.28,47.58 84.28,47.47 85.14,46.61 85.14,46.32 84.78,45.97 84.5,45.97 83.64,46.83 83.52,46.83 83.29,46.6 83.29,46.48 84.3,45.48 84.3,45.19 83.95,44.84 83.66,44.84 82.65,45.84 82.54,45.84 82.31,45.61 82.31,45.5 83.31,44.49 83.31,44.2 82.96,43.85 82.67,43.85 81.67,44.86 81.55,44.86 81.32,44.63 81.32,44.51 82.33,43.51 82.33,43.22 81.98,42.87 81.69,42.87 80.68,43.87 80.57,43.87 80.34,43.64 80.34,43.53 81.34,42.52 81.34,42.23 80.99,41.88 80.7,41.88 79.76,42.82 79.65,42.82 79.42,42.59 79.42,42.48 80.36,41.54 80.36,41.25 79.91,40.8 79.62,40.8 79.11,41.31 79,41.31 78.77,41.08 78.77,40.97 79.28,40.46 79.28,40.17 78.93,39.82 78.64,39.82 78.13,40.33 78.01,40.33 77.78,40.1 77.78,39.98 78.29,39.47 78.29,39.18 70.72,31.61 70.72,10.57 70.8,10.49 v2(71.25,10.49)
FMC2_HA10_P: length 83.4
  TOP w0.124: U3.AN23 v2(86.9,63.93) ; J54.K13 v2(69.98,10.49)
  L10-SIG3 w0.081: v2(69.98,10.49) 70.43,10.49 70.51,10.57 70.51,31.69 78.08,39.27 78.08,39.38 77.57,39.89 77.57,40.18 77.93,40.53 78.21,40.53 78.72,40.02 78.84,40.02 79.07,40.25 79.07,40.37 78.56,40.88 78.56,41.17 78.91,41.52 79.2,41.52 79.71,41.01 79.82,41.01 80.15,41.34 80.15,41.45 79.21,42.39 79.21,42.68 79.56,43.03 79.85,43.03 80.79,42.09 80.91,42.09 81.14,42.32 81.14,42.44 80.13,43.44 80.13,43.73 80.48,44.08 80.77,44.08 81.78,43.08 81.89,43.08 82.12,43.31 82.12,43.42 81.12,44.43 81.12,44.71 81.47,45.07 81.76,45.07 82.76,44.06 82.88,44.06 83.11,44.29 83.11,44.41 82.1,45.41 82.1,45.7 82.45,46.05 82.74,46.05 83.75,45.05 83.86,45.05 84.09,45.28 84.09,45.39 83.09,46.4 83.09,46.68 83.44,47.04 83.73,47.04 84.58,46.18 84.7,46.18 84.93,46.41 84.93,46.52 84.07,47.38 84.07,47.67 84.42,48.02 84.71,48.02 85.49,47.25 86.06,47.25 86.28,47.46 86.28,63.31 v2(86.9,63.93)
FMC2_HA11_N: length 86.8
  TOP w0.124: J54.J13 v2(71.25,13.03) ; U3.AP18 v2(81.9,62.93)
  L05-SIG2 w0.081: v2(81.9,62.93) 81.9,63.3 81.82,63.38 81.65,63.38 81.49,63.22 81.49,62.55 81.58,62.45 81.58,62.2 81.49,62.1 81.49,46.23 79.76,44.5 79.76,41.36 79.55,41.16 78.78,41.16 78.69,41.08 78.69,40.75 78.78,40.67 79.55,40.67 79.76,40.47 79.76,39.97 79.55,39.77 78.78,39.77 78.69,39.69 78.69,39.36 78.78,39.28 79.55,39.28 79.76,39.08 79.76,38.58 79.55,38.37 78.78,38.37 78.69,38.29 78.69,37.97 78.78,37.89 79.55,37.89 79.76,37.68 79.76,37.19 79.55,36.98 78.78,36.98 78.69,36.9 78.69,36.58 78.78,36.49 79.55,36.49 79.76,36.29 79.76,35.79 79.55,35.59 78.78,35.59 78.69,35.51 78.69,35.18 78.78,35.1 79.55,35.1 79.76,34.9 79.76,34.4 79.55,34.2 78.78,34.2 78.69,34.12 78.69,33.79 78.78,33.71 79.55,33.71 79.76,33.51 79.76,33.01 79.55,32.81 78.78,32.81 78.69,32.73 78.69,32.4 78.78,32.32 79.55,32.32 79.76,32.12 79.76,31.62 79.55,31.41 78.78,31.41 78.69,31.33 78.69,31.01 78.78,30.93 79.55,30.93 79.76,30.72 79.76,30.23 79.55,30.02 78.78,30.02 78.69,29.94 78.69,29.62 78.78,29.54 80.42,29.54 80.62,29.33 80.62,28.83 80.42,28.63 78.78,28.63 78.69,28.55 78.69,28.22 78.78,28.14 80.34,28.14 80.54,27.94 80.54,27.44 80.34,27.24 78.78,27.24 78.69,27.16 78.69,26.83 78.78,26.75 80.52,26.75 80.72,26.55 80.72,25.57 80.34,25.19 72.81,25.19 72.09,24.47 72.09,14.06 71.59,13.55 70.91,13.55 70.79,13.44 70.79,13.11 70.87,13.03 v2(71.25,13.03)
FMC2_HA11_P: length 86.9
  TOP w0.124: 69.34,12.39 v2(69.98,13.03) ; U3.AN18 v2(81.9,63.93)
  L05-SIG2 w0.081: v2(81.9,63.93) 81.28,63.31 81.28,46.32 79.55,44.58 79.55,41.45 79.47,41.37 78.69,41.37 78.49,41.16 78.49,40.67 78.69,40.46 79.47,40.46 79.55,40.38 79.55,40.06 79.47,39.97 78.69,39.97 78.49,39.77 78.49,39.27 78.69,39.07 79.47,39.07 79.55,38.99 79.55,38.66 79.47,38.58 78.69,38.58 78.49,38.38 78.49,37.88 78.69,37.68 79.47,37.68 79.55,37.6 79.55,37.27 79.47,37.19 78.69,37.19 78.49,36.99 78.49,36.49 78.69,36.29 79.47,36.29 79.55,36.21 79.55,35.88 79.47,35.8 78.69,35.8 78.49,35.6 78.49,35.1 78.69,34.89 79.47,34.89 79.55,34.81 79.55,34.49 79.47,34.41 78.69,34.41 78.49,34.2 78.49,33.71 78.69,33.5 79.47,33.5 79.55,33.42 79.55,33.1 79.47,33.02 78.69,33.02 78.49,32.81 78.49,32.31 78.69,32.11 79.47,32.11 79.55,32.03 79.55,31.7 79.47,31.62 78.69,31.62 78.49,31.42 78.49,30.92 78.69,30.72 79.47,30.72 79.55,30.64 79.55,30.31 79.47,30.23 78.69,30.23 78.49,30.03 78.49,29.53 78.69,29.33 80.33,29.33 80.41,29.25 80.41,28.92 80.33,28.84 78.69,28.84 78.49,28.64 78.49,28.14 78.69,27.94 80.25,27.94 80.34,27.85 80.34,27.53 80.25,27.45 78.69,27.45 78.49,27.24 78.49,26.75 78.69,26.54 80.43,26.54 80.51,26.46 80.51,25.66 80.25,25.4 72.73,25.4 71.88,24.56 71.88,14.14 71.5,13.76 70.83,13.76 70.58,13.52 70.58,13.15 70.46,13.03 v2(69.98,13.03)
FMC2_LA00_CLK_N: length 89.1
  TOP w0.099: J54.G7 v2(62.36,14.3)
  TOP w0.124: U3.AK18 v2(81.9,66.93)
  L10-SIG3 w0.081: v2(81.9,66.93) 81.9,67.24 81.98,67.33 82.21,67.33 82.29,67.24 82.29,53.76 72.82,44.29 72.41,44.29 72.32,44.38 72.32,45.18 72.12,45.39 71.62,45.39 71.42,45.18 71.42,44.38 71.34,44.29 71.01,44.29 70.93,44.38 70.93,45.18 70.73,45.39 70.23,45.39 70.03,45.18 70.03,44.38 69.95,44.29 69.62,44.29 69.54,44.38 69.54,45.18 69.34,45.39 68.84,45.39 68.64,45.18 68.64,44.38 68.56,44.29 68.23,44.29 68.15,44.38 68.15,45.18 67.95,45.39 67.45,45.39 67.24,45.18 67.24,44.38 67.16,44.29 66.84,44.29 66.76,44.38 66.76,45.18 66.55,45.39 66.06,45.39 65.85,45.18 65.85,44.38 65.77,44.29 63.28,44.29 62.95,43.96 62.95,43.22 63.15,43.02 63.64,43.02 63.72,42.94 63.72,42.61 63.64,42.53 63.15,42.53 62.95,42.33 62.95,41.83 63.15,41.63 63.64,41.63 63.72,41.54 63.72,41.22 63.64,41.14 63.15,41.14 62.95,40.93 62.95,40.44 63.15,40.23 63.64,40.23 63.72,40.15 63.72,39.83 63.64,39.75 63.15,39.75 62.95,39.54 62.95,39.04 63.15,38.84 63.64,38.84 63.72,38.76 63.72,38.44 63.64,38.35 63.15,38.35 62.95,38.15 62.95,37.65 63.15,37.45 63.64,37.45 63.72,37.37 63.72,37.04 63.64,36.96 63.15,36.96 62.95,36.76 62.95,36.26 63.15,36.06 63.64,36.06 63.72,35.98 63.72,35.65 63.64,35.57 63.15,35.57 62.95,35.37 62.95,34.87 63.15,34.67 63.52,34.67 63.6,34.58 63.6,34.26 63.52,34.18 63.15,34.18 62.95,33.97 62.95,32.81 60.45,30.31 60.45,15.32 60.87,14.9 62.2,14.9 62.36,14.75 v2(62.36,14.3)
FMC2_LA00_CLK_P: length 89
  TOP w0.099: 61.72,14.93 v2(62.36,15.57)
  TOP w0.124: U3.AJ18 v2(81.9,67.93)
  L10-SIG3 w0.081: v2(62.36,15.57) 62.36,15.19 62.28,15.11 60.96,15.11 60.66,15.41 60.66,30.23 63.15,32.72 63.15,33.89 63.24,33.97 63.6,33.97 63.8,34.17 63.8,34.67 63.6,34.87 63.24,34.87 63.15,34.96 63.15,35.28 63.24,35.36 63.73,35.36 63.93,35.56 63.93,36.06 63.73,36.27 63.24,36.27 63.15,36.35 63.15,36.67 63.24,36.75 63.73,36.75 63.93,36.96 63.93,37.45 63.73,37.66 63.24,37.66 63.15,37.74 63.15,38.06 63.24,38.15 63.73,38.15 63.93,38.35 63.93,38.85 63.73,39.05 63.24,39.05 63.15,39.13 63.15,39.46 63.24,39.54 63.73,39.54 63.93,39.74 63.93,40.24 63.73,40.44 63.24,40.44 63.15,40.52 63.15,40.85 63.24,40.93 63.73,40.93 63.93,41.13 63.93,41.63 63.73,41.83 63.24,41.83 63.15,41.91 63.15,42.24 63.24,42.32 63.73,42.32 63.93,42.52 63.93,43.02 63.73,43.23 63.24,43.23 63.15,43.31 63.15,43.87 63.37,44.09 65.86,44.09 66.06,44.29 66.06,45.1 66.14,45.18 66.47,45.18 66.55,45.1 66.55,44.29 66.75,44.09 67.25,44.09 67.45,44.29 67.45,45.1 67.53,45.18 67.86,45.18 67.94,45.1 67.94,44.29 68.14,44.09 68.64,44.09 68.85,44.29 68.85,45.1 68.93,45.18 69.25,45.18 69.33,45.1 69.33,44.29 69.54,44.09 70.03,44.09 70.24,44.29 70.24,45.1 70.32,45.18 70.64,45.18 70.72,45.1 70.72,44.29 70.93,44.09 71.43,44.09 71.63,44.29 71.63,45.1 71.71,45.18 72.04,45.18 72.12,45.1 72.12,44.29 72.32,44.09 72.91,44.09 82.5,53.68 82.5,67.33 82.3,67.53 81.98,67.53 81.9,67.62 v2(81.9,67.93)
FMC2_LA01_CLK_N: length 83.5
  TOP w0.099: J54.D9 v2(64.9,18.11)
  TOP w0.124: U3.AN22 v2(85.9,63.93)
  L10-SIG3 w0.081: v2(64.9,18.11) 64.9,18.6 64.82,18.69 64.38,18.69 64.18,18.89 64.18,27.31 66.67,29.81 66.67,31.1 66.88,31.31 67.25,31.31 67.33,31.39 67.33,31.71 67.25,31.79 66.88,31.79 66.67,32 66.67,32.49 66.88,32.7 67.25,32.7 67.33,32.78 67.33,33.1 67.25,33.18 66.88,33.18 66.67,33.39 66.67,33.89 66.88,34.09 67.25,34.09 67.33,34.17 67.33,34.5 67.25,34.58 66.88,34.58 66.67,34.78 66.67,35.28 66.88,35.48 67.25,35.48 67.33,35.56 67.33,35.89 67.25,35.97 66.88,35.97 66.67,36.17 66.67,36.67 66.88,36.87 67.25,36.87 67.33,36.95 67.33,37.28 67.25,37.36 66.88,37.36 66.67,37.56 66.67,38.06 66.88,38.26 67.25,38.26 67.33,38.35 67.33,38.67 67.25,38.75 66.88,38.75 66.67,38.96 66.67,41.17 67.06,41.55 67.74,41.55 67.94,41.35 67.94,40.16 68.02,40.08 68.35,40.08 68.43,40.16 68.43,41.35 68.63,41.55 69.13,41.55 69.33,41.35 69.33,40.16 69.42,40.08 69.74,40.08 69.82,40.16 69.82,41.35 70.03,41.55 70.52,41.55 70.73,41.35 70.73,40.16 70.81,40.08 71.13,40.08 71.21,40.16 71.21,41.35 71.42,41.55 71.92,41.55 72.12,41.35 72.12,40.16 72.2,40.08 72.53,40.08 72.61,40.16 72.61,41.35 72.81,41.55 73.31,41.55 73.51,41.35 73.51,40.16 73.59,40.08 73.92,40.08 74,40.16 74,41.35 74.2,41.55 74.7,41.55 74.9,41.35 74.9,40.41 74.98,40.33 75.31,40.33 75.39,40.41 75.39,41.35 75.59,41.55 76.56,41.55 85.26,50.26 85.26,63.29 v2(85.9,63.93)
FMC2_LA01_CLK_P: length 83.2
  TOP w0.099: 64.26,18.74 v2(64.9,19.38)
  TOP w0.124: U3.AP22 v2(85.9,62.93)
  L10-SIG3 w0.081: v2(64.9,19.38) 64.9,18.98 64.82,18.89 64.47,18.89 64.39,18.98 64.39,27.22 66.88,29.72 66.88,31.02 66.96,31.1 67.34,31.1 67.54,31.3 67.54,31.8 67.34,32 66.96,32 66.88,32.08 66.88,32.41 66.96,32.49 67.34,32.49 67.54,32.69 67.54,33.19 67.34,33.39 66.96,33.39 66.88,33.47 66.88,33.8 66.96,33.88 67.34,33.88 67.54,34.08 67.54,34.58 67.34,34.79 66.96,34.79 66.88,34.87 66.88,35.19 66.96,35.27 67.34,35.27 67.54,35.48 67.54,35.97 67.34,36.18 66.96,36.18 66.88,36.26 66.88,36.58 66.96,36.66 67.34,36.66 67.54,36.87 67.54,37.37 67.34,37.57 66.96,37.57 66.88,37.65 66.88,37.98 66.96,38.06 67.34,38.06 67.54,38.26 67.54,38.76 67.34,38.96 66.96,38.96 66.88,39.04 66.88,41.08 67.14,41.34 67.65,41.34 67.73,41.26 67.73,40.08 67.94,39.87 68.44,39.87 68.64,40.08 68.64,41.26 68.72,41.34 69.05,41.34 69.13,41.26 69.13,40.08 69.33,39.87 69.83,39.87 70.03,40.08 70.03,41.26 70.11,41.34 70.44,41.34 70.52,41.26 70.52,40.08 70.72,39.87 71.22,39.87 71.42,40.08 71.42,41.26 71.5,41.34 71.83,41.34 71.91,41.26 71.91,40.08 72.11,39.87 72.61,39.87 72.81,40.08 72.81,41.26 72.9,41.34 73.22,41.34 73.3,41.26 73.3,40.08 73.51,39.87 74,39.87 74.21,40.08 74.21,41.26 74.29,41.34 74.61,41.34 74.69,41.26 74.69,40.33 74.9,40.12 75.4,40.12 75.6,40.33 75.6,41.26 75.68,41.34 76.64,41.34 85.47,50.17 85.47,61.31 85.6,61.44 85.6,61.64 85.47,61.77 85.47,62.02 85.6,62.15 85.6,62.38 85.47,62.51 85.47,63.21 85.65,63.38 85.82,63.38 85.9,63.3 v2(85.9,62.93)
FMC2_LA02_N: length 90.6
  TOP w0.124: 64.26,13.66 v2(63.63,13.03) ; U3.AJ19 v2(82.9,67.93)
  L05-SIG2 w0.081: v2(63.63,13.03) 63.63,13.48 63.55,13.56 62.01,13.56 61.64,13.93 61.64,27.98 62.15,28.49 72.35,28.49 72.52,28.66 72.52,30.09 72.44,30.17 71.27,30.17 71.06,30.37 71.06,30.87 71.27,31.07 72.44,31.07 72.52,31.15 72.52,31.48 72.44,31.56 71.27,31.56 71.06,31.76 71.06,32.26 71.27,32.46 72.44,32.46 72.52,32.55 72.52,32.87 72.44,32.95 71.29,32.95 71.09,33.16 71.09,33.65 71.29,33.86 72.44,33.86 72.52,33.94 72.52,34.26 72.44,34.34 71.19,34.34 70.99,34.55 70.99,35.04 71.19,35.25 72.44,35.25 72.52,35.33 72.52,35.65 72.44,35.74 71.17,35.74 70.96,35.94 70.96,36.44 71.17,36.64 72.44,36.64 72.52,36.72 72.52,37.05 72.44,37.13 71.17,37.13 70.96,37.33 70.96,37.83 71.17,38.03 72.44,38.03 72.52,38.11 72.52,43.35 78.28,49.11 78.28,66.17 78.65,66.55 80.18,66.55 81.16,67.53 82.5,67.53 v2(82.9,67.93)
FMC2_LA02_P: length 90.5
  TOP w0.124: J54.H7 v2(63.63,14.3) ; U3.AK19 v2(82.9,66.93)
  L05-SIG2 w0.081: v2(82.9,66.93) 82.9,67.24 82.82,67.33 81.25,67.33 81.09,67.17 81.09,67.04 80.92,66.87 80.8,66.87 80.26,66.34 78.74,66.34 78.49,66.09 78.49,65.73 78.61,65.6 78.61,65.4 78.49,65.27 78.49,64.7 78.61,64.57 78.61,64.37 78.49,64.24 78.49,64.05 78.61,63.92 78.61,63.72 78.49,63.59 78.49,49.03 72.73,43.27 72.73,38.03 72.52,37.82 71.25,37.82 71.17,37.74 71.17,37.42 71.25,37.34 72.52,37.34 72.73,37.13 72.73,36.63 72.52,36.43 71.25,36.43 71.17,36.35 71.17,36.03 71.25,35.94 72.52,35.94 72.73,35.74 72.73,35.24 72.52,35.04 71.28,35.04 71.2,34.96 71.2,34.63 71.28,34.55 72.52,34.55 72.73,34.35 72.73,33.85 72.52,33.65 71.38,33.65 71.3,33.57 71.3,33.24 71.38,33.16 72.52,33.16 72.73,32.96 72.73,32.46 72.52,32.26 71.35,32.26 71.27,32.17 71.27,31.85 71.35,31.77 72.52,31.77 72.73,31.57 72.73,31.07 72.52,30.86 71.35,30.86 71.27,30.78 71.27,30.46 71.35,30.38 72.52,30.38 72.73,30.17 72.73,28.58 72.44,28.29 62.24,28.29 61.85,27.9 61.85,14.02 62.1,13.77 63.55,13.77 63.63,13.85 v2(63.63,14.3)
FMC2_LA03_N: length 97.6
  TOP w0.099: 66.8,14.93 v2(66.17,15.57)
  TOP w0.152: U3.Y18 v2(80.9,76.93)
  L03-SIG1 w0.081: v2(66.17,15.57) 66.17,15.12 66.09,15.04 65.68,15.04 65.58,15.13 65.36,15.13 65.26,15.04 65.03,15.04 64.93,15.13 64.71,15.13 64.61,15.04 64.38,15.04 64.28,15.13 64.06,15.13 63.96,15.04 63.24,15.04 63.12,15.16 63.12,15.79 63.25,15.92 63.25,16.18 63.12,16.3 63.12,24.95 62.92,25.15 62.16,25.15 62.08,25.23 62.08,25.56 62.16,25.64 62.92,25.64 63.12,25.84 63.12,26.34 62.92,26.54 62.16,26.54 62.08,26.63 62.08,26.95 62.16,27.03 62.92,27.03 63.12,27.24 63.12,27.73 62.92,27.94 62.16,27.94 62.08,28.02 62.08,28.34 62.16,28.42 62.92,28.42 63.12,28.63 63.12,33.91 63.2,34 64.26,34 64.47,34.2 64.47,34.7 64.26,34.9 63.2,34.9 63.12,34.98 63.12,35.31 63.2,35.39 64.26,35.39 64.47,35.59 64.47,36.09 64.26,36.29 63.2,36.29 63.12,36.37 63.12,36.7 63.2,36.78 64.26,36.78 64.47,36.98 64.47,37.48 64.26,37.68 63.2,37.68 63.12,37.77 63.12,38.87 63.54,39.29 63.65,39.29 64.29,38.64 64.58,38.64 64.93,39 64.93,39.28 64.29,39.93 64.29,40.04 64.52,40.27 64.64,40.27 65.19,39.72 65.48,39.72 65.83,40.07 65.83,40.36 65.28,40.91 65.28,41.03 65.51,41.26 65.62,41.26 66.17,40.7 66.46,40.7 66.81,41.05 66.81,41.34 66.26,41.9 66.26,42.01 66.49,42.24 66.61,42.24 67.16,41.69 67.45,41.69 67.8,42.04 67.8,42.33 67.25,42.88 67.25,43 67.48,43.23 67.59,43.23 68.14,42.67 68.43,42.67 68.78,43.02 68.78,43.31 68.23,43.87 68.23,43.98 77.47,53.22 77.47,70.11 77.68,70.32 78.06,70.32 78.49,70.75 78.49,73.29 78.57,73.37 80.22,73.37 80.5,73.65 80.5,76.85 80.58,76.93 v2(80.9,76.93)
FMC2_LA03_P: length 97.5
  TOP w0.099: J54.G9 v2(66.17,14.3)
  TOP w0.152: U3.Y17 v2(79.9,76.93)
  L03-SIG1 w0.081: v2(66.17,14.3) 66.17,14.75 66.09,14.83 63.16,14.83 62.91,15.07 62.91,24.86 62.83,24.94 62.08,24.94 61.87,25.15 61.87,25.65 62.08,25.85 62.83,25.85 62.91,25.93 62.91,26.25 62.83,26.34 62.08,26.34 61.87,26.54 61.87,27.04 62.08,27.24 62.83,27.24 62.91,27.32 62.91,27.65 62.83,27.73 62.08,27.73 61.87,27.93 61.87,28.43 62.08,28.63 62.83,28.63 62.91,28.71 62.91,34 63.11,34.2 64.18,34.2 64.26,34.29 64.26,34.61 64.18,34.69 63.11,34.69 62.91,34.9 62.91,35.39 63.11,35.6 64.18,35.6 64.26,35.68 64.26,36 64.18,36.08 63.11,36.08 62.91,36.29 62.91,36.78 63.11,36.99 64.18,36.99 64.26,37.07 64.26,37.39 64.18,37.48 63.11,37.48 62.91,37.68 62.91,38.95 63.45,39.49 63.74,39.49 64.38,38.85 64.49,38.85 64.72,39.08 64.72,39.2 64.08,39.84 64.08,40.13 64.43,40.48 64.72,40.48 65.28,39.93 65.39,39.93 65.62,40.16 65.62,40.27 65.07,40.82 65.07,41.11 65.42,41.46 65.71,41.46 66.26,40.91 66.38,40.91 66.61,41.14 66.61,41.26 66.05,41.81 66.05,42.1 66.4,42.45 66.69,42.45 67.25,41.9 67.36,41.9 67.59,42.13 67.59,42.24 67.04,42.79 67.04,43.08 67.39,43.43 67.68,43.43 68.23,42.88 68.35,42.88 68.58,43.11 68.58,43.23 68.02,43.78 68.02,44.07 77.26,53.31 77.26,70.2 77.6,70.53 77.98,70.53 78.28,70.84 78.28,73.38 78.49,73.58 80.14,73.58 80.29,73.74 80.29,76.67 80.04,76.93 v2(79.9,76.93)
FMC2_LA04_N: length 90.2
  TOP w0.124: J54.H11 v2(67.44,13.03)
  TOP w0.152: U3.AL17 v2(79.9,65.93)
  L05-SIG2 w0.081: v2(67.44,13.03) 67.44,13.48 67.36,13.56 66.97,13.56 66.7,13.83 66.7,23.58 66.62,23.66 64.59,23.66 64.39,23.86 64.39,24.36 64.59,24.56 66.62,24.56 66.7,24.64 66.7,24.97 66.62,25.05 64.59,25.05 64.39,25.25 64.39,25.75 64.59,25.95 66.62,25.95 66.7,26.04 66.7,26.65 67.48,27.43 74.84,27.43 75.1,27.69 75.1,28.4 75.02,28.48 74.12,28.48 73.91,28.69 73.91,29.18 74.12,29.39 75.02,29.39 75.1,29.47 75.1,29.79 75.02,29.88 74.12,29.88 73.91,30.08 73.91,30.58 74.12,30.78 75.02,30.78 75.1,30.86 75.1,31.19 75.02,31.27 74.12,31.27 73.91,31.47 73.91,31.97 74.12,32.17 75.02,32.17 75.1,32.25 75.1,32.58 75.02,32.66 74.12,32.66 73.91,32.86 73.91,33.36 74.12,33.56 75.02,33.56 75.1,33.64 75.1,33.97 75.02,34.05 74.12,34.05 73.91,34.25 73.91,34.75 74.12,34.96 75.02,34.96 75.1,35.04 75.1,35.36 75.02,35.44 74.16,35.44 73.96,35.65 73.96,36.14 74.16,36.35 75.02,36.35 75.1,36.43 75.1,36.75 75.02,36.84 74.29,36.84 74.09,37.04 74.09,37.54 74.29,37.74 75.02,37.74 75.1,37.82 75.1,38.15 75.02,38.23 74.42,38.23 74.21,38.43 74.21,38.93 74.42,39.13 75.02,39.13 75.1,39.21 75.1,39.54 75.02,39.62 74.42,39.62 74.21,39.82 74.21,40.32 74.42,40.52 75.02,40.52 75.1,40.6 75.1,44.33 79.25,48.47 79.25,65.28 v2(79.9,65.93)
FMC2_LA04_P: length 90.1
  TOP w0.124: 66.8,13.66 v2(67.44,14.3)
  TOP w0.152: U3.AM17 v2(79.9,64.93)
  L05-SIG2 w0.081: v2(79.9,64.93) 79.9,65.33 79.82,65.41 79.67,65.41 79.46,65.19 79.46,64.74 79.6,64.59 79.6,64.28 79.46,64.14 79.46,63.72 79.58,63.6 79.58,63.29 79.46,63.17 79.46,62.7 79.58,62.58 79.58,62.35 79.46,62.23 79.46,48.39 75.31,44.24 75.31,40.52 75.11,40.31 74.5,40.31 74.42,40.23 74.42,39.91 74.5,39.83 75.11,39.83 75.31,39.62 75.31,39.13 75.11,38.92 74.5,38.92 74.42,38.84 74.42,38.52 74.5,38.44 75.11,38.44 75.31,38.23 75.31,37.73 75.11,37.53 74.38,37.53 74.29,37.45 74.29,37.12 74.38,37.04 75.11,37.04 75.31,36.84 75.31,36.34 75.11,36.14 74.25,36.14 74.17,36.06 74.17,35.73 74.25,35.65 75.11,35.65 75.31,35.45 75.31,34.95 75.11,34.75 74.2,34.75 74.12,34.67 74.12,34.34 74.2,34.26 75.11,34.26 75.31,34.06 75.31,33.56 75.11,33.36 74.2,33.36 74.12,33.27 74.12,32.95 74.2,32.87 75.11,32.87 75.31,32.66 75.31,32.17 75.11,31.96 74.2,31.96 74.12,31.88 74.12,31.56 74.2,31.48 75.11,31.48 75.31,31.27 75.31,30.77 75.11,30.57 74.2,30.57 74.12,30.49 74.12,30.17 74.2,30.08 75.11,30.08 75.31,29.88 75.31,29.38 75.11,29.18 74.2,29.18 74.12,29.1 74.12,28.77 74.2,28.69 75.11,28.69 75.31,28.49 75.31,27.61 74.93,27.22 67.56,27.22 66.91,26.57 66.91,25.95 66.7,25.75 64.68,25.75 64.6,25.66 64.6,25.34 64.68,25.26 66.7,25.26 66.91,25.06 66.91,24.56 66.7,24.35 64.68,24.35 64.6,24.27 64.6,23.95 64.68,23.87 66.7,23.87 66.91,23.66 66.91,13.91 67.05,13.77 67.36,13.77 67.44,13.85 v2(67.44,14.3)
FMC2_LA05_N: length 96.7
  TOP w0.124: U3.AE19 v2(82.9,71.93) ; 69.34,18.74 v2(68.71,19.38)
  L03-SIG1 w0.081: v2(82.9,71.93) 82.48,71.93 82.4,71.85 82.4,71.57 82.17,71.34 81.62,71.34 81.53,71.26 81.53,68.5 80.52,67.48 80.52,49.54 79.33,48.35 79.33,48.23 80.12,47.44 80.12,47.15 79.77,46.8 79.48,46.8 78.69,47.59 78.57,47.59 78.34,47.36 78.34,47.25 79.92,45.66 79.92,45.38 79.57,45.02 79.28,45.02 77.7,46.61 77.59,46.61 77.36,46.38 77.36,46.26 78.94,44.68 78.94,44.39 78.59,44.04 78.3,44.04 76.72,45.62 76.6,45.62 76.37,45.39 76.37,45.28 77.95,43.69 77.95,43.41 77.6,43.05 77.31,43.05 75.73,44.64 75.62,44.64 75.39,44.41 75.39,44.29 76.97,42.71 76.97,42.42 76.62,42.07 76.33,42.07 74.75,43.65 74.63,43.65 74.4,43.42 74.4,43.31 75.98,41.72 75.98,41.44 75.63,41.08 75.34,41.08 73.76,42.67 73.65,42.67 73.42,42.44 73.42,42.32 75,40.74 75,40.45 73.89,39.34 73.89,34.67 73.35,34.13 73.07,34.13 72.64,34.56 72.52,34.56 72.29,34.33 72.29,34.21 72.72,33.79 72.72,33.5 72.37,33.15 72.08,33.15 71.65,33.57 71.54,33.57 71.31,33.34 71.31,33.23 71.74,32.8 71.74,32.51 71.38,32.16 71.1,32.16 70.67,32.59 70.55,32.59 70.32,32.36 70.32,32.24 70.75,31.82 70.75,31.53 70.4,31.18 70.11,31.18 69.68,31.6 69.57,31.6 69.34,31.37 69.34,31.26 69.77,30.83 69.77,30.54 69.41,30.19 69.13,30.19 68.76,30.55 68.65,30.55 68.42,30.32 68.42,30.21 68.78,29.85 68.78,29.56 68.2,28.98 68.2,20.19 68.3,20.09 68.3,19.83 68.2,19.73 68.2,18.97 68.33,18.85 68.63,18.85 68.71,18.93 v2(68.71,19.38)
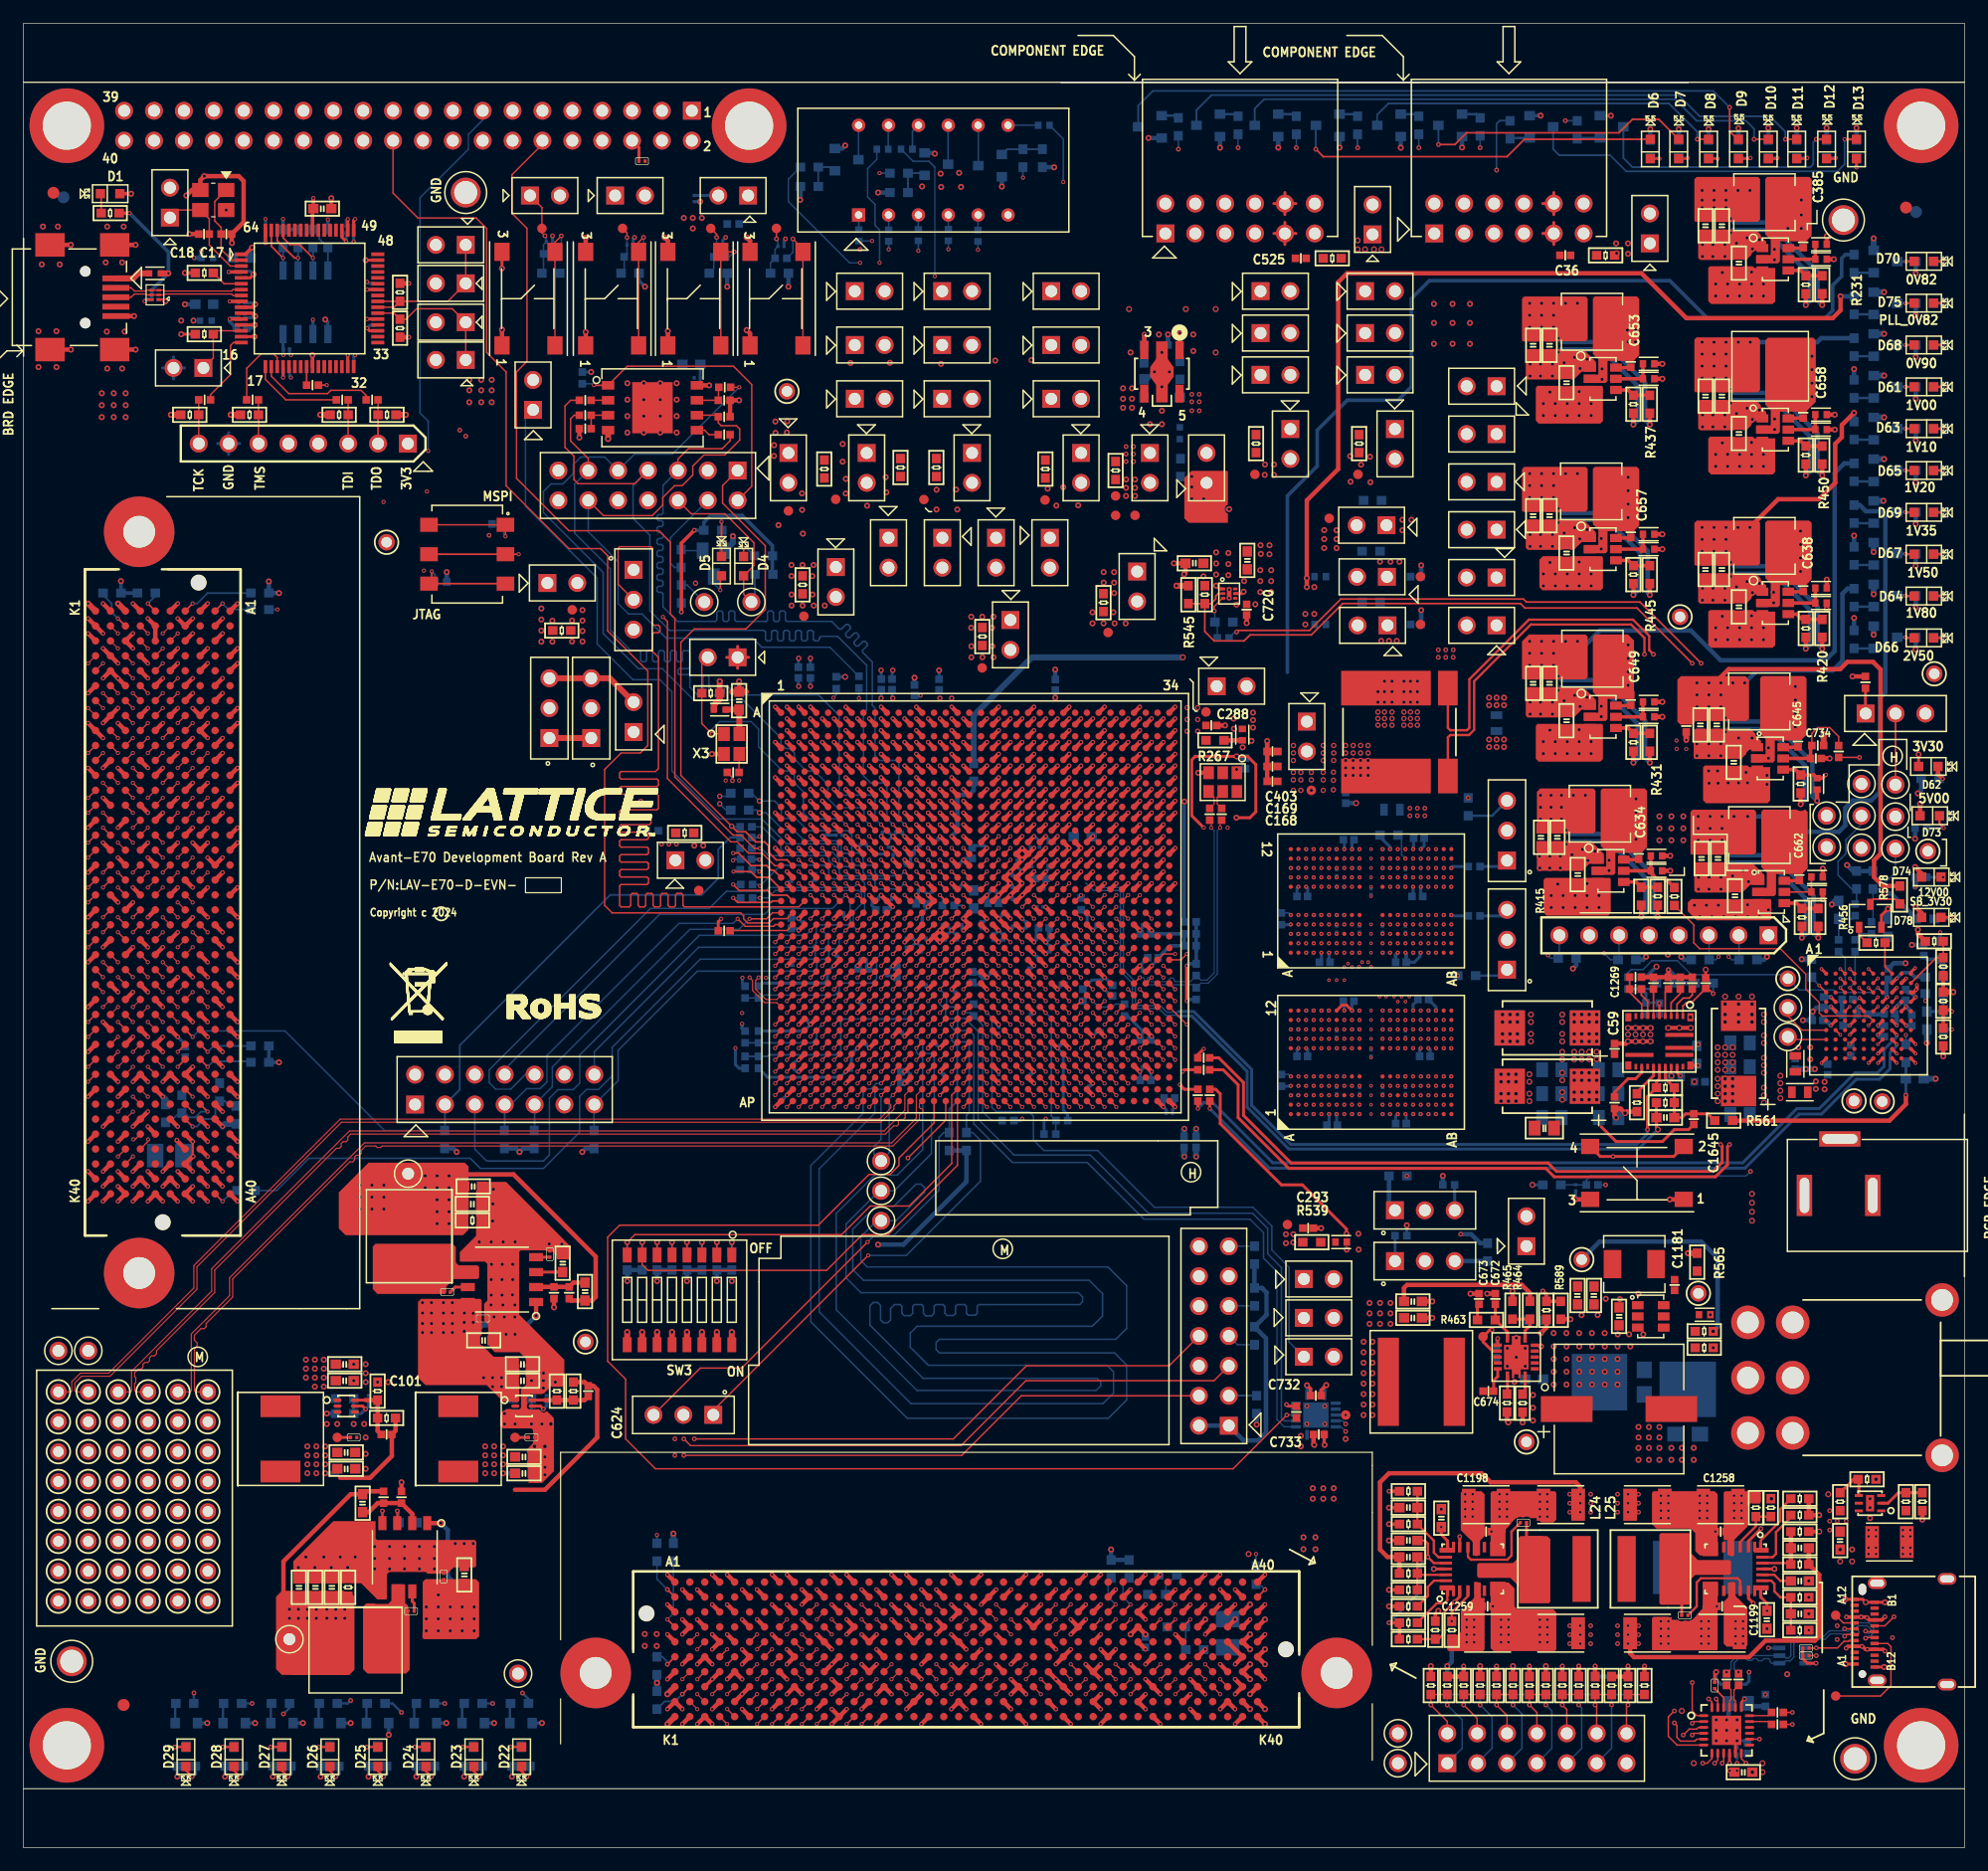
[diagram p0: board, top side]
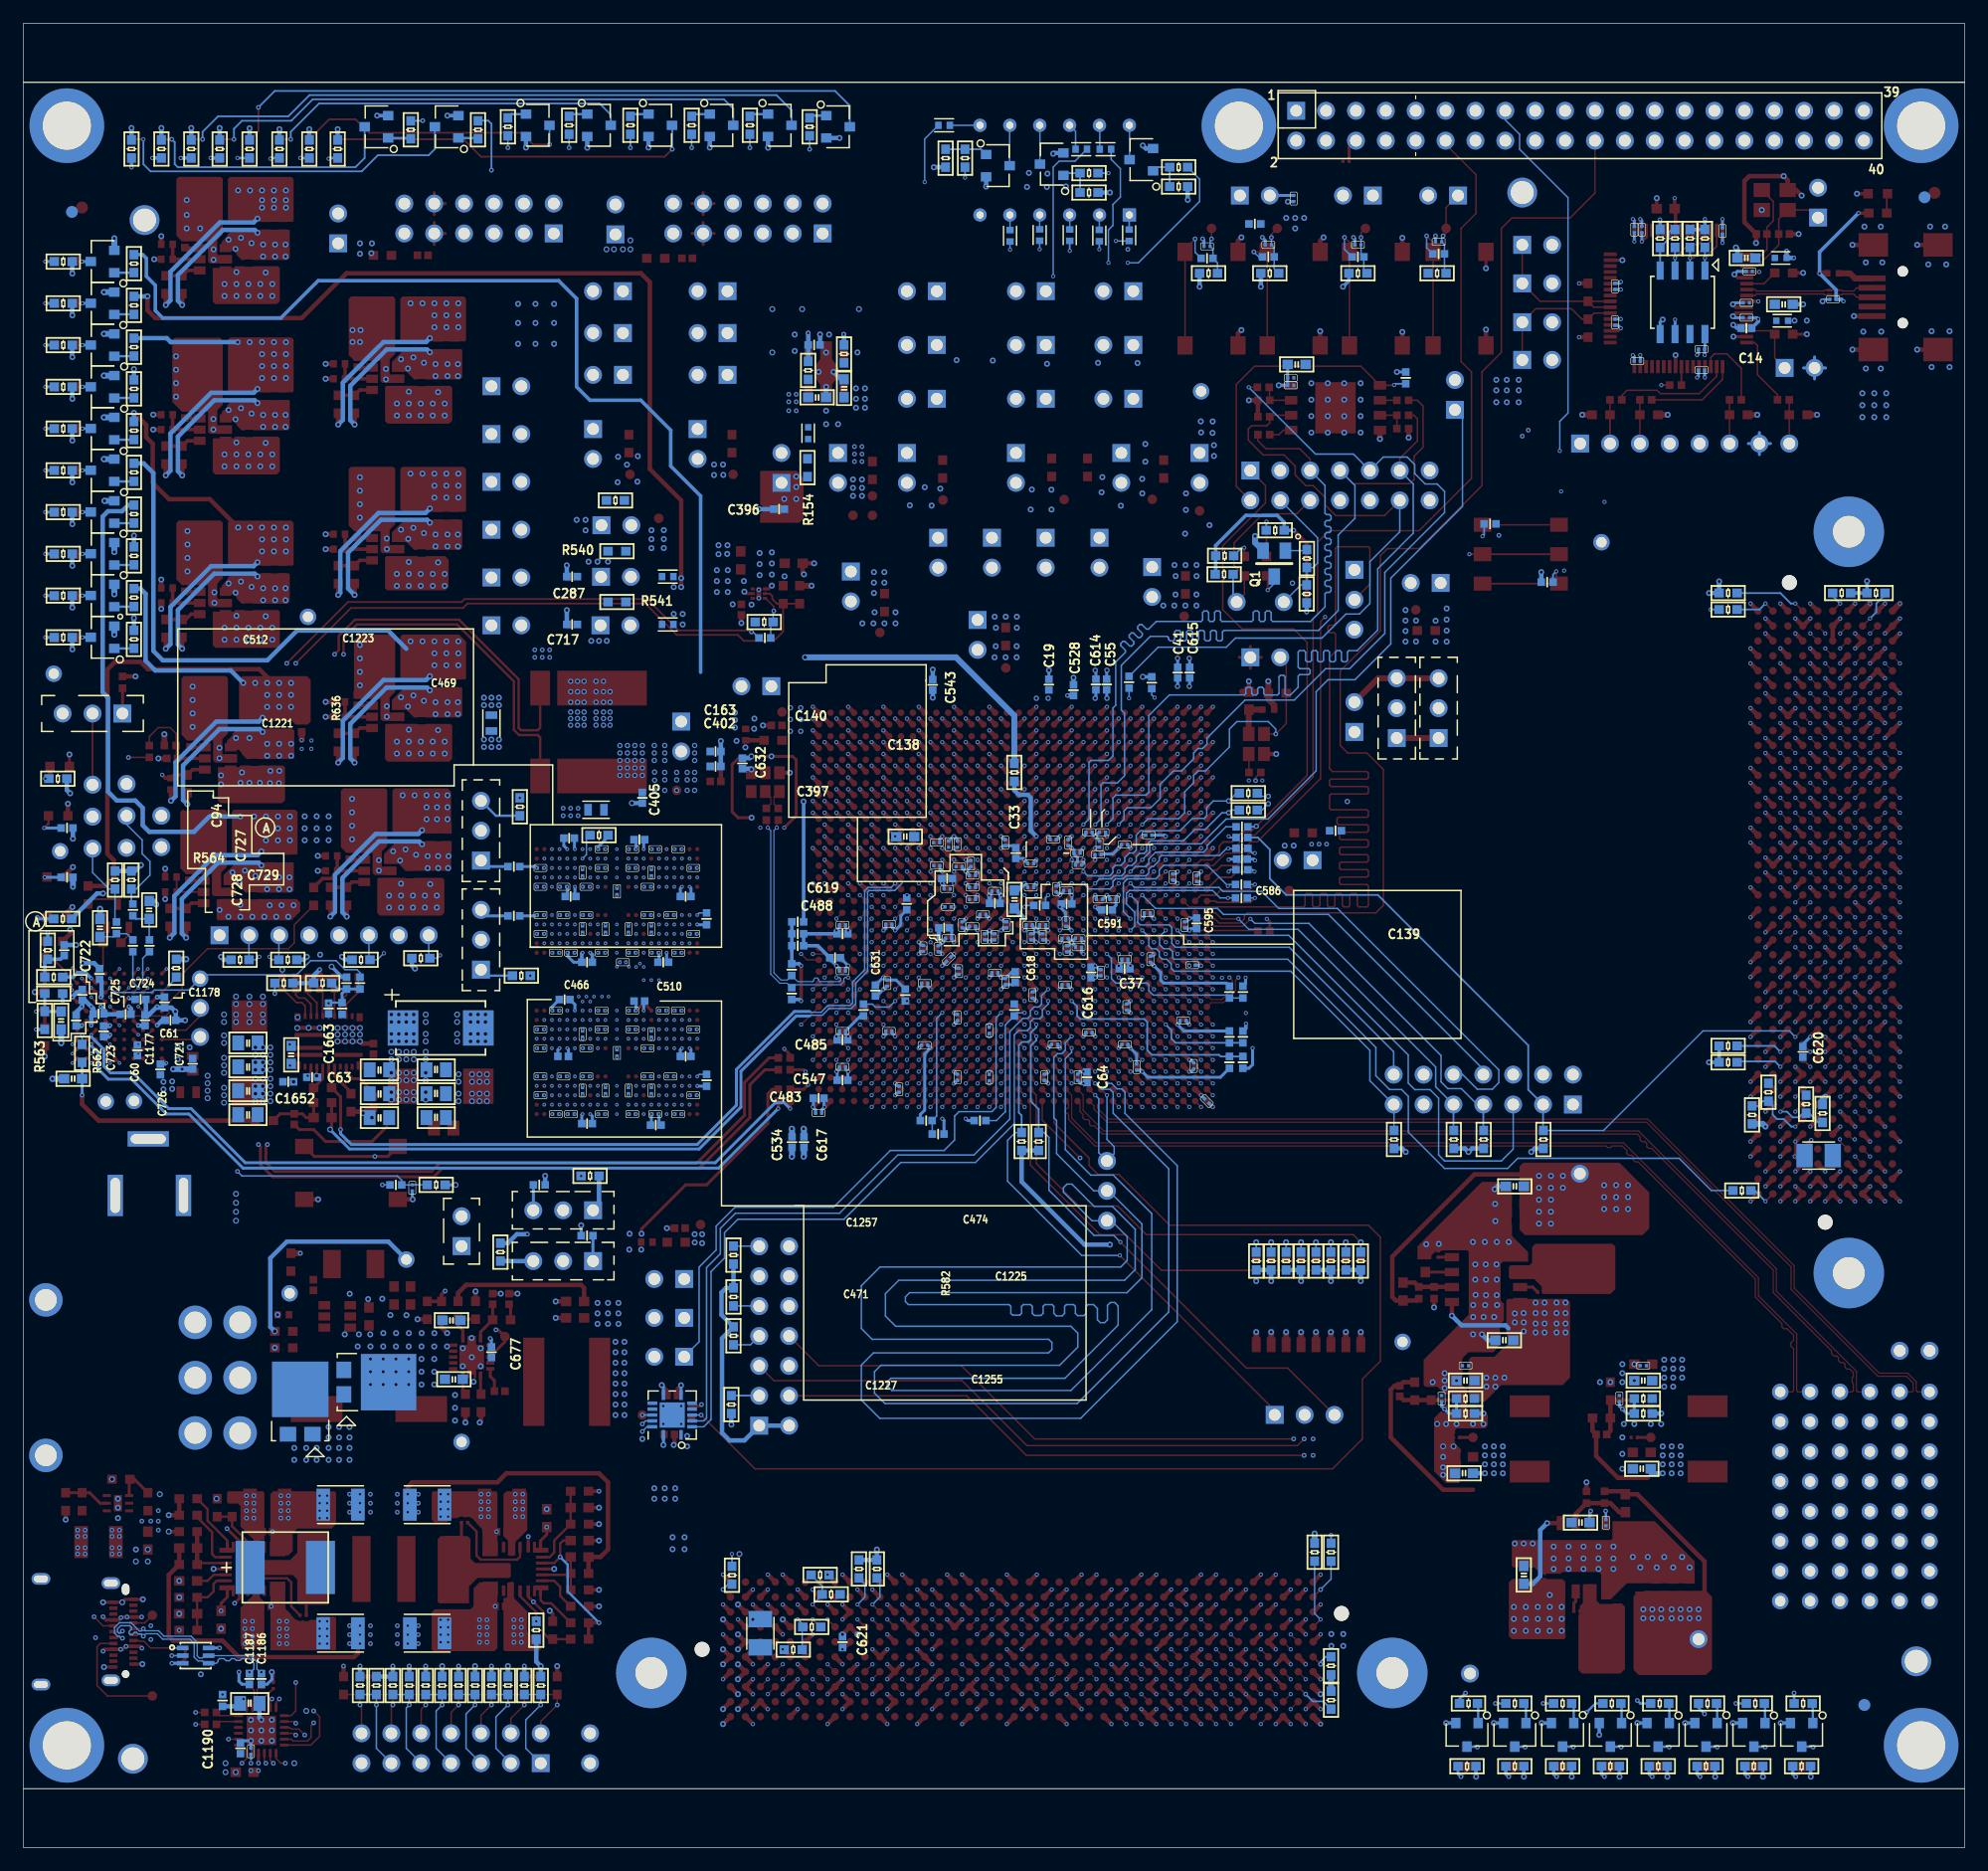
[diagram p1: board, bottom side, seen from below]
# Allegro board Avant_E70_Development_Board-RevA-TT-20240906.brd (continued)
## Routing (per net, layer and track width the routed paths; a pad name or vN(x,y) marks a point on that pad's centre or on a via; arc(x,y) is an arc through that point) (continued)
FMC2_LA05_P: length 96.8
  TOP w0.124: U3.AE18 v2(81.9,71.93) ; J54.D11 v2(68.71,18.11)
  L03-SIG1 w0.081: v2(68.71,18.11) 68.71,18.56 68.63,18.64 68.24,18.64 67.99,18.89 67.99,29.06 68.57,29.65 68.57,29.76 68.21,30.12 68.21,30.41 68.56,30.76 68.85,30.76 69.21,30.4 69.33,30.4 69.56,30.63 69.56,30.75 69.13,31.17 69.13,31.46 69.48,31.81 69.77,31.81 70.2,31.39 70.31,31.39 70.54,31.62 70.54,31.73 70.12,32.16 70.12,32.44 70.47,32.8 70.76,32.8 71.18,32.37 71.3,32.37 71.53,32.6 71.53,32.72 71.1,33.14 71.1,33.43 71.45,33.78 71.74,33.78 72.17,33.36 72.28,33.36 72.51,33.59 72.51,33.7 72.09,34.13 72.09,34.41 72.44,34.77 72.73,34.77 73.15,34.34 73.27,34.34 73.68,34.75 73.68,39.43 74.79,40.54 74.79,40.65 73.21,42.23 73.21,42.52 73.56,42.87 73.85,42.87 75.43,41.29 75.54,41.29 75.78,41.52 75.78,41.64 74.19,43.22 74.19,43.51 74.55,43.86 74.83,43.86 76.42,42.28 76.53,42.28 76.76,42.51 76.76,42.62 75.18,44.2 75.18,44.49 75.53,44.84 75.82,44.84 77.4,43.26 77.51,43.26 77.75,43.49 77.75,43.61 76.16,45.19 76.16,45.48 76.52,45.83 76.8,45.83 78.39,44.25 78.5,44.25 78.73,44.48 78.73,44.59 77.15,46.17 77.15,46.46 77.5,46.81 77.79,46.81 79.37,45.23 79.48,45.23 79.72,45.46 79.72,45.58 78.13,47.16 78.13,47.45 78.49,47.8 78.77,47.8 79.57,47 79.68,47 79.91,47.23 79.91,47.35 79.12,48.14 79.12,48.43 80.31,49.62 80.31,67.57 81.33,68.59 81.33,71.35 81.53,71.55 82.09,71.55 82.19,71.66 82.19,71.83 82.09,71.93 v2(81.9,71.93)
FMC2_LA06_N: length 99.2
  TOP w0.099: J54.C11 v2(67.44,19.38)
  TOP w0.152: U3.AA18 v2(81.9,75.93)
  L03-SIG1 w0.081: v2(81.9,75.93) 81.2,75.23 81.2,73.37 80.26,72.44 80.26,68.75 80.01,68.5 79.5,68.5 79.29,68.3 79.29,50.16 72.21,43.07 72.21,42.48 72.13,42.4 70.97,42.4 70.76,42.2 70.76,41.7 70.97,41.5 72.13,41.5 72.21,41.42 72.21,41.09 72.13,41.01 70.97,41.01 70.76,40.81 70.76,40.31 70.97,40.11 72.13,40.11 72.21,40.02 72.21,39.7 72.13,39.62 70.97,39.62 70.76,39.42 70.76,38.92 70.97,38.71 72.13,38.71 72.21,38.63 72.21,38.31 72.13,38.23 70.97,38.23 70.76,38.02 70.76,37.53 70.97,37.32 72.13,37.32 72.21,37.24 72.21,35.92 71.95,35.66 71.83,35.66 71.18,36.32 70.89,36.32 70.54,35.96 70.54,35.68 71.19,35.02 71.19,34.91 70.96,34.68 70.85,34.68 70.19,35.33 69.9,35.33 69.55,34.98 69.55,34.69 70.21,34.04 70.21,33.92 69.98,33.69 69.86,33.69 69.21,34.35 68.92,34.35 68.57,33.99 68.57,33.71 69.22,33.05 69.22,32.94 68.99,32.71 68.88,32.71 68.22,33.36 67.93,33.36 67.58,33.01 67.58,32.72 68.24,32.07 68.24,31.95 68.01,31.72 67.89,31.72 67.24,32.38 66.95,32.38 66.6,32.02 66.6,31.74 67.25,31.08 67.25,30.97 67.02,30.74 66.91,30.74 66.25,31.39 65.96,31.39 65.61,31.04 65.61,30.75 66.27,30.1 66.27,29.98 65.55,29.27 65.55,27.74 65.76,27.54 66.84,27.54 66.92,27.46 66.92,27.13 66.84,27.05 65.76,27.05 65.55,26.85 65.55,26.35 65.76,26.15 66.84,26.15 66.92,26.06 66.92,25.74 66.84,25.66 65.76,25.66 65.55,25.45 65.55,24.96 65.76,24.75 66.84,24.75 66.92,24.67 66.92,24.35 66.84,24.27 65.76,24.27 65.55,24.06 65.55,23.57 65.76,23.36 66.84,23.36 66.92,23.28 66.92,22.96 66.84,22.87 65.76,22.87 65.55,22.67 65.55,20.3 65.95,19.91 67.36,19.91 67.44,19.83 v2(67.44,19.38)
FMC2_LA06_P: length 99.7
  TOP w0.099: 66.8,20.01 v2(67.44,20.65)
  TOP w0.152: U3.AB18 v2(81.9,74.93)
  L03-SIG1 w0.081: v2(67.44,20.65) 67.44,20.2 67.36,20.12 67.02,20.12 66.94,20.2 66.94,20.31 66.86,20.39 66.7,20.39 66.61,20.31 66.61,20.2 66.53,20.12 66.04,20.12 65.76,20.39 65.76,20.96 65.91,21.11 65.91,21.28 65.76,21.43 65.76,22.58 65.84,22.67 66.93,22.67 67.13,22.87 67.13,23.37 66.93,23.57 65.84,23.57 65.76,23.65 65.76,23.98 65.84,24.06 66.93,24.06 67.13,24.26 67.13,24.76 66.93,24.96 65.84,24.96 65.76,25.04 65.76,25.37 65.84,25.45 66.93,25.45 67.13,25.65 67.13,26.15 66.93,26.35 65.84,26.35 65.76,26.44 65.76,26.76 65.84,26.84 66.93,26.84 67.13,27.04 67.13,27.54 66.93,27.75 65.84,27.75 65.76,27.83 65.76,29.18 66.47,29.9 66.47,30.18 65.82,30.84 65.82,30.95 66.05,31.18 66.17,31.18 66.82,30.53 67.11,30.53 67.46,30.88 67.46,31.17 66.81,31.82 66.81,31.94 67.04,32.17 67.15,32.17 67.81,31.51 68.09,31.51 68.44,31.87 68.44,32.15 67.79,32.81 67.79,32.92 68.02,33.15 68.14,33.15 68.79,32.5 69.08,32.5 69.43,32.85 69.43,33.14 68.78,33.79 68.78,33.91 69.01,34.14 69.12,34.14 69.78,33.48 70.06,33.48 70.41,33.84 70.41,34.12 69.76,34.78 69.76,34.89 69.99,35.12 70.11,35.12 70.76,34.47 71.05,34.47 71.4,34.82 71.4,35.11 70.75,35.76 70.75,35.88 70.98,36.11 71.09,36.11 71.75,35.45 72.03,35.45 72.42,35.84 72.42,37.33 72.21,37.53 71.05,37.53 70.97,37.61 70.97,37.94 71.05,38.02 72.21,38.02 72.42,38.22 72.42,38.72 72.21,38.92 71.05,38.92 70.97,39 70.97,39.33 71.05,39.41 72.21,39.41 72.42,39.61 72.42,40.11 72.21,40.31 71.05,40.31 70.97,40.4 70.97,40.72 71.05,40.8 72.21,40.8 72.42,41.01 72.42,41.5 72.21,41.71 71.05,41.71 70.97,41.79 70.97,42.11 71.05,42.19 72.21,42.19 72.42,42.4 72.42,42.98 79.5,50.07 79.5,68.21 79.58,68.29 80.1,68.29 80.47,68.67 80.47,72.35 81.41,73.29 81.41,74.21 81.53,74.34 81.53,74.6 81.41,74.72 81.41,75.14 81.75,75.48 81.93,75.48 82.02,75.4 82.02,75.05 v2(81.9,74.93)
FMC2_LA07_N: length 90
  TOP w0.099: J54.H14 v2(72.52,14.3)
  TOP w0.124: U3.AJ20 v2(83.9,67.93)
  L03-SIG1 w0.081: v2(83.9,67.93) 84.51,67.32 84.51,40.14 84.31,39.94 83.22,39.94 83.14,39.86 83.14,39.53 83.22,39.45 84.31,39.45 84.51,39.25 84.51,38.75 84.31,38.55 83.22,38.55 83.14,38.47 83.14,38.14 83.22,38.06 84.31,38.06 84.51,37.86 84.51,37.36 84.31,37.16 83.22,37.16 83.14,37.07 83.14,36.75 83.22,36.67 84.31,36.67 84.51,36.47 84.51,35.97 84.31,35.76 83.22,35.76 83.14,35.68 83.14,35.36 83.22,35.28 84.31,35.28 84.51,35.07 84.51,34.58 84.31,34.37 83.22,34.37 83.14,34.29 83.14,33.97 83.22,33.88 84.31,33.88 84.51,33.68 84.51,33.18 84.31,32.98 83.22,32.98 83.14,32.9 83.14,32.57 83.22,32.49 84.31,32.49 84.51,32.29 84.51,31.79 84.31,31.59 83.22,31.59 83.14,31.51 83.14,31.18 83.22,31.1 84.31,31.1 84.51,30.9 84.51,29.4 82.16,27.05 81.46,27.05 81.26,27.25 81.26,27.75 81.18,27.83 80.85,27.83 80.77,27.75 80.77,27.25 80.57,27.05 80.07,27.05 79.87,27.25 79.87,27.75 79.79,27.83 79.46,27.83 79.38,27.75 79.38,27.25 79.18,27.05 78.68,27.05 78.48,27.25 78.48,27.75 78.39,27.83 78.07,27.83 77.99,27.75 77.99,27.25 77.79,27.05 77.29,27.05 77.08,27.25 77.08,27.7 77,27.78 76.68,27.78 76.6,27.7 76.6,27.25 76.39,27.05 76.02,27.05 73.28,24.3 73.28,17.62 73.08,17.42 71.64,17.42 71.56,17.33 71.56,16.5 71.64,16.42 73.08,16.42 73.28,16.21 73.28,15.16 72.94,14.82 72.16,14.82 71.99,14.65 71.99,14.38 72.07,14.3 v2(72.52,14.3)
FMC2_LA07_P: length 90.4
  TOP w0.099: J54.H13 v2(71.25,14.3)
  TOP w0.124: U3.AK20 v2(83.9,66.93)
  L03-SIG1 w0.081: v2(71.25,14.3) 71.7,14.3 71.78,14.38 71.78,14.74 72.07,15.03 72.86,15.03 73.07,15.25 73.07,16.13 72.99,16.21 71.55,16.21 71.35,16.41 71.35,17.42 71.55,17.62 72.99,17.62 73.07,17.71 73.07,24.39 75.94,27.26 76.31,27.26 76.39,27.34 76.39,27.78 76.59,27.99 77.09,27.99 77.29,27.78 77.29,27.34 77.37,27.26 77.7,27.26 77.78,27.34 77.78,27.83 77.98,28.04 78.48,28.04 78.68,27.83 78.68,27.34 78.77,27.26 79.09,27.26 79.17,27.34 79.17,27.83 79.38,28.04 79.87,28.04 80.08,27.83 80.08,27.34 80.16,27.26 80.48,27.26 80.56,27.34 80.56,27.83 80.77,28.04 81.27,28.04 81.47,27.83 81.47,27.34 81.55,27.26 82.07,27.26 84.3,29.49 84.3,30.81 84.22,30.89 83.13,30.89 82.93,31.1 82.93,31.59 83.13,31.8 84.22,31.8 84.3,31.88 84.3,32.2 84.22,32.28 83.13,32.28 82.93,32.49 82.93,32.99 83.13,33.19 84.22,33.19 84.3,33.27 84.3,33.59 84.22,33.68 83.13,33.68 82.93,33.88 82.93,34.38 83.13,34.58 84.22,34.58 84.3,34.66 84.3,34.99 84.22,35.07 83.13,35.07 82.93,35.27 82.93,35.77 83.13,35.97 84.22,35.97 84.3,36.05 84.3,36.38 84.22,36.46 83.13,36.46 82.93,36.66 82.93,37.16 83.13,37.36 84.22,37.36 84.3,37.45 84.3,37.77 84.22,37.85 83.13,37.85 82.93,38.06 82.93,38.55 83.13,38.76 84.22,38.76 84.3,38.84 84.3,39.16 84.22,39.24 83.13,39.24 82.93,39.45 82.93,39.94 83.13,40.15 84.22,40.15 84.3,40.23 84.3,62.21 84.18,62.34 84.18,62.54 84.3,62.66 84.3,64.26 84.18,64.39 84.18,64.59 84.3,64.72 84.3,65.25 84.18,65.38 84.18,65.57 84.3,65.7 84.3,66.21 84.18,66.34 84.18,66.59 84.3,66.72 84.3,67.23 84.15,67.38 83.98,67.38 83.9,67.3 v2(83.9,66.93)
FMC2_LA08_N: length 89.8
  TOP w0.124: J54.G13 v2(69.98,14.3) ; U3.AL18 v2(81.9,65.93)
  L05-SIG2 w0.081: v2(81.9,65.93) 81.63,65.66 81.28,65.66 80.39,64.77 80.39,47.33 77.39,44.33 77.39,42.69 77.31,42.61 76.35,42.61 76.15,42.41 76.15,41.91 76.35,41.71 77.31,41.71 77.39,41.63 77.39,41.3 77.31,41.22 76.35,41.22 76.15,41.02 76.15,40.52 76.35,40.31 77.31,40.31 77.39,40.23 77.39,39.91 77.31,39.83 76.35,39.83 76.15,39.62 76.15,39.13 76.35,38.92 77.31,38.92 77.39,38.84 77.39,38.21 77.31,38.12 76.37,38.12 76.17,37.92 76.17,37.42 76.37,37.22 77.31,37.22 77.39,37.14 77.39,36.81 77.31,36.73 76.4,36.73 76.2,36.53 76.2,36.03 76.4,35.83 77.31,35.83 77.39,35.75 77.39,35.42 77.31,35.34 76.4,35.34 76.2,35.14 76.2,34.64 76.4,34.44 77.31,34.44 77.39,34.35 77.39,34.03 77.31,33.95 76.4,33.95 76.2,33.75 76.2,33.25 76.4,33.04 77.31,33.04 77.39,32.96 77.39,32.64 77.31,32.56 76.4,32.56 76.2,32.35 76.2,31.86 76.4,31.65 77.31,31.65 77.39,31.57 77.39,31.25 77.31,31.16 76.4,31.16 76.2,30.96 76.2,30.46 76.4,30.26 77.31,30.26 77.39,30.18 77.39,29.85 77.31,29.77 76.4,29.77 76.2,29.57 76.2,29.07 76.4,28.87 77.31,28.87 77.39,28.79 77.39,28.46 77.31,28.38 76.4,28.38 76.2,28.18 76.2,27.68 76.4,27.48 77.31,27.48 77.39,27.4 77.39,26.68 77.13,26.42 70.57,26.42 70.37,26.21 70.37,25.78 70.29,25.7 69.96,25.7 69.88,25.78 69.88,26.21 69.68,26.42 68.92,26.42 67.97,25.47 67.97,15.1 68.24,14.83 69.9,14.83 69.98,14.75 v2(69.98,14.3)
FMC2_LA08_P: length 89.5
  TOP w0.124: 69.34,14.93 v2(69.98,15.57) ; U3.AM18 v2(81.9,64.93)
  L05-SIG2 w0.081: v2(81.9,64.93) 81.9,65.37 81.82,65.45 81.37,65.45 80.6,64.69 80.6,47.25 77.6,44.24 77.6,42.61 77.39,42.4 76.44,42.4 76.36,42.32 76.36,42 76.44,41.92 77.39,41.92 77.6,41.71 77.6,41.21 77.39,41.01 76.44,41.01 76.36,40.93 76.36,40.6 76.44,40.52 77.39,40.52 77.6,40.32 77.6,39.82 77.39,39.62 76.44,39.62 76.36,39.54 76.36,39.21 76.44,39.13 77.39,39.13 77.6,38.93 77.6,38.12 77.39,37.92 76.46,37.92 76.38,37.83 76.38,37.51 76.46,37.43 77.39,37.43 77.6,37.22 77.6,36.73 77.39,36.52 76.49,36.52 76.41,36.44 76.41,36.12 76.49,36.04 77.39,36.04 77.6,35.83 77.6,35.34 77.39,35.13 76.49,35.13 76.41,35.05 76.41,34.73 76.49,34.64 77.39,34.64 77.6,34.44 77.6,33.94 77.39,33.74 76.49,33.74 76.41,33.66 76.41,33.33 76.49,33.25 77.39,33.25 77.6,33.05 77.6,32.55 77.39,32.35 76.49,32.35 76.41,32.27 76.41,31.94 76.49,31.86 77.39,31.86 77.6,31.66 77.6,31.16 77.39,30.96 76.49,30.96 76.41,30.87 76.41,30.55 76.49,30.47 77.39,30.47 77.6,30.27 77.6,29.77 77.39,29.56 76.49,29.56 76.41,29.48 76.41,29.16 76.49,29.08 77.39,29.08 77.6,28.87 77.6,28.38 77.39,28.17 76.49,28.17 76.41,28.09 76.41,27.77 76.49,27.68 77.39,27.68 77.6,27.48 77.6,26.59 77.22,26.21 70.66,26.21 70.58,26.13 70.58,25.7 70.38,25.49 69.88,25.49 69.67,25.7 69.67,26.13 69.59,26.21 69,26.21 68.18,25.38 68.18,15.18 68.32,15.04 69.9,15.04 69.98,15.12 v2(69.98,15.57)
FMC2_LA09_N: length 95.3
  TOP w0.124: J54.D15 v2(72.52,19.38) ; U3.AF20 v2(83.9,70.93)
  L03-SIG1 w0.081: v2(83.9,70.93) 83.41,70.93 83.31,70.84 83.31,70.5 83.5,70.31 83.5,66.49 83.27,66.26 82.59,66.26 82.5,66.18 82.5,42.89 82.14,42.52 82.14,42.41 82.48,42.07 82.48,41.78 82.13,41.43 81.84,41.43 81.5,41.77 81.39,41.77 80.67,41.05 80.67,40.93 81.12,40.48 81.12,40.19 80.76,39.84 80.48,39.84 80.03,40.29 79.91,40.29 78.99,39.38 78.99,38.61 78.79,38.41 78.01,38.41 77.93,38.33 77.93,38 78.01,37.92 78.79,37.92 78.99,37.72 78.99,37.22 78.79,37.02 77.17,37.02 77.09,36.94 77.09,36.61 77.17,36.53 78.79,36.53 78.99,36.33 78.99,35.83 78.79,35.62 77.2,35.62 77.11,35.54 77.11,35.22 77.2,35.14 78.79,35.14 78.99,34.93 78.99,34.44 78.79,34.23 77.25,34.23 77.17,34.15 77.17,33.83 77.25,33.74 78.79,33.74 78.99,33.54 78.99,32.56 78.54,32.11 78.54,31.99 79.2,31.33 79.2,31.04 78.85,30.69 78.56,30.69 77.07,32.18 76.96,32.18 76.73,31.95 76.73,31.84 78.26,30.31 78.26,30.02 77.9,29.67 77.62,29.67 76.92,30.37 76.8,30.37 76.31,29.87 76.02,29.87 75.19,30.7 75.08,30.7 74.85,30.47 74.85,30.36 75.68,29.53 75.68,29.24 75.32,28.89 75.04,28.89 74.16,29.77 74.04,29.77 73.81,29.54 73.81,29.42 74.69,28.54 74.69,28.26 74.34,27.9 74.05,27.9 73.11,28.85 73,28.85 72.76,28.62 72.76,28.5 73.71,27.56 73.71,27.27 73.35,26.92 73.07,26.92 72.15,27.84 72.04,27.84 71.81,27.61 71.81,27.49 72.72,26.57 72.72,26.29 72.37,25.93 72.08,25.93 71.46,26.56 71.34,26.56 71.11,26.33 71.11,26.21 71.74,25.59 71.74,25.3 70.74,24.3 70.74,20.37 70.99,20.11 71.63,20.11 71.99,19.75 71.99,19.46 72.07,19.38 v2(72.52,19.38)
FMC2_LA09_P: length 94.8
  TOP w0.124: U3.AF19 v2(82.9,70.93) ; J54.D14 v2(71.25,19.38)
  L03-SIG1 w0.081: v2(71.25,19.38) 71.7,19.38 71.78,19.46 71.78,19.67 71.54,19.9 70.91,19.9 70.53,20.28 70.53,24.39 71.53,25.39 71.53,25.5 70.9,26.13 70.9,26.41 71.26,26.77 71.54,26.77 72.17,26.14 72.28,26.14 72.51,26.37 72.51,26.49 71.6,27.4 71.6,27.69 71.95,28.04 72.24,28.04 73.15,27.13 73.27,27.13 73.5,27.36 73.5,27.47 72.56,28.41 72.56,28.7 72.91,29.05 73.2,29.05 74.14,28.11 74.25,28.11 74.48,28.34 74.48,28.46 73.61,29.34 73.61,29.62 73.96,29.98 74.24,29.98 75.12,29.1 75.24,29.1 75.47,29.33 75.47,29.44 74.64,30.27 74.64,30.56 74.99,30.91 75.28,30.91 76.11,30.08 76.22,30.08 76.72,30.58 77,30.58 77.7,29.87 77.82,29.87 78.05,30.1 78.05,30.22 76.52,31.75 76.52,32.04 76.87,32.39 77.16,32.39 78.65,30.9 78.77,30.9 79,31.13 79,31.24 78.33,31.91 78.33,32.19 78.79,32.65 78.79,33.46 78.7,33.54 77.16,33.54 76.96,33.74 76.96,34.24 77.16,34.44 78.7,34.44 78.79,34.52 78.79,34.85 78.7,34.93 77.11,34.93 76.91,35.13 76.91,35.63 77.11,35.83 78.7,35.83 78.79,35.91 78.79,36.24 78.7,36.32 77.08,36.32 76.88,36.52 76.88,37.02 77.08,37.22 78.7,37.22 78.79,37.31 78.79,37.63 78.7,37.71 77.93,37.71 77.72,37.92 77.72,38.41 77.93,38.62 78.7,38.62 78.79,38.7 78.79,39.46 79.82,40.5 80.11,40.5 80.56,40.05 80.68,40.05 80.91,40.28 80.91,40.39 80.46,40.85 80.46,41.13 81.3,41.98 81.59,41.98 81.93,41.64 82.04,41.64 82.27,41.87 82.27,41.99 81.93,42.32 81.93,42.61 82.3,42.97 82.3,66.26 82.5,66.47 83.19,66.47 83.29,66.58 83.29,70.22 83.1,70.41 83.1,70.73 v2(82.9,70.93)
FMC2_LA10_N: length 86.7
  TOP w0.124: J54.C15 v2(72.52,20.65) ; U3.AP20 v2(83.9,62.93)
  L03-SIG1 w0.081: v2(83.9,62.93) 83.9,63.24 83.82,63.32 83.6,63.32 83.52,63.24 83.52,41.66 82.17,40.31 82.17,39.28 81.97,39.08 80.05,39.08 79.96,39 79.96,38.67 80.05,38.59 81.97,38.59 82.17,38.39 82.17,37.89 81.97,37.69 80.05,37.69 79.96,37.6 79.96,37.28 80.05,37.2 81.97,37.2 82.17,37 82.17,36.5 81.97,36.29 80.05,36.29 79.96,36.21 79.96,35.89 80.05,35.81 81.97,35.81 82.17,35.6 82.17,35.11 81.97,34.9 80.05,34.9 79.96,34.82 79.96,34.5 80.05,34.41 81.97,34.41 82.17,34.21 82.17,33.71 81.97,33.51 80.05,33.51 79.96,33.43 79.96,33.1 80.05,33.02 81.97,33.02 82.17,32.82 82.17,32.32 81.97,32.12 80.05,32.12 79.96,32.04 79.96,31.71 80.05,31.63 81.97,31.63 82.17,31.43 82.17,30.93 81.97,30.73 80.05,30.73 79.96,30.65 79.96,30.32 80.05,30.24 83.08,30.24 83.29,30.04 83.29,29.32 82.53,28.57 81.9,28.57 81.69,28.77 81.69,29.15 81.61,29.23 81.29,29.23 81.21,29.15 81.21,28.77 81,28.57 80.51,28.57 80.3,28.77 80.3,29.15 80.22,29.23 79.9,29.23 79.82,29.15 79.82,28.77 79.61,28.57 79.11,28.57 78.91,28.77 78.91,28.99 78.83,29.07 78.5,29.07 78.42,28.99 78.42,28.77 78.22,28.57 76.14,28.57 71.99,24.41 71.99,20.73 72.07,20.65 v2(72.52,20.65)
FMC2_LA10_P: length 86.9
  TOP w0.124: J54.C14 v2(71.25,20.65) ; U3.AN20 v2(83.9,63.93)
  L03-SIG1 w0.081: v2(83.9,63.93) 83.31,63.34 83.31,41.74 81.96,40.39 81.96,39.37 81.88,39.29 79.96,39.29 79.76,39.08 79.76,38.59 79.96,38.38 81.88,38.38 81.96,38.3 81.96,37.98 81.88,37.89 79.96,37.89 79.76,37.69 79.76,37.19 79.96,36.99 81.88,36.99 81.96,36.91 81.96,36.58 81.88,36.5 79.96,36.5 79.76,36.3 79.76,35.8 79.96,35.6 81.88,35.6 81.96,35.52 81.96,35.19 81.88,35.11 79.96,35.11 79.76,34.91 79.76,34.41 79.96,34.21 81.88,34.21 81.96,34.13 81.96,33.8 81.88,33.72 79.96,33.72 79.76,33.52 79.76,33.02 79.96,32.81 81.88,32.81 81.96,32.73 81.96,32.41 81.88,32.33 79.96,32.33 79.76,32.12 79.76,31.63 79.96,31.42 81.88,31.42 81.96,31.34 81.96,31.02 81.88,30.93 79.96,30.93 79.76,30.73 79.76,30.23 79.96,30.03 83,30.03 83.08,29.95 83.08,29.4 82.45,28.77 81.98,28.77 81.9,28.86 81.9,29.23 81.7,29.43 81.2,29.43 81,29.23 81,28.86 80.92,28.77 80.59,28.77 80.51,28.86 80.51,29.23 80.31,29.43 79.81,29.43 79.61,29.23 79.61,28.86 79.53,28.77 79.2,28.77 79.12,28.86 79.12,29.08 78.92,29.28 78.42,29.28 78.21,29.08 78.21,28.86 78.13,28.77 76.06,28.77 71.78,24.49 71.78,20.73 71.7,20.65 v2(71.25,20.65)
FMC2_LA11_N: length 87.2
  TOP w0.124: J54.H17 v2(75.06,14.3) ; U3.AP19 v2(82.9,62.93)
  L05-SIG2 w0.081: v2(82.9,62.93) 82.9,63.3 82.82,63.38 82.65,63.38 82.55,63.29 82.55,62.63 82.65,62.53 82.65,62.33 82.55,62.23 82.55,44.44 82.35,44.23 81.06,44.23 80.98,44.15 80.98,43.83 81.06,43.75 82.35,43.75 82.55,43.54 82.55,43.04 82.35,42.84 81.06,42.84 80.98,42.76 80.98,42.44 81.06,42.35 82.35,42.35 82.55,42.15 82.55,41.65 82.35,41.45 81.06,41.45 80.98,41.37 80.98,41.04 81.06,40.96 82.35,40.96 82.55,40.76 82.55,40.26 82.35,40.06 81.06,40.06 80.98,39.98 80.98,39.65 81.06,39.57 82.35,39.57 82.55,39.37 82.55,38.87 82.35,38.67 81.06,38.67 80.98,38.58 80.98,38.26 81.06,38.18 82.35,38.18 82.55,37.98 82.55,37.48 82.35,37.27 81.36,37.27 81.28,37.19 81.28,36.87 81.36,36.79 82.35,36.79 82.55,36.58 82.55,36.09 82.35,35.88 81.36,35.88 81.28,35.8 81.28,35.48 81.36,35.39 82.35,35.39 82.55,35.19 82.55,34.69 82.35,34.49 81.36,34.49 81.28,34.41 81.28,34.08 81.36,34 82.35,34 82.55,33.8 82.55,32.26 82.17,31.88 82.17,24.43 81.79,24.05 77.1,24.05 77.02,23.97 77.02,23.62 76.81,23.41 76.32,23.41 76.11,23.62 76.11,23.97 76.03,24.05 74.68,24.05 74.42,23.8 74.42,22.69 74.5,22.6 75.59,22.6 75.79,22.4 75.79,21.9 75.59,21.7 74.5,21.7 74.42,21.62 74.42,18.88 74.22,18.68 73.24,18.68 73.16,18.6 73.16,18.27 73.24,18.19 74.22,18.19 74.42,17.99 74.42,16.8 74.55,16.67 74.55,16.47 74.42,16.35 74.42,16.15 74.55,16.02 74.55,15.82 74.42,15.7 74.42,15.5 74.55,15.37 74.55,15.17 74.42,15.05 74.42,14.85 74.55,14.72 74.55,14.52 74.42,14.4 74.42,13.89 74.54,13.77 74.98,13.77 75.06,13.85 v2(75.06,14.3)
FMC2_LA11_P: length 87.1
  TOP w0.124: U3.AN19 v2(82.9,63.93) ; 74.42,13.66 v2(75.06,13.03)
  L05-SIG2 w0.081: v2(75.06,13.03) 75.06,13.48 74.98,13.56 74.46,13.56 74.21,13.8 74.21,17.9 74.13,17.98 73.15,17.98 72.95,18.19 72.95,18.68 73.15,18.89 74.13,18.89 74.21,18.97 74.21,21.71 74.42,21.91 75.5,21.91 75.59,21.99 75.59,22.32 75.5,22.4 74.42,22.4 74.21,22.6 74.21,23.88 74.59,24.26 76.12,24.26 76.32,24.06 76.32,23.7 76.4,23.62 76.73,23.62 76.81,23.7 76.81,24.06 77.01,24.26 81.7,24.26 81.96,24.52 81.96,31.97 82.34,32.35 82.34,33.71 82.26,33.79 81.27,33.79 81.07,34 81.07,34.5 81.27,34.7 82.26,34.7 82.34,34.78 82.34,35.1 82.26,35.19 81.27,35.19 81.07,35.39 81.07,35.89 81.27,36.09 82.26,36.09 82.34,36.17 82.34,36.5 82.26,36.58 81.27,36.58 81.07,36.78 81.07,37.28 81.27,37.48 82.26,37.48 82.34,37.56 82.34,37.89 82.26,37.97 80.98,37.97 80.77,38.17 80.77,38.67 80.98,38.87 82.26,38.87 82.34,38.96 82.34,39.28 82.26,39.36 80.98,39.36 80.77,39.57 80.77,40.06 80.98,40.27 82.26,40.27 82.34,40.35 82.34,40.67 82.26,40.75 80.98,40.75 80.77,40.96 80.77,41.45 80.98,41.66 82.26,41.66 82.34,41.74 82.34,42.06 82.26,42.15 80.98,42.15 80.77,42.35 80.77,42.85 80.98,43.05 82.26,43.05 82.34,43.13 82.34,43.46 82.26,43.54 80.98,43.54 80.77,43.74 80.77,44.24 80.98,44.44 82.26,44.44 82.34,44.52 82.34,63.37 v2(82.9,63.93)
FMC2_LA12_N: length 89.4
  TOP w0.099: 74.42,14.93 v2(73.79,14.3)
  TOP w0.124: U3.AL21 v2(84.9,65.93)
  L03-SIG1 w0.081: v2(84.9,65.93) 85.5,65.33 85.5,38.45 85.58,38.37 86.92,38.37 87.12,38.17 87.12,37.67 86.92,37.47 85.58,37.47 85.5,37.39 85.5,37.06 85.58,36.98 86.92,36.98 87.12,36.78 87.12,36.28 86.92,36.08 85.58,36.08 85.5,35.99 85.5,35.67 85.58,35.59 86.92,35.59 87.12,35.39 87.12,34.89 86.92,34.68 85.58,34.68 85.5,34.6 85.5,34.28 85.58,34.2 86.92,34.2 87.12,33.99 87.12,33.5 86.92,33.29 85.58,33.29 85.5,33.21 85.5,32.89 85.58,32.8 86.92,32.8 87.12,32.6 87.12,32.1 86.92,31.9 85.58,31.9 85.5,31.82 85.5,31.49 85.58,31.41 86.92,31.41 87.12,31.21 87.12,30.71 86.92,30.51 85.58,30.51 85.5,30.43 85.5,30.1 85.58,30.02 86.75,30.02 86.95,29.82 86.95,29.32 86.75,29.12 85.58,29.12 85.27,28.8 85.27,28.69 85.92,28.04 85.92,27.75 85.57,27.4 85.28,27.4 84.63,28.05 84.51,28.05 84.28,27.82 84.28,27.7 84.49,27.5 84.49,27.21 84.14,26.86 83.85,26.86 83.64,27.06 83.53,27.06 82.7,26.23 76.73,26.23 74.55,24.05 74.55,17.73 74.63,17.65 76.73,17.65 76.94,17.44 76.94,16.95 76.73,16.74 74.63,16.74 74.55,16.66 74.55,15.08 74.29,14.83 73.87,14.83 73.79,14.75 v2(73.79,14.3)
FMC2_LA12_P: length 89.2
  TOP w0.099: J54.G15 v2(73.79,15.57)
  TOP w0.124: U3.AM21 v2(84.9,64.93)
  L03-SIG1 w0.081: v2(73.79,15.57) 73.79,15.12 73.87,15.04 74.21,15.04 74.34,15.17 74.34,16.75 74.54,16.95 76.65,16.95 76.73,17.03 76.73,17.36 76.65,17.44 74.54,17.44 74.34,17.64 74.34,24.14 76.65,26.44 82.61,26.44 83.44,27.27 83.73,27.27 83.94,27.06 84.05,27.06 84.28,27.29 84.28,27.41 84.07,27.62 84.07,27.9 84.43,28.25 84.71,28.25 85.36,27.6 85.48,27.6 85.71,27.83 85.71,27.95 85.06,28.6 85.06,28.89 85.5,29.32 86.66,29.32 86.74,29.41 86.74,29.73 86.66,29.81 85.5,29.81 85.29,30.02 85.29,30.51 85.5,30.72 86.83,30.72 86.91,30.8 86.91,31.12 86.83,31.2 85.5,31.2 85.29,31.41 85.29,31.91 85.5,32.11 86.83,32.11 86.91,32.19 86.91,32.52 86.83,32.6 85.5,32.6 85.29,32.8 85.29,33.3 85.5,33.5 86.83,33.5 86.91,33.58 86.91,33.91 86.83,33.99 85.5,33.99 85.29,34.19 85.29,34.69 85.5,34.89 86.83,34.89 86.91,34.97 86.91,35.3 86.83,35.38 85.5,35.38 85.29,35.58 85.29,36.08 85.5,36.28 86.83,36.28 86.91,36.37 86.91,36.69 86.83,36.77 85.5,36.77 85.29,36.98 85.29,37.47 85.5,37.68 86.83,37.68 86.91,37.76 86.91,38.08 86.83,38.16 85.5,38.16 85.29,38.37 85.29,64.18 85.12,64.36 85.12,64.51 85.29,64.69 85.29,65.24 85.15,65.38 84.98,65.38 84.9,65.3 v2(84.9,64.93)
FMC2_LA13_N: length 89.4
  TOP w0.124: J54.D18 v2(76.33,19.38) ; U3.AK22 v2(85.9,66.93)
  L03-SIG1 w0.081: v2(76.33,19.38) 75.88,19.38 75.8,19.46 75.8,22.3 76.1,22.61 76.1,23.27 75.8,23.57 75.8,24.03 76.2,24.43 76.9,24.43 77.1,24.63 77.1,25.39 77.19,25.47 77.51,25.47 77.59,25.39 77.59,24.63 77.79,24.43 78.29,24.43 78.5,24.63 78.5,25.39 78.58,25.47 78.9,25.47 78.98,25.39 78.98,24.63 79.19,24.43 79.68,24.43 79.89,24.63 79.89,25.39 79.97,25.47 80.29,25.47 80.38,25.39 80.38,24.63 80.58,24.43 81.08,24.43 81.28,24.63 81.28,25.39 81.36,25.47 81.69,25.47 81.77,25.39 81.77,24.63 81.97,24.43 82.85,24.43 84.63,26.21 85.47,26.21 88.01,28.75 88.01,38.8 87.81,39 87.2,39 87.12,39.08 87.12,39.41 87.2,39.49 87.81,39.49 88.01,39.69 88.01,40.19 87.81,40.39 86.57,40.39 86.49,40.47 86.49,40.8 86.57,40.88 87.81,40.88 88.01,41.08 88.01,41.58 87.81,41.78 86.57,41.78 86.49,41.87 86.49,42.19 86.57,42.27 87.81,42.27 88.01,42.47 88.01,42.97 87.81,43.18 86.57,43.18 86.49,43.26 86.49,43.58 86.57,43.66 87.81,43.66 88.01,43.87 88.01,44.36 87.81,44.57 86.57,44.57 86.49,44.65 86.49,44.97 86.57,45.06 87.81,45.06 88.01,45.26 88.01,45.76 87.81,45.96 86.57,45.96 86.49,46.04 86.49,46.37 86.57,46.45 87.81,46.45 88.01,46.65 88.01,47.15 87.81,47.35 86.57,47.35 86.49,47.43 86.49,47.76 86.57,47.84 87.81,47.84 88.01,48.04 88.01,48.54 87.81,48.74 86.57,48.74 86.49,48.82 86.49,49.15 86.57,49.23 87.81,49.23 88.01,49.43 88.01,49.93 87.81,50.14 86.57,50.14 86.49,50.22 86.49,66.34 86.28,66.54 85.58,66.54 85.45,66.68 85.45,66.85 85.53,66.93 v2(85.9,66.93)
FMC2_LA13_P: length 89.1
  TOP w0.124: J54.D17 v2(75.06,19.38) ; U3.AK21 v2(84.9,66.93)
  L03-SIG1 w0.081: v2(75.06,19.38) 75.51,19.38 75.59,19.46 75.59,22.39 75.9,22.69 75.9,23.18 75.59,23.49 75.59,24.11 76.11,24.64 76.81,24.64 76.9,24.72 76.9,25.47 77.1,25.68 77.6,25.68 77.8,25.47 77.8,24.72 77.88,24.64 78.21,24.64 78.29,24.72 78.29,25.47 78.49,25.68 78.99,25.68 79.19,25.47 79.19,24.72 79.27,24.64 79.6,24.64 79.68,24.72 79.68,25.47 79.88,25.68 80.38,25.68 80.58,25.47 80.58,24.72 80.66,24.64 80.99,24.64 81.07,24.72 81.07,25.47 81.27,25.68 81.77,25.68 81.98,25.47 81.98,24.72 82.06,24.64 82.77,24.64 84.55,26.42 85.38,26.42 87.8,28.84 87.8,38.71 87.72,38.79 87.12,38.79 86.91,39 86.91,39.49 87.12,39.7 87.72,39.7 87.8,39.78 87.8,40.1 87.72,40.18 86.48,40.18 86.28,40.39 86.28,40.88 86.48,41.09 87.72,41.09 87.8,41.17 87.8,41.49 87.72,41.58 86.48,41.58 86.28,41.78 86.28,42.28 86.48,42.48 87.72,42.48 87.8,42.56 87.8,42.89 87.72,42.97 86.48,42.97 86.28,43.17 86.28,43.67 86.48,43.87 87.72,43.87 87.8,43.95 87.8,44.28 87.72,44.36 86.48,44.36 86.28,44.56 86.28,45.06 86.48,45.26 87.72,45.26 87.8,45.35 87.8,45.67 87.72,45.75 86.48,45.75 86.28,45.95 86.28,46.45 86.48,46.66 87.72,46.66 87.8,46.74 87.8,47.06 87.72,47.14 86.48,47.14 86.28,47.35 86.28,47.84 86.48,48.05 87.72,48.05 87.8,48.13 87.8,48.45 87.72,48.54 86.48,48.54 86.28,48.74 86.28,49.24 86.48,49.44 87.72,49.44 87.8,49.52 87.8,49.85 87.72,49.93 86.48,49.93 86.28,50.13 86.28,66.25 86.2,66.34 85.49,66.34 v2(84.9,66.93)
FMC2_LA14_N: length 87.5
  TOP w0.124: U3.AL23 v2(86.9,65.93) ; J54.C19 v2(77.6,20.65)
  L03-SIG1 w0.081: v2(86.9,65.93) 87.46,65.37 87.46,62.07 87.77,61.75 87.77,61.47 87.38,61.07 87.38,60.96 87.61,60.73 87.72,60.73 88.12,61.12 88.41,61.12 88.9,60.63 88.9,59.97 88.7,59.77 87.36,59.77 87.27,59.69 87.27,59.36 87.36,59.28 88.7,59.28 88.9,59.08 88.9,58.58 88.7,58.38 87.38,58.38 87.3,58.29 87.3,57.97 87.38,57.89 88.7,57.89 88.9,57.69 88.9,57.19 88.7,56.98 87.41,56.98 87.33,56.9 87.33,56.58 87.41,56.5 88.7,56.5 88.9,56.29 88.9,55.8 88.7,55.59 87.46,55.59 87.38,55.51 87.38,55.19 87.46,55.1 88.7,55.1 88.9,54.9 88.9,54.4 88.7,54.2 87.46,54.2 87.38,54.12 87.38,53.79 87.46,53.71 88.7,53.71 88.9,53.51 88.9,53.01 88.7,52.81 87.53,52.81 87.45,52.73 87.45,52.4 87.53,52.32 88.7,52.32 88.9,52.12 88.9,51.62 88.7,51.42 87.51,51.42 87.43,51.34 87.43,51.01 87.51,50.93 88.7,50.93 88.9,50.73 88.9,36.75 88.98,36.67 89.66,36.67 89.87,36.47 89.87,35.97 89.66,35.77 88.98,35.77 88.9,35.68 88.9,35.36 88.98,35.28 89.69,35.28 89.89,35.07 89.89,34.58 89.69,34.37 88.98,34.37 88.9,34.29 88.9,33.97 88.98,33.89 89.69,33.89 89.89,33.68 89.89,33.18 89.69,32.98 88.98,32.98 88.9,32.9 88.9,32.58 88.98,32.49 89.69,32.49 89.89,32.29 89.89,31.79 89.69,31.59 88.98,31.59 88.9,31.51 88.9,31.18 88.98,31.1 89.69,31.1 89.9,30.9 89.9,30.4 89.69,30.2 88.98,30.2 88.9,30.12 88.9,29.79 88.98,29.71 89.64,29.71 89.84,29.51 89.84,29.01 89.64,28.81 88.98,28.81 88.9,28.72 88.9,28.24 85.98,25.32 84.96,25.32 83.26,23.62 77.37,23.62 77.07,23.32 77.07,20.73 77.15,20.65 v2(77.6,20.65)
FMC2_LA14_P: length 87.3
  TOP w0.124: U3.AM23 v2(86.9,64.93) ; J54.C18 v2(76.33,20.65)
  L03-SIG1 w0.081: v2(76.33,20.65) 76.78,20.65 76.86,20.73 76.86,23.4 77.28,23.83 83.17,23.83 84.88,25.53 85.89,25.53 88.69,28.33 88.69,28.81 88.89,29.01 89.55,29.01 89.63,29.1 89.63,29.42 89.55,29.5 88.89,29.5 88.69,29.71 88.69,30.2 88.89,30.41 89.61,30.41 89.69,30.49 89.69,30.81 89.61,30.89 88.89,30.89 88.69,31.1 88.69,31.59 88.89,31.8 89.6,31.8 89.68,31.88 89.68,32.2 89.6,32.29 88.89,32.29 88.69,32.49 88.69,32.99 88.89,33.19 89.6,33.19 89.68,33.27 89.68,33.6 89.6,33.68 88.89,33.68 88.69,33.88 88.69,34.38 88.89,34.58 89.6,34.58 89.68,34.66 89.68,34.99 89.6,35.07 88.89,35.07 88.69,35.27 88.69,35.77 88.89,35.97 89.58,35.97 89.66,36.06 89.66,36.38 89.58,36.46 88.89,36.46 88.69,36.66 88.69,50.64 88.61,50.72 87.42,50.72 87.22,50.92 87.22,51.42 87.42,51.62 88.61,51.62 88.69,51.71 88.69,52.03 88.61,52.11 87.45,52.11 87.24,52.32 87.24,52.81 87.45,53.02 88.61,53.02 88.69,53.1 88.69,53.42 88.61,53.5 87.37,53.5 87.17,53.71 87.17,54.21 87.37,54.41 88.61,54.41 88.69,54.49 88.69,54.81 88.61,54.9 87.37,54.9 87.17,55.1 87.17,55.6 87.37,55.8 88.61,55.8 88.69,55.88 88.69,56.21 88.61,56.29 87.32,56.29 87.12,56.49 87.12,56.99 87.32,57.19 88.61,57.19 88.69,57.27 88.69,57.6 88.61,57.68 87.29,57.68 87.09,57.88 87.09,58.38 87.29,58.58 88.61,58.58 88.69,58.67 88.69,58.99 88.61,59.07 87.27,59.07 87.07,59.28 87.07,59.77 87.27,59.98 88.61,59.98 88.69,60.06 88.69,60.54 88.32,60.91 88.2,60.91 87.81,60.52 87.52,60.52 87.17,60.87 87.17,61.16 87.56,61.55 87.56,61.67 87.25,61.98 87.25,65.25 87.15,65.35 86.98,65.35 86.9,65.27 v2(86.9,64.93)
FMC2_LA15_N: length 89.7
  TOP w0.099: 79.5,13.66 v2(78.87,13.03)
  TOP w0.124: U3.AH22 v2(85.9,68.93)
  L03-SIG1 w0.081: v2(78.87,13.03) 78.87,13.48 78.95,13.56 80.31,13.56 80.85,14.1 80.85,17.26 80.93,17.34 81.7,17.34 81.79,17.26 81.79,16.56 81.99,16.35 82.49,16.35 82.69,16.56 82.69,17.26 82.77,17.34 83.16,17.34 83.36,17.54 83.36,18.67 83.16,18.87 80.93,18.87 80.85,18.95 80.85,20.98 81.08,21.21 83.33,21.21 83.41,21.12 83.41,20.19 83.62,19.99 84.11,19.99 84.32,20.19 84.32,21.12 84.4,21.21 84.73,21.21 85.91,22.38 85.91,23.48 86.07,23.64 87.09,23.64 91.57,28.11 91.57,50.47 91.36,50.67 90.89,50.67 90.81,50.75 90.81,51.08 90.89,51.16 91.36,51.16 91.57,51.36 91.57,51.86 91.36,52.06 90.71,52.06 90.63,52.15 90.63,52.47 90.71,52.55 91.36,52.55 91.57,52.76 91.57,53.25 91.36,53.46 90.71,53.46 90.63,53.54 90.63,53.86 90.71,53.94 91.36,53.94 91.57,54.15 91.57,54.65 91.36,54.85 90.71,54.85 90.63,54.93 90.63,55.25 90.71,55.34 91.36,55.34 91.57,55.54 91.57,56.04 91.36,56.24 90.71,56.24 90.63,56.32 90.63,56.65 90.71,56.73 91.36,56.73 91.57,56.93 91.57,57.43 91.36,57.63 90.71,57.63 90.63,57.71 90.63,58.04 90.71,58.12 91.36,58.12 91.57,58.32 91.57,58.82 91.36,59.02 90.71,59.02 90.63,59.11 90.63,59.43 90.71,59.51 91.36,59.51 91.57,59.71 91.57,60.63 89.49,62.7 89.49,67.19 89.11,67.57 88.73,67.57 88.52,67.78 88.52,68.12 88.14,68.5 85.63,68.5 85.5,68.63 85.5,68.85 85.58,68.93 v2(85.9,68.93)
FMC2_LA15_P: length 90
  TOP w0.099: J54.H19 v2(78.87,14.3)
  TOP w0.124: U3.AH21 v2(84.9,68.93)
  L03-SIG1 w0.081: v2(78.87,14.3) 78.87,13.85 78.95,13.77 79.33,13.77 79.43,13.86 79.66,13.86 79.76,13.77 80.23,13.77 80.65,14.18 80.65,14.54 80.52,14.67 80.52,14.86 80.65,14.99 80.65,15.19 80.52,15.32 80.52,15.51 80.65,15.64 80.65,17.34 80.85,17.55 81.79,17.55 81.99,17.34 81.99,16.64 82.08,16.56 82.4,16.56 82.48,16.64 82.48,17.34 82.68,17.55 83.07,17.55 83.15,17.63 83.15,18.58 83.07,18.67 80.85,18.67 80.65,18.87 80.65,21.07 80.99,21.41 83.42,21.41 83.62,21.21 83.62,20.28 83.7,20.19 84.03,20.19 84.11,20.28 84.11,21.21 84.31,21.41 84.65,21.41 85.7,22.47 85.7,23.57 85.98,23.85 87.01,23.85 91.36,28.2 91.36,50.38 91.28,50.46 90.8,50.46 90.6,50.67 90.6,51.17 90.8,51.37 91.28,51.37 91.36,51.45 91.36,51.77 91.28,51.86 90.63,51.86 90.42,52.06 90.42,52.56 90.63,52.76 91.28,52.76 91.36,52.84 91.36,53.17 91.28,53.25 90.63,53.25 90.42,53.45 90.42,53.95 90.63,54.15 91.28,54.15 91.36,54.23 91.36,54.56 91.28,54.64 90.63,54.64 90.42,54.84 90.42,55.34 90.63,55.54 91.28,55.54 91.36,55.63 91.36,55.95 91.28,56.03 90.63,56.03 90.42,56.24 90.42,56.73 90.63,56.94 91.28,56.94 91.36,57.02 91.36,57.34 91.28,57.42 90.63,57.42 90.42,57.63 90.42,58.12 90.63,58.33 91.28,58.33 91.36,58.41 91.36,58.73 91.28,58.82 90.63,58.82 90.42,59.02 90.42,59.52 90.63,59.72 91.28,59.72 91.36,59.8 91.36,60.54 89.28,62.62 89.28,64.18 89.15,64.31 89.15,64.59 89.28,64.72 89.28,65.22 89.13,65.38 89.13,65.55 89.28,65.71 89.28,66.21 89.13,66.37 89.13,66.57 89.28,66.72 89.28,67.1 89.03,67.36 88.65,67.36 88.31,67.69 88.31,68.03 88.05,68.29 85.54,68.29 85.29,68.54 85.29,68.85 85.21,68.93 v2(84.9,68.93)
FMC2_LA16_N: length 88.8
  TOP w0.099: J54.G19 v2(77.6,15.57)
  TOP w0.124: U3.AJ21 v2(84.9,67.93)
  L03-SIG1 w0.081: v2(77.6,15.57) 77.6,15.12 77.68,15.04 78.07,15.04 78.28,15.25 78.28,16.28 78.48,16.48 79.36,16.48 79.45,16.56 79.45,16.89 79.36,16.97 78.48,16.97 78.28,17.17 78.28,18.8 78.48,19 79.39,19 79.47,19.08 79.47,19.77 79.39,19.85 78.48,19.85 78.28,20.06 78.28,22.36 78.52,22.6 79.12,22.6 79.32,22.4 79.32,21.49 79.41,21.41 79.78,21.41 79.86,21.49 79.86,22.4 80.06,22.6 83.22,22.6 83.57,22.95 83.86,22.95 84.36,22.46 84.47,22.46 84.7,22.69 84.7,22.8 84.21,23.3 84.21,23.59 85.3,24.68 86.36,24.68 90.47,28.79 90.47,37.1 90.39,37.18 89.78,37.18 89.58,37.38 89.58,37.88 89.78,38.08 90.39,38.08 90.47,38.17 90.47,38.49 90.39,38.57 89.78,38.57 89.58,38.78 89.58,39.27 89.78,39.48 90.39,39.48 90.47,39.56 90.47,39.88 90.39,39.96 89.78,39.96 89.58,40.17 89.58,40.67 89.78,40.87 90.39,40.87 90.47,40.95 90.47,41.28 90.39,41.36 89.78,41.36 89.58,41.56 89.58,42.06 89.78,42.26 90.39,42.26 90.47,42.34 90.47,42.67 90.39,42.75 89.78,42.75 89.58,42.95 89.58,43.45 89.78,43.65 90.39,43.65 90.47,43.73 90.47,44.06 90.39,44.14 89.78,44.14 89.58,44.34 89.58,44.84 89.78,45.04 90.39,45.04 90.47,45.13 90.47,45.45 90.39,45.53 89.78,45.53 89.58,45.74 89.58,46.23 89.78,46.44 90.39,46.44 90.47,46.52 90.47,46.84 90.39,46.92 89.78,46.92 89.58,47.13 89.58,47.62 89.78,47.83 90.39,47.83 90.47,47.91 90.47,48.23 90.39,48.32 89.78,48.32 89.58,48.52 89.58,49.02 89.78,49.22 90.39,49.22 90.47,49.3 90.47,49.63 90.39,49.71 89.78,49.71 89.58,49.91 89.58,60.96 88.31,62.23 88.31,65.15 88.19,65.27 88.19,65.5 88.31,65.62 88.31,66.17 88.14,66.34 87.59,66.34 87.29,66.64 87.29,67.18 87.13,67.35 85.48,67.35 v2(84.9,67.93)
FMC2_LA16_P: length 89
  TOP w0.099: J54.G18 v2(77.6,14.3)
  TOP w0.124: U3.AJ22 v2(85.9,67.93)
  L03-SIG1 w0.081: v2(85.9,67.93) 85.68,67.93 85.6,67.85 85.6,67.64 85.68,67.56 87.21,67.56 87.5,67.27 87.5,66.72 87.68,66.55 88.22,66.55 88.52,66.25 88.52,62.32 89.79,61.05 89.79,50 89.87,49.92 90.47,49.92 90.68,49.71 90.68,49.22 90.47,49.01 89.87,49.01 89.79,48.93 89.79,48.61 89.87,48.52 90.47,48.52 90.68,48.32 90.68,47.82 90.47,47.62 89.87,47.62 89.79,47.54 89.79,47.21 89.87,47.13 90.47,47.13 90.68,46.93 90.68,46.43 90.47,46.23 89.87,46.23 89.79,46.15 89.79,45.82 89.87,45.74 90.47,45.74 90.68,45.54 90.68,45.04 90.47,44.84 89.87,44.84 89.79,44.75 89.79,44.43 89.87,44.35 90.47,44.35 90.68,44.15 90.68,43.65 90.47,43.44 89.87,43.44 89.79,43.36 89.79,43.04 89.87,42.96 90.47,42.96 90.68,42.75 90.68,42.26 90.47,42.05 89.87,42.05 89.79,41.97 89.79,41.65 89.87,41.56 90.47,41.56 90.68,41.36 90.68,40.86 90.47,40.66 89.87,40.66 89.79,40.58 89.79,40.25 89.87,40.17 90.47,40.17 90.68,39.97 90.68,39.47 90.47,39.27 89.87,39.27 89.79,39.19 89.79,38.86 89.87,38.78 90.47,38.78 90.68,38.58 90.68,38.08 90.47,37.88 89.87,37.88 89.79,37.8 89.79,37.47 89.87,37.39 90.47,37.39 90.68,37.19 90.68,28.71 86.45,24.48 85.39,24.48 84.41,23.5 84.41,23.39 84.91,22.89 84.91,22.6 84.56,22.25 84.27,22.25 83.77,22.75 83.66,22.75 83.31,22.39 80.15,22.39 80.07,22.31 80.07,21.41 79.86,21.21 79.32,21.21 79.12,21.41 79.12,22.31 79.03,22.39 78.61,22.39 78.49,22.27 78.49,20.14 78.57,20.06 79.48,20.06 79.68,19.86 79.68,19 79.48,18.79 78.57,18.79 78.49,18.71 78.49,17.26 78.57,17.18 79.45,17.18 79.65,16.97 79.65,16.48 79.45,16.27 78.57,16.27 78.49,16.19 78.49,15.16 78.15,14.83 77.68,14.83 77.6,14.75 v2(77.6,14.3)
FMC2_LA17_CLK_N: length 81.9
  TOP w0.099: J54.D21 v2(80.14,18.11)
  TOP w0.124: U3.AM28 v2(91.9,64.93)
  L12-SIG4 w0.081: v2(91.9,64.93) 92.51,64.32 92.51,44.63 91.18,43.31 91.18,43.2 91.8,42.58 91.8,42.27 91.47,41.94 91.16,41.94 90.54,42.56 90.43,42.56 90.2,42.33 90.2,42.21 90.81,41.59 90.81,41.31 90.46,40.95 90.18,40.95 89.56,41.57 89.44,41.57 89.21,41.34 89.21,41.23 89.96,40.48 89.96,40.19 89.6,39.84 89.32,39.84 88.57,40.59 88.46,40.59 88.23,40.36 88.23,40.24 88.98,39.48 88.98,39.2 88.63,38.84 88.34,38.84 87.59,39.6 87.47,39.6 87.24,39.37 87.24,39.26 87.95,38.55 87.95,38.26 87.6,37.91 87.31,37.91 86.6,38.62 86.49,38.62 82.12,34.25 82.12,32.22 81.92,32.01 80.73,32.01 80.65,31.93 80.65,31.61 80.73,31.52 81.92,31.52 82.12,31.32 82.12,30.82 81.92,30.62 80.68,30.62 80.6,30.54 80.6,30.21 80.68,30.13 81.92,30.13 82.12,29.93 82.12,29.43 81.92,29.23 80.68,29.23 80.6,29.15 80.6,28.82 80.68,28.74 81.92,28.74 82.12,28.54 82.12,28.04 81.92,27.84 80.68,27.84 80.6,27.76 80.6,27.43 80.68,27.35 81.92,27.35 82.12,27.15 82.12,26.65 81.92,26.44 80.68,26.44 80.6,26.36 80.6,26.04 80.68,25.96 81.92,25.96 82.12,25.75 82.12,25.26 81.92,25.05 80.68,25.05 80.6,24.97 80.6,24.65 80.68,24.57 81.92,24.57 82.12,24.36 82.12,18.88 81.88,18.64 80.22,18.64 80.14,18.56 v2(80.14,18.11)
FMC2_LA17_CLK_P: length 81.9
  TOP w0.099: 79.5,18.74 v2(80.14,19.38)
  TOP w0.124: U3.AN28 v2(91.9,63.93)
  L12-SIG4 w0.081: v2(80.14,19.38) 80.14,18.93 80.22,18.85 80.62,18.85 80.75,18.97 80.97,18.97 81.1,18.85 81.79,18.85 81.91,18.97 81.91,19.85 81.79,19.98 81.79,20.18 81.91,20.3 81.91,20.5 81.79,20.63 81.79,20.83 81.91,20.95 81.91,24.28 81.83,24.36 80.59,24.36 80.39,24.56 80.39,25.06 80.59,25.26 81.83,25.26 81.91,25.34 81.91,25.67 81.83,25.75 80.59,25.75 80.39,25.95 80.39,26.45 80.59,26.65 81.83,26.65 81.91,26.73 81.91,27.06 81.83,27.14 80.59,27.14 80.39,27.34 80.39,27.84 80.59,28.04 81.83,28.04 81.91,28.13 81.91,28.45 81.83,28.53 80.59,28.53 80.39,28.74 80.39,29.23 80.59,29.44 81.83,29.44 81.91,29.52 81.91,29.84 81.83,29.92 80.59,29.92 80.39,30.13 80.39,30.63 80.59,30.83 81.83,30.83 81.91,30.91 81.91,31.24 81.83,31.32 80.64,31.32 80.44,31.52 80.44,32.02 80.64,32.22 81.83,32.22 81.91,32.3 81.91,34.34 86.4,38.82 86.69,38.82 87.4,38.12 87.51,38.12 87.74,38.35 87.74,38.46 87.03,39.17 87.03,39.46 87.39,39.81 87.67,39.81 88.43,39.05 88.55,39.05 88.78,39.28 88.78,39.4 88.02,40.15 88.02,40.44 88.37,40.79 88.66,40.79 89.4,40.05 89.52,40.05 89.75,40.28 89.75,40.4 89,41.14 89,41.43 89.36,41.78 89.64,41.78 90.26,41.16 90.38,41.16 90.61,41.39 90.61,41.51 89.99,42.12 89.99,42.41 90.34,42.76 90.63,42.76 91.25,42.15 91.39,42.15 91.59,42.35 91.59,42.49 90.97,43.11 90.97,43.4 92.3,44.72 92.3,63.22 92.18,63.34 92.18,63.55 92.3,63.67 92.3,64.24 92.15,64.38 91.98,64.38 91.9,64.3 v2(91.9,63.93)
FMC2_LA18_CLK_N: length 87.3
  TOP w0.099: J54.C23 v2(82.68,20.65)
  TOP w0.124: U3.AK23 v2(86.9,66.93)
  L10-SIG3 w0.081: v2(86.9,66.93) 87.21,66.93 87.29,66.85 87.29,65.62 87.54,65.37 88.15,65.37 88.31,65.21 88.31,45.43 84.46,41.58 84.46,39.59 84.37,39.51 83.26,39.51 83.06,39.3 83.06,38.81 83.26,38.6 84.37,38.6 84.46,38.52 84.46,38.2 84.37,38.12 83.26,38.12 83.06,37.91 83.06,37.41 83.26,37.21 84.37,37.21 84.46,37.13 84.46,36.8 84.37,36.72 83.26,36.72 83.06,36.52 83.06,36.02 83.26,35.82 84.37,35.82 84.46,35.74 84.46,35.41 84.37,35.33 83.26,35.33 83.06,35.13 83.06,34.63 83.26,34.43 84.37,34.43 84.46,34.35 84.46,34.02 84.37,33.94 83.05,33.94 82.85,33.74 82.85,33.24 83.05,33.04 84.37,33.04 84.46,32.95 84.46,32.63 84.37,32.55 82.72,32.55 82.52,32.34 82.52,31.85 82.72,31.64 84.37,31.64 84.46,31.56 84.46,31.24 84.37,31.16 82.67,31.16 82.47,30.95 82.47,30.45 82.67,30.25 84.37,30.25 84.46,30.17 84.46,29.85 84.37,29.76 82.7,29.76 82.49,29.56 82.49,29.06 82.7,28.86 84.37,28.86 84.46,28.78 84.46,28.45 84.37,28.37 82.8,28.37 82.6,28.17 82.6,27.67 82.8,27.47 84.37,27.47 84.46,27.39 84.46,27.06 84.37,26.98 82.77,26.98 82.57,26.78 82.57,26.28 82.77,26.08 84.37,26.08 84.46,25.99 84.46,25.67 84.37,25.59 82.77,25.59 82.57,25.39 82.57,24.89 82.77,24.68 84.37,24.68 84.46,24.6 84.46,20.62 83.95,20.12 83.66,20.12 83.58,20.2 83.58,20.34 83.5,20.42 83.34,20.42 83.26,20.34 83.26,20.2 83.18,20.12 82.76,20.12 82.68,20.2 v2(82.68,20.65)
FMC2_LA18_CLK_P: length 87.2
  TOP w0.099: J54.C22 v2(82.68,19.38)
  TOP w0.124: U3.AK24 v2(87.9,66.93)
  L10-SIG3 w0.081: v2(82.68,19.38) 82.68,19.83 82.76,19.91 84.04,19.91 84.66,20.53 84.66,24.69 84.46,24.89 82.86,24.89 82.78,24.97 82.78,25.3 82.86,25.38 84.46,25.38 84.66,25.58 84.66,26.08 84.46,26.28 82.86,26.28 82.78,26.37 82.78,26.69 82.86,26.77 84.46,26.77 84.66,26.98 84.66,27.47 84.46,27.68 82.89,27.68 82.8,27.76 82.8,28.08 82.89,28.16 84.46,28.16 84.66,28.37 84.66,28.86 84.46,29.07 82.78,29.07 82.7,29.15 82.7,29.47 82.78,29.56 84.46,29.56 84.66,29.76 84.66,30.26 84.46,30.46 82.76,30.46 82.68,30.54 82.68,30.87 82.76,30.95 84.46,30.95 84.66,31.15 84.66,31.65 84.46,31.85 82.81,31.85 82.73,31.93 82.73,32.26 82.81,32.34 84.46,32.34 84.66,32.54 84.66,33.04 84.46,33.24 83.14,33.24 83.06,33.33 83.06,33.65 83.14,33.73 84.46,33.73 84.66,33.93 84.66,34.43 84.46,34.64 83.35,34.64 83.27,34.72 83.27,35.04 83.35,35.12 84.46,35.12 84.66,35.33 84.66,35.82 84.46,36.03 83.35,36.03 83.27,36.11 83.27,36.43 83.35,36.52 84.46,36.52 84.66,36.72 84.66,37.22 84.46,37.42 83.35,37.42 83.27,37.5 83.27,37.83 83.35,37.91 84.46,37.91 84.66,38.11 84.66,38.61 84.46,38.81 83.35,38.81 83.27,38.89 83.27,39.22 83.35,39.3 84.46,39.3 84.66,39.5 84.66,41.49 88.52,45.35 88.52,65.3 88.24,65.58 87.63,65.58 87.5,65.71 87.5,66.85 87.58,66.93 v2(87.9,66.93)
FMC2_LA19_N: length 98.1
  TOP w0.099: J54.H23 v2(82.68,13.03)
  TOP w0.124: U3.AD20 v2(83.9,72.93)
  L05-SIG2 w0.081: v2(83.9,72.93) 83.58,72.93 83.5,72.85 83.5,32.05 83.58,31.96 84.76,31.96 84.96,31.76 84.96,31.26 84.76,31.06 83.16,31.06 83.08,30.98 83.08,30.65 83.16,30.57 84.76,30.57 84.96,30.37 84.96,29.87 84.76,29.67 83.14,29.67 83.06,29.59 83.06,29.26 83.14,29.18 84.76,29.18 84.96,28.98 84.96,28.48 84.76,28.28 83.27,28.28 83.19,28.2 83.19,27.87 83.27,27.79 84.76,27.79 84.96,27.59 84.96,27.09 84.76,26.88 83.27,26.88 83.19,26.8 83.19,26.48 83.27,26.4 84.76,26.4 84.96,26.19 84.96,25.7 84.76,25.49 83.27,25.49 83.19,25.41 83.19,25.09 83.27,25 84.5,25 84.79,24.72 84.79,24.38 84.5,24.1 83.58,24.1 83.5,24.01 83.5,22.8 83.09,22.39 77.25,22.39 77.14,22.29 77.14,15.23 77.29,15.08 79.15,15.08 79.4,15.34 79.4,17.24 79.81,17.65 83.26,17.65 83.5,17.41 83.5,13.92 83.14,13.56 82.76,13.56 82.68,13.48 v2(82.68,13.03)
FMC2_LA19_P: length 98.3
  TOP w0.099: J54.H22 v2(82.68,14.3)
  TOP w0.124: U3.AD19 v2(82.9,72.93)
  L05-SIG2 w0.081: v2(82.9,72.93) 83.21,72.93 83.29,72.85 83.29,72.62 83.13,72.46 83.13,72.29 83.29,72.13 83.29,71.76 83.16,71.62 83.16,71.35 83.29,71.22 83.29,31.96 83.5,31.76 84.67,31.76 84.75,31.67 84.75,31.35 84.67,31.27 83.08,31.27 82.88,31.07 82.88,30.57 83.08,30.36 84.67,30.36 84.75,30.28 84.75,29.96 84.67,29.88 83.05,29.88 82.85,29.67 82.85,29.18 83.05,28.97 84.67,28.97 84.75,28.89 84.75,28.57 84.67,28.48 83.18,28.48 82.98,28.28 82.98,27.78 83.18,27.58 84.67,27.58 84.75,27.5 84.75,27.17 84.67,27.09 83.18,27.09 82.98,26.89 82.98,26.39 83.18,26.19 84.67,26.19 84.75,26.11 84.75,25.78 84.67,25.7 83.18,25.7 82.98,25.5 82.98,25 83.18,24.8 84.41,24.8 84.58,24.63 84.58,24.47 84.41,24.3 83.5,24.3 83.29,24.1 83.29,22.89 83.01,22.6 77.17,22.6 76.94,22.37 76.94,15.14 77.21,14.88 79.23,14.88 79.61,15.25 79.61,17.16 79.9,17.45 83.17,17.45 83.29,17.32 83.29,17.05 83.19,16.94 83.19,16.73 83.29,16.62 83.29,16.4 83.19,16.29 83.19,16.08 83.29,15.97 83.29,15.75 83.19,15.64 83.19,15.43 83.29,15.32 83.29,15.1 83.19,14.99 83.19,14.78 83.29,14.67 83.29,14 83.06,13.77 82.76,13.77 82.68,13.85 v2(82.68,14.3)
FMC2_LA20_N: length 93.8
  TOP w0.124: U3.AE21 v2(84.9,71.93) ; J54.G22 v2(81.41,14.3)
  L12-SIG4 w0.081: v2(81.41,14.3) 82.12,15.01 82.12,15.97 81.71,16.38 78.66,16.38 78.36,16.68 78.36,32.9 79.45,33.99 79.45,34.27 78.96,34.76 78.96,34.87 79.19,35.1 79.31,35.1 79.79,34.62 80.08,34.62 80.43,34.97 80.43,35.26 79.7,35.99 79.7,36.11 79.93,36.34 80.04,36.34 80.78,35.6 81.06,35.6 81.42,35.96 81.42,36.24 80.45,37.21 80.45,37.32 80.69,37.55 80.8,37.55 81.76,36.59 82.05,36.59 82.63,37.17 82.63,37.45 81.67,38.41 81.67,38.52 81.9,38.75 82.02,38.75 82.97,37.8 83.26,37.8 83.61,38.15 83.61,38.44 82.66,39.39 82.66,39.51 82.89,39.74 83,39.74 83.96,38.78 84.24,38.78 84.6,39.14 84.6,39.42 83.64,40.38 83.64,40.49 83.87,40.72 83.99,40.72 84.94,39.77 85.23,39.77 85.58,40.12 85.58,40.41 84.63,41.36 84.63,41.48 84.86,41.71 84.97,41.71 85.93,40.75 86.21,40.75 91.52,46.06 91.52,68.16 91.18,68.5 84.75,68.5 84.5,68.75 84.5,71.57 84.86,71.93 v2(84.9,71.93)
FMC2_LA20_P: length 94
  TOP w0.124: U3.AE20 v2(83.9,71.93) ; J54.G21 v2(81.41,15.57)
  L12-SIG4 w0.081: v2(81.41,15.57) 81.41,15.05 81.49,14.97 81.78,14.97 81.91,15.1 81.91,15.88 81.62,16.18 78.57,16.18 78.15,16.6 78.15,32.99 79.24,34.07 79.24,34.19 78.75,34.67 78.75,34.96 79.11,35.31 79.39,35.31 79.88,34.83 79.99,34.83 80.22,35.06 80.22,35.17 79.49,35.91 79.49,36.19 79.84,36.55 80.13,36.55 80.86,35.81 80.98,35.81 81.21,36.04 81.21,36.16 80.25,37.12 80.25,37.41 80.6,37.76 80.89,37.76 81.85,36.8 81.96,36.8 82.42,37.25 82.42,37.37 81.46,38.32 81.46,38.61 81.81,38.96 82.1,38.96 83.06,38.01 83.17,38.01 83.4,38.24 83.4,38.35 82.45,39.31 82.45,39.59 82.8,39.95 83.09,39.95 84.04,38.99 84.16,38.99 84.39,39.22 84.39,39.34 83.43,40.29 83.43,40.58 83.78,40.93 84.07,40.93 85.03,39.98 85.14,39.98 85.37,40.21 85.37,40.32 84.42,41.28 84.42,41.56 84.77,41.92 85.06,41.92 86.01,40.96 86.13,40.96 91.31,46.15 91.31,68.07 91.1,68.29 84.66,68.29 84.29,68.66 84.29,71.85 84.21,71.93 v2(83.9,71.93)
FMC2_LA21_N: length 93.9
  TOP w0.124: U3.AG21 v2(84.9,69.93) ; J54.H26 v2(86.49,14.3)
  L05-SIG2 w0.081: v2(84.9,69.93) 84.9,70.3 84.98,70.38 85.15,70.38 85.26,70.27 85.26,52 85.47,51.79 86.98,51.79 87.07,51.71 87.07,51.39 86.98,51.31 85.24,51.31 85.03,51.1 85.03,50.61 85.24,50.4 87.04,50.4 87.12,50.32 87.12,50 87.04,49.92 85.24,49.92 85.03,49.71 85.03,49.21 85.24,49.01 87.04,49.01 87.12,48.93 87.12,48.6 87.04,48.52 85.26,48.52 85.06,48.32 85.06,47.82 85.26,47.62 87.06,47.62 87.14,47.54 87.14,47.21 87.06,47.13 85.26,47.13 85.06,46.93 85.06,46.43 85.26,46.23 87.06,46.23 87.14,46.15 87.14,45.82 87.06,45.74 85.24,45.74 85.03,45.54 85.03,45.04 85.24,44.84 87.04,44.84 87.12,44.75 87.12,44.43 87.04,44.35 85.24,44.35 85.03,44.14 85.03,43.65 85.24,43.44 87.06,43.44 87.14,43.36 87.14,43.04 87.06,42.96 85.24,42.96 85.03,42.75 85.03,42.25 85.24,42.05 86.83,42.05 87,41.89 87,41.49 86.74,41.24 86.74,40.71 87,40.46 87,40.1 86.74,39.85 86.74,39.32 87,39.07 87,38.71 86.74,38.46 86.74,37.93 87,37.67 87,37.32 86.74,37.06 86.74,36.54 87,36.28 87,35.93 86.74,35.67 86.74,35.14 87,34.89 87,34.53 86.74,34.28 86.74,33.75 87,33.5 87,33.14 86.74,32.89 86.74,32.36 87,32.11 87,31.75 86.74,31.5 86.74,30.97 87,30.71 87,30.36 86.74,30.1 86.74,29.58 87,29.32 87,28.97 86.74,28.71 86.74,28.18 87,27.93 87,27.57 86.74,27.32 86.74,26.79 87,26.54 87,26.18 86.74,25.93 86.74,25.4 87,25.15 87,24.79 86.74,24.54 86.74,24.01 87,23.75 87,22.12 86.91,22.04 85.64,22.04 85.44,21.84 85.44,21.25 85.64,21.05 86.91,21.05 87,20.97 87,15.86 86.87,15.73 86.87,15.48 87,15.35 87,15.13 86.87,15 86.87,14.78 87,14.65 87,13.85 86.91,13.77 86.57,13.77 86.49,13.85 v2(86.49,14.3)
FMC2_LA21_P: length 94.1
  TOP w0.124: U3.AF21 v2(84.9,70.93) ; J54.H25 v2(86.49,13.03)
  L05-SIG2 w0.081: v2(84.9,70.93) 85.47,70.36 85.47,52.08 85.55,52 87.07,52 87.27,51.8 87.27,51.3 87.07,51.1 85.32,51.1 85.24,51.02 85.24,50.69 85.32,50.61 87.12,50.61 87.33,50.41 87.33,49.91 87.12,49.71 85.32,49.71 85.24,49.63 85.24,49.3 85.32,49.22 87.12,49.22 87.33,49.02 87.33,48.52 87.12,48.31 85.35,48.31 85.27,48.23 85.27,47.91 85.35,47.83 87.15,47.83 87.35,47.62 87.35,47.13 87.15,46.92 85.35,46.92 85.27,46.84 85.27,46.52 85.35,46.44 87.15,46.44 87.35,46.23 87.35,45.73 87.15,45.53 85.32,45.53 85.24,45.45 85.24,45.12 85.32,45.04 87.12,45.04 87.33,44.84 87.33,44.34 87.12,44.14 85.32,44.14 85.24,44.06 85.24,43.73 85.32,43.65 87.15,43.65 87.35,43.45 87.35,42.95 87.15,42.75 85.32,42.75 85.24,42.67 85.24,42.34 85.32,42.26 86.92,42.26 87.2,41.98 87.2,41.41 86.95,41.15 86.95,40.8 87.2,40.54 87.2,40.02 86.95,39.76 86.95,39.41 87.2,39.15 87.2,38.62 86.95,38.37 86.95,38.01 87.2,37.76 87.2,37.23 86.95,36.98 86.95,36.62 87.2,36.37 87.2,35.84 86.95,35.59 86.95,35.23 87.2,34.98 87.2,34.45 86.95,34.19 86.95,33.84 87.2,33.58 87.2,33.06 86.95,32.8 86.95,32.45 87.2,32.19 87.2,31.66 86.95,31.41 86.95,31.05 87.2,30.8 87.2,30.27 86.95,30.02 86.95,29.66 87.2,29.41 87.2,28.88 86.95,28.63 86.95,28.27 87.2,28.02 87.2,27.49 86.95,27.23 86.95,26.88 87.2,26.62 87.2,26.1 86.95,25.84 86.95,25.49 87.2,25.23 87.2,24.7 86.95,24.45 86.95,24.09 87.2,23.84 87.2,22.04 87,21.84 85.73,21.84 85.65,21.75 85.65,21.34 85.73,21.26 87,21.26 87.2,21.05 87.2,13.76 87,13.56 86.57,13.56 86.49,13.48 v2(86.49,13.03)
FMC2_LA22_N: length 100.1
  TOP w0.099: J54.G25 v2(85.22,14.3)
  TOP w0.124: U3.AB20 v2(83.9,74.93)
  L05-SIG2 w0.081: v2(85.22,14.3) 85.93,15.01 85.93,16.98 85.73,17.19 84.95,17.19 84.87,17.27 84.87,17.59 84.95,17.67 85.73,17.67 85.93,17.88 85.93,18.46 85.59,18.8 78.47,18.8 78.36,18.91 78.36,21.16 78.45,21.25 79.29,21.25 79.37,21.17 79.37,20.06 79.57,19.86 80.65,19.86 80.85,20.06 80.85,21.17 80.93,21.25 84.41,21.25 84.64,21.47 84.64,22.44 84.72,22.52 85.61,22.52 85.93,22.85 85.93,32.48 85.69,32.72 84.58,32.72 84.5,32.8 84.5,33.12 84.58,33.2 85.96,33.2 86.19,33.43 86.19,33.91 85.98,34.11 84.58,34.11 84.5,34.19 84.5,34.52 84.58,34.6 85.9,34.6 86.11,34.8 86.11,35.3 85.9,35.5 84.58,35.5 84.5,35.58 84.5,35.91 84.58,35.99 85.9,35.99 86.11,36.19 86.11,36.69 85.9,36.89 84.58,36.89 84.5,36.97 84.5,37.3 84.58,37.38 85.9,37.38 86.11,37.58 86.11,38.08 85.9,38.28 84.58,38.28 84.5,38.37 84.5,38.69 84.58,38.77 85.9,38.77 86.11,38.98 86.11,39.47 85.9,39.68 84.58,39.68 84.5,39.76 84.5,40.08 84.58,40.16 85.9,40.16 86.11,40.37 86.11,40.87 85.9,41.07 84.58,41.07 84.5,41.15 84.5,74.33 v2(83.9,74.93)
FMC2_LA22_P: length 100.5
  TOP w0.099: J54.G24 v2(85.22,15.57)
  TOP w0.124: U3.AC20 v2(83.9,73.93)
  L05-SIG2 w0.081: v2(83.9,73.93) 83.9,74.29 83.99,74.38 84.15,74.38 84.29,74.24 84.29,73.67 84.15,73.53 84.15,73.35 84.29,73.21 84.29,72.68 84.12,72.51 84.12,72.33 84.29,72.16 84.29,71.72 84.12,71.55 84.12,71.34 84.29,71.17 84.29,41.06 84.5,40.86 85.82,40.86 85.9,40.78 85.9,40.45 85.82,40.37 84.5,40.37 84.29,40.17 84.29,39.67 84.5,39.47 85.82,39.47 85.9,39.39 85.9,39.06 85.82,38.98 84.5,38.98 84.29,38.78 84.29,38.28 84.5,38.08 85.82,38.08 85.9,38 85.9,37.67 85.82,37.59 84.5,37.59 84.29,37.39 84.29,36.89 84.5,36.68 85.82,36.68 85.9,36.6 85.9,36.28 85.82,36.2 84.5,36.2 84.29,35.99 84.29,35.5 84.5,35.29 85.82,35.29 85.9,35.21 85.9,34.89 85.82,34.81 84.5,34.81 84.29,34.6 84.29,34.1 84.5,33.9 85.9,33.9 85.98,33.82 85.98,33.52 85.87,33.41 84.5,33.41 84.29,33.21 84.29,32.71 84.5,32.51 85.61,32.51 85.72,32.39 85.72,22.93 85.52,22.73 84.63,22.73 84.43,22.53 84.43,21.56 84.33,21.46 80.84,21.46 80.64,21.26 80.64,20.15 80.56,20.07 79.66,20.07 79.58,20.15 79.58,21.26 79.38,21.46 78.36,21.46 78.15,21.25 78.15,18.82 78.38,18.59 85.51,18.59 85.72,18.37 85.72,17.96 85.64,17.88 84.86,17.88 84.66,17.68 84.66,17.18 84.86,16.98 85.64,16.98 85.72,16.9 85.72,16.29 85.65,16.21 85.65,15.91 85.72,15.84 85.72,15.1 85.58,14.96 85.32,14.96 85.22,15.06 v2(85.22,15.57)
FMC2_LA23_N: length 97.3
  TOP w0.124: U3.AA19 v2(82.9,75.93) ; J54.D24 v2(83.95,19.38)
  L10-SIG3 w0.081: v2(82.9,75.93) 83.29,75.53 84.15,75.53 84.5,75.18 84.5,64.73 84.67,64.56 87.17,64.56 87.49,64.25 87.49,46 80.9,39.42 80.9,34.46 80.7,34.25 79.28,34.25 79.2,34.17 79.2,33.85 79.28,33.77 80.7,33.77 80.9,33.56 80.9,33.07 80.7,32.86 79.25,32.86 79.17,32.78 79.17,32.46 79.25,32.37 80.7,32.37 80.9,32.17 80.9,31.67 80.7,31.47 79.23,31.47 79.15,31.39 79.15,31.06 79.23,30.98 80.7,30.98 80.9,30.78 80.9,30.28 80.7,30.08 79.23,30.08 79.15,30 79.15,29.67 79.23,29.59 80.7,29.59 80.9,29.39 80.9,28.89 80.7,28.69 79.28,28.69 79.2,28.61 79.2,28.28 79.28,28.2 80.7,28.2 80.9,28 80.9,27.5 80.7,27.29 78.59,27.29 78.51,27.21 78.51,26.89 78.59,26.81 80.7,26.81 80.9,26.6 80.9,26.11 80.7,25.9 78.59,25.9 78.51,25.82 78.51,25.5 78.59,25.42 80.62,25.42 80.82,25.21 80.82,24.71 80.62,24.51 78.57,24.51 78.49,24.43 78.49,24.1 78.57,24.02 80.7,24.02 80.9,23.82 80.9,19.35 81.4,18.85 83.87,18.85 83.95,18.93 v2(83.95,19.38)
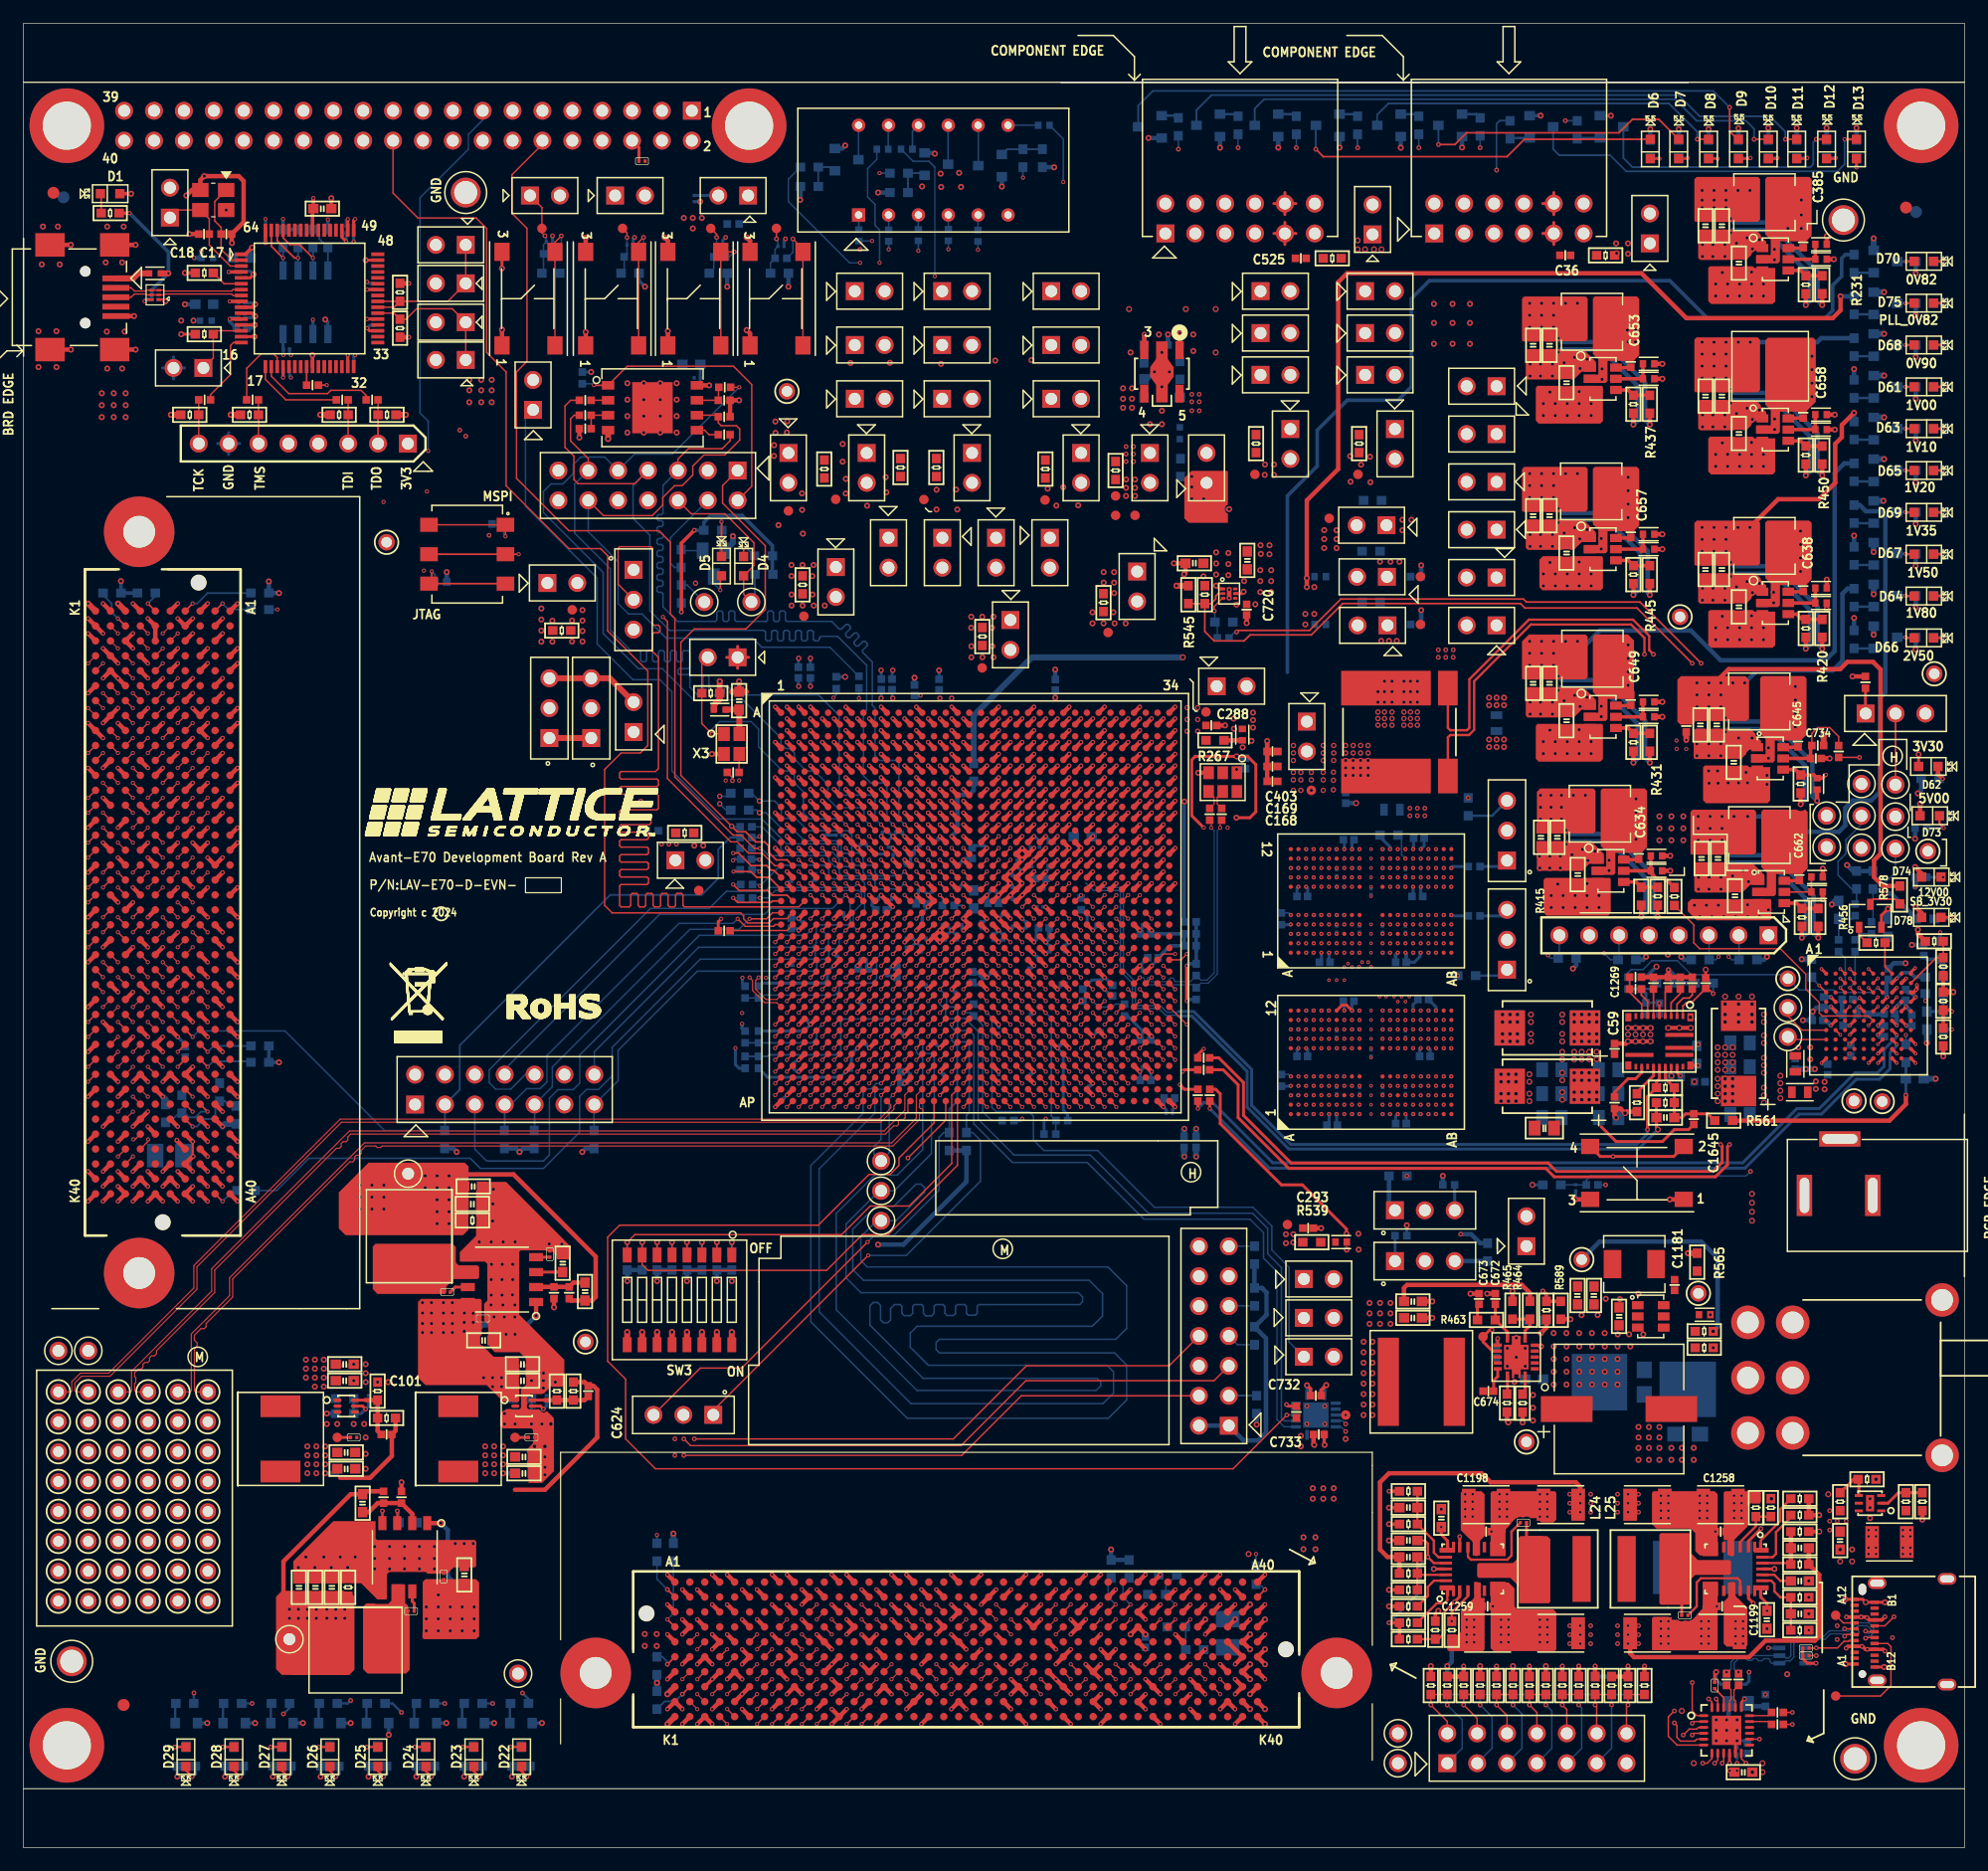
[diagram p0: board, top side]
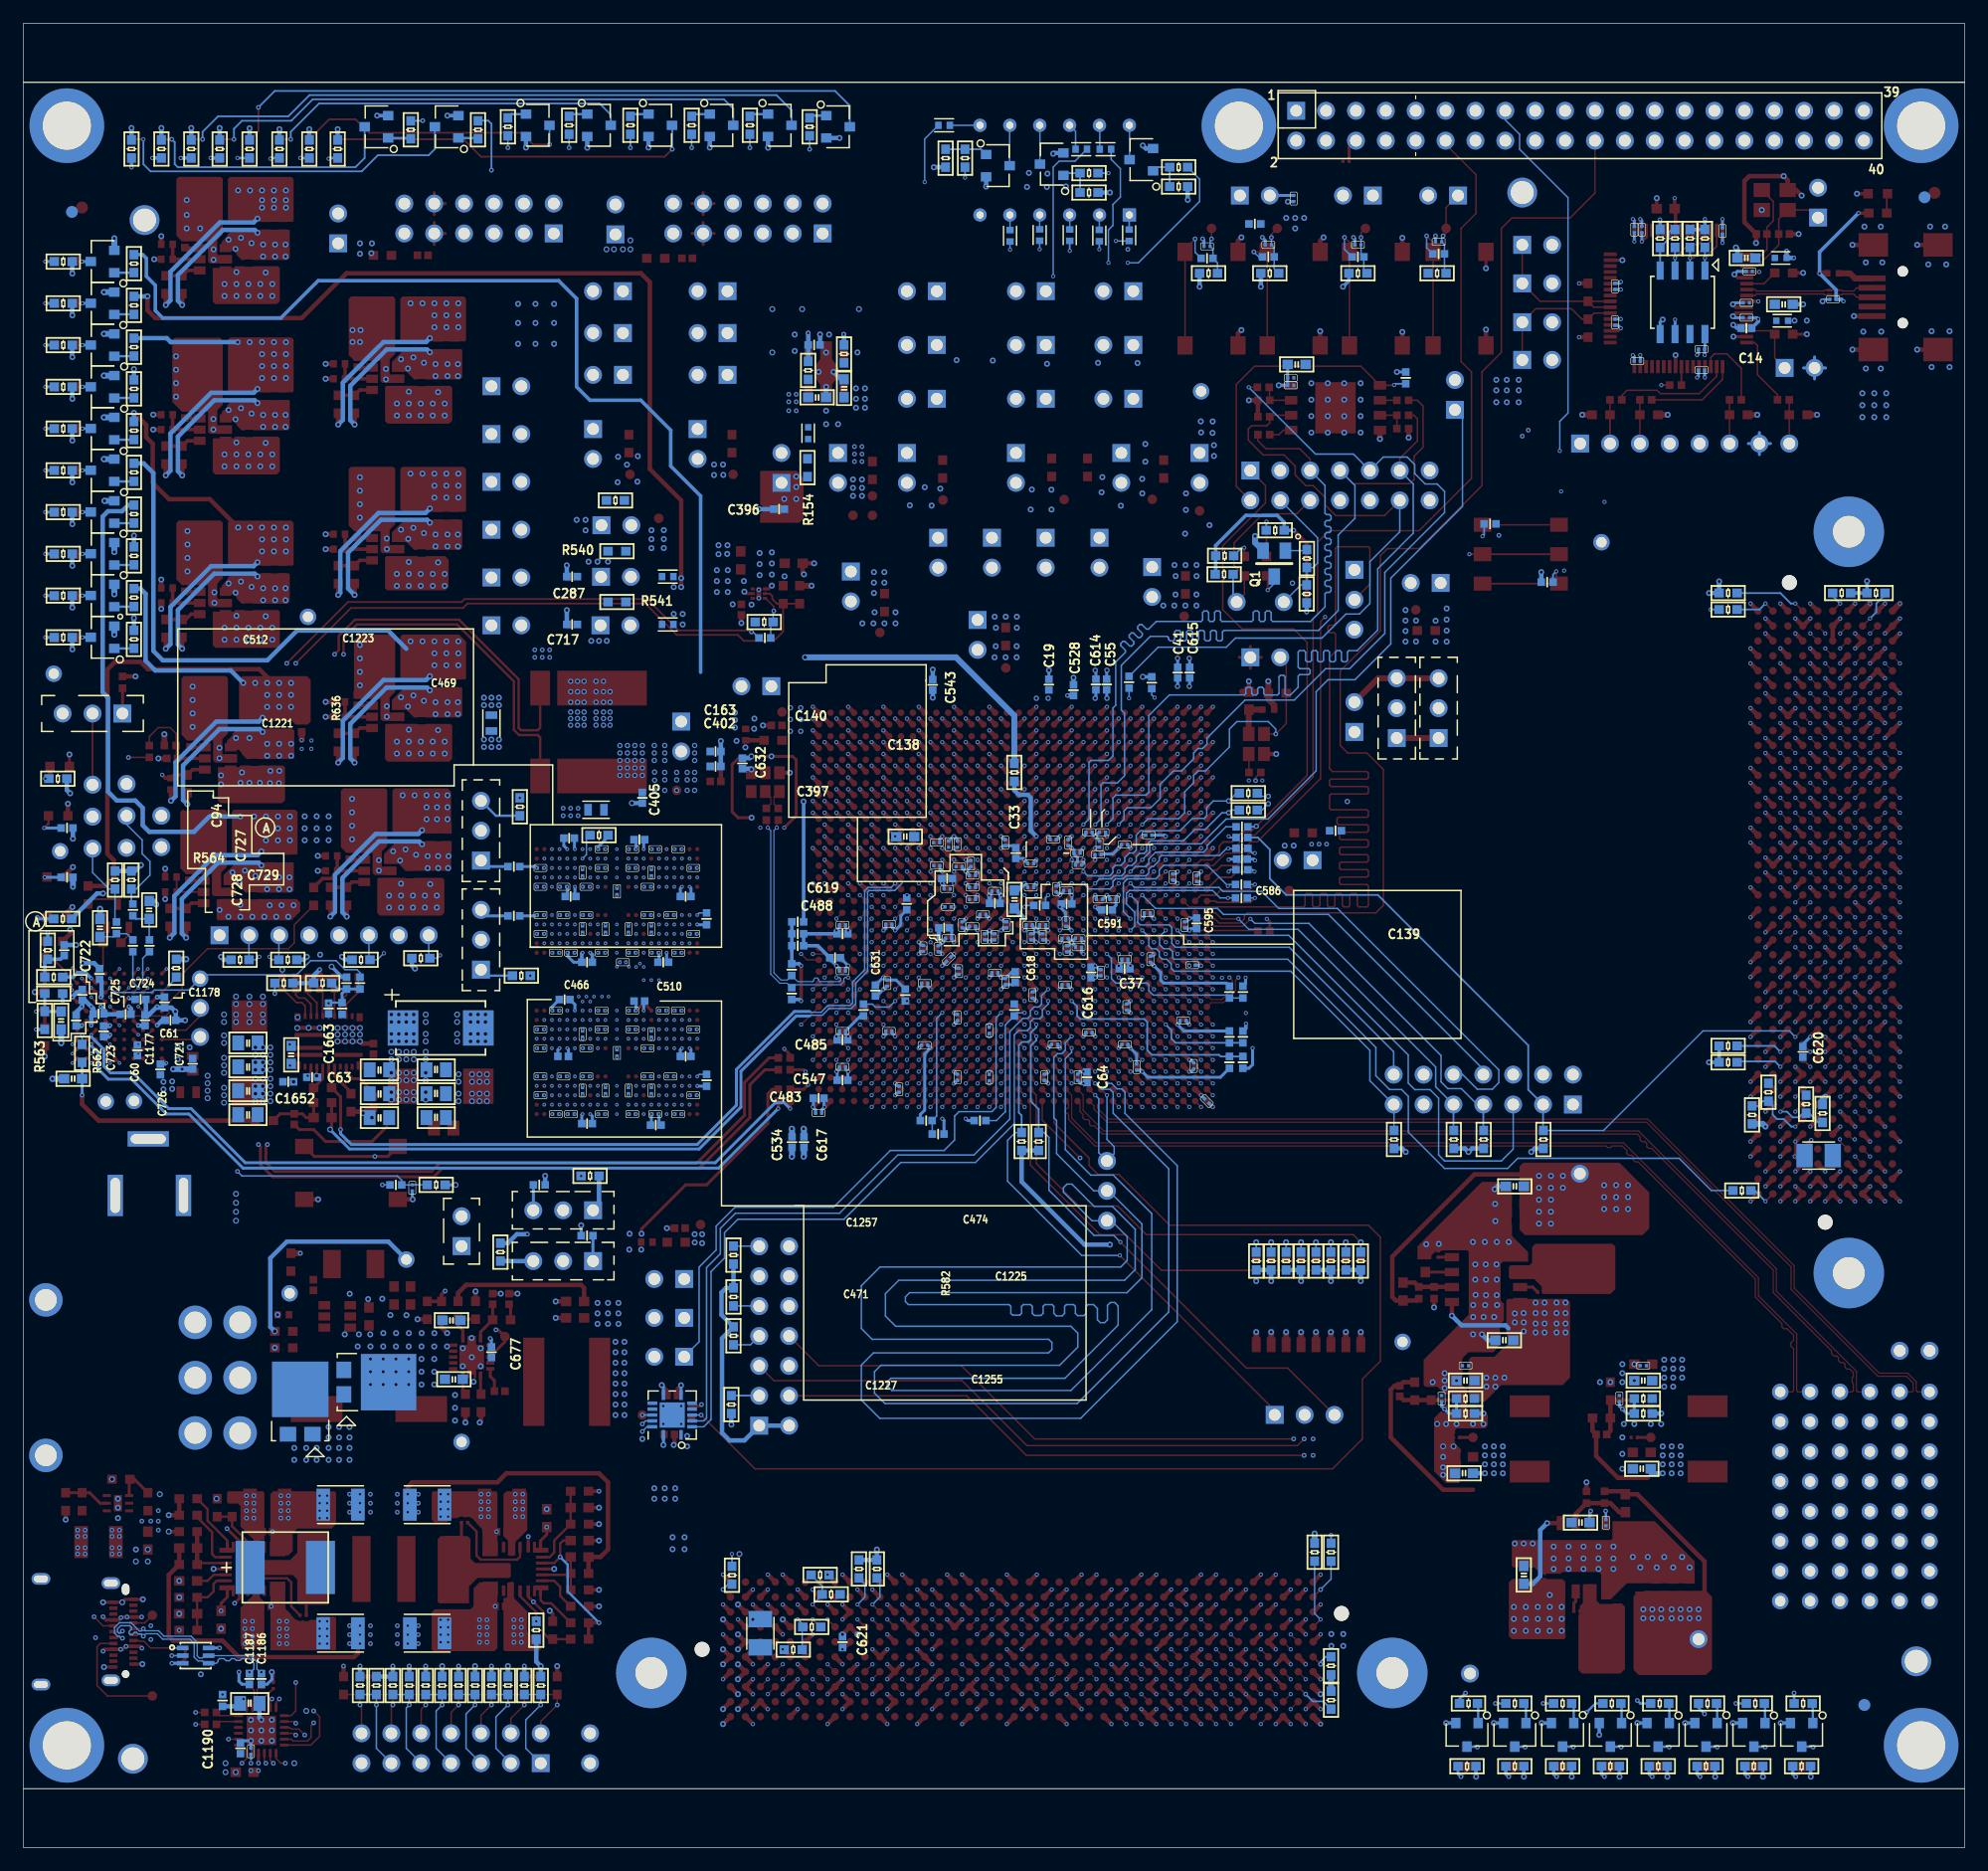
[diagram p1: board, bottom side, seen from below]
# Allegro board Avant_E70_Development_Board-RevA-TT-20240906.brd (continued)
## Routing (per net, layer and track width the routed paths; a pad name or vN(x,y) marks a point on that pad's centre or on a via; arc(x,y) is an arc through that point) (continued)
FMC2_LA23_P: length 97.9
  TOP w0.124: J54.D23 v2(83.95,18.11) ; U3.AB19 v2(82.9,74.93)
  L10-SIG3 w0.081: v2(83.95,18.11) 83.95,18.56 83.87,18.64 81.32,18.64 80.69,19.26 80.69,23.73 80.61,23.82 78.48,23.82 78.28,24.02 78.28,24.52 78.48,24.72 80.53,24.72 80.61,24.8 80.61,25.13 80.53,25.21 78.51,25.21 78.3,25.41 78.3,25.91 78.51,26.11 80.61,26.11 80.69,26.19 80.69,26.52 80.61,26.6 78.51,26.6 78.3,26.8 78.3,27.3 78.51,27.5 80.61,27.5 80.69,27.58 80.69,27.91 80.61,27.99 79.19,27.99 78.99,28.19 78.99,28.69 79.19,28.9 80.61,28.9 80.69,28.98 80.69,29.3 80.61,29.38 79.14,29.38 78.94,29.59 78.94,30.08 79.14,30.29 80.61,30.29 80.69,30.37 80.69,30.69 80.61,30.77 79.14,30.77 78.94,30.98 78.94,31.48 79.14,31.68 80.61,31.68 80.69,31.76 80.69,32.09 80.61,32.17 79.17,32.17 78.96,32.37 78.96,32.87 79.17,33.07 80.61,33.07 80.69,33.15 80.69,33.48 80.61,33.56 79.19,33.56 78.99,33.76 78.99,34.26 79.19,34.46 80.61,34.46 80.69,34.54 80.69,39.5 87.28,46.09 87.28,64.16 87.09,64.35 84.59,64.35 84.29,64.65 84.29,72.23 84.15,72.38 84.15,72.59 84.29,72.73 84.29,73.28 84.18,73.39 84.18,73.66 84.29,73.78 84.29,74.27 84.15,74.42 84.15,74.6 84.29,74.74 84.29,75.1 84.07,75.33 82.98,75.33 82.9,75.24 v2(82.9,74.93)
FMC2_LA24_N: length 90.4
  TOP w0.099: J54.H29 v2(90.3,13.03)
  TOP w0.124: U3.AG24 v2(87.9,69.93)
  L05-SIG2 w0.081: v2(90.3,13.03) 90.3,13.48 90.38,13.56 90.73,13.56 91.06,13.89 91.06,17.86 90.86,18.06 90.46,18.06 90.38,18.14 90.38,18.47 90.46,18.55 90.86,18.55 91.06,18.75 91.06,21.54 90.86,21.74 89.74,21.74 89.66,21.82 89.66,22.29 89.74,22.37 90.91,22.37 91.11,22.57 91.11,24.13 90.88,24.35 90.22,24.35 90.04,24.53 90.04,35.18 89.84,35.38 89.16,35.38 89.08,35.46 89.08,35.79 89.16,35.87 90.02,35.87 90.22,36.07 90.22,36.57 90.02,36.77 89.11,36.77 89.03,36.86 89.03,37.18 89.11,37.26 90.02,37.26 90.22,37.47 90.22,37.96 90.02,38.17 89.11,38.17 89.03,38.25 89.03,38.57 89.11,38.65 90.07,38.65 90.27,38.86 90.27,39.35 90.07,39.56 89.11,39.56 89.03,39.64 89.03,39.96 89.11,40.05 90.04,40.05 90.25,40.25 90.25,40.75 90.04,40.95 89.11,40.95 89.03,41.03 89.03,41.36 89.11,41.44 90.07,41.44 90.27,41.64 90.27,42.14 90.07,42.34 89.11,42.34 89.03,42.42 89.03,42.75 89.11,42.83 90.07,42.83 90.27,43.03 90.27,43.53 90.07,43.73 89.11,43.73 89.03,43.81 89.03,44.14 89.11,44.22 90.04,44.22 90.25,44.42 90.25,44.92 90.04,45.13 89.11,45.13 89.03,45.21 89.03,45.53 89.11,45.61 90.07,45.61 90.27,45.82 90.27,46.31 90.07,46.52 89.11,46.52 89.03,46.6 89.03,46.92 89.11,47.01 90.02,47.01 90.22,47.21 90.22,47.71 90.02,47.91 89.11,47.91 89.03,47.99 89.03,48.32 89.11,48.4 90.02,48.4 90.22,48.6 90.22,49.1 90.02,49.3 89.11,49.3 89.03,49.38 89.03,49.71 89.11,49.79 90.04,49.79 90.25,49.99 90.25,50.49 90.04,50.69 89.11,50.69 89.03,50.77 89.03,51.1 89.11,51.18 90.07,51.18 90.27,51.38 90.27,51.88 90.07,52.09 89.11,52.09 89.03,52.17 89.03,58.97 87.5,60.5 87.5,69.85 87.58,69.93 v2(87.9,69.93)
FMC2_LA24_P: length 90.8
  TOP w0.099: J54.H28 v2(90.3,14.3)
  TOP w0.124: U3.AG23 v2(86.9,69.93)
  L05-SIG2 w0.081: v2(90.3,14.3) 90.3,13.85 90.38,13.77 90.64,13.77 90.85,13.98 90.85,14.56 90.75,14.66 90.75,14.89 90.85,14.98 90.85,15.21 90.75,15.31 90.75,15.54 90.85,15.63 90.85,15.86 90.75,15.96 90.75,16.19 90.85,16.28 90.85,16.51 90.73,16.63 90.73,16.81 90.85,16.93 90.85,17.77 90.77,17.85 90.37,17.85 90.17,18.06 90.17,18.55 90.37,18.76 90.77,18.76 90.85,18.84 90.85,21.45 90.77,21.53 89.66,21.53 89.45,21.73 89.45,22.37 89.66,22.58 90.82,22.58 90.9,22.66 90.9,24.04 90.79,24.15 90.13,24.15 89.83,24.45 89.83,35.09 89.75,35.17 89.07,35.17 88.87,35.38 88.87,35.87 89.07,36.08 89.93,36.08 90.01,36.16 90.01,36.48 89.93,36.57 89.02,36.57 88.82,36.77 88.82,37.27 89.02,37.47 89.93,37.47 90.01,37.55 90.01,37.88 89.93,37.96 89.02,37.96 88.82,38.16 88.82,38.66 89.02,38.86 89.98,38.86 90.06,38.94 90.06,39.27 89.98,39.35 89.02,39.35 88.82,39.55 88.82,40.05 89.02,40.25 89.96,40.25 90.04,40.34 90.04,40.66 89.96,40.74 89.02,40.74 88.82,40.94 88.82,41.44 89.02,41.65 89.98,41.65 90.06,41.73 90.06,42.05 89.98,42.13 89.02,42.13 88.82,42.34 88.82,42.83 89.02,43.04 89.98,43.04 90.06,43.12 90.06,43.44 89.98,43.53 89.02,43.53 88.82,43.73 88.82,44.23 89.02,44.43 89.96,44.43 90.04,44.51 90.04,44.84 89.96,44.92 89.02,44.92 88.82,45.12 88.82,45.62 89.02,45.82 89.98,45.82 90.06,45.9 90.06,46.23 89.98,46.31 89.02,46.31 88.82,46.51 88.82,47.01 89.02,47.21 89.93,47.21 90.01,47.29 90.01,47.62 89.93,47.7 89.02,47.7 88.82,47.9 88.82,48.4 89.02,48.61 89.93,48.61 90.01,48.69 90.01,49.01 89.93,49.09 89.02,49.09 88.82,49.3 88.82,49.79 89.02,50 89.96,50 90.04,50.08 90.04,50.4 89.96,50.49 89.02,50.49 88.82,50.69 88.82,51.19 89.02,51.39 89.98,51.39 90.06,51.47 90.06,51.8 89.98,51.88 89.02,51.88 88.82,52.08 88.82,58.89 87.29,60.41 87.29,65.25 87.17,65.37 87.17,65.57 87.29,65.69 87.29,66.29 87.17,66.41 87.17,66.61 87.29,66.74 87.29,67.27 87.17,67.39 87.17,67.6 87.29,67.72 87.29,69.19 87.17,69.32 87.17,69.52 87.29,69.64 87.29,69.85 87.21,69.93 v2(86.9,69.93)
FMC2_LA25_N: length 90.5
  TOP w0.124: U3.AH23 v2(86.9,68.93) ; J54.G28 v2(89.03,15.57)
  L05-SIG2 w0.081: v2(86.9,68.93) 86.9,68.62 86.82,68.53 86.53,68.53 86.28,68.29 86.28,60.16 86.8,59.64 86.8,59.52 86.27,59 86.27,58.71 86.62,58.36 86.91,58.36 87.44,58.89 87.55,58.89 87.93,58.51 87.93,57.71 87.85,57.63 86.56,57.63 86.36,57.43 86.36,56.93 86.56,56.73 87.85,56.73 87.93,56.65 87.93,56.32 87.85,56.24 86.56,56.24 86.36,56.04 86.36,55.54 86.56,55.34 87.85,55.34 87.93,55.26 87.93,54.93 87.85,54.85 86.3,54.85 86.1,54.65 86.1,54.15 86.3,53.94 87.85,53.94 87.93,53.86 87.93,53.54 87.85,53.46 86.38,53.46 86.18,53.25 86.18,52.76 86.38,52.55 87.85,52.55 87.93,52.47 87.93,34.68 88.13,34.48 89.02,34.48 89.1,34.39 89.1,34.07 89.02,33.99 88.13,33.99 87.93,33.78 87.93,33.29 88.13,33.08 88.99,33.08 89.07,33 89.07,32.68 88.99,32.6 88.13,32.6 87.93,32.39 87.93,31.89 88.13,31.69 88.99,31.69 89.07,31.61 89.07,31.28 88.99,31.2 88.13,31.2 87.93,31 87.93,30.5 88.13,30.3 88.99,30.3 89.07,30.22 89.07,29.89 88.99,29.81 88.13,29.81 87.93,29.61 87.93,29.11 88.13,28.91 88.99,28.91 89.07,28.83 89.07,28.5 88.99,28.42 88.13,28.42 87.93,28.22 87.93,27.72 88.13,27.52 88.99,27.52 89.07,27.43 89.07,27.11 88.99,27.03 88.13,27.03 87.93,26.82 87.93,26.33 88.13,26.12 88.99,26.12 89.07,26.04 89.07,25.72 88.99,25.64 88.13,25.64 87.93,25.43 87.93,24.83 88.13,24.62 88.97,24.62 89.05,24.54 89.05,24.22 88.97,24.13 88.13,24.13 87.93,23.93 87.93,22.87 88.29,22.52 88.29,20.13 88.49,19.93 89.42,19.93 89.5,19.85 89.5,19.01 89.42,18.92 88.49,18.92 88.29,18.72 88.29,17.54 88.49,17.34 89.47,17.34 89.63,17.18 89.63,15.12 89.55,15.04 89.11,15.04 89.03,15.12 v2(89.03,15.57)
FMC2_LA25_P: length 90.5
  TOP w0.124: U3.AJ23 v2(86.9,67.93) ; J54.G27 v2(89.03,14.3)
  L05-SIG2 w0.081: v2(86.9,67.93) 86.9,68.24 86.82,68.33 86.61,68.33 86.49,68.2 86.49,60.24 87.01,59.73 87.01,59.44 86.48,58.91 86.48,58.8 86.71,58.57 86.82,58.57 87.35,59.09 87.64,59.09 88.14,58.59 88.14,57.63 87.93,57.42 86.65,57.42 86.57,57.34 86.57,57.02 86.65,56.94 87.93,56.94 88.14,56.73 88.14,56.24 87.93,56.03 86.65,56.03 86.57,55.95 86.57,55.63 86.65,55.54 87.93,55.54 88.14,55.34 88.14,54.84 87.93,54.64 86.39,54.64 86.31,54.56 86.31,54.23 86.39,54.15 87.93,54.15 88.14,53.95 88.14,53.45 87.93,53.25 86.47,53.25 86.39,53.17 86.39,52.84 86.47,52.76 87.93,52.76 88.14,52.56 88.14,34.76 88.22,34.68 89.1,34.68 89.31,34.48 89.31,33.98 89.1,33.78 88.22,33.78 88.14,33.7 88.14,33.37 88.22,33.29 89.08,33.29 89.28,33.09 89.28,32.59 89.08,32.39 88.22,32.39 88.14,32.31 88.14,31.98 88.22,31.9 89.08,31.9 89.28,31.7 89.28,31.2 89.08,31 88.22,31 88.14,30.91 88.14,30.59 88.22,30.51 89.08,30.51 89.28,30.3 89.28,29.81 89.08,29.6 88.22,29.6 88.14,29.52 88.14,29.2 88.22,29.12 89.08,29.12 89.28,28.91 89.28,28.41 89.08,28.21 88.22,28.21 88.14,28.13 88.14,27.81 88.22,27.72 89.08,27.72 89.28,27.52 89.28,27.02 89.08,26.82 88.22,26.82 88.14,26.74 88.14,26.41 88.22,26.33 89.08,26.33 89.28,26.13 89.28,25.63 89.08,25.43 88.22,25.43 88.14,25.35 88.14,24.91 88.22,24.83 89.05,24.83 89.26,24.63 89.26,24.13 89.05,23.93 88.22,23.93 88.14,23.85 88.14,22.96 88.49,22.6 88.49,20.22 88.57,20.14 89.51,20.14 89.71,19.94 89.71,18.92 89.51,18.72 88.57,18.72 88.49,18.63 88.49,17.63 88.57,17.55 89.56,17.55 89.84,17.27 89.84,15.03 89.64,14.83 89.11,14.83 89.03,14.75 v2(89.03,14.3)
FMC2_LA26_N: length 95.7
  TOP w0.099: J54.D27 v2(87.76,18.11)
  TOP w0.124: U3.AA20 v2(83.9,75.93)
  L10-SIG3 w0.081: v2(83.9,75.93) 83.9,76.24 83.98,76.33 84.97,76.33 85.26,76.03 85.26,67.65 85.51,67.4 87.92,67.4 88.29,67.03 88.29,66.65 88.56,66.39 88.97,66.39 89.33,66.03 89.33,44.8 87.04,42.51 87.04,38.16 87.24,37.96 88.2,37.96 88.29,37.88 88.29,37.55 88.2,37.47 87.24,37.47 87.04,37.27 87.04,36.77 87.24,36.57 88.08,36.57 88.16,36.49 88.16,36.16 88.08,36.08 87.24,36.08 87.04,35.88 87.04,35.38 87.24,35.18 88.2,35.18 88.29,35.09 88.29,34.77 88.2,34.69 87.24,34.69 87.04,34.48 87.04,33.71 87.24,33.5 88.25,33.5 88.34,33.42 88.34,33.1 88.25,33.02 86.61,33.02 86.41,32.81 86.41,32.32 86.61,32.11 88.25,32.11 88.34,32.03 88.34,31.71 88.25,31.62 86.58,31.62 86.38,31.42 86.38,30.92 86.58,30.72 88.23,30.72 88.31,30.64 88.31,30.31 88.23,30.23 86.58,30.23 86.38,30.03 86.38,29.53 86.58,29.33 88.23,29.33 88.31,29.25 88.31,28.92 88.23,28.84 86.61,28.84 86.41,28.64 86.41,28.14 86.61,27.94 88.23,27.94 88.31,27.86 88.31,27.53 88.23,27.45 86.58,27.45 86.38,27.25 86.38,26.75 86.58,26.54 88.23,26.54 88.31,26.46 88.31,26.14 88.23,26.06 86.56,26.06 86.35,25.85 86.35,25.36 86.56,25.15 88.18,25.15 88.26,25.07 88.26,24.75 88.18,24.66 87.24,24.66 87.04,24.46 87.04,18.91 87.29,18.66 87.65,18.66 87.76,18.56 v2(87.76,18.11)
FMC2_LA26_P: length 95.7
  TOP w0.099: J54.D26 v2(87.76,19.38)
  TOP w0.124: U3.Y20 v2(83.9,76.93)
  L10-SIG3 w0.081: v2(83.9,76.93) 83.9,76.62 83.98,76.53 85.06,76.53 85.47,76.12 85.47,67.74 85.6,67.61 88.01,67.61 88.5,67.12 88.5,66.74 88.65,66.59 89.05,66.59 89.53,66.11 89.53,44.71 87.25,42.42 87.25,38.25 87.33,38.17 88.29,38.17 88.49,37.96 88.49,37.47 88.29,37.26 87.33,37.26 87.25,37.18 87.25,36.86 87.33,36.78 88.16,36.78 88.37,36.57 88.37,36.07 88.16,35.87 87.33,35.87 87.25,35.79 87.25,35.47 87.33,35.38 88.29,35.38 88.49,35.18 88.49,34.68 88.29,34.48 87.33,34.48 87.25,34.4 87.25,33.79 87.33,33.71 88.34,33.71 88.54,33.51 88.54,33.01 88.34,32.81 86.7,32.81 86.61,32.73 86.61,32.4 86.7,32.32 88.34,32.32 88.54,32.12 88.54,31.62 88.34,31.42 86.67,31.42 86.59,31.33 86.59,31.01 86.67,30.93 88.32,30.93 88.52,30.73 88.52,30.23 88.32,30.02 86.67,30.02 86.59,29.94 86.59,29.62 86.67,29.54 88.32,29.54 88.52,29.33 88.52,28.84 88.32,28.63 86.7,28.63 86.61,28.55 86.61,28.23 86.7,28.14 88.32,28.14 88.52,27.94 88.52,27.44 88.32,27.24 86.67,27.24 86.59,27.16 86.59,26.83 86.67,26.75 88.32,26.75 88.52,26.55 88.52,26.05 88.32,25.85 86.64,25.85 86.56,25.77 86.56,25.44 86.64,25.36 88.26,25.36 88.47,25.16 88.47,24.66 88.26,24.46 87.33,24.46 87.25,24.38 87.25,19 87.38,18.87 87.68,18.87 87.76,18.95 v2(87.76,19.38)
FMC2_LA27_N: length 80.4
  TOP w0.124: U3.AP27 v2(90.9,62.93) ; J54.C27 v2(89.03,20.65)
  L10-SIG3 w0.081: v2(90.9,62.93) 91.21,62.93 91.29,62.85 91.29,42.7 91.12,42.53 89.74,42.53 89.53,42.33 89.53,41.83 89.74,41.62 90.85,41.62 90.93,41.54 90.93,41.22 90.85,41.14 89.74,41.14 89.53,40.93 89.53,40.44 89.74,40.23 90.85,40.23 90.93,40.15 90.93,39.83 90.85,39.74 89.74,39.74 89.53,39.54 89.53,39.04 89.74,38.84 90.85,38.84 90.93,38.76 90.93,38.43 90.85,38.35 89.74,38.35 89.53,38.15 89.53,37.65 89.74,37.45 90.85,37.45 90.93,37.37 90.93,37.04 90.85,36.96 89.74,36.96 89.53,36.76 89.53,36.26 89.74,36.06 90.85,36.06 90.93,35.98 90.93,35.65 90.85,35.57 89.74,35.57 89.53,35.37 89.53,34.87 89.74,34.66 90.85,34.66 90.93,34.58 90.93,34.26 90.85,34.18 89.74,34.18 89.53,33.97 89.53,33.48 89.74,33.27 90.85,33.27 90.93,33.19 90.93,32.87 90.85,32.79 89.74,32.79 89.53,32.58 89.53,32.08 89.74,31.88 90.85,31.88 90.93,31.8 90.93,31.47 90.85,31.39 89.74,31.39 89.53,31.19 89.53,30.69 89.74,30.49 90.85,30.49 90.93,30.41 90.93,30.08 90.85,30 89.74,30 89.53,29.8 89.53,29.3 89.74,29.1 90.85,29.1 90.93,29.02 90.93,28.69 90.85,28.61 89.74,28.61 89.53,28.41 89.53,27.91 89.74,27.71 90.85,27.71 90.93,27.62 90.93,27.3 90.85,27.22 89.78,27.22 89.58,27.01 89.58,26.52 89.78,26.31 90.85,26.31 90.93,26.23 90.93,25.91 90.85,25.83 90.22,25.83 90.01,25.62 90.01,25.12 90.22,24.92 90.85,24.92 90.93,24.84 90.93,22.68 90.81,22.55 90.81,22.36 90.93,22.23 90.93,21.93 90.81,21.8 90.81,21.6 90.93,21.47 90.93,21.27 90.81,21.15 90.81,20.95 90.93,20.82 90.93,20.24 90.78,20.09 90.57,20.09 90.44,20.21 90.21,20.21 90.09,20.09 89.83,20.09 89.75,20.17 89.75,20.39 89.67,20.47 89.51,20.47 89.43,20.39 89.43,20.17 89.35,20.09 88.58,20.09 88.5,20.17 88.5,20.57 88.58,20.65 v2(89.03,20.65)
FMC2_LA27_P: length 80.1
  TOP w0.124: J54.C26 v2(87.76,20.65) ; U3.AP28 v2(91.9,62.93)
  L10-SIG3 w0.081: v2(87.76,20.65) 88.21,20.65 88.29,20.57 88.29,20.08 88.49,19.88 90.87,19.88 91.14,20.15 91.14,24.93 90.94,25.13 90.3,25.13 90.22,25.21 90.22,25.54 90.3,25.62 90.94,25.62 91.14,25.82 91.14,26.32 90.94,26.52 89.87,26.52 89.79,26.6 89.79,26.93 89.87,27.01 90.94,27.01 91.14,27.21 91.14,27.71 90.94,27.91 89.82,27.91 89.74,27.99 89.74,28.32 89.82,28.4 90.94,28.4 91.14,28.6 91.14,29.1 90.94,29.31 89.82,29.31 89.74,29.39 89.74,29.71 89.82,29.79 90.94,29.79 91.14,30 91.14,30.49 90.94,30.7 89.82,30.7 89.74,30.78 89.74,31.1 89.82,31.18 90.94,31.18 91.14,31.39 91.14,31.89 90.94,32.09 89.82,32.09 89.74,32.17 89.74,32.5 89.82,32.58 90.94,32.58 91.14,32.78 91.14,33.28 90.94,33.48 89.82,33.48 89.74,33.56 89.74,33.89 89.82,33.97 90.94,33.97 91.14,34.17 91.14,34.67 90.94,34.87 89.82,34.87 89.74,34.95 89.74,35.28 89.82,35.36 90.94,35.36 91.14,35.56 91.14,36.06 90.94,36.26 89.82,36.26 89.74,36.35 89.74,36.67 89.82,36.75 90.94,36.75 91.14,36.96 91.14,37.45 90.94,37.66 89.82,37.66 89.74,37.74 89.74,38.06 89.82,38.14 90.94,38.14 91.14,38.35 91.14,38.85 90.94,39.05 89.82,39.05 89.74,39.13 89.74,39.46 89.82,39.54 90.94,39.54 91.14,39.74 91.14,40.24 90.94,40.44 89.82,40.44 89.74,40.52 89.74,40.85 89.82,40.93 90.94,40.93 91.14,41.13 91.14,41.63 90.94,41.83 89.82,41.83 89.74,41.91 89.74,42.24 89.82,42.32 91.21,42.32 91.5,42.61 91.5,62.85 91.58,62.93 v2(91.9,62.93)
FMC2_LA28_N: length 88.8
  TOP w0.124: J54.H32 v2(94.11,13.03) ; U3.AL25 v2(88.9,65.93)
  L05-SIG2 w0.081: v2(94.11,13.03) 94.11,13.48 94.03,13.56 93.59,13.56 93.39,13.76 93.39,22.65 93.59,22.85 94.38,22.85 94.46,22.93 94.46,23.25 94.38,23.34 93.59,23.34 93.39,23.54 93.39,24.23 93.59,24.43 95.87,24.43 95.96,24.51 95.96,24.9 95.87,24.98 93.57,24.98 93.37,25.19 93.37,25.7 93.57,25.9 95.9,25.9 95.98,25.98 95.98,26.31 95.9,26.39 93.59,26.39 93.39,26.59 93.39,27.09 93.59,27.29 95.98,27.29 96.06,27.38 96.06,27.7 95.98,27.78 93.59,27.78 93.39,27.98 93.39,28.48 93.59,28.69 96.08,28.69 96.16,28.77 96.16,29.09 96.08,29.17 93.59,29.17 93.39,29.38 93.39,29.87 93.59,30.08 96.08,30.08 96.16,30.16 96.16,30.48 96.08,30.57 93.59,30.57 93.39,30.77 93.39,31.27 93.59,31.47 95.52,31.47 95.6,31.55 95.6,31.88 95.52,31.96 93.59,31.96 93.39,32.16 93.39,34.07 92.86,34.61 92.86,35.8 91.74,36.92 91.74,58.76 89.28,61.22 89.28,66.25 89.22,66.32 88.98,66.32 88.9,66.23 v2(88.9,65.93)
FMC2_LA28_P: length 88.7
  TOP w0.124: U3.AK25 v2(88.9,66.93) ; J54.H31 v2(94.11,14.3)
  L05-SIG2 w0.081: v2(88.9,66.93) 89.49,66.34 89.49,61.31 91.95,58.85 91.95,37 93.07,35.89 93.07,34.69 93.6,34.16 93.6,32.25 93.68,32.17 95.61,32.17 95.81,31.96 95.81,31.46 95.61,31.26 93.68,31.26 93.6,31.18 93.6,30.86 93.68,30.77 96.16,30.77 96.37,30.57 96.37,30.07 96.16,29.87 93.68,29.87 93.6,29.79 93.6,29.46 93.68,29.38 96.16,29.38 96.37,29.18 96.37,28.68 96.16,28.48 93.68,28.48 93.6,28.4 93.6,28.07 93.68,27.99 96.06,27.99 96.27,27.79 96.27,27.29 96.06,27.09 93.68,27.09 93.6,27 93.6,26.68 93.68,26.6 95.99,26.6 96.19,26.39 96.19,25.9 95.99,25.69 93.65,25.69 93.57,25.61 93.57,25.27 93.65,25.19 95.96,25.19 96.16,24.99 96.16,24.43 95.96,24.22 93.68,24.22 93.6,24.14 93.6,23.63 93.68,23.54 94.46,23.54 94.67,23.34 94.67,22.84 94.46,22.64 93.68,22.64 93.6,22.56 93.6,13.85 93.68,13.77 94.03,13.77 94.11,13.85 v2(94.11,14.3)
FMC2_LA29_N: length 88.8
  TOP w0.124: J54.G31 v2(92.84,15.57) ; U3.AH25 v2(88.9,68.93)
  L05-SIG2 w0.081: v2(92.84,15.57) 92.84,15.12 92.76,15.04 92.46,15.04 92.33,15.16 92.33,15.86 92.38,15.91 92.38,16.26 92.33,16.31 92.33,17.82 92.61,18.1 92.61,18.6 92.33,18.88 92.33,19.72 92.16,19.89 92.16,20.36 92.33,20.53 92.33,21.43 92.13,21.64 91.93,21.64 91.85,21.72 91.85,22.04 91.93,22.12 92.13,22.12 92.33,22.33 92.33,22.85 92.41,22.93 92.63,22.93 92.84,23.13 92.84,23.63 92.63,23.84 92.41,23.84 92.33,23.92 92.33,24.34 91.06,25.61 91.06,25.92 91.14,26 92.53,26 92.74,26.2 92.74,26.72 92.53,26.93 91.14,26.93 91.06,27.01 91.06,27.33 91.14,27.41 92.58,27.41 92.79,27.62 92.79,28.12 92.58,28.32 91.14,28.32 91.06,28.4 91.06,28.73 91.14,28.81 92.58,28.81 92.79,29.01 92.79,29.51 92.58,29.71 91.14,29.71 91.06,29.79 91.06,30.12 91.14,30.2 92.56,30.2 92.76,30.4 92.76,30.9 92.56,31.1 91.14,31.1 91.06,31.18 91.06,31.51 91.14,31.59 92.58,31.59 92.79,31.79 92.79,32.29 92.58,32.49 91.14,32.49 91.06,32.58 91.06,32.9 91.14,32.98 92.61,32.98 92.81,33.19 92.81,33.68 92.61,33.89 91.14,33.89 91.06,33.97 91.06,34.42 91.14,34.5 92.02,34.5 92.23,34.7 92.23,35.2 92.02,35.4 91.14,35.4 91.06,35.48 91.06,52.66 90.86,52.86 90,52.86 89.92,52.94 89.92,53.27 90,53.35 90.86,53.35 91.06,53.55 91.06,54.05 90.86,54.25 89.95,54.25 89.87,54.33 89.87,54.66 89.95,54.74 90.86,54.74 91.06,54.94 91.06,55.44 90.86,55.65 89.95,55.65 89.87,55.73 89.87,56.05 89.95,56.13 90.86,56.13 91.06,56.34 91.06,56.83 90.86,57.04 89.95,57.04 89.87,57.12 89.87,57.44 89.95,57.53 90.86,57.53 91.06,57.73 91.06,58.59 88.5,61.15 88.5,68.85 88.58,68.93 v2(88.9,68.93)
FMC2_LA29_P: length 89.1
  TOP w0.124: 92.2,14.93 v2(92.84,14.3) ; U3.AH24 v2(87.9,68.93)
  L05-SIG2 w0.081: v2(87.9,68.93) 88.21,68.93 88.29,68.85 88.29,61.06 90.85,58.51 90.85,57.81 90.77,57.73 89.87,57.73 89.66,57.53 89.66,57.03 89.87,56.83 90.77,56.83 90.85,56.75 90.85,56.42 90.77,56.34 89.87,56.34 89.66,56.14 89.66,55.64 89.87,55.44 90.77,55.44 90.85,55.36 90.85,55.03 90.77,54.95 89.87,54.95 89.66,54.75 89.66,54.25 89.87,54.05 90.77,54.05 90.85,53.96 90.85,53.64 90.77,53.56 89.91,53.56 89.71,53.35 89.71,52.86 89.91,52.65 90.77,52.65 90.85,52.57 90.85,35.4 91.05,35.19 91.94,35.19 92.02,35.11 92.02,34.79 91.94,34.71 91.05,34.71 90.85,34.5 90.85,33.88 91.05,33.68 92.52,33.68 92.6,33.6 92.6,33.27 92.52,33.19 91.05,33.19 90.85,32.99 90.85,32.49 91.05,32.29 92.5,32.29 92.58,32.21 92.58,31.88 92.5,31.8 91.05,31.8 90.85,31.6 90.85,31.1 91.05,30.89 92.47,30.89 92.55,30.81 92.55,30.49 92.47,30.41 91.05,30.41 90.85,30.2 90.85,29.71 91.05,29.5 92.5,29.5 92.58,29.42 92.58,29.1 92.5,29.02 91.05,29.02 90.85,28.81 90.85,28.31 91.05,28.11 92.5,28.11 92.58,28.03 92.58,27.7 92.5,27.62 91.05,27.62 90.85,27.42 90.85,26.92 91.05,26.72 92.45,26.72 92.53,26.64 92.53,26.29 92.45,26.21 91.05,26.21 90.85,26.01 90.85,25.53 92.12,24.26 92.12,23.83 92.32,23.63 92.55,23.63 92.63,23.55 92.63,23.22 92.55,23.14 92.32,23.14 92.12,22.94 92.12,22.41 92.04,22.33 91.85,22.33 91.64,22.13 91.64,21.63 91.85,21.43 92.04,21.43 92.12,21.35 92.12,20.62 91.95,20.45 91.95,19.81 92.12,19.63 92.12,18.8 92.4,18.52 92.4,18.19 92.12,17.91 92.12,15.08 92.37,14.83 92.76,14.83 92.84,14.75 v2(92.84,14.3)
FMC2_LA30_N: length 84.7
  TOP w0.099: J54.H35 v2(97.92,13.03)
  TOP w0.124: U3.AL28 v2(91.9,65.93)
  L05-SIG2 w0.081: v2(97.92,13.03) 97.92,13.48 98,13.56 98.43,13.56 98.63,13.76 98.63,22.64 98.71,22.72 99.62,22.72 99.82,22.92 99.82,23.42 99.62,23.62 98.71,23.62 98.63,23.7 98.63,24.03 98.71,24.11 100.13,24.11 100.33,24.31 100.33,24.81 100.13,25.01 98.71,25.01 98.63,25.09 98.63,25.42 98.71,25.5 100.13,25.5 100.33,25.7 100.33,26.2 100.13,26.4 98.71,26.4 98.63,26.49 98.63,26.81 98.71,26.89 100.13,26.89 100.33,27.1 100.33,27.59 100.13,27.8 98.71,27.8 98.63,27.88 98.63,28.2 98.71,28.28 100.13,28.28 100.33,28.49 100.33,28.99 100.13,29.19 98.71,29.19 98.63,29.27 98.63,29.59 98.71,29.68 99.67,29.68 99.87,29.88 99.87,30.41 99.67,30.61 98.71,30.61 98.63,30.69 98.63,32.66 97.8,33.49 97.51,33.49 97.25,33.24 97.14,33.24 96.91,33.47 96.91,33.58 97.16,33.84 97.16,34.13 96.81,34.48 96.52,34.48 96.22,34.18 96.11,34.18 95.88,34.41 95.88,34.52 96.18,34.82 96.18,35.11 95.83,35.46 95.54,35.46 95.24,35.16 95.12,35.16 94.89,35.39 94.89,35.51 95.19,35.81 95.19,36.1 94.87,36.42 94.87,51.62 94.67,51.83 94.06,51.83 93.98,51.91 93.98,52.23 94.06,52.31 94.67,52.31 94.87,52.52 94.87,53.02 94.67,53.22 93.89,53.22 93.81,53.3 93.81,53.63 93.89,53.71 94.67,53.71 94.87,53.91 94.87,54.41 94.67,54.61 93.89,54.61 93.81,54.69 93.81,55.02 93.89,55.1 94.67,55.1 94.87,55.3 94.87,55.8 94.67,56 93.89,56 93.81,56.08 93.81,56.41 93.89,56.49 94.67,56.49 94.87,56.69 94.87,58.47 91.5,61.83 91.5,65.85 91.58,65.93 v2(91.9,65.93)
FMC2_LA30_P: length 84.6
  TOP w0.099: 97.28,13.66 v2(97.92,14.3)
  TOP w0.124: U3.AL27 v2(90.9,65.93)
  L05-SIG2 w0.081: v2(97.92,14.3) 97.92,13.85 98,13.77 98.34,13.77 98.43,13.85 98.43,14.65 98.27,14.8 98.27,14.98 98.43,15.13 98.43,15.3 98.3,15.43 98.3,15.65 98.43,15.78 98.43,22.72 98.63,22.92 99.53,22.92 99.61,23.01 99.61,23.33 99.53,23.41 98.63,23.41 98.43,23.62 98.43,24.11 98.63,24.32 100.04,24.32 100.12,24.4 100.12,24.72 100.04,24.8 98.63,24.8 98.43,25.01 98.43,25.51 98.63,25.71 100.04,25.71 100.12,25.79 100.12,26.12 100.04,26.2 98.63,26.2 98.43,26.4 98.43,26.9 98.63,27.1 100.04,27.1 100.12,27.18 100.12,27.51 100.04,27.59 98.63,27.59 98.43,27.79 98.43,28.29 98.63,28.49 100.04,28.49 100.12,28.57 100.12,28.9 100.04,28.98 98.63,28.98 98.43,29.18 98.43,29.68 98.63,29.88 99.58,29.88 99.66,29.97 99.66,30.32 99.58,30.4 98.63,30.4 98.43,30.6 98.43,32.57 97.71,33.28 97.59,33.28 97.34,33.03 97.05,33.03 96.7,33.38 96.7,33.67 96.96,33.92 96.96,34.04 96.72,34.27 96.61,34.27 96.31,33.97 96.02,33.97 95.67,34.32 95.67,34.61 95.97,34.91 95.97,35.02 95.74,35.25 95.62,35.25 95.33,34.96 95.04,34.96 94.69,35.31 94.69,35.6 94.99,35.89 94.99,36.01 94.66,36.33 94.66,51.54 94.58,51.62 93.97,51.62 93.77,51.82 93.77,52.32 93.97,52.52 94.58,52.52 94.66,52.6 94.66,52.93 94.58,53.01 93.8,53.01 93.6,53.21 93.6,53.71 93.8,53.92 94.58,53.92 94.66,54 94.66,54.32 94.58,54.4 93.8,54.4 93.6,54.61 93.6,55.1 93.8,55.31 94.58,55.31 94.66,55.39 94.66,55.71 94.58,55.79 93.8,55.79 93.6,56 93.6,56.5 93.8,56.7 94.58,56.7 94.66,56.78 94.66,58.38 91.29,61.75 91.29,65.85 91.21,65.93 v2(90.9,65.93)
FMC2_LA31_N: length 90.2
  TOP w0.124: U3.AF25 v2(88.9,70.93) ; 97.28,14.93 v2(96.65,14.3)
  L05-SIG2 w0.081: v2(96.65,14.3) 96.65,14.75 96.73,14.83 97.12,14.83 97.41,15.12 97.41,18.58 97.21,18.78 95.08,18.78 95,18.86 95,19.8 95.08,19.88 97.21,19.88 97.41,20.08 97.41,21.17 97.21,21.37 95.26,21.37 95.17,21.45 95.17,21.78 95.26,21.86 97.21,21.86 97.41,22.06 97.41,31.67 93.98,35.1 93.98,36.81 93.78,37.01 93.05,37.01 92.96,37.09 92.96,37.42 93.05,37.5 93.78,37.5 93.98,37.7 93.98,38.2 93.78,38.4 93.05,38.4 92.96,38.49 92.96,38.81 93.05,38.89 93.78,38.89 93.98,39.1 93.98,39.59 93.78,39.8 93.05,39.8 92.96,39.88 92.96,40.2 93.05,40.28 93.78,40.28 93.98,40.49 93.98,40.99 93.78,41.19 93.05,41.19 92.96,41.27 92.96,41.59 93.05,41.68 93.78,41.68 93.98,41.88 93.98,42.38 93.78,42.58 93.05,42.58 92.96,42.66 92.96,42.99 93.05,43.07 93.78,43.07 93.98,43.27 93.98,43.77 93.78,43.97 93.05,43.97 92.96,44.05 92.96,44.38 93.05,44.46 93.78,44.46 93.98,44.66 93.98,45.16 93.78,45.36 93.05,45.36 92.96,45.45 92.96,45.77 93.05,45.85 93.78,45.85 93.98,46.06 93.98,46.55 93.78,46.76 93.05,46.76 92.96,46.84 92.96,47.16 93.05,47.24 93.78,47.24 93.98,47.45 93.98,47.94 93.78,48.15 93.05,48.15 92.96,48.23 92.96,48.55 93.05,48.64 93.78,48.64 93.98,48.84 93.98,49.34 93.78,49.54 93.05,49.54 92.96,49.62 92.96,49.95 93.05,50.03 93.78,50.03 93.98,50.23 93.98,50.73 93.78,50.93 93.05,50.93 92.96,51.01 92.96,57.35 93.05,57.43 93.6,57.43 93.8,57.63 93.8,58.13 93.59,58.34 93.05,58.34 92.96,58.42 92.96,59.1 90.55,61.51 90.55,70.15 90.17,70.53 89.29,70.53 v2(88.9,70.93)
FMC2_LA31_P: length 90.2
  TOP w0.124: J54.G33 v2(96.65,15.57) ; U3.AG25 v2(88.9,69.93)
  L05-SIG2 w0.081: v2(96.65,15.57) 96.65,15.12 96.73,15.04 97.03,15.04 97.2,15.21 97.2,15.74 97.08,15.86 97.08,16.07 97.2,16.19 97.2,16.39 97.08,16.51 97.08,16.72 97.2,16.84 97.2,17.04 97.1,17.14 97.1,17.39 97.2,17.49 97.2,18.49 97.12,18.57 95,18.57 94.79,18.77 94.79,19.88 95,20.09 97.12,20.09 97.2,20.17 97.2,21.08 97.12,21.16 95.17,21.16 94.97,21.36 94.97,21.86 95.17,22.06 97.12,22.06 97.2,22.15 97.2,31.58 93.77,35.01 93.77,36.72 93.69,36.8 92.96,36.8 92.76,37.01 92.76,37.51 92.96,37.71 93.69,37.71 93.77,37.79 93.77,38.11 93.69,38.2 92.96,38.2 92.76,38.4 92.76,38.9 92.96,39.1 93.69,39.1 93.77,39.18 93.77,39.51 93.69,39.59 92.96,39.59 92.76,39.79 92.76,40.29 92.96,40.49 93.69,40.49 93.77,40.57 93.77,40.9 93.69,40.98 92.96,40.98 92.76,41.18 92.76,41.68 92.96,41.88 93.69,41.88 93.77,41.97 93.77,42.29 93.69,42.37 92.96,42.37 92.76,42.58 92.76,43.07 92.96,43.28 93.69,43.28 93.77,43.36 93.77,43.68 93.69,43.76 92.96,43.76 92.76,43.97 92.76,44.46 92.96,44.67 93.69,44.67 93.77,44.75 93.77,45.07 93.69,45.16 92.96,45.16 92.76,45.36 92.76,45.86 92.96,46.06 93.69,46.06 93.77,46.14 93.77,46.47 93.69,46.55 92.96,46.55 92.76,46.75 92.76,47.25 92.96,47.45 93.69,47.45 93.77,47.53 93.77,47.86 93.69,47.94 92.96,47.94 92.76,48.14 92.76,48.64 92.96,48.84 93.69,48.84 93.77,48.93 93.77,49.25 93.69,49.33 92.96,49.33 92.76,49.53 92.76,50.03 92.96,50.24 93.69,50.24 93.77,50.32 93.77,50.64 93.69,50.72 92.96,50.72 92.76,50.93 92.76,57.43 92.96,57.64 93.51,57.64 93.59,57.72 93.59,58.04 93.51,58.13 92.96,58.13 92.76,58.33 92.76,59.02 90.34,61.43 90.34,68.25 90.2,68.39 90.2,68.57 90.34,68.72 90.34,69.23 90.22,69.35 90.22,69.56 90.34,69.68 90.34,70.06 90.08,70.33 88.98,70.33 88.9,70.24 v2(88.9,69.93)
FMC2_LA32_N: length 83.5
  TOP w0.124: U3.AM29 v2(92.9,64.93) ; J54.H38 v2(101.73,14.3)
  L05-SIG2 w0.081: v2(92.9,64.93) 92.9,65.3 92.98,65.38 93.15,65.38 93.26,65.27 93.26,64.63 93.12,64.49 93.12,64.28 93.26,64.13 93.26,63.75 93.09,63.57 93.09,63.34 93.26,63.17 93.26,62.44 93.52,62.19 93.52,62.03 93.67,61.88 93.83,61.88 93.98,61.73 93.98,61.57 94.13,61.42 94.29,61.42 94.44,61.27 94.44,61.11 94.59,60.96 94.75,60.96 98.22,57.49 98.22,56.8 98.14,56.72 97.49,56.72 97.28,56.51 97.28,56.02 97.49,55.81 98.41,55.81 98.5,55.73 98.5,55.41 98.41,55.33 97.49,55.33 97.28,55.12 97.28,54.62 97.49,54.42 98.39,54.42 98.47,54.34 98.47,54.01 98.39,53.93 97.49,53.93 97.28,53.73 97.28,53.23 97.49,53.03 98.14,53.03 98.22,52.95 98.22,52.62 98.14,52.54 97.49,52.54 97.28,52.34 97.28,51.84 97.49,51.64 98.14,51.64 98.22,51.56 98.22,51.23 98.14,51.15 97.49,51.15 97.28,50.95 97.28,50.45 97.49,50.25 98.14,50.25 98.22,50.16 98.22,49.84 98.14,49.76 97.49,49.76 97.28,49.55 97.28,49.06 97.49,48.85 98.14,48.85 98.22,48.77 98.22,48.45 98.14,48.37 97.49,48.37 97.28,48.16 97.28,47.66 97.49,47.46 98.14,47.46 98.22,47.38 98.22,47.06 98.14,46.97 97.49,46.97 97.28,46.77 97.28,46.27 97.49,46.07 98.14,46.07 98.22,45.99 98.22,45.66 98.14,45.58 97.49,45.58 97.28,45.38 97.28,44.88 97.49,44.68 98.14,44.68 98.22,44.6 98.22,44.27 98.14,44.19 97.49,44.19 97.28,43.99 97.28,43.49 97.49,43.29 98.14,43.29 98.22,43.2 98.22,42.88 98.14,42.8 97.49,42.8 97.28,42.59 97.28,42.1 97.49,41.89 98.14,41.89 98.22,41.81 98.22,41.49 98.14,41.41 97.49,41.41 97.28,41.2 97.28,40.71 97.49,40.5 98.14,40.5 98.22,40.42 98.22,40.1 98.14,40.01 97.49,40.01 97.28,39.81 97.28,39.31 97.49,39.11 98.14,39.11 98.22,39.03 98.22,38.7 98.14,38.62 97.48,38.62 97.28,38.42 97.28,37.92 97.48,37.72 98.14,37.72 98.22,37.64 98.22,37.31 98.14,37.23 97.43,37.23 97.23,37.03 97.23,36.53 97.43,36.33 98.14,36.33 98.22,36.24 98.22,35.09 102.24,31.07 102.24,15.64 102.13,15.54 102.13,15.32 102.24,15.22 102.24,14.99 102.13,14.89 102.13,14.67 102.24,14.57 102.24,13.93 102.07,13.77 101.81,13.77 101.73,13.85 v2(101.73,14.3)
FMC2_LA32_P: length 83.2
  TOP w0.124: U3.AL29 v2(92.9,65.93) ; J54.H37 v2(101.73,13.03)
  L05-SIG2 w0.081: v2(92.9,65.93) 93.47,65.36 93.47,62.53 98.43,57.58 98.43,56.71 98.22,56.51 97.57,56.51 97.49,56.43 97.49,56.1 97.57,56.02 98.5,56.02 98.7,55.82 98.7,55.32 98.5,55.12 97.57,55.12 97.49,55.04 97.49,54.71 97.57,54.63 98.48,54.63 98.68,54.43 98.68,53.93 98.48,53.73 97.57,53.73 97.49,53.64 97.49,53.32 97.57,53.24 98.22,53.24 98.43,53.03 98.43,52.54 98.22,52.33 97.57,52.33 97.49,52.25 97.49,51.93 97.57,51.85 98.22,51.85 98.43,51.64 98.43,51.14 98.22,50.94 97.57,50.94 97.49,50.86 97.49,50.53 97.57,50.45 98.22,50.45 98.43,50.25 98.43,49.75 98.22,49.55 97.57,49.55 97.49,49.47 97.49,49.14 97.57,49.06 98.22,49.06 98.43,48.86 98.43,48.36 98.22,48.16 97.57,48.16 97.49,48.08 97.49,47.75 97.57,47.67 98.22,47.67 98.43,47.47 98.43,46.97 98.22,46.77 97.57,46.77 97.49,46.68 97.49,46.36 97.57,46.28 98.22,46.28 98.43,46.07 98.43,45.58 98.22,45.37 97.57,45.37 97.49,45.29 97.49,44.97 97.57,44.89 98.22,44.89 98.43,44.68 98.43,44.18 98.22,43.98 97.57,43.98 97.49,43.9 97.49,43.58 97.57,43.49 98.22,43.49 98.43,43.29 98.43,42.79 98.22,42.59 97.57,42.59 97.49,42.51 97.49,42.18 97.57,42.1 98.22,42.1 98.43,41.9 98.43,41.4 98.22,41.2 97.57,41.2 97.49,41.12 97.49,40.79 97.57,40.71 98.22,40.71 98.43,40.51 98.43,40.01 98.22,39.81 97.57,39.81 97.49,39.72 97.49,39.4 97.57,39.32 98.22,39.32 98.43,39.11 98.43,38.62 98.22,38.41 97.57,38.41 97.49,38.33 97.49,38.01 97.57,37.93 98.22,37.93 98.43,37.72 98.43,37.23 98.22,37.02 97.52,37.02 97.43,36.94 97.43,36.62 97.52,36.53 98.22,36.53 98.43,36.33 98.43,35.18 102.44,31.16 102.44,13.84 102.16,13.56 101.81,13.56 101.73,13.48 v2(101.73,13.03)
FMC2_LA33_N: length 84.8
  TOP w0.099: J54.G37 v2(100.46,15.57)
  TOP w0.124: U3.AK27 v2(90.9,66.93)
  L05-SIG2 w0.081: v2(90.9,66.93) 91.36,66.93 91.44,66.85 91.44,66.51 91.64,66.31 92.19,66.31 92.32,66.18 92.32,61.99 96.44,57.87 96.44,56.93 96.36,56.85 95.71,56.85 95.5,56.64 95.5,56.14 95.71,55.94 96.36,55.94 96.44,55.86 96.44,55.53 96.36,55.45 95.71,55.45 95.5,55.25 95.5,54.75 95.71,54.55 96.36,54.55 96.44,54.47 96.44,54.14 96.36,54.06 95.71,54.06 95.5,53.86 95.5,53.36 95.71,53.16 96.36,53.16 96.44,53.08 96.44,52.75 96.36,52.67 95.71,52.67 95.5,52.47 95.5,51.97 95.71,51.77 96.36,51.77 96.44,51.68 96.44,51.36 96.36,51.28 95.71,51.28 95.5,51.07 95.5,50.58 95.71,50.37 96.36,50.37 96.44,50.29 96.44,49.97 96.36,49.89 95.71,49.89 95.5,49.68 95.5,49.18 95.71,48.98 96.36,48.98 96.44,48.9 96.44,48.58 96.36,48.49 95.71,48.49 95.5,48.29 95.5,47.79 95.71,47.59 96.36,47.59 96.44,47.51 96.44,47.18 96.36,47.1 95.71,47.1 95.5,46.9 95.5,46.4 95.71,46.2 96.36,46.2 96.44,46.12 96.44,45.79 96.36,45.71 95.71,45.71 95.5,45.51 95.5,45.01 95.71,44.81 96.36,44.81 96.44,44.72 96.44,44.4 96.36,44.32 95.71,44.32 95.5,44.11 95.5,43.62 95.71,43.41 96.36,43.41 96.44,43.33 96.44,43.01 96.36,42.93 95.71,42.93 95.5,42.72 95.5,42.23 95.71,42.02 96.36,42.02 96.44,41.94 96.44,41.62 96.36,41.53 95.71,41.53 95.5,41.33 95.5,40.83 95.71,40.63 96.36,40.63 96.44,40.55 96.44,40.22 96.36,40.14 95.71,40.14 95.5,39.94 95.5,39.44 95.71,39.24 96.36,39.24 96.44,39.16 96.44,38.83 96.36,38.75 95.88,38.75 95.68,38.55 95.68,38.05 95.88,37.85 96.36,37.85 96.44,37.76 96.44,37.44 96.36,37.36 96.01,37.36 95.8,37.16 95.8,36.66 96.01,36.45 96.36,36.45 96.44,36.37 96.44,35.62 101.01,31.05 101.01,30.69 101.21,30.49 101.21,30.09 101.01,29.88 101.01,29.3 101.21,29.1 101.21,28.69 101.01,28.49 101.01,27.91 101.21,27.71 101.21,27.3 101.01,27.1 101.01,26.52 101.21,26.32 101.21,25.91 101.01,25.71 101.01,25.13 101.21,24.92 101.21,24.52 101.01,24.31 101.01,21.57 100.93,21.49 99.85,21.49 99.64,21.29 99.64,20.28 99.94,19.98 100.93,19.98 101.01,19.9 101.01,18.25 100.91,18.15 100.91,17.89 101.01,17.8 101.01,17.59 100.91,17.5 100.91,17.24 101.01,17.15 101.01,16.94 100.91,16.85 100.91,16.59 101.01,16.5 101.01,16.29 100.89,16.17 100.89,15.97 101.01,15.85 101.01,15.29 100.76,15.04 100.54,15.04 100.46,15.12 v2(100.46,15.57)
FMC2_LA33_P: length 84.5
  TOP w0.099: J54.G36 v2(100.46,14.3)
  TOP w0.124: U3.AK28 v2(91.9,66.93)
  L05-SIG2 w0.081: v2(100.46,14.3) 100.46,14.75 100.54,14.83 100.84,14.83 101.22,15.2 101.22,19.99 101.02,20.19 100.03,20.19 99.85,20.36 99.85,21.2 99.93,21.28 101.02,21.28 101.22,21.48 101.22,24.23 101.42,24.43 101.42,25.01 101.22,25.21 101.22,25.62 101.42,25.82 101.42,26.4 101.22,26.61 101.22,27.01 101.42,27.21 101.42,27.79 101.22,28 101.22,28.4 101.42,28.61 101.42,29.19 101.22,29.39 101.22,29.8 101.42,30 101.42,30.58 101.22,30.78 101.22,31.14 96.65,35.71 96.65,36.46 96.44,36.66 96.09,36.66 96.01,36.74 96.01,37.07 96.09,37.15 96.44,37.15 96.65,37.35 96.65,37.85 96.44,38.05 95.97,38.05 95.88,38.14 95.88,38.46 95.97,38.54 96.44,38.54 96.65,38.75 96.65,39.24 96.44,39.45 95.79,39.45 95.71,39.53 95.71,39.85 95.79,39.93 96.44,39.93 96.65,40.14 96.65,40.64 96.44,40.84 95.79,40.84 95.71,40.92 95.71,41.24 95.79,41.33 96.44,41.33 96.65,41.53 96.65,42.03 96.44,42.23 95.79,42.23 95.71,42.31 95.71,42.64 95.79,42.72 96.44,42.72 96.65,42.92 96.65,43.42 96.44,43.62 95.79,43.62 95.71,43.7 95.71,44.03 95.79,44.11 96.44,44.11 96.65,44.31 96.65,44.81 96.44,45.01 95.79,45.01 95.71,45.1 95.71,45.42 95.79,45.5 96.44,45.5 96.65,45.71 96.65,46.2 96.44,46.41 95.79,46.41 95.71,46.49 95.71,46.81 95.79,46.89 96.44,46.89 96.65,47.1 96.65,47.59 96.44,47.8 95.79,47.8 95.71,47.88 95.71,48.2 95.79,48.29 96.44,48.29 96.65,48.49 96.65,48.99 96.44,49.19 95.79,49.19 95.71,49.27 95.71,49.6 95.79,49.68 96.44,49.68 96.65,49.88 96.65,50.38 96.44,50.58 95.79,50.58 95.71,50.66 95.71,50.99 95.79,51.07 96.44,51.07 96.65,51.27 96.65,51.77 96.44,51.97 95.79,51.97 95.71,52.06 95.71,52.38 95.79,52.46 96.44,52.46 96.65,52.66 96.65,53.16 96.44,53.37 95.79,53.37 95.71,53.45 95.71,53.77 95.79,53.85 96.44,53.85 96.65,54.06 96.65,54.55 96.44,54.76 95.79,54.76 95.71,54.84 95.71,55.16 95.79,55.25 96.44,55.25 96.65,55.45 96.65,55.95 96.44,56.15 95.79,56.15 95.71,56.23 95.71,56.56 95.79,56.64 96.44,56.64 96.65,56.84 96.65,57.96 92.53,62.07 92.53,66.26 92.28,66.52 91.73,66.52 91.65,66.6 91.65,66.83 91.75,66.93 v2(91.9,66.93)
FMC2_PG_C2M: length 181.4
  TOP w0.127: J53.4 84.82,38.38 79.76,33.32 v1(56.13,33.32)
  TOP w0.152: J54.D1 v2(54.74,19.38) ; U3.T18 v2(81.9,81.93)
  L03-SIG1 w0.091: J53.4 101.27,39.74 101.27,41.57 101.92,42.21 103.21,42.21 105.66,44.67 105.66,53.89 108.2,56.43 121.54,56.43 124.51,59.4 124.51,85.64 121.4,88.74 116.38,88.74 115.57,87.93 102.11,87.93 101.6,87.42 90.7,87.42 89.41,86.13 89.41,85.75 89.15,85.49 88.75,85.49 88.32,85.06 88.32,84.71 88.01,84.4 87.6,84.4 87.4,84.2 87.4,83.69 87.1,83.38 86.66,83.38 86.46,83.18 86.46,82.77 86.16,82.47 85.65,82.47 85.42,82.24 85.42,81.91 85.07,81.56 82.64,81.56 82.27,81.93 v2(81.9,81.93)
  L05-SIG2 w0.091: v2(54.74,19.38) 55.5,20.14 55.5,25.45 55.88,25.83 55.88,33.07 v1(56.13,33.32)
  BOTTOM w0.127: v2(54.74,19.38) 55.24,19.89 R327.1
FMC2_PG_M2C: length 182.6
  TOP w0.127: v1(56.13,34.72) 56.7,34.15 79.7,34.15 85.22,39.67 101.21,39.67 J53.5
  TOP w0.152: J54.F1 v1(54.74,15.57) ; U3.T19 v2(82.9,81.93)
  L03-SIG1 w0.091: v2(82.9,81.93) 82.9,82.06 83.31,82.47 85.17,82.47 85.39,82.7 85.39,83.18 85.57,83.36 86.08,83.36 86.44,83.71 86.44,84.17 86.69,84.43 87,84.43 87.33,84.76 87.33,85.04 87.71,85.42 88.19,85.42 88.47,85.7 88.47,86.18 88.65,86.36 89.1,86.36 90.3,87.55 90.3,88.06 90.68,88.44 98.04,88.44 98.68,87.8 101.47,87.8 101.98,88.31 115.32,88.31 116.04,89.03 121.58,89.03 124.8,85.81 124.8,59.06 121.79,56.05 108.33,56.05 105.99,53.72 105.99,44.46 J53.5
  L05-SIG2 w0.091: v1(54.74,15.57) 56.52,17.35 56.52,32.81 56.77,33.07 56.77,34.08 v1(56.13,34.72)
  BOTTOM w0.152: R328.1 54.3,16.2 54.74,15.77 v1(54.74,15.57)
FMC2_PRSNT_M2C_L: length 186.7
  TOP w0.127: J53.8 97.4,40.94 85.27,40.94 79.04,34.72 v1(57.02,34.72)
  TOP w0.152: U3.T15 v2(77.9,81.93) ; 56.64,13.66 v1(56.01,13.03)
  L03-SIG1 w0.091: J53.8 98.88,44.5 98.88,49.3 99.15,49.56 103.12,49.56 103.89,50.33 103.89,54.66 108.59,59.36 121.41,59.36 123.03,60.98 123.03,84.61 121.71,85.92 105.44,85.92 104.27,84.76 98.93,84.76 97.58,83.4 92.13,83.4 91.12,82.39 90.68,82.39 89.38,81.09 89.38,80.74 88.95,80.31 86.75,80.31 86.46,80.01 86.46,79.83 85.94,79.31 79.45,79.31 78.72,80.04 77.98,80.04 77.52,80.5 77.52,81.35 77.9,81.73 v2(77.9,81.93)
  L05-SIG2 w0.091: v1(57.02,34.72) 57.78,33.96 57.78,13.89 57.56,13.66 56.64,13.66 v1(56.01,13.03)
  BOTTOM w0.152: v1(56.01,13.03) 55.4,12.42 54.51,12.42 R310.1
FMC2_RES0: length 128.1
  TOP w0.152: U3.R19 v2(82.9,82.93)
  L03-SIG1 w0.091: v2(104.78,24.94) 106.3,26.46 106.3,53.51 108.33,55.55 121.92,55.55 125.09,58.72 125.09,85.93 121.7,89.33 112.14,89.33 111.51,88.69 101.6,88.69 100.97,88.06 98.93,88.06 98.25,88.74 98.25,89.12 97.92,89.45 90.81,89.45 90.3,88.95 90.3,88.69 90.04,88.44 89.79,88.44 89.41,88.06 89.41,87.68 89.15,87.42 88.77,87.42 88.33,86.98 88.33,86.68 88.06,86.41 87.64,86.41 87.42,86.19 87.42,85.59 87.22,85.38 86.73,85.38 86.39,85.04 86.39,84.75 86.05,84.41 85.66,84.41 85.45,84.2 85.45,83.71 85.17,83.43 83.42,83.43 82.91,82.93 v2(82.9,82.93)
  BOTTOM w0.152: v2(104.78,24.94) R309.2
FMC2_RES1: length 76.7
  TOP w0.152: U3.R18 v2(81.9,82.93)
  L05-SIG2 w0.091: v2(53.85,26.55) 53.85,34.97 54.87,35.99 54.87,41.1 57.06,43.29 57.06,47.8 59.09,49.83 61.98,49.83 64.73,52.58 69.96,52.58 71.91,54.53 74.04,54.53 77.58,58.07 77.58,67.21 77.72,67.36 80.01,67.36 80.39,67.74 80.39,78.66 81.53,79.8 81.53,82.39 81.9,82.75 v2(81.9,82.93)
  BOTTOM w0.152: R308.2 v2(53.85,26.55)
FMC2_SCL: length 145.1
  TOP w0.152: U3.R15 v2(77.9,82.93) ; 92.2,20.01 v2(92.84,20.65)
  L03-SIG1 w0.091: v2(77.9,82.93) 78.39,82.44 78.39,80.84 79.68,79.55 85.18,79.55 85.41,79.78 85.41,80.05 85.67,80.31 86.24,80.31 86.48,80.55 88.16,80.55 88.44,80.83 88.44,81.19 88.7,81.46 89.06,81.46 90.42,82.83 90.42,83.05 90.82,83.45 91.57,83.45 92.54,84.42 98.17,84.42 98.85,85.1 104.05,85.1 105.18,86.23 121.93,86.23 123.33,84.83 123.33,60.64 121.67,58.97 108.71,58.97 104.27,54.53 104.27,48.84 102.87,47.44 101.36,47.44 J53.10
  L12-SIG4 w0.091: v2(92.84,20.65) 92.46,21.03 92.46,23.29 103.52,34.35 103.52,39.01 102.87,39.66 101.78,39.66 101.19,40.25 101.19,44.73 J53.10
  BOTTOM w0.127: v2(92.84,20.65) 92.2,21.28 92.2,22.65 R321.1
FMC2_SDA: length 150
  TOP w0.152: J54.C31 v2(94.11,20.65) ; U3.R14 v2(76.9,82.93)
  L03-SIG1 w0.091: v2(76.9,82.93) 77.28,82.55 77.28,80.29 78.16,79.4 78.99,79.4 79.4,79 79.4,78.68 79.52,78.56 86.08,78.56 86.27,78.75 86.27,79.26 86.57,79.56 89.09,79.56 89.41,79.89 89.41,80.18 89.7,80.48 90,80.48 90.3,80.78 90.3,81.07 90.66,81.43 90.95,81.43 91.31,81.79 91.31,82.22 91.67,82.57 97.79,82.57 99.59,84.37 104.4,84.37 105.63,85.59 121.34,85.59 122.74,84.19 122.74,61.19 121.28,59.74 108.46,59.74 103.5,54.78 103.5,50.44 103.12,50.06 100.95,50.06 J53.14
  L12-SIG4 w0.091: v2(94.11,20.65) 94.37,20.65 96.09,22.37 96.09,24.49 105.41,33.81 105.41,47.57 103.17,49.81 101.2,49.81 J53.14
  BOTTOM w0.127: R322.1 93.47,22.4 93.47,21.28 v2(94.11,20.65)
FMC2_TCK: length 146.3
  TOP w0.152: J54.D29 v2(91.57,19.38)
  L03-SIG1 w0.091: v2(79.9,79.93) 80.27,80.3 85.27,80.3 85.54,80.56 86.11,80.56 86.84,81.3 87.55,81.3 87.68,81.42 88.07,81.42 88.42,81.77 88.42,82.16 88.71,82.45 89.1,82.45 89.43,82.79 89.43,83.1 89.86,83.53 90.2,83.53 90.45,83.78 90.45,84.17 90.74,84.46 92.09,84.46 92.32,84.7 92.32,85.1 92.65,85.43 103.8,85.43 104.9,86.53 122.15,86.53 123.62,85.06 123.62,60.42 121.79,58.59 108.84,58.59 104.65,54.4 104.65,48.69 103.03,47.07 101.89,47.07 101.14,46.32 101.14,43.02 100.25,42.13 99.36,42.13 98.76,41.54 98.76,38.01 99.64,37.13 101.21,37.13 J53.3
  L12-SIG4 w0.091: v2(91.57,19.38) 91.98,19.79 91.98,23.7 101.19,32.91 101.19,37.12 J53.3
  BOTTOM w0.152: v2(79.9,79.93) 79.77,80.06 R345.1 ; J53.3 102.48,38.4 R317.1
FMC2_TDI: length 142
  TOP w0.152: 92.2,18.74 v2(92.84,19.38) ; U3.U16 v2(78.9,80.93)
  L03-SIG1 w0.091: J53.7 105.36,46.36 105.36,54.1 109.09,57.83 122.3,57.83 124.21,59.74 124.21,85.51 122.56,87.17 104.27,87.17 104.17,87.07 99.59,87.07 99.09,86.56 90.75,86.56 90.42,86.23 90.42,85.72 90.17,85.47 89.69,85.47 89.38,85.16 89.38,84.73 89.08,84.42 88.72,84.42 88.47,84.17 88.47,83.66 88.16,83.36 87.66,83.36 87.33,83.03 87.33,82.74 87.07,82.49 86.73,82.49 86.38,82.13 86.38,81.86 86.06,81.55 85.45,81.55 85.22,81.31 79.25,81.31 78.9,80.96 v2(78.9,80.93)
  L12-SIG4 w0.091: J53.7 103.94,41.99 103.94,33.9 93.5,23.46 93.5,21.81 93.22,21.53 93.22,19.76 v2(92.84,19.38)
  BOTTOM w0.127: R314.1 103.21,42.72 J53.7
FMC2_TDO: length 140.4
  TOP w0.152: U3.U17 v2(79.9,80.93) ; J54.D31 v2(94.11,19.38)
  L03-SIG1 w0.091: J53.9 105.03,48.57 105.03,54.28 108.97,58.21 122.05,58.21 123.92,60.08 123.92,85.29 122.34,86.86 104.66,86.86 103.7,85.9 99.44,85.9 99.06,86.28 92.28,86.28 91.42,85.42 90.65,85.42 90.47,85.24 90.47,84.71 90.25,84.48 89.79,84.48 89.46,84.15 89.46,83.82 89.15,83.51 88.88,83.51 88.42,83.05 88.42,82.73 88.12,82.43 87.75,82.43 87.4,82.08 87.4,81.73 87.22,81.55 86.48,81.55 86.26,81.33 85.72,81.33 85.36,80.96 85.36,80.81 85.11,80.55 81.43,80.55 81.05,80.93 v2(79.9,80.93)
  L12-SIG4 w0.091: J53.9 104.39,44.07 104.39,33.58 94.65,23.84 94.65,21.85 93.72,20.91 93.72,19.74 94.08,19.38 v2(94.11,19.38)
  BOTTOM w0.127: J53.9 102.48,46.02 R315.1
FMC2_TMS: length 139.6
  TOP w0.152: U3.W14 v2(76.9,77.93) ; J54.D33 v2(96.65,19.38)
  L03-SIG1 w0.091: v2(76.9,77.93) 77.27,78.3 86.23,78.3 86.51,78.59 86.51,79.09 86.73,79.32 89.81,79.32 90.3,79.8 90.3,80.22 90.66,80.59 90.95,80.59 91.8,81.43 92.13,81.43 92.38,81.68 92.38,82.06 92.66,82.34 98.17,82.34 99.82,83.99 104.65,83.99 105.92,85.26 121.16,85.26 122.44,83.98 122.44,61.4 121.16,60.12 108.2,60.12 103.12,55.04 103.12,51.75 J53.13
  L12-SIG4 w0.091: J53.13 102.78,51.08 105.94,47.93 105.94,33.3 97.3,24.66 97.3,20.04 v2(96.65,19.38)
  BOTTOM w0.127: J53.13 102.48,51.1 R316.1
FMC2_TRST_L: length 33.7
  TOP w0.152: 97.28,18.74 v2(97.92,19.38)
  L12-SIG4 w0.091: J53.6 98.85,39.85 98.85,32.85 91.08,25.09 91.08,19.15 91.58,18.65 97.19,18.65 v2(97.92,19.38)
FMC2_VREFA: length 90.6
  TOP w0.508: J54.H1 v4(54.74,13.03)
  L12-SIG4 w0.508: JP42.2 JP40.2 111.38,41.32 110.24,40.18 108.84,40.18 108.2,39.54 108.2,35.86 107.31,34.97 107.31,32.81 98.55,24.05 98.55,10.46 97.03,8.94 54.99,8.94 53.98,9.95 53.98,12.27 v4(54.74,13.03)
GPIO_AP14: length 111.7
  TOP w0.127: U3.AP14 77.4,61.57 74.42,58.59 74.42,57.96 73.66,57.2 71.88,57.2 67.56,52.88 50.67,52.88 49.66,51.86 49.66,41.32 51.18,39.8 51.18,34.72 53.72,32.18 102.82,32.18 v1(107.39,36.75)
  BOTTOM w0.127: U46.4 v1(107.39,36.75)
ICS: length 45.2
  TOP w0.254: v1(148.21,20.11) 148.21,20.75 147.69,21.26 U111.17 ; U110.17 121.04,26.07 120.52,26.59 v1(120.52,27.22)
  L05-SIG2 w0.254: v1(120.52,27.22) 120.65,27.1 120.65,22.14 119.51,21 119.51,18.33 121.28,16.56 146.43,16.56 147.45,17.57 147.45,19.35 v1(148.21,20.11)
IMON1N_082V: length 91.8
  TOP w0.203: v1(137.79,101.39) 137.79,102.79 136.65,103.93 128.14,103.93 123.32,99.11 123.32,94.98 122.88,94.53 121.29,94.53 121.08,94.33 R658.2
  TOP w0.254: U45.H10 v3(160.84,68.26)
  L05-SIG2 w0.203: v3(160.84,68.26) 160.88,68.3 160.88,70.32 162.37,71.81 162.37,76.37 161.77,76.97 161.77,80.86 162.15,81.24 162.15,82.89 163.04,83.78 163.04,85.29 162.28,86.05 162.28,90.24 159,93.52 153.42,93.52 152.4,92.5 152.4,90.98 150.34,88.92 140.87,88.92 138.94,90.85 138.94,93.26 137.79,94.41 v1(137.79,101.39)
IMON1P_082V: length 93.9
  TOP w0.203: R658.1 121.08,95.14 121.29,94.94 122.71,94.94 122.91,95.14 122.91,99.28 127.97,104.34 136.82,104.34 138.2,102.96 138.2,101.75 v1(138.56,101.39)
  TOP w0.254: U45.J10 v3(160.84,67.46)
  L05-SIG2 w0.203: v1(138.56,101.39) 138.2,101.04 138.2,94.58 139.34,93.43 139.34,91.02 141.04,89.33 150.17,89.33 151.99,91.15 151.99,92.67 153.25,93.93 159.17,93.93 162.69,90.41 162.69,86.22 163.45,85.46 163.45,83.61 162.56,82.72 162.56,81.07 162.18,80.69 162.18,77.14 162.78,76.53 162.78,71.64 161.29,70.15 161.29,67.9 v3(160.84,67.46)
INITN: length 45.5
  TOP w0.127: J3.6 56.76,113.34 59.63,113.34 62.09,110.87 62.09,108.93 D4.K 61.21,106.5 INIT.1
  TOP w0.152: U3.T5 v2(67.9,81.93)
  L05-SIG2 w0.091: INIT.1 65.41,102.31 65.41,100.5 66.36,99.55 66.36,86.72 66.55,86.53 67.06,86.53 67.44,86.15 67.44,85.9 67.82,85.52 68.07,85.52 68.45,85.14 68.45,84.76 68.71,84.5 68.96,84.5 69.34,84.12 69.34,82.6 69.09,82.34 68.31,82.34 v2(67.9,81.93)
  BOTTOM w0.152: INIT.1 62.17,106.14 R22.2
K_DIG1: length 2.9
  BOTTOM w0.127: D60.12 70.98,146.33 Q4.C
K_DIG2: length 3.3
  BOTTOM w0.127: D60.9 78.6,146.33 Q2.C
K_DIG3: length 3.4
  BOTTOM w0.127: Q3.C 81.17,146.33 D60.8
LED_0: length 113.2
  TOP w0.127: U3.L8 v2(70.9,86.93)
  L05-SIG2 w0.127: v1(113.41,144.45) 112.93,144.93 98.38,144.93 95.97,147.35 70.66,147.35 64.9,141.59 64.9,139.37 62.87,137.33 62.87,109.63 64.28,108.21 64.28,105.18 68.61,100.85 68.61,98.57 69.34,97.84 69.34,87.8 69.6,87.55 70.28,87.55 v2(70.9,86.93)
  BOTTOM w0.152: R687.2 v1(113.41,144.45)
LED_1: length 128.9
  TOP w0.127: U3.P8 v2(70.9,83.93)
  L05-SIG2 w0.127: v2(70.9,83.93) 70.36,84.47 70.36,85.26 70.1,85.52 69.47,85.52 68.33,86.66 68.33,87.04 67.94,87.42 67.69,87.42 67.44,87.68 67.44,99.36 66.42,100.38 66.42,102.03 63.37,105.08 63.37,107.36 62.1,108.63 62.1,137.67 64.01,139.58 64.01,142.03 70.36,148.38 96.77,148.38 99.06,146.1 122.17,146.1 v1(123.82,144.45)
  BOTTOM w0.127: R688.2 v1(123.82,144.45)
LED_2: length 120.9
  TOP w0.127: U3.M8 v2(70.9,85.93)
  L05-SIG2 w0.127: v1(118.62,144.45) 117.63,145.44 98.7,145.44 96.24,147.9 70.4,147.9 64.39,141.89 64.39,139.49 62.47,137.58 62.47,109.28 63.88,107.87 63.88,105.08 67.94,101.01 67.94,98.57 68.33,98.19 68.33,87.8 68.71,87.42 69.09,87.42 69.42,87.09 69.42,86.66 69.67,86.41 70.42,86.41 v2(70.9,85.93)
  BOTTOM w0.127: R689.2 v1(118.62,144.45)
LED_3: length 96.7
  TOP w0.127: U3.M9 v2(71.9,85.93)
  L05-SIG2 w0.127: v1(98.17,144.32) 90.81,144.32 89.73,145.4 69.41,145.4 65.32,141.32 65.32,139.28 63.25,137.2 63.25,112.19 64.64,110.79 64.64,105.46 70.36,99.74 70.36,87.93 70.87,87.42 70.99,87.42 71.5,86.91 71.5,86.33 v2(71.9,85.93)
  BOTTOM w0.127: R690.2 v1(98.17,144.32)
LED_4: length 104.2
  TOP w0.203: U3.P10 v2(72.9,83.93)
  L05-SIG2 w0.127: v2(72.9,83.93) 73.41,84.44 73.41,98.13 70.91,100.63 70.91,109.61 67.65,112.87 67.65,119.41 66.57,120.48 66.57,138.46 71.15,143.05 86.23,143.05 87,142.29 89.46,142.29 90.38,143.22 106.97,143.22 v1(108.2,144.45)
  BOTTOM w0.127: R691.2 v1(108.2,144.45)
LED_5: length 98.7
  TOP w0.127: U3.N10 v2(72.9,84.93)
  L05-SIG2 w0.127: v2(72.9,84.93) 72.52,85.31 72.52,97.33 71.75,98.09 71.75,99.23 70.28,100.71 70.28,109.29 66.94,112.63 66.94,118.91 66.21,119.64 66.21,139.02 71.89,144.7 89.15,144.7 90.04,143.81 102.62,143.81 v1(103.25,144.45)
  BOTTOM w0.127: R692.2 v1(103.25,144.45)
LED_6: length 130
  TOP w0.152: U3.AL10 v2(72.9,65.93)
  L05-SIG2 w0.127: v1(131.06,146.74) 127.47,143.15 123.42,143.15 122.94,142.67 92.08,142.67 84.76,135.35 84.76,106.55 85.22,106.09 85.22,101.52 80.65,96.95 80.65,80.16 80.03,79.55 79.5,79.55 79.25,79.29 79.25,78.79 78.99,78.53 78.63,78.53 78.25,78.15 78.25,69.69 78.13,69.57 76.62,69.57 76.3,69.24 76.3,67.71 76.07,67.48 75.82,67.48 75.44,67.1 75.44,66.8 75.18,66.54 73.99,66.54 73.79,66.34 73.31,66.34 v2(72.9,65.93)
  BOTTOM w0.152: v1(131.06,146.74) 131.08,146.73 R683.2
LED_7: length 125.8
  TOP w0.152: U3.AL11 v2(73.9,65.93)
  L05-SIG2 w0.127: v2(73.9,65.93) 74.26,66.29 75.9,66.29 76.28,66.67 76.28,67.31 76.55,67.58 76.55,69.13 76.73,69.31 78.28,69.31 78.51,69.54 78.51,78.05 78.74,78.28 79.12,78.28 79.5,78.66 79.5,79.17 79.63,79.29 80.14,79.29 80.9,80.06 80.9,96.69 85.6,101.39 85.6,106.35 85.12,106.83 85.12,135.2 92.07,142.16 124.84,142.16 v1(125.22,142.54)
  BOTTOM w0.152: R684.2 126.35,146.74 125.49,146.74 125.22,146.48 v1(125.22,142.54)
LED_8: length 69.5
  TOP w0.203: U3.AN15 v2(77.9,63.93)
  L12-SIG4 w0.127: v2(77.9,63.93) 77.9,59.66 75.76,57.51 75.76,49.64 56.6,30.48 52.92,30.48 43.35,20.92 43.35,14.06 v1(42.42,13.13)
  BOTTOM w0.203: v1(42.42,13.13) 42.93,12.62 R520.2
LED_9: length 80
  TOP w0.203: U3.AH17 v2(79.9,68.93)
  L12-SIG4 w0.127: v2(79.9,68.93) 80.26,68.57 80.26,60.37 77.01,57.12 77.01,49.37 56.87,29.23 53.45,29.23 44.51,20.3 44.51,12.81 43.43,11.73 40.39,11.73 v1(39.88,12.24)
  BOTTOM w0.203: R522.2 v1(39.88,12.24)
LED_10: length 85.9
  TOP w0.203: U3.AG17 v2(79.9,69.93)
  L12-SIG4 w0.127: v2(79.9,69.93) 80.52,69.31 80.52,60.12 77.34,56.94 77.34,49.2 57.02,28.88 53.59,28.88 44.89,20.18 44.89,12.68 43.56,11.35 36.7,11.35 v1(35.81,12.24)
  BOTTOM w0.203: R525.2 v1(35.81,12.24)
LED_11: length 79.5
  TOP w0.203: U3.AM14 v2(76.9,64.93)
  L12-SIG4 w0.127: v1(32.13,11.48) 33.09,11.48 35.88,14.27 39.37,14.27 40.96,15.86 40.96,19.04 52.77,30.84 56.45,30.84 75.31,49.7 75.31,57.55 77.34,59.58 77.34,64.49 v2(76.9,64.93)
  BOTTOM w0.203: v1(32.13,11.48) 31.37,12.24 R527.2
LED_12: length 83
  TOP w0.203: U3.AL14 v2(76.9,65.93)
  L12-SIG4 w0.127: v1(27.81,12.49) 33.09,12.49 35.58,14.99 39.07,14.99 40.24,16.16 40.24,19.33 52.47,31.56 56.15,31.56 74.55,49.96 74.55,58.97 76.4,60.82 76.4,65.43 v2(76.9,65.93)
  BOTTOM w0.203: R530.2 27.56,12.24 v1(27.81,12.49)
LED_13: length 97
  TOP w0.203: U3.AK17 v2(79.9,66.93)
  L12-SIG4 w0.127: v2(79.9,66.93) 79.9,66.64 79.45,66.19 79.45,60.19 76.58,57.32 76.58,49.45 56.9,29.76 53.21,29.76 44.07,20.62 44.07,13.25 42.93,12.11 41.27,12.11 39.88,13.51 36.2,13.51 33.27,10.59 30.35,10.59 29.72,11.22 22.23,11.22 v1(22.1,11.35)
  BOTTOM w0.203: R531.2 22.61,11.86 v1(22.1,11.35)
LED_14: length 100.4
  TOP w0.203: U3.AJ17 v2(79.9,67.93)
  L12-SIG4 w0.127: v2(79.9,67.93) 79.9,67.7 79.4,67.2 79.4,66.67 79.12,66.39 78.77,66.39 78.4,66.03 78.4,59.67 76.17,57.43 76.17,49.54 56.75,30.12 53.06,30.12 43.71,20.77 43.71,13.53 42.67,12.49 41.4,12.49 40.03,13.87 36.05,13.87 33.15,10.97 30.61,10.97 29.97,11.6 23.62,11.6 22.99,12.24 v1(19.43,12.24)
  BOTTOM w0.203: R534.2 v1(19.43,12.24)
LED_15: length 95.4
  TOP w0.203: U3.AN14 v2(76.9,63.93)
  L12-SIG4 w0.127: v2(76.9,63.93) 76.9,59.67 74.93,57.7 74.93,49.83 56.3,31.2 52.62,31.2 40.6,19.18 40.6,16.01 39.22,14.63 35.73,14.63 33.09,11.98 23.85,11.98 22.99,12.85 19.71,12.85 18.92,13.64 15,13.64 v1(14.49,13.13)
  BOTTOM w0.203: R535.2 14.48,13.12 v1(14.49,13.13)
LPDDR4_A0_A: length 71.9
  TOP w0.127: U3.AC26 v2(89.9,73.93)
  L05-SIG2 w0.076: v3(116.83,76.84) 116.43,77.24 114.95,77.24 v3(114.55,76.84) 114.15,77.24 112.68,77.24 v3(112.28,76.84) ; v3(112.28,63.12) 112.68,63.52 114.15,63.52 v3(114.55,63.12) 114.95,63.52 116.43,63.52 v3(116.83,63.12)
  L10-SIG3 w0.076: v3(114.55,63.12) 113.92,63.76 113.92,65.35 114.1,65.53 116.38,65.53 116.5,65.65 116.5,66.15 116.58,66.22 117.32,66.22 117.41,66.31 117.41,66.6 117.32,66.68 116.58,66.68 116.5,66.76 v3(116.5,72.31) 116.71,72.52 116.71,73.07 116.97,73.33 118.67,73.33 118.75,73.4 118.75,73.62 118.67,73.69 118.19,73.69 118.11,73.77 118.11,74 118.19,74.07 118.76,74.07 118.83,74.15 118.83,74.38 118.76,74.45 118.19,74.45 118.11,74.53 118.11,74.76 118.19,74.83 118.75,74.83 118.82,74.91 118.82,75.14 118.75,75.22 118.19,75.22 118.11,75.29 118.11,75.52 118.19,75.6 118.41,75.6 118.49,75.67 118.49,76.37 118.36,76.5 114.89,76.5 v3(114.55,76.84)
  L12-SIG4 w0.142: v2(89.9,73.93) 89.41,73.44 89.41,71.8 89.79,71.42 90.04,71.42 90.42,71.04 90.42,70.79 90.75,70.46 102.93,70.46 103.07,70.31 103.07,70.17 103.21,70.02 103.5,70.02 103.64,70.17 103.64,70.31 103.78,70.46 104.07,70.46 104.21,70.31 104.21,70.17 104.35,70.02 104.64,70.02 104.78,70.17 104.78,70.31 104.92,70.46 105.21,70.46 105.35,70.31 105.35,70.17 105.49,70.02 105.77,70.02 105.92,70.17 105.92,70.31 106.06,70.46 106.34,70.46 106.49,70.31 106.49,70.17 106.63,70.02 106.91,70.02 107.05,70.17 107.05,70.31 107.2,70.46 107.85,70.46 108.1,70.71 116.26,70.71 116.5,70.96 v3(116.5,72.31)
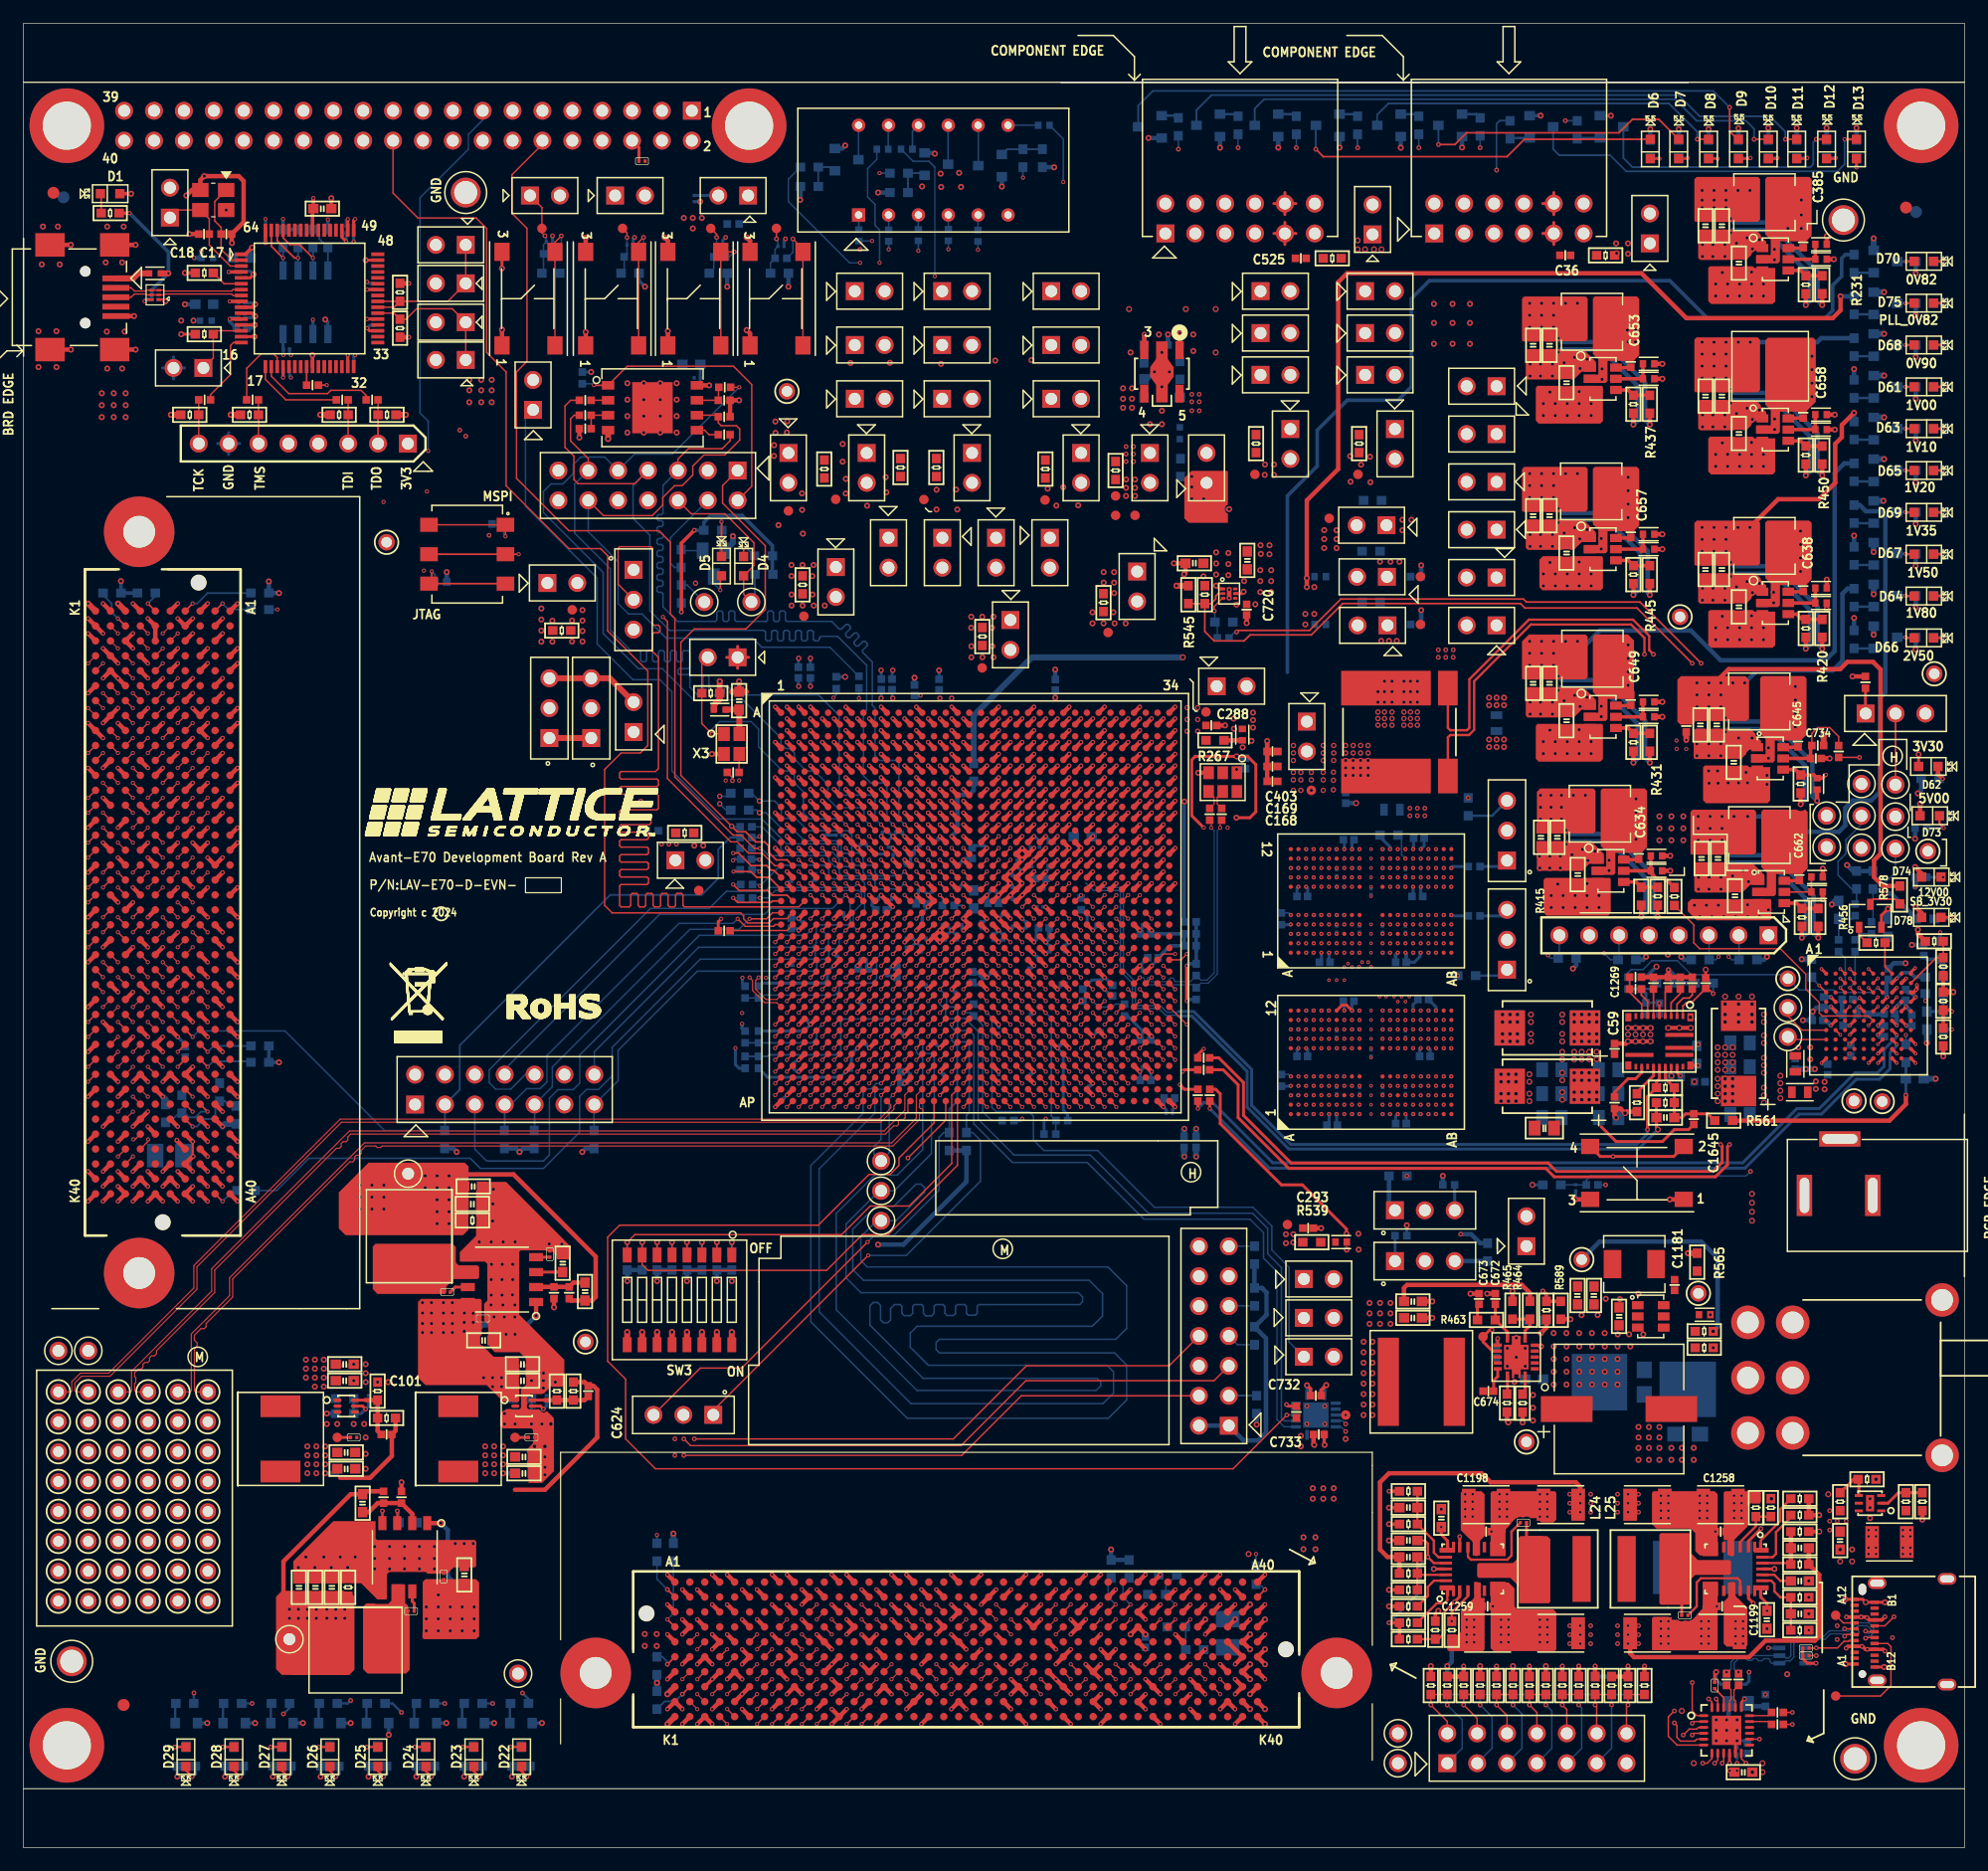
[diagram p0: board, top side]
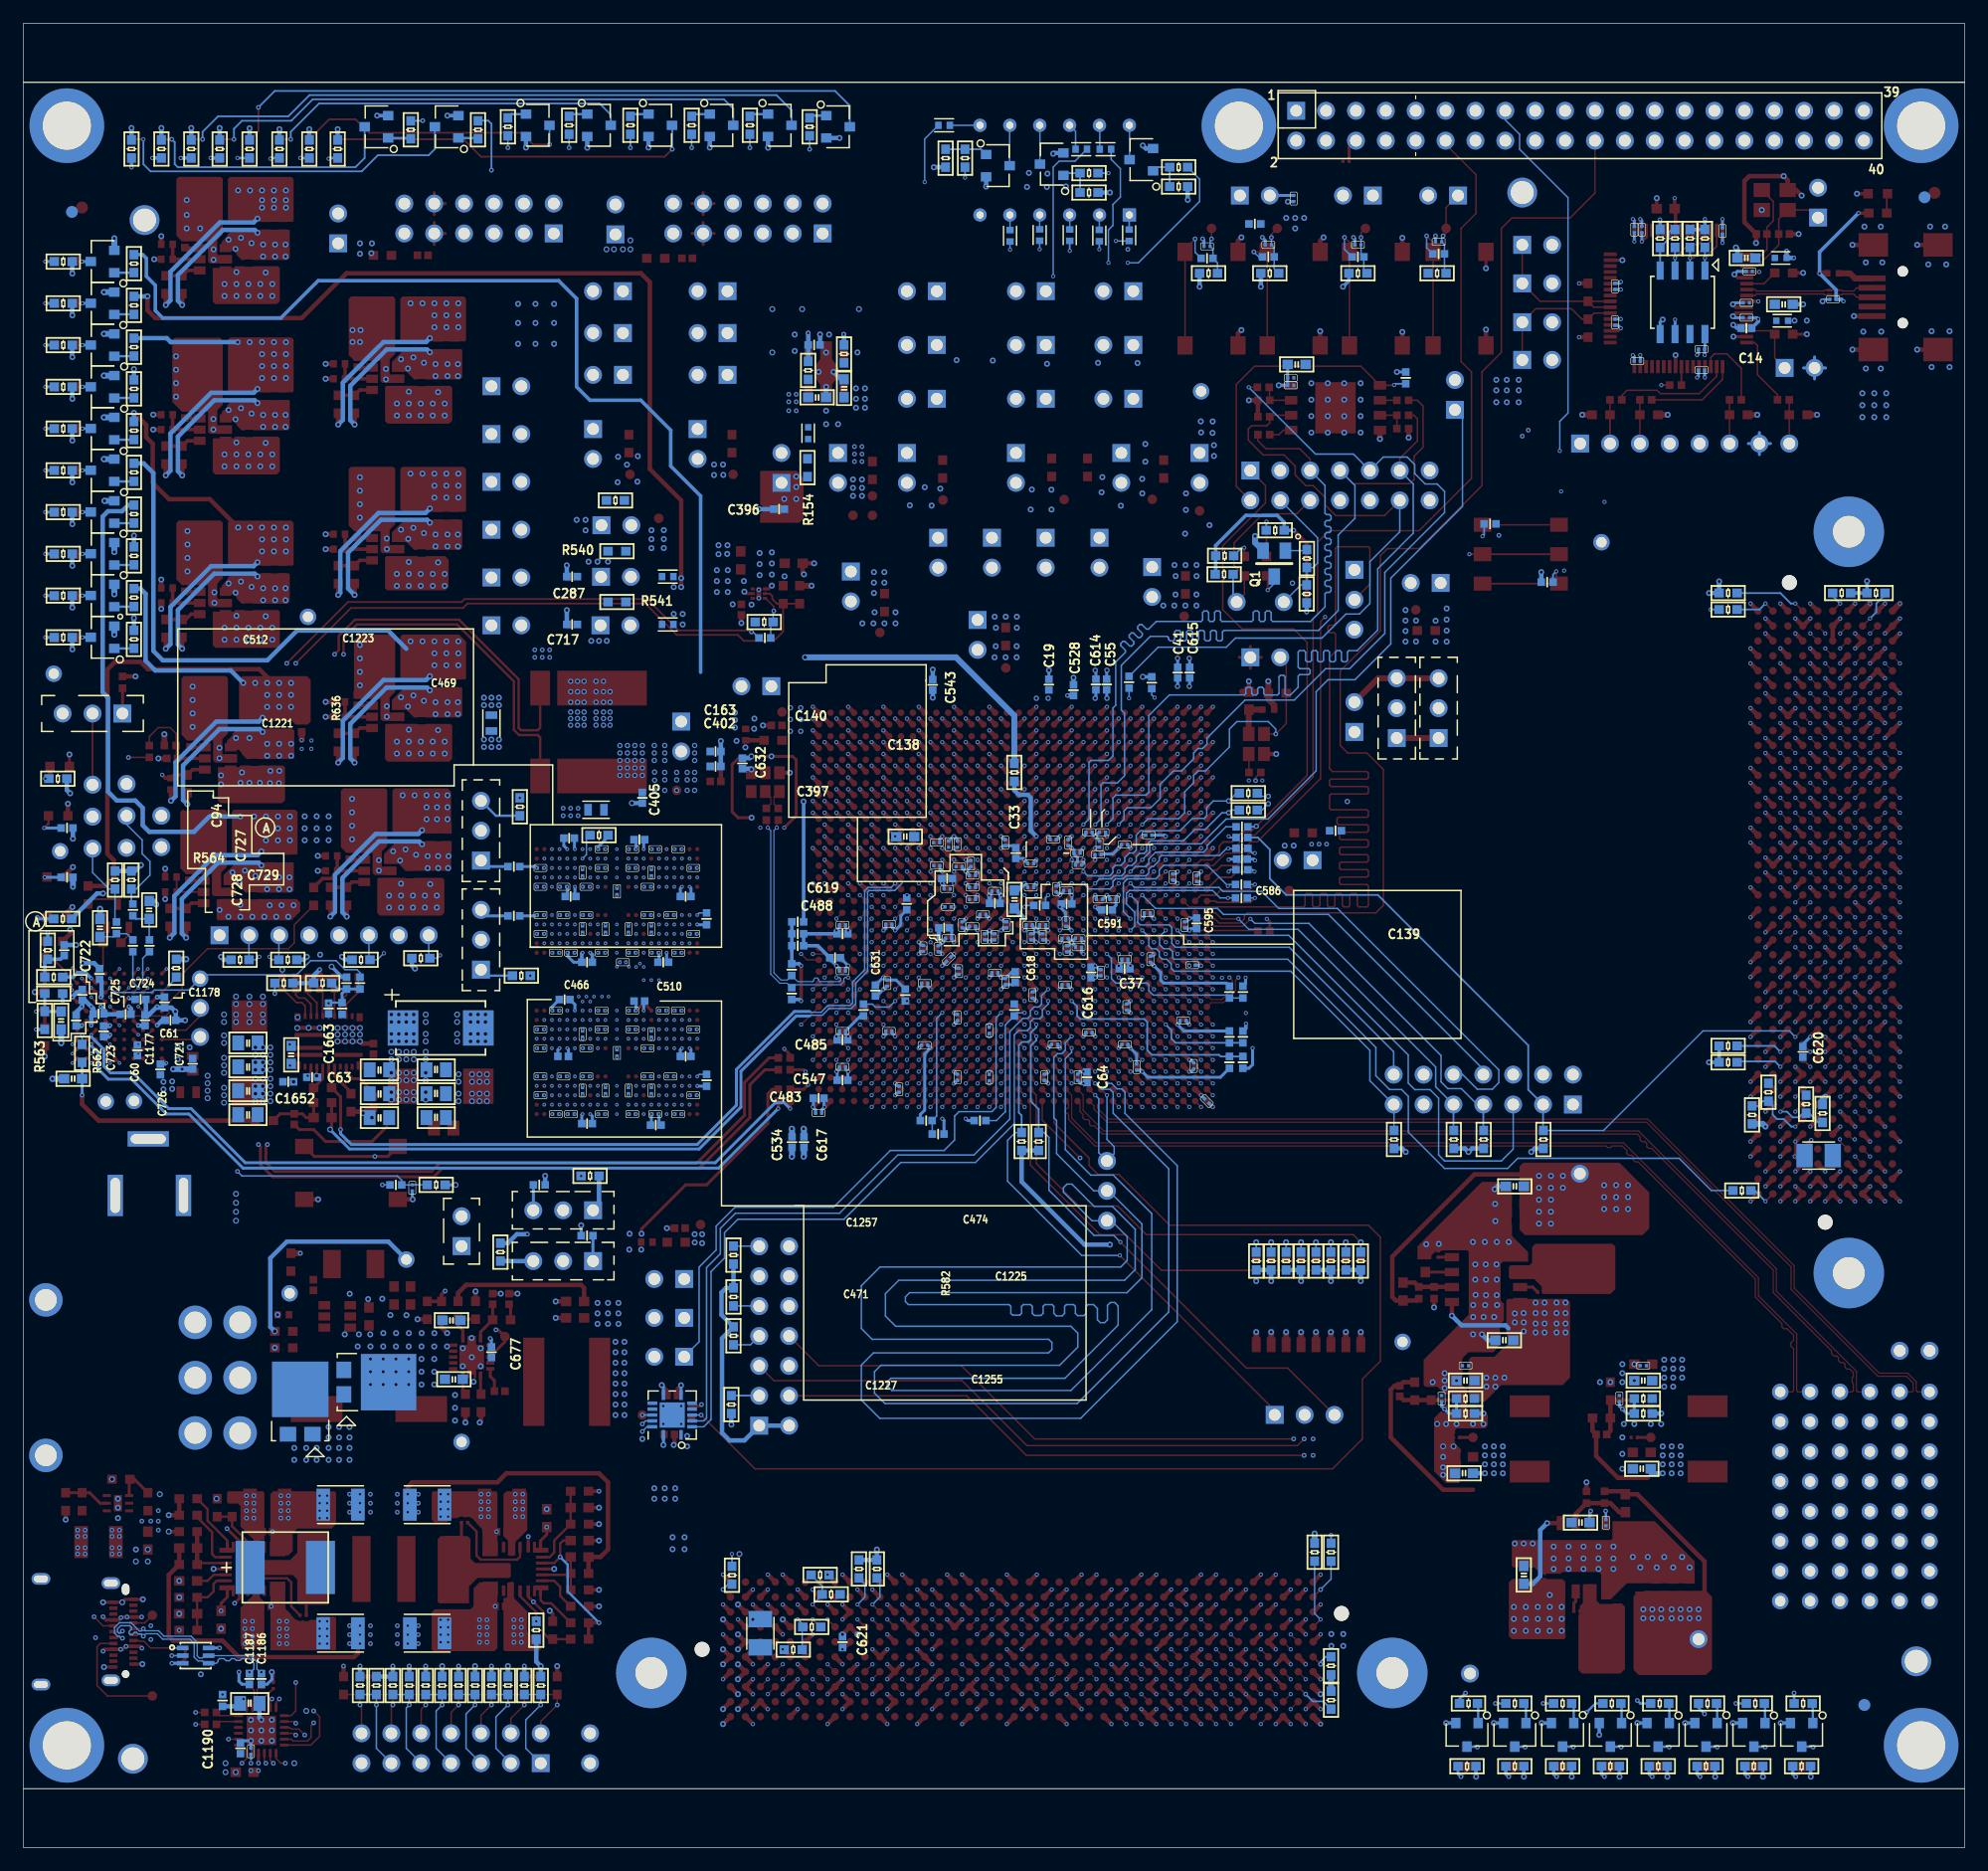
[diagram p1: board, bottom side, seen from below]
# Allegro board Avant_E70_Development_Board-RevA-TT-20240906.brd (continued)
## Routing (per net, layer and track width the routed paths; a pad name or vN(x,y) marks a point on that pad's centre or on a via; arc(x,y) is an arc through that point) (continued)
LPDDR4_A1_A: length 70.2
  TOP w0.127: U3.AB27 v2(90.9,74.93)
  L05-SIG2 w0.076: v3(116.18,76.84) 116.18,76.54 116.06,76.43 115.31,76.43 115.21,76.52 115.21,76.63 115.12,76.72 114.95,76.72 114.86,76.63 114.86,76.34 v3(114.55,76.04) 114.25,76.34 114.25,76.63 114.16,76.72 113.99,76.72 113.89,76.63 113.89,76.52 113.8,76.43 113.05,76.43 112.93,76.54 v3(112.93,76.84) ; v3(112.93,63.12) 112.93,62.83 113.05,62.71 113.8,62.71 113.89,62.8 113.89,62.91 113.99,63 114.16,63 114.25,62.91 114.25,62.63 v3(114.55,62.32) 114.86,62.63 114.86,62.91 114.95,63 115.12,63 115.21,62.91 115.21,62.8 115.31,62.71 116.06,62.71 116.18,62.83 v3(116.18,63.12)
  L10-SIG3 w0.076: v3(114.55,62.32) 114.07,62.32 114,62.4 114,63.24 113.72,63.52 113.36,63.52 113.25,63.63 113.25,66.01 113.38,66.14 115.72,66.14 115.85,66.27 115.85,72.28 v3(115.82,72.31) 116.33,72.82 116.33,73.64 116.41,73.71 117.67,73.71 117.74,73.79 117.74,74.02 117.67,74.09 116.41,74.09 116.33,74.17 116.33,74.39 116.41,74.47 117.68,74.47 117.75,74.55 117.75,74.76 117.68,74.84 116.41,74.84 116.33,74.91 116.33,75.22 116.41,75.29 117.65,75.29 117.73,75.37 117.73,75.62 117.65,75.7 114.89,75.7 v3(114.55,76.04)
  L12-SIG4 w0.142: v2(90.9,74.93) 90.9,73.8 90.42,73.33 90.42,72.69 90.68,72.44 99.21,72.44 99.67,71.98 113.54,71.98 113.79,72.23 113.79,73.45 113.92,73.58 114.33,73.58 114.47,73.44 114.47,72.83 114.61,72.69 114.9,72.69 115.04,72.83 115.04,73.44 115.18,73.58 115.57,73.58 115.8,73.35 115.8,72.34 v3(115.82,72.31)
LPDDR4_A2_A: length 70
  TOP w0.127: U3.AB28 v2(91.9,74.93)
  L05-SIG2 w0.076: v3(116.83,68.72) 116.43,69.12 114.95,69.12 v3(114.55,68.72) 114.15,69.12 112.68,69.12 v3(112.28,68.72)
  L05-SIG2 w0.091: v3(116.83,82.44) 116.43,82.84 114.95,82.84 v3(114.55,82.44) 114.15,82.84 112.68,82.84 v3(112.28,82.44)
  L10-SIG3 w0.076: v3(114.55,68.72) 114.15,69.12 108.27,69.12 108.08,69.31 108.08,72.79 108.86,73.58 110.85,73.58 v3(110.98,73.71) 111.3,74.03 111.3,80.74 111.94,81.38 111.94,81.76 112.27,82.09 112.37,82.09 112.6,82.32 112.6,82.55 112.9,82.85 112.95,82.85 113.28,83.18 113.28,83.36 113.46,83.54 114.71,83.54 114.86,83.38 114.86,82.74 v3(114.55,82.44)
  L12-SIG4 w0.142: v2(91.9,74.93) 91.9,75.38 92,75.48 93.22,75.48 93.4,75.31 93.4,74.59 93.57,74.41 97.48,74.41 97.74,74.67 98.35,74.67 98.7,74.32 98.7,73.86 98.86,73.71 99.09,73.71 99.23,73.85 99.23,74.35 99.37,74.49 99.66,74.49 99.8,74.35 99.8,73.85 99.94,73.71 100.23,73.71 100.37,73.85 100.37,74.35 100.51,74.49 100.8,74.49 100.94,74.35 100.94,73.85 101.08,73.71 101.37,73.71 101.51,73.85 101.51,74.35 101.65,74.49 101.93,74.49 102.08,74.35 102.08,73.85 102.22,73.71 102.5,73.71 102.65,73.85 102.65,74.35 102.79,74.49 103.07,74.49 103.21,74.35 103.21,73.85 103.36,73.71 103.64,73.71 103.78,73.85 103.78,74.33 103.93,74.47 104.21,74.47 104.35,74.33 104.35,73.85 104.5,73.71 104.83,73.71 104.98,73.56 104.98,73.24 105.12,73.1 105.4,73.1 105.54,73.24 105.54,73.56 105.69,73.71 105.97,73.71 106.11,73.56 106.11,73.24 106.26,73.1 106.54,73.1 106.68,73.24 106.68,73.56 106.82,73.71 107.11,73.71 107.25,73.56 107.25,73.24 107.39,73.1 107.68,73.1 107.82,73.24 107.82,73.56 107.96,73.71 108.32,73.71 108.46,73.56 108.46,73.21 108.6,73.07 108.89,73.07 109.03,73.21 109.03,73.56 109.17,73.71 109.45,73.71 109.6,73.56 109.6,73.21 109.74,73.07 110.02,73.07 110.17,73.21 110.17,73.56 110.31,73.71 v3(110.98,73.71)
LPDDR4_A3_A: length 68.2
  TOP w0.127: v2(92.9,74.93) 92.4,74.43 U3.AC29
  L05-SIG2 w0.076: v3(116.83,69.52) 116.43,69.92 114.95,69.92 v3(114.55,69.52) 114.15,69.92 112.68,69.92 v3(112.28,69.52) ; v3(116.83,83.24) 116.43,83.64 114.95,83.64 v3(114.55,83.24) 114.15,83.64 112.68,83.64 v3(112.28,83.24)
  L10-SIG3 w0.076: v3(114.55,83.24) 114.55,82.93 114.48,82.85 113.36,82.85 113.23,82.72 113.23,82.17 113.16,82.09 112.78,82.09 112.6,81.91 112.6,81.4 111.95,80.76 111.95,80.62 111.88,80.55 111.71,80.55 111.63,80.47 111.63,80.32 111.71,80.24 111.88,80.24 111.95,80.16 111.95,80.01 111.88,79.94 111.71,79.94 111.63,79.86 111.63,79.71 111.71,79.63 111.88,79.63 111.95,79.56 111.95,75.73 111.88,75.65 111.71,75.65 111.63,75.58 111.63,75.42 111.71,75.35 111.88,75.35 111.95,75.27 111.95,75.12 111.88,75.04 111.71,75.04 111.63,74.97 111.63,74.82 111.71,74.74 111.88,74.74 111.95,74.66 111.95,74.03 v3(112.28,73.71) 112.28,73.46 112.09,73.28 109.42,73.28 109.35,73.2 109.35,73.02 109.27,72.94 108.94,72.94 108.86,72.86 108.86,72.63 108.94,72.56 109.27,72.56 109.35,72.48 109.35,72.25 109.27,72.18 108.93,72.18 108.85,72.1 108.85,71.87 108.93,71.8 109.27,71.8 109.35,71.72 109.35,70.02 109.47,69.9 114.18,69.9 v3(114.55,69.52)
  L12-SIG4 w0.142: v3(112.28,73.71) 112.66,73.33 113.11,73.33 113.23,73.2 113.23,72.63 113.09,72.49 111.76,72.49 111.62,72.63 111.62,73.06 111.48,73.2 111.19,73.2 111.05,73.06 111.05,72.63 110.91,72.49 104.62,72.49 104.52,72.59 104.52,73.07 104.38,73.21 104.08,73.21 103.93,73.07 103.93,72.63 103.79,72.49 103.51,72.49 103.37,72.63 103.37,73.07 103.22,73.21 102.94,73.21 102.8,73.07 102.8,72.63 102.65,72.49 102.37,72.49 102.23,72.63 102.23,73.07 102.09,73.21 101.8,73.21 101.66,73.07 101.66,72.63 101.52,72.49 101.23,72.49 101.09,72.63 101.09,73.07 100.95,73.21 100.66,73.21 100.52,73.07 100.52,72.63 100.38,72.49 100.09,72.49 99.95,72.63 99.95,73.07 99.81,73.21 98.62,73.21 98.12,73.71 97.54,73.71 97.28,73.45 96.75,73.45 96.57,73.63 96.24,73.63 96.04,73.43 93.12,73.43 92.9,73.64 v2(92.9,74.93)
LPDDR4_A4_A: length 68.1
  TOP w0.127: U3.AB29 v2(92.9,75.93)
  L05-SIG2 w0.076: v3(116.83,84.04) 116.34,84.53 114.86,84.53 v3(114.55,84.84) 114.24,84.53 112.77,84.53 v3(112.28,84.04) ; v3(112.28,70.32) 112.77,70.81 114.24,70.81 v3(114.55,71.12) 114.86,70.81 116.34,70.81 v3(116.83,70.32)
  L10-SIG3 w0.076: v3(114.55,71.12) 114.26,71.42 110.67,71.42 110.57,71.52 110.57,72.46 110.67,72.56 110.9,72.56 110.97,72.49 110.97,72.01 111.05,71.93 111.28,71.93 111.35,72.01 111.35,72.49 111.43,72.56 111.66,72.56 111.73,72.49 111.73,72.01 111.81,71.93 112.04,71.93 112.11,72.01 112.11,72.49 112.19,72.56 112.42,72.56 112.5,72.49 112.5,72.01 112.58,71.92 112.8,71.92 112.88,72.01 112.88,72.49 112.95,72.56 113.16,72.56 113.26,72.67 113.26,74.49 v3(112.93,74.82) 112.93,75.51 113.26,75.84 113.26,79.42 113.08,79.6 113.08,79.85 113.26,80.03 113.26,80.31 113.11,80.46 113.11,80.77 113.26,80.92 113.26,81.17 114.02,81.94 115.67,81.94 115.85,82.12 115.85,84.4 115.75,84.5 114.89,84.5 v3(114.55,84.84)
  L12-SIG4 w0.142: v2(92.9,75.93) 93.28,75.93 93.73,76.37 94.36,76.37 94.5,76.23 94.5,75.96 94.64,75.82 94.92,75.82 95.07,75.96 95.07,76.23 95.21,76.37 95.49,76.37 95.64,76.23 95.64,75.96 95.78,75.82 96.06,75.82 96.2,75.96 96.2,76.23 96.35,76.37 96.63,76.37 96.77,76.23 96.77,75.96 96.92,75.82 97.2,75.82 97.34,75.96 97.34,76.23 97.48,76.37 99.45,76.37 99.59,76.23 99.59,75.88 99.73,75.74 100.02,75.74 100.16,75.88 100.16,76.23 100.3,76.37 100.58,76.37 100.73,76.23 100.73,75.5 100.87,75.36 101.15,75.36 101.3,75.5 101.3,76.23 101.44,76.37 101.72,76.37 101.86,76.23 101.86,75.47 102.01,75.33 102.29,75.33 102.43,75.47 102.43,76.23 102.58,76.37 102.86,76.37 103,76.23 103,75.45 103.14,75.31 103.43,75.31 103.57,75.45 103.57,76.23 103.71,76.37 104.78,76.37 105.01,76.14 105.01,75.88 105.29,75.61 105.54,75.61 105.82,75.33 105.82,75.08 106.09,74.8 106.34,74.8 106.68,74.47 112.57,74.47 v3(112.93,74.82)
LPDDR4_A5_A: length 70.7
  TOP w0.152: U3.AD27 v2(90.9,72.93)
  L05-SIG2 w0.076: v3(112.93,84.04) 112.93,84.25 113.03,84.35 113.77,84.35 113.88,84.25 113.88,84.05 113.96,83.96 114.1,83.96 114.18,84.04 114.18,84.25 114.26,84.32 114.36,84.32 114.44,84.25 114.44,84.15 v3(114.55,84.04) 114.67,84.15 114.67,84.25 114.74,84.32 114.85,84.32 114.93,84.25 114.93,84.04 115,83.96 115.15,83.96 115.23,84.05 115.23,84.25 115.33,84.35 116.08,84.35 116.18,84.25 v3(116.18,84.04) ; v3(112.93,70.32) 112.93,70.53 113.03,70.63 113.77,70.63 113.88,70.53 113.88,70.33 113.96,70.25 114.1,70.25 114.18,70.32 114.18,70.53 114.26,70.61 114.36,70.61 114.44,70.53 114.44,70.44 v3(114.55,70.32) 114.67,70.44 114.67,70.53 114.74,70.61 114.85,70.61 114.93,70.53 114.93,70.32 115,70.25 115.15,70.25 115.23,70.33 115.23,70.53 115.33,70.63 116.08,70.63 116.18,70.53 v3(116.18,70.32)
  L10-SIG3 w0.076: v3(114.55,84.04) 115.11,84.04 115.19,83.96 115.19,82.22 115.11,82.14 113.84,82.14 112.78,81.07 112.78,80.69 112.66,80.58 112.36,80.58 112.28,80.5 112.28,80.35 112.36,80.27 112.76,80.27 112.83,80.2 112.83,80.04 112.76,79.97 112.34,79.97 112.27,79.89 112.27,79.74 112.34,79.66 112.66,79.66 112.78,79.55 112.78,78.91 112.59,78.73 112.59,75.94 112.28,75.62 v3(112.28,74.82) 112.93,74.18 112.93,73.1 112.78,72.94 110.58,72.94 110.24,72.6 109.68,72.6 109.6,72.52 109.6,72.29 109.68,72.22 110.16,72.22 110.24,72.14 110.24,71.91 110.16,71.84 109.66,71.84 109.59,71.76 109.59,71.53 109.66,71.46 109.91,71.46 109.98,71.38 109.98,70.79 110.06,70.7 114.17,70.7 v3(114.55,70.32)
  L12-SIG4 w0.142: v2(90.9,72.93) 90.9,73.14 91.19,73.43 92.33,73.43 92.43,73.53 92.43,74.33 92.29,74.47 91.62,74.47 91.41,74.67 91.41,75.24 91.27,75.38 90.47,75.38 90.35,75.51 90.35,76.33 90.52,76.5 90.99,76.5 91.27,76.22 91.54,76.22 91.82,76.5 92.07,76.5 92.35,76.22 92.56,76.22 92.84,76.5 93.27,76.5 93.52,76.75 99.31,76.75 99.54,76.98 99.75,76.98 99.98,76.75 100.32,76.75 100.55,76.98 100.89,76.98 101.12,76.75 101.46,76.75 101.68,76.98 102.02,76.98 102.25,76.75 102.59,76.75 102.82,76.98 103.16,76.98 103.39,76.75 103.73,76.75 103.96,76.98 104.3,76.98 104.53,76.75 104.98,76.75 105.35,77.12 105.68,77.12 105.89,76.91 105.89,76.46 105.72,76.29 105.72,76.09 105.92,75.89 106.13,75.89 106.29,76.05 106.49,76.05 106.83,75.71 106.83,75.51 106.65,75.33 106.65,75.13 106.85,74.93 107.06,74.93 107.24,75.11 107.44,75.11 107.72,74.82 v3(112.28,74.82)
LPDDR4_CKE_A: length 72.2
  TOP w0.127: U3.AB26 v2(89.9,74.93)
  L05-SIG2 w0.076: v3(116.18,78.44) 116.18,78.14 116.06,78.02 115.31,78.02 115.21,78.12 115.21,78.23 115.12,78.32 114.95,78.32 114.86,78.23 114.86,77.94 v3(114.55,77.64) 114.25,77.94 114.25,78.23 114.16,78.32 113.99,78.32 113.89,78.23 113.89,78.12 113.8,78.02 113.05,78.02 112.93,78.14 v3(112.93,78.44) ; v3(112.93,64.72) 112.93,64.43 113.05,64.31 113.8,64.31 113.89,64.4 113.89,64.51 113.99,64.6 114.16,64.6 114.25,64.51 114.25,64.23 v3(114.55,63.92) 114.86,64.23 114.86,64.51 114.95,64.6 115.12,64.6 115.21,64.51 115.21,64.4 115.31,64.31 116.06,64.31 116.18,64.43 v3(116.18,64.72)
  L10-SIG3 w0.076: v3(114.55,63.92) 114.17,64.3 114.17,64.97 114.33,65.12 118.31,65.12 118.47,65.27 118.47,66.75 118.11,67.1 117.65,67.1 117.15,67.6 v3(117.15,72.31) 117.63,72.79 118.84,72.79 119.13,73.07 119.13,73.28 119.2,73.36 119.52,73.36 119.6,73.44 119.6,73.66 119.52,73.74 119.2,73.74 119.13,73.82 119.13,74.05 119.2,74.12 119.53,74.12 119.61,74.2 119.61,74.43 119.53,74.5 119.2,74.5 119.13,74.58 119.13,74.81 119.2,74.88 119.53,74.88 119.61,74.96 119.61,75.19 119.53,75.26 119.2,75.26 119.13,75.34 119.13,77.14 119,77.26 114.93,77.26 v3(114.55,77.64)
  L12-SIG4 w0.142: v3(117.15,72.31) 116.77,72.69 116.36,72.69 116.15,72.49 116.15,71.62 116,71.47 114.88,71.47 114.74,71.61 114.74,72.17 114.6,72.31 114.32,72.31 114.17,72.17 114.17,71.61 114.03,71.47 107.87,71.47 107.44,71.04 106.91,71.04 106.66,71.29 106.34,71.29 106.09,71.04 105.77,71.04 105.52,71.29 105.21,71.29 104.95,71.04 104.64,71.04 104.38,71.29 104.07,71.29 103.81,71.04 99.69,71.04 99.26,71.47 90.63,71.47 90.42,71.67 90.42,72.08 89.94,72.56 89.94,73.35 90.42,73.83 90.42,74.41 v2(89.9,74.93)
LPDDR4_CLK_A_N: length 73.1
  TOP w0.099: U3.AC25 v2(88.9,73.93)
  L05-SIG2 w0.081: v3(112.93,68.72) 112.93,68.56 113.02,68.47 113.4,68.47 113.66,68.21 113.66,67.75 113.83,67.59 114.22,67.59 v3(114.55,67.92) 114.89,67.59 115.28,67.59 115.44,67.75 115.44,68.21 115.7,68.47 116.09,68.47 116.18,68.56 v3(116.18,68.72) ; v3(112.93,82.44) 112.93,82.28 113.02,82.19 113.4,82.19 113.66,81.93 113.66,81.46 113.83,81.3 114.22,81.3 v3(114.55,81.64) 114.89,81.3 115.28,81.3 115.44,81.46 115.44,81.93 115.7,82.19 116.09,82.19 116.18,82.28 v3(116.18,82.44)
  L10-SIG3 w0.081: v3(114.55,67.92) 114.48,67.85 114.48,67.62 114.56,67.54 114.68,67.54 114.94,67.8 114.94,71.89 114.85,71.97 114.12,71.97 113.92,72.18 113.92,73.63 114.12,73.83 114.82,73.83 115.02,73.63 115.02,73.14 115.1,73.05 115.43,73.05 115.51,73.14 115.51,74.22 115.43,74.3 114.18,74.3 113.92,74.56 113.92,75.1 v3(113.79,75.23) 113.92,75.36 113.92,78.86 114.12,79.07 116.12,79.07 116.21,79.15 116.21,80.94 116.07,81.07 115.78,81.07 115.65,80.94 115.65,79.91 115.45,79.7 114.12,79.7 113.92,79.91 113.92,81 v3(114.55,81.64)
  L12-SIG4 w0.122: v3(113.79,75.23) 113.53,75.49 113.29,75.49 113.17,75.37 112.9,75.37 112.78,75.49 112.37,75.49 112.24,75.36 112.04,75.36 111.91,75.49 108.11,75.49 107.56,76.04 107.56,76.76 107.44,76.88 106.89,76.88 106.52,77.26 106.52,77.67 106.16,78.03 105.61,78.03 105.3,77.72 104.8,77.72 104.49,78.02 104.14,78.02 103.83,77.72 103.32,77.72 103.04,78 102.64,78 102.36,77.72 101.73,77.72 101.48,77.97 101.48,78.31 101.36,78.44 101.11,78.44 100.99,78.31 100.99,77.97 100.74,77.72 100.31,77.72 100.06,77.97 100.06,78.31 99.94,78.44 99.69,78.44 99.57,78.31 99.57,77.81 99.08,77.33 97.95,77.33 97.69,77.58 97.69,78.06 97.57,78.18 97.28,78.18 97.16,78.06 97.16,77.58 96.9,77.33 92.7,77.33 92.53,77.16 92.28,77.16 92.11,77.33 91.72,77.33 91.55,77.16 91.29,77.16 91.12,77.33 90.68,77.33 90.51,77.16 90.25,77.16 90.08,77.33 89.7,77.33 89.51,77.14 89.51,76.73 89.66,76.58 89.66,76.29 89.51,76.15 89.51,75.79 89.66,75.64 89.66,75.36 89.51,75.21 89.51,74.57 89.26,74.32 89.02,74.32 88.9,74.2 v2(88.9,73.93)
  BOTTOM w0.137: R636.1 v3(114.55,81.64) ; R582.1 v3(114.55,67.92)
LPDDR4_CLK_A_P: length 72.9
  TOP w0.099: U3.AB25 v2(88.9,74.93)
  L05-SIG2 w0.081: v3(112.93,81.64) 112.93,81.78 113.12,81.98 113.32,81.98 113.46,81.84 113.46,81.38 113.74,81.09 114.3,81.09 v3(114.55,80.84) 114.81,81.09 115.37,81.09 115.65,81.38 115.65,81.84 115.79,81.98 116,81.98 116.18,81.8 v3(116.18,81.64) ; v3(112.93,67.92) 112.93,68.07 113.12,68.26 113.32,68.26 113.46,68.13 113.46,67.66 113.74,67.38 114.3,67.38 v3(114.55,67.12) 114.81,67.38 115.37,67.38 115.65,67.66 115.65,68.13 115.79,68.26 116,68.26 116.18,68.08 v3(116.18,67.92)
  L10-SIG3 w0.081: v3(114.55,80.84) 114.63,80.91 114.63,81.12 114.56,81.2 114.41,81.2 114.13,80.92 114.13,79.99 114.21,79.91 115.36,79.91 115.44,79.99 115.44,81.03 115.7,81.28 116.16,81.28 116.41,81.03 116.41,79.06 116.21,78.86 114.21,78.86 114.13,78.78 114.13,75.4 v3(114.3,75.23) 114.13,75.06 114.13,74.64 114.26,74.51 115.52,74.51 115.72,74.3 115.72,73.05 115.52,72.85 115.02,72.85 114.81,73.05 114.81,73.54 114.73,73.63 114.21,73.63 114.13,73.54 114.13,72.26 114.21,72.18 114.94,72.18 115.14,71.97 115.14,67.71 v3(114.55,67.12)
  L12-SIG4 w0.122: v2(88.9,74.93) 88.9,74.66 89.02,74.54 89.17,74.54 89.29,74.66 89.29,77.27 89.57,77.55 96.81,77.55 96.93,77.67 96.93,78.15 97.18,78.41 97.66,78.41 97.92,78.15 97.92,77.67 98.04,77.55 98.99,77.55 99.35,77.9 99.35,78.41 99.6,78.66 100.03,78.66 100.28,78.41 100.28,78.07 100.4,77.94 100.65,77.94 100.77,78.07 100.77,78.41 101.02,78.66 101.45,78.66 101.7,78.41 101.7,78.07 101.83,77.94 102.27,77.94 102.58,78.25 103.11,78.25 103.42,77.94 103.74,77.94 104.05,78.25 104.58,78.25 104.89,77.94 105.21,77.94 105.52,78.25 106.25,78.25 106.74,77.76 106.74,77.35 106.98,77.11 107.53,77.11 107.78,76.86 107.78,76.13 108.2,75.71 113.82,75.71 v3(114.3,75.23)
  BOTTOM w0.137: R582.2 v3(114.55,67.12) ; R636.2 v3(114.55,80.84)
LPDDR4_CS_A: length 63.5
  TOP w0.127: U3.AA31 v2(93.9,75.93)
  L05-SIG2 w0.076: v3(116.83,78.44) 116.43,78.84 114.95,78.84 v3(114.55,78.44) 114.15,78.84 112.68,78.84 v3(112.28,78.44) ; v3(116.83,64.72) 116.43,65.12 114.95,65.12 v3(114.55,64.72) 114.15,65.12 112.68,65.12 v3(112.28,64.72)
  L10-SIG3 w0.076: v3(114.55,64.72) 114.99,64.28 118.87,64.28 119.13,64.54 119.13,66.95 118.59,67.48 118.08,67.48 117.8,67.76 v3(117.8,72.31) 120.01,72.31 120.18,72.47 120.18,75.32 119.76,75.74 119.76,77.9 119.63,78.02 114.97,78.02 v3(114.55,78.44)
  L12-SIG4 w0.142: v3(117.8,72.31) 116.03,74.09 106.17,74.09 105.31,74.95 100.41,74.95 100,75.36 94.47,75.36 v2(93.9,75.93)
LPDDR4_DQ0_A: length 34.8
  TOP w0.127: U3.AD22 v2(85.9,72.93)
  L05-SIG2 w0.091: v3(108.38,76.84) 108.04,76.5 105.96,76.5 105.87,76.41 105.87,75.96 105.78,75.87 105.6,75.87 105.5,75.96 105.5,76.41 105.41,76.5 105.23,76.5 105.14,76.41 105.14,75.96 105.05,75.87 104.86,75.87 104.77,75.96 104.77,76.41 104.68,76.5 104.5,76.5 104.41,76.41 104.41,76.08 104.32,75.99 104.13,75.99 104.04,76.08 104.04,76.41 103.95,76.5 103.77,76.5 103.68,76.41 103.68,76.08 103.58,75.99 103.4,75.99 103.31,76.08 103.31,76.41 103.22,76.5 103.04,76.5 102.94,76.41 102.94,76.08 102.85,75.99 102.67,75.99 102.58,76.08 102.58,76.41 102.49,76.5 102.3,76.5 102.21,76.41 102.21,76.08 102.12,75.99 101.94,75.99 101.85,76.08 101.85,76.41 101.75,76.5 101.57,76.5 101.48,76.41 101.48,76.08 101.39,75.99 101.21,75.99 101.11,76.08 101.11,76.41 101.02,76.5 100.84,76.5 100.75,76.41 100.75,76.08 100.66,75.99 100.47,75.99 100.38,76.08 100.38,76.41 100.29,76.5 100.11,76.5 100.02,76.41 100.02,76.08 99.93,75.99 99.74,75.99 99.65,76.08 99.65,76.41 99.56,76.5 90.42,76.5 90.3,76.37 90.3,73.07 90.04,72.82 89.28,72.82 89.03,72.56 86.26,72.56 v2(85.9,72.93)
LPDDR4_DQ0_B: length 40.1
  TOP w0.127: U3.U29 v2(92.9,80.93)
  L03-SIG1 w0.091: v2(92.9,80.93) 93.42,81.45 98.3,81.45 99.69,82.85 102.88,82.85 102.97,82.76 102.97,82.56 103.06,82.47 103.25,82.47 103.34,82.56 103.34,82.76 103.43,82.85 103.61,82.85 103.7,82.76 103.7,82.56 103.8,82.47 103.98,82.47 104.07,82.56 104.07,82.76 104.16,82.85 104.34,82.85 104.44,82.76 104.44,82.56 104.53,82.47 104.71,82.47 104.8,82.56 104.8,82.76 104.89,82.85 105.08,82.85 105.17,82.76 105.17,82.56 105.26,82.47 105.44,82.47 105.53,82.56 105.53,82.76 105.62,82.85 105.81,82.85 105.9,82.76 105.9,82.56 105.99,82.47 106.17,82.47 106.26,82.56 106.26,82.76 106.36,82.85 106.54,82.85 106.63,82.76 106.63,82.56 106.72,82.47 106.91,82.47 107,82.56 107,82.76 107.09,82.85 121.54,82.85 121.69,82.7 121.69,77.42 121.11,76.84 v3(120.73,76.84)
LPDDR4_DQ0_C: length 42.2
  TOP w0.127: v2(91.9,79.93) U3.V28
  L10-SIG3 w0.091: v3(108.38,63.12) 107.91,62.66 101.98,62.66 101.85,62.78 101.85,62.99 101.55,63.29 99.45,63.29 99.35,63.2 99.35,62.88 99.26,62.78 99.08,62.78 98.99,62.88 98.99,63.2 98.9,63.29 98.71,63.29 98.62,63.2 98.62,62.88 98.53,62.78 98.35,62.78 98.26,62.88 98.26,63.2 98.16,63.29 94.36,63.29 93.34,64.31 92.94,64.31 92.46,64.79 92.46,65.07 92.07,65.45 91.69,65.45 91.31,65.83 91.31,66.21 91.06,66.47 90.55,66.47 90.3,66.72 90.3,67.23 90.04,67.48 89.79,67.48 89.41,67.86 89.41,68.12 89.15,68.37 88.77,68.37 88.39,68.75 88.39,69.13 88.14,69.39 87.76,69.39 87.25,69.9 87.25,78.81 87.86,79.42 88.09,79.42 88.98,80.31 91.52,80.31 v2(91.9,79.93)
LPDDR4_DQ0_D: length 34.2
  TOP w0.124: U3.AK32 v2(95.9,66.93)
  L12-SIG4 w0.091: v2(95.9,66.93) 96.39,67.42 96.39,68.02 96.67,68.3 101.85,68.3 103.07,67.08 103.25,67.08 103.34,67.17 103.34,67.37 103.43,67.46 103.62,67.46 103.71,67.37 103.71,67.17 103.8,67.08 103.98,67.08 104.07,67.17 104.07,67.37 104.16,67.46 104.35,67.46 104.44,67.37 104.44,67.17 104.53,67.08 104.71,67.08 104.8,67.17 104.8,67.37 104.9,67.46 113.41,67.46 114.27,68.32 120.83,68.32 121.03,68.12 121.03,63.42 v3(120.73,63.12)
LPDDR4_DQ1_A: length 34.9
  TOP w0.127: U3.AD21 v2(84.9,72.93)
  L05-SIG2 w0.091: v2(84.9,72.93) 85.52,72.31 89.15,72.31 89.41,72.56 90.42,72.56 90.55,72.69 90.55,75.23 90.81,75.48 97.31,75.48 97.41,75.39 97.41,75.2 97.5,75.1 97.68,75.1 97.77,75.2 97.77,75.39 97.86,75.48 98.05,75.48 98.14,75.39 98.14,75.2 98.23,75.1 98.41,75.1 98.5,75.2 98.5,75.39 98.59,75.48 99.57,75.48 99.66,75.39 99.66,75.17 99.75,75.08 99.93,75.08 100.02,75.17 100.02,75.39 100.12,75.48 100.3,75.48 100.39,75.39 100.39,75.2 100.48,75.1 100.67,75.1 100.76,75.2 100.76,75.39 100.85,75.48 106.18,75.48 106.27,75.58 106.27,76.03 106.36,76.12 106.54,76.12 106.63,76.03 106.63,75.58 106.73,75.48 106.91,75.48 107,75.58 107,76.03 107.09,76.12 107.27,76.12 107.37,76.03 107.37,75.58 107.46,75.48 107.64,75.48 107.73,75.58 107.73,76.03 107.82,76.12 108.01,76.12 108.1,76.03 108.1,75.58 108.19,75.48 108.97,75.48 109.35,75.87 109.35,76.52 v3(109.03,76.84)
LPDDR4_DQ1_B: length 40.2
  TOP w0.127: U3.V29 v2(92.9,79.93)
  L03-SIG1 w0.091: v3(120.08,76.84) 120.5,77.26 120.9,77.26 121.08,77.44 121.08,80.74 120.99,80.84 120.11,80.84 120.01,80.93 120.01,81.11 120.11,81.2 120.99,81.2 121.08,81.29 121.08,81.78 120.78,82.09 115.66,82.09 115.57,82 115.57,81.62 115.48,81.53 115.25,81.53 115.16,81.62 115.16,82 115.07,82.09 113.89,82.09 113.8,82 113.8,81.67 113.71,81.58 113.53,81.58 113.44,81.67 113.44,82 113.35,82.09 105.58,82.09 105.48,82 105.48,81.8 105.39,81.71 105.21,81.71 105.12,81.8 105.12,82 105.03,82.09 104.84,82.09 104.75,82 104.75,81.8 104.66,81.71 104.48,81.71 104.39,81.8 104.39,82 104.3,82.09 99.57,82.09 98.55,81.07 95.76,81.07 94.62,79.93 v2(92.9,79.93)
LPDDR4_DQ1_C: length 42.2
  TOP w0.127: U3.U28 v2(91.9,80.93)
  L10-SIG3 w0.091: v3(109.03,63.12) 108.21,62.3 94.03,62.3 86.49,69.85 86.49,79.17 86.87,79.55 87.1,79.55 87.38,79.83 87.38,79.93 88.01,80.56 91.53,80.56 v2(91.9,80.93)
LPDDR4_DQ1_D: length 34
  TOP w0.124: U3.AK31 v2(94.9,66.93)
  L12-SIG4 w0.091: v3(120.08,63.12) 120.4,63.44 120.4,64.18 120.27,64.31 106.57,64.31 106.48,64.4 106.48,64.75 106.39,64.84 106.2,64.84 106.11,64.75 106.11,64.4 106.02,64.31 105.84,64.31 105.75,64.4 105.75,64.75 105.66,64.84 105.47,64.84 105.38,64.75 105.38,64.4 105.29,64.31 105.11,64.31 105.02,64.4 105.02,64.75 104.92,64.84 104.74,64.84 104.65,64.75 104.65,64.4 104.56,64.31 104.38,64.31 104.28,64.4 104.28,64.75 104.19,64.84 104.01,64.84 103.92,64.75 103.92,64.4 103.83,64.31 103.64,64.31 103.55,64.4 103.55,64.75 103.46,64.84 103.28,64.84 103.19,64.75 103.19,64.4 103.1,64.31 98.02,64.31 95.47,66.86 95.47,67.45 95.38,67.53 94.96,67.53 94.9,67.47 v2(94.9,66.93)
LPDDR4_DQ2_A: length 31.4
  TOP w0.127: U3.AE25 v2(88.9,71.93)
  L05-SIG2 w0.091: v3(110.33,76.84) 109.98,76.49 109.98,75.61 109.73,75.36 109.35,75.36 109.09,75.1 109.09,74.72 108.97,74.6 107.42,74.6 107.32,74.69 106.96,74.69 106.87,74.6 106.68,74.6 106.59,74.69 106.59,75.01 106.5,75.1 106.32,75.1 106.23,75.01 106.23,74.69 106.14,74.6 105.95,74.6 105.86,74.69 105.86,75.01 105.77,75.1 105.59,75.1 105.5,75.01 105.5,74.69 105.4,74.6 105.22,74.6 105.13,74.69 105.13,75.01 105.04,75.1 104.86,75.1 104.76,75.01 104.76,74.69 104.67,74.6 104.49,74.6 104.4,74.69 104.4,75.01 104.31,75.1 104.12,75.1 104.03,75.01 104.03,74.69 103.94,74.6 103.76,74.6 103.67,74.69 103.67,75.01 103.57,75.1 103.39,75.1 103.3,75.01 103.3,74.69 103.21,74.6 103.03,74.6 102.93,74.69 102.93,75.01 102.84,75.1 102.66,75.1 102.57,75.01 102.57,74.69 102.48,74.6 102.29,74.6 102.2,74.69 102.2,75.01 102.11,75.1 101.93,75.1 101.84,75.01 101.84,74.69 101.75,74.6 99.44,74.6 99.19,74.34 91.57,74.34 91.31,74.09 91.31,72.69 90.93,72.31 89.53,72.31 89.16,71.93 v2(88.9,71.93)
LPDDR4_DQ2_B: length 37.7
  TOP w0.127: U3.U30 v2(93.9,80.93)
  L03-SIG1 w0.091: v3(118.78,76.84) 118.44,76.5 118.44,75.83 118.22,75.61 109.73,75.61 108.59,74.47 91.82,74.47 91.26,75.03 91.26,79.8 92.02,80.56 93.53,80.56 v2(93.9,80.93)
LPDDR4_DQ2_C: length 44.2
  TOP w0.127: U3.W26 v2(89.9,77.93)
  L10-SIG3 w0.091: v3(110.33,63.12) 110.33,63.13 110.74,63.55 111.02,63.55 111.3,63.83 111.3,66.8 111,67.1 107.7,67.1 106.93,67.86 106.93,70.28 106.74,70.47 106.38,70.47 106.29,70.56 106.29,71.08 106.2,71.17 106.02,71.17 105.93,71.08 105.93,70.56 105.84,70.47 105.65,70.47 105.56,70.56 105.56,71.08 105.47,71.17 105.29,71.17 105.2,71.08 105.2,70.56 105.1,70.47 104.92,70.47 104.83,70.56 104.83,71.15 104.74,71.24 104.56,71.24 104.46,71.15 104.46,70.56 104.37,70.47 104.19,70.47 104.1,70.56 104.1,71.2 104.01,71.29 103.82,71.29 103.73,71.2 103.73,70.56 103.64,70.47 103.46,70.47 103.37,70.56 103.37,71.2 103.28,71.29 103.09,71.29 103,71.2 103,70.56 102.91,70.47 102.73,70.47 102.64,70.56 102.64,71.23 102.54,71.32 102.36,71.32 102.27,71.23 102.27,70.56 102.18,70.47 102,70.47 101.9,70.56 101.9,71.2 101.81,71.29 101.63,71.29 101.54,71.2 101.54,70.56 101.45,70.47 94.74,70.47 94.36,70.85 94.36,71.04 93.24,72.16 93.24,75.21 92.96,75.48 92.84,75.48 92.46,75.87 92.46,76.12 92.07,76.5 91.57,76.5 91.31,76.75 91.31,77.26 91.06,77.52 90.31,77.52 v2(89.9,77.93)
LPDDR4_DQ2_D: length 35.1
  TOP w0.124: U3.AJ32 v2(94.9,67.93)
  L12-SIG4 w0.091: v2(94.9,67.93) 94.53,68.3 93.22,68.3 92.25,67.33 92.25,65.66 92.58,65.32 94.11,65.32 94.62,64.82 94.62,64.16 96.9,61.87 118.36,61.87 118.47,61.97 118.47,62.81 v3(118.78,63.12)
LPDDR4_DQ3_A: length 31.7
  TOP w0.127: U3.AE24 v2(87.9,71.93)
  L05-SIG2 w0.091: v3(110.98,76.84) 110.64,76.5 110.64,74.31 110.55,74.21 102.97,74.21 102.88,74.12 102.88,73.93 102.79,73.83 102.61,73.83 102.52,73.93 102.52,74.12 102.42,74.21 102.24,74.21 102.15,74.12 102.15,73.67 102.06,73.58 101.88,73.58 101.78,73.67 101.78,74.12 101.69,74.21 101.51,74.21 101.42,74.12 101.42,73.67 101.33,73.58 101.14,73.58 101.05,73.67 101.05,74.12 100.96,74.21 100.78,74.21 100.69,74.12 100.69,73.54 100.6,73.45 100.41,73.45 100.32,73.54 100.32,74.12 100.23,74.21 99.82,74.21 99.06,73.45 93.34,73.45 92.46,72.56 91.69,72.56 91.44,72.31 91.44,71.8 91.19,71.55 88.26,71.55 87.9,71.91 v2(87.9,71.93)
LPDDR4_DQ3_B: length 37.9
  TOP w0.127: U3.U31 v2(94.9,80.93)
  L03-SIG1 w0.091: v2(94.9,80.93) 94.28,80.31 92.71,80.31 92.33,79.93 92.33,79.42 91.57,78.66 91.57,75.61 91.82,75.36 101.91,75.36 102,75.27 102,74.94 102.09,74.85 102.27,74.85 102.37,74.94 102.37,75.27 102.46,75.36 102.64,75.36 102.73,75.27 102.73,74.94 102.82,74.85 103.01,74.85 103.1,74.94 103.1,75.27 103.19,75.36 103.37,75.36 103.46,75.27 103.46,74.99 103.55,74.9 103.79,74.9 103.89,74.99 103.89,75.27 103.98,75.36 107.7,75.36 108.81,76.48 117.77,76.48 v3(118.13,76.84)
LPDDR4_DQ3_C: length 44.5
  TOP w0.127: U3.V26 v2(89.9,78.93)
  L10-SIG3 w0.091: v3(110.98,63.12) 111.4,63.55 111.85,63.55 111.94,63.64 111.94,66.93 111.38,67.48 108.08,67.48 107.31,68.25 107.31,71.29 106.93,71.67 106.48,71.67 106.39,71.77 106.39,72.27 106.3,72.36 106.11,72.36 106.02,72.27 106.02,71.77 105.93,71.67 105.75,71.67 105.66,71.77 105.66,72.27 105.56,72.36 105.38,72.36 105.29,72.27 105.29,71.77 105.2,71.67 105.02,71.67 104.92,71.77 104.92,72.29 104.83,72.39 104.65,72.39 104.56,72.29 104.56,71.77 104.47,71.67 104.28,71.67 104.19,71.77 104.19,72.29 104.1,72.39 103.92,72.39 103.83,72.29 103.83,71.77 103.74,71.67 103.55,71.67 103.46,71.77 103.46,72.27 103.37,72.36 103.19,72.36 103.1,72.27 103.1,71.77 103,71.67 102.82,71.67 102.73,71.77 102.73,72.27 102.64,72.36 102.46,72.36 102.36,72.27 102.36,71.77 102.27,71.67 101.09,71.67 100.33,70.91 96.65,70.91 96.14,71.42 94.49,71.42 93.47,72.44 93.47,75.87 92.96,76.37 92.71,76.37 92.46,76.63 92.46,78.02 91.95,78.53 90.3,78.53 v2(89.9,78.93)
LPDDR4_DQ3_D: length 35
  TOP w0.124: U3.AJ31 v2(93.9,67.93)
  L12-SIG4 w0.091: v3(118.13,63.12) 118.13,62.83 118.03,62.73 115.42,62.73 115.21,62.53 114.91,62.53 114.71,62.73 114.4,62.73 114.2,62.53 113.89,62.53 113.69,62.73 108.6,62.73 108.51,62.64 108.51,62.37 108.42,62.28 100.79,62.28 100.56,62.51 100.23,62.51 100,62.28 99.82,62.28 99.62,62.48 99.44,62.48 99.24,62.28 97.79,62.28 97.7,62.37 97.7,62.59 97.61,62.68 97.42,62.68 97.33,62.59 97.33,62.37 97.24,62.28 96.98,62.28 96.13,63.13 96.13,63.26 96.35,63.48 96.35,63.61 96.22,63.74 96.09,63.74 95.87,63.52 95.74,63.52 95.61,63.65 95.61,63.78 95.83,64 95.83,64.13 95.71,64.26 95.58,64.26 95.35,64.03 95.22,64.03 95,64.26 95,64.82 94.23,65.58 92.69,65.58 92.51,65.76 92.51,67.2 92.76,67.46 93.81,67.46 93.9,67.55 v2(93.9,67.93)
LPDDR4_DQ4_A: length 33.8
  TOP w0.127: U3.AA21 v2(84.9,75.93)
  L05-SIG2 w0.091: v3(110.98,78.44) 110.67,78.75 110.67,79.5 109.35,80.82 106.55,80.82 105.03,82.34 88.77,82.34 88.39,81.96 88.39,81.58 88.14,81.33 87.76,81.33 86.49,80.06 86.49,79.68 86.23,79.42 85.85,79.42 85.47,79.04 85.47,78.02 84.46,77.01 84.46,76.37 v2(84.9,75.93)
LPDDR4_DQ4_B: length 44.4
  TOP w0.127: U3.Y28 v2(91.9,76.93)
  L03-SIG1 w0.091: v3(118.13,78.44) 117.75,78.81 116.12,78.81 116.03,78.9 116.03,79.2 115.93,79.29 115.75,79.29 115.66,79.2 115.66,78.9 115.57,78.81 115.39,78.81 115.29,78.9 115.29,79.2 115.2,79.29 115.02,79.29 114.93,79.2 114.93,78.9 114.84,78.81 114.65,78.81 114.56,78.9 114.56,79.2 114.47,79.29 114.29,79.29 114.2,79.2 114.2,78.9 114.11,78.81 113.92,78.81 113.83,78.9 113.83,79.2 113.74,79.29 113.56,79.29 113.47,79.2 113.47,78.9 113.37,78.81 113.19,78.81 113.1,78.9 113.1,79.2 113.01,79.29 112.83,79.29 112.73,79.2 112.73,78.9 112.64,78.81 107.54,78.81 107.19,79.17 105.76,79.17 105.66,79.08 105.66,78.5 105.57,78.41 105.33,78.41 105.24,78.5 105.24,79.79 105.15,79.88 104.97,79.88 104.88,79.79 104.88,78.5 104.79,78.41 104.6,78.41 104.51,78.5 104.51,79.71 104.42,79.8 104.24,79.8 104.15,79.71 104.15,78.5 104.05,78.41 103.87,78.41 103.78,78.5 103.78,79.71 103.69,79.8 103.51,79.8 103.41,79.71 103.41,78.5 103.32,78.41 103.14,78.41 103.05,78.5 103.05,79.08 102.96,79.17 102.77,79.17 102.68,79.08 102.68,78.5 102.59,78.41 102.41,78.41 102.32,78.5 102.32,79.08 102.23,79.17 102.04,79.17 101.95,79.08 101.95,78.5 101.86,78.41 101.68,78.41 101.59,78.5 101.59,79.08 101.49,79.17 96.77,79.17 96.16,78.56 92.48,78.56 92.25,78.33 92.25,77.28 v2(91.9,76.93)
LPDDR4_DQ4_C: length 46.1
  TOP w0.127: U3.AA27 v2(90.9,75.93)
  L10-SIG3 w0.091: v3(110.98,64.72) 110.67,65.03 110.67,66.52 110.46,66.72 107.31,66.72 106.55,67.48 106.55,68.34 106.46,68.43 105.37,68.43 105.28,68.53 105.28,68.71 105.37,68.8 106.46,68.8 106.55,68.89 106.55,69.13 106.43,69.26 105.85,69.26 105.75,69.35 105.75,69.52 105.88,69.64 106.38,69.64 106.5,69.77 106.5,70.03 106.38,70.15 105.48,70.15 105.39,70.06 105.39,69.35 105.3,69.26 105.11,69.26 105.02,69.35 105.02,70.06 104.93,70.15 104.75,70.15 104.66,70.06 104.66,69.35 104.57,69.26 104.38,69.26 104.29,69.35 104.29,70.06 104.2,70.15 104.02,70.15 103.93,70.06 103.93,69.61 103.83,69.52 103.65,69.52 103.56,69.61 103.56,69.93 103.47,70.02 103.29,70.02 103.19,69.93 103.19,69.61 103.1,69.52 102.92,69.52 102.83,69.61 102.83,69.93 102.74,70.02 102.55,70.02 102.46,69.93 102.46,69.61 102.37,69.52 102.19,69.52 102.1,69.61 102.1,69.93 102.01,70.02 101.82,70.02 101.73,69.93 101.73,69.61 101.64,69.52 101.46,69.52 101.37,69.61 101.37,69.93 101.27,70.02 101.09,70.02 101,69.93 101,69.61 100.91,69.52 100.73,69.52 100.63,69.61 100.63,69.93 100.54,70.02 100.36,70.02 100.27,69.93 100.27,69.61 100.18,69.52 99.99,69.52 99.9,69.61 99.9,69.93 99.81,70.02 99.63,70.02 99.54,69.93 99.54,69.61 99.45,69.52 97.46,69.52 97.37,69.42 97.37,69 97.28,68.91 97.1,68.91 97.01,69 97.01,69.42 96.91,69.52 96.73,69.52 96.64,69.42 96.64,69 96.55,68.91 96.37,68.91 96.27,69 96.27,69.42 96.18,69.52 95.68,69.52 95.59,69.42 95.59,69.2 95.49,69.11 95.31,69.11 95.22,69.2 95.22,69.42 95.13,69.52 94.74,69.52 94.49,69.77 94.49,70.15 94.23,70.4 93.73,70.4 93.47,70.66 93.47,71.29 92.33,72.44 92.33,73.1 92.42,73.19 92.64,73.19 92.74,73.29 92.74,73.47 92.64,73.56 92.42,73.56 92.33,73.65 92.33,73.83 92.42,73.93 92.64,73.93 92.74,74.02 92.74,74.2 92.64,74.29 92.42,74.29 92.33,74.38 92.33,75.23 92.07,75.48 91.69,75.48 91.25,75.93 v2(90.9,75.93)
LPDDR4_DQ4_D: length 31.5
  TOP w0.124: U3.AK34 v2(97.9,66.93)
  L12-SIG4 w0.091: v3(118.13,64.72) 117.81,65.05 114.91,65.05 114.82,65.14 114.82,65.54 114.73,65.63 114.55,65.63 114.46,65.54 114.46,65.21 114.37,65.12 114.18,65.12 114.09,65.21 114.09,65.54 114,65.63 113.82,65.63 113.73,65.54 113.73,65.27 113.62,65.17 102.84,65.17 102.75,65.08 102.75,64.71 102.66,64.61 102.48,64.61 102.38,64.71 102.38,65.08 102.29,65.17 102.11,65.17 102.02,65.08 102.02,64.71 101.93,64.61 101.74,64.61 101.65,64.71 101.65,65.08 101.56,65.17 101.38,65.17 101.29,65.08 101.29,64.71 101.19,64.61 101.01,64.61 100.92,64.71 100.92,65.08 100.83,65.17 100.65,65.17 100.55,65.08 100.55,64.71 100.46,64.61 100.28,64.61 100.19,64.71 100.19,65.08 100.1,65.17 99.91,65.17 99.82,65.08 99.82,64.71 99.73,64.61 99.55,64.61 99.46,64.71 99.46,65.08 99.37,65.17 99.18,65.17 99.09,65.08 99.09,64.71 99,64.61 98.82,64.61 98.73,64.71 98.73,65.08 98.63,65.17 97.64,65.17 96.74,66.07 96.74,66.4 96.88,66.54 97.81,66.54 97.9,66.64 v2(97.9,66.93)
LPDDR4_DQ5_A: length 33.6
  TOP w0.127: U3.Y21 v2(84.9,76.93)
  L05-SIG2 w0.091: v3(110.33,78.44) 109.98,78.78 109.98,79.55 109.22,80.31 106.17,80.31 105.03,81.45 103.95,81.45 103.86,81.36 103.86,81.29 103.77,81.2 103.58,81.2 103.49,81.29 103.49,81.36 103.4,81.45 103.22,81.45 103.13,81.36 103.13,81.16 103.03,81.07 102.85,81.07 102.76,81.16 102.76,81.36 102.67,81.45 102.49,81.45 102.39,81.36 102.39,81.04 102.3,80.95 102.12,80.95 102.03,81.04 102.03,81.36 101.94,81.45 101.75,81.45 101.66,81.36 101.66,81.04 101.57,80.95 101.39,80.95 101.3,81.04 101.3,81.36 101.21,81.45 101.02,81.45 100.93,81.36 100.93,81.04 100.84,80.95 100.66,80.95 100.56,81.04 100.56,81.36 100.47,81.45 89.66,81.45 89.41,81.2 89.41,80.82 88.9,80.31 87.76,80.31 86.96,79.51 86.83,79.51 86.36,79.04 86.36,78.39 v2(84.9,76.93)
LPDDR4_DQ5_B: length 44.3
  TOP w0.127: U3.AA28 v2(91.9,75.93)
  L03-SIG1 w0.091: v3(118.78,78.44) 118.37,78.02 115.33,78.02 115.24,78.12 115.24,78.31 115.15,78.41 114.97,78.41 114.88,78.31 114.88,78.12 114.78,78.02 114.37,78.02 114.27,78.12 114.27,78.31 114.18,78.41 114,78.41 113.91,78.31 113.91,78.12 113.82,78.02 107.36,78.02 107.23,77.9 107.03,77.9 106.93,77.99 106.93,78.7 106.84,78.79 106.66,78.79 106.57,78.7 106.57,77.99 106.48,77.9 105.53,77.9 105.4,78.02 105.16,78.02 105.04,77.9 104.8,77.9 104.67,78.02 104.43,78.02 104.31,77.9 104.07,77.9 103.94,78.02 103.7,78.02 103.57,77.9 103.34,77.9 103.21,78.02 102.97,78.02 102.84,77.9 102.6,77.9 102.48,78.02 102.24,78.02 102.11,77.9 101.87,77.9 101.75,78.02 101.18,78.02 101.09,78.12 101.09,78.7 101,78.79 100.81,78.79 100.72,78.7 100.72,77.86 100.63,77.77 100.45,77.77 100.36,77.86 100.36,78.7 100.26,78.79 100.08,78.79 99.99,78.7 99.99,77.86 99.9,77.77 99.72,77.77 99.62,77.86 99.62,78.7 99.53,78.79 99.35,78.79 99.26,78.7 99.26,77.86 99.17,77.77 98.98,77.77 98.89,77.86 98.89,78.7 98.8,78.79 98.62,78.79 98.53,78.7 98.53,77.86 98.44,77.77 98.25,77.77 98.16,77.86 98.16,78.7 98.07,78.79 97.89,78.79 97.8,78.7 97.8,77.86 97.7,77.77 97.52,77.77 97.43,77.86 97.43,78.7 97.34,78.79 97.16,78.79 97.06,78.7 97.06,77.86 96.97,77.77 96.79,77.77 96.7,77.86 96.7,78.19 96.61,78.28 92.6,78.28 92.51,78.19 92.51,76.04 92.39,75.93 v2(91.9,75.93)
LPDDR4_DQ5_C: length 46.5
  TOP w0.127: U3.Y27 v2(90.9,76.93)
  L10-SIG3 w0.091: v2(90.9,76.93) 90.52,76.93 90.42,76.84 90.42,75.87 90.81,75.48 91.14,75.48 91.31,75.31 91.31,71.8 91.69,71.42 92.2,71.42 92.46,71.17 92.46,70.79 92.84,70.4 93.09,70.4 93.34,70.15 93.34,69.77 93.6,69.52 94.11,69.52 94.36,69.26 94.36,68.88 94.74,68.5 95.28,68.5 95.37,68.41 95.37,68.24 95.46,68.14 95.64,68.14 95.74,68.24 95.74,68.41 95.83,68.5 96.01,68.5 96.1,68.41 96.1,68.24 96.19,68.14 96.38,68.14 96.47,68.24 96.47,68.41 96.56,68.5 97.1,68.5 97.25,68.35 97.46,68.35 97.62,68.5 98.78,68.5 98.88,68.59 98.88,69.04 98.97,69.13 99.15,69.13 99.24,69.04 99.24,68.59 99.33,68.5 99.52,68.5 99.61,68.59 99.61,69.04 99.7,69.13 99.88,69.13 99.97,69.04 99.97,68.59 100.06,68.5 100.25,68.5 100.34,68.59 100.34,69.04 100.43,69.13 100.61,69.13 100.7,69.04 100.7,68.59 100.8,68.5 100.98,68.5 101.07,68.59 101.07,69.04 101.16,69.13 101.34,69.13 101.44,69.04 101.44,68.59 101.53,68.5 101.71,68.5 101.8,68.59 101.8,69.04 101.89,69.13 102.08,69.13 102.17,69.04 102.17,68.59 102.26,68.5 102.44,68.5 102.53,68.59 102.53,69.04 102.62,69.13 102.81,69.13 102.9,69.04 102.9,68.59 102.99,68.5 103.17,68.5 103.26,68.59 103.26,69.04 103.36,69.13 103.54,69.13 103.63,69.04 103.63,68.59 103.72,68.5 103.89,68.5 103.97,68.59 103.97,68.84 104.07,68.93 104.79,68.93 104.9,68.81 104.9,68.66 104.81,68.56 104.59,68.56 104.5,68.47 104.5,68.29 104.59,68.2 104.81,68.2 104.9,68.11 104.9,67.91 104.56,67.57 104.56,67.44 104.69,67.31 104.82,67.31 105.61,68.1 105.74,68.1 105.86,67.97 105.86,67.84 105.08,67.05 105.08,66.93 105.21,66.8 105.34,66.8 105.97,67.43 106.1,67.43 106.23,67.3 106.23,67.17 105.6,66.54 105.6,66.41 105.73,66.28 105.86,66.28 106.43,66.85 106.68,66.85 107.19,66.34 110.21,66.34 110.29,66.26 110.29,65.99 110.21,65.91 110.06,65.91 109.98,65.83 109.98,64.81 110.07,64.72 v3(110.33,64.72)
LPDDR4_DQ5_D: length 31.7
  TOP w0.124: U3.AK33 v2(96.9,66.93)
  L12-SIG4 w0.091: v3(118.78,64.72) 119.1,65.04 119.1,65.76 118.9,65.96 105.41,65.96 105.21,65.76 104.93,65.76 104.72,65.96 104.5,65.96 104.29,65.75 104.03,65.75 103.82,65.96 103.64,65.96 103.54,65.87 103.54,65.62 103.45,65.53 103.27,65.53 103.18,65.62 103.18,65.87 103.09,65.96 102.9,65.96 102.81,65.87 102.81,65.62 102.72,65.53 102.54,65.53 102.45,65.62 102.45,65.87 102.36,65.96 102.17,65.96 102.08,65.87 102.08,65.62 101.99,65.53 101.81,65.53 101.72,65.62 101.72,65.87 101.62,65.96 101.44,65.96 101.35,65.87 101.35,65.62 101.26,65.53 101.08,65.53 100.98,65.62 100.98,65.87 100.89,65.96 100.71,65.96 100.62,65.87 100.62,65.62 100.53,65.53 100.21,65.53 100.12,65.62 100.12,65.87 100.03,65.96 99.84,65.96 99.75,65.87 99.75,65.62 99.66,65.53 99.48,65.53 99.39,65.62 99.39,66.02 99.29,66.11 99.11,66.11 99.02,66.02 99.02,65.62 98.93,65.53 97.86,65.53 97.77,65.62 97.77,65.89 98.32,66.44 98.32,67.2 98.2,67.33 97.3,67.33 v2(96.9,66.93)
LPDDR4_DQ6_A: length 33.4
  TOP w0.127: U3.AB24 v2(87.9,75.93)
  L05-SIG2 w0.091: v2(87.9,75.93) 87.38,76.45 87.38,78.15 87.63,78.41 88.01,78.41 88.26,78.66 88.26,79.04 88.65,79.42 93.85,79.42 94.36,79.93 96.71,79.93 96.8,79.84 96.8,79.51 96.89,79.42 97.07,79.42 97.16,79.51 97.16,79.84 97.25,79.93 97.44,79.93 97.53,79.84 97.53,79.51 97.62,79.42 97.8,79.42 97.89,79.51 97.89,79.84 97.99,79.93 98.17,79.93 98.26,79.84 98.26,79.51 98.35,79.42 98.53,79.42 98.63,79.51 98.63,79.84 98.72,79.93 98.9,79.93 98.99,79.84 98.99,79.51 99.08,79.42 99.27,79.42 99.36,79.51 99.36,79.84 99.45,79.93 99.63,79.93 99.72,79.84 99.72,79.51 99.82,79.42 100,79.42 100.09,79.51 100.09,79.84 100.18,79.93 100.36,79.93 100.46,79.84 100.46,79.51 100.55,79.42 100.73,79.42 100.82,79.51 100.82,79.84 100.91,79.93 101.1,79.93 101.19,79.84 101.19,79.51 101.28,79.42 101.46,79.42 101.55,79.51 101.55,79.84 101.64,79.93 101.83,79.93 101.92,79.84 101.92,79.51 102.01,79.42 102.19,79.42 102.28,79.51 102.28,79.76 102.38,79.85 102.56,79.85 102.65,79.76 102.65,79.51 102.74,79.42 102.92,79.42 103.02,79.51 103.02,79.71 103.11,79.8 103.29,79.8 103.38,79.71 103.38,79.51 103.47,79.42 106.17,79.42 106.81,78.79 108.68,78.79 v3(109.03,78.44)
LPDDR4_DQ6_B: length 39.8
  TOP w0.127: U3.V30 93.4,79.43 v2(93.9,78.93)
  L03-SIG1 w0.091: v2(93.9,78.93) 93.9,78.93 94.89,78.93 95.88,79.93 98.81,79.93 99.57,80.69 99.95,80.69 100.04,80.78 100.04,81.24 100.14,81.33 100.32,81.33 100.41,81.24 100.41,80.78 100.5,80.69 100.68,80.69 100.78,80.78 100.78,81.24 100.87,81.33 101.05,81.33 101.14,81.24 101.14,80.78 101.23,80.69 101.42,80.69 101.51,80.78 101.51,81.24 101.6,81.33 101.78,81.33 101.87,81.24 101.87,80.78 101.96,80.69 102.15,80.69 102.24,80.78 102.24,81.24 102.33,81.33 102.51,81.33 102.6,81.24 102.6,80.78 102.7,80.69 109.38,80.69 109.47,80.6 109.47,80.02 109.57,79.93 109.75,79.93 109.84,80.02 109.84,80.6 109.93,80.69 110.11,80.69 110.21,80.6 110.21,80.02 110.3,79.93 110.48,79.93 110.57,80.02 110.57,80.6 110.66,80.69 110.85,80.69 110.94,80.6 110.94,80.02 111.03,79.93 111.21,79.93 111.3,80.02 111.3,80.6 111.39,80.69 111.58,80.69 111.67,80.6 111.67,80.02 111.76,79.93 111.94,79.93 112.03,80.02 112.03,80.6 112.13,80.69 112.31,80.69 112.4,80.6 112.4,80.02 112.49,79.93 112.67,79.93 112.77,80.02 112.77,80.6 112.86,80.69 113.16,80.69 113.92,79.93 119.38,79.93 119.76,79.55 119.76,79.04 120.08,78.72 v3(120.08,78.44)
LPDDR4_DQ6_C: length 46
  TOP w0.127: U3.AA26 v2(89.9,75.93)
  L10-SIG3 w0.091: v2(89.9,75.93) 90.3,75.53 90.3,71.93 90.81,71.42 91.06,71.42 91.44,71.04 91.44,70.79 91.82,70.4 92.33,70.4 92.46,70.28 92.46,69.77 92.84,69.39 93.09,69.39 93.34,69.13 93.34,68.75 93.6,68.5 94.11,68.5 94.49,68.12 94.49,67.74 94.87,67.36 95.21,67.36 95.3,67.45 95.3,67.75 95.39,67.84 95.58,67.84 95.67,67.75 95.67,67.45 95.76,67.36 95.94,67.36 96.03,67.45 96.03,67.75 96.12,67.84 96.31,67.84 96.4,67.75 96.4,67.45 96.49,67.36 97.08,67.36 97.17,67.45 97.17,67.65 97.26,67.74 97.44,67.74 97.54,67.65 97.54,67.45 97.63,67.36 98.17,67.36 98.55,66.98 98.71,66.98 98.81,67.07 98.81,68.05 98.9,68.14 99.1,68.14 99.19,68.05 99.19,67.07 99.28,66.98 99.48,66.98 99.57,67.07 99.57,68.05 99.66,68.14 99.86,68.14 99.95,68.05 99.95,67.07 100.04,66.98 100.4,66.98 100.49,67.07 100.49,67.52 100.58,67.61 100.76,67.61 100.86,67.52 100.86,67.07 100.95,66.98 101.13,66.98 101.22,67.07 101.22,68.05 101.31,68.14 101.5,68.14 101.59,68.05 101.59,67.07 101.68,66.98 101.86,66.98 101.95,67.07 101.95,68.05 102.04,68.14 102.23,68.14 102.32,68.05 102.32,67.07 102.41,66.98 102.59,66.98 102.68,67.07 102.68,68.05 102.78,68.14 102.96,68.14 103.05,68.05 103.05,67.07 103.14,66.98 103.32,66.98 103.42,67.07 103.42,68.03 103.51,68.12 104.11,68.12 104.21,68.03 104.21,67.58 104.11,67.48 103.87,67.48 103.78,67.39 103.78,67.07 103.87,66.98 104.6,66.98 104.78,66.8 104.78,66.09 104.9,65.96 106.31,65.96 106.4,66.05 106.4,66.25 106.5,66.34 106.68,66.34 106.77,66.25 106.77,66.05 106.86,65.96 109.09,65.96 109.35,65.71 109.35,65.04 v3(109.03,64.72)
LPDDR4_DQ6_D: length 32.4
  TOP w0.124: U3.AJ33 v2(96.9,67.93)
  L12-SIG4 w0.091: v2(96.9,67.93) 97.27,67.56 98.78,67.56 99.13,67.21 99.13,67.08 98.72,66.66 98.72,66.53 98.85,66.4 98.98,66.4 99.39,66.82 99.52,66.82 100,66.34 116.54,66.34 116.63,66.43 116.63,67.06 116.72,67.15 116.9,67.15 116.99,67.06 116.99,66.43 117.09,66.34 117.27,66.34 117.36,66.43 117.36,66.99 117.45,67.08 117.63,67.08 117.73,66.99 117.73,66.43 117.82,66.34 118,66.34 118.09,66.43 118.09,66.99 118.18,67.08 118.37,67.08 118.46,66.99 118.46,66.43 118.55,66.34 118.73,66.34 118.82,66.43 118.82,66.99 118.91,67.08 119.1,67.08 119.19,66.99 119.19,66.43 119.28,66.34 119.63,66.34 119.76,66.21 119.76,65.04 v3(120.08,64.72)
LPDDR4_DQ7_A: length 33.8
  TOP w0.127: v2(87.9,74.93) 87.4,74.43 U3.AC24
  L05-SIG2 w0.091: v3(108.38,78.44) 108.43,78.44 108.84,78.02 109.22,78.02 109.35,78.15 109.35,79.55 109.09,79.8 105.45,79.8 105.36,79.89 105.36,80.09 105.27,80.18 105.08,80.18 104.99,80.09 104.99,79.89 104.9,79.8 104.72,79.8 104.63,79.89 104.63,80.35 104.54,80.44 104.35,80.44 104.26,80.35 104.26,79.89 104.17,79.8 103.99,79.8 103.9,79.89 103.9,80.35 103.8,80.44 89.66,80.44 89.03,79.8 88.01,79.8 87.5,79.29 87.5,78.79 86.36,77.64 86.36,75.74 86.74,75.36 87.47,75.36 v2(87.9,74.93)
LPDDR4_DQ7_B: length 40
  TOP w0.127: U3.W30 v2(92.9,78.93)
  L03-SIG1 w0.091: v3(120.73,78.44) 120.4,78.77 120.4,80.06 120.14,80.31 119.63,80.31 119.53,80.4 119.53,80.6 119.44,80.69 119.26,80.69 119.17,80.6 119.17,80.4 119.08,80.31 118.87,80.31 118.77,80.4 118.77,80.85 118.68,80.95 118.5,80.95 118.41,80.85 118.41,80.4 118.32,80.31 118.13,80.31 118.04,80.4 118.04,80.85 117.95,80.95 117.77,80.95 117.68,80.85 117.68,80.4 117.58,80.31 117.4,80.31 117.31,80.4 117.31,80.85 117.22,80.95 117.04,80.95 116.94,80.85 116.94,80.4 116.85,80.31 116.67,80.31 116.58,80.4 116.58,80.85 116.49,80.95 116.3,80.95 116.21,80.85 116.21,80.4 116.12,80.31 115.94,80.31 115.85,80.4 115.85,80.85 115.76,80.95 115.57,80.95 115.48,80.85 115.48,80.4 115.39,80.31 114.3,80.31 113.41,81.2 107.99,81.2 107.9,81.29 107.9,81.62 107.81,81.71 107.63,81.71 107.53,81.62 107.53,81.29 107.44,81.2 107.26,81.2 107.17,81.29 107.17,81.62 107.08,81.71 106.89,81.71 106.8,81.62 106.8,81.29 106.71,81.2 106.53,81.2 106.44,81.29 106.44,81.62 106.35,81.71 106.16,81.71 106.07,81.62 106.07,81.29 105.98,81.2 103.89,81.2 103.38,81.71 99.82,81.71 98.55,80.44 95.63,80.44 94.74,79.55 93.52,79.55 v2(92.9,78.93)
LPDDR4_DQ7_C: length 46.3
  TOP w0.127: U3.Y26 v2(89.9,76.93)
  L10-SIG3 w0.091: v3(108.38,64.72) 108.38,64.98 108.29,65.07 106.83,65.07 106.74,65.16 106.74,65.49 106.65,65.58 106.46,65.58 106.37,65.49 106.37,65.09 106.28,64.99 106.1,64.99 106.01,65.09 106.01,65.49 105.92,65.58 105.73,65.58 105.64,65.49 105.64,65.09 105.55,64.99 105.37,64.99 105.28,65.09 105.28,65.49 105.18,65.58 105,65.58 104.91,65.49 104.91,65.11 104.82,65.02 104.52,65.02 104.42,65.12 104.42,66.48 104.33,66.57 104.15,66.57 104.06,66.48 104.06,65.14 103.97,65.05 103.78,65.05 103.69,65.14 103.69,66.5 103.6,66.59 103.42,66.59 103.33,66.5 103.33,65.19 103.23,65.1 103.05,65.1 102.96,65.19 102.96,66.5 102.87,66.59 102.69,66.59 102.59,66.5 102.59,65.8 102.5,65.71 102.32,65.71 102.23,65.8 102.23,66.5 102.14,66.59 101.95,66.59 101.86,66.5 101.86,65.8 101.77,65.71 101.59,65.71 101.5,65.8 101.5,66.5 101.41,66.59 101.22,66.59 101.13,66.5 101.13,65.8 101.04,65.71 100.86,65.71 100.77,65.8 100.77,66.53 100.67,66.62 100.49,66.62 100.4,66.53 100.4,65.8 100.31,65.71 100.13,65.71 100.03,65.8 100.03,66.53 99.94,66.62 99.76,66.62 99.67,66.53 99.67,65.8 99.58,65.71 99.39,65.71 99.3,65.8 99.3,66.25 99.21,66.34 94.74,66.34 94.36,66.72 94.36,67.23 94.11,67.48 93.6,67.48 93.47,67.61 93.47,68.12 93.22,68.37 92.71,68.37 92.33,68.75 92.33,69.13 92.07,69.39 91.69,69.39 91.44,69.64 91.44,70.28 91.19,70.53 90.68,70.53 90.42,70.79 90.42,70.89 89.41,71.9 89.41,76.44 v2(89.9,76.93)
LPDDR4_DQ7_D: length 32.2
  TOP w0.124: U3.AJ34 v2(97.9,67.93)
  L12-SIG4 w0.091: v3(120.73,64.72) 120.4,65.05 120.4,66.69 120.3,66.78 119.73,66.78 119.63,66.87 119.63,67.06 119.73,67.15 120.41,67.15 120.5,67.24 120.5,67.47 120.41,67.56 115.62,67.56 115.49,67.43 115.49,66.82 115.39,66.72 114.22,66.72 113.82,67.13 110.12,67.13 110.03,67.04 110.03,66.89 109.94,66.8 109.76,66.8 109.67,66.89 109.67,67.04 109.58,67.13 109.39,67.13 109.3,67.04 109.3,66.81 109.21,66.72 109.03,66.72 108.94,66.81 108.94,67.04 108.84,67.13 108.66,67.13 108.57,67.04 108.57,66.81 108.48,66.72 108.3,66.72 108.2,66.81 108.2,67.04 108.11,67.13 107.93,67.13 107.84,67.04 107.84,66.81 107.75,66.72 107.56,66.72 107.47,66.81 107.47,67.04 107.38,67.13 107.2,67.13 107.11,67.04 107.11,66.81 107.02,66.72 106.83,66.72 106.74,66.81 106.74,67.04 106.65,67.13 106.47,67.13 106.37,67.04 106.37,66.81 106.28,66.72 100.33,66.72 99.12,67.93 v2(97.9,67.93)
LPDDR4_DQ8_A: length 23.8
  TOP w0.127: U3.AD34 v2(97.9,72.93)
  L10-SIG3 w0.091: v3(108.38,84.04) 104.95,84.04 101.3,80.39 101.17,80.39 101.02,80.54 100.89,80.54 100.76,80.41 100.76,80.28 100.91,80.13 100.91,80 100.78,79.87 100.65,79.87 100.36,80.16 100.23,80.16 100.1,80.03 100.1,79.9 100.39,79.61 100.39,79.48 100.26,79.35 100.13,79.35 99.86,79.63 99.73,79.63 99.6,79.5 99.6,79.37 99.87,79.1 99.87,78.97 99.74,78.84 99.61,78.84 99.34,79.11 99.21,79.11 99.08,78.98 99.08,78.85 99.36,78.58 99.36,78.45 99.06,78.15 98.17,78.15 96.39,76.37 96.39,73.69 96.76,73.33 97.5,73.33 v2(97.9,72.93)
LPDDR4_DQ8_B: length 44.3
  TOP w0.127: U3.AA24 87.4,76.43 v2(87.9,76.93)
  L12-SIG4 w0.091: v3(120.73,84.04) 121.38,84.04 121.47,84.13 121.47,84.28 121.56,84.37 121.93,84.37 122.02,84.28 122.02,84.13 122.11,84.04 122.64,84.04 122.94,83.74 122.94,79.17 122.68,78.91 107.31,78.91 106.93,79.29 97.16,79.29 96.14,78.28 89.41,78.28 88.06,76.93 v2(87.9,76.93)
LPDDR4_DQ8_C: length 21.7
  TOP w0.124: U3.AF32 v2(95.9,70.93)
  L05-SIG2 w0.091: v2(95.9,70.93) 99.84,70.93 99.93,70.84 99.93,70.37 100.02,70.28 100.2,70.28 100.3,70.37 100.3,70.84 100.39,70.93 100.57,70.93 100.66,70.84 100.66,70.37 100.75,70.28 100.94,70.28 101.03,70.37 101.03,70.84 101.12,70.93 101.3,70.93 101.39,70.84 101.39,70.37 101.48,70.28 101.67,70.28 101.76,70.37 101.76,70.84 101.85,70.93 102.6,70.93 102.69,70.84 102.69,70.71 102.59,70.61 102.2,70.61 102.12,70.53 102.12,70.37 102.22,70.28 104.61,70.28 104.7,70.19 104.7,69.66 104.8,69.57 104.98,69.57 105.07,69.66 105.07,70.19 105.16,70.28 105.34,70.28 105.44,70.19 105.44,69.66 105.53,69.57 105.71,69.57 105.8,69.66 105.8,70.19 105.89,70.28 106.08,70.28 106.17,70.19 106.17,69.66 106.26,69.57 106.44,69.57 106.53,69.66 106.53,70.18 106.62,70.28 108.34,70.28 v3(108.38,70.32)
LPDDR4_DQ8_D: length 38.4
  TOP w0.124: U3.AJ29 v2(91.9,67.93)
  L03-SIG1 w0.091: v3(120.73,70.32) 121.11,70.32 121.72,69.72 121.72,66.42 121.06,65.76 121.06,65.38 120.88,65.2 107.31,65.2 107.06,65.45 92.76,65.45 92.33,65.88 92.33,66.06 92.05,66.34 91.74,66.34 91.44,66.65 91.44,67.23 91.9,67.69 v2(91.9,67.93)
LPDDR4_DQ9_A: length 23.5
  TOP w0.127: U3.AD33 v2(96.9,72.93)
  L10-SIG3 w0.091: v3(109.03,84.04) 108.92,84.04 108.51,84.45 103.96,84.45 102.31,82.8 102.31,82.67 102.52,82.46 102.52,82.33 102.4,82.2 102.27,82.2 102.05,82.41 101.92,82.41 101.79,82.28 101.79,82.15 102.05,81.9 102.05,81.77 101.92,81.64 101.79,81.64 101.53,81.89 101.41,81.89 95.5,75.99 95.5,73.76 96.33,72.93 v2(96.9,72.93)
LPDDR4_DQ9_B: length 44.4
  TOP w0.127: U3.Y24 v2(87.9,77.93)
  L12-SIG4 w0.091: v3(120.08,84.04) 120.5,83.61 122.3,83.61 122.56,83.36 122.56,79.8 122.43,79.68 116.46,79.68 116.08,79.29 115.75,79.29 115.37,79.68 114.93,79.68 114.84,79.58 114.84,79.39 114.75,79.29 114.38,79.29 114.29,79.39 114.29,79.58 114.2,79.68 113.83,79.68 113.74,79.58 113.74,79.39 113.65,79.29 113.29,79.29 113.19,79.39 113.19,79.58 113.1,79.68 97.16,79.68 96.01,78.53 95.34,78.53 95.21,78.66 94.97,78.66 94.84,78.53 94.6,78.53 94.48,78.66 94.24,78.66 94.11,78.53 92.41,78.53 92.29,78.66 92.05,78.66 91.92,78.53 91.68,78.53 91.56,78.66 91.32,78.66 91.19,78.53 90.68,78.53 90.55,78.66 90.17,78.66 90.04,78.53 89.15,78.53 88.55,77.93 v2(87.9,77.93)
LPDDR4_DQ9_C: length 21.6
  TOP w0.124: U3.AG32 v2(95.9,69.93)
  L05-SIG2 w0.091: v2(95.9,69.93) 95.9,70.16 96.37,70.63 99.22,70.63 99.31,70.54 99.31,69.52 99.44,69.39 99.62,69.39 99.71,69.48 99.71,69.86 99.8,69.95 99.98,69.95 100.07,69.86 100.07,69.48 100.17,69.39 100.35,69.39 100.44,69.48 100.44,69.86 100.53,69.95 100.71,69.95 100.81,69.86 100.81,69.48 100.9,69.39 101.08,69.39 101.17,69.48 101.17,69.86 101.26,69.95 101.45,69.95 101.54,69.86 101.54,69.61 101.63,69.52 101.81,69.52 101.9,69.61 101.9,69.86 101.99,69.95 102.18,69.95 102.27,69.86 102.27,69.61 102.36,69.52 102.54,69.52 102.63,69.61 102.63,69.86 102.73,69.95 102.91,69.95 103,69.86 103,69.61 103.09,69.52 103.27,69.52 103.37,69.61 103.37,69.86 103.46,69.95 104.29,69.95 104.37,69.87 104.37,69.64 104.29,69.57 103.96,69.57 103.89,69.49 103.89,69.25 103.98,69.16 106.43,69.16 107.29,70.02 108.73,70.02 v3(109.03,70.32)
LPDDR4_DQ9_D: length 38.7
  TOP w0.124: U3.AJ28 v2(90.9,67.93)
  L03-SIG1 w0.091: v3(120.08,70.32) 120.08,70.54 119.76,70.86 119.76,71.67 118.11,73.33 90.75,73.33 89.53,72.11 89.53,68.75 89.92,68.37 90.46,68.37 v2(90.9,67.93)
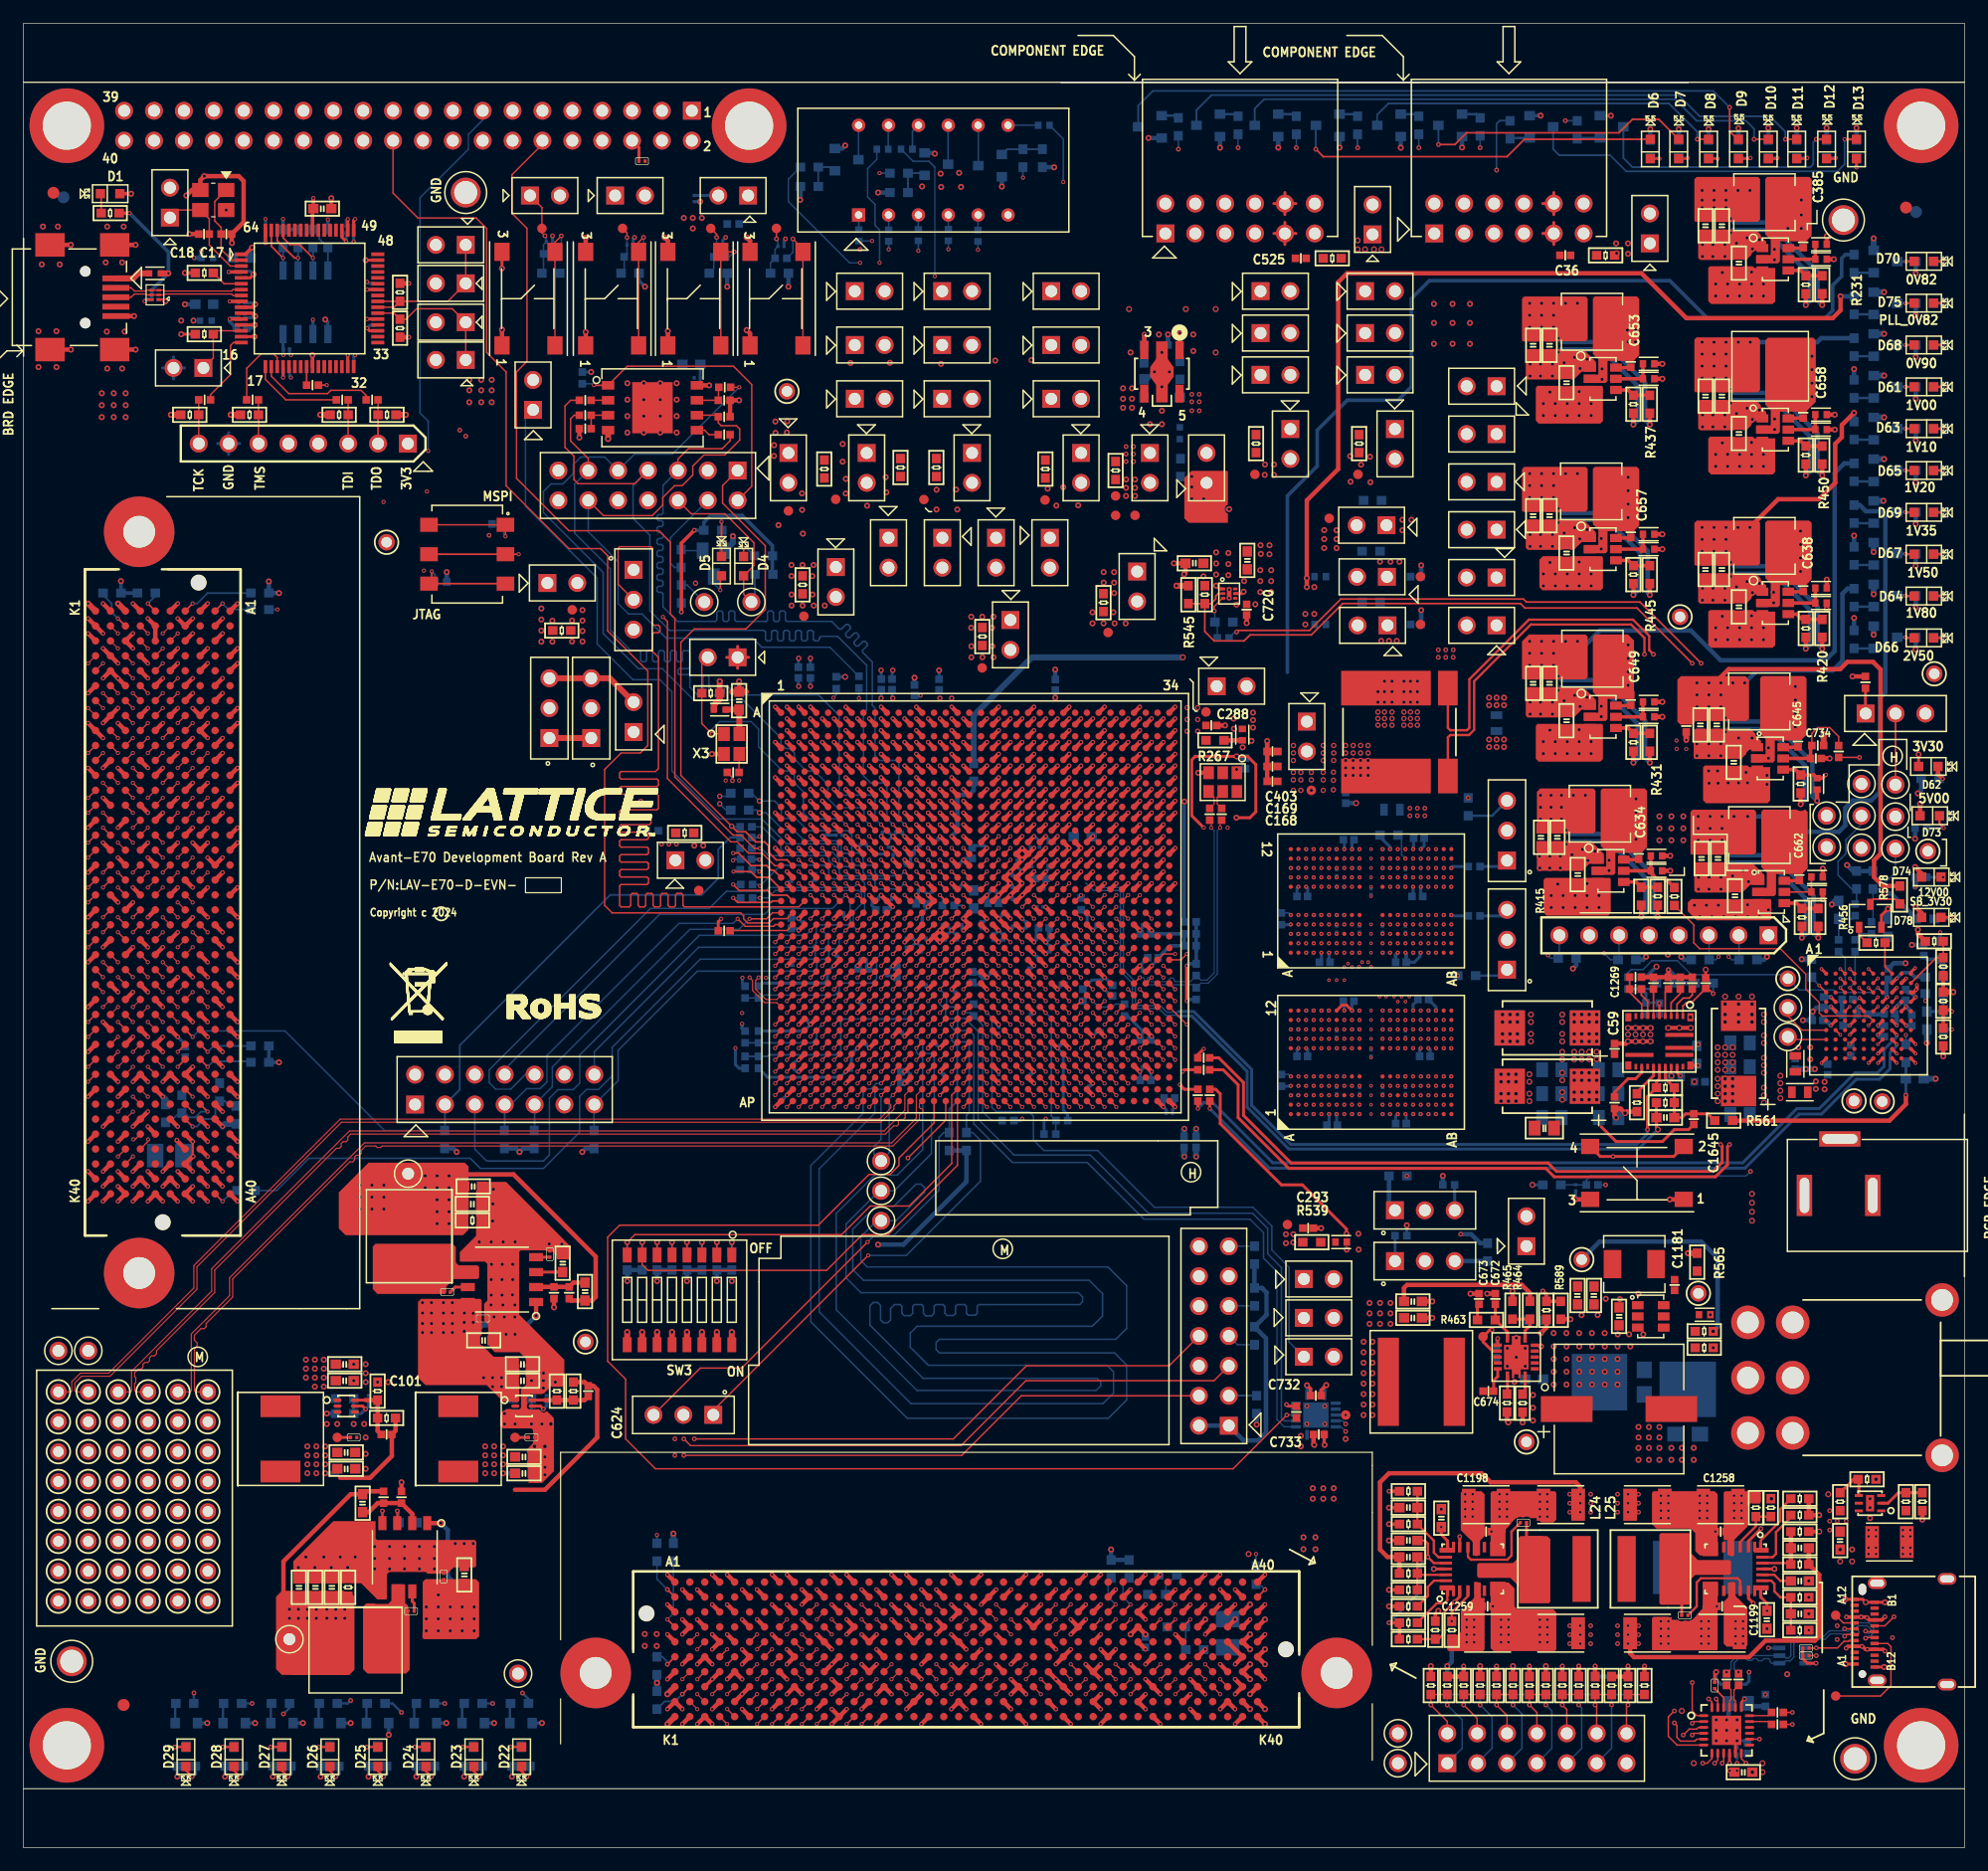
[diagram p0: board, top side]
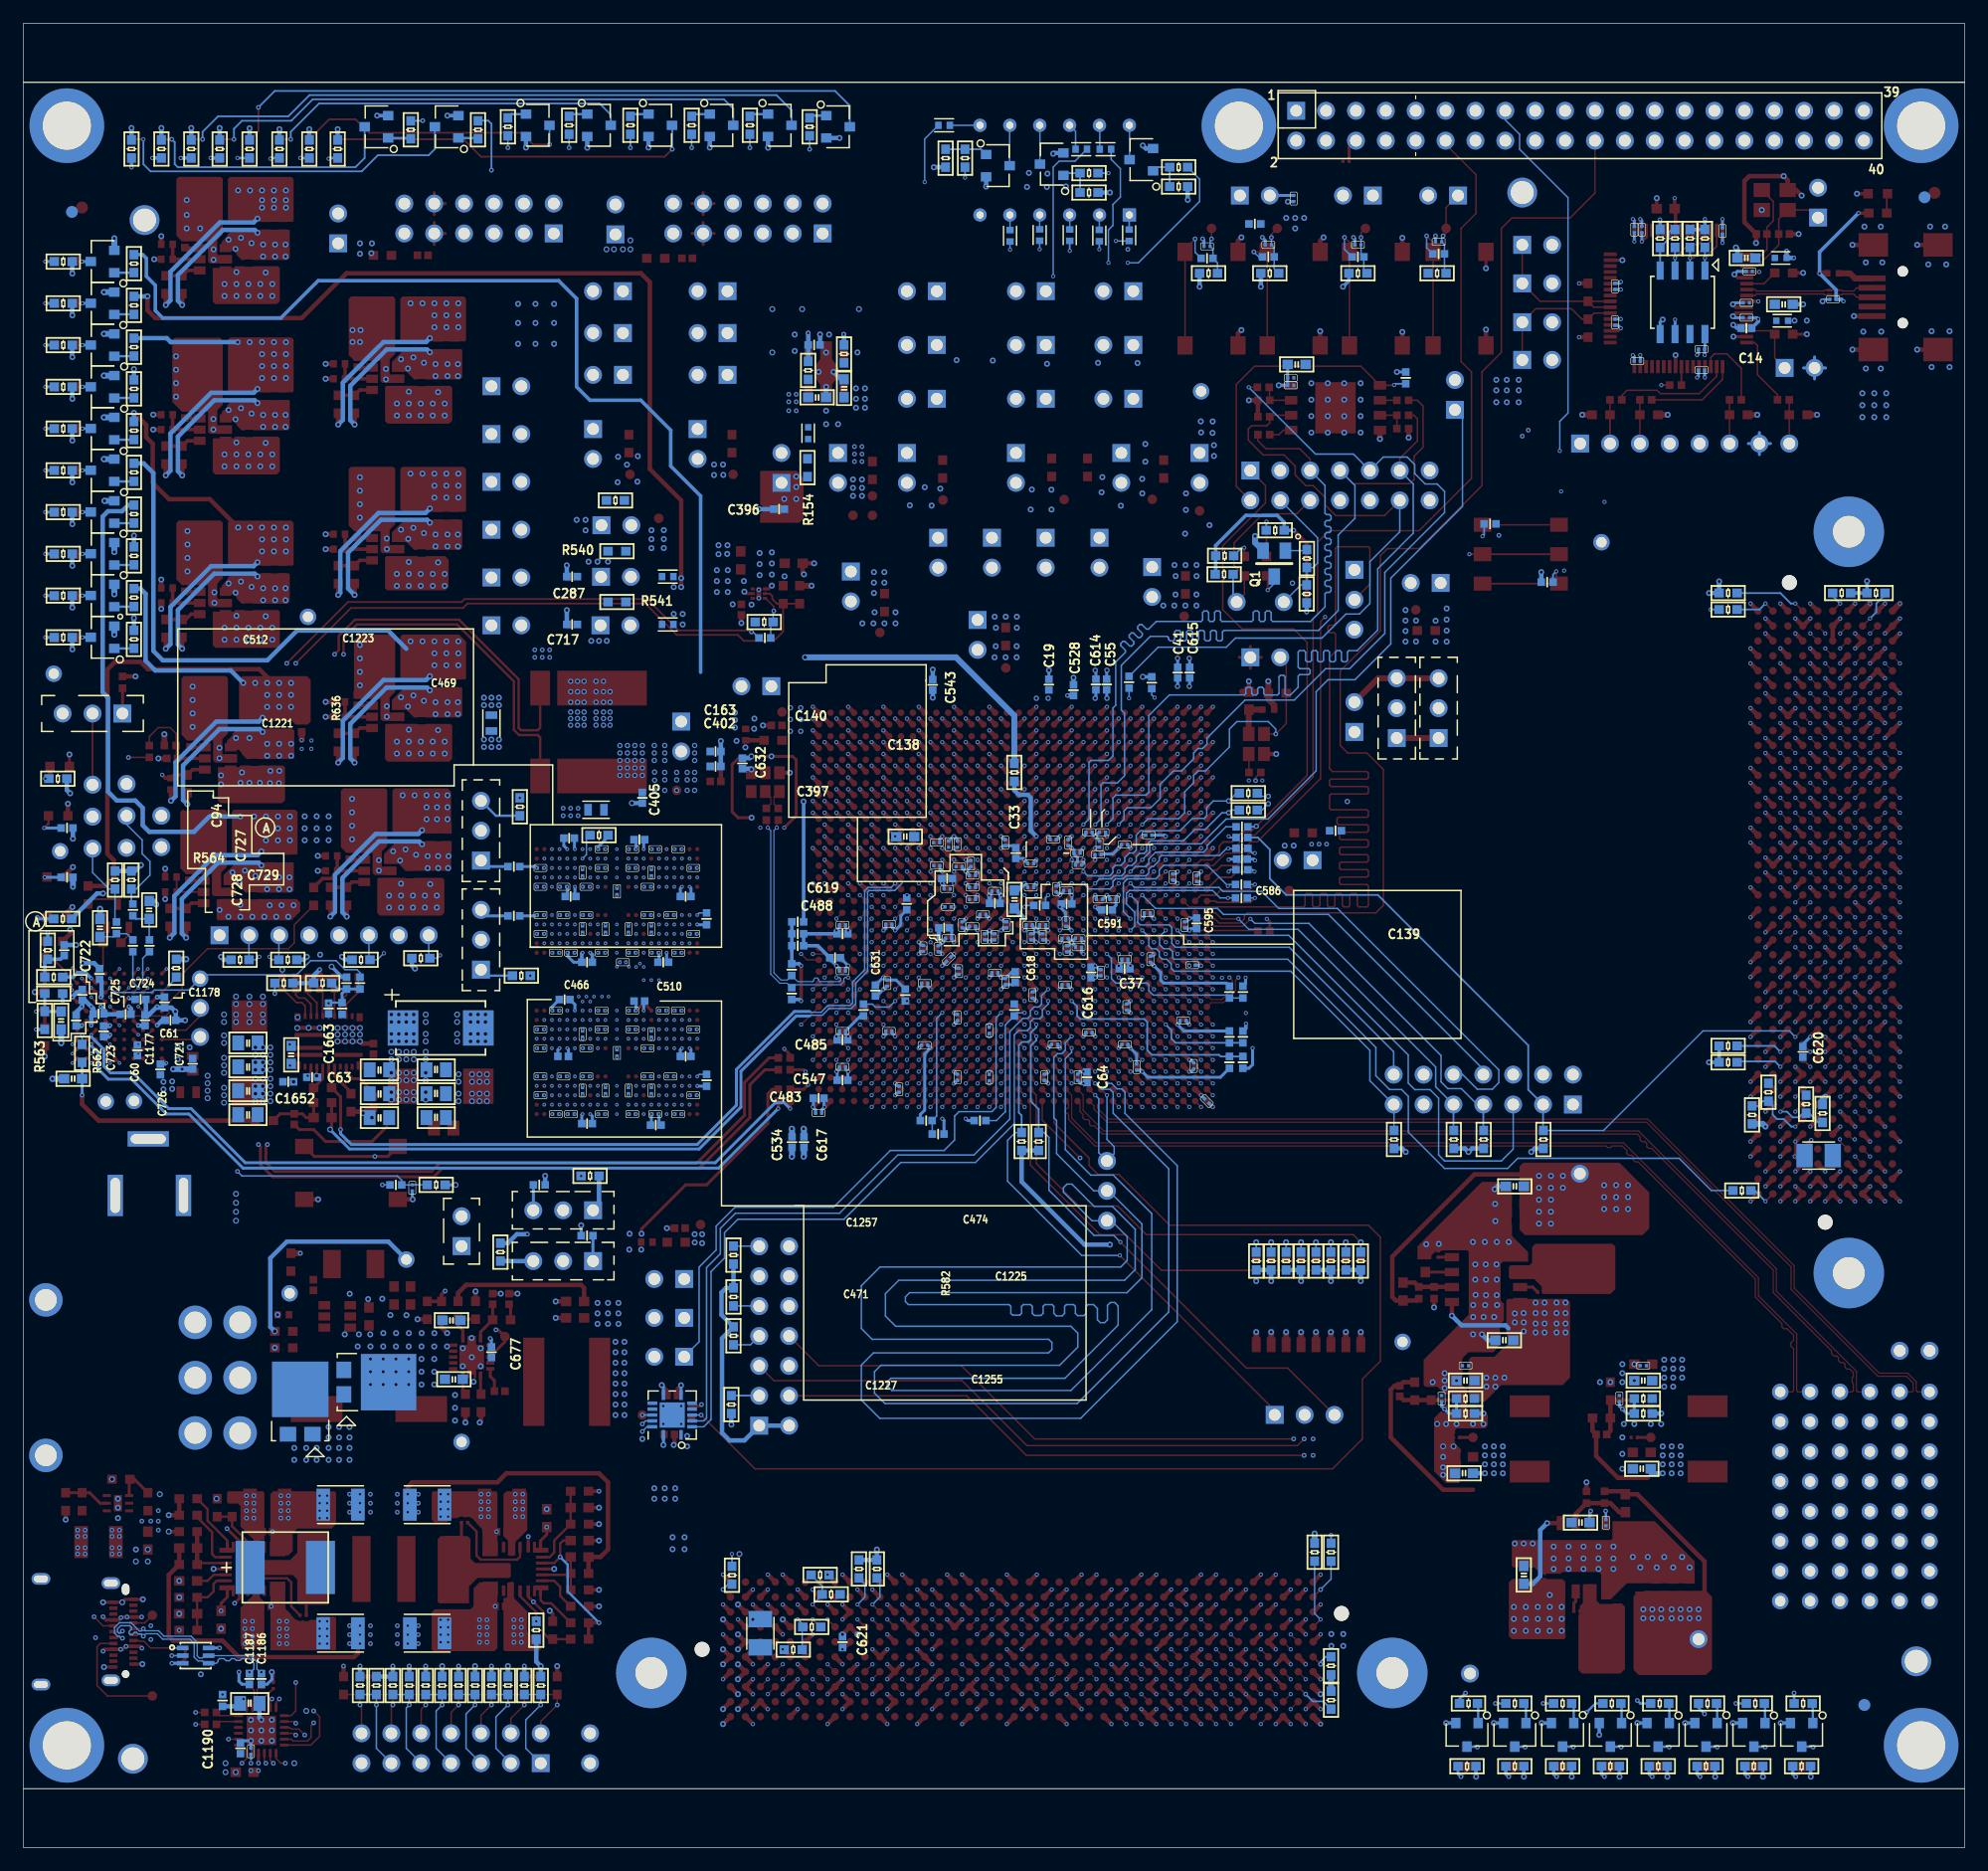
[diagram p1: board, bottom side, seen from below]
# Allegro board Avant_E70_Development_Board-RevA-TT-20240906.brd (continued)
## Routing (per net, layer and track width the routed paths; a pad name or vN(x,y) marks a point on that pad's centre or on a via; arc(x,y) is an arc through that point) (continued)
LPDDR4_DQ10_A: length 27
  TOP w0.127: U3.AE32 v2(94.9,72.93)
  L10-SIG3 w0.091: v2(94.9,72.93) 94.5,72.93 94.36,73.07 94.36,75.23 94.49,75.36 94.49,75.99 95.49,76.99 95.49,77.25 95.62,77.38 95.87,77.38 96.39,77.9 96.39,78.28 96.62,78.5 96.75,78.5 96.81,78.44 96.94,78.44 97.07,78.57 97.07,78.7 97,78.76 97,78.89 97.13,79.02 97.26,79.02 97.32,78.96 97.45,78.96 97.58,79.09 97.58,79.22 97.52,79.28 97.52,79.41 97.65,79.54 97.78,79.54 97.84,79.48 97.97,79.48 98.1,79.61 98.1,79.74 98.04,79.8 98.04,79.93 98.39,80.28 98.57,80.28 98.74,80.45 98.74,80.63 98.91,80.8 99.09,80.8 99.26,80.97 99.26,81.15 99.43,81.32 99.61,81.32 99.78,81.49 99.78,81.66 99.95,81.83 100.13,81.83 100.29,82 100.29,82.18 100.46,82.35 100.64,82.35 100.81,82.52 100.81,82.7 100.98,82.87 101.16,82.87 101.33,83.04 101.33,83.22 101.5,83.39 101.68,83.39 101.85,83.56 101.85,83.73 103.38,85.26 109.88,85.26 109.98,85.16 109.98,84.37 110.32,84.04 v3(110.33,84.04)
LPDDR4_DQ10_B: length 39.7
  TOP w0.127: U3.U23 v2(85.9,80.93)
  L12-SIG4 w0.091: v3(118.78,84.04) 118.44,84.38 118.44,85.19 117.47,86.15 98.24,86.15 97.99,86.41 87.88,86.41 85.47,83.99 85.47,81.36 v2(85.9,80.93)
LPDDR4_DQ10_C: length 26.6
  TOP w0.124: U3.AF29 v2(91.9,70.93)
  L05-SIG2 w0.091: v2(91.9,70.93) 91.9,71.35 92,71.45 93.09,71.45 94.23,70.3 94.23,69.52 94.41,69.34 95.43,69.34 95.55,69.46 95.55,71.08 95.73,71.27 103.04,71.27 103.13,71.18 103.13,70.75 103.22,70.66 103.4,70.66 103.5,70.75 103.5,71.18 103.59,71.27 103.77,71.27 103.86,71.18 103.86,70.75 103.95,70.66 104.14,70.66 104.23,70.75 104.23,71.18 104.32,71.27 104.5,71.27 104.59,71.18 104.59,70.75 104.68,70.66 104.87,70.66 104.96,70.75 104.96,71.18 105.05,71.27 105.27,71.27 105.36,71.18 105.36,70.74 105.44,70.66 109.09,70.66 109.28,70.85 109.54,70.85 109.73,70.66 110.24,70.66 110.33,70.57 v3(110.33,70.32)
LPDDR4_DQ10_D: length 41.9
  TOP w0.124: U3.AG28 v2(90.9,70.93)
  L03-SIG1 w0.091: v2(90.9,70.93) 91.52,71.55 99.31,71.55 99.52,71.75 99.52,72.01 99.57,72.06 99.96,72.06 100.05,71.96 100.05,71.61 100.14,71.52 100.32,71.52 100.41,71.61 100.41,71.96 100.51,72.06 100.69,72.06 100.78,71.96 100.78,71.61 100.87,71.52 101.05,71.52 101.15,71.61 101.15,71.96 101.24,72.06 101.46,72.06 101.56,72.15 101.56,72.47 101.65,72.56 101.83,72.56 101.92,72.47 101.92,71.64 102.01,71.55 102.2,71.55 102.29,71.64 102.29,72.47 102.38,72.56 102.56,72.56 102.65,72.47 102.65,72.02 102.74,71.93 102.93,71.93 103.02,72.02 103.02,72.47 103.11,72.56 103.29,72.56 103.38,72.47 103.38,72.15 103.48,72.06 103.66,72.06 103.75,72.15 103.75,72.47 103.84,72.56 104.02,72.56 104.12,72.47 104.12,72.15 104.21,72.06 104.39,72.06 104.48,72.15 104.48,72.47 104.57,72.56 104.76,72.56 104.85,72.47 104.85,72.15 104.94,72.06 105.12,72.06 105.21,72.15 105.21,72.47 105.3,72.56 105.49,72.56 105.58,72.47 105.58,72.15 105.67,72.06 105.85,72.06 105.94,72.15 105.94,72.47 106.04,72.56 106.22,72.56 106.31,72.47 106.31,72.15 106.4,72.06 106.59,72.06 106.68,72.15 106.68,72.47 106.77,72.56 106.95,72.56 107.04,72.47 107.04,72.15 107.13,72.06 107.32,72.06 107.41,72.15 107.41,72.47 107.5,72.56 107.68,72.56 107.77,72.47 107.77,72.02 107.87,71.93 108.05,71.93 108.14,72.02 108.14,72.47 108.23,72.56 108.41,72.56 108.51,72.47 108.51,72.27 108.6,72.18 108.78,72.18 108.87,72.27 108.87,72.47 109.01,72.61 114.38,72.61 115.44,71.55 118.19,71.55 118.44,71.29 118.44,70.66 v3(118.78,70.32)
LPDDR4_DQ11_A: length 27.2
  TOP w0.127: U3.AE31 v2(93.9,72.93)
  L10-SIG3 w0.091: v2(93.9,72.93) 93.9,75.28 94.23,75.61 94.23,76.75 95.38,77.9 95.38,78.02 95.76,78.41 96.01,78.41 103.25,85.64 108.97,85.64 109.06,85.74 109.06,86.09 109.15,86.18 109.33,86.18 109.42,86.09 109.42,85.74 109.51,85.64 110.29,85.64 110.67,85.26 110.67,84.35 v3(110.98,84.04)
LPDDR4_DQ11_B: length 40.1
  TOP w0.127: U3.U22 v2(84.9,79.93)
  L12-SIG4 w0.091: v2(84.9,79.93) 85.41,80.44 85.98,80.44 86.36,80.82 86.36,84.12 86.74,84.5 87,84.5 87.43,84.93 87.43,85.19 87.76,85.52 97.66,85.52 97.92,85.77 98.43,85.77 98.68,85.52 98.93,85.52 99.19,85.77 99.57,85.77 99.85,85.49 100.18,85.49 100.46,85.77 117.22,85.77 117.81,85.19 117.81,84.68 118.13,84.36 v3(118.13,84.04)
LPDDR4_DQ11_C: length 26.8
  TOP w0.124: U3.AF28 91.9,71.93 v2(91.9,71.93)
  L05-SIG2 w0.091: v3(110.98,70.32) 110.64,70.66 110.64,71.34 110.41,71.57 108.44,71.57 108.35,71.48 108.35,71.13 108.26,71.04 108.08,71.04 107.99,71.13 107.99,71.48 107.9,71.57 107.71,71.57 107.62,71.48 107.62,71.11 107.53,71.01 107.35,71.01 107.26,71.11 107.26,71.48 107.16,71.57 106.98,71.57 106.89,71.48 106.89,71.11 106.8,71.01 106.62,71.01 106.52,71.11 106.52,71.48 106.43,71.57 106.25,71.57 106.16,71.48 106.16,71.11 106.07,71.01 105.88,71.01 105.79,71.11 105.79,71.48 105.7,71.57 95.66,71.57 95.28,71.2 95.28,69.99 95.19,69.9 94.71,69.9 94.62,69.99 94.62,70.4 93.34,71.67 92.15,71.67 v2(91.9,71.93)
LPDDR4_DQ11_D: length 42.5
  TOP w0.124: U3.AG27 v2(89.9,69.93)
  L03-SIG1 w0.091: v3(118.13,70.32) 117.66,70.79 115.19,70.79 115.06,70.91 115.06,71.29 114.86,71.5 114.22,71.5 114.13,71.59 114.13,72.09 114.04,72.18 113.85,72.18 113.76,72.09 113.76,71.59 113.67,71.5 113.49,71.5 113.39,71.59 113.39,72.09 113.3,72.18 113.12,72.18 113.03,72.09 113.03,71.59 112.94,71.5 112.75,71.5 112.66,71.59 112.66,72.09 112.57,72.18 112.39,72.18 112.3,72.09 112.3,71.59 112.21,71.5 112.02,71.5 111.93,71.59 111.93,71.94 111.84,72.03 111.66,72.03 111.57,71.94 111.57,71.59 111.47,71.5 111.29,71.5 111.2,71.59 111.2,71.89 111.11,71.98 110.93,71.98 110.83,71.89 110.83,71.59 110.74,71.5 110.56,71.5 110.47,71.59 110.47,71.84 110.38,71.93 110.19,71.93 110.1,71.84 110.1,71.59 110.01,71.5 109.83,71.5 109.74,71.59 109.74,71.84 109.65,71.93 109.46,71.93 109.37,71.84 109.37,71.59 109.28,71.5 108.66,71.5 108.46,71.29 107.55,71.29 107.17,71.67 106.99,71.67 106.9,71.58 106.9,71.13 106.81,71.04 106.62,71.04 106.53,71.13 106.53,71.58 106.44,71.67 106.26,71.67 106.17,71.58 106.17,71.13 106.07,71.04 105.89,71.04 105.8,71.13 105.8,71.58 105.71,71.67 105.53,71.67 105.43,71.58 105.43,71.13 105.34,71.04 105.16,71.04 105.07,71.13 105.07,71.58 104.98,71.67 104.79,71.67 104.7,71.58 104.7,71.13 104.61,71.04 104.43,71.04 104.34,71.13 104.34,71.58 104.25,71.67 104.06,71.67 103.97,71.58 103.97,71.13 103.88,71.04 103.7,71.04 103.61,71.13 103.61,71.58 103.51,71.67 103.33,71.67 103.24,71.58 103.24,71.26 103.15,71.17 96.65,71.17 96.01,70.53 90.5,70.53 v2(89.9,69.93)
LPDDR4_DQ12_A: length 24
  TOP w0.127: U3.AE33 v2(96.9,71.93)
  L10-SIG3 w0.091: v3(110.98,82.44) 110.67,82.13 110.67,81.35 109.12,79.8 107.59,79.8 106.96,79.17 106.96,78.43 105.34,76.82 105.34,76.69 105.44,76.59 105.44,76.46 105.31,76.33 105.18,76.33 105.09,76.43 104.96,76.43 104.83,76.3 104.83,76.17 105.14,75.85 105.14,75.72 105.01,75.59 104.88,75.59 104.57,75.91 104.44,75.91 104.31,75.78 104.31,75.65 104.62,75.34 104.62,75.21 104.49,75.08 104.36,75.08 104.05,75.39 103.92,75.39 103.79,75.26 103.79,75.13 104.11,74.82 104.11,74.69 103.98,74.56 103.85,74.56 103.53,74.87 103.4,74.87 99.95,71.42 97.41,71.42 v2(96.9,71.93)
LPDDR4_DQ12_B: length 38.6
  TOP w0.127: U3.U25 v2(88.9,80.93)
  L12-SIG4 w0.091: v3(118.13,82.44) 118.02,82.44 117.6,82.85 116.63,82.85 116.51,82.97 116.51,83.47 116.37,83.61 107.61,83.61 107.23,83.99 106.87,83.99 106.77,83.9 106.77,83.7 106.68,83.61 106.32,83.61 106.23,83.7 106.23,83.9 106.13,83.99 105.77,83.99 105.68,83.9 105.68,83.7 105.59,83.61 105.22,83.61 105.13,83.7 105.13,83.9 105.04,83.99 104.67,83.99 104.58,83.9 104.58,83.7 104.49,83.61 104.12,83.61 104.03,83.7 104.03,83.9 103.94,83.99 103.57,83.99 103.48,83.9 103.48,83.7 103.39,83.61 102.54,83.61 102.03,83.1 101.66,83.1 101.57,83.01 101.57,82.69 101.48,82.6 101.3,82.6 101.21,82.69 101.21,83.01 101.12,83.1 100.93,83.1 100.84,83.01 100.84,82.56 100.75,82.47 100.57,82.47 100.48,82.56 100.48,83.01 100.38,83.1 100.2,83.1 100.11,83.01 100.11,82.56 100.02,82.47 99.84,82.47 99.74,82.56 99.74,83.01 99.65,83.1 99.47,83.1 99.38,83.01 99.38,82.56 99.29,82.47 99.1,82.47 99.01,82.56 99.01,83.01 98.92,83.1 98.74,83.1 98.65,83.01 98.65,82.56 98.56,82.47 89.66,82.47 89.41,82.22 89.41,81.44 v2(88.9,80.93)
LPDDR4_DQ12_C: length 18.7
  TOP w0.124: U3.AG34 v2(97.9,69.93)
  L05-SIG2 w0.091: v3(110.98,68.72) 110.98,69.12 110.89,69.21 107.31,69.21 106.35,68.25 103.25,68.25 103.16,68.15 103.16,67.7 103.07,67.61 102.88,67.61 102.79,67.7 102.79,68.15 102.7,68.25 102.49,68.25 102.4,68.15 102.4,67.7 102.3,67.61 102.12,67.61 102.03,67.7 102.03,68.15 101.94,68.25 101.76,68.25 101.66,68.15 101.66,67.7 101.57,67.61 101.39,67.61 101.3,67.7 101.3,68.15 101.21,68.25 99.19,68.25 97.9,69.53 v2(97.9,69.93)
LPDDR4_DQ12_D: length 42
  TOP w0.124: v2(89.9,70.93) 89.9,70.93 U3.AG26
  L03-SIG1 w0.091: v3(118.13,68.72) 118.54,69.13 119.51,69.13 119.76,69.39 119.76,70.41 119.51,70.66 119.38,70.66 119.13,70.91 119.13,71.67 117.83,72.97 100.97,72.97 100.88,72.88 100.88,72.53 100.78,72.44 100.6,72.44 100.51,72.53 100.51,72.88 100.42,72.97 100.24,72.97 100.14,72.88 100.14,72.53 100.05,72.44 99.87,72.44 99.78,72.53 99.78,72.88 99.69,72.97 99.5,72.97 99.41,72.88 99.41,72.53 99.32,72.44 99.14,72.44 99.05,72.53 99.05,72.88 98.96,72.97 98.76,72.97 98.63,72.84 98.63,72.51 98.55,72.44 96.49,72.44 96.4,72.53 96.4,72.88 96.31,72.97 96.13,72.97 96.03,72.88 96.03,72.53 95.94,72.44 95.76,72.44 95.67,72.53 95.67,72.88 95.58,72.97 95.39,72.97 95.3,72.88 95.3,72.53 95.21,72.44 94.32,72.44 94.16,72.28 93.98,72.28 93.82,72.44 93.64,72.44 93.55,72.35 93.55,72.15 93.46,72.06 93.28,72.06 93.18,72.15 93.18,72.35 93.09,72.44 92.91,72.44 92.82,72.35 92.82,72.15 92.73,72.06 92.54,72.06 92.45,72.15 92.45,72.35 92.36,72.44 90.68,72.44 90.36,72.12 90.36,71.39 v2(89.9,70.93)
LPDDR4_DQ13_A: length 23.8
  TOP w0.127: U3.AE34 v2(97.9,71.93)
  L10-SIG3 w0.091: v2(97.9,71.93) 98.41,72.44 99.57,72.44 99.96,72.83 100.09,72.83 100.28,72.64 100.41,72.64 100.54,72.77 100.54,72.9 100.35,73.09 100.35,73.22 100.48,73.35 100.61,73.35 100.8,73.16 100.93,73.16 101.06,73.29 101.06,73.42 100.87,73.61 100.87,73.74 101,73.87 101.13,73.87 101.32,73.68 101.45,73.68 101.58,73.81 101.58,73.94 101.39,74.13 101.39,74.26 101.52,74.39 101.65,74.39 101.83,74.2 101.96,74.2 102.09,74.33 102.09,74.46 101.91,74.64 101.91,74.77 102.03,74.9 102.16,74.9 102.35,74.72 102.48,74.72 102.61,74.84 102.61,74.97 102.42,75.16 102.42,75.29 102.55,75.42 102.68,75.42 102.87,75.23 103,75.23 103.13,75.36 103.13,75.49 102.94,75.68 102.94,75.81 103.07,75.94 103.2,75.94 103.39,75.75 103.52,75.75 103.65,75.88 103.65,76.01 103.46,76.2 103.46,76.33 103.59,76.46 103.72,76.46 103.9,76.27 104.03,76.27 104.16,76.4 104.16,76.53 103.98,76.72 103.98,76.84 104.1,76.97 104.23,76.97 104.32,76.89 104.45,76.89 104.58,77.02 104.58,77.15 104.49,77.23 104.49,77.36 107.54,80.41 109.07,80.41 110.01,81.35 110.01,82.12 v3(110.33,82.44)
LPDDR4_DQ13_B: length 38.6
  TOP w0.127: U3.T25 v2(88.9,81.93)
  L12-SIG4 w0.091: v2(88.9,81.93) 88.26,82.56 88.26,83.23 88.52,83.49 98.88,83.49 98.97,83.58 98.97,83.9 99.07,83.99 99.25,83.99 99.34,83.9 99.34,83.58 99.43,83.49 99.61,83.49 99.71,83.58 99.71,83.9 99.8,83.99 99.98,83.99 100.07,83.9 100.07,83.58 100.16,83.49 100.35,83.49 100.44,83.58 100.44,83.9 100.53,83.99 100.71,83.99 100.8,83.9 100.8,83.58 100.9,83.49 101.08,83.49 101.17,83.58 101.17,84.03 101.26,84.12 101.44,84.12 101.54,84.03 101.54,83.58 101.63,83.49 101.81,83.49 101.9,83.58 101.9,84.41 101.99,84.5 116.84,84.5 117.17,84.17 117.17,83.79 117.4,83.56 117.65,83.56 117.81,83.41 117.81,83.03 117.98,82.85 118.37,82.85 v3(118.78,82.44)
LPDDR4_DQ13_C: length 18.8
  TOP w0.124: U3.AH34 v2(97.9,68.93)
  L05-SIG2 w0.091: v3(110.33,68.72) 110.03,69.02 107.53,69.02 107.31,68.8 107.31,68.22 106.96,67.86 106.51,67.86 106.42,67.77 106.42,67.45 106.33,67.36 106.15,67.36 106.05,67.45 106.05,67.77 105.96,67.86 105.76,67.86 105.66,67.77 105.66,67.5 105.57,67.41 105.39,67.41 105.3,67.5 105.3,67.75 105.21,67.84 105.02,67.84 104.93,67.75 104.93,67.32 104.84,67.23 104.66,67.23 104.57,67.32 104.57,67.75 104.48,67.84 104.29,67.84 104.2,67.75 104.2,67.32 104.11,67.23 103.93,67.23 103.84,67.32 103.84,67.75 103.74,67.84 103.56,67.84 103.47,67.75 103.47,67.32 103.38,67.23 99.6,67.23 v2(97.9,68.93)
LPDDR4_DQ13_D: length 42.1
  TOP w0.124: U3.AH26 v2(89.9,68.93)
  L03-SIG1 w0.091: v2(89.9,68.93) 91.25,70.28 93.22,70.28 93.34,70.15 93.34,68.88 93.68,68.55 98.88,68.55 99.19,68.25 99.32,68.25 99.57,68.5 99.7,68.5 99.83,68.37 99.83,68.24 99.57,67.99 99.57,67.86 99.9,67.53 101.59,67.53 101.68,67.63 101.68,67.9 101.77,67.99 101.96,67.99 102.05,67.9 102.05,67.63 102.14,67.53 102.32,67.53 102.41,67.63 102.41,67.9 102.51,67.99 102.69,67.99 102.78,67.9 102.78,67.63 102.87,67.53 103.05,67.53 103.15,67.63 103.15,67.9 103.24,67.99 103.42,67.99 103.51,67.9 103.51,67.63 103.6,67.53 103.79,67.53 103.88,67.63 103.88,67.9 103.97,67.99 104.15,67.99 104.24,67.9 104.24,67.63 104.33,67.53 104.52,67.53 104.61,67.63 104.61,67.9 104.7,67.99 104.88,67.99 104.97,67.9 104.97,67.63 105.07,67.53 105.25,67.53 105.34,67.63 105.34,67.9 105.43,67.99 105.61,67.99 105.71,67.9 105.71,67.63 105.8,67.53 105.98,67.53 106.07,67.63 106.07,67.9 106.16,67.99 106.35,67.99 106.44,67.9 106.44,67.63 106.53,67.53 106.71,67.53 106.8,67.63 106.8,67.98 106.89,68.07 107.08,68.07 107.17,67.98 107.17,67.63 107.26,67.53 107.44,67.53 107.53,67.63 107.53,68.26 107.62,68.35 107.81,68.35 107.9,68.26 107.9,67.63 107.99,67.53 113.21,67.53 113.42,67.75 113.55,67.75 113.76,67.53 113.89,67.53 114.02,67.66 114.02,67.79 113.81,68 113.81,68.13 114.01,68.34 115.02,68.34 115.11,68.25 115.11,67.93 115.21,67.84 115.39,67.84 115.48,67.93 115.48,68.25 115.57,68.34 118.4,68.34 v3(118.78,68.72)
LPDDR4_DQ14_A: length 22.7
  TOP w0.127: U3.AB34 98.4,75.43 v2(98.9,75.93)
  L10-SIG3 w0.091: v2(98.9,75.93) 99.38,75.93 99.47,75.84 99.47,75.07 99.56,74.98 99.75,74.98 99.84,75.07 99.84,75.84 99.93,75.93 100.11,75.93 100.2,75.84 100.2,75.07 100.29,74.98 100.48,74.98 100.57,75.07 100.57,75.84 100.66,75.93 100.84,75.93 100.93,75.84 100.93,75.07 101.03,74.98 101.21,74.98 101.3,75.07 101.3,75.84 101.39,75.93 101.92,75.93 102.25,76.26 102.38,76.26 102.51,76.14 102.64,76.14 102.76,76.27 102.76,76.4 102.64,76.52 102.64,76.65 102.77,76.78 102.9,76.78 103.02,76.66 103.15,76.66 103.28,76.79 103.28,76.92 103.16,77.04 103.16,77.17 103.29,77.3 103.42,77.3 103.54,77.17 103.67,77.17 103.8,77.3 103.8,77.43 103.68,77.56 103.68,77.69 103.8,77.82 103.93,77.82 104.06,77.69 104.19,77.69 104.32,77.82 104.32,77.95 104.19,78.08 104.19,78.2 104.32,78.33 104.45,78.33 104.58,78.21 104.71,78.21 104.83,78.34 104.83,78.47 104.71,78.59 104.71,78.72 104.84,78.85 105.02,78.85 105.23,79.06 105.23,79.24 107.19,81.2 108.53,81.2 108.71,81.38 108.71,82.12 v3(109.03,82.44)
LPDDR4_DQ14_B: length 38.9
  TOP w0.127: U3.U24 v2(87.9,80.93)
  L12-SIG4 w0.091: v2(87.9,80.93) 88.26,80.56 89.03,80.56 89.92,81.45 98.04,81.45 98.68,82.09 99.25,82.09 99.34,82 99.34,81.67 99.44,81.58 99.62,81.58 99.71,81.67 99.71,82.03 99.8,82.12 99.99,82.12 100.08,82.03 100.08,81.67 100.17,81.58 100.35,81.58 100.44,81.67 100.44,82.03 100.53,82.12 100.72,82.12 100.81,82.03 100.81,81.67 100.9,81.58 101.08,81.58 101.17,81.67 101.17,82.03 101.27,82.12 101.45,82.12 101.54,82.03 101.54,81.67 101.63,81.58 101.81,81.58 101.91,81.67 101.91,82.03 102,82.12 102.65,82.12 103.38,82.85 104.09,82.85 104.18,82.76 104.18,82.56 104.27,82.47 104.64,82.47 104.73,82.56 104.73,82.76 104.82,82.85 105.19,82.85 105.28,82.76 105.28,82.56 105.37,82.47 105.74,82.47 105.83,82.56 105.83,82.76 105.92,82.85 114.68,82.85 115.41,82.12 119.76,82.12 v3(120.08,82.44)
LPDDR4_DQ14_C: length 24.4
  TOP w0.124: U3.AG30 v2(92.9,69.93)
  L05-SIG2 w0.091: v2(92.9,69.93) 92.33,69.36 92.33,67.61 92.46,67.48 93.22,67.48 93.47,67.23 93.47,66.72 93.73,66.47 108.56,66.47 108.71,66.62 108.71,67 108.8,67.09 109.56,67.09 109.65,67.18 109.65,67.37 109.56,67.46 108.8,67.46 108.71,67.55 108.71,68.4 v3(109.03,68.72)
LPDDR4_DQ14_D: length 39.6
  TOP w0.124: U3.AG29 v2(91.9,69.93)
  L03-SIG1 w0.091: v2(91.9,69.93) 92.46,69.37 92.46,68.63 92.9,68.18 92.9,67.8 93.35,67.36 99.03,67.36 99.29,67.1 99.29,66.97 99.12,66.81 99.12,66.68 99.25,66.55 99.38,66.55 99.55,66.72 99.68,66.72 100.05,66.34 110.99,66.34 111.08,66.43 111.08,66.63 111.17,66.72 111.36,66.72 111.45,66.63 111.45,66.43 111.54,66.34 111.72,66.34 111.81,66.43 111.81,66.63 111.91,66.72 112.09,66.72 112.18,66.63 112.18,66.43 112.27,66.34 112.45,66.34 112.55,66.43 112.55,66.63 112.64,66.72 112.82,66.72 112.91,66.63 112.91,66.43 113,66.34 113.19,66.34 113.28,66.43 113.28,66.63 113.37,66.72 113.55,66.72 113.64,66.63 113.64,66.43 113.73,66.34 115.59,66.34 115.68,66.43 115.68,66.88 115.77,66.98 115.95,66.98 116.04,66.88 116.04,66.43 116.14,66.34 116.32,66.34 116.41,66.43 116.41,66.76 116.5,66.85 116.68,66.85 116.78,66.76 116.78,66.43 116.87,66.34 117.05,66.34 117.14,66.43 117.14,66.76 117.23,66.85 117.42,66.85 117.51,66.76 117.51,66.43 117.6,66.34 117.78,66.34 117.87,66.43 117.87,66.76 117.96,66.85 118.15,66.85 118.24,66.76 118.24,66.43 118.33,66.34 119.51,66.34 120.39,67.22 120.39,68.41 v3(120.08,68.72)
LPDDR4_DQ15_A: length 22.4
  TOP w0.127: U3.AB33 96.9,75.93 v2(97.9,75.93)
  L10-SIG3 w0.091: v3(108.38,82.44) 108.38,82.18 108.29,82.09 106.55,82.09 104.27,79.81 104.27,79.68 104.65,79.3 104.65,79.17 104.52,79.04 104.39,79.04 104.01,79.42 103.88,79.42 103.75,79.29 103.75,79.16 104.13,78.78 104.13,78.65 104,78.52 103.87,78.52 103.49,78.9 103.36,78.9 103.23,78.77 103.23,78.64 103.61,78.26 103.61,78.13 103.48,78 103.35,78 102.98,78.38 102.85,78.38 102.72,78.25 102.72,78.12 103.1,77.75 103.1,77.62 102.97,77.49 102.84,77.49 102.46,77.86 102.33,77.86 102.2,77.74 102.2,77.61 102.58,77.23 102.58,77.1 102.45,76.97 102.32,76.97 101.94,77.35 101.81,77.35 101.68,77.22 101.68,77.09 102.06,76.71 102.06,76.58 101.93,76.45 101.8,76.45 101.42,76.83 101.29,76.83 100.84,76.37 98.34,76.37 v2(97.9,75.93)
LPDDR4_DQ15_B: length 39.3
  TOP w0.127: U3.T24 v2(87.9,81.93)
  L12-SIG4 w0.091: v3(120.73,82.44) 120.4,82.1 120.4,81.45 120.14,81.2 115.19,81.2 114.94,81.45 114.94,81.96 114.81,82.09 114.05,82.09 113.92,81.96 113.92,81.45 113.66,81.2 106.03,81.2 105.94,81.29 105.94,81.46 105.85,81.56 105.48,81.56 105.39,81.46 105.39,81.29 105.3,81.2 104.93,81.2 104.84,81.29 104.84,81.46 104.75,81.56 104.39,81.56 104.29,81.46 104.29,81.29 104.2,81.2 98.43,81.2 98.3,81.07 96.01,81.07 95.38,80.44 89.66,80.44 89.41,80.18 87.76,80.18 87.5,80.44 87.5,81.53 v2(87.9,81.93)
LPDDR4_DQ15_C: length 24.8
  TOP w0.124: U3.AF30 v2(92.9,70.93)
  L05-SIG2 w0.091: v3(108.38,68.72) 107.97,68.31 107.97,67.71 107.88,67.62 107.25,67.62 107.16,67.53 107.16,67.35 107.25,67.26 107.88,67.26 107.97,67.16 107.97,66.99 107.82,66.85 99.44,66.85 98.93,67.36 97.67,67.36 97.58,67.45 97.58,67.65 97.48,67.74 97.3,67.74 97.21,67.65 97.21,67.45 97.12,67.36 96.52,67.36 96.39,67.48 96.39,68.37 96.27,68.5 95.53,68.5 95.38,68.35 95.38,67.48 95.25,67.36 93.98,67.36 93.34,67.99 93.34,70.48 v2(92.9,70.93)
LPDDR4_DQ15_D: length 39.9
  TOP w0.124: U3.AH29 v2(92.9,68.93)
  L03-SIG1 w0.091: v3(120.73,68.72) 120.32,69.13 120.01,69.13 119.76,68.88 119.76,67.74 119.51,67.48 115.57,67.48 114.81,66.72 114.17,66.72 113.79,67.1 110.72,67.1 110.63,67.01 110.63,66.81 110.54,66.72 110.35,66.72 110.26,66.81 110.26,67.01 110.17,67.1 109.99,67.1 109.9,67.01 109.9,66.81 109.81,66.72 109.62,66.72 109.53,66.81 109.53,67.01 109.44,67.1 109.26,67.1 109.17,67.01 109.17,66.81 109.07,66.72 108.89,66.72 108.8,66.81 108.8,67.01 108.71,67.1 108.53,67.1 108.43,67.01 108.43,66.81 108.34,66.72 108.16,66.72 108.07,66.81 108.07,67.01 107.98,67.1 107.79,67.1 107.7,67.01 107.7,66.81 107.61,66.72 107.43,66.72 107.34,66.81 107.34,67.01 107.25,67.1 107.06,67.1 106.97,67.01 106.97,66.81 106.88,66.72 106.7,66.72 106.61,66.81 106.61,67.01 106.51,67.1 106.33,67.1 106.24,67.01 106.24,66.81 106.15,66.72 105.97,66.72 105.87,66.81 105.87,67.01 105.78,67.1 105.6,67.1 105.51,67.01 105.51,66.81 105.42,66.72 105.23,66.72 105.14,66.81 105.14,67.01 105.05,67.1 104.87,67.1 104.78,67.01 104.78,66.81 104.69,66.72 104.5,66.72 104.41,66.81 104.41,67.01 104.32,67.1 104.14,67.1 104.05,67.01 104.05,66.81 103.95,66.72 103.77,66.72 103.68,66.81 103.68,67.09 103.59,67.18 103.41,67.18 103.31,67.09 103.31,66.81 103.22,66.72 103.04,66.72 102.95,66.81 102.95,67.14 102.86,67.23 102.67,67.23 102.58,67.14 102.58,66.81 102.49,66.72 102.31,66.72 102.22,66.81 102.22,67.14 102.13,67.23 101.94,67.23 101.85,67.14 101.85,66.81 101.76,66.72 101.58,66.72 101.49,66.81 101.49,67.01 101.39,67.1 101.21,67.1 101.12,67.01 101.12,66.81 101.03,66.72 100.23,66.72 98.68,68.27 96.61,68.27 96.46,68.12 96.25,68.12 96.09,68.27 95.88,68.27 95.73,68.12 95.51,68.12 95.36,68.27 93.32,68.27 92.9,68.69 v2(92.9,68.93)
LPDDR4_LDM_A: length 36.7
  TOP w0.127: U3.AC21 v2(84.9,73.93)
  L05-SIG2 w0.091: v2(84.9,73.93) 85.56,74.6 88.14,74.6 88.52,74.98 88.52,77.9 89.03,78.41 94.19,78.41 94.28,78.5 94.28,79.08 94.37,79.17 94.56,79.17 94.65,79.08 94.65,78.5 94.74,78.41 94.92,78.41 95.01,78.5 95.01,79.18 95.11,79.27 95.29,79.27 95.38,79.18 95.38,78.5 95.47,78.41 96.27,78.41 96.77,78.91 97.09,78.91 97.18,78.82 97.18,78.12 97.27,78.02 97.46,78.02 97.55,78.12 97.55,78.82 97.64,78.91 97.82,78.91 97.91,78.82 97.91,78.12 98.01,78.02 98.19,78.02 98.28,78.12 98.28,78.82 98.37,78.91 98.55,78.91 98.65,78.82 98.65,78.12 98.74,78.02 98.92,78.02 99.01,78.12 99.01,78.82 99.1,78.91 105.66,78.91 106.55,78.02 108.46,78.02 108.85,77.64 v3(109.03,77.64)
LPDDR4_LDM_B: length 37.3
  TOP w0.127: U3.V32 95.4,79.43 v2(95.9,78.93)
  L03-SIG1 w0.091: v2(95.9,78.93) 96.52,79.55 99.57,79.55 99.66,79.64 99.66,80.22 99.75,80.31 99.94,80.31 100.03,80.22 100.03,79.64 100.12,79.55 100.3,79.55 100.39,79.64 100.39,80.22 100.48,80.31 100.67,80.31 100.76,80.22 100.76,79.64 100.85,79.55 101.03,79.55 101.13,79.64 101.13,80.22 101.22,80.31 101.4,80.31 101.49,80.22 101.49,79.64 101.58,79.55 101.77,79.55 101.86,79.64 101.86,80.22 101.95,80.31 102.13,80.31 102.22,80.22 102.22,79.64 102.31,79.55 102.5,79.55 102.59,79.64 102.59,80.22 102.68,80.31 105.7,80.31 105.79,80.22 105.79,79.64 105.88,79.55 106.17,79.55 106.26,79.64 106.26,80.22 106.35,80.31 106.53,80.31 106.63,80.22 106.63,79.64 106.72,79.55 106.9,79.55 106.99,79.64 106.99,80.22 107.08,80.31 107.27,80.31 107.36,80.22 107.36,79.64 107.45,79.55 107.63,79.55 107.72,79.64 107.72,80.09 107.81,80.18 108,80.18 108.09,80.09 108.09,79.64 108.18,79.55 108.36,79.55 108.45,79.64 108.45,79.84 108.55,79.93 108.73,79.93 108.82,79.84 108.82,79.64 108.91,79.55 119,79.55 119.13,79.42 119.13,79.04 119.25,78.91 119.51,78.91 119.76,78.66 119.76,77.96 v3(120.08,77.64)
LPDDR4_LDM_C: length 44.4
  TOP w0.127: v2(88.9,78.93) 88.4,79.43 U3.V25
  L10-SIG3 w0.091: v3(109.03,63.92) 109.03,63.64 108.94,63.55 108.2,63.55 107.95,63.29 107.67,63.29 107.31,63.65 107.07,63.65 106.98,63.56 106.98,63.13 106.89,63.04 106.71,63.04 106.61,63.13 106.61,63.58 106.52,63.67 106.34,63.67 106.25,63.58 106.25,63.13 106.16,63.04 105.97,63.04 105.88,63.13 105.88,63.58 105.79,63.67 105.61,63.67 105.52,63.58 105.52,63.13 105.43,63.04 105.24,63.04 105.15,63.13 105.15,63.58 105.06,63.67 104.88,63.67 104.79,63.58 104.79,63.13 104.69,63.04 104.51,63.04 104.42,63.13 104.42,63.58 104.33,63.67 104.15,63.67 104.05,63.58 104.05,63.13 103.96,63.04 103.78,63.04 103.69,63.13 103.69,63.58 103.6,63.67 103.41,63.67 103.32,63.58 103.32,63.16 103.23,63.06 103.05,63.06 102.96,63.16 102.96,63.58 102.87,63.67 102.68,63.67 102.59,63.58 102.59,63.13 102.5,63.04 102.32,63.04 102.23,63.13 102.23,63.58 102.13,63.67 94.49,63.67 94.21,63.95 94.21,64.08 94.53,64.4 94.53,64.52 94.4,64.65 94.27,64.65 93.95,64.34 93.82,64.34 93.47,64.69 93.47,64.94 93.09,65.32 92.84,65.32 92.46,65.71 92.46,65.93 91.92,66.47 91.57,66.47 91.31,66.72 91.31,67.1 90.93,67.48 90.55,67.48 90.3,67.74 90.3,68.02 89.94,68.37 89.66,68.37 89.41,68.63 89.41,68.88 88.9,69.39 88.65,69.39 88.39,69.64 88.39,70.15 88.14,70.4 87.76,70.4 87.54,70.62 87.54,78.32 87.76,78.53 88.5,78.53 v2(88.9,78.93)
LPDDR4_LDM_D: length 35
  TOP w0.124: U3.AM30 v2(93.9,64.93)
  L12-SIG4 w0.091: v3(120.08,63.92) 119.76,63.6 119.76,61.61 119.67,61.51 105.61,61.51 105.51,61.42 105.51,61.23 105.42,61.13 105.24,61.13 105.15,61.23 105.15,61.42 105.06,61.51 104.87,61.51 104.78,61.42 104.78,61.15 104.69,61.06 104.51,61.06 104.42,61.15 104.42,61.42 104.33,61.51 104.14,61.51 104.05,61.42 104.05,61.15 103.96,61.06 103.78,61.06 103.69,61.15 103.69,61.42 103.59,61.51 103.41,61.51 103.32,61.42 103.32,61.15 103.23,61.06 103.05,61.06 102.95,61.15 102.95,61.42 102.86,61.51 102.64,61.51 102.54,61.42 102.54,61.15 102.45,61.06 102.27,61.06 102.18,61.15 102.18,61.42 102.09,61.51 101.9,61.51 101.81,61.42 101.81,61.15 101.72,61.06 101.54,61.06 101.45,61.15 101.45,61.42 101.36,61.51 96.52,61.51 93.9,64.14 v2(93.9,64.93)
LPDDR4_LDQS_A_N: length 34.5
  TOP w0.099: U3.AD23 v2(86.9,72.93)
  L05-SIG2 w0.081: v3(110.33,77.64) 110.33,77.55 109.91,77.13 105.28,77.13 105.08,77.33 105.08,77.99 105,78.07 104.67,78.07 104.59,77.99 104.59,77.33 104.39,77.13 103.89,77.13 103.69,77.33 103.69,77.99 103.61,78.07 103.28,78.07 103.2,77.99 103.2,77.33 103,77.13 102.5,77.13 102.3,77.33 102.3,77.99 102.22,78.07 101.89,78.07 101.81,77.99 101.81,77.33 101.61,77.13 100.98,77.13 100.77,77.33 100.77,77.86 100.69,77.94 100.37,77.94 100.29,77.86 100.29,77.33 100.08,77.13 94.87,77.13 94.62,77.39 89.7,77.39 89.49,77.18 89.49,73.62 89.19,73.33 86.98,73.33 86.9,73.24 v2(86.9,72.93)
LPDDR4_LDQS_A_P: length 34.5
  TOP w0.099: U3.AC23 v2(86.9,73.93)
  L05-SIG2 w0.081: v3(109.68,77.64) 109.76,77.72 109.91,77.72 110,77.64 110,77.52 109.82,77.34 105.37,77.34 105.29,77.42 105.29,78.08 105.09,78.28 104.59,78.28 104.39,78.08 104.39,77.42 104.3,77.34 103.98,77.34 103.9,77.42 103.9,78.08 103.69,78.28 103.2,78.28 102.99,78.08 102.99,77.42 102.91,77.34 102.59,77.34 102.51,77.42 102.51,78.08 102.3,78.28 101.8,78.28 101.6,78.08 101.6,77.42 101.52,77.34 101.06,77.34 100.98,77.42 100.98,77.95 100.78,78.15 100.28,78.15 100.08,77.95 100.08,77.42 100,77.34 94.96,77.34 94.7,77.6 89.62,77.6 89.28,77.26 89.28,73.71 89.11,73.53 86.98,73.53 86.9,73.62 v2(86.9,73.93)
LPDDR4_LDQS_B_N: length 42
  TOP w0.099: U3.W29 v2(92.9,77.93)
  L03-SIG1 w0.081: v2(92.9,77.93) 92.9,77.62 92.98,77.53 94.22,77.53 94.62,77.14 95.08,77.14 95.28,76.93 95.28,76.28 95.36,76.2 95.69,76.2 95.77,76.28 95.77,76.93 95.97,77.14 96.47,77.14 96.67,76.93 96.67,76.28 96.75,76.2 97.08,76.2 97.16,76.28 97.16,76.93 97.36,77.14 99.58,77.14 99.78,76.93 99.78,76.28 99.86,76.2 100.19,76.2 100.27,76.28 100.27,77.06 100.47,77.26 100.97,77.26 101.17,77.06 101.17,76.28 101.25,76.2 101.58,76.2 101.66,76.28 101.66,77.19 101.86,77.39 102.36,77.39 102.56,77.19 102.56,76.28 102.65,76.2 102.97,76.2 103.05,76.28 103.05,77.06 103.26,77.26 103.75,77.26 103.96,77.06 103.96,76.28 104.04,76.2 104.36,76.2 104.44,76.28 104.44,77.06 104.65,77.26 105.14,77.26 105.35,77.06 105.35,76.28 105.43,76.2 105.75,76.2 105.84,76.28 105.84,76.93 106.04,77.14 106.54,77.14 106.74,76.93 106.74,76.28 106.82,76.2 107.15,76.2 107.23,76.28 107.23,77.14 107.43,77.34 114.81,77.34 114.93,77.47 115.24,77.47 115.36,77.34 116.79,77.34 116.94,77.49 117.12,77.49 117.27,77.34 118.9,77.34 119.08,77.52 119.08,77.66 119,77.74 118.89,77.74 v3(118.78,77.64)
LPDDR4_LDQS_B_P: length 41.6
  TOP w0.099: U3.Y29 v2(92.9,76.93)
  L03-SIG1 w0.081: v2(92.9,76.93) 93.29,77.33 94.13,77.33 94.53,76.93 94.99,76.93 95.07,76.85 95.07,76.2 95.28,75.99 95.77,75.99 95.98,76.2 95.98,76.85 96.06,76.93 96.38,76.93 96.46,76.85 96.46,76.2 96.67,75.99 97.16,75.99 97.37,76.2 97.37,76.85 97.45,76.93 99.49,76.93 99.57,76.85 99.57,76.2 99.78,75.99 100.27,75.99 100.48,76.2 100.48,76.97 100.56,77.05 100.88,77.05 100.96,76.97 100.96,76.2 101.17,75.99 101.67,75.99 101.87,76.2 101.87,77.1 101.95,77.18 102.27,77.18 102.36,77.1 102.36,76.2 102.56,75.99 103.06,75.99 103.26,76.2 103.26,76.97 103.34,77.05 103.67,77.05 103.75,76.97 103.75,76.2 103.95,75.99 104.45,75.99 104.65,76.2 104.65,76.97 104.73,77.05 105.06,77.05 105.14,76.97 105.14,76.2 105.34,75.99 105.84,75.99 106.04,76.2 106.04,76.85 106.13,76.93 106.45,76.93 106.53,76.85 106.53,76.2 106.73,75.99 107.23,75.99 107.44,76.2 107.44,77.05 107.52,77.13 118.99,77.13 119.43,77.58 v3(119.43,77.64)
LPDDR4_LDQS_C_N: length 41.5
  TOP w0.099: U3.V27 90.4,79.43 v2(90.9,78.93)
  L10-SIG3 w0.081: v3(110.33,63.92) 110.19,63.92 110.11,64 110.11,64.22 109.91,64.43 102.59,64.43 102.51,64.51 102.51,64.99 102.31,65.2 101.81,65.2 101.61,64.99 101.61,64.51 101.53,64.43 101.2,64.43 101.12,64.51 101.12,64.99 100.92,65.2 100.42,65.2 100.22,64.99 100.22,64.51 100.13,64.43 99.81,64.43 99.73,64.51 99.73,64.99 99.53,65.2 99.03,65.2 98.82,64.99 98.82,64.51 98.74,64.43 95.64,64.43 93.52,66.55 92.82,66.55 92.46,66.92 92.46,67.27 92.16,67.57 91.81,67.57 91.52,67.85 91.52,68.21 91.15,68.58 90.75,68.58 90.51,68.83 90.51,69.13 90.12,69.52 89.83,69.52 89.53,69.81 89.53,70.3 89.66,70.43 89.66,70.63 89.53,70.76 89.53,71.17 89.15,71.55 88.65,71.55 88.52,71.67 88.52,72.18 88.67,72.34 88.67,72.54 88.52,72.69 88.52,74.21 88.67,74.37 88.67,74.57 88.52,74.72 88.52,75.23 88.67,75.38 88.67,75.59 88.52,75.74 88.52,76.12 88.65,76.25 88.65,76.5 88.52,76.63 88.52,77.23 88.6,77.31 89.33,77.31 89.53,77.52 89.53,79.07 89.79,79.33 90.82,79.33 90.9,79.24 v2(90.9,78.93)
LPDDR4_LDQS_C_P: length 41.1
  TOP w0.099: U3.U27 v2(90.9,79.93)
  L10-SIG3 w0.081: v2(90.9,79.93) 90.5,79.53 89.7,79.53 89.33,79.16 89.33,77.6 89.24,77.52 88.51,77.52 88.31,77.31 88.31,71.59 88.56,71.34 89.07,71.34 89.33,71.08 89.33,69.72 89.74,69.31 90.03,69.31 90.3,69.04 90.3,68.74 90.66,68.37 91.06,68.37 91.31,68.12 91.31,67.76 91.72,67.36 92.07,67.36 92.25,67.18 92.25,66.83 92.74,66.34 93.43,66.34 95.55,64.22 98.83,64.22 99.03,64.42 99.03,64.91 99.11,64.99 99.44,64.99 99.52,64.91 99.52,64.42 99.72,64.22 100.22,64.22 100.42,64.42 100.42,64.91 100.51,64.99 100.83,64.99 100.91,64.91 100.91,64.42 101.12,64.22 101.61,64.22 101.82,64.42 101.82,64.91 101.9,64.99 102.22,64.99 102.3,64.91 102.3,64.42 102.51,64.22 109.82,64.22 109.9,64.14 109.9,64 109.82,63.92 v3(109.68,63.92)
LPDDR4_LDQS_D_N: length 37.1
  TOP w0.124: U3.AK30 v2(93.9,66.93)
  L12-SIG4 w0.081: v3(118.78,63.92) 118.87,64.02 119,64.02 119.08,63.93 119.08,63.81 118.9,63.63 118.62,63.63 118.5,63.75 118.38,63.75 118.27,63.63 107.87,63.63 107.67,63.42 107.67,63.1 107.59,63.02 107.26,63.02 107.18,63.1 107.18,63.62 106.98,63.83 106.48,63.83 106.28,63.62 106.28,63.1 106.2,63.02 105.87,63.02 105.79,63.1 105.79,63.6 105.59,63.8 105.09,63.8 104.89,63.6 104.89,63.1 104.8,63.02 104.48,63.02 104.4,63.1 104.4,63.6 104.2,63.8 103.7,63.8 103.49,63.6 103.49,63.1 103.41,63.02 103.09,63.02 103.01,63.1 103.01,63.6 102.8,63.8 102.31,63.8 102.1,63.6 102.1,63.1 102.02,63.02 101.7,63.02 101.61,63.1 101.61,63.55 101.41,63.75 100.76,63.75 100.41,63.4 100.25,63.4 99.92,63.72 99.21,63.72 99,63.52 99,63.13 98.92,63.04 98.6,63.04 98.51,63.13 98.51,63.42 98.31,63.63 97.48,63.63 97.17,63.94 97.17,64.25 96.88,64.53 96.57,64.53 96.41,64.7 96.41,65 96.12,65.29 95.82,65.29 95.5,65.6 95.5,66.09 95.12,66.47 94.82,66.47 94.72,66.57 94.51,66.57 94.41,66.47 94.23,66.47 94.13,66.57 93.93,66.57 93.83,66.47 93.66,66.47 93.36,66.76 93.36,66.85 93.44,66.93 v2(93.9,66.93)
LPDDR4_LDQS_D_P: length 36.8
  TOP w0.124: U3.AK29 v2(92.9,66.93)
  L12-SIG4 w0.081: v2(92.9,66.93) 93.57,66.26 95.04,66.26 95.3,66 95.3,65.52 95.73,65.08 96.04,65.08 96.2,64.92 96.2,64.61 96.49,64.33 96.79,64.33 96.96,64.16 96.96,63.86 97.39,63.42 98.23,63.42 98.31,63.34 98.31,63.04 98.51,62.84 99.01,62.84 99.21,63.04 99.21,63.44 99.29,63.52 99.83,63.52 100.16,63.19 100.49,63.19 100.84,63.54 101.32,63.54 101.41,63.46 101.41,63.01 101.61,62.81 102.11,62.81 102.31,63.01 102.31,63.51 102.39,63.59 102.72,63.59 102.8,63.51 102.8,63.01 103,62.81 103.5,62.81 103.7,63.01 103.7,63.51 103.78,63.59 104.11,63.59 104.19,63.51 104.19,63.01 104.39,62.81 104.89,62.81 105.09,63.01 105.09,63.51 105.18,63.59 105.5,63.59 105.58,63.51 105.58,63.01 105.79,62.81 106.28,62.81 106.49,63.01 106.49,63.54 106.57,63.62 106.89,63.62 106.97,63.54 106.97,63.01 107.18,62.81 107.67,62.81 107.88,63.01 107.88,63.34 107.96,63.42 118.99,63.42 119.43,63.86 v3(119.43,63.92)
LPDDR4_RESET: length 38.5
  TOP w0.127: U3.AF34 v2(98.9,69.93)
  L05-SIG2 w0.091: v3(117.48,70.32) 117.8,70.65 117.8,71.24 118.11,71.55 118.11,72.82 117.8,73.12 117.8,83.71 v3(117.48,84.04)
  L12-SIG4 w0.091: v2(98.9,69.93) 99.77,69.06 116.99,69.06 117.14,69.21 117.14,69.99 v3(117.48,70.32)
  BOTTOM w0.127: v3(117.48,84.04) 117.14,84.37 117.14,85.72 R596.1
LPDDR4_UDM_A: length 24.3
  TOP w0.127: U3.AF33 v2(95.9,71.93)
  L10-SIG3 w0.091: v2(95.9,71.93) 95.25,72.58 95.25,76.25 103.76,84.76 108.61,84.76 108.86,84.5 109.09,84.5 109.35,84.25 109.35,83.56 v3(109.03,83.24)
LPDDR4_UDM_B: length 40.9
  TOP w0.127: U3.V22 v2(85.9,78.93)
  L12-SIG4 w0.091: v2(85.9,78.93) 86.49,79.52 86.49,80.31 87.25,81.07 87.25,83.87 87.88,84.5 99.95,84.5 100.84,85.39 116.84,85.39 117.17,85.06 117.17,84.68 117.47,84.37 117.6,84.37 117.78,84.2 117.78,83.94 118.11,83.61 119.7,83.61 v3(120.08,83.24)
LPDDR4_UDM_C: length 20.3
  TOP w0.124: U3.AG33 v2(96.9,69.93)
  L05-SIG2 w0.091: v2(96.9,69.93) 96.48,69.93 96.39,69.84 96.39,69.48 96.48,69.39 97.41,69.39 97.54,69.52 97.54,70.15 97.66,70.28 98.3,70.28 98.43,70.15 98.43,69.77 99.06,69.13 99.51,69.13 99.6,69.04 99.6,68.82 99.69,68.73 99.88,68.73 99.97,68.82 99.97,69.02 100.06,69.11 100.24,69.11 100.33,69.02 100.33,68.72 100.42,68.63 100.61,68.63 100.7,68.72 100.7,69.02 100.79,69.11 100.97,69.11 101.07,69.02 101.07,68.72 101.16,68.63 101.34,68.63 101.43,68.72 101.43,69.04 101.52,69.13 101.71,69.13 101.8,69.04 101.8,68.72 101.89,68.63 102.07,68.63 102.16,68.72 102.16,69.04 102.25,69.13 102.44,69.13 102.53,69.04 102.53,68.72 102.62,68.63 102.82,68.63 102.92,68.72 102.92,68.99 103.01,69.08 103.19,69.08 103.28,68.99 103.28,68.72 103.37,68.63 106.3,68.63 107.5,69.83 108.72,69.83 v3(109.03,69.52)
LPDDR4_UDM_D: length 40.7
  TOP w0.124: U3.AJ27 v2(89.9,67.93)
  L03-SIG1 w0.091: v2(89.9,67.93) 90.35,67.48 91.06,67.48 91.31,67.74 91.31,68.12 91.57,68.37 92.07,68.37 92.46,67.99 92.46,66.59 92.71,66.34 98.86,66.34 99.24,65.96 113.13,65.96 113.23,65.87 113.23,65.75 113.32,65.66 113.5,65.66 113.59,65.75 113.59,65.87 113.68,65.96 113.87,65.96 113.96,65.87 113.96,65.75 114.05,65.66 114.23,65.66 114.32,65.75 114.32,65.87 114.41,65.96 114.6,65.96 114.69,65.87 114.69,65.75 114.78,65.66 114.96,65.66 115.05,65.75 115.05,65.87 115.15,65.96 115.33,65.96 115.42,65.87 115.42,65.75 115.51,65.66 115.69,65.66 115.79,65.75 115.79,65.87 115.88,65.96 120.52,65.96 121.06,66.49 121.06,69.67 120.83,69.9 120.45,69.9 v3(120.08,69.52)
LPDDR4_UDQS_A_N: length 22.5
  TOP w0.099: U3.AC33 v2(96.9,73.93)
  L10-SIG3 w0.081: v2(96.9,73.93) 96.9,74.14 97.05,74.29 97.25,74.29 97.49,74.53 97.49,76.16 98.47,77.14 100.58,77.14 101.23,77.78 101.23,78.06 100.81,78.48 100.81,78.59 101.04,78.82 101.16,78.82 101.57,78.41 101.86,78.41 102.21,78.76 102.21,79.05 101.94,79.32 101.94,79.44 102.17,79.67 102.28,79.67 102.56,79.39 102.84,79.39 103.2,79.75 103.2,80.03 102.94,80.29 102.94,80.41 103.17,80.64 103.28,80.64 103.54,80.38 103.83,80.38 106.18,82.73 109.91,82.73 110.33,83.16 v3(110.33,83.24)
LPDDR4_UDQS_A_P: length 22.6
  TOP w0.099: U3.AC34 v2(96.9,74.93)
  L10-SIG3 w0.081: v2(96.9,74.93) 96.9,74.57 96.97,74.49 97.16,74.49 97.28,74.62 97.28,76.25 98.38,77.34 100.5,77.34 101.02,77.86 101.02,77.98 100.6,78.39 100.6,78.68 100.96,79.03 101.24,79.03 101.66,78.62 101.77,78.62 102,78.85 102,78.96 101.73,79.24 101.73,79.52 102.08,79.88 102.37,79.88 102.64,79.6 102.76,79.6 102.99,79.83 102.99,79.95 102.73,80.2 102.73,80.49 103.08,80.84 103.37,80.84 103.63,80.59 103.74,80.59 106.1,82.94 109.82,82.94 109.98,83.11 109.98,83.25 109.9,83.33 109.77,83.33 v3(109.68,83.24)
LPDDR4_UDQS_B_N: length 42.4
  TOP w0.099: U3.W24 v2(87.9,78.93)
  L12-SIG4 w0.081: v3(118.78,83.24) 118.99,83.24 119.5,82.73 121.62,82.73 121.72,82.63 121.72,80.66 121.58,80.52 121.2,80.52 120.93,80.79 120.46,80.79 120.18,80.52 96.81,80.52 95.84,79.55 88.61,79.55 88.26,79.21 88.26,78.66 88.14,78.53 87.58,78.53 87.41,78.7 87.41,78.83 87.63,79.04 87.79,79.04 v2(87.9,78.93)
LPDDR4_UDQS_B_P: length 42.3
  TOP w0.099: U3.W23 v2(86.9,78.93)
  L12-SIG4 w0.081: v3(119.43,83.24) 119.72,82.94 121.7,82.94 121.93,82.72 121.93,80.57 121.67,80.31 121.12,80.31 120.84,80.59 120.54,80.59 120.27,80.31 96.9,80.31 95.93,79.34 88.69,79.34 88.47,79.12 88.47,78.57 88.22,78.32 87.5,78.32 87.21,78.62 87.21,78.62 v2(86.9,78.93)
LPDDR4_UDQS_C_N: length 22.9
  TOP w0.124: v2(94.9,70.93) 94.9,70.93 U3.AG31
  L05-SIG2 w0.081: v3(110.33,69.52) 110.63,69.82 111.25,69.82 111.51,70.07 111.51,71.47 110.41,72.56 94.57,72.56 94.28,72.27 94.28,71.55 v2(94.9,70.93)
LPDDR4_UDQS_C_P: length 23
  TOP w0.124: U3.AF31 94.9,71.93 v2(94.9,71.93)
  L05-SIG2 w0.081: v3(109.68,69.52) 109.68,69.75 109.96,70.03 111.16,70.03 111.3,70.16 111.3,71.39 110.33,72.36 95.66,72.36 95.58,72.27 95.58,72.16 95.47,72.06 95.36,72.06 95.25,72.16 95.25,72.27 95.17,72.36 94.66,72.36 94.49,72.18 94.49,71.64 94.65,71.47 94.82,71.47 94.9,71.55 v2(94.9,71.93)
LPDDR4_UDQS_D_N: length 38
  TOP w0.124: v2(93.9,68.93) 93.9,68.93 U3.AJ30
  L03-SIG1 w0.081: v2(93.9,68.93) 93.9,69.24 93.98,69.33 99.35,69.33 99.84,69.82 100.43,69.82 100.51,69.74 100.51,68.78 100.72,68.58 101.21,68.58 101.42,68.78 101.42,69.86 101.5,69.94 101.82,69.94 101.91,69.86 101.91,68.78 102.11,68.58 102.61,68.58 102.81,68.78 102.81,69.86 102.89,69.94 103.22,69.94 103.3,69.86 103.3,68.78 103.5,68.58 104,68.58 104.2,68.78 104.2,69.71 104.28,69.79 104.61,69.79 104.69,69.71 104.69,68.78 104.89,68.58 105.39,68.58 105.59,68.78 105.59,69.69 105.67,69.77 106,69.77 106.08,69.69 106.08,68.78 106.28,68.58 106.78,68.58 106.99,68.78 106.99,69.74 107.07,69.82 117.61,69.82 117.72,69.7 117.86,69.7 117.98,69.82 118.27,69.82 118.36,69.72 118.52,69.72 118.61,69.82 118.9,69.82 119,69.72 119,69.6 118.92,69.52 v3(118.78,69.52)
LPDDR4_UDQS_D_P: length 38.1
  TOP w0.124: U3.AH30 93.9,69.93 v2(93.9,69.93)
  L03-SIG1 w0.081: v2(93.9,69.93) 93.9,69.62 93.98,69.53 99.27,69.53 99.76,70.03 100.52,70.03 100.72,69.82 100.72,68.87 100.8,68.78 101.13,68.78 101.21,68.87 101.21,69.95 101.41,70.15 101.91,70.15 102.11,69.95 102.11,68.87 102.2,68.78 102.52,68.78 102.6,68.87 102.6,69.95 102.8,70.15 103.3,70.15 103.51,69.95 103.51,68.87 103.59,68.78 103.91,68.78 103.99,68.87 103.99,69.8 104.2,70 104.69,70 104.9,69.8 104.9,68.87 104.98,68.78 105.3,68.78 105.39,68.87 105.39,69.78 105.59,69.98 106.09,69.98 106.29,69.78 106.29,68.87 106.37,68.78 106.7,68.78 106.78,68.87 106.78,69.82 106.98,70.03 118.99,70.03 119.43,69.58 v3(119.43,69.52)
MPM3695_SCL: length 3.1
  TOP w0.152: U120.3 140.57,71.66 141.09,72.18 141.6,72.18 141.86,72.44 R707.2
MPM3695_SDA: length 2.6
  TOP w0.152: R706.2 140.84,72.56 140.06,71.79 U120.4
MPM3695_SW1:
  vias: v1(142.37,68.25)
MPM3695_TAKE: length 3.7
  TOP w0.152: R694.1 R695.2 136.53,72.68 137.56,71.65 U120.9
ODT_CA_A: length 21.9
  L12-SIG4 w0.091: JP83.2 124.59,84.88 124.59,79.04 123.57,78.02 112.82,78.02 v3(111.63,76.84)
ODT_CA_B: length 8.9
  L12-SIG4 w0.091: JP84.2 125.98,77.26 117.9,77.26 v3(117.48,76.84)
ODT_CA_C: length 16.8
  L10-SIG3 w0.091: JP85.2 117.54,51.42 116.78,51.42 111.95,56.24 111.95,62.8 v3(111.63,63.12)
ODT_CA_D: length 9.7
  L10-SIG3 w0.091: v3(117.48,63.12) 117.8,62.8 117.8,61.31 119.13,59.99 JP86.2
PLL0V82_EN: length 97.4
  TOP w0.152: v1(142.62,100.63) 137.41,105.84 127.76,105.84 127.51,106.09 111.98,106.09 109.32,103.42 103.25,103.42 v1(103.12,103.3) ; U45.D6 v3(157.64,72.26)
  L05-SIG2 w0.091: v3(157.64,72.26) 157.64,71.97 156.21,70.53 156.21,64.04 PLL0V82_EN.1
  L12-SIG4 w0.091: v3(157.64,72.26) 157.64,72.48 158.24,73.07 158.24,74.72 159.39,75.87 159.39,81.93 157.66,83.66 157.66,98.17 155.57,100.25 143,100.25 v1(142.62,100.63)
  BOTTOM w0.127: R715.2 102.99,103.3 v1(103.12,103.3)
PLL0V82_MON: length 66.9
  TOP w0.254: R584.2 v2(100.85,62.79) ; U45.H8 v3(159.24,68.26)
  BOTTOM w0.254: v2(100.85,62.79) 105.9,57.73 146.34,57.73 150.94,62.33 152.85,62.33 155.81,65.29 157.78,65.29 158.67,66.18 158.67,67.55 159.24,68.12 v3(159.24,68.26)
PLL0V82_MON_GS: length 68.4
  TOP w0.254: R583.2 v2(99.83,62.79) ; U45.G8 v3(159.24,69.06)
  BOTTOM w0.254: v3(159.24,69.06) 159.24,68.9 158.17,67.82 158.17,66.39 157.6,65.82 155.69,65.82 152.66,62.78 150.75,62.78 146.15,58.19 106.2,58.19 101.09,63.29 100.33,63.29 v2(99.83,62.79)
PLL0V82_TRIM: length 4.2
  TOP w0.305: U45.C8 v3(159.25,73.06)
  L03-SIG1 w0.305: v2(161.67,71.94) 161.5,71.77 160.54,71.77 v3(159.25,73.06)
  BOTTOM w0.305: R564.2 v2(161.67,71.94)
PMOD2_1: length 79.9
  TOP w0.152: U3.P18 v2(81.9,83.93)
  L03-SIG1 w0.091: v2(81.9,83.93) 81.45,84.38 81.45,97.34 84.32,100.21 85.8,100.21 89.92,104.32 89.92,110.54 93.28,113.9 96.46,113.9 97.66,115.11 97.66,120.44 98.43,121.2 105.7,121.2 108.75,124.25 108.75,130.77 112.27,134.29 117.05,134.29 J6.1
PMOD2_2: length 80.1
  TOP w0.152: U3.N19 v2(82.9,84.93)
  L03-SIG1 w0.091: J6.2 122.47,136.14 119.19,132.86 119.19,125.97 116.52,123.3 112.59,123.3 111.25,121.97 111.25,117.39 106.81,112.95 98.68,112.95 96.01,110.28 96.01,103.28 93.6,100.87 90.73,100.87 89.21,99.35 85.73,99.35 83.38,97 83.38,85.41 v2(82.9,84.93)
PMOD2_3: length 80.6
  TOP w0.152: U3.N20 v2(83.9,84.93)
  L03-SIG1 w0.091: v2(83.9,84.93) 83.9,85.3 84.37,85.78 84.37,86.25 84.54,86.41 85.07,86.41 85.34,86.69 85.34,97.16 86.43,98.24 92.42,98.24 97.16,102.98 97.16,109.91 98.93,111.68 107.11,111.68 112.01,116.58 112.01,120.57 113.54,122.09 116.97,122.09 122.29,127.42 122.29,133.65 125.01,136.36 J6.3
PMOD2_4: length 83.2
  TOP w0.152: U3.P20 v2(83.9,83.93)
  L03-SIG1 w0.091: v2(83.9,83.93) 84.11,83.93 84.63,84.45 85.23,84.45 85.43,84.64 85.43,85.24 85.6,85.42 86.2,85.42 86.47,85.69 86.47,86.22 86.67,86.43 87.17,86.43 87.45,86.72 87.45,96.15 87.78,96.47 92.21,96.47 98.02,102.28 104.14,102.28 108.59,106.73 108.59,111.3 111.89,114.6 116.36,114.6 118.14,116.38 118.14,121.99 121.92,125.78 124.08,125.78 125.97,127.67 125.97,134.22 127.55,135.79 J6.4
PMOD2_5: length 84
  TOP w0.152: U3.R17 v2(79.9,82.93)
  L03-SIG1 w0.091: J6.7 118.24,138.01 118.24,136.57 116.53,134.87 104.6,134.87 101.57,131.83 97.87,131.83 92.99,126.95 92.99,114.38 89.41,110.79 89.41,104.6 85.55,100.74 84.17,100.74 81.04,97.61 81.04,84.07 v2(79.9,82.93)
PMOD2_6: length 82.9
  TOP w0.152: U3.M19 v2(82.9,85.93)
  L03-SIG1 w0.091: J6.8 121.24,138.47 121.24,136.2 118.59,133.55 112.43,133.55 110.36,131.49 110.36,117.14 106.55,113.33 93.73,113.33 90.3,109.9 90.3,103.96 86.14,99.81 85.18,99.81 82.44,97.06 82.44,86.39 v2(82.9,85.93)
PMOD2_7: length 82
  TOP w0.152: U3.M20 v2(83.9,85.93)
  L03-SIG1 w0.091: J6.9 123.82,138.51 123.82,136.35 120.82,133.35 120.82,126.79 116.5,122.47 113.16,122.47 111.63,120.95 111.63,117.01 106.93,112.31 98.68,112.31 96.52,110.16 96.52,103.07 92.29,98.84 85.94,98.84 84.44,97.34 84.44,86.84 83.9,86.29 v2(83.9,85.93)
PMOD2_8: length 86.3
  TOP w0.152: U3.P19 v2(82.9,83.93)
  L03-SIG1 w0.091: v2(82.9,83.93) 83.37,84.4 84.13,84.4 84.48,84.75 84.48,85.27 84.67,85.46 85.14,85.46 85.34,85.65 85.34,86.17 85.58,86.41 86.09,86.41 86.45,86.77 86.45,96.08 87.42,97.04 88.08,97.04 88.54,97.5 92.49,97.5 97.77,102.79 104.01,102.79 108.08,106.85 108.08,111.43 111.63,114.98 116.21,114.98 117.73,116.51 117.73,122.22 121.81,126.31 123.93,126.31 125,127.38 125,134.89 126.32,136.2 126.32,138.47 J6.10
PMOD3_1: length 68.6
  TOP w0.152: U3.P14 v2(76.9,83.93)
  L03-SIG1 w0.091: v2(76.9,83.93) 76.4,84.43 76.4,85.15 76.15,85.4 75.83,85.4 75.47,85.76 75.47,98.73 75.14,99.07 75.14,101.31 75.7,101.87 75.7,103.86 81.08,109.24 81.08,113.36 83.15,115.43 83.15,131.18 89.13,137.16 J7.1
PMOD3_2: length 67
  TOP w0.152: U3.N15 v2(77.9,84.93)
  L03-SIG1 w0.091: v2(77.9,84.93) 77.37,85.46 77.37,104.09 80.68,107.4 83.07,107.4 84.29,108.62 84.29,127.12 87.95,130.78 92.06,130.78 96.2,134.92 97.54,134.92 99.61,136.99 J7.2
PMOD3_3: length 66.5
  TOP w0.152: U3.N16 v2(78.9,84.93)
  L03-SIG1 w0.091: J7.3 102.15,136.23 99.95,134.03 98.13,134.03 89.98,125.88 87.63,125.88 85.49,123.74 85.49,108.4 83.28,106.19 80.8,106.19 79.34,104.73 79.34,85.37 v2(78.9,84.93)
PMOD3_4: length 70.1
  TOP w0.152: U3.R16 v2(78.9,82.93)
  L03-SIG1 w0.091: J7.4 104.69,136.04 100.89,132.25 97.66,132.25 92.56,127.15 92.56,114.58 88.9,110.92 88.9,105.79 86.1,102.99 82.22,102.99 81.05,101.82 81.05,100.87 80.68,100.5 80.68,84.81 80.34,84.47 79.81,84.47 79.38,84.03 79.38,83.41 v2(78.9,82.93)
PMOD3_5: length 70.5
  TOP w0.152: U3.P13 v2(75.9,83.93)
  L03-SIG1 w0.091: v2(75.9,83.93) 75.86,83.96 75.86,84.22 75.42,84.66 75.42,85.07 75.12,85.38 74.63,85.38 74.4,85.61 74.4,101.48 75.11,102.19 75.11,103.98 80.68,109.55 80.68,113.81 81.97,115.1 81.97,131.04 90.63,139.7 J7.7
PMOD3_6: length 70.6
  TOP w0.152: U3.N14 v2(76.9,84.93)
  L03-SIG1 w0.091: J7.8 98.38,138.47 98.38,136.45 97.49,135.56 88.35,135.56 83.77,130.99 83.77,115.11 81.53,112.87 81.53,108.93 76.8,104.2 76.8,96.62 76.49,96.32 76.49,85.64 76.88,85.25 76.88,84.95 v2(76.9,84.93)
PMOD3_7: length 71.5
  TOP w0.152: U3.P15 v2(77.9,83.93)
  L03-SIG1 w0.091: J7.9 100.68,138.23 100.68,136.57 98.52,134.41 96.87,134.41 92.6,130.14 88.19,130.14 84.88,126.83 84.88,108.48 83.18,106.78 80.75,106.78 78.38,104.41 78.38,84.41 v2(77.9,83.93)
PMOD3_8: length 70.4
  TOP w0.152: U3.N17 v2(79.9,84.93)
  L03-SIG1 w0.091: v2(79.9,84.93) 80.3,85.33 80.3,99.42 79.77,99.96 79.77,104.5 80.89,105.62 85.9,105.62 88.46,108.18 88.46,111.31 92,114.85 92,127.23 98.36,133.59 100.52,133.59 103.25,136.32 103.25,138.26 J7.10
POWER_DOWN: length 39.5
  TOP w0.152: U45.H7 v3(157.65,68.26)
  L03-SIG1 w0.091: v3(157.65,68.26) 158.1,68.26 158.5,67.86 159.64,67.86 160.27,67.23 160.27,65.83 159.38,64.94 157.86,64.94 156.84,63.93 156.84,62.66 155.83,61.64 152.78,61.64 149.99,58.85 148.21,58.85 v1(146.81,57.45)
  BOTTOM w0.127: R42.2 130.69,56.32 C34.1 131.96,56.31 R80.1 132.85,56.7 133.22,57.07 146.43,57.07 v1(146.81,57.45)
PROGRAMN: length 120.1
  TOP w0.127: v1(44.32,136.95) 44.07,137.21 PROGRAMN.1 44.07,139.37 JP17.1 ; v6(60.2,86.79) 55.88,91.11 55.88,102.41 57.02,103.55 61.4,103.55 63.06,105.2 63.06,110.62 59.43,114.25 59.43,115.73 60.71,117.01
  TOP w0.152: v6(60.2,86.79) 60.67,86.32 61.38,86.32 62.24,85.45 63.01,85.45 63.35,85.11 63.35,84.57 63.99,83.93 64.9,83.93 U3.P2 ; R10.2 v2(25.77,124.27)
  L10-SIG3 w0.091: 60.71,117.01 59.2,118.52 37.23,118.52 32.77,122.98 27.06,122.98 v2(25.77,124.27) 26.77,125.27 28.83,125.27 31.62,128.06 31.62,130.09 32.77,131.24 41.91,131.24 44.32,133.65 v1(44.32,136.95)
  BOTTOM w0.127: v1(44.32,136.95) 44.44,136.83 C22.1 44.2,136.21 R29.1 44.2,133.91 R27.2
  BOTTOM w0.152: R408.1 60.25,86.74 v6(60.2,86.79)
PTM_DONE: length 14
  TOP w0.152: U45.C6 v3(156.85,73.06)
  L05-SIG2 w0.091: v3(156.85,73.06) 156.45,73.45 156.45,78.4 153.53,81.32 153.53,84.77 P_DONE.1
PTM_INITN: length 23.3
  TOP w0.152: U45.C5 v3(156.05,73.06)
  L05-SIG2 w0.091: P_INITN.1 156.19,90.33 152.9,90.33 151.92,89.35 151.92,80.93 156.08,76.77 156.08,73.09 v3(156.05,73.06)
PTM_JTAGENB: length 24.6
  TOP w0.152: P_JTAGENB.1 159.14,90.32 J8.2 ; U45.B6 v3(157.64,73.86)
  L05-SIG2 w0.091: v3(157.64,73.86) 159.03,75.24 159.03,80.58 160.23,81.78 160.23,89.22 P_JTAGENB.1
PTM_PROGRAMN: length 15.1
  TOP w0.152: U45.A6 v3(156.85,74.66)
  L05-SIG2 w0.091: P_PROGN.1 154.36,86.61 154.36,81.23 156.85,78.74 v3(156.85,74.66)
PTM_SCL_18: length 59.8
  TOP w0.124: U3.AE15 v2(77.9,71.93)
  BOTTOM w0.127: v2(77.9,71.93) 77.9,71.67 78.39,71.18 78.39,70.62 78.57,70.44 79.13,70.44 79.41,70.15 79.41,69.69 79.67,69.42 80.41,69.42 80.77,69.05 80.77,61.51 84.07,58.21 90.42,58.21 95.25,53.39 104.27,53.39 105.41,52.24 105.41,50.08 106.55,48.94 106.55,36.37 107.17,35.75 U46.2
PTM_SCL_33: length 116.4
  L03-SIG1 w0.091: PTM_SCL.1 159.13,83.87 160.07,82.93 160.07,78.23 162.54,75.76 162.54,67.97 161.92,67.36 161.92,65.83 161.16,65.07 161.16,54.4 158.5,51.74 141.86,51.74 140.72,50.59 140.72,46.27 142.75,44.24 142.75,37.51 143.89,36.37 143.89,32.3 142.49,30.91 119.51,30.91 117.98,32.43 115.7,32.43 112.78,35.35 v1(112.4,35.35)
  BOTTOM w0.127: R550.1 157.23,78.78 R127.2 157.73,81.45 159.13,82.85 PTM_SCL.1 ; v1(112.4,35.35) 112,35.75 U46.13
PTM_SDA_18: length 60
  TOP w0.124: U3.AD15 v2(77.9,72.93)
  BOTTOM w0.127: v2(77.9,72.93) 77.91,72.93 78.46,72.38 78.46,71.65 78.69,71.42 79.08,71.42 79.41,71.1 79.41,70.68 79.63,70.46 80.04,70.46 81.15,69.34 81.15,61.9 84.2,58.85 90.68,58.85 95.63,53.89 104.48,53.89 105.77,52.61 105.77,50.45 106.93,49.28 106.93,36.5 107.18,36.25 U46.3
PTM_SDA_33: length 121.6
  L03-SIG1 w0.091: v1(112.4,35.99) 112.78,35.99 115.95,32.81 118.11,32.81 119.57,31.36 142.31,31.36 143.44,32.49 143.44,36.18 142.3,37.33 142.3,44.06 140.33,46.02 140.33,50.85 141.73,52.24 158.24,52.24 160.86,54.86 160.86,65.2 161.62,65.96 161.62,67.53 161.29,67.86 161.29,70.33 162.23,71.27 162.23,75.64 159.77,78.1 159.77,82.72 157.48,85.01 157.48,86.43 PTM_SDA.1
  BOTTOM w0.127: U46.12 112.13,36.25 v1(112.4,35.99) ; R126.2 155.42,81.45 154.25,82.62 154.25,83.79 154.91,84.45 154.91,85.62 156.24,86.95 PTM_SDA.1
  BOTTOM w0.152: R126.2 155.83,80.3 R549.1
PTM_TCK: length 35.5
  TOP w0.152: U45.A4 v3(155.25,74.66)
  L03-SIG1 w0.091: v2(129.59,75.82) 129.89,76.12 133.5,76.12 134.19,76.81 134.19,78.46 136.42,80.69 150.62,80.69 155.25,76.07 v3(155.25,74.66)
  BOTTOM w0.127: v2(129.59,75.82) 129.84,75.57 R77.1 130.56,75.65 J39.8
PTM_TDI: length 15
  TOP w0.152: U45.B3 v3(154.45,73.86)
  L03-SIG1 w0.091: v2(144.1,75.69) 145.2,74.6 148.72,74.6 149.1,74.98 150.37,74.98 151.49,73.86 v3(154.45,73.86)
  BOTTOM w0.127: J39.3 143.29,77.48 R78.2 143.85,75.44 v2(144.1,75.69)
PTM_TDO: length 14.2
  TOP w0.152: U45.A3 v3(154.45,74.66)
  L03-SIG1 w0.091: v2(144.95,75.69) 145.67,74.98 148.46,74.98 148.84,75.36 150.4,75.36 151.55,74.21 154,74.21 v3(154.45,74.66)
  BOTTOM w0.127: J39.2 145.83,77.48 R76.2 145.21,75.44 v2(144.95,75.69)
PTM_TMS: length 31.4
  TOP w0.152: U45.B4 v3(155.25,73.86)
  L03-SIG1 w0.091: v2(134.37,75.99) 134.57,76.2 134.57,78.18 135.99,79.6 146.99,79.6 147.55,80.16 150.6,80.16 154.84,75.92 154.84,74.27 v3(155.25,73.86)
  BOTTOM w0.127: v2(134.37,75.99) 134.92,75.44 R79.2 135.64,75.53 J39.6
PUSHBUTTON1: length 113.3
  TOP w0.127: v1(51.3,136.82) 51.3,137.22 PB1.1
  TOP w0.152: U3.AC17 v2(79.9,73.93)
  L10-SIG3 w0.091: v1(37.59,119.93) 36.92,119.93 36.2,120.66 36.2,127.55 36.62,127.98 45.89,127.98 51.3,133.39 v1(51.3,136.82)
  L12-SIG4 w0.091: v2(79.9,73.93) 79.28,74.55 72.8,74.55 72.52,74.83 72.52,78.02 72.26,78.28 64.39,78.28 64.13,78.53 53.47,78.53 46.61,85.39 46.61,99.74 45.21,101.14 44.07,101.14 38.86,106.35 38.86,118.66 v1(37.59,119.93)
  BOTTOM w0.127: R21.2 51.06,134.04 R23.1 51.3,135.41 C21.1 v1(51.3,136.82)
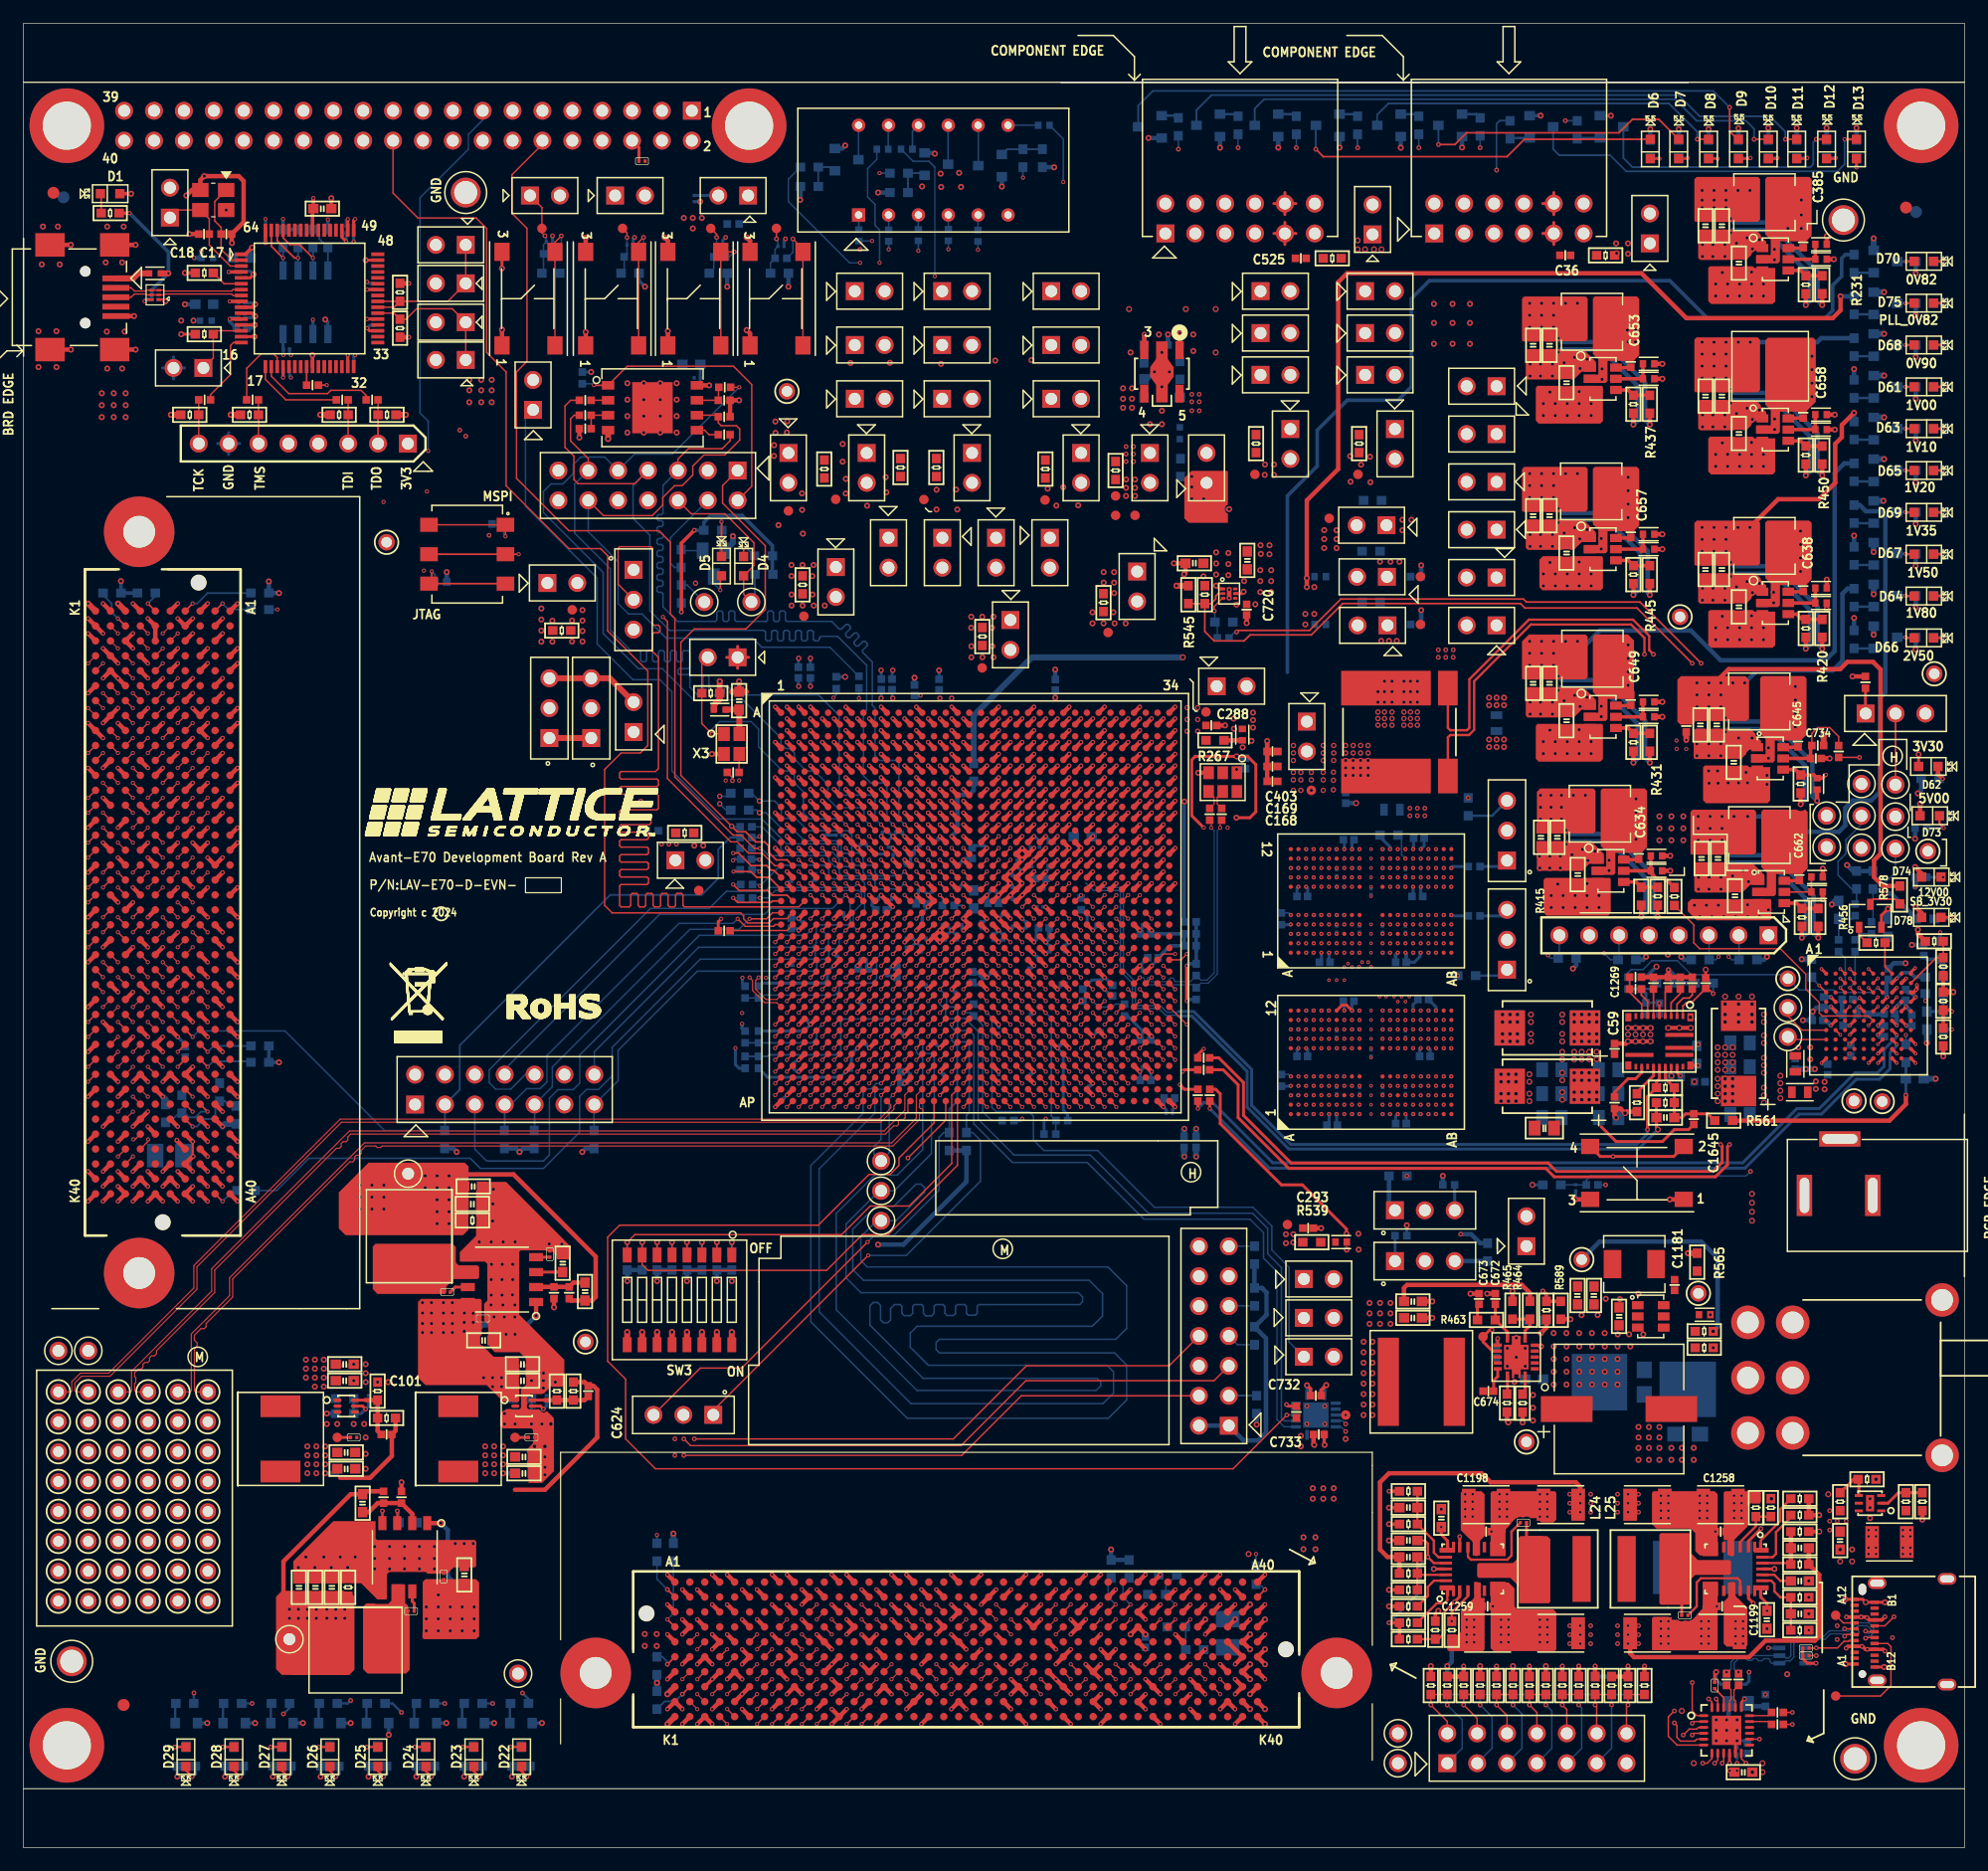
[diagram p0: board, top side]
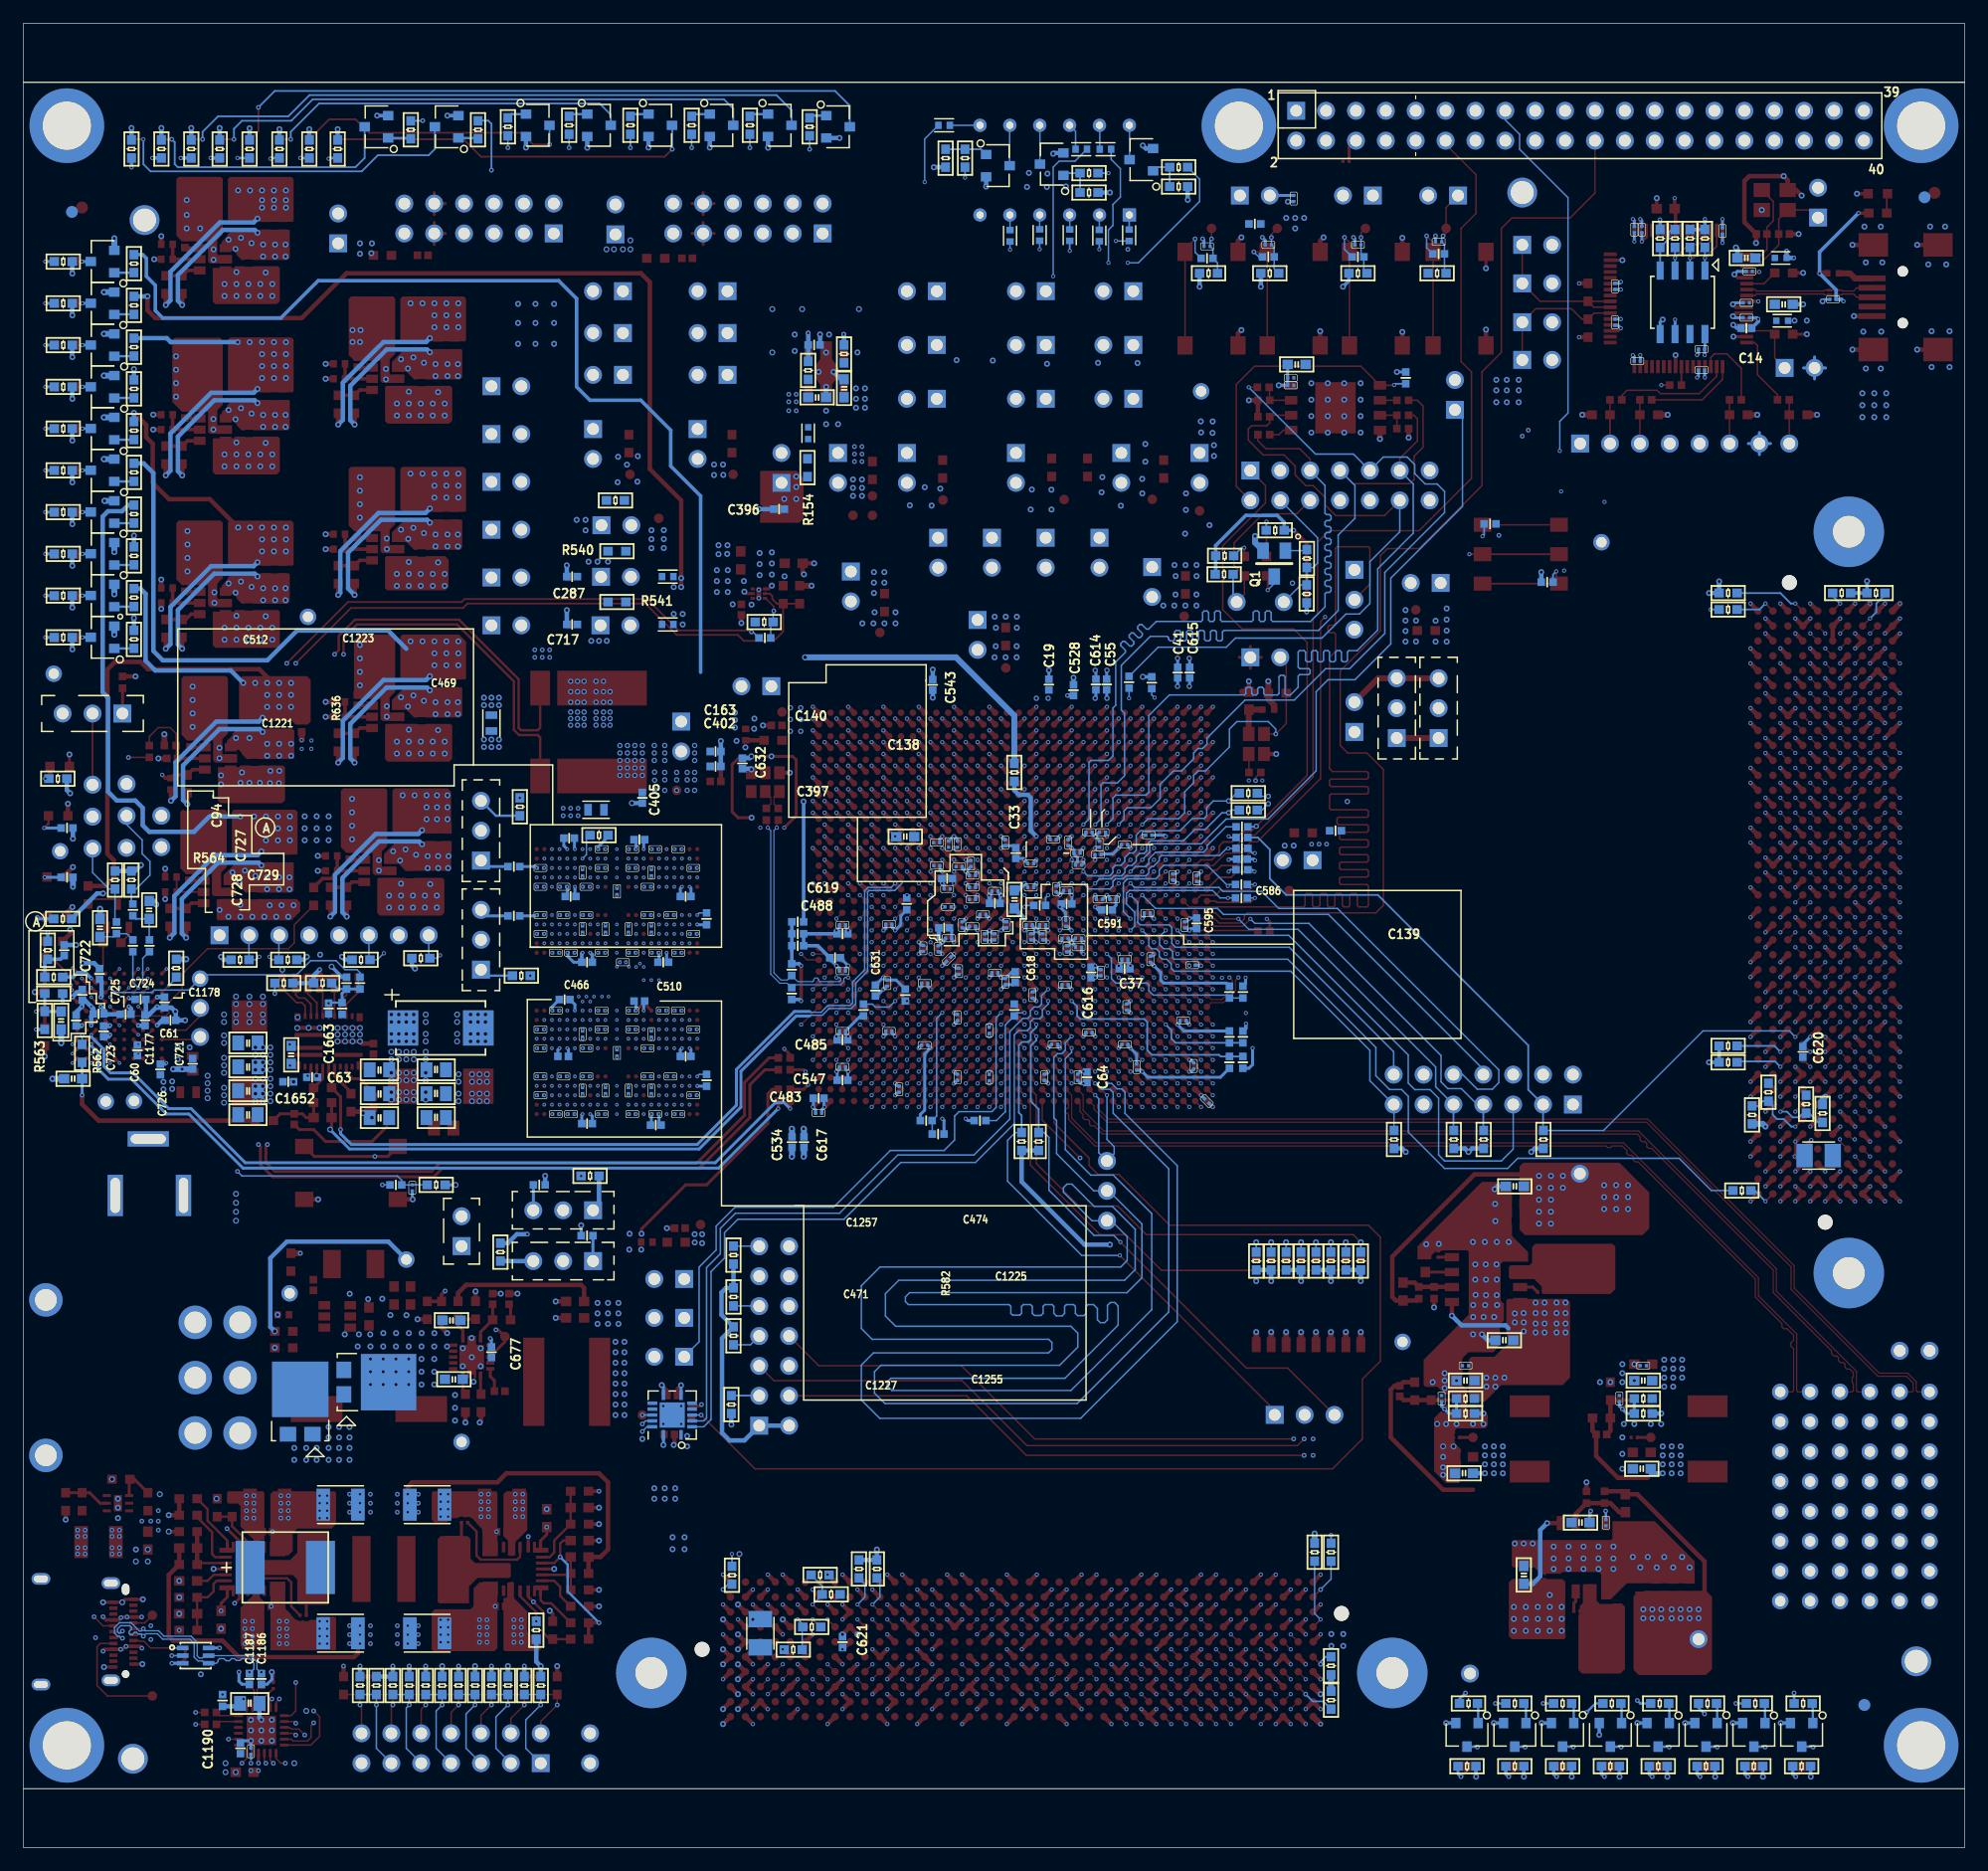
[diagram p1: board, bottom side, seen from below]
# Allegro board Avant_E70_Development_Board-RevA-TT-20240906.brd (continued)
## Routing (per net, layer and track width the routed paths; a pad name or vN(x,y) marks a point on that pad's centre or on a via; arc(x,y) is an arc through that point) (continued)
PUSHBUTTON2: length 116.8
  TOP w0.127: v1(58.92,136.82) 58.92,137.09 PB2.1
  TOP w0.152: U3.AC16 v2(78.9,73.93)
  L10-SIG3 w0.091: v1(37.08,120.44) 36.58,120.95 36.58,127.3 36.96,127.68 46.01,127.68 54.26,135.94 58.04,135.94 v1(58.92,136.82)
  L12-SIG4 w0.091: v1(37.08,120.44) 37.08,119.55 38.5,118.14 38.5,106.2 43.92,100.78 45.06,100.78 46.25,99.59 46.25,85.24 53.34,78.15 63.5,78.15 64.13,77.52 72.01,77.52 72.26,77.26 72.26,74.72 72.69,74.29 78.54,74.29 v2(78.9,73.93)
  BOTTOM w0.127: R47.2 58.68,134.17 R50.1 58.68,135.95 C26.1 v1(58.92,136.82)
PUSHBUTTON3: length 118.2
  TOP w0.127: PB3.1 v1(64.01,136.7) ; v1(75.18,58.59) 78.4,61.81 U3.AP15
  L03-SIG1 w0.091: v1(64.01,136.7) 64.9,135.81 v1(71.12,135.81)
  L05-SIG2 w0.091: v1(71.12,135.81) 71.12,136.44 71.75,137.08 80.9,137.08 84.33,133.65 84.33,108.12 82.55,106.35 81.15,106.35 80.01,105.2 80.01,100.12 80.26,99.87 80.26,80.69 80.01,80.44 79.63,80.44 78.36,79.17 78.36,78.79 77.98,78.41 77.85,78.41 77.47,78.02 77.47,70.66 77.22,70.4 75.69,70.4 75.31,70.02 75.31,67.48 75.18,67.36 72.64,67.36 72.39,67.1 72.39,61.39 v1(75.18,58.59)
  BOTTOM w0.127: v1(64.01,136.7) 64.13,136.58 C27.1 63.89,135.83 R51.1 63.5,134.66 R48.2
RASP_ID_SC: length 100.5
  TOP w0.152: U3.R12 v2(74.9,82.93)
  L05-SIG2 w0.091: v6(62.55,88.93) 60.82,88.93 59.94,88.06 59.05,88.06 56.7,90.42 56.7,98.88 53.85,101.73 51.32,101.73 49.28,103.77 49.28,108.46 48.51,109.23 40.12,109.23 39.15,110.2 39.15,119.64 32,126.79 32,136.84 JP26.28
  BOTTOM w0.127: v2(74.9,82.93) 74.54,82.57 72.67,82.57 72.4,82.85 72.4,83.27 72.2,83.47 71.71,83.47 71.38,83.8 71.38,84.12 70.99,84.51 70.66,84.51 70.41,84.76 70.41,86.03 70.03,86.41 66.67,86.41 65.63,87.45 64.63,87.45 64.42,87.66 64.42,88.37 63.86,88.93 v6(62.55,88.93) 61.89,89.59 R103.1
RASP_ID_SD: length 101.8
  TOP w0.152: U3.T11 v2(73.9,81.93)
  L05-SIG2 w0.091: JP26.27 22.74,146.53 22.74,140.38 26.19,136.93 26.19,134.01 30.79,129.41 30.79,127.37 38.79,119.37 38.79,109.75 39.74,108.8 48.17,108.8 48.84,108.12 48.84,103.4 51.03,101.22 53.7,101.22 56.3,98.61 56.3,90.16 58.71,87.75 60.07,87.75 60.25,87.93 v6(62.55,87.93)
  BOTTOM w0.127: R104.1 62.33,88.16 v6(62.55,87.93) 63.12,87.93 64.55,86.5 65.43,86.5 66.4,85.54 69.19,85.54 69.52,85.21 69.52,84.71 69.75,84.48 70.13,84.48 70.41,84.2 70.41,83.82 70.77,83.45 71.1,83.45 71.37,83.18 71.37,82.85 71.65,82.57 72.29,82.57 72.54,82.32 73.51,82.32 v2(73.9,81.93)
RASP_IO02: length 90.2
  TOP w0.152: U3.V15 v2(77.9,78.93)
  L03-SIG1 w0.091: v2(77.9,78.93) 77.46,79.37 76.78,79.37 76.38,79.78 76.38,83.13 76.1,83.41 75.62,83.41 75.29,83.74 75.29,84.14 75.03,84.4 73.72,84.4 73.45,84.67 73.45,105.59 75.51,107.64 75.51,135.1 73.15,137.46 66.54,137.46 65.15,138.85 65.15,141.52 63.88,142.79 58.8,142.79 58.02,143.57 58.02,145.57 57.24,146.35 56.39,146.35 55.15,147.59 JP26.3
RASP_IO03: length 86.5
  TOP w0.152: U3.T13 v2(75.9,81.93)
  L03-SIG1 w0.091: JP26.5 53.09,146.23 53.09,144.7 56.26,141.52 56.26,140.25 57.4,139.11 63.63,139.11 66.04,136.7 71.37,136.7 74.68,133.4 74.68,114.22 72.13,111.67 72.13,96.45 72.26,96.31 72.26,83.61 72.57,83.31 74.22,83.31 74.42,83.1 74.42,82.85 74.87,82.4 75.43,82.4 v2(75.9,81.93)
RASP_IO04: length 103.3
  TOP w0.127: U3.P6 v2(68.9,83.93)
  L05-SIG2 w0.091: v2(68.9,83.93) 68.45,84.37 66.8,84.37 66.29,84.88 66.29,85.26 65.15,86.41 64.64,86.41 64.52,86.53 64.52,100.63 59.82,105.33 59.82,107.11 58.17,108.76 55.63,108.76 54.74,109.65 54.71,109.65 53.1,111.26 50.84,111.26 50.16,111.93 45.34,111.93 43.18,114.09 43.18,119.43 44.96,121.2 44.96,133.14 41.66,136.44 41.66,139.11 37.59,143.18 36.07,143.18 35.43,143.81 35.43,148.64 36.07,149.27 47.51,149.27 JP26.7
RASP_IO05: length 104.9
  TOP w0.152: U3.V8 v2(70.9,78.93)
  L05-SIG2 w0.091: v2(62.61,81.71) 62.03,82.29 62.03,84.96 60.96,86.03 60.96,86.79 60.33,87.42 58.42,87.42 55.89,89.95 55.89,98.45 53.55,100.8 50.79,100.8 48.29,103.3 48.29,105.43 47.61,106.11 40.85,106.11 38.39,108.57 38.39,118.5 25.6,131.29 25.6,136.72 22.27,140.04 22.27,146.57 JP26.29
  BOTTOM w0.127: R108.2 62.48,81.83 v2(62.61,81.71) 64.37,83.47 68.07,83.47 68.45,83.08 68.45,82.6 68.73,82.32 71.15,82.32 71.5,81.96 71.5,79.53 v2(70.9,78.93)
RASP_IO06: length 107.2
  TOP w0.152: U3.W8 v2(70.9,77.93)
  L05-SIG2 w0.091: v2(62.61,80.69) 62.23,80.69 60.96,81.96 60.96,84.5 59.05,86.41 57.53,86.41 54.46,89.48 54.46,97.68 52.71,99.43 50.09,99.43 48.3,101.23 43.09,101.23 36.65,107.67 36.65,118.37 31.83,123.19 29.3,123.19 18.92,133.57 18.92,142.16 17.53,143.56 17.53,146.4 JP26.31
  BOTTOM w0.127: R105.2 v2(62.61,80.69) 63.28,80.69 63.92,81.33 70.99,81.33 71.25,81.07 71.25,80.18 70.54,79.47 70.54,78.29 v2(70.9,77.93)
RASP_IO07: length 63.1
  L05-SIG2 w0.091: JP26.26 27.53,146.24 27.53,148.03 28.34,148.84 34.45,148.84 35.05,148.24 35.05,141.09 37.25,138.89 38.48,138.89 44.38,133 44.38,121.68 42.66,119.96 42.66,113.55 44.66,111.55 49.32,111.55 51.86,109.01 JP65.1
RASP_IO08: length 102.9
  TOP w0.152: U3.P5 v2(67.9,83.93)
  L03-SIG1 w0.091: v2(67.9,83.93) 67.41,84.42 67.41,99.21 70.54,102.34 70.54,119.63 68.52,121.64 68.52,126.61 67.69,127.44 67.69,128.95 62.74,133.9 58.15,133.9 54.47,137.59 50.42,137.59 45.97,142.03 44.58,142.03 42.8,143.81 42.8,148.16 42.23,148.73 28.29,148.73 27.81,148.26 27.81,146.11 JP26.24
RASP_IO09: length 102.8
  TOP w0.152: U3.R5 v2(67.9,82.93)
  L03-SIG1 w0.091: JP26.21 32.64,146.36 32.64,143.12 32.55,143.03 31.97,143.03 31.88,142.94 31.88,142.67 31.97,142.58 32.55,142.58 32.64,142.48 32.64,142.21 32.55,142.12 31.71,142.12 31.62,142.03 31.62,141.75 31.71,141.66 32.55,141.66 32.64,141.57 32.64,141.29 32.55,141.2 31.71,141.2 31.62,141.11 31.62,140.84 31.71,140.75 32.55,140.75 32.64,140.65 32.64,138.6 33.02,138.22 39.37,138.22 41.87,135.72 45.81,135.72 47.88,133.65 55.37,133.65 57.62,131.4 63.09,131.4 65.93,128.55 65.93,126.37 66.63,125.67 66.63,121.12 67.21,120.54 67.21,111.33 66.17,110.28 65.28,110.28 64.53,109.53 64.53,84.55 65.63,83.45 67.38,83.45 v2(67.9,82.93)
RASP_IO10: length 104.2
  TOP w0.152: U3.R6 v2(68.9,82.93)
  L05-SIG2 w0.091: JP26.19 32.93,146.56 32.93,142.28 36.92,138.3 38.48,138.3 42.01,134.77 42.01,132.38 42.1,132.29 43.47,132.29 43.56,132.19 43.56,131.92 43.47,131.83 42.1,131.83 42.01,131.74 42.01,131.46 42.1,131.37 43.47,131.37 43.56,131.28 43.56,131.01 43.47,130.91 42.1,130.91 42.01,130.82 42.01,130.55 42.1,130.46 43.09,130.46 43.18,130.37 43.18,130.09 43.09,130 42.1,130 42.01,129.91 42.01,129.63 42.1,129.54 43.09,129.54 43.18,129.45 43.18,129.18 43.09,129.09 42.1,129.09 42.01,128.99 42.01,128.72 42.1,128.63 43.09,128.63 43.18,128.54 43.18,128.26 43.09,128.17 42.1,128.17 42.01,128.08 42.01,127.81 42.1,127.71 43.09,127.71 43.18,127.62 43.18,127.35 43.09,127.26 42.1,127.26 42.01,127.17 42.01,112.74 43.81,110.94 49,110.94 50.8,109.14 50.8,107.71 51.02,107.49 53.72,107.49 54.15,107.06 58.34,107.06 58.99,106.41 58.99,105.27 63.5,100.76 63.5,90.09 64.01,89.58 64.01,88.82 64.26,88.57 64.26,86.03 64.77,85.52 65.02,85.52 65.41,85.14 65.41,84.88 65.79,84.5 66.04,84.5 66.42,84.12 66.42,83.74 66.67,83.49 68.2,83.49 68.76,82.93 v2(68.9,82.93)
RASP_IO11: length 101.4
  TOP w0.152: U3.U12 v2(74.9,80.93)
  L03-SIG1 w0.091: v2(74.9,80.93) 74.53,80.56 69.6,80.56 69.47,80.69 69.47,80.95 69.09,81.33 68.2,81.33 67.94,81.58 66.04,81.58 65.79,81.33 64.39,81.33 62.87,82.85 62.63,82.85 v2(62.55,82.93)
  L05-SIG2 w0.091: JP26.23 30.06,146.4 30.06,144.12 36.5,137.68 38.1,137.68 41.5,134.28 41.5,112.21 43.2,110.51 48.92,110.51 50.42,109.01 50.42,107.62 50.93,107.11 52.98,107.11 53.49,106.6 53.49,104.73 54.36,103.86 54.36,102.92 57.78,99.49 57.78,91.49 59.18,90.09 62.1,90.09 62.95,89.25 62.95,83.33 v2(62.55,82.93)
  BOTTOM w0.152: R106.2 62.4,83.09 v2(62.55,82.93)
RASP_IO12: length 102.6
  TOP w0.152: U3.U5 v2(67.9,80.93)
  L03-SIG1 w0.091: JP26.32 18.71,144.28 34.81,128.19 57.91,128.19 61.85,124.25 61.85,108.89 60.79,107.82 60.79,104.55 62.23,103.1 62.23,91.11 61.59,90.47 61.59,83.36 62.53,82.42 62.94,82.42 64.29,81.07 66.04,81.07 66.29,81.33 67.5,81.33 v2(67.9,80.93)
RASP_IO13: length 106.7
  TOP w0.152: U3.R9 v2(71.9,82.93)
  L05-SIG2 w0.091: JP26.33 17.58,148.99 19.33,148.99 20.2,148.12 20.2,139.61 22.71,137.11 22.71,133.55 37.97,118.28 37.97,107.81 43.76,102.02 48.73,102.02 50.42,100.33 53.21,100.33 55.5,98.04 55.5,89.59 58.02,87.07 59.28,87.07 61.65,84.7 61.65,82.16 62.48,81.33 64.26,81.33 65.02,80.56 69.34,80.56 69.47,80.69 69.47,81.96 69.98,82.47 71.44,82.47 v2(71.9,82.93)
RASP_IO14: length 89.6
  TOP w0.152: U3.V14 v2(76.9,78.93)
  L03-SIG1 w0.091: v2(76.9,78.93) 76.67,78.93 75.56,80.03 75.56,81.19 75.18,81.58 71.47,81.58 71.37,81.68 71.37,82.22 71.12,82.47 70.74,82.47 70.4,82.81 70.4,96.11 71.45,97.16 71.45,112.27 73.91,114.73 73.91,119.43 71.75,121.59 71.75,128.77 65.85,134.67 58.42,134.67 54.61,138.48 54.61,141.52 53.56,142.58 51.01,142.58 49.19,144.39 JP26.8
RASP_IO15: length 96.4
  TOP w0.152: U3.R13 v2(75.9,82.93)
  L03-SIG1 w0.091: v2(75.9,82.93) 75.49,82.93 74.86,83.56 72.66,83.56 72.52,83.7 72.52,105.21 75.06,107.76 75.06,135.02 72.98,137.1 66.15,137.1 64.58,138.67 64.58,141.33 63.5,142.41 57.53,142.41 55.52,144.42 55.52,145.61 54.85,146.28 53.65,146.28 53.07,146.86 53.07,148.1 52.42,148.75 48.67,148.75 47.84,147.92 47.84,146.23 JP26.10
RASP_IO16: length 105.1
  TOP w0.127: U3.N6 v2(68.9,84.93)
  L10-SIG3 w0.091: v2(68.9,84.93) 68.9,85.58 68.45,86.03 68.45,96.44 69.22,97.2 69.22,100.25 63.75,105.71 63.75,106.47 61.98,108.25 61.98,112.31 61.21,113.08 44.96,113.08 40.89,117.14 37.46,117.14 33.53,121.08 24.38,121.08 16.76,128.7 16.76,136.19 19.3,138.73 19.3,142.29 18.16,143.43 15.11,143.43 13.63,144.91 JP26.36
RASP_IO17: length 100.4
  TOP w0.152: U3.V16 v2(78.9,78.93)
  L03-SIG1 w0.091: JP26.11 45.21,146.49 45.21,144.19 47.75,141.66 53.66,141.66 54.23,141.09 54.23,138.35 58.29,134.29 65.01,134.29 68.45,130.85 68.45,127.81 69.22,127.05 69.22,122.6 72.78,119.04 72.78,114.22 70.97,112.42 70.97,102.13 68.4,99.56 68.4,83.56 68.63,83.33 69.11,83.33 69.35,83.09 69.35,82.71 69.6,82.47 70.23,82.47 70.49,82.22 70.49,81.71 70.74,81.45 71.12,81.45 71.25,81.33 75.06,81.33 75.34,81.04 75.34,78.79 75.59,78.55 78.51,78.55 v2(78.9,78.93)
RASP_IO18: length 91.7
  TOP w0.127: v2(62.59,84.9) 62.13,84.9 61.01,86.03 60.33,86.03 55.37,90.98 55.37,104.44 54.99,104.82 54.99,110.92 54.01,111.9 46.36,111.9 41.91,116.35 41.91,125.4 42.8,126.28 42.8,137.59 41.53,138.86 41.53,142.16 44.11,144.74 JP26.12
  TOP w0.152: U3.T12 v2(74.9,81.93)
  BOTTOM w0.127: R107.2 v2(62.59,84.9) 62.72,84.9 63.32,84.3 68.28,84.3 68.45,84.12 68.45,83.87 68.96,83.36 69.09,83.36 69.34,83.1 69.34,82.81 69.58,82.57 71.27,82.57 71.53,82.32 72.16,82.32 72.39,82.09 72.39,81.71 72.64,81.45 74.42,81.45 v2(74.9,81.93)
RASP_IO19: length 126.8
  TOP w0.152: U3.R11 v2(73.9,82.93)
  L03-SIG1 w0.091: JP26.35 15.19,149.14 44.2,149.14 45.59,147.75 45.59,144.57 46.23,143.94 47.37,143.94 47.88,144.45 47.88,145.46 48.77,146.35 49.78,146.35 50.55,145.59 50.55,144.19 51.5,143.24 53.78,143.24 55.05,141.97 55.05,138.54 58.55,135.05 66.19,135.05 72.14,129.1 72.14,121.97 74.29,119.81 74.29,114.47 71.75,111.93 71.75,96.75 71.35,96.35 71.35,82.72 71.68,82.4 73.37,82.4 v2(73.9,82.93)
RASP_IO20: length 112
  TOP w0.152: U3.T6 v2(68.9,81.93)
  L03-SIG1 w0.091: v2(68.9,81.93) 68.26,82.57 64.67,82.57 63.37,83.87 63.37,85.9 63.12,86.15 63.12,99.82 63.63,100.32 63.63,109.77 62.87,110.53 62.87,126.06 58.47,130.46 56.97,130.46 55.75,131.68 34.64,131.68 31.4,134.92 31.4,136.01 25.99,141.41 23.06,141.41 20.1,144.37 20.1,145.82 19.61,146.31 12.35,146.31 JP26.38
RASP_IO21: length 112.7
  TOP w0.152: U3.U6 v2(68.9,80.93)
  L03-SIG1 w0.091: JP26.40 10.84,142.76 16.92,142.76 22.2,137.48 23.48,137.48 29.07,131.89 30.15,131.89 34.35,127.68 57.4,127.68 59.44,125.65 59.44,113.84 58.93,113.33 58.93,110.54 60.34,109.12 60.34,104.3 61.85,102.79 61.85,91.23 61.24,90.62 61.24,83.08 62.23,82.09 62.74,82.09 64.26,80.56 68.53,80.56 v2(68.9,80.93)
RASP_IO22: length 93.2
  TOP w0.152: U3.W6 v2(68.9,77.93)
  L03-SIG1 w0.091: v2(68.9,77.93) 68.42,78.41 64.01,78.41 62.36,80.06 62.36,80.44 60.58,82.22 59.69,82.22 59.18,82.72 59.18,85.01 54.74,89.45 54.74,97.33 49.15,102.92 49.15,108.89 46.86,111.17 44.07,111.17 37.21,118.03 35.05,118.03 v2(34.4,118.68)
  BOTTOM w0.127: JP26.15 39.03,146.8 37.82,145.59 37.82,144.32 33.71,140.2 33.71,121.89 34.4,121.19 v2(34.4,118.68)
RASP_IO23: length 102.4
  TOP w0.152: U3.P4 v2(66.9,83.93)
  L03-SIG1 w0.091: v2(66.9,83.93) 66.49,84.34 66.49,98.88 70.16,102.55 70.16,113.98 69.1,115.04 69.1,119.92 67.91,121.11 67.91,126.29 67.16,127.04 67.16,128.72 62.34,133.54 57.51,133.54 56,135.05 50.14,135.05 50.05,135.14 50.05,135.72 49.96,135.81 49.68,135.81 49.59,135.72 49.59,135.14 49.5,135.05 48.64,135.05 46.1,137.59 45.47,137.59 45.38,137.68 45.38,138.77 45.29,138.86 45.02,138.86 44.93,138.77 44.93,137.68 44.83,137.59 44.56,137.59 44.47,137.68 44.47,138.77 44.38,138.86 44.1,138.86 44.01,138.77 44.01,137.68 43.92,137.59 43.65,137.59 43.55,137.68 43.55,138.77 43.46,138.86 43.19,138.86 43.1,138.77 43.1,137.68 43.01,137.59 42.16,137.59 40.13,139.62 40.13,140.01 40.22,140.1 41.18,140.1 41.27,140.19 41.27,140.46 41.18,140.56 40.22,140.56 40.13,140.65 40.13,140.92 40.22,141.01 41.18,141.01 41.27,141.1 41.27,141.38 41.18,141.47 40.22,141.47 40.13,141.56 40.13,141.84 40.22,141.93 41.18,141.93 41.27,142.02 41.27,142.29 41.18,142.38 40.22,142.38 40.13,142.48 40.13,142.75 40.22,142.84 41.18,142.84 41.27,142.93 41.27,143.21 41.18,143.3 40.22,143.3 40.13,143.39 40.13,143.95 JP26.16
RASP_IO24: length 103.5
  TOP w0.152: U3.N5 v2(67.9,84.93)
  L05-SIG2 w0.091: v2(67.9,84.93) 67.44,85.39 66.67,85.39 65.53,86.53 65.53,98.22 65.02,98.73 65.02,100.76 60.2,105.58 60.2,107.23 58.17,109.27 56.18,109.27 53.66,111.78 51.73,111.78 50.99,112.53 45.64,112.53 43.93,114.24 43.93,119.16 45.59,120.82 45.59,127.55 45.68,127.64 46.64,127.64 46.74,127.73 46.74,128.01 46.64,128.1 45.68,128.1 45.59,128.19 45.59,128.46 45.68,128.55 46.64,128.55 46.74,128.65 46.74,128.92 46.64,129.01 45.68,129.01 45.59,129.1 45.59,129.38 45.68,129.47 46.64,129.47 46.74,129.56 46.74,129.83 46.64,129.93 45.68,129.93 45.59,130.02 45.59,130.29 45.68,130.38 46.64,130.38 46.74,130.47 46.74,130.75 46.64,130.84 45.68,130.84 45.59,130.93 45.59,131.21 45.68,131.3 46.64,131.3 46.74,131.39 46.74,131.66 46.64,131.75 45.68,131.75 45.59,131.85 45.59,132.12 45.68,132.21 46.9,132.21 46.99,132.3 46.99,132.58 46.9,132.67 45.68,132.67 45.59,132.76 45.59,133.4 44.7,134.29 44.7,134.42 45.14,134.86 45.14,134.99 44.95,135.18 44.82,135.18 44.38,134.74 44.25,134.74 44.05,134.94 44.05,135.07 44.5,135.51 44.5,135.64 44.3,135.83 44.17,135.83 43.73,135.39 43.6,135.39 43.41,135.58 43.41,135.71 43.85,136.15 43.85,136.28 43.66,136.48 43.53,136.48 43.08,136.04 42.95,136.04 42.16,136.83 42.16,139.38 41.08,140.46 41.08,140.59 41.64,141.16 41.64,141.29 41.45,141.48 41.32,141.48 40.75,140.92 40.62,140.92 40.43,141.11 40.43,141.24 40.99,141.8 40.99,141.93 40.8,142.13 40.67,142.13 40.11,141.56 39.98,141.56 39.78,141.76 39.78,141.89 40.35,142.45 40.35,142.58 40.15,142.77 40.02,142.77 39.46,142.21 39.33,142.21 JP26.18
RASP_IO25: length 98
  TOP w0.127: JP26.22 31.41,140.59 33.53,138.48 38.48,138.48 39.37,137.59 39.37,127.05 41.02,125.4 41.02,115.72 46.36,110.38 49.05,110.38 49.66,109.77 49.66,103.39 53.07,99.98 53.07,93.65 52.43,93.01 50.8,93.01 49.4,91.61 49.4,80.06 50.04,79.42 60.96,79.42 61.21,79.17 61.21,78.91 61.57,78.56 63.37,78.56 63.74,78.93 64.9,78.93 U3.V2
RASP_IO26: length 114.1
  TOP w0.152: U3.T9 v2(71.9,81.93)
  L05-SIG2 w0.091: v2(71.9,81.93) 71.5,81.53 70.56,81.53 70.36,81.33 70.36,80.44 70.23,80.31 64.77,80.31 64.01,81.07 62.36,81.07 61.31,82.12 61.31,84.59 59.14,86.75 57.82,86.75 55.02,89.56 55.02,97.84 52.96,99.89 50.39,99.89 48.77,101.52 43.37,101.52 37.44,107.45 37.44,118.06 31.56,123.93 29.35,123.93 20.72,132.56 20.72,135.51 19.81,136.41 19.81,148 19.18,148.64 18.03,148.64 17.4,148 17.4,146.99 16.76,146.35 12.33,146.35 JP26.37
RASP_IO27: length 101.2
  TOP w0.152: U3.P3 v2(65.9,83.93)
  L03-SIG1 w0.091: JP26.13 40.27,146.28 35.36,146.28 35.18,146.1 35.18,143.19 35.09,143.1 34.38,143.1 34.29,143.01 34.29,142.73 34.38,142.64 35.09,142.64 35.18,142.55 35.18,142.28 35.09,142.18 34.38,142.18 34.29,142.09 34.29,141.82 34.38,141.73 35.09,141.73 35.18,141.64 35.18,141.36 35.09,141.27 34.38,141.27 34.29,141.18 34.29,140.9 34.38,140.81 35.09,140.81 35.18,140.72 35.18,139.49 35.94,138.73 39.88,138.73 42.06,136.55 45.94,136.55 48.13,134.36 55.55,134.36 58.04,131.87 63.37,131.87 66.48,128.77 66.48,126.69 67.24,125.92 67.24,121.14 67.64,120.75 67.64,101.04 65.46,98.87 65.46,84.37 v2(65.9,83.93)
RXD_UART: length 103
  TOP w0.152: U3.R3 v2(65.9,82.93)
  L03-SIG1 w0.091: v2(65.9,82.93) 65.6,82.93 64.26,84.27 64.26,85.52 63.5,86.28 63.5,98.9 64.01,99.41 64.01,110.54 66.77,113.3 66.77,120.22 66.22,120.77 66.22,125.38 65.44,126.17 65.44,128.29 62.87,130.86 57.4,130.86 55.13,133.13 46.5,133.13 46.35,133.27 46.35,134.07 46.26,134.16 45.86,134.16 45.76,134.07 45.76,133.23 45.67,133.14 45.4,133.14 45.31,133.23 45.31,134.58 45.22,134.67 44.94,134.67 44.85,134.58 44.85,133.23 44.76,133.14 44.48,133.14 44.39,133.23 44.39,134.58 44.3,134.67 44.03,134.67 43.94,134.58 43.94,133.23 43.84,133.14 43.57,133.14 43.48,133.23 43.48,134.58 43.39,134.67 43.11,134.67 43.02,134.58 43.02,133.23 42.93,133.14 42.66,133.14 42.56,133.23 42.56,134.58 42.47,134.67 42.2,134.67 42.11,134.58 42.11,133.23 42.02,133.14 41.74,133.14 41.65,133.23 41.65,134.58 41.56,134.67 39.34,134.67 39.25,134.58 39.25,134 39.16,133.9 38.89,133.9 38.8,134 38.8,134.58 38.7,134.67 38.43,134.67 38.34,134.58 38.34,134 38.25,133.9 37.97,133.9 37.88,134 37.88,134.58 37.79,134.67 37.52,134.67 37.42,134.58 37.42,134 37.33,133.9 37.06,133.9 36.97,134 36.97,134.58 36.88,134.67 36.6,134.67 36.51,134.58 36.51,134 36.42,133.9 36.14,133.9 36.05,134 36.05,134.58 35.96,134.67 35.18,134.67 35.05,134.54 35.05,132.92
SB_3V30: length 47.2
  TOP w0.381: R585.2 v4(155.48,99.52)
  L12-SIG4 w0.381: v4(155.48,99.52) 154.81,98.85 154.81,83.69 v4(155.02,83.49)
  BOTTOM w0.254: R42.1 v5(128.27,56.31)
  BOTTOM w0.381: R76.1 147.95,75.44 v4(148.21,75.69) ; v4(158.24,81.07) 158.75,81.07 R567.2 ; v4(137.93,75.69) 137.67,75.44 R79.1 ; SB_3V30.1 133.98,51.48 142.62,51.48 144.02,50.08 144.02,44.24 v5(143.64,43.86) ; R127.1 R126.1 155.52,82.98 v4(155.02,83.49) ; v4(140.92,75.69) 141.17,75.44 R78.1
  BOTTOM w0.508: R81.1 v4(151.17,75.48)
SCL: length 57
  L05-SIG2 w0.091: v6(59.18,89.33) 57.4,91.11 57.4,99.26 53.82,102.85 53.82,103.77 52.82,104.77 51.49,104.77 50.04,106.22 50.04,108.89 48.89,110.03 43.05,110.03 40.8,112.28 40.8,126.64 39.62,127.81 36.45,127.81 35.05,126.41
  BOTTOM w0.127: v6(59.18,89.33) 59.86,89.33 R103.2
SDA: length 65.6
  L05-SIG2 w0.091: v6(59.18,88.69) 59.13,88.69 57.05,90.78 57.05,99.1 53.91,102.24 51.6,102.24 49.66,104.18 49.66,108.63 48.77,109.52 41.53,109.52 40.36,110.69 40.36,119.07 33.4,126.03 33.4,134.54 35.05,136.19
  BOTTOM w0.127: v6(59.18,88.69) 59.72,88.16 R104.2
SEG_A: length 71.4
  TOP w0.152: U3.V10 v2(72.9,78.93)
  L05-SIG2 w0.091: v2(72.77,134.67) 73.41,134.67 76.05,132.02 76.05,100.22 76.65,99.62 76.65,97.15 76.28,96.77 76.28,82.55 76.07,82.34 75.69,82.34 75.44,82.09 75.44,81.71 75.06,81.33 73.61,81.33 73.37,81.09 73.37,80.53 72.9,80.06 v2(72.9,78.93)
  BOTTOM w0.127: v2(72.77,134.67) 72.77,137.46 72.39,137.84 72.39,139.62 71.75,140.25 71.75,142.67 72.54,143.45 R332.2
SEG_B: length 85.5
  TOP w0.152: U3.T10 v2(72.9,81.93)
  L05-SIG2 w0.091: v2(72.9,81.93) 72.9,82.22 73.28,82.6 75.18,82.6 75.28,82.69 75.28,96.61 74.9,96.99 74.9,100.62 75.21,100.93 75.21,127.91 71.88,131.24 71.88,132.93 70.4,134.41 70.4,136.74 72.26,138.6 72.26,139.11 73.79,140.64 87.5,140.64 v2(88.39,141.52)
  BOTTOM w0.127: R333.2 88.39,145.18 v2(88.39,141.52)
SEG_C: length 66.6
  TOP w0.152: U3.V12 v2(74.9,78.93)
  L05-SIG2 w0.091: v2(74.9,78.93) 75.27,78.56 76.23,78.56 76.45,78.79 76.45,79.04 76.71,79.29 77.22,79.29 78.51,80.59 78.51,98.62 79.25,99.36 79.25,105.71 81.15,107.62 81.15,112.82 83.57,115.24 83.57,132.62 80.37,135.82 v2(78.62,135.82)
  BOTTOM w0.127: R334.2 v2(78.62,135.82)
SEG_D: length 69.5
  TOP w0.152: U3.V13 v2(75.9,78.93)
  L05-SIG2 w0.091: v2(73.55,135.81) 73.93,136.19 77.09,136.19 78.24,135.04 80.34,135.04 83.19,132.2 83.19,115.36 80.77,112.95 80.77,107.87 78.9,106 78.9,99.65 78.28,99.03 78.28,80.74 77.09,79.55 76.52,79.55 v2(75.9,78.93)
  BOTTOM w0.152: v2(73.55,135.81) R335.2
SEG_DP: length 67.6
  TOP w0.152: U3.W11 v2(73.9,77.93)
  L05-SIG2 w0.091: v2(76.06,135.68) 77.51,134.23 80.35,134.23 81.91,132.67 81.91,114.73 80.19,113 80.19,107.84 78.49,106.14 78.49,99.94 77.52,98.97 77.52,80.62 77.22,80.31 76.71,80.31 75.83,79.43 74.75,79.43 74.39,79.07 74.39,78.42 v2(73.9,77.93)
  BOTTOM w0.152: R331.2 v2(76.06,135.68)
SEG_E: length 65.5
  TOP w0.152: U3.W10 v2(72.9,77.93)
  L05-SIG2 w0.091: v2(72.14,136.52) 76.51,132.15 76.51,101.15 76.96,100.7 76.96,96.69 76.53,96.26 76.53,82.42 76.33,82.22 76.33,80.69 76.03,80.4 73.74,80.4 73.47,80.12 73.47,78.5 v2(72.9,77.93)
  BOTTOM w0.127: R336.2 v2(72.14,136.52)
SEG_F: length 73.9
  TOP w0.152: U3.V11 v2(73.9,78.93)
  L05-SIG2 w0.091: v2(77.47,133.52) 78.69,133.52 79.44,132.78 79.44,119.24 78.49,118.28 78.49,113.35 79.65,112.19 79.65,108.01 77.27,105.63 77.27,80.74 77.09,80.57 76.58,80.57 75.85,79.84 74.57,79.84 73.9,79.16 v2(73.9,78.93)
  BOTTOM w0.127: v2(77.47,133.52) 77.47,142.79 76.96,143.3 75.61,143.3 R337.2
SEG_G: length 66.2
  TOP w0.152: U3.W12 v2(74.9,77.93)
  L05-SIG2 w0.091: v2(74.9,77.93) 75.27,78.3 76.99,78.3 77.34,78.66 77.34,78.91 78.61,80.18 78.87,80.18 79.5,80.82 79.5,98.85 79.63,98.98 79.63,105.46 80.9,106.73 82.42,106.73 83.95,108.25 83.95,132.97 v2(81.14,135.78)
  BOTTOM w0.127: R338.2 v2(81.14,135.78)
SHORT_STUB_TRACE: length 13.5
  TOP w0.152: U3.AN10 v2(72.9,63.93) ; U3.AN11 v2(73.9,63.93)
  BOTTOM w0.127: v2(72.9,63.93) 72.9,60.17 72.29,59.56 72.29,58.95 ST.1 73.59,59.04 73.59,63.62 v2(73.9,63.93)
SPI_MCLK: length 55.1
  TOP w0.127: J3.12 49.3,113.18 53.44,113.18 54.34,114.07 54.34,114.71 55.35,115.73 55.99,115.73 56.89,116.63 56.89,117.39 57.84,118.33 59.61,118.33 60.88,119.6 60.88,120.54 60.6,120.82 59.31,120.82 59.06,121.07 R40.2 58.94,121.71 U4.6
  BOTTOM w0.127: J3.12 48.01,111.81 50.55,109.27 50.55,105.71 51.44,104.82 52.58,104.82 54.63,102.77 61.98,102.77 62.75,102 68.55,102 R20.1
SYNC_IN: length 34
  TOP w0.203: R615.2 R616.2 120.27,17.7 120.78,18.21 120.78,20 v1(121.66,20.88)
  TOP w0.254: U111.16 146.64,21.17 v1(147.06,20.76) ; v1(121.66,20.88) 122.09,21.31 U110.3
  L05-SIG2 w0.254: v1(147.06,20.76) 146.29,19.99 122.55,19.99 v1(121.66,20.88)
SYNC_OUT: length 29
  TOP w0.254: v1(147.7,27.1) 146.64,26.04 U111.3 ; U110.16 v1(122.09,26.42)
  L05-SIG2 w0.254: v1(147.7,27.1) 147.45,27.35 123.02,27.35 v1(122.09,26.42)
TCK: length 80.9
  TOP w0.127: R6.2 R5.1 J1.8
  TOP w0.152: U3.T1 63.38,82.44 62.33,82.44 61.84,82.93 v2(60.36,82.93)
  L03-SIG1 w0.091: v2(60.36,82.93) 60.71,83.28 60.71,85.14 60.2,85.64 59.69,85.64 55.63,89.7 55.63,97.42 49.86,103.19 49.86,109.4 47.07,112.19 44.4,112.19 37.55,119.03 35.79,119.03 33.77,121.06 16.64,121.06 J1.8
  BOTTOM w0.152: R106.1 60.52,83.09 v2(60.36,82.93)
TDI: length 67.6
  TOP w0.127: J1.3 R3.2 R7.2
  TOP w0.152: v2(60.33,80.69) 60.71,80.31 63.54,80.31 63.66,80.43 U3.U1
  L03-SIG1 w0.091: J1.3 29.74,117.16 36.76,117.16 43.64,110.28 46.35,110.28 48.44,108.2 48.44,102.47 53.72,97.18 53.72,89.2 56.01,86.91 56.01,84.88 56.52,84.37 56.52,82.72 58.55,80.69 v2(60.33,80.69)
  BOTTOM w0.127: R105.1 v2(60.33,80.69)
TDO: length 66
  TOP w0.127: R4.2 R8.2
  TOP w0.152: v2(60.33,81.83) 60.83,81.33 63.25,81.33 63.65,80.93 64.9,80.93 U3.U2 ; J1.2 R4.2
  L03-SIG1 w0.091: J1.2 31.78,117.66 36.96,117.66 43.85,110.77 46.63,110.77 48.83,108.57 48.83,102.73 54.23,97.33 54.23,89.33 56.39,87.17 56.39,85.01 56.9,84.5 56.9,82.98 58.04,81.83 v2(60.33,81.83)
  BOTTOM w0.127: R108.1 v2(60.33,81.83)
TMS: length 73.3
  TOP w0.127: J1.6 R2.2 R9.2
  TOP w0.152: U3.R1 63.78,83.05 63.56,83.05 63.17,83.44 61.85,83.44 60.79,84.5 v2(60.33,84.5)
  L03-SIG1 w0.091: v2(60.33,84.5) 55.24,89.58 55.24,97.33 49.53,103.04 49.53,109.05 46.9,111.68 44.23,111.68 37.45,118.46 35.68,118.46 33.53,120.61 21.28,120.61 J1.6
  BOTTOM w0.152: R107.1 60.52,84.5 v2(60.33,84.5)
TXD_UART: length 102.9
  TOP w0.152: U3.T3 v2(65.9,81.93)
  L03-SIG1 w0.091: 35.05,129.62 36.29,130.86 40.55,130.86 40.64,130.77 40.64,129.93 40.73,129.84 41.01,129.84 41.1,129.93 41.1,130.77 41.19,130.86 41.46,130.86 41.55,130.77 41.55,129.93 41.65,129.84 41.92,129.84 42.01,129.93 42.01,130.77 42.1,130.86 42.38,130.86 42.47,130.77 42.47,129.93 42.56,129.84 42.83,129.84 42.93,129.93 42.93,130.77 43.02,130.86 43.29,130.86 43.38,130.77 43.38,129.93 43.47,129.84 43.75,129.84 43.84,129.93 43.84,130.77 43.93,130.86 44.21,130.86 44.3,130.77 44.3,129.93 44.39,129.84 44.66,129.84 44.76,129.93 44.76,130.77 44.85,130.86 45.12,130.86 45.21,130.77 45.21,129.93 45.3,129.84 45.58,129.84 45.67,129.93 45.67,130.77 45.76,130.86 46.04,130.86 46.13,130.77 46.13,129.93 46.22,129.84 46.49,129.84 46.58,129.93 46.58,130.77 46.68,130.86 46.95,130.86 47.04,130.77 47.04,129.93 47.13,129.84 47.41,129.84 47.5,129.93 47.5,130.77 47.59,130.86 47.86,130.86 47.96,130.77 47.96,129.93 48.05,129.84 48.32,129.84 48.41,129.93 48.41,130.77 48.5,130.86 48.78,130.86 48.87,130.77 48.87,129.93 48.96,129.84 49.24,129.84 49.33,129.93 49.33,130.77 49.42,130.86 49.69,130.86 49.78,130.77 49.78,129.93 49.88,129.84 50.15,129.84 50.24,129.93 50.24,130.77 50.33,130.86 50.61,130.86 50.7,130.77 50.7,129.93 50.79,129.84 51.06,129.84 51.16,129.93 51.16,130.77 51.25,130.86 51.52,130.86 51.61,130.77 51.61,129.93 51.7,129.84 51.98,129.84 52.07,129.93 52.07,130.77 52.16,130.86 52.44,130.86 52.53,130.77 52.53,130.06 52.62,129.97 52.89,129.97 52.98,130.06 52.98,130.77 53.08,130.86 55.88,130.86 62.36,124.38 62.36,110.16 63.23,109.29 63.23,100.61 62.55,99.93 62.55,91.04 61.98,90.47 61.98,83.75 62.28,83.44 62.7,83.44 64.56,81.58 65.55,81.58 v2(65.9,81.93)
USB3_CC1: length 12.2
  TOP w0.127: J25.A5 155.21,17.58 155.14,17.52 154.76,17.52 154.19,16.95 v1(152.4,16.95) 152.39,16.94 C1188.1 ; R601.2 v1(150.37,11.48)
  L05-SIG2 w0.091: v1(150.37,11.48) 150.75,11.86 150.75,15.3 v1(152.4,16.95)
  BOTTOM w0.127: U109.1 v1(152.4,16.95)
USB3_CC2: length 21.4
  TOP w0.127: C1189.1 v1(152.4,16.3) ; J25.B5 158.23,18.84 v1(159,19.6) ; R602.2 v1(150.37,10.46)
  L05-SIG2 w0.091: v1(150.37,10.46) 151.13,11.22 151.13,15.03 v1(152.4,16.3) 156.59,16.3 156.97,15.92 158.5,15.92 159.38,16.81 159.38,19.22 v1(159,19.6)
  BOTTOM w0.127: U109.2 v1(152.4,16.3)
USB3_LDO_5V: length 14.7
  TOP w0.254: U108.10 v1(145.03,7.16)
  TOP w0.305: R650.2 v1(116.08,30.27)
  TOP w0.381: R676.1 v1(137.79,15.41) ; R607.1 R606.1 v1(122.43,15.41) ; R608.1 v1(133.6,15.41) ; R675.1 v1(128.02,15.41) ; R605.1 v1(130.81,15.41) ; R623.1 v1(125.22,15.41)
  BOTTOM w0.254: C1191.1 145.67,7.54
  BOTTOM w0.381: R623.1 v1(125.22,15.41) ; R605.1 v1(130.81,15.41) ; R675.1 v1(128.02,15.41) ; R606.1 v1(122.43,15.41) ; v1(133.6,15.41) R608.1 R662.1
  vias: v1(145.03,6.52) v1(145.67,7.16) v1(145.67,6.52) v1(151.76,18.46) v1(153.54,28.62) v1(153.54,27.73) v1(153.54,26.97) v1(154.18,27.73) v1(154.94,27.73)
USB3_PA1: length 33.8
  TOP w0.127: U108.1 142.26,11.2 141.86,11.6 v1(141.86,14.02)
  L05-SIG2 w0.091: v1(141.86,14.02) 141.48,14.39 124.07,14.39 121.79,12.11 v1(121.03,12.11)
  BOTTOM w0.127: R603.2 R663.1 v1(121.03,12.11) 122.3,10.84 122.3,8.43 J83.1
USB3_PA2: length 32.1
  TOP w0.127: v1(141.86,10.56) 142.01,10.7 U108.2
  L05-SIG2 w0.091: v1(123.82,12.11) 124.59,11.35 124.59,9.44 125.35,8.69 141.86,8.69 142.37,9.19 142.37,10.05 v1(141.86,10.56)
  BOTTOM w0.127: R604.2 R664.1 v1(123.82,12.11) 124.84,11.1 124.84,8.43 J83.3
USB3_PA3: length 25.6
  TOP w0.127: v1(141.1,9.56) 141.6,10.06 142.24,10.06 142.38,10.2 U108.3
  L05-SIG2 w0.091: v1(126.62,12.11) 128.02,10.71 137.29,10.71 138.45,9.56 v1(141.1,9.56)
  BOTTOM w0.127: J83.5 127.38,8.43 127.38,11.35 v1(126.62,12.11) R665.1 R659.2
USB3_PA4: length 22.5
  TOP w0.127: U108.4 142.01,9.7 v1(141.86,9.56)
  L05-SIG2 w0.091: v1(129.41,12.11) 130.43,11.1 137.67,11.1 138.68,10.08 141.33,10.08 v1(141.86,9.56)
  BOTTOM w0.127: R660.2 R666.1 v1(129.41,12.11) 129.92,11.6 129.92,8.43 J83.7
USB3_PA5: length 20.4
  TOP w0.127: U108.5 142.25,9.2 142.09,9.04 140.86,9.04 140.56,9.35 140.56,10.37 v1(140.33,10.59)
  L05-SIG2 w0.091: v1(132.21,12.11) 132.72,11.6 137.79,11.6 138.81,10.59 v1(140.33,10.59)
  BOTTOM w0.127: J83.9 132.46,8.43 132.46,11.86 v1(132.21,12.11) R667.1 R661.2
USB3_PA6: length 19.5
  TOP w0.127: U108.6 140.57,8.7 139.83,9.44 139.83,11.1 v1(140.33,11.6)
  L05-SIG2 w0.091: v1(140.33,11.6) 139.19,12.75 135.64,12.75 v1(135,12.11)
  BOTTOM w0.127: J83.11 135,8.43 v1(135,12.11) R662.2 R668.1
USB3_PB0: length 34.7
  TOP w0.127: R607.2 R671.2 v1(119.63,12.11) 121.03,10.71 J83.2 ; U108.7 143.53,7.56 143.13,7.16 v1(142.75,7.16)
  L05-SIG2 w0.091: v1(142.75,7.16) 141.6,6.02 123.19,6.02 122.17,7.03 122.17,10.33 121.28,11.22 120.52,11.22 v1(119.63,12.11)
USB3_PB1: length 31.4
  TOP w0.127: v1(143.76,7.16) 144.03,7.43 U108.8 ; R672.2 R606.2 v1(122.43,12.11) 123.57,10.97 J83.4
  L05-SIG2 w0.091: v1(143.76,7.16) 143.26,7.67 142.24,7.67 141.6,8.3 123.1,8.3 122.47,8.94 122.47,12.07 v1(122.43,12.11)
USB3_PB2: length 35
  TOP w0.127: U108.12 146.03,7.56 v1(146.43,7.16) ; R651.1 R623.2 v1(125.22,12.11) 126.11,11.22 J83.6
  L05-SIG2 w0.091: v1(125.22,12.11) 125.48,12.11 127.46,14.1 140.25,14.1 140.74,13.61 144.42,13.61 148.08,9.95 148.08,8.81 v1(146.43,7.16)
USB3_PB3: length 28.3
  TOP w0.127: J83.8 128.65,11.48 v1(128.02,12.11) R675.2 R670.2 ; U108.14 v1(147.57,9.2)
  L05-SIG2 w0.091: v1(128.02,12.11) 129.71,13.8 140.04,13.8 140.53,13.32 144.08,13.32 147.57,9.83 v1(147.57,9.2)
USB3_PB6: length 19.7
  TOP w0.127: J83.10 131.19,11.73 v1(130.81,12.11) R605.2 R673.2 ; U108.23 144.03,12.48 v1(143.89,12.62)
  L05-SIG2 w0.091: v1(143.89,12.62) 143.49,13.02 140.31,13.02 139.83,13.51 132.21,13.51 v1(130.81,12.11)
USB3_PB7: length 15.9
  TOP w0.127: J83.12 133.73,11.98 v1(133.6,12.11) R608.2 R674.2 ; U108.24 143.53,12.35 v1(143.26,12.62)
  L05-SIG2 w0.091: v1(133.6,12.11) 134.62,13.13 139.7,13.13 140.21,12.62 v1(143.26,12.62)
USB3_PC2: length 16.9
  TOP w0.127: R676.2 R669.2 v1(136.4,12.11) 136.27,11.98 J83.14 ; U108.9 144.53,7.29 v1(144.4,7.16)
  L05-SIG2 w0.091: v1(144.4,7.16) 142.88,8.68 142.88,10.71 142.6,10.99 139.04,10.99 137.92,12.11 v1(136.4,12.11)
USB3_RST: length 1.9
  TOP w0.152: C1192.2 144.53,12.73 U108.22
USB_12V: length 54.7
  TOP w0.381: C1667.1 R622.2 152.65,23.16 152.65,17.95 152.27,17.57 148.08,17.57 146.69,16.18 136.91,16.18 136.57,16.51 C1208.1 ; v1(132.33,29.26) v1(132.33,30.02) 132.33,30.65 131.95,31.03 124.71,31.03 123.95,31.8 116.08,31.8 115.32,31.03 115.32,25.32 115.95,24.68 C1666.1 R619.2
  vias: v1(131.44,30.02) v1(131.44,29.26) v1(131.44,28.49) v1(131.44,18.84) v1(131.44,18.08) v1(131.44,17.32) v1(132.33,28.49) v1(132.33,18.84) v1(132.33,18.08) v1(132.33,17.32) v1(133.22,30.02) v1(133.22,29.26) v1(133.22,28.49) v1(133.22,18.84) v1(133.22,18.08) v1(133.22,17.32) v1(135.51,30.02) v1(135.51,29.26) v1(135.51,28.49) v1(135.51,18.84) v1(135.51,18.08) v1(135.51,17.32) v1(136.4,30.02) v1(136.4,29.26) v1(136.4,28.49) v1(136.4,18.84) v1(136.4,18.08) v1(136.4,17.32) v1(137.29,30.02) v1(137.29,29.26) v1(137.29,28.49) v1(137.29,18.84) v1(137.29,18.08) v1(137.29,17.32)
USB_DM: length 18.7
  TOP w0.117: v1(156.59,17.78) 156.64,17.83 J25.B7 ; J25.A7 v1(154.81,18.58)
  BOTTOM w0.117: v1(144.78,14.9) 144.9,14.9 145.16,15.16 145.16,15.77 145.69,16.3 U109.5 149.61,16.3 149.8,16.1 150.06,16.1 150.24,16.28 150.24,17.45 150.75,17.95 153.06,17.95 153.51,18.41 154.64,18.41 v1(154.81,18.58) 155,18.4 155.15,18.4 155.85,19.1 156.84,19.1 157.27,18.67 157.27,18.22 157,17.96 156.85,17.96 156.68,17.78 v1(156.59,17.78)
USB_DP: length 18.8
  TOP w0.117: v1(154.81,17.95) 154.94,18.09 J25.A6 ; J25.B6 156.64,18.33 v1(156.59,18.39)
  BOTTOM w0.117: v1(145.8,14.9) 145.68,14.9 145.41,15.16 145.41,15.67 145.8,16.05 146.43,16.05 146.58,15.9 146.91,15.9 147.07,16.05 147.32,16.05 147.5,15.87 147.78,15.87 147.95,16.05 148.34,16.05 148.46,15.92 148.46,15.79 148.6,15.65 U109.4 149.59,15.65 149.79,15.85 150.17,15.85 150.5,16.18 150.5,17.34 150.85,17.7 153.16,17.7 153.62,18.16 154.61,18.16 v1(154.81,17.95) 155,18.14 155.26,18.14 155.4,18.29 155.56,18.29 155.76,18.09 155.91,18.09 156.02,18.19 156.02,18.35 155.82,18.55 155.82,18.71 155.96,18.84 156.74,18.84 157.01,18.57 157.01,18.33 156.9,18.21 156.76,18.21 v1(156.59,18.39)
USB_VBUS: length 7.5
  TOP w0.254: 156.9,19.35 157.31,19.35 157.33,19.33
  TOP w0.305: v1(158.24,16.68) 158.09,16.83 J25.B9 v1(156.74,16.83) 156.59,16.83 156.34,17.09 v1(156.29,17.09) J25.A4 155.09,17.09 v1(154.94,16.94) ; v1(158.24,19.6) 157.97,19.33 J25.B4 156.91,19.33 v1(156.72,19.53) 156.66,19.58 v1(156.21,19.58) J25.A9 v1(154.96,19.58)
  vias: v1(122.56,30.02) v1(122.56,29.38) v1(122.56,28.75) v1(122.56,28.11) v1(122.68,19.35) v1(122.68,18.72) v1(122.68,18.08) v1(122.68,17.45) v1(123.19,30.02) v1(123.19,29.38) v1(123.19,28.75) v1(123.19,28.11) v1(123.32,19.35) v1(123.32,18.72) v1(123.32,18.08) v1(123.32,17.45) v1(145.41,29.89) v1(145.41,29.26) v1(145.41,28.62) v1(145.41,27.99) v1(145.54,19.22) v1(145.54,18.59) v1(145.54,17.95) v1(145.54,17.32) v1(146.05,29.89) v1(146.05,29.26) v1(146.05,28.62) v1(146.05,27.99) v1(146.18,19.22) v1(146.18,18.59) v1(146.18,17.95) v1(146.18,17.32) v1(148.07,13) v1(159.77,26.97) v1(159.77,26.44) v1(159.77,25.47) v1(159.77,24.94) v1(160.4,26.97) v1(160.4,26.44) v1(160.4,25.47) v1(160.4,24.94)
VFMC1_3V30: length 26.5
  TOP w0.203: v2(14.43,58.73) 14.38,58.78 v2(14.38,59.99)
  TOP w0.381: v2(14.38,56.18) J48.D40 v2(14.38,54.91) ; 37.59,57.2 41.66,57.2 48.64,50.21 48.64,46.78 48.34,46.48 C52.1 46.55,46.48 R96.1 ; J48.C39 v2(15.65,56.18) ; v2(14.43,58.73) 14.39,58.73 J48.D38 v2(14.38,57.45) ; J48.D36 v2(14.38,59.99)
  vias: v4(28.6,56.28) v4(28.6,55.27) v4(28.6,54.25) v4(29.62,56.28) v4(29.62,55.27) v4(29.62,54.25) v4(30.63,56.28) v4(30.63,55.27) v4(30.63,54.25) v4(34.14,57.08) v4(34.14,56.06) v4(35.16,57.08) v4(35.16,56.06) v4(35.16,55.04) v4(35.16,54.03) v4(35.16,53.01) v4(36.17,57.08) v4(36.17,56.06) v4(36.17,55.04) v4(36.17,54.03) v4(36.17,53.01)
VFMC1_3V30AUX: length 1.8
  TOP w0.381: v2(14.38,66.34) 13.74,65.71 v2(14.38,65.07)
VFMC1_ADJ: length 17.8
  TOP w0.254: C100.1 VFMC1_ADJ.1
  TOP w0.381: v2(8.03,56.18) J48.H40 v2(8.03,54.91) ; v2(11.84,54.91) J48.F40 v2(10.57,54.91) ; v2(9.3,56.18) J48.G39 v2(10.57,56.18) ; v2(13.11,56.18) J48.E39 v2(11.84,56.18) ; R399.2 31.62,35.41 C101.1 31.31,33.26 29.46,31.42 26.92,31.42
  BOTTOM w0.381: 26.67,31.8 v4(25.65,31.8)
  vias: v4(24.13,34.08) v4(24.13,33.32) v4(24.13,32.56) v4(24.13,31.8) v4(24.89,34.08) v4(24.89,33.32) v4(24.89,32.56) v4(24.89,31.8) v4(25.65,34.08) v4(25.65,33.32) v4(25.65,32.56) v4(37.89,124.72) v4(37.89,123.83) v4(37.89,122.82) v4(38.91,124.72) v4(38.91,123.83) v4(38.91,122.82) v4(39.8,124.72) v4(39.8,123.83) v4(39.8,122.82)
VFMC2_3V30: length 17.5
  TOP w0.381: 22.1,21.38 22.1,24.3 27.81,30.02 C559.1 29.08,30.27 R305.1 ; J54.D40 v4(105.54,19.38) ; J54.D38 v4(103,19.38) ; J54.C39 v4(104.27,20.65) ; J54.D36 v4(100.46,19.38)
  vias: v4(22.61,20.24) v4(22.61,19.48) v4(23.37,20.24) v4(23.37,19.48) v4(24.13,20.24) v4(24.13,19.48) v4(24.89,20.24) v4(24.89,19.48) v4(25.78,20.24) v4(25.78,19.48) v4(26.54,20.24) v4(26.54,19.48) v4(27.3,20.24) v4(27.3,19.48)
VFMC2_3V30AUX: length 1.8
  TOP w0.381: v4(95.38,18.11) J54.D32 v4(94.11,18.11)
VFMC2_ADJ: length 23.6
  TOP w0.254: C629.1 VFMC2_ADJ.1
  TOP w0.381: v4(104.27,14.3) J54.G39 v4(104.27,15.57) ; R402.2 47.69,39.54 C624.1 48.44,39.23 48.77,38.91 48.77,34.84 44.32,30.4 41.78,30.4 ; J54.H40 v4(104.27,13.03) ; v4(105.54,16.84) J54.F40 v4(105.54,15.57) ; v4(104.27,18.11) J54.E39 v4(104.27,16.84)
  BOTTOM w0.381: C622.1 v4(40.77,31.8)
  vias: v4(39.24,34.08) v4(39.24,33.32) v4(39.24,32.56) v4(39.24,31.8) v4(40.01,34.08) v4(40.01,33.32) v4(40.01,32.56) v4(40.01,31.8) v4(40.77,34.08) v4(40.77,33.32) v4(40.77,32.56)
VLDO_MPM_3V3: length 19.7
  TOP w0.254: U120.23 140.57,65.86 v1(140.84,65.58)
  TOP w0.381: R693.1 R705.1 137.54,73.95 R694.2 ; R693.1 R706.1 R707.1 ; R693.1 v1(139.83,74.6)
  L10-SIG3 w0.381: v1(140.84,65.58) 140.84,67.74 142.37,69.26 142.37,72.06 v1(139.83,74.6)
  BOTTOM w0.381: v1(139.83,74.6) 140.33,74.09 R708.2 R52.2
N00911: length 1
  TOP w0.305: U1.9 v2(17.53,131.39)
N00925: length 1.1
  TOP w0.305: U1.4 v2(17.44,133.89)
N01606: length 5.7
  TOP w0.127: U1.14 16.42,128.89 R11.1 16.13,126.57 JP3.1
N01656: length 2.8
  TOP w0.127: R15.2 17.05,132.89 U1.6
N02092: length 4.7
  TOP w0.152: v2(22.06,135.08) 21.06,136.08 U1.63
  BOTTOM w0.152: R12.2 v2(22.06,135.08) U2.1
N02098: length 5.2
  TOP w0.152: v2(23.33,135.08) 23.04,135.08 21.56,136.55 U1.62
  BOTTOM w0.152: R13.2 v2(23.33,135.08) U2.2
N02124: length 5.9
  TOP w0.152: U1.61 22.06,136.79 22.64,136.22 23.46,136.22 v2(24.6,135.08)
  BOTTOM w0.152: U2.3 v2(24.6,135.08) R19.1
N02138: length 4.2
  BOTTOM w0.152: R19.2 24.89,137.49 25.15,137.24 25.15,136.69 R14.2 U2.4
N02805: length 7.8
  TOP w0.127: X1.1 16.26,139.88 16.26,138.22 16.79,137.69 C17.2 16.79,135.81 17.71,134.89 U1.2
N02831: length 9.6
  TOP w0.127: JP6.1 13.09,139.15 X1.3 15.79,138.39 C18.2 15.79,136.18 17.58,134.39 U1.3
N03813: length 6.7
  TOP w0.127: U1.19 21.56,126.62 21.25,126.93 20.2,126.93 18.97,125.7 R9.1
N03929: length 7.8
  TOP w0.127: U1.17 20.56,124.75 22.3,123.02 R7.1
N03953: length 10.2
  TOP w0.127: R8.1 29.13,123.39 28.69,123.83 26.12,123.83 25.84,123.55 22.55,123.55 21.06,125.04 U1.18
N16504386: length 3
  TOP w0.508: J2.1 9.31,133.34 9.74,133.77 FB2.2
N16632009: length 13.5
  TOP w0.127: 32,131.39 31.5,130.89 U1.39 ; 32,131.39 U1.40 ; 32,131.39 R16.1 36.07,131.39 37.59,132.92 37.59,136.19
N16632070: length 11.7
  TOP w0.127: 37.59,126.41 37.59,129.62 36.45,130.76 33.4,130.76 32.51,129.87 R17.1 31.48,130.39 U1.38
N16986163: length 2.6
  TOP w0.127: R39.2 R45.1 U4.3
N16986174: length 3
  TOP w0.127: R44.2 59.08,124.06 59.08,122.98 R41.2 U4.7
N16986210: length 1.4
  TOP w0.127: U4.2 R43.2
N17591276: length 1.6
  TOP w0.152: U1.24 R10.1
N17596855: length 6.3
  TOP w0.127: R6.1 15.9,123.46 17.6,125.16 17.6,127.64 17.85,127.89 U1.16
N18595602: length 1.7
  TOP w0.152: D1.A 6.6,140.47 R1.1
N20181793: length 4.3
  TOP w0.381: C52.2 46.75,48 R96.2 R100.1 43.59,47.64 U6.2
N20181835: length 1.7
  TOP w0.254: U6.7 36.7,47.62 C48.1
N20181965: length 1.2
  TOP w0.254: C54.1 U6.4
N20181967: length 2.3
  TOP w0.254: U6.3 C53.1
N20325017: length 3.5
  TOP w0.152: J48.B1 v2(16.92,105.71)
  BOTTOM w0.152: R215.1 17.43,105.2 v2(16.92,105.71)
N20325029: length 2.5
  TOP w0.152: J48.B40 v2(16.92,54.91)
  BOTTOM w0.152: R216.1 17.83,55.83 v2(16.92,54.91)
N20421551: length 40.5
  TOP w0.152: U3.AA11 v2(73.9,75.93)
  L05-SIG2 w0.091: v2(73.9,75.93) 73.46,76.37 72.9,76.37 72.39,76.88 72.39,77.01 72.14,77.26 71.63,77.26 71.25,77.64 71.25,79.04 70.81,79.48 67.89,79.48 67.56,79.8 62.1,79.8 60.58,81.33 59.94,81.33 58.55,82.72 54.48,82.72 51.44,85.77 51.44,93.65 JP88.2
N20899580: length 0.7
  TOP w0.152: U3.U26 v2(89.9,80.93)
N20899618: length 3.7
  TOP w0.152: U3.AE27 v2(90.9,71.93)
  BOTTOM w0.127: R290.1 92.83,71.67 92.58,71.42 91.41,71.42 v2(90.9,71.93)
N20900730: length 0.9
  BOTTOM w0.127: v3(107.73,79.24) 107.55,79.41 R291.2
N20943247: length 50.3
  TOP w0.152: U3.AF18 v2(81.9,70.93)
  BOTTOM w0.127: JP40.1 107.57,42.97 107.57,49.32 106.12,50.77 106.12,52.8 104.52,54.4 96.14,54.4 91.31,59.23 86.74,59.23 85.85,60.12 85.85,62.15 85.47,62.53 82.68,62.53 82.32,62.89 82.32,70.51 v2(81.9,70.93)
N20953565: length 5.7
  TOP w0.381: U32.2 33.05,28.35 R306.1 R305.2 30.11,29.26 29.34,28.49 C559.2
N20953569: length 1.7
  TOP w0.254: C564.1 33.21,20.75 33.05,20.91 U32.7
N20953725: length 1.8
  TOP w0.203: U32.4 v1(30.51,28.59)
  BOTTOM w0.203: C563.1 30.48,28.57 v1(30.51,28.59)
N20953727: length 2.1
  TOP w0.203: U32.3 v1(31.78,28.59)
  BOTTOM w0.203: v1(31.78,28.59) 31.88,28.49 C562.1
N20954035: length 3.7
  TOP w0.152: J54.B1 v1(54.74,21.92)
  BOTTOM w0.127: R308.1 53.85,22.81 v1(54.74,21.92)
N20954045: length 1.8
  TOP w0.152: J54.B40 v1(105.54,21.92)
  BOTTOM w0.152: R309.1 105.08,22.37 v1(105.54,21.92)
N20954331: length 15.4
  TOP w0.508: J54.K1 v1(54.74,10.49)
  L03-SIG1 w0.508: v1(54.74,10.49) 46.33,10.49 TP_FMC2_VREFB.1
N20986575: length 1.9
  TOP w0.127: v2(61.23,110.46) 61.21,110.44 D4.A
  BOTTOM w0.152: R24.1 61.44,110.46 v2(61.23,110.46)
N20986579: length 2.6
  TOP w0.152: v2(59.23,106.85) 59.23,107.96 D5.K
  BOTTOM w0.127: Q1.C 58.68,107.41 v2(59.23,106.85)
N20986602: length 3.7
  TOP w0.152: D5.A v2(59.33,112.67)
  BOTTOM w0.152: R25.1 59.36,112.65 v2(59.33,112.67)
N20986712: length 1.9
  BOTTOM w0.127: Q1.B 55.99,110.2 R28.1
N20987029: length 11.3
  TOP w0.127: v1(45.72,136.95) 45.18,136.41 SW2.4 SW2.2
  BOTTOM w0.127: v1(45.72,136.95) 45.72,135.94 R29.2
N21000300: length 2
  TOP w0.127: R46.2 58.28,120.06 57.89,120.44 U4.5
N21001542: length 16.2
  TOP w0.152: U3.P9 v2(71.9,83.93)
  L05-SIG2 w0.091: v2(71.9,83.93) 72.26,84.29 72.26,87.3 72.14,87.42 71.75,87.42 71.37,87.8 71.37,97.3 v2(71.02,97.66)
  BOTTOM w0.127: R20.2 v2(71.02,97.66)
N21002825: length 102.6
  TOP w0.127: JP65.2 50.55,107.35 50.55,110.41 50.67,110.54 53.34,110.54 53.47,110.41 53.47,104 53.59,103.87 53.98,103.87 54.1,103.74 54.1,103.36 53.98,103.24 53.59,103.24 53.47,103.11 53.47,101.65 53.98,101.14 53.98,91.69 53.72,91.43 50.8,91.43 50.67,91.31 50.67,90.92 50.8,90.8 53.85,90.8 53.98,90.67 53.98,90.29 53.85,90.16 50.8,90.16 50.67,90.04 50.67,89.65 50.8,89.53 53.85,89.53 53.98,89.4 53.98,88.31 53.85,88.18 50.8,88.18 50.67,88.06 50.67,87.68 50.8,87.55 53.21,87.55 53.34,87.42 53.34,87.04 53.21,86.91 50.8,86.91 50.67,86.79 50.67,86.41 50.8,86.28 53,86.28 53.13,86.15 53.13,85.77 53,85.64 50.8,85.64 50.67,85.52 50.67,85.14 50.8,85.01 53,85.01 53.13,84.88 53.13,84.5 53,84.37 50.8,84.37 50.67,84.25 50.67,83.87 50.8,83.74 53,83.74 53.13,83.61 53.13,83.23 53,83.1 50.8,83.1 50.67,82.98 50.67,82.6 50.8,82.47 53,82.47 53.13,82.34 53.13,81.96 53,81.83 50.8,81.83 50.67,81.71 50.67,80.05 50.8,79.93 51.49,79.93 51.62,80.05 51.62,80.95 51.74,81.07 52.12,81.07 52.25,80.95 52.25,80.05 52.38,79.93 52.76,79.93 52.89,80.05 52.89,80.95 53.01,81.07 53.39,81.07 53.52,80.95 53.52,80.05 53.65,79.93 54.03,79.93 54.16,80.05 54.16,80.95 54.28,81.07 54.66,81.07 54.79,80.95 54.79,80.05 54.92,79.93 55.3,79.93 55.43,80.05 55.43,80.95 55.55,81.07 55.93,81.07 56.06,80.95 56.06,80.05 56.19,79.93 65.9,79.93 U3.U3
N21005513: length 1.2
  BOTTOM w0.127: R331.1 76.06,138.72 D60.3
N21005532: length 2
  BOTTOM w0.127: D60.11 73.51,146.33 R332.1
N21005551: length 2.6
  BOTTOM w0.127: D60.7 R333.1
N21005570: length 1.2
  BOTTOM w0.127: R334.1 78.62,138.72 D60.4
N21005589: length 1.3
  BOTTOM w0.127: D60.2 73.55,138.72 R335.1
N21005608: length 1.2
  BOTTOM w0.152: R336.1 71.01,138.72 D60.1
N21005627: length 2.2
  BOTTOM w0.127: D60.10 75.57,145.85 R337.1
N21005646: length 1.3
  BOTTOM w0.127: R338.1 81.14,138.72 D60.5
N21008142: length 3.1
  BOTTOM w0.152: Q2.B 76.41,142.29 R339.2 R340.1
N21008495: length 3.6
  BOTTOM w0.152: Q3.B 83.62,144.32 R341.2 R342.1
N21008871: length 3.2
  BOTTOM w0.152: R344.1 R343.2 68.66,142.79 Q4.B
N21037031: length 11.8
  TOP w0.152: U3.T7 v2(69.9,81.93)
  L03-SIG1 w0.091: v2(62.55,85.93) 62.99,85.49 62.99,83.74 64.39,82.34 68.07,82.34 68.45,81.96 68.45,81.83 68.71,81.58 69.55,81.58 v2(69.9,81.93)
  BOTTOM w0.152: R55.2 62.45,85.83 v2(62.55,85.93)
N21071175: length 1.7
  TOP w0.152: U3.U15 v2(77.9,80.93)
  BOTTOM w0.152: v2(77.9,80.93) 78.11,80.72 R345.2
N21072310: length 11.3
  TOP w0.127: v1(52.7,136.83) 52.29,136.41 SW1.4 SW1.2
  BOTTOM w0.127: R23.2 52.7,135.82 v1(52.7,136.83)
N21077063: length 56.2
  TOP w0.152: v1(145.03,147.87) 145.03,145.84 145.71,145.16 D9.K
  BOTTOM w0.152: Q32.C 94.76,148.02 96.01,149.27 143.64,149.27 v1(145.03,147.87)
N21077065: length 54.8
  TOP w0.152: D11.K v1(149.78,145.16)
  BOTTOM w0.152: Q34.C 99.71,147.64 100.99,148.92 140.69,148.92 142.49,147.11 148.46,147.11 149.78,145.8 v1(149.78,145.16)
N21077067: length 47.3
  TOP w0.152: D10.K v1(147.11,145.16)
  BOTTOM w0.152: Q33.C 104.66,147.76 105.46,148.56 140.41,148.56 142.24,146.73 146.43,146.73 147.11,146.05 v1(147.11,145.16)
N21077110: length 31.4
  TOP w0.152: D6.K 127.59,145.16 126.11,143.68 110.49,143.68 v1(109.85,144.32)
  BOTTOM w0.152: v1(109.85,144.32) 109.85,146.33 Q29.C
N21077112: length 23.6
  TOP w0.152: v1(120.29,144.72) 121.68,144.72 122.68,145.72 135.64,145.72 136.78,146.86 139.01,146.86 D7.K
  BOTTOM w0.152: Q30.C v1(120.29,144.72)
N21077121: length 31.1
  TOP w0.152: D8.K v1(142.29,145.16)
  BOTTOM w0.152: Q31.C 115.08,147.26 116.03,148.21 139.88,148.21 142.29,145.8 v1(142.29,145.16)
N21077214: length 1.6
  TOP w0.203: D10.A 149.03,143.51 v2(149.1,143.57)
  BOTTOM w0.305: R60.1 v2(149.1,143.57)
N21077216: length 1.6
  TOP w0.203: v2(141.48,143.57) 141.41,143.51 D7.A
  BOTTOM w0.203: R57.1 v2(141.48,143.57)
N21077218: length 1.6
  TOP w0.203: D6.A v2(139.06,143.51)
  BOTTOM w0.203: R56.1 139,143.57 v2(139.06,143.51)
N21077222: length 1.8
  TOP w0.203: D11.A 151.57,143.51 v2(151.64,143.57)
  BOTTOM w0.305: R61.1 v2(151.64,143.57)
N21077224: length 1.6
  TOP w0.203: D8.A v2(144.02,143.51)
  BOTTOM w0.203: R58.1 143.95,143.57 v2(144.02,143.51)
N21077226: length 2.1
  TOP w0.203: v2(146.81,143.57) 146.75,143.51 D9.A
  BOTTOM w0.203: R59.1 v2(146.81,143.57)
N21110155: length 10
  TOP w0.127: v1(60.41,135.59) SW4.4 SW4.2
  BOTTOM w0.127: R50.2 59.99,135.17 v1(60.41,135.59)
N21111210: length 11.3
  TOP w0.127: SW5.2 SW5.4 66.26,135.85 v1(65.41,136.7)
  BOTTOM w0.127: R51.2 65.41,135.56 v1(65.41,136.7)
N21123855: length 2
  BOTTOM w0.254: JP12.2 59.05,140.39 C600.1
N21167890: length 11.6
  TOP w0.152: U3.R8 v2(70.9,82.93)
  BOTTOM w0.127: v2(70.9,82.93) 70.47,83.36 69.6,83.36 69.34,83.61 69.34,83.99 68.76,84.58 64.69,84.58 64.39,84.88 64.39,85.14 62.79,86.74 R408.2
N21221554: length 15.1
  TOP w0.152: U3.AA10 v2(72.9,75.93)
  BOTTOM w0.127: v2(72.9,75.93) 72.52,75.55 72.52,73.83 72.14,73.45 69.47,73.45 69.34,73.33 69.34,72.82 68.96,72.44 62.73,72.44 R712.1 R652.1
N21236832: length 4.9
  TOP w0.254: U115.6 43.29,38.02 44.32,38.02
  TOP w0.381: C624.2 47.69,38.02 R402.1 R406.2 44.32,38.02
N21269868: length 1.8
  TOP w0.099: R538.2 101.48,88.68 101.48,89.26 Y1.5
N21271826: length 1.5
  TOP w0.203: v2(163.15,124.12) 163.15,124.13 D61.A
  BOTTOM w0.254: R169.1 v2(163.15,124.12)
N21271847: length 1.7
  BOTTOM w0.203: R229.1 155.62,123.18 Q7.B
N21271871: length 1.4
  TOP w0.203: D61.K 160,124.13 v2(160,124.12)
  BOTTOM w0.254: v2(160,124.12) 159.99,124.13 Q7.C
N21271879: length 1.3
  TOP w0.305: C385.1 151.25,135.92 U17.6
N21271891:
  vias: v4(148.84,135.81) v4(148.84,134.92) v4(149.99,137.59) v4(151.13,140) v4(151.13,138.73) v4(151.13,137.59)
N21271907: length 3.1
  TOP w0.305: R231.2 R232.1 151.06,134.02 U17.4
N21272003: length 3.6
  TOP w0.305: R234.1 R233.2 U17.5
N21279835: length 1.5
  TOP w0.203: D63.A 163.14,120.57 v2(163.15,120.58)
  BOTTOM w0.254: R417.1 v2(163.15,120.58)
N21279856: length 1.7
  BOTTOM w0.203: R416.1 155.62,119.63 Q8.B
N21279868: length 1.4
  TOP w0.203: v2(160,120.58) 160.01,120.57 D63.K
  BOTTOM w0.254: v2(160,120.58) 159.99,120.58 Q8.C
N21279888: length 1.3
  TOP w0.305: U35.6 151.25,106.71 C638.1
N21279900:
  vias: v4(148.78,106.66) v4(148.78,105.77) v4(151.06,111.87) v4(151.06,110.73) v4(151.06,109.58) v4(151.06,108.44)
N21279916: length 3.1
  TOP w0.305: U35.4 150.76,104.81 151.21,104.36 R421.1 R420.2
N21279996: length 3.6
  TOP w0.305: U35.5 R418.2 R419.1
N21283467: length 8.1
  TOP w0.127: R716.1 154.31,94.41 153.54,95.17 152.53,95.17 152.03,94.67 R572.2
  TOP w0.305: U36.5 C734.1 151.92,93.54 R572.2
N21283516: length 27.8
  TOP w0.305: U36.4 150.62,91.6 R424.1 152.19,91.15 R425.2 152.93,90.87 v2(153.21,91.16)
  L03-SIG1 w0.305: v2(153.21,91.16) 153.87,91.82 160.07,91.82 161.84,90.05 161.84,86.53 163.1,85.27 163.1,83.77 162.31,82.98 162.31,81.58 162.71,81.17 162.71,78 v2(162.94,77.77)
  BOTTOM w0.305: R288.1 v2(162.94,77.77)
N21283565: length 1.6
  TOP w0.203: v2(163.15,106.39) 163.11,106.35 D64.A
  BOTTOM w0.254: R427.1 v2(163.15,106.39)
N21283586: length 1.7
  BOTTOM w0.203: Q9.B 155.62,105.44 R426.1
N21283590: length 1.5
  TOP w0.203: D64.K 160.04,106.35 v2(160,106.39)
  BOTTOM w0.254: v2(160,106.39) 159.99,106.39 Q9.C
N21283614: length 1.3
  TOP w0.305: U36.6 150.81,93.5 C645.1
N21283618:
  vias: v4(148.34,93.45) v4(148.34,92.56) v4(150.63,98.66) v4(150.63,97.52) v4(150.63,96.37) v4(150.63,95.23)
N21285415: length 3.6
  TOP w0.305: U37.5 R428.2 R429.1
N21285466: length 3.1
  TOP w0.305: U37.4 136.4,95.13 R430.1 R431.2
N21285515: length 1.5
  TOP w0.203: D65.A 163.13,117.01 v2(163.15,117.03)
  BOTTOM w0.254: R433.1 v2(163.15,117.03)
N21285536: length 1.7
  BOTTOM w0.203: R432.1 155.62,116.08 Q10.B
N21285540: length 1.4
  TOP w0.203: D65.K 160.01,117.01 v2(160,117.03)
  BOTTOM w0.254: Q10.C 159.99,117.03 v2(160,117.03)
N21285564: length 1.3
  TOP w0.305: U37.6 136.59,97.03 C649.1
N21285568:
  vias: v4(134.12,96.98) v4(134.12,96.1) v4(136.41,102.19) v4(136.41,101.05) v4(136.41,99.91) v4(136.41,98.76)
N21287544: length 3.6
  TOP w0.305: U38.5 R434.2 R435.1
N21287595: length 3.1
  TOP w0.305: U38.4 136.4,123.86 R436.1 R437.2
N21287644: length 1.6
  TOP w0.203: D66.A 163.1,102.79 v2(163.15,102.84)
  BOTTOM w0.254: R439.1 v2(163.15,102.84)
N21287665: length 1.7
  BOTTOM w0.203: R438.1 155.62,101.89 Q11.B
N21287669: length 1.5
  TOP w0.203: v2(160,102.84) 160.05,102.79 D66.K
  BOTTOM w0.254: v2(160,102.84) 159.99,102.84 Q11.C
N21287693: length 1.3
  TOP w0.305: U38.6 136.59,125.76 C653.1
N21287697:
  vias: v4(134.19,125.65) v4(134.19,124.76) v4(136.35,128.95) v4(136.4,127.94) v4(137.03,128.95) v4(137.03,127.94)
N21298381: length 1.5
  TOP w0.203: v2(163.15,127.67) 163.14,127.68 D68.A
  BOTTOM w0.254: R447.1 v2(163.15,127.67)
N21298402: length 1.7
  BOTTOM w0.203: Q13.B 155.62,126.73 R446.1
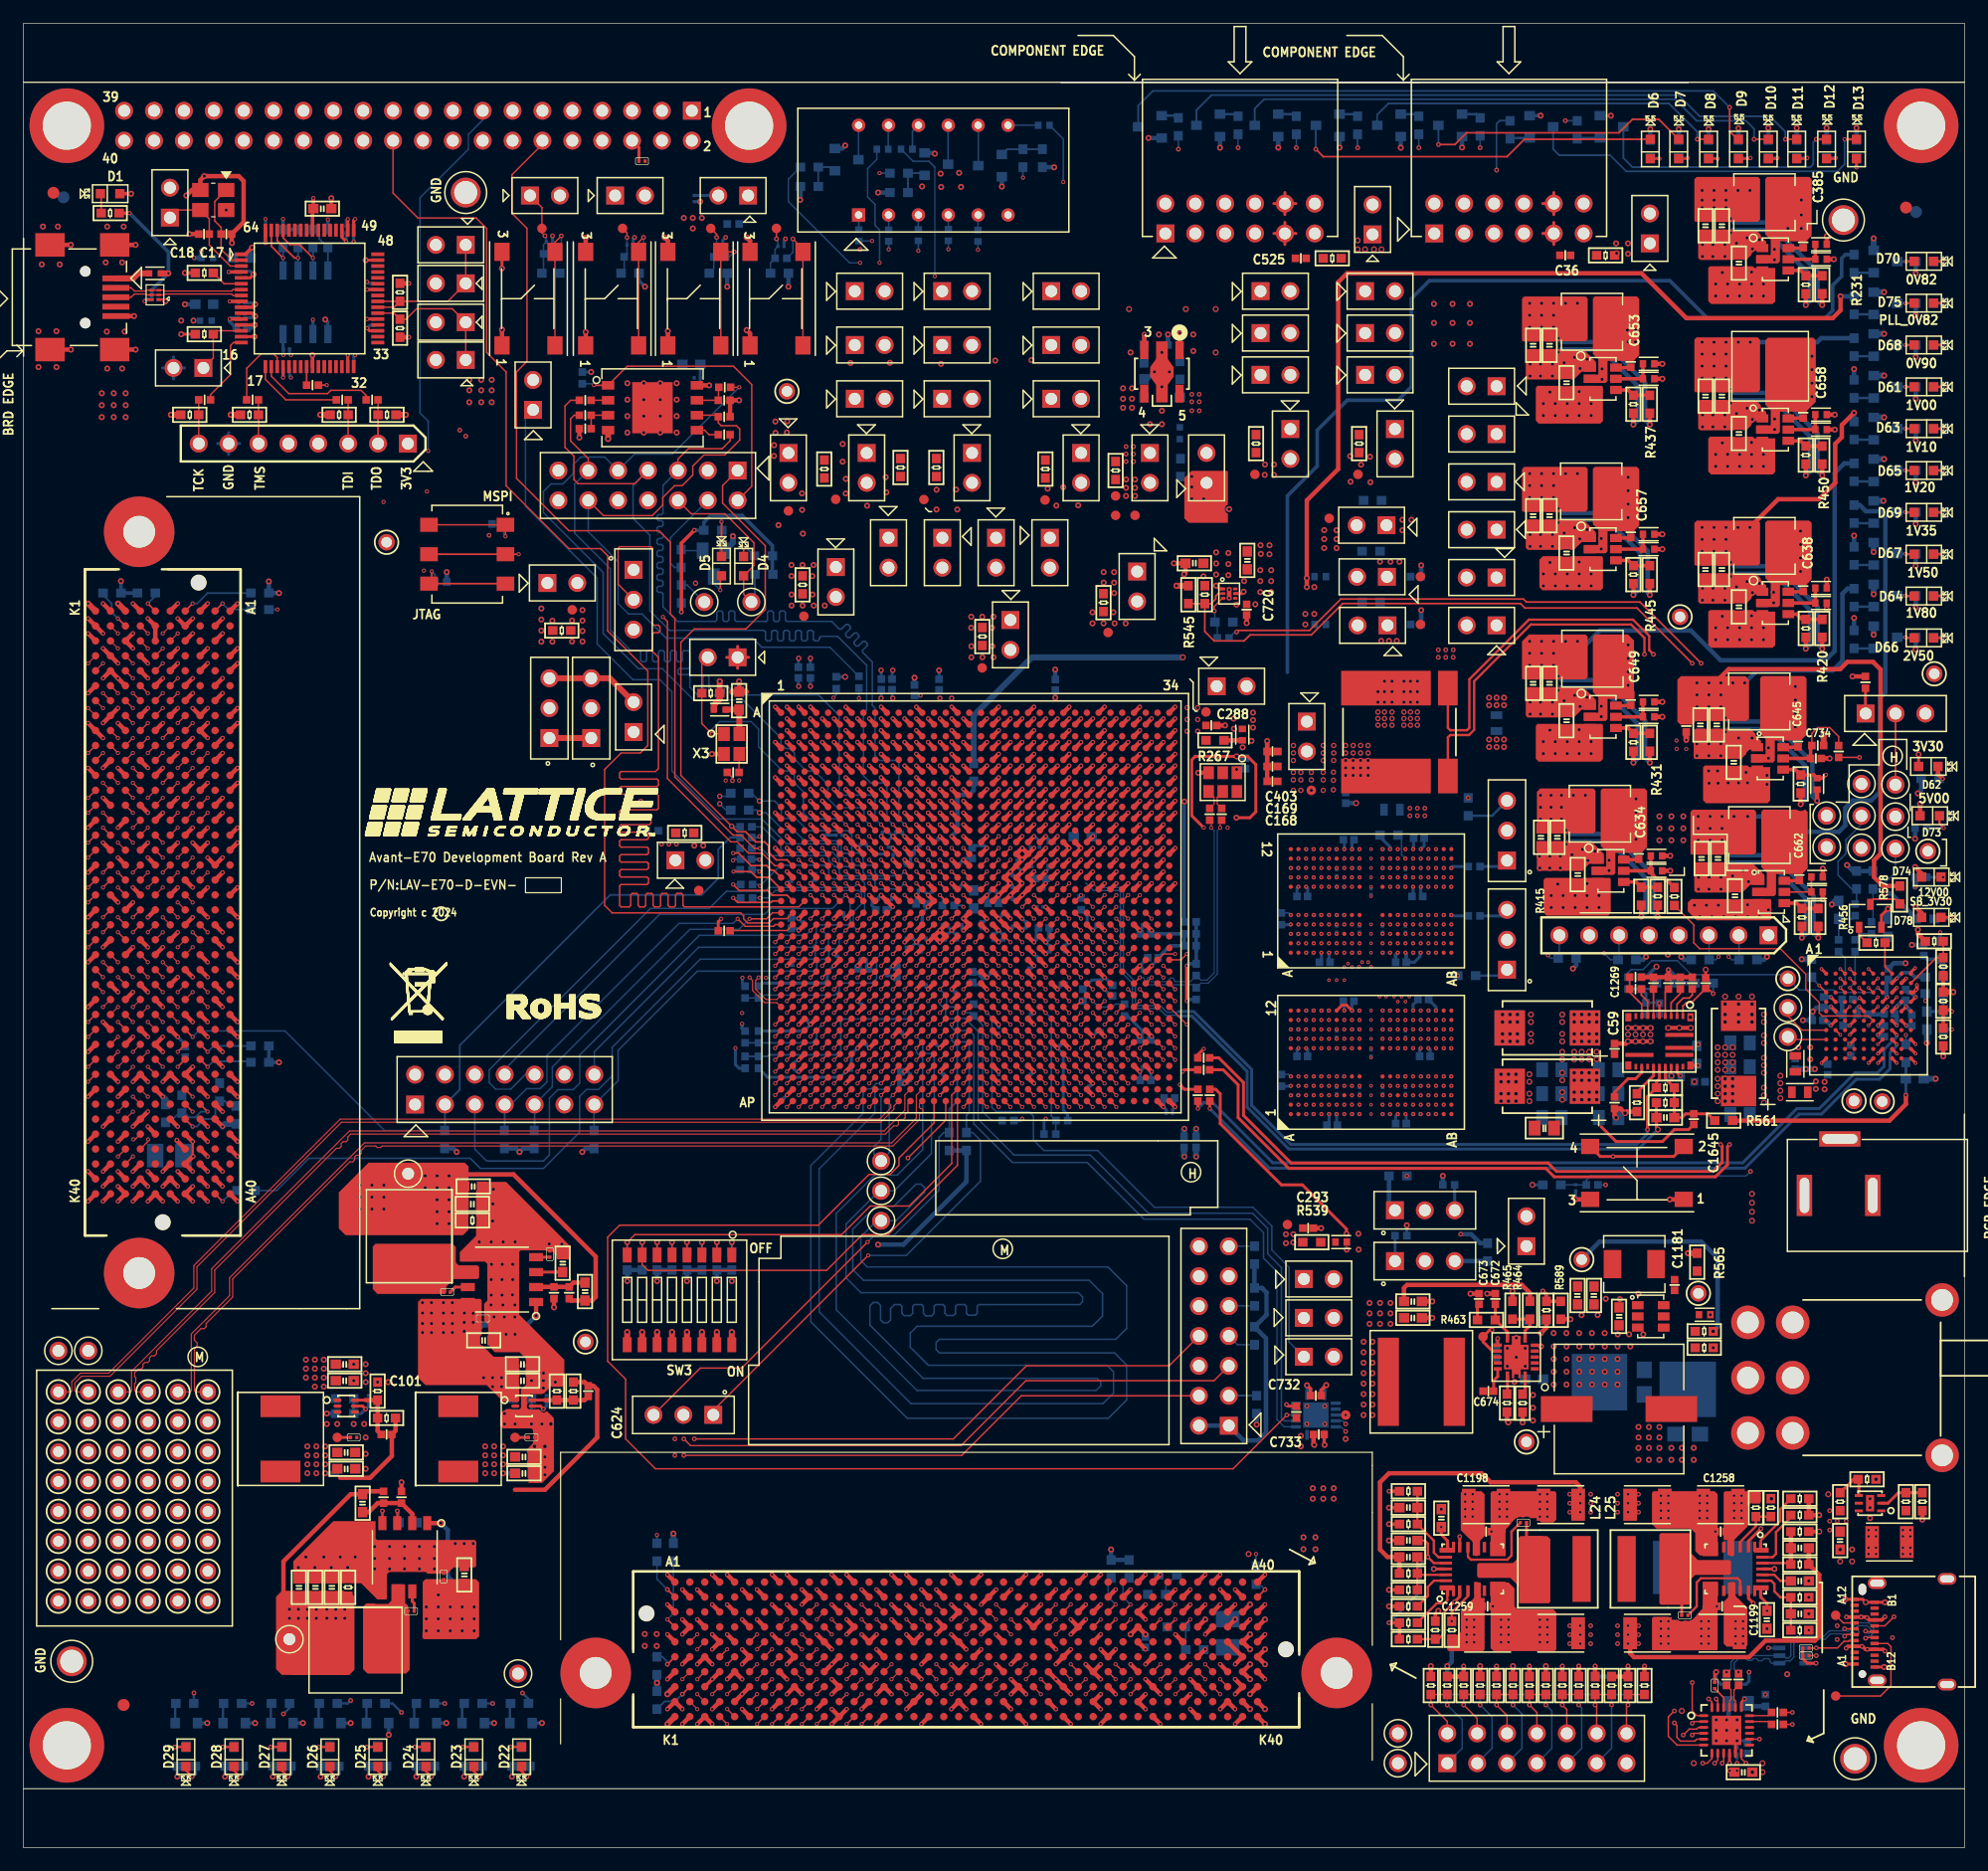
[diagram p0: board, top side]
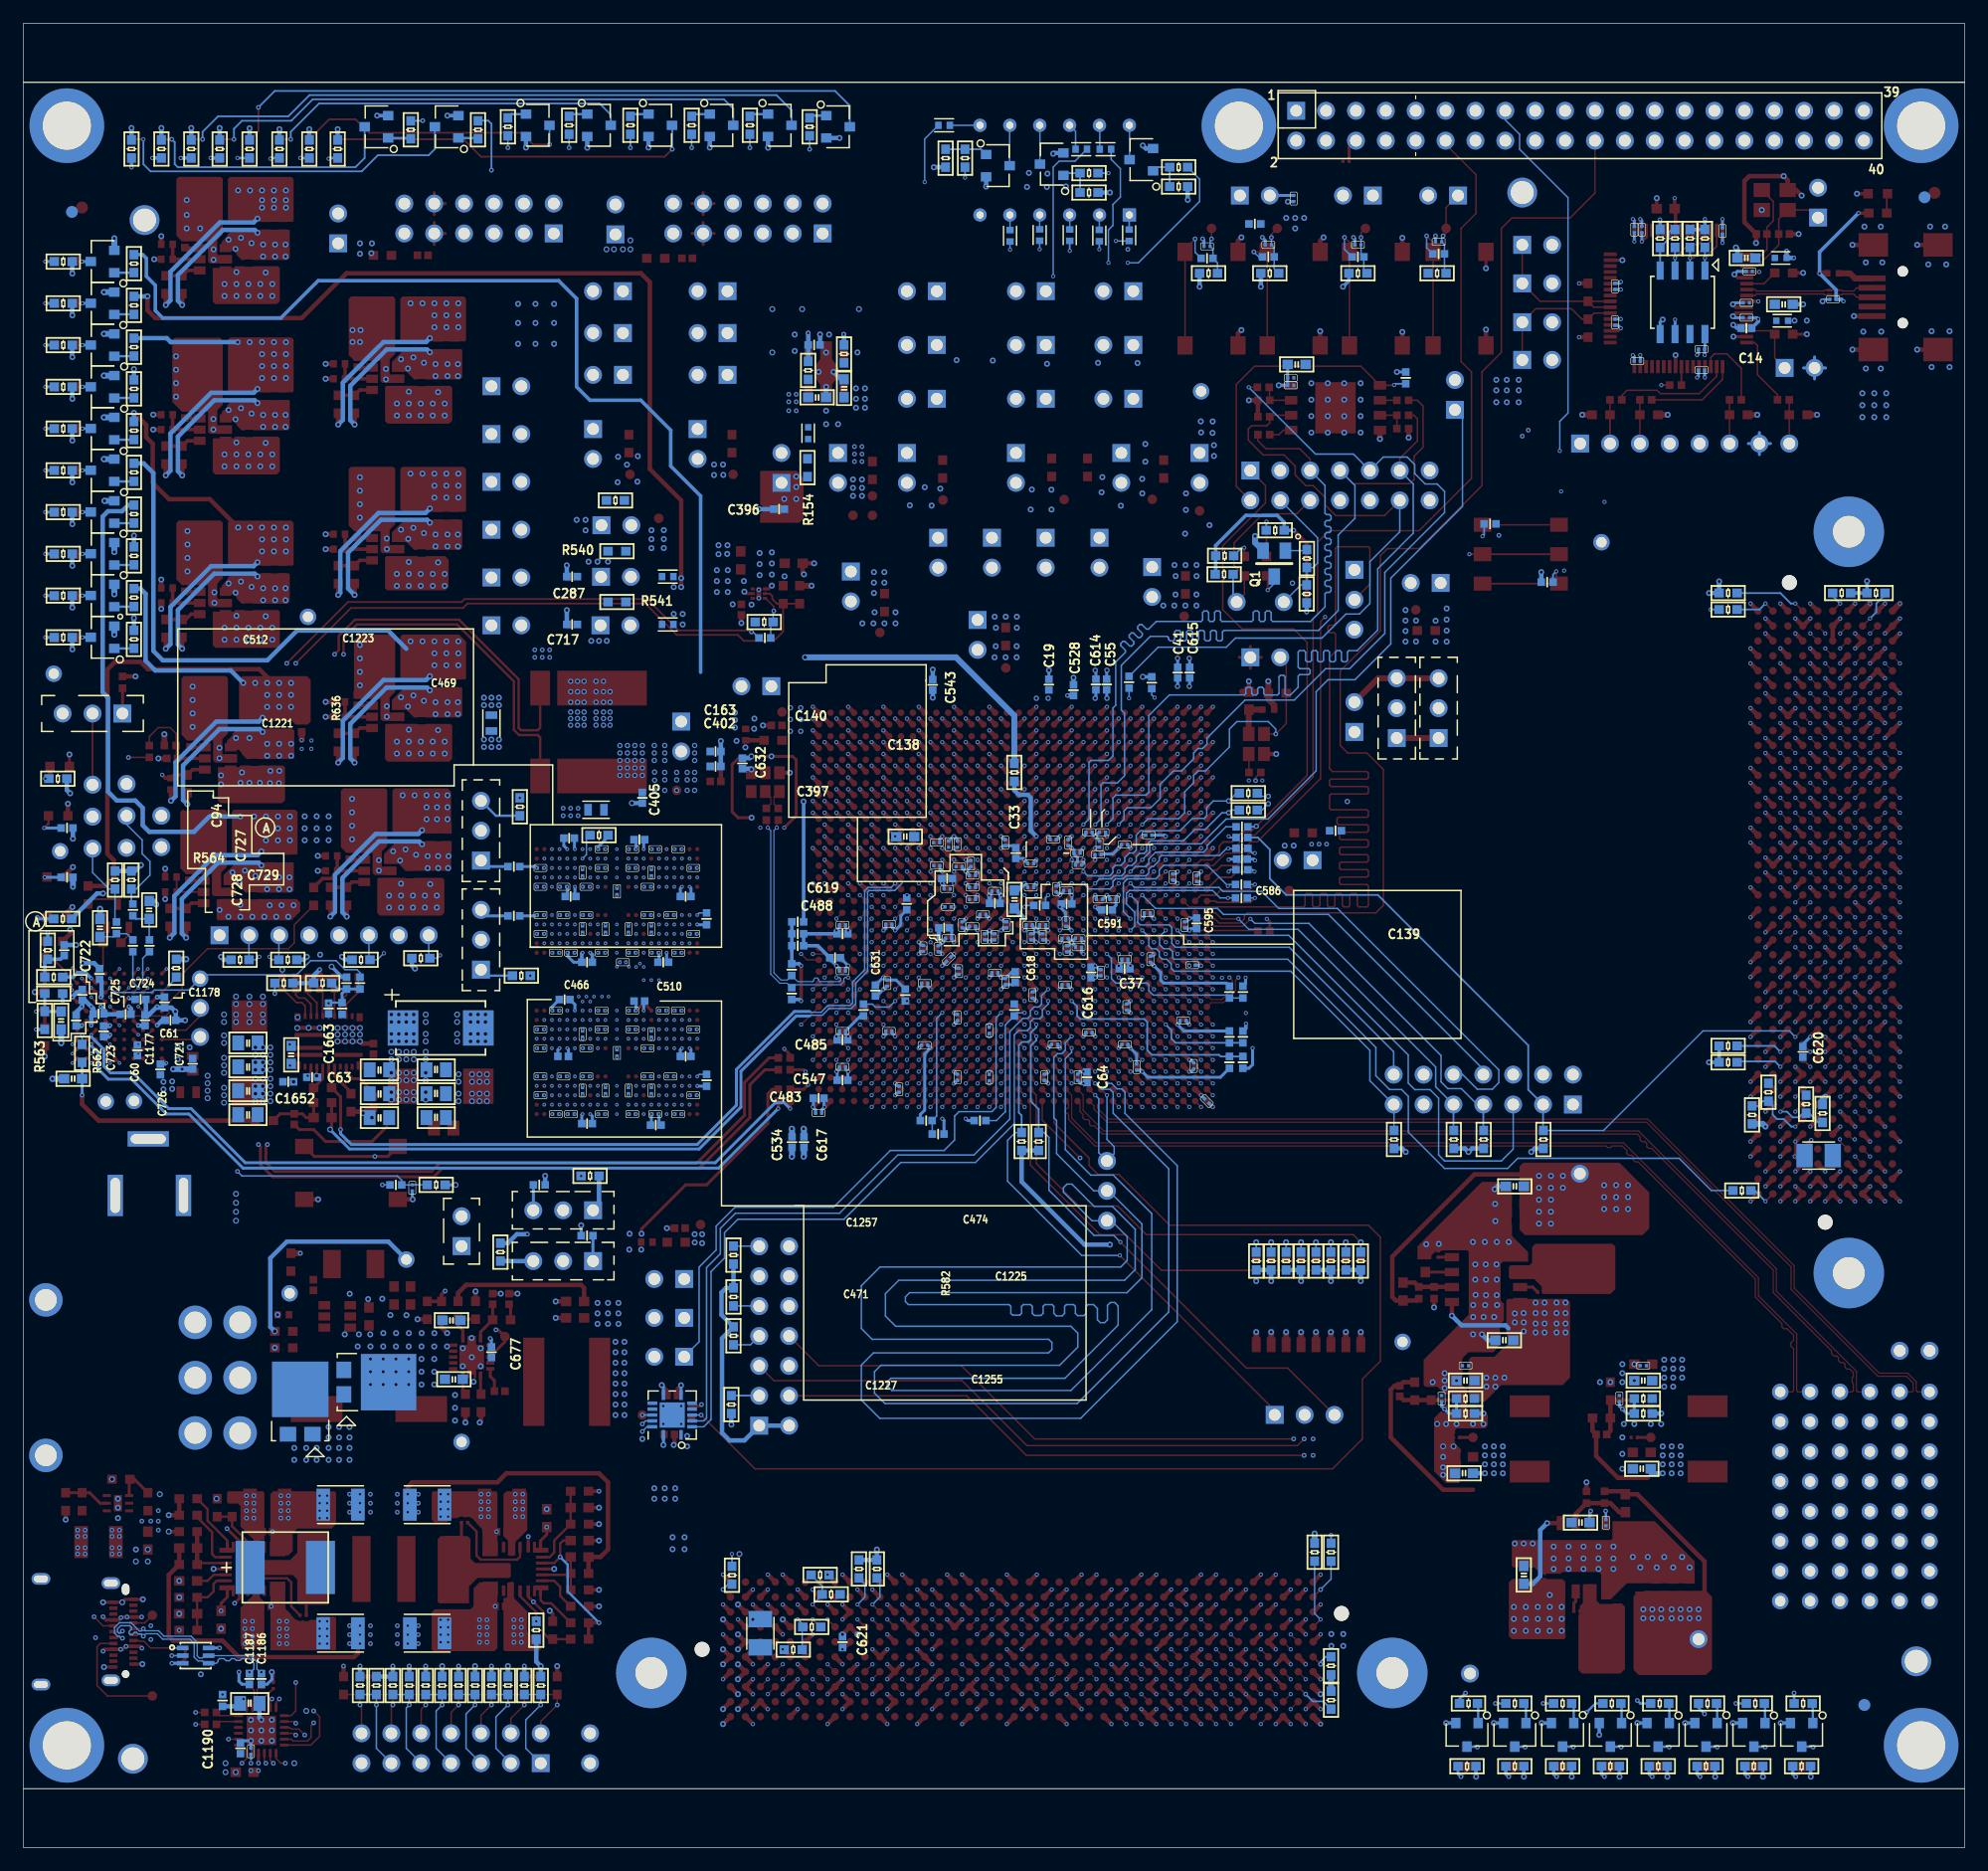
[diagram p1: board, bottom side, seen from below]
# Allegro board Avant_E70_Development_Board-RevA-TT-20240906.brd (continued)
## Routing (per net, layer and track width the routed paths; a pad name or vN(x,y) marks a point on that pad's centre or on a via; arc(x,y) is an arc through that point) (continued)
N21298414: length 1.4
  TOP w0.203: v2(160,127.67) 160.01,127.68 D68.K
  BOTTOM w0.254: Q13.C 159.99,127.68 v2(160,127.67)
N21298430: length 1.3
  TOP w0.305: U40.6 150.06,121.48 C658.1
N21298442:
  vias: v4(148.86,121.39) v4(148.86,120.5) v4(152.04,126.72) v4(152.04,125.58) v4(152.04,124.44) v4(152.04,123.3)
N21298458: length 3.1
  TOP w0.305: R450.2 R451.1 151.06,119.54 U40.4
N21298538: length 3.6
  TOP w0.305: U40.5 R448.2 R449.1
N21300072: length 1.5
  TOP w0.381: v2(163.14,90.83) 162.75,91.22 D62.A
  BOTTOM w0.381: R411.1 v2(163.14,90.83)
N21300092: length 1.3
  TOP w0.305: U34.6 137.26,83.95 C634.1
N21300096:
  vias: v4(134.79,83.9) v4(134.79,83.01) v4(137.08,89.11) v4(137.08,87.96) v4(137.08,86.82) v4(137.08,85.68)
N21300112: length 3.1
  TOP w0.305: U34.4 137.07,82.05 R415.1 R414.2
N21300200: length 6.3
  TOP w0.305: R682.2 139.57,82.34 138.81,82.34 138.33,82.82 R412.2 ; R412.2 R413.1 ; R412.2 U34.5
N21310610: length 1.6
  TOP w0.203: D69.A 163.13,113.46 v2(163.15,113.48)
  BOTTOM w0.254: R453.1 v2(163.15,113.48)
N21310631: length 1.7
  BOTTOM w0.203: R452.1 155.62,112.54 Q14.B
N21310643: length 1.4
  TOP w0.203: v2(160,113.48) 160.02,113.46 D69.K
  BOTTOM w0.254: Q14.C 159.99,113.49 v2(160,113.48)
N21310659: length 1.3
  TOP w0.305: U41.6 150.91,82.15 C662.1
N21310687: length 3.1
  TOP w0.305: R456.2 R457.1 150.72,80.25 U41.4
N21310767: length 3.6
  TOP w0.152: R455.1 R454.2 U41.5
N21316067: length 3.6
  TOP w0.305: R440.1 R441.2 U39.5
N21316093: length 3.1
  TOP w0.305: U39.4 136.4,109.38 R442.1 R445.2
N21316143: length 1.6
  TOP w0.203: D67.A 163.12,109.9 v2(163.15,109.93)
  BOTTOM w0.254: R444.1 v2(163.15,109.93)
N21316167: length 1.7
  BOTTOM w0.203: R443.1 155.62,108.99 Q12.B
N21316171: length 1.5
  TOP w0.203: D67.K 160.03,109.9 v2(160,109.93)
  BOTTOM w0.254: Q12.C 159.99,109.94 v2(160,109.93)
N21316188: length 1.3
  TOP w0.305: U39.6 136.59,111.28 C657.1
N21316200:
  vias: v4(134.12,111.23) v4(134.12,110.34) v4(136.41,116.44) v4(136.41,115.3) v4(136.41,114.15) v4(136.41,113.01)
N21319599: length 12.1
  TOP w0.152: U3.AF17 v2(79.9,70.93)
  BOTTOM w0.127: R655.1 82.3,61.77 81.53,62.53 81.53,69.9 R709.1 80.51,70.93 v2(79.9,70.93)
N21332860: length 56
  TOP w0.381: R588.1 129.46,44.18 v4(128.99,43.71)
  TOP w0.508: R565.1 v1(141.48,50.5)
  L03-SIG1 w0.508: v2(160.8,81.63) 161.82,80.61 161.82,77.75 163.32,76.25 163.32,69.01 163.96,68.37 163.96,53.77 160.69,50.5 v1(141.48,50.5)
  BOTTOM w0.508: R519.1 v2(160.8,81.63)
  vias: v4(129,42.58) v4(130.07,43.71) v4(130.08,42.58) v4(130.08,41.51) v4(130.08,40.43) v4(130.08,39.34) v4(131.16,43.71) v4(131.17,42.58) v4(131.17,41.51) v4(131.17,40.43) v4(131.17,39.34) v4(132.24,43.71) v4(132.25,42.58) v4(132.25,41.51) v4(132.25,40.43) v4(132.25,39.34) v4(133.33,43.71) v4(133.34,42.58) v4(133.34,41.51) v4(133.34,40.43) v4(133.34,39.34) v4(134.41,43.71) v4(134.42,42.58) v4(134.42,41.51) v4(134.42,40.43) v4(134.42,39.34) v4(135.53,43.61) v4(135.51,42.58) v4(135.51,41.51) v4(135.51,40.43) v4(135.51,39.34) v4(136.49,43.61) v4(136.59,42.58) v4(137.69,43.61)
N21333157: length 3.3
  TOP w0.254: C672.1 R463.1 126.15,43.81 U43.8
N21333175: length 1.4
  TOP w0.254: C673.1 123.6,46.04 R463.2
N21333379: length 2
  TOP w0.254: U43.13 125.32,40.03 124.98,39.68 C674.1
N21333574: length 3.3
  TOP w0.254: R465.1 R464.2 128.06,44.35 127.65,43.94 U43.7
N21334320: length 1.7
  TOP w0.254: R466.2 127.65,38.73 U43.1
N21334323: length 1.3
  TOP w0.254: U43.9 v1(125.32,43.25)
  BOTTOM w0.254: C677.2 125.22,43.15 v1(125.32,43.25)
N21335874: length 1.6
  TOP w0.254: R467.2 126.15,38.57 U43.14
N21377300: length 8.3
  TOP w0.305: v2(98.9,71.93) v2(98.9,74.93)
  BOTTOM w0.305: R491.1 99.03,72.06 v2(98.9,71.93) ; v2(98.9,74.93) 99.07,75.1 R490.2 99.69,76.24 99.69,76.25 R548.2 R493.2 R492.1
N21392431: length 1.4
  BOTTOM w0.254: R519.2 v2(163.19,82.44)
N21425635: length 2.1
  TOP w0.203: D22.A 42.34,6.47 v1(42.8,6.02)
  BOTTOM w0.254: v1(42.8,6.02) 43.05,6.27 R521.1
N21425658: length 1.8
  TOP w0.203: D22.K v1(41.4,8.54)
  BOTTOM w0.203: v1(41.4,8.54) 41.44,8.57 Q16.C
N21425660: length 1.7
  BOTTOM w0.203: Q16.B 41.34,12.18 R520.1
N21425855: length 2.1
  TOP w0.203: v1(38.73,6.02) 38.28,6.47 D23.A
  BOTTOM w0.305: R523.1 38.99,6.27 v1(38.73,6.02)
N21425865: length 1.8
  TOP w0.203: D23.K v1(37.34,8.54)
  BOTTOM w0.203: v1(37.34,8.54) 37.37,8.57 Q17.C
N21425867: length 1.7
  BOTTOM w0.203: R522.1 37.28,12.05 Q17.B
N21436938: length 2.1
  TOP w0.203: D24.A 34.2,6.49 v1(34.67,6.02)
  BOTTOM w0.305: v1(34.67,6.02) 34.92,6.27 R524.1
N21436944: length 1.9
  TOP w0.203: D24.K v1(33.26,8.54)
  BOTTOM w0.203: v1(33.26,8.54) 33.3,8.57 Q18.C
N21437139: length 1.7
  BOTTOM w0.203: R525.1 33.21,12.05 Q18.B
N21437250: length 2.1
  TOP w0.203: D25.A 30.12,6.5 v1(30.61,6.02)
  BOTTOM w0.305: R526.1 30.86,6.27 v1(30.61,6.02)
N21437256: length 1.9
  TOP w0.203: D25.K v1(29.18,8.54)
  BOTTOM w0.203: v1(29.18,8.54) 29.22,8.57 Q19.C
N21437449: length 1.7
  BOTTOM w0.203: R527.1 29.15,12.18 Q19.B
N21437528: length 2.1
  TOP w0.203: D26.A 26.04,6.52 v1(26.54,6.02)
  BOTTOM w0.305: R528.1 26.8,6.27 v1(26.54,6.02)
N21437532: length 1.9
  TOP w0.203: D26.K v1(25.1,8.54)
  BOTTOM w0.203: v1(25.1,8.54) 25.14,8.57 Q20.C
N21437655: length 2.1
  TOP w0.203: D27.A 21.96,6.53 v1(22.48,6.02)
  BOTTOM w0.305: v1(22.48,6.02) 22.73,6.27 R529.1
N21437659: length 1.9
  TOP w0.203: D27.K v1(21.02,8.54)
  BOTTOM w0.203: v1(21.02,8.54) 21.06,8.57 Q21.C
N21437864: length 1.7
  BOTTOM w0.203: Q20.B 25.09,12.18 R530.1
N21437895: length 1.7
  BOTTOM w0.203: R531.1 21.02,12.18 Q21.B
N21438194: length 2.1
  TOP w0.203: v1(18.41,6.02) 17.88,6.55 D28.A
  BOTTOM w0.305: R532.1 18.67,6.27 v1(18.41,6.02)
N21438198: length 1.9
  TOP w0.203: D28.K v1(16.94,8.54)
  BOTTOM w0.203: v1(16.94,8.54) 16.98,8.57 Q22.C
N21438325: length 2.1
  TOP w0.203: D29.A 13.8,6.56 v1(14.35,6.02)
  BOTTOM w0.305: R533.1 14.61,6.27 v1(14.35,6.02)
N21438329: length 1.9
  TOP w0.203: D29.K v1(12.86,8.54)
  BOTTOM w0.203: Q23.C 12.9,8.57 v1(12.86,8.54)
N21438561: length 1.7
  BOTTOM w0.203: 17.02,12.24 16.96,12.18 Q22.B
N21438597: length 1.7
  BOTTOM w0.203: Q23.B 12.89,12.18 12.95,12.24
N21460625: length 11.4
  TOP w0.152: U3.AF23 v2(86.9,70.93)
  BOTTOM w0.127: R656.1 87.75,61.75 R710.1 87.38,62.16 87.38,70.45 v2(86.9,70.93)
N21460772: length 38.9
  TOP w0.124: U3.AF24 v2(87.9,70.93)
  L05-SIG2 w0.091: v2(87.9,70.93) 88.26,71.29 91.06,71.29 91.31,71.04 91.31,67.74 91.57,67.48 91.95,67.48 92.46,66.98 92.46,66.85 92.84,66.47 93.09,66.47 94.62,64.94 94.62,63.55 98.55,59.61 99.95,59.61 104.9,54.66 104.9,48.94 JP42.1
N21461634: length 10.9
  TOP w0.254: U43.10 124.87,42.18 124.08,42.97 PS_EN.1 124.66,43.99 v1(124.84,43.99)
  TOP w0.305: v1(129.16,47.29) 129.46,46.99 R588.2 R589.1
  L03-SIG1 w0.254: v1(124.84,43.99) 125.73,44.88 126.75,44.88 v1(129.16,47.29)
N21466678: length 1.8
  TOP w0.099: Y1.4 101.21,89.26 101.21,88.68 R537.2
N21480652: length 102.3
  TOP w0.152: U44.2 101.55,106.55 101.35,106.35 101.35,106.09 100.95,105.7 R544.2 ; R544.2 R545.1 ; R544.2 100.42,103.33 101.22,102.54 103.76,102.54 104.27,103.04 109.47,103.04 112.14,105.71 127.25,105.71 127.63,105.33 137.16,105.33 v1(141.86,100.63)
  L12-SIG4 w0.091: v1(141.86,100.63) 142.26,101.03 142.98,101.03 143.38,100.63 155.7,100.63 158.04,98.29 158.04,83.82 159.77,82.09 159.77,75.74 158.75,74.72 158.75,72.94 159.06,72.63 159.82,72.63 162.94,69.52 v2(163.93,69.52)
  BOTTOM w0.305: R563.1 v2(163.93,69.52)
N21481605: length 3.8
  TOP w0.127: v1(101.22,105.08) 101.22,105.46 101.92,106.15 U44.3
  BOTTOM w0.127: R715.1 101.48,103.93 R556.2 101.27,105.02 v1(101.22,105.08)
N21482339: length 1.5
  TOP w0.203: D75.A 163.13,131.24 v2(163.15,131.22)
  BOTTOM w0.254: R546.1 v2(163.15,131.22)
N21482349: length 1.4
  TOP w0.203: D75.K 160.02,131.24 v2(160,131.22)
  BOTTOM w0.254: Q24.C 159.99,131.23 v2(160,131.22)
N21482360: length 1.7
  BOTTOM w0.203: Q24.B 157.27,130.29 R547.1
N21645200: length 2.6
  TOP w0.203: v2(163.25,86.64) 162.88,87 D73.A
  BOTTOM w0.254: R510.2 v2(163.25,86.64)
N21892437: length 8.7
  TOP w0.152: v2(34.7,108.44) 34.7,107.63 SW7.6 SW7.3
  BOTTOM w0.152: v2(34.7,108.44) 34.98,108.17 34.98,107.53 R180.1
N21892555: length 8.6
  TOP w0.127: v2(40.97,111.42) SW7.1 SW7.4
  BOTTOM w0.152: R179.2 40.83,111.56 v2(40.97,111.42)
N21945289: length 10.1
  TOP w0.254: U45.E5 v3(156.05,71.46) ; U45.D2 v3(153.65,72.26) ; U45.D5 156.1,72.21 v3(156.07,72.21) ; U45.D7 v3(158.44,72.26) ; U45.F4 v3(155.25,69.86) ; U45.F2 v3(153.65,69.86) ; U45.H4 v3(155.25,68.26) ; U45.G7 v3(157.65,69.06)
  BOTTOM w0.254: C724.1 155.54,72.11 155.98,72.11 v3(156.07,72.21)
  BOTTOM w0.381: C61.1 153.21,70.3 v3(153.65,69.86) ; C722.1 158.37,73.62 158.37,72.33 v3(158.44,72.26) ; C723.1 157.8,68.91 v3(157.65,69.06) ; C725.1 155.87,71.28 v3(156.05,71.46) ; v3(153.65,72.26) 153.63,72.27 C1178.1 ; C1177.1 155.23,69.85 v3(155.25,69.86)
  vias: v4(150.88,67.99) v4(151.89,67.99) v4(151.89,66.98)
N21945322:
  vias: v5(146.94,55.55) v5(146.94,54.78) v5(146.94,54.02) v5(146.94,53.26) v5(149.35,65.58) v5(149.35,64.94) v5(149.35,64.31) v5(149.35,63.67)
N21945422: length 5.9
  TOP w0.254: U45.E9 v3(160.04,71.46) ; U45.F8 v3(159.24,69.86) ; U45.E8 v3(159.24,71.46)
  BOTTOM w0.381: v3(159.24,69.86) 159.24,70.61 159.07,70.79 C729.1 159.07,71.29 v3(159.24,71.46) 159.79,72 C727.1 160,71.5 v3(160.04,71.46) 160.53,70.98 C728.1
  vias: v4(152.36,65.1) v4(152.36,64.46) v4(153.11,65.06) v4(153.11,64.43)
N21948317: length 3.3
  BOTTOM w0.127: R551.1 154.31,77.15 C30.2
  BOTTOM w0.152: C30.2 155.44,78.91 R549.2
N21948373: length 3.1
  BOTTOM w0.127: R552.1 156.22,77.65 R550.2 157.36,77.39 C29.2
N21948381: length 4
  TOP w0.152: U45.C3 v3(154.44,73.06)
  BOTTOM w0.127: R551.2 154.86,75.56 154.86,73.48 v3(154.44,73.06)
N21948411: length 3.8
  TOP w0.152: U45.C4 v3(155.25,73.06)
  BOTTOM w0.127: R552.2 155.7,73.52 v3(155.25,73.06)
N21948657: length 12
  TOP w0.254: SW8.2 140.28,58.72 v1(135.13,58.72) 134.04,58.72 SW8.4
  L05-SIG2 w0.152: v1(134.49,56.31) 134.49,58.09 v1(135.13,58.72)
  BOTTOM w0.127: R80.2 v1(134.49,56.31)
N21970187:
  vias: v1(109.09,37.51) v1(109.09,35.99) v1(110.62,37.51) v1(110.62,35.99)
N21993618: length 1.8
  TOP w0.152: U45.C1 v3(152.64,73.26)
  BOTTOM w0.127: R81.2 152.02,73.89 v3(152.64,73.26)
N22007255: length 3.2
  BOTTOM w0.305: R287.1 163.19,75.23 R288.2 161.86,75.48 C94.1
N22018757: length 2.9
  BOTTOM w0.254: C1180.1 R563.2 R564.1
N22019789: length 2.3
  TOP w0.254: D78.A v1(163.83,79.04)
  BOTTOM w0.254: v1(163.83,79.04) 163.7,78.91 R567.1
N22103220: length 3
  TOP w0.152: R578.2 159.11,80.59 157.25,80.59 156.99,80.33 Q26.D
N22103236: length 1.6
  TOP w0.152: Q26.G 156.04,77.56 R579.2
N22103439: length 2.9
  TOP w0.152: U45.A8 158.24,74.86 R579.1
N22357147: length 2.2
  TOP w0.254: J8.1 156.58,96.38 R585.1
N22419042: length 60.2
  TOP w0.152: U3.R7 v2(69.9,82.93)
  L03-SIG1 w0.114: v2(69.9,82.93) 69.9,83.16 69.49,83.56 69.49,97.07 v2(68.85,97.71)
  L10-SIG3 w0.091: TP_R7.1 40.26,101.52 51.44,101.52 55.24,97.71 v2(68.85,97.71)
  BOTTOM w0.127: v2(68.85,97.71) 69.09,97.95 R398.1
N22461237: length 19.1
  TOP w0.152: U3.AE13 v2(75.9,71.93)
  BOTTOM w0.152: R654.1 R711.1 63.24,67.22 63.37,67.36 69.09,67.36 69.47,67.74 69.47,70.15 69.72,70.4 75.18,70.4 75.44,70.66 75.44,71.47 v2(75.9,71.93)
N22461561: length 42.2
  TOP w0.152: U3.AF13 v2(75.9,70.93)
  L05-SIG2 w0.091: v2(75.9,70.93) 75.9,71.09 75.44,71.55 75.44,75.87 74.93,76.37 73.91,76.37 73.41,76.88 73.41,77.01 72.9,77.52 71.75,77.52 71.5,77.77 71.5,79.17 70.61,80.06 62.36,80.06 60.71,81.71 60.71,83.23 60.45,83.49 59.56,83.49 59.31,83.74 59.31,85.39 58.62,86.08 56.85,86.08 53.98,88.95 53.98,92.68 JP38.1
N22463394: length 58.9
  TOP w0.152: U3.AG6 v2(68.9,69.93)
  L12-SIG4 w0.091: JP89.2 45.85,95.68 45.85,85.14 53.21,77.77 63.25,77.77 63.75,77.26 71.25,77.26 71.5,77.01 71.5,73.71 71.75,73.45 75.18,73.45 75.56,73.07 75.56,70.66 75.31,70.4 69.37,70.4 v2(68.9,69.93)
N22463398: length 8.3
  TOP w0.152: U3.AG5 v2(67.9,69.93)
  BOTTOM w0.152: v2(67.9,69.93) 67.42,69.45 67.42,68.74 67.06,68.38 R713.1 R653.1
N22505657: length 1.9
  TOP w0.127: J25.A8 154.7,19.09 TP26.1
N22505665: length 9.9
  TOP w0.127: J25.B8 158.48,17.33 158.75,17.06 158.75,13.76 157.86,12.87 TP25.1
N22506509: length 2.1
  TOP w0.117: U108.21 145.03,12.45 145.15,12.58 145.15,13.4 R599.2
N22506512: length 2.1
  TOP w0.117: U108.20 145.53,12.45 145.41,12.58 145.41,13.38 R600.2
N22506572: length 2.4
  TOP w0.203: U108.19 146.03,12.35 v1(146.3,12.62)
  BOTTOM w0.381: R648.2 146.84,11.99 C1185.1
N22506942: length 2
  TOP w0.127: U108.18 148.32,11.2 R601.1
N22506945: length 2
  TOP w0.127: R602.1 148.36,10.7 U108.17
N22513651: length 4.4
  TOP w0.203: R613.2 R610.2 147.27,27.3 145.94,25.97 U111.4
N22518145: length 3.8
  TOP w0.203: R612.2 119.38,21.38 119.38,22.14 119.9,22.67 U110.23
N22518148: length 5.1
  TOP w0.203: U111.23 148.7,24.67 148.97,24.94 148.97,26.79 150.24,28.06 R611.2
N22519451: length 13.1
  TOP w0.203: U110.20 119.9,24.17 v1(119.38,24.68) 119.38,25.83 119.13,26.08 C1266.1
  TOP w0.305: R615.1 R618.1 v1(116.08,19.1)
  BOTTOM w0.203: v1(116.08,19.1) 118.75,21.76 118.75,24.05 v1(119.38,24.68)
N22519923: length 2.6
  TOP w0.203: C1267.1 149.35,22.65 148.84,23.17 U111.20
N22520337: length 4.1
  TOP w0.203: U110.1 121.04,21.01 120.78,20.75 120.14,20.75 R618.2
N22520353: length 5.2
  TOP w0.203: U111.1 147.69,26.1 149.35,27.76 149.35,28.75 R617.2
N22520434: length 7.9
  TOP w0.203: U110.15 122.79,24.7 123.04,24.46 126.14,24.46 126.49,24.81 126.49,26.85 C1203.1
N22520437: length 1.5
  TOP w0.254: C1203.2 127.77,26.09 127.76,26.08
N22520459: length 4.2
  TOP w0.254: L25.1 140.96,23.04 C1202.2
N22520465: length 7.9
  TOP w0.203: C1202.1 142.24,20.49 142.24,22.53 142.6,22.88 145.69,22.88 145.94,22.63 U111.15
N22523186: length 5.3
  TOP w0.203: R622.1 150.12,24.17 U111.22
  TOP w0.381: R621.1 C1667.2 R622.1
N22523201: length 5.3
  TOP w0.203: C1666.2 R619.1 ; R619.1 R620.1 ; R619.1 118.61,23.17 U110.22
N22530625: length 4.2
  TOP w0.254: U114.5 28.83,37.51 v1(29.08,37.26)
  BOTTOM w0.254: R624.1 R625.1 28.7,36.88 v1(29.08,37.26) 29.34,37.51 C1219.2
N22531796: length 5
  TOP w0.254: U114.6 29.08,38.01 29.08,38.02
  TOP w0.381: C101.2 30.1,35.41 R399.1 R401.2 29.08,38.02
N22581142: length 4.2
  TOP w0.254: U115.5 43.94,37.51 v1(44.2,37.26)
  BOTTOM w0.254: C1220.2 44.45,37.51 v1(44.2,37.26) 43.81,36.88 R629.1 R628.1
N22604437: length 2.3
  TOP w0.381: U116.3 v1(95.27,128.59)
  BOTTOM w0.381: v1(95.27,128.59) 95.25,128.57 R185.2
N22604439: length 3.9
  TOP w0.381: v1(98.3,128.7) 98.27,128.67 U116.1
  BOTTOM w0.381: R189.1 98.29,126.29 R192.2 98.29,128.69 v1(98.3,128.7)
N22625096: length 0.9
  BOTTOM w0.127: v3(107.73,65.52) 107.55,65.7 R633.2
N22668834: length 3.9
  TOP w0.254: R639.2 R638.2 159.38,30.15 158.5,29.26 U118.2
N22670042: length 3.4
  TOP w0.254: R640.1 155.57,31.29 R641.1 156.02,31.22 U118.4
N22671497: length 6.2
  TOP w0.203: U111.19 148.57,22.67 148.84,22.4 148.84,21.76 149.35,21.26 R642.1 C1265.1 R649.1
N22672695: length 7
  TOP w0.203: U110.19 120.29,24.67 119.89,25.07 119.89,26.08 R643.1 C1264.1 R650.1
N22703478: length 3.8
  BOTTOM w0.203: JP83.3 124.84,87.68 R292.1
N22703481: length 2.5
  BOTTOM w0.254: JP83.1 125.6,83.36 R598.2
N22703488: length 2.5
  BOTTOM w0.254: R597.2 125.6,79.17 126.11,79.68
N22703491: length 2.9
  BOTTOM w0.203: R293.1 125.6,74.09 JP84.1
N22703555: length 2.8
  BOTTOM w0.381: R646.1 JP85.3
N22703558: length 2.2
  BOTTOM w0.254: R645.2 116.59,49.84 116.59,49.83
N22703565: length 2.2
  BOTTOM w0.254: R644.2 121.66,54.16 JP86.3
N22703568: length 3.1
  BOTTOM w0.381: R647.1 116.08,54.66 116.59,54.15
N22778691: length 0.9
  TOP w0.381: J54.K40 v4(105.54,10.49)
N22778693: length 0.9
  TOP w0.381: J54.J39 v4(104.27,11.76)
N22778746: length 0.9
  TOP w0.381: J48.K40 v2(5.49,54.91)
N22778748: length 0.9
  TOP w0.381: J48.J39 v2(6.76,56.18)
N23028314: length 0.8
  BOTTOM w0.127: U46.11 v1(112.4,36.75)
N23029118: length 3.2
  TOP w0.508: FB6.2 C69.1 60.85,96.68 X3.4
N23029151: length 1.6
  TOP w0.127: X3.3 60.83,92.9 R110.1
N23030072: length 22.3
  TOP w0.203: D12.K v1(152.4,145.16)
  BOTTOM w0.152: v1(152.4,145.16) 152.15,144.91 152.15,143.05 151.89,142.79 136.78,142.79 136,143.57 Q27.C
N23030074: length 30.8
  TOP w0.203: v2(154.81,145.16) D13.K
  BOTTOM w0.152: v2(154.81,145.16) 154.81,143.05 154.2,142.44 136.25,142.44 134.87,143.81 130.56,143.81 130.03,144.33 Q28.C
N23030106: length 1.6
  TOP w0.203: v2(154.05,143.57) 153.99,143.51 D12.A
  BOTTOM w0.305: R62.1 v2(154.05,143.57)
N23030124: length 1.5
  TOP w0.203: D13.A v2(155.82,142.77)
  BOTTOM w0.305: R63.1 v2(155.82,142.77)
N23030387: length 1.9
  BOTTOM w0.203: Q27.B 132.15,145.27 R683.1
N23030530: length 1.7
  BOTTOM w0.203: Q28.B 126.43,145.27 R684.1
N23050396: length 0.7
  TOP w0.152: U3.AF26 v1(89.9,71.93)
N23063052: length 5.6
  TOP w0.127: R686.1 60.09,77.92 64.89,77.92 U3.W2
N23067021: length 1.6
  BOTTOM w0.203: Q29.B 113.22,147.3 R687.1
N23067044: length 1.7
  BOTTOM w0.203: Q30.B 123.51,147.3 R688.1
N23067876: length 1.6
  BOTTOM w0.203: Q31.B 118.43,147.3 R689.1
N23067899: length 1.5
  BOTTOM w0.203: Q32.B 97.98,147.17 R690.1
N23068194: length 1.6
  BOTTOM w0.203: R691.1 108.02,147.3 Q33.B
N23068217: length 1.6
  BOTTOM w0.203: R692.1 103.06,147.3 Q34.B
N23070235: length 5.1
  TOP w0.152: v1(143.64,72.56) 143.2,73 C1269.1 141.8,71.8 141.35,71.8 141.06,71.52 U120.2
  BOTTOM w0.152: R52.1 v1(143.64,72.56)
N23070376: length 0.6
  TOP w0.254: U120.25 v1(142.35,66.45)
N23070416: length 2.5
  TOP w0.152: R695.1 137.53,72.44 138.07,71.91 U120.8
N23070431: length 2.9
  TOP w0.254: U120.19 138.56,65.59 137.16,64.18 R696.1
N23070448: length 3.9
  TOP w0.254: R54.2 135.25,64.18 136.4,65.32 137.03,65.32 137.56,65.86 U120.17
N23076171: length 18.9
  TOP w0.381: v1(160.02,63.93) 160.02,63.17 158.62,61.77 R561.2
  BOTTOM w0.254: R562.1 C1179.1 v1(160.02,63.93)
N23077522: length 1.6
  TOP w0.203: D70.A 163.12,134.79 v2(163.15,134.77)
  BOTTOM w0.254: R475.1 v2(163.15,134.77)
N23077532: length 1.4
  TOP w0.203: v2(160.05,134.77) 160.07,134.79 D70.K
  BOTTOM w0.254: v2(160.05,134.77) 160,134.77 159.99,134.77 Q15.C
N23077534: length 1.7
  BOTTOM w0.203: R474.1 155.62,133.82 Q15.B
N23166257: length 3.2
  TOP w0.203: v1(121.41,19.22) 121.41,19.99 122.79,21.36 U110.4

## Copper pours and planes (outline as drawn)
1V8_LDO on TOP: 98.04,124.38 100.33,124.38 100.46,124.25 100.46,121.59 100.33,121.46 98.17,121.46 97.92,121.71 97.92,124.25
1V8_LDO on BOTTOM: 114.05,87.17 113.92,87.3 113.92,90.47 115.95,92.5 119.13,92.5 119.63,93.01 119.63,101.77 119.89,102.03 121.92,102.03 122.17,101.77 122.17,90.85 121.41,90.09 117.22,90.09 116.08,88.95 116.08,87.3 115.95,87.17
1V8_LDO on BOTTOM: 97.92,125.14 97.92,120.7 98.17,120.44 100.2,120.44 100.46,120.7 100.46,125.01 100.33,125.14
1V8_LDO on L05-SIG2: 99.44,124.63 121.03,124.63 123.44,122.22 123.44,101.39 122.81,100.76 115.32,100.76 113.79,102.28 113.79,116.12 109.85,120.06 100.08,120.06 99.06,121.08 99.06,124.25
1V80_MON on TOP: 141.67,95.14 140.36,95.14 140.18,94.95 140.18,93.31 140.38,93.11 141.47,93.11 141.7,93.34 141.7,95.11
1V80_MON on L03-SIG1: 161.27,75.89 161.27,73 160.97,72.71 160.31,72.71 159.57,73.44 157.58,73.44 157.36,73.23 157.36,71.27 158.14,70.49 158.14,67.64 157.79,67.3 156.5,67.3 155.63,68.17 155.63,76.6 150.37,81.86 148.06,81.86 140.21,89.71 140.21,94.15 140.87,94.82 150.69,94.82 152.53,92.98 152.53,87.55 159.26,80.82 159.26,77.9
GND on TOP (solid shape): 126.75,22.02 126.75,20.49 127,20.24 130.05,20.24 130.3,19.99 130.3,16.81 130.18,16.68 124.97,16.68 124.71,16.94 124.71,22.53 126.24,22.53
GND on TOP (solid shape): 144.02,30.02 144.02,24.81 142.49,24.81 142.11,25.19 142.11,26.72 141.73,27.1 138.81,27.1 138.43,27.48 138.43,30.15 138.56,30.27 143.76,30.27
GND on TOP (solid shape): 133.67,126.25 133.67,125.41 133.67,125.41 132.45,125.41 131.8,124.75 131.52,124.75 131.47,124.81 130.86,124.81 130.8,124.75 127.87,124.75 127.71,124.91 127.71,127.26 127.77,127.32 132.6,127.32
GND on TOP (solid shape): 133.67,111.78 133.67,110.93 133.67,110.93 132.45,110.93 131.8,110.27 131.52,110.27 131.47,110.33 130.86,110.33 130.8,110.27 127.87,110.27 127.71,110.44 127.71,112.78 127.77,112.84 132.6,112.84
GND on TOP (solid shape): 133.67,97.53 133.67,96.68 133.67,96.68 132.45,96.68 131.8,96.02 131.52,96.02 131.47,96.08 130.86,96.08 130.8,96.02 127.87,96.02 127.71,96.19 127.71,98.53 127.77,98.59 132.6,98.59
GND on TOP (solid shape): 134.34,84.44 134.34,83.6 134.34,83.6 133.12,83.6 132.52,83 132.43,83 132.42,83.01 131.81,83.01 131.8,83 128.76,83 128.65,83.1 128.65,85.38 128.78,85.51 133.27,85.51
GND on TOP (solid shape): 147.99,82.65 147.99,81.8 147.99,81.8 146.77,81.8 146.12,81.14 145.84,81.14 145.79,81.2 145.18,81.2 145.12,81.14 142.19,81.14 142.03,81.3 142.03,83.65 142.09,83.71 146.92,83.71
GND on TOP (solid shape): 147.68,137.06 147.68,136.92 148.15,136.45 148.15,135.71 147.14,135.71 146.89,135.46 146.89,135.35 146.45,134.91 146.18,134.91 146.12,134.97 145.51,134.97 145.45,134.91 142.52,134.91 142.36,135.07 142.36,137.42 142.43,137.48 147.26,137.48
GND on TOP (solid shape): 147.68,122.58 147.68,122.44 148.15,121.98 148.15,121.23 147.14,121.23 146.89,120.98 146.89,120.87 146.45,120.43 146.18,120.43 146.12,120.49 145.51,120.49 145.45,120.43 142.52,120.43 142.36,120.6 142.36,122.94 142.43,123 147.26,123
GND on TOP (solid shape): 147.68,107.85 147.68,107.71 148.15,107.24 148.15,106.5 147.14,106.5 146.89,106.25 146.89,106.14 146.45,105.7 146.18,105.7 146.12,105.76 145.51,105.76 145.45,105.7 142.52,105.7 142.36,105.86 142.36,108.21 142.43,108.27 147.26,108.27
GND on TOP (solid shape): 29.93,26.25 30.05,26.13 38.35,26.13 38.48,26.01 38.48,23.92 38.35,23.8 36.55,23.8 36.02,23.26 34.34,23.26 34.19,23.41 31.09,23.41 30.89,23.21 30.89,21.13 30.84,21.08 30.08,21.08 28.7,22.45 27.89,22.45 27.85,22.49 27.34,22.49 27.31,22.45 22.94,22.45 22.94,24.33 26.34,27.73 29.93,27.73
GND on TOP (solid shape): 147.25,94.64 147.25,94.5 147.71,94.03 147.71,93.29 146.7,93.29 146.46,93.04 146.46,92.93 146.02,92.49 145.74,92.49 145.68,92.55 145.07,92.55 145.02,92.49 142.09,92.49 141.98,92.6 141.98,94.03 141.99,94.07 141.99,94.11 141.99,94.8 141.99,94.84 141.98,94.91 142.13,95.06 146.82,95.06
GND on TOP (solid shape): 130.3,30.15 130.3,27.86 130.05,27.61 129.03,27.61 128.65,27.99 128.11,27.99 127.8,28.11 127.48,28.03 127.22,28.09 126.96,28 126.95,27.99 126.87,27.99 126.49,27.61 126.49,27.54 126.01,27.05 126.01,26.74 125.98,26.72 125.98,25.07 125.86,24.94 124.84,24.94 124.71,25.07 124.71,30.15 124.84,30.27 130.18,30.27
GND on TOP (solid shape): 144.02,22.27 144.02,16.81 143.96,16.75 138.49,16.75 138.43,16.81 138.43,19.48 138.56,19.6 139.83,19.6 140.08,19.35 140.63,19.35 140.93,19.22 141.25,19.31 141.51,19.25 141.77,19.34 141.78,19.35 141.86,19.35 142.24,19.73 142.24,19.8 142.72,20.29 142.72,20.6 142.75,20.62 142.75,22.27 142.88,22.4 143.89,22.4
GND on TOP (solid shape): outline of 122 points within 37.09,30.97 46.5,56.56
GND on TOP: 101.85,120.57 101.47,120.19 92.33,120.19 92.2,120.32 92.2,131.87 92.96,132.63 101.47,132.63 101.85,132.25
GND on TOP: 123.7,72.18 128.4,72.18 128.91,71.67 128.91,60.63 128.65,60.37 123.82,60.37 123.63,60.56 123.63,62.21 123.57,62.28 123.57,72.06
GND on TOP: 103.25,109.65 103.25,111.17 105.89,111.17 106.22,110.84 106.22,110.11 105.77,109.65
GND on TOP: 137.79,40.94 137.79,36.62 136.65,35.48 128.91,35.48 128.65,35.73 128.65,37.51 128.52,37.64 127.13,37.64 126.87,37.38 126.87,33.07 128.02,31.92 141.35,31.92 142.37,32.94 142.37,40.94 142.24,41.07 137.92,41.07
GND on TOP: 108.41,134.64 106.88,134.64 105.99,135.53 105.99,140.36 106.32,140.69 107.82,140.69 108.48,140.03 108.48,134.72
GND on TOP: 27.56,41.58 27.56,39.29 27.18,38.91 27.18,37.38 27.05,37.26 25.91,37.26 25.4,36.75 25.4,35.86 25.65,35.61 27.94,35.61 28.19,35.35 28.19,34.59 27.56,33.96 27.56,31.8 27.69,31.67 29.34,31.67 29.97,32.3 29.97,35.61 29.59,35.99 29.59,38.65 29.97,39.04 31.24,39.04 31.37,39.16 31.37,41.45 31.24,41.58
GND on TOP: 137.57,45.76 136.42,45.76 136.04,45.38 135.28,45.38 134.34,44.44 130.32,44.44 130.26,44.5 130.26,45.28 130.31,45.33 131.3,45.33 131.47,45.5 131.47,46.53 131.6,46.65 133.88,46.65 134.65,47.42 137.44,47.42 137.69,47.16 137.69,45.89
GND on TOP: 127.27,43.58 126.58,43.58 126.5,43.5 126.5,42.82 126.43,42.74 125.84,42.74 125.81,42.7 125.81,40.57 125.84,40.53 126.37,40.53 126.37,39.42 126.49,39.29 127.25,39.29 127.25,39.81 127.29,39.84 127.29,40.52 128.08,40.52 128.15,40.45 128.91,40.45 128.91,41.34 128.13,41.34 127.99,41.48 127.99,42.73 127.97,42.75 127.39,42.75 127.3,42.84 127.3,43.54
GND on TOP: 51.18,124.89 56.01,124.89 56.13,124.76 56.13,119.81 55.88,119.55 51.18,119.55 50.93,119.81 50.93,124.63
GND on TOP: 8.85,138.08 1.24,138.08 0.56,137.39 0.56,125.53 0.87,125.23 8.97,125.23 10.01,126.27 10.01,130.07 9.66,130.42 6.15,130.42 5.88,130.69 5.88,134.13 6.1,134.36 8.72,134.36 9.97,135.61 9.97,136.96
GND on TOP: 152.91,139.54 152.91,136.09 153.19,135.81 154.58,135.81 155.42,134.97 155.42,125.52 153.01,123.11 153.01,121.41 153.19,121.23 154,121.23 155.47,119.76 155.47,102.82 155.89,102.41 159,102.41 159.44,102.84 159.44,137.26 156.84,139.85 153.21,139.85
GND on TOP: 146.43,7.29 146.43,5.89 146.56,5.76 148.08,5.76 148.21,5.89 148.21,7.54 148.08,7.67 146.81,7.67
GND on TOP: 156.59,29.51 156.59,27.35 155.19,25.95 153.67,25.95 153.54,25.83 153.54,24.05 153.8,23.8 162.31,23.8 162.56,24.05 162.56,30.91 160.78,32.69 153.42,32.69 152.91,32.18 152.91,29.64 153.03,29.51
GND on TOP: 130.91,135.05 130.81,134.95 129.46,134.95 129.01,135.4 129.01,140.51 129.26,140.76 130.71,140.76 130.91,140.56
GND on TOP: 61.85,103.04 57.4,103.04 56.13,101.77 56.13,91.36 57.66,89.84 61.85,89.84 62.36,90.34 62.36,102.54 ; 1 cut-out
GND on TOP: 136.14,69.9 136.14,68.25 136.27,68.12 138.81,68.12 138.94,68.25 138.94,69.26 139.06,69.39 147.83,69.39 147.95,69.52 147.95,72.82 147.57,73.2 144.02,73.2 141.99,71.17 141.6,71.17 141.48,71.04 141.48,70.28 141.22,70.02 136.27,70.02
GND on BOTTOM: 124.84,71.55 126.62,73.33 135,73.33 137.16,71.17 141.22,71.17 142.75,72.69 148.08,72.69 148.59,72.18 148.59,61.39 147.57,60.37 142.75,60.37 141.6,61.51 137.54,61.51 136.4,60.37 125.48,60.37 124.84,61.01
GND on BOTTOM: 0.51,70.02 0.51,141.27 29.59,141.27 31.5,139.37 31.5,74.47 27.05,70.02 ; 4 cut-outs
GND on BOTTOM: 130.81,20.49 130.94,20.62 137.92,20.62 138.18,20.37 138.18,17.19 138.43,16.94 144.02,16.94 144.14,17.06 144.14,30.07 143.71,30.5 138.12,30.5 137.92,30.31 137.92,26.97 137.67,26.72 130.94,26.72 130.68,26.97 130.68,30.36 130.5,30.54 124.65,30.54 124.46,30.35 124.46,17.06 124.71,16.81 130.56,16.81 130.81,17.06
GND on BOTTOM: 27.43,39.67 27.94,39.16 28.45,39.16 28.83,38.78 28.83,38.4 28.96,38.27 29.34,38.27 29.72,37.89 29.72,36.62 29.34,36.24 27.05,36.24 26.92,36.37 26.92,37.13 26.8,37.26 25.53,37.26 25.15,36.88 25.15,35.99 27.75,33.38 27.75,32.37 27.81,32.3 27.81,30.91 23.11,26.21 23.11,22.65 23.88,21.89 33.91,21.89 35.43,23.41 35.43,23.54 46.1,23.54 49.15,26.59 49.15,50.47 47.5,52.12 38.23,52.12 37.21,51.1 28.83,51.1 27.43,49.7 ; 1 cut-out
GND on BOTTOM: 56.26,24.18 91.19,24.18 91.69,23.67 91.69,7.54 90.93,6.78 56.13,6.78 55.88,7.03 55.88,23.8
GND on BOTTOM: 128.52,37.38 128.52,47.16 127.89,47.8 122.94,47.8 122.68,47.54 122.68,32.94 123.95,31.67 143.38,31.67 143.64,31.92 143.64,35.86 143.51,35.99 129.92,35.99
GND on BOTTOM: 55.96,126.89 51.21,126.89 50.7,126.39 50.7,120.06 50.93,119.83 55.96,119.83 57.07,120.95 57.07,125.01 56.82,125.27 56.49,125.27 56.31,125.45 56.31,126.54
GND on L02-GND, L04-GND, L06-GND, L09-GND, L11-GND, L13-GND: 0.51,5.51 0.51,149.49 164.49,149.49 164.49,5.51 ; 4 cut-outs
GND on L05-SIG2: 149.88,143.31 162.78,143.31 164.29,141.8 164.29,134.92 163.58,134.21 153.8,134.21 153.14,134.87 141.74,134.87 141.59,135.02 141.59,138.97 142.79,140.17 146.74,140.17
GND on L05-SIG2: 9.9,142.9 0.95,142.9 0.53,142.48 0.53,127.62 1.52,126.63 10.49,126.63 12.25,124.87 12.25,117.79 5.22,110.76 5.22,104.05 5.4,103.86 12.92,103.86 13.81,104.76 13.81,106.05 14.14,106.38 14.6,106.38 15.52,105.45 19.1,105.45 19.59,105.94 34.98,105.94 35.7,106.66 35.7,118.4 31.62,122.49 28.9,122.49 15.45,135.93 11.93,135.93 10.38,137.48 10.38,142.42
GND on L07_POW1: 59.36,110.29 38.5,89.43 38.5,88.85 39.45,87.91 60.52,87.91 61.22,88.61 61.22,109.63 60.56,110.29
GND on L07_POW1: 34.1,149.4 3.35,149.4 0.58,146.64 0.58,113.53 0.78,113.33 1.87,113.33 32.57,144.03 32.57,145.42 33.28,146.13 34.43,146.13 35.08,146.78 35.08,148.42
GND on L08-POW2: 59.44,72.94 73.66,72.94 74.04,72.56 74.04,59.61 73.79,59.36 59.94,59.36 59.18,60.12 59.18,72.69
GND on L08-POW2: 111.76,21.38 163.45,21.38 164.34,20.49 164.34,7.03 163.07,5.76 112.4,5.76 111.12,7.03 111.12,20.75
GND on L10-SIG3: 1.64,113.79 0.6,114.83 0.6,145.12 4.75,149.27 15.61,149.27 15.63,149.29 57.67,149.29 58.15,148.81 58.15,144.16 54.89,140.9 54.89,136.09 46.76,127.96 34.47,127.96 32.39,130.04 32.39,138.1 30.67,139.81 19.11,139.81 15.26,135.95 15.26,123.04 6,113.79
GND on L12-SIG4: 159.36,68.91 159.36,83.74 159.38,83.74 159.38,97.58 159.64,97.84 164,97.84 164.38,97.46 164.38,50 163.45,49.07 149.86,49.07 149.35,49.58 149.35,61.26 149.73,61.64 160.27,61.64 161.54,62.91 161.54,66.72
GND on L12-SIG4: 118.37,123.02 118.37,115.62 118.36,115.62 117.86,115.11 103.76,115.11 103.38,115.49 103.38,120.95 102.11,122.22 69.72,122.22 67.06,119.55 56.26,119.55 56.14,119.43 49.16,119.43 48.78,119.81 48.78,122.1 49.03,122.35 64.9,122.35 74.04,131.49 109.9,131.49
GND on L12-SIG4: 57.36,148.8 3.57,148.8 0.74,145.97 0.74,119.98 1.21,119.51 4.48,119.51 5.15,120.18 5.15,131.83 7.71,134.39 7.71,136.01 14.71,143 57.26,143 58.06,143.81 58.06,148.09
VCC_0V82 on TOP: 136.65,70.27 136.59,70.21 136.06,70.21 134.75,68.89 134.75,66.85 135.89,66.85 136.02,66.72 136.65,66.72 136.65,66.09 135.51,64.94 135.13,64.94 134.73,64.55 134.73,61.41 134.22,60.9 132.23,60.9 131.69,60.36 131.2,60.36 131.19,60.37 130.05,60.37 129.79,60.63 129.79,61.9 128.91,62.78 128.91,73.83 129.29,74.21 135.38,74.21 135.89,73.71 135.89,72.56 136.65,71.8
VCC_0V82 on TOP: 6.1,24.3 6.1,17.7 14.35,9.44 42.8,9.44 44.39,11.03 44.39,20.87 50.48,26.97 111.47,26.97 111.95,27.46 111.95,30.69 111.61,31.03 47.88,31.03 39.37,22.53 39.37,17.32 34.73,12.68 18.86,12.68 14.86,16.68 14.86,24.3 14.22,24.94 6.73,24.94
VCC_0V82 on TOP: 119.63,94.92 119.63,100.76 119.38,101.01 114.81,101.01 113.54,102.28 106.04,102.28 105.79,102.03 105.79,95.04 106.3,94.53 119.25,94.53
VCC_0V82 on BOTTOM: 107.14,99.95 107.14,95.17 107.52,94.79 118.62,94.79 118.81,94.98 118.81,100.06 118.62,100.25 107.44,100.25
VCC_0V82 on BOTTOM: 134.49,63.17 134.52,63.17 134.52,71.01 134.11,71.42 130.59,71.42 130.21,71.04 130.21,61.64 130.43,61.42 130.43,61.39 134.11,61.39 134.49,61.77
VCC_0V82 on L03-SIG1: 118.87,99.49 108.59,99.49 107.7,98.6 107.7,95.42 108.2,94.92 119,94.92 119.13,95.04 119.13,99.23
VCC_0V82 on L10-SIG3: 120.9,48.81 108.33,48.81 107.06,47.54 107.06,29.51 107.44,29.13 115.19,29.13 120.14,34.08 131.32,34.08 143.51,46.27 143.51,65.83 144.4,66.72 147.57,66.72 148.46,67.61 148.46,94.15 147.7,94.92 134.11,94.92 130.3,98.73 120.27,98.73 119.38,99.61 115.57,99.61 114.17,98.22 114.17,87.8 115.51,86.47 115.57,86.47 116.78,85.26 120.14,85.26 121.79,83.61 121.79,49.7
VCC_0V90 on TOP (solid shape): 147.62,128.13 147.62,123.86 147.43,123.67 142.12,123.67 142.04,123.75 142.04,128.15 142.22,128.32 147.43,128.32
VCC_0V90 on BOTTOM: 142.12,123.67 145.21,123.67 145.57,124.03 147.42,124.03 147.62,124.24 147.62,128.06 147.43,128.25 142.19,128.25 142.04,128.1 142.04,123.75
VCC_0V90 on L05-SIG2: 8.77,18.77 1.08,18.77 0.51,19.34 0.51,124.44 1.35,125.28 10.06,125.28 11.52,123.81 11.52,119.01 4.54,112.02 4.54,47.15 9.46,42.23 9.46,19.46
VCC_0V90 on L12-SIG4: 130.23,149.42 68.44,149.42 61.07,142.06 16.79,142.06 5.82,131.09 5.82,118.56 7.14,117.24 15.32,117.24 16.89,118.81 16.89,123.61 27.07,133.8 64.73,133.8 72.54,141.61 117.57,141.61 126.11,133.08 126.11,125.57 123.77,123.24 123.77,117.06 124.38,116.46 126.7,116.46 127.99,117.75 145.92,117.75 147.47,119.3 147.47,132.18
VCC_1V00 on TOP (solid shape): 147.62,141.79 147.62,138.34 147.43,138.15 142.12,138.15 142.04,138.23 142.04,141.77 142.23,141.96 147.45,141.96
VCC_1V00 on BOTTOM: 142.12,138.15 145.21,138.15 145.57,138.51 147.42,138.51 147.62,138.72 147.62,141.47 147.45,141.65 142.29,141.65 142.04,141.4 142.04,138.23
VCC_1V00 on L07_POW1: 6.91,105.13 6.91,24.75 7.32,24.34 11.43,24.34 11.73,24.64 11.73,27.12 12.9,28.29 12.9,101.28 45.61,133.99 108.32,133.99 121.43,120.87 155.32,120.87 156.54,122.09 156.54,141.02 155.19,142.36 136.09,142.36 134.77,141.04 134.77,128.85 133.09,127.17 126.6,127.17 114.98,138.78 40.56,138.78
VCC_1V10 on TOP (solid shape): 147.62,112.58 147.62,109.13 147.43,108.94 142.12,108.94 142.04,109.02 142.04,112.56 142.23,112.75 147.45,112.75
VCC_1V10 on BOTTOM: 124.33,95.93 124.21,96.06 124.21,98.09 124.33,98.22 125.98,98.22 126.11,98.09 126.11,96.06 125.98,95.93
VCC_1V10 on BOTTOM: 142.12,108.94 145.21,108.94 145.57,109.3 147.42,109.3 147.62,109.51 147.62,112.58 147.45,112.75 142.23,112.75 142.04,112.56 142.04,109.02
VCC_1V10 on L07_POW1: 10.52,13.58 8.87,15.23 8.87,22.54 9.05,22.72 12.48,22.72 13.22,21.98 13.22,19.85 14.56,18.51 21,18.51 25.43,22.93 25.43,90.16 57.29,122.03 57.4,122.03 59.12,123.74 66.42,123.74 68.14,122.03 91.06,122.03 93.54,124.51 102.36,124.51 117.72,109.15 136.08,109.15 139.63,112.7 146.84,112.7 147.57,111.96 147.57,97.2 145.99,95.61 123.76,95.61 122.56,96.82 122.56,101.52 121.92,102.15 117.22,102.15 101.57,117.81 99.28,117.81 97.16,119.93 93.34,119.93 91.22,117.81 65.37,117.81 31.36,83.8 31.36,15.44 29.49,13.58
VCC_1V20 on TOP (solid shape): 132.97,102.9 132.97,99.45 132.78,99.26 127.47,99.26 127.38,99.34 127.38,102.49 127.97,103.08 132.79,103.08
VCC_1V20 on TOP: 102.82,106.83 103.2,106.83 103.57,107.2 104.07,107.2 104.89,106.38 106.24,106.38 106.36,106.5 106.36,109 106.17,109.19 103.36,109.19 103.11,108.95 103.11,108.08 102.82,107.79 102.82,106.83
VCC_1V20 on BOTTOM: 106.33,108.86 106,109.19 103.35,109.19 103.17,109.01 103.17,107.9 102.84,107.57 102.84,106.7 102.36,106.22 102.36,103.76 102.57,103.55 106.15,103.55 106.33,103.74
VCC_1V20 on BOTTOM: 127.47,99.26 130.55,99.26 130.92,99.62 132.76,99.62 132.97,99.83 132.97,102.9 132.79,103.08 127.58,103.08 127.38,102.88 127.38,99.34
VCC_1V20 on L07_POW1: 58.22,124.25 24.82,90.85 24.82,24.01 20.31,19.5 15.39,19.5 14.55,20.34 14.55,22.78 14.88,23.11 17.6,23.11 19.48,24.99 19.48,95.93 52.06,128.51 88.52,128.51 88.52,128.44 88.9,128.06 88.9,124.89 88.26,124.25
VCC_1V20 on L10-SIG3: 120.65,99.11 120.14,99.61 120.14,112.7 119.13,113.71 111.51,113.71 111.38,113.58 111.25,113.58 111,113.33 111,110.16 105.79,104.95 102.24,104.95 101.09,106.09 101.09,109.27 100.19,110.17 75.35,110.17 75.35,119.41 74.56,120.21 68.08,120.21 67.75,120.53 67.75,128.44 68.21,128.9 127.94,128.9 132.97,123.87 132.97,103.3 132.59,102.92 132.59,99.61 132.08,99.11
VCC_1V35 on TOP (solid shape): 147.29,88.02 147.29,84.57 147.1,84.38 141.79,84.38 141.71,84.46 141.71,88 141.9,88.2 147.11,88.2
VCC_1V35 on BOTTOM: 141.79,84.38 144.87,84.38 145.24,84.74 147.08,84.74 147.29,84.95 147.29,88.02 147.11,88.2 141.9,88.2 141.71,88 141.71,84.46
VCC_1V35 on L05-SIG2: 12.32,6.02 11.56,6.78 11.56,21.38 12.06,21.89 14.1,21.89 14.61,21.38 14.61,13.38 19.81,8.17 110.11,8.17 115.19,13.25 115.19,32.81 116.84,34.46 135.25,34.46 144.11,43.32 144.11,81 142.04,83.08 142.04,87.88 142.39,88.24 150.19,88.24 151.03,87.4 151.03,81.07 153.11,78.99 153.11,50.64 154.94,48.81 154.94,33.32 151.51,29.89 121.79,29.89 119.95,28.05 119.95,14.08 111.89,6.02
VCC_1V35 on L12-SIG4: 125.22,94.41 125.86,93.77 128.27,93.77 129.03,93.01 131.44,93.01 134.09,90.37 137.39,90.37 138.43,89.33 138.43,85.44 139.52,84.35 145.95,84.35 147.02,85.42 147.02,96.01 142.77,100.25 131.7,100.25 127.13,104.82 123.82,104.82 123.06,104.06 123.06,94.92 123.57,94.41
VCC_1V50 on TOP (solid shape): 132.97,117.15 132.97,113.7 132.78,113.51 127.47,113.51 127.38,113.59 127.38,117.13 127.58,117.33 132.79,117.33
VCC_1V50 on BOTTOM: 127.47,113.51 130.55,113.51 130.92,113.87 132.76,113.87 132.97,114.08 132.97,117.15 132.79,117.33 127.58,117.33 127.38,117.13 127.38,113.59
VCC_1V50 on L07_POW1: 98.54,129 51.2,129 18.85,96.64 18.85,25.91 17.32,24.38 12.5,24.38 12.24,24.64 12.24,26.78 13.53,28.08 13.53,100.64 46.34,133.45 107.7,133.45 121.89,119.27 155.28,119.27 156.34,118.21 156.34,105.03 155.85,104.54 153.8,104.54 153.29,105.05 153.29,112.04 151.71,113.61 138.2,113.61 135.46,110.87 135.46,110.84 134.21,109.59 117.94,109.59
VCC_1V80 on TOP (solid shape): 146.69,99.23 146.69,95.93 146.48,95.73 142.16,95.73 141.86,95.42 141.45,95.42 141.35,95.43 141.25,95.42 140.84,95.42 140.59,95.68 140.59,99.23 140.9,99.54 146.38,99.54
VCC_1V80 on BOTTOM: 145.14,96.09 146.98,96.09 147.19,96.3 147.19,99.37 147.01,99.54 139.76,99.54 138.68,98.47 138.68,92.12 137.41,90.85 137.41,85.01 138.05,84.37 140.84,84.37 141.48,85.01 141.48,88.31 142.49,89.33 142.49,92.12 142.88,92.5 143.64,92.5 144.14,93.01 144.14,95.1
VCC_1V80 on L03-SIG1: 138.81,99.74 146.43,99.74 146.94,99.23 146.94,95.93 146.3,95.3 140.59,95.3 139.7,94.41 139.7,89.71 141.6,87.8 141.6,82.72 140.97,82.09 137.03,82.09 135.89,83.23 135.89,96.82
VCC_1V80 on L05-SIG2: 20.32,18.08 22.8,15.6 47.94,15.6 51.69,11.86 102.81,11.86 106.74,15.79 106.74,17.38 106.68,17.45 106.68,42.97 112.14,48.43 129.92,48.43 135.66,54.17 135.66,80.9 137.03,82.27 137.03,87.68 137.49,88.13 141.38,88.13 141.54,87.97 141.54,82.2 143.18,80.56 143.18,43.91 134.37,35.1 121.16,35.1 121.03,35.23 116.59,35.23 114.68,33.32 114.68,13.51 109.73,8.56 21.08,8.56 17.02,12.62 17.02,21.64 16.51,22.14 15.24,22.14 14.61,22.78 14.61,24.81 14.99,25.19 19.18,25.19 20.32,24.05
VCC_1V80 on L08-POW2: 141.3,84.71 141.96,85.37 141.96,91.21 146.81,96.06 146.81,99.11 146.05,99.87 141.48,99.87 133.63,92.02 129.03,92.02 126.57,94.48 126.57,125.57 126.14,126.01 126.14,126.26 122.43,129.97 68.71,129.97 67.82,129.08 67.82,117.78 68.35,117.25 75.04,117.25 75.86,116.43 75.86,109.22 76.51,108.57 86.17,108.57 90.68,113.08 90.68,115.88 92.17,117.37 113.66,117.37 113.69,117.39 117.35,117.39 117.98,116.76 117.98,92.12 125.4,84.71
VCC_1V80_FT on L10-SIG3: 18.09,128.86 30.48,128.86 30.89,129.27 30.89,138.48 30.31,139.06 21.34,139.06 17.23,134.96 17.23,129.71
VCC_2V50 on TOP (solid shape): 132.97,131.63 132.97,128.18 132.78,127.99 127.47,127.99 127.38,128.07 127.38,131.61 127.58,131.8 132.79,131.8
VCC_2V50 on TOP: 95.5,124.25 93.22,124.25 93.09,124.13 93.09,122.09 93.22,121.97 95.38,121.97 95.63,122.22 95.63,124.13
VCC_2V50 on BOTTOM: 127.47,127.99 130.55,127.99 130.92,128.35 132.76,128.35 132.97,128.56 132.97,131.63 132.79,131.8 127.58,131.8 127.38,131.61 127.38,128.07
VCC_2V50 on BOTTOM: 95.5,126.54 92.71,126.54 92.33,126.16 92.33,121.71 92.58,121.46 95.38,121.46 95.63,121.71 95.63,123.49 95.5,123.62 94.62,123.62 94.49,123.74 94.49,125.52 94.74,125.78 95.63,125.78 95.63,126.41
VCC_2V50 on L03-SIG1: 76.81,110.18 79.6,110.18 80.35,110.93 80.35,142.28 79.7,142.93 76.47,142.93 75.94,142.41 75.94,111.05
VCC_2V50 on L05-SIG2: 91.19,121.33 91.57,120.95 98.17,120.95 98.55,121.33 98.55,124.38 99.5,125.33 126.05,125.33 128.27,127.55 132.33,127.55 132.72,127.94 132.72,133.78 132.21,134.29 91.82,134.29 91.19,133.65
VCC_2V50 on L07_POW1: 127.09,127.99 132.48,127.99 133.76,129.27 133.76,146.79 132.02,148.52 37.87,148.52 0.54,111.18 0.54,20.42 1.39,19.57 5.22,19.57 5.22,19.57 6.34,19.57 6.87,20.09 6.87,22.86 6.27,23.45 6.27,105.47 40.45,139.65 115.44,139.65
VCC_3V30 on TOP (solid shape): 133.64,89.82 133.64,86.37 133.45,86.18 128.88,86.18 128.65,86.41 128.65,89.71 128.91,89.96 128.91,89.99 133.46,89.99
VCC_3V30 on TOP: 65,107.68 64.97,107.71 64.97,110.03 65.21,110.27 70.1,110.27 70.52,109.86 70.52,108.06 70.14,107.68
VCC_3V30 on TOP: 13.24,128.01 14.95,128.01 15.06,128.12 15.06,129.91 14.71,130.26 13.24,130.26 12.98,130 12.98,128.27
VCC_3V30 on TOP: 102.81,106.3 104.36,106.3 104.64,106.03 105.08,106.03 105.18,105.93 105.18,105.41 105.06,105.3 103.83,105.3 103.82,105.31 102.83,105.31 102.81,105.33
VCC_3V30 on TOP: 14.39,134.73 15.16,134.73 15.41,134.98 15.41,135.73 15.16,135.98 14.39,135.98 14.14,135.73 14.14,134.98
VCC_3V30 on TOP: 45.37,102.19 45.35,102.16 43.81,102.16 43.56,102.41 43.56,108.72 43.74,108.9 45.17,108.9 45.37,108.7
VCC_3V30 on TOP: 102.72,89.15 104.09,89.15 104.29,89.35 104.29,91.64 104.04,91.89 102.69,91.89 102.69,89.17
VCC_3V30 on TOP: 62.93,117.28 69.85,117.28 70.14,117.57 70.14,121.24 69.81,121.57 62.93,121.57 62.67,121.31 62.67,117.53
VCC_3V30 on BOTTOM: 60.58,127.17 61.98,125.78 61.98,114.35 64.64,111.68 64.64,108.12 65.15,107.62 69.72,107.62 70.36,108.25 70.36,121.33 68.71,122.98 68.71,135.05 64.64,139.11 64.64,141.27 64.01,141.91 60.71,141.91 60.58,141.78
VCC_3V30 on BOTTOM: 13.24,128.01 15.06,128.01 15.31,128.27 15.31,130 15.06,130.26 13.24,130.26 12.98,130 12.98,128.27
VCC_3V30 on BOTTOM: 49.78,86.03 53.09,86.03 53.21,86.15 53.21,87.42 47.12,93.52 47.12,100.63 45.97,101.77 45.97,108.5 45.85,108.63 42.29,108.63 41.91,108.25 41.91,93.9
VCC_3V30 on BOTTOM: 128.14,86.18 131.28,86.18 131.65,86.54 133.43,86.54 133.64,86.75 133.64,89.82 133.46,89.99 128.25,89.99 128.05,89.8 128.05,86.26
VCC_3V30 on L03-SIG1: 9.02,24.2 9.02,16.94 9.65,16.3 43.18,16.3 45.85,13.64 53.85,13.64 55.44,15.22 55.44,23.22 54.46,24.2
VCC_3V30 on L07_POW1: 60.35,64.41 62.04,62.72 82.99,62.72 83.12,62.59 103.57,62.59 106.87,59.29 122.36,59.29 124.83,61.76 124.83,89.37 126.8,91.33 145.47,91.33 149.05,94.92 149.05,102.49 150.19,103.63 156.51,103.63 157.63,104.74 157.63,141.25 155.7,143.18 152.91,143.18 152.53,143.56 152.53,146.73 152.78,146.99 157.1,146.99 164.11,139.98 164.11,14.14 155.98,6.01 43.69,6.01 43.44,5.76 12.95,5.76 12.57,6.14 12.57,12.49 13.33,13.25 29.84,13.25 32.09,15.5 32.09,83.08 35.95,86.94 59.63,86.94 60.35,86.22
VCC_3V30 on L08-POW2: 41.43,143.58 5.51,143.58 4.17,142.24 4.17,62.55 4.65,62.06 37.45,62.06 40.79,58.72 56.13,58.72 58.63,61.22 58.63,90.13 55.12,93.65 55.12,110.41 56.46,111.76 59.96,111.76 66.37,118.16 66.37,131.5 64.06,133.8 51.21,133.8
VCC_3V30 on L10-SIG3: 74.7,119.09 74.7,106.35 73.77,105.42 68.97,105.42 67.74,106.65 65.48,106.65 65.02,107.11 65.02,108.63 63.12,110.54 63.12,121.2 63.37,121.46 66.17,121.46 66.55,121.08 66.55,121.08 68,119.62 74.18,119.62
VCC_3V30 on L12-SIG4: 127,86.91 128.14,85.77 133.1,85.77 133.38,86.05 133.38,89.94 131.23,92.09 131.19,92.09 130.43,92.84 128.48,92.84 128.12,93.21 123.25,93.21 122.17,94.28 122.17,100.25 121.03,101.39 114.43,101.39 109.85,105.96 102.62,105.96 102.24,105.58 102.24,101.27 102.74,100.76 106.68,100.76 107.82,99.61 107.82,92.76 107.19,92.12 102.49,92.12 102.11,91.74 102.11,88.18 102.36,87.93 119.25,87.93 120.27,86.91
VCC_5V00 on TOP (solid shape): 130.86,124.15 131.47,124.15 131.53,124.21 134.17,124.21 134.26,124.12 134.26,121.22 134.04,121 128.81,121 128.55,121.25 128.55,124.05 128.71,124.21 130.79,124.21
VCC_5V00 on TOP (solid shape): 130.86,109.67 131.47,109.67 131.53,109.73 134.17,109.73 134.26,109.64 134.26,107.01 134.09,106.83 129.14,106.83 128.86,107.11 128.86,109.44 129.16,109.73 130.79,109.73
VCC_5V00 on TOP (solid shape): 130.86,95.42 131.47,95.42 131.53,95.48 134.17,95.48 134.26,95.39 134.26,92.5 134.04,92.27 128.81,92.27 128.55,92.53 128.55,95.32 128.71,95.48 130.79,95.48
VCC_5V00 on TOP (solid shape): 131.81,82.35 132.42,82.35 132.48,82.4 134.84,82.4 134.93,82.31 134.93,79.41 134.71,79.19 129.48,79.19 129.22,79.44 129.22,82.24 129.38,82.4 131.75,82.4
VCC_5V00 on TOP (solid shape): 145.18,80.54 145.79,80.54 145.85,80.6 148.49,80.6 148.58,80.51 148.58,78.91 148.46,78.79 142.23,78.79 141.48,79.54 141.48,80.31 141.77,80.6 145.11,80.6
VCC_5V00 on TOP (solid shape): 145.07,91.89 145.68,91.89 145.75,91.95 146.56,91.95 146.7,91.81 148.48,91.81 148.48,88.96 148.26,88.74 143.03,88.74 142.77,88.99 142.77,91.79 142.93,91.95 145.01,91.95
VCC_5V00 on TOP (solid shape): 145.51,134.31 146.12,134.31 146.19,134.37 147,134.37 147.14,134.23 148.92,134.23 148.92,131.38 148.7,131.16 143.46,131.16 143.21,131.41 143.21,134.21 143.37,134.37 145.45,134.37
VCC_5V00 on TOP (solid shape): 145.51,119.83 146.12,119.83 146.19,119.89 147,119.89 147.14,119.75 148.92,119.75 148.92,116.9 148.7,116.68 143.46,116.68 143.21,116.94 143.21,119.73 143.37,119.89 145.45,119.89
VCC_5V00 on TOP (solid shape): 145.51,105.1 146.12,105.1 146.19,105.16 147,105.16 147.14,105.02 148.92,105.02 148.92,102.17 148.7,101.95 143.46,101.95 143.21,102.2 143.21,105 143.37,105.16 145.45,105.16
VCC_5V00 on TOP: 117.73,46.91 117.86,46.78 117.86,35.86 117.47,35.48 113.79,35.48 113.54,35.73 113.54,46.66 113.79,46.91
VCC_5V00 on TOP: 139.19,67.74 139.32,67.61 143,67.61 143.89,68.5 147.7,68.5 147.83,68.37 147.83,63.04 147.57,62.78 144.02,62.78 143.64,63.17 143.64,64.18 143.13,64.69 143.13,66.34 142.62,66.85 136.53,66.85 136.27,67.1 134.87,67.1 134.87,67.74
VCC_5V00 on BOTTOM: 141.77,80.6 141.48,80.31 141.48,79.04 141.73,78.79 148.46,78.79 148.58,78.91 148.58,80.51 148.49,80.6
VCC_5V00 on BOTTOM: 128.71,95.48 128.55,95.32 128.55,92.53 128.81,92.27 134.04,92.27 134.26,92.5 134.26,95.39 134.17,95.48
VCC_5V00 on BOTTOM: 143.37,134.37 143.21,134.21 143.21,131.41 143.46,131.16 148.7,131.16 148.92,131.38 148.92,134.28 148.83,134.37
VCC_5V00 on BOTTOM: 129.38,82.4 129.22,82.24 129.22,79.44 129.48,79.19 134.71,79.19 134.93,79.41 134.93,82.31 134.84,82.4
VCC_5V00 on BOTTOM: 128.71,124.21 128.55,124.05 128.55,121.25 128.81,121 134.04,121 134.26,121.22 134.26,124.12 134.17,124.21
VCC_5V00 on BOTTOM: 143.37,119.89 143.21,119.73 143.21,116.94 143.46,116.68 148.7,116.68 148.92,116.9 148.92,119.8 148.83,119.89
VCC_5V00 on BOTTOM: 143.13,69.01 143.13,66.09 142.62,65.58 142.62,61.9 143,61.51 145.54,61.51 145.67,61.64 145.67,69.01 145.54,69.13 143.26,69.13
VCC_5V00 on BOTTOM: 128.71,109.73 128.55,109.57 128.55,106.78 128.81,106.52 134.04,106.52 134.26,106.74 134.26,109.64 134.17,109.73
VCC_5V00 on BOTTOM: 143.37,105.16 143.21,105 143.21,102.2 143.46,101.95 148.7,101.95 148.92,102.17 148.92,105.07 148.83,105.16
VCC_5V00 on BOTTOM: 142.93,91.95 142.77,91.79 142.77,88.99 143.03,88.74 148.26,88.74 148.48,88.96 148.48,91.86 148.39,91.95
VCC_5V00 on L03-SIG1: 135.51,80.83 134.15,79.47 128.05,79.47 126.86,80.66 126.86,123.73 127.25,124.13 138.05,124.13 139.06,125.14 139.06,138.6 141.22,140.76 160.93,140.76 162.2,139.49 162.2,96.52 161.13,95.44 153.92,95.44 149.11,100.25 138.18,100.25 135.51,97.58
VCC_5V00 on L05-SIG2: 152.78,134.24 153.34,133.68 162.64,133.68 163.16,133.15 163.16,102.5 159.89,99.23 154.69,99.23 154.05,98.6 154.05,94.78 153.54,94.27 152.91,94.27 151.08,92.44 151.08,90.8 150.15,89.87 140.04,89.87 138.94,90.98 138.94,96.31 139.7,97.07 139.7,101.9 137.53,104.07 127.96,104.07 127.71,104.32 127.71,126.11 128.78,127.17 133.1,127.17 140.16,134.24
VCC_5V00 on L08-POW2: 53.41,135.1 51.88,135.1 47.24,139.73 47.24,146.1 47.83,146.68 155.22,146.68 163.83,138.07 163.83,68.12 163.45,67.74 162.94,67.74 162.69,67.48 162.69,61.64 162.08,61.03 147.47,61.03 147.26,60.82 128.33,60.82 127.13,62.02 127.13,82.72 128.14,83.74 141.53,83.74 142.7,84.91 142.7,90.93 147.45,95.68 147.45,100 146.69,100.76 141.45,100.76 133.22,92.53 128.68,92.53 127.08,94.13 127.08,126.4 118.39,135.08 53.44,135.08
VCC_5V00 on L12-SIG4: 147.05,82.28 148.67,80.67 148.67,79.45 148.03,78.81 147.42,78.81 146.91,78.3 146.91,73.02 148.46,71.47 148.46,50.47 146.43,48.43 143.38,48.43 140.97,46.02 140.97,40.31 133.22,32.56 120.52,32.56 118.49,30.53 118.49,9.95 114.55,6.02 8.51,6.02 6.1,8.43 6.1,24.68 6.6,25.19 16.26,25.19 16.89,24.56 16.89,18.08 13.33,14.52 13.33,12.37 17.4,8.3 103.63,8.3 107.82,12.49 107.82,30.65 110.24,33.07 110.24,38.02 112.52,40.31 112.52,51.74 123.44,62.66 123.44,66.98 127.13,70.66 127.13,81.83 127.58,82.28
VCC_12V00 on TOP (solid shape): 38.73,22.53 38.73,17.95 38.48,17.7 34.04,17.7 33.91,17.83 33.91,18.31 33.94,18.33 33.94,22.58 34.17,22.81 38.46,22.81
VCC_12V00 on TOP (solid shape): 38.95,46.51 38.95,43.57 38.79,43.41 38.79,42.79 38.94,42.64 39.02,42.64 39.96,41.7 41.91,41.7 42.16,41.45 42.09,41.37 42.09,40.76 42.16,40.69 42.16,40.05 42.09,39.98 42.09,39.37 42.16,39.29 42.16,39 42.14,38.97 42.14,38.12 41.91,37.89 40.77,37.89 39.37,39.29 34.16,39.29 33.53,39.92 33.53,46.35 33.8,46.62 38.83,46.62
VCC_12V00 on TOP: 26.8,41.7 23.88,41.7 23.75,41.58 23.75,39.42 24,39.16 24.38,39.16 25.65,37.89 26.8,37.89 27.05,38.15 27.05,41.45
VCC_12V00 on BOTTOM: 38.72,46.73 33.99,46.73 33.59,46.34 33.59,39.86 35.69,37.77 41.78,37.77 42.04,38.02 42.04,40.31 42.16,40.43 42.16,41.58 41.53,42.21 38.99,42.21 38.93,42.27 38.95,42.29 38.95,46.51
VCC_12V00 on BOTTOM: 137.16,41.96 151.38,41.96 151.89,41.45 151.89,37.89 151.13,37.13 137.29,37.13 137.03,37.38 137.03,41.83
VCC_12V00 on BOTTOM: 27.18,41.7 27.18,40.69 26.92,40.43 26.92,37.89 26.8,37.77 23.75,37.77 23.5,38.02 23.5,41.58 23.75,41.83 27.05,41.83
VCC_12V00 on BOTTOM: 34.04,21.51 34.04,17.7 34.29,17.45 38.35,17.45 38.73,17.83 38.73,22.4 38.35,22.78 37.21,22.78 37.21,22.02 36.96,21.76 34.29,21.76
VCC_12V00 on L08-POW2: 37.12,61.58 3.42,61.58 1.3,59.46 1.3,14.27 1.92,13.65 12.08,13.65 12.7,14.27 12.7,27.48 13.92,28.7 18.16,28.7 25.6,21.26 30.71,21.26 33.88,18.08 38.35,18.08 40.49,20.21 102.03,20.21 103.71,21.89 163.96,21.89 164.4,22.33 164.4,59.85 163.89,60.36 147.94,60.36 147.89,60.31 126.17,60.31 123.19,57.32 109.6,57.32 104.27,51.99 78.99,51.99 73.26,57.73 40.97,57.73
VCC_AUX on TOP (solid shape): 102.38,116.92 102.38,114.1 102.36,114.09 102.11,113.73 102.36,113.37 102.38,113.36 102.38,112.57 99.06,112.57 98.68,112.95 98.68,116.38 99.29,116.99 102.32,116.99
VCC_AUX on BOTTOM: 98.04,116.89 101.22,116.89 101.35,116.76 101.35,115.36 100.58,114.6 100.58,113.46 100.33,113.2 98.04,113.2 97.92,113.33 97.92,116.76
